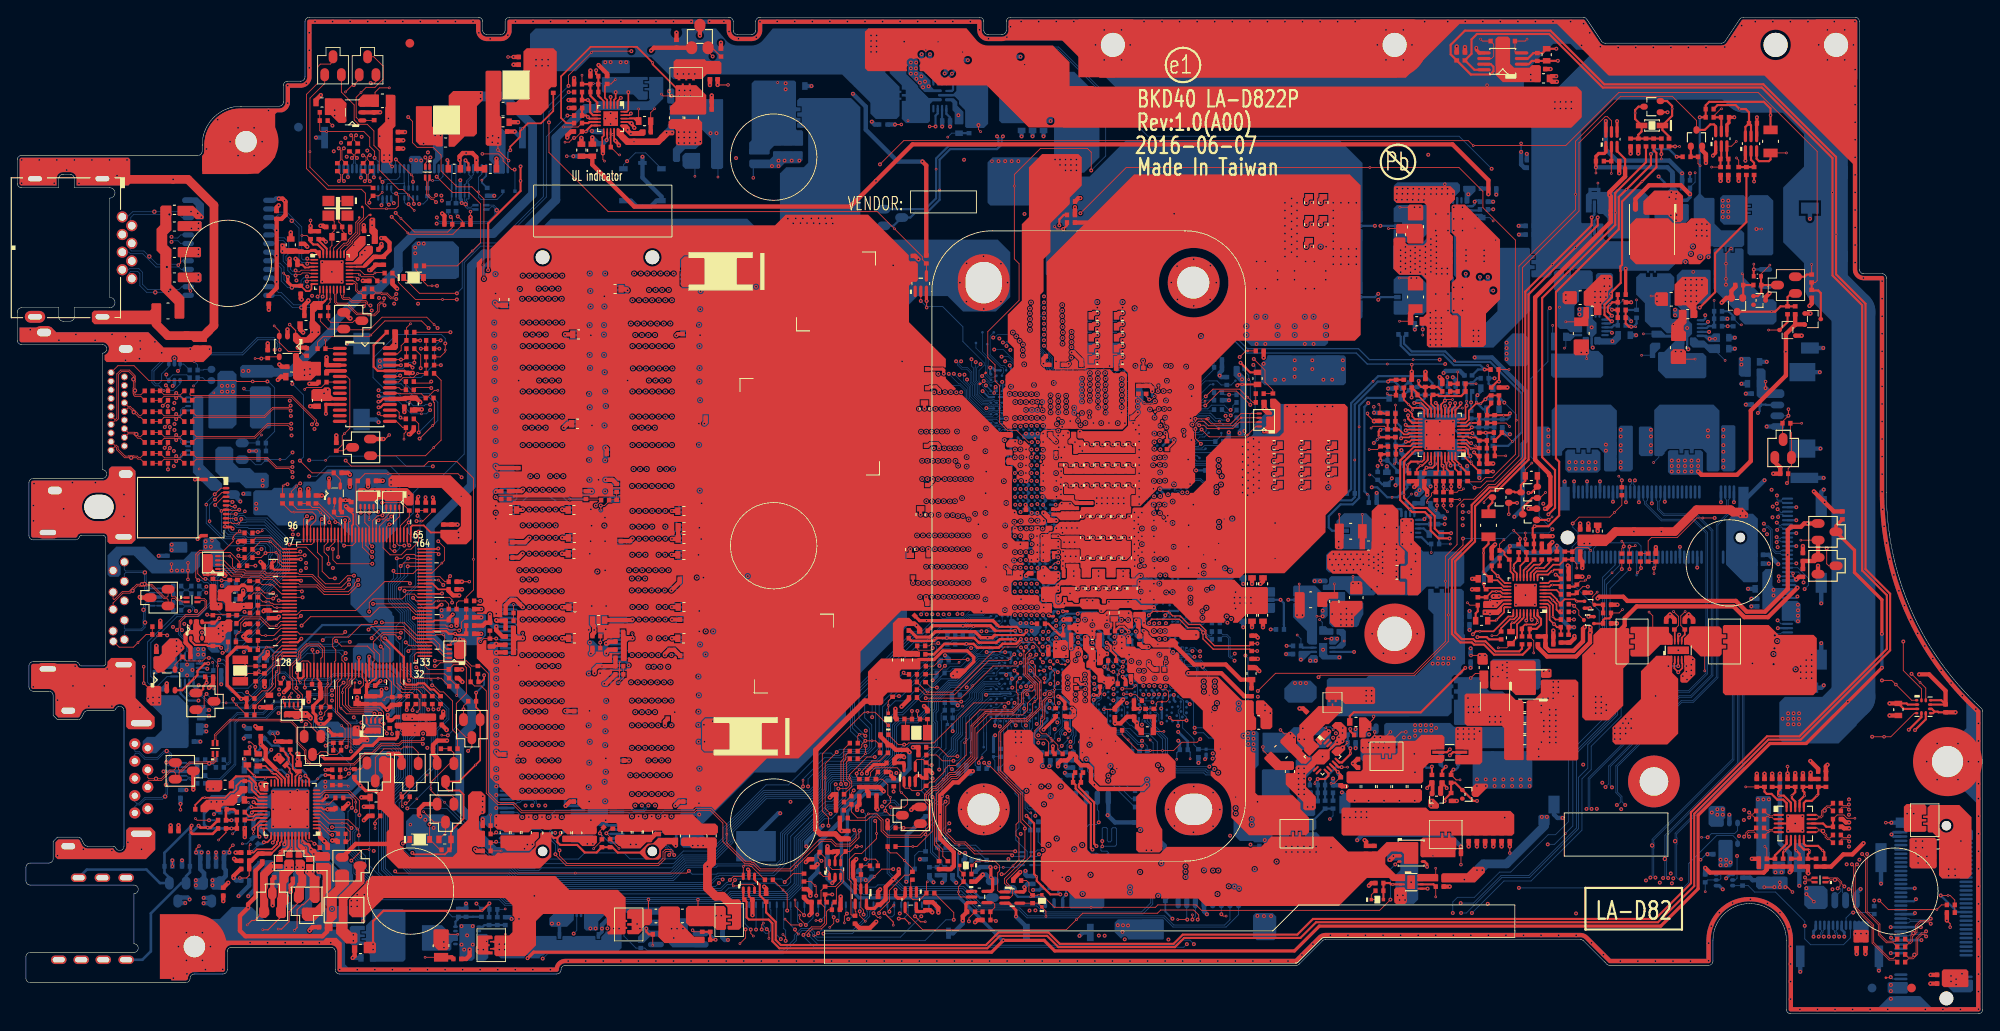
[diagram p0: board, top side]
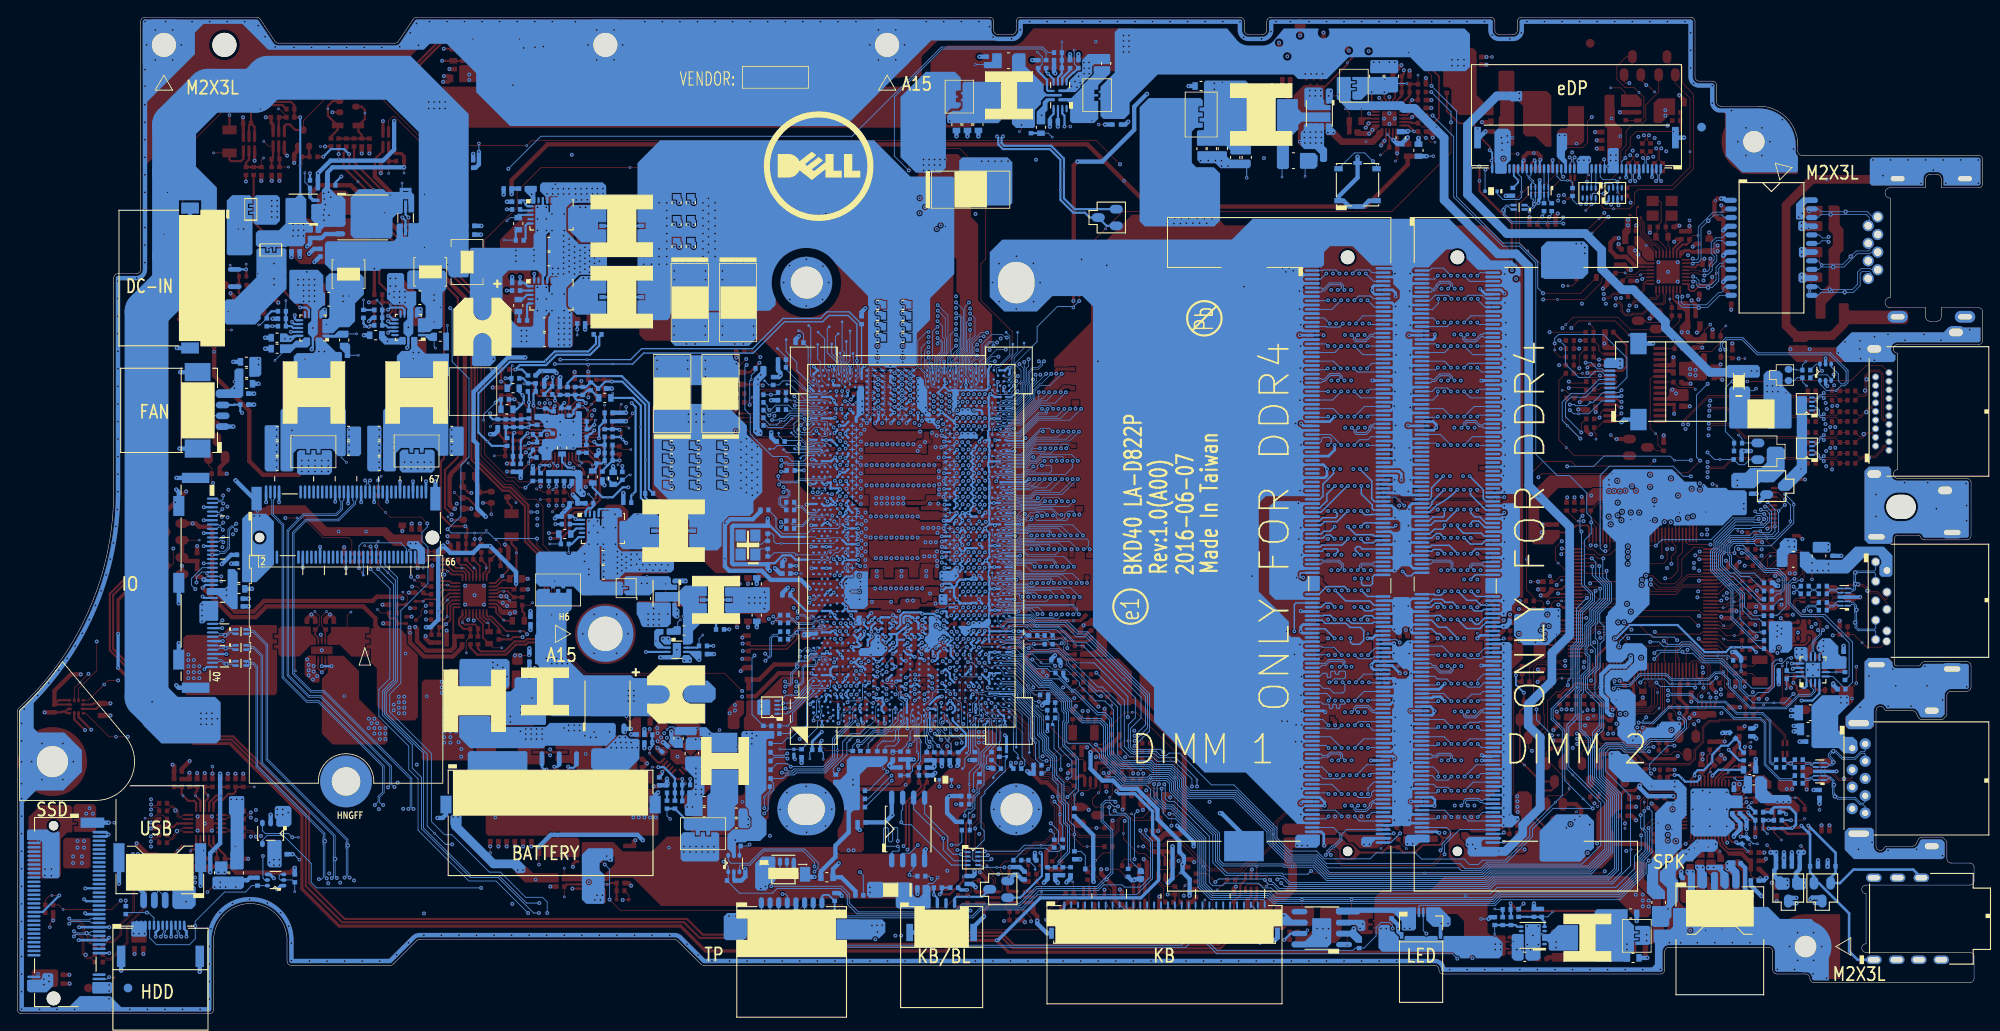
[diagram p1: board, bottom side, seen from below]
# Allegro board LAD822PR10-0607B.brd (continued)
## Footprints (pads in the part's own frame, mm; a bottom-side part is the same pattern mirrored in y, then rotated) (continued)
SY8286BRAC_QFN20_3X3-S
  oval 0.889x0.254 smd: 1(0,0) 2(0,-0.45) 3(0,-0.9) 4(0,-1.35) 5(0,-1.8) 11(3.1,-1.8) 12(3.1,-1.35) 13(3.1,-0.9) 14(3.1,-0.45) 15(3.1,0)
  oval 0.254x0.889 smd: 6(0.65,-2.45) 7(1.1,-2.45) 8(1.55,-2.45) 9(2,-2.45) 10(2.45,-2.45) 16(2.45,0.65) 17(2,0.65) 18(1.55,0.65) 19(1.1,0.65) 20(0.65,0.65)
  rect 0.991x0.991 smd: 21(1.55,-0.9)
SY8286CRAC_QFN20_3X3-S
  oval 0.889x0.254 smd: 1(0,0) 2(0,-0.45) 3(0,-0.9) 4(0,-1.35) 5(0,-1.8) 11(3.1,-1.8) 12(3.1,-1.35) 13(3.1,-0.9) 14(3.1,-0.45) 15(3.1,0)
  oval 0.254x0.889 smd: 6(0.65,-2.45) 7(1.1,-2.45) 8(1.55,-2.45) 9(2,-2.45) 10(2.45,-2.45) 16(2.45,0.65) 17(2,0.65) 18(1.55,0.65) 19(1.1,0.65) 20(0.65,0.65)
  rect 0.991x0.991 smd: 21(1.55,-0.9)
SY8286RAC_QFN20_3X3-S
  oval 0.889x0.254 smd: 1(0,0) 2(0,-0.45) 3(0,-0.9) 4(0,-1.35) 5(0,-1.8) 11(3.1,-1.8) 12(3.1,-1.35) 13(3.1,-0.9) 14(3.1,-0.45) 15(3.1,0)
  oval 0.254x0.889 smd: 6(0.65,-2.45) 7(1.1,-2.45) 8(1.55,-2.45) 9(2,-2.45) 10(2.45,-2.45) 16(2.45,0.65) 17(2,0.65) 18(1.55,0.65) 19(1.1,0.65) 20(0.65,0.65)
  rect 0.991x0.991 smd: 21(1.55,-0.9)
TAITW_PUBAUN-09FLBS1NN4H0_9P-T
  round 1.295 hole 0.711: 1(0,0) 2(-2.5,0) 3(-4.5,0) 4(-7,0) 5(-7.5,-1.5) 6(-5.5,-1.5) 7(-3.5,-1.5) 8(-1.5,-1.5) 9(0.5,-1.5)
  oval 1.295x2.997 hole 0.711x2.388: 10(2.9,-0.75) 11(-9.9,-0.75)
  oval 1.295x2.21 hole 0.711x1.6: 12(-11.35,-9.2) 13(4.35,-9.2)
TAIWI_USB034-107CRL-TWD_10P-T
  round 1.041 hole 0.787: 1(0,0) 2(-2.5,0) 3(-4.5,0) 4(-7,0) 5(-8,1.3) 6(-5.75,1.3) 7(-3.5,1.3) 8(-1.25,1.3) 9(1,1.3)
  round 0.965 hole 0.762: 10(-8.2,0.03)
  oval 1.372x2.667 hole 0.61x1.905: 11(-10.9,1.21) 12(-11.4,-7.55) 13(3.9,1.21) 14(4.4,-7.55)
TPC12
  round 0.305 smd: 1(0,0)
TPS2543RTER_QFN16_3X3-S
  oval 0.254x1.016 smd: 1(0,0) 2(0.5,0) 3(1,0) 4(1.5,0) 9(1.5,2.975) 10(1,2.975) 11(0.5,2.975) 12(0,2.975)
  oval 1.016x0.254 smd: 5(2.238,0.738) 6(2.238,1.238) 7(2.238,1.738) 8(2.238,2.238) 13(-0.738,2.238) 14(-0.738,1.738) 15(-0.738,1.238) 16(-0.738,0.738)
  rect 1.702x1.702 smd: 17(0.75,1.488)
TPS22961DNYR_WSON8
  oval 0.305x0.508 smd: 1(0,0) 2(0.65,0) 3(1.3,0) 4(1.95,0) 5(1.95,2.7)
  oval 1.6x0.508 smd: 6(0.65,2.7)
  rect 2.388x1.6 smd: 7(0.975,1.35)
TPS22965DSGR_SON8_2X2-S
  oval 0.254x0.787 smd: 1(0,0) 2(0.5,0) 3(1,0) 4(1.5,0) 5(1.5,2.2) 6(1,2.2) 7(0.5,2.2) 8(0,2.2)
  rect 1.6x0.889 smd: 9(0.75,1.1)
TPS22966DPUR_SON14_2X3-S
  oval 0.254x0.813 smd: 1(0,0) 2(0.4,0) 6(2,0) 7(2.4,0) 8(2.4,2.05) 9(2,2.05) 13(0.4,2.05) 14(0,2.05)
  oval 0.203x0.762 smd: 3(0.8,0) 4(1.2,0) 5(1.6,0) 10(1.6,2.05) 11(1.2,2.05) 12(0.8,2.05)
  rect 2.489x0.889 smd: 15(1.2,1.025)
TVNST52302AB0_SOT523-3
  oval 0.508x0.559 smd: 1(0,0) 2(-0.5,-1.4) 3(0.5,-1.4)
W25R128FVSIQ_SO8
  oval 0.635x1.676 smd: 1(0,0) 2(1.27,0) 3(2.54,0) 4(3.81,0) 5(3.81,7.25) 6(2.54,7.25) 7(1.27,7.25) 8(0,7.25)
Y_X1A000141000200_2P
  rect 0.991x1.803 smd: 1(0,0) 2(2.5,0)
Y_X3G024000DC1H_4P
  rect 1.397x1.194 smd: 1(0,0) 2(2.2,0) 3(2.2,1.7) 4(0,1.7)
Y_X3G025000DC1H_4P
  rect 1.397x1.194 smd: 1(0,0) 2(2.2,0) 3(2.2,1.7) 4(0,1.7)
YB8251ST23_TSOT-23-3
  oval 0.787x0.991 smd: 1(0,0) 2(-0.95,-2.6) 3(0.95,-2.6)

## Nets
0.6V_DDR_VTT_ON: PR202.1 RC123.2 UC14.4
1.2V_VTT_PWRGD: CC1822.1 PR209.2 PU200.10 RC392.1
2.5V_VIN: PC802.1 PJP801.2 PU800.3
3V_FB: PC113.1 PR109.2 PR110.1 PU100.13
3V_SN: PC112.1 PR106.2
3V_VIN: PC100.1 PC103.1 PC104.1 PC105.1 PJP105.2 PL102.2 PU100.2 PU100.3 PU100.4 PU100.5
5V_FB: PC127.1 PR115.2 PR118.1 PU102.13
5V_HDD: C6215.1 C6216.1 C6217.1 HDD1.1 HDD1.2 HDD1.3 R5601.1 RS1.1
5V_SN: PC125.1 PR112.2
5V_VIN: PC115.1 PC116.1 PC117.1 PC118.1 PJP106.2 PL103.2 PU102.2 PU102.3 PU102.4 PU102.5
+0.6V_DDR_VTT: CD12.1 CD13.1 CD14.1 CD15.1 CD32.1 CD88.1 CD89.1 CD90.1 JDIMM1.258 JDIMM2.258 PJP203.1
+0.6VSP: PC205.1 PC211.1 PJP203.2 PU200.2 PU200.20
+1.0V_APLL: CC225.1 CC1801.1 RC172.1 UC1.V15
+1.0V_CLK2: CC220.1 RC170.1 UC1.K19
+1.0V_CLK4: CC226.1 RC173.1 UC1.N20
+1.0V_CLK5: CC221.1 RC52.2 RC171.1 UC1.L19
+1.0V_MPHYPLL: CC58.1 CC210.1 CC211.1 CC217.1 CC218.1 JP17.2 UC1.AF20 UC1.AF21 UC1.K15 UC1.L15 UC1.N15 UC1.N16 UC1.N17 UC1.N18 UC1.P15 UC1.P16 UC1.T19 UC1.T20
+1.0V_PRIM: CC59.1 CC203.1 CC205.1 CC206.1 CC216.1 CC273.1 CE77.1 CZ87.1 JP17.1 PJP302.2 RC170.2 RC171.2 RC172.2 RC173.2 RC352.1 UC1.A10 UC1.A14 UC1.AB17 UC1.AB19 UC1.AB20 UC1.AF18 UC1.AF19 UC1.AK20 UC1.K17 UC1.L1 UC1.L21 UC1.P18 UC1.T1 UC1.V20 UC1.V21 UC1.Y18 UE1.95 UZ19.1 UZ19.2 UZ19.7 UZ21.1 UZ21.2
+1.0V_VCCST: CC195.1 CC202.1 PC602.1 PR601.1 PR604.1 PR605.1 RC79.1 RC80.1 RC120.2 RC152.1 RC157.1 RC1118.1 RZ1704.1 UC1.A18 UC1.K20 UC1.K21
+1.0V_VCCST_C: RZ1704.2 UZ21.7 UZ21.8
+1.0V_VCCSTG: CC199.1 RC83.1 RPC1.1 RPC1.2 RPC1.3 RZ1703.2 UC1.A22 UC1.G20
+1.0V_VCCSTG_C: JP15.1 RZ1703.1 UZ19.6
+1.0V_XDP: RC115.2 RC352.2 RC353.1
+1.0VS_VCCIO: CC181.1 CC182.1 CC185.1 CC186.1 CC248.1 CC249.1 CC250.1 CC251.1 CC252.1 CC253.1 JP15.2 RC2.1 UC1.AK28 UC1.AK30 UC1.AL30 UC1.AL42 UC1.AM28 UC1.AM30 UC1.AM42
+1.0VS_VCCOPC: CC1824.1 CC1825.1 CC1826.1 CC1827.1 CC1828.1 CC1829.1 CC1830.1 CC1831.1 CC1832.1 PJP1202.2 UC1.AB62 UC1.AE62 UC1.AG62 UC1.P62 UC1.V62
+1.0VS_VCCOPCP: PC1206.1 PC1207.1 PC1208.1 PJP1202.1 PL1201.2 PU1200.12
+1.2V_DDR: CC57.1 CC174.1 CC175.1 CC176.1 CC177.1 CC178.1 CC179.1 CC194.1 CC255.1 CC256.1 CC257.1 CC258.1 CC293.1 CC294.1 CC295.1 CC296.1 CC297.1 CD1.1 CD2.1 CD5.1 CD6.1 CD7.1 CD8.1 CD11.1 CD19.1 CD20.1 CD21.1 CD22.1 CD23.1 CD24.1 CD25.1 CD26.1 CD33.1 CD70.1 CD71.1 CD72.1 CD73.1 CD74.1 CD75.1 CD76.1 CD77.1 CD78.1 CD79.1 CD80.1 CD81.1 CD82.1 CD83.1 CD84.1 CD85.1 CD86.1 CD87.1 JDIMM1.12 JDIMM1.33 JDIMM1.54 JDIMM1.75 JDIMM1.96 JDIMM1.111 JDIMM1.112 JDIMM1.117 JDIMM1.118 JDIMM1.123 JDIMM1.124 JDIMM1.129 JDIMM1.130 JDIMM1.135 JDIMM1.136 JDIMM1.141 JDIMM1.142 JDIMM1.147 JDIMM1.148 JDIMM1.153 JDIMM1.154 JDIMM1.159 JDIMM1.160 JDIMM1.163 JDIMM1.178 JDIMM1.199 JDIMM1.220 JDIMM1.241 JDIMM2.12 JDIMM2.33 JDIMM2.54 JDIMM2.75 JDIMM2.111 JDIMM2.112 JDIMM2.117 JDIMM2.118 JDIMM2.123 JDIMM2.124 JDIMM2.129 JDIMM2.130 JDIMM2.135 JDIMM2.136 JDIMM2.141 JDIMM2.142 JDIMM2.147 JDIMM2.148 JDIMM2.153 JDIMM2.154 JDIMM2.159 JDIMM2.160 JDIMM2.163 JDIMM2.178 JDIMM2.199 JDIMM2.220 JDIMM2.241 PJP200.2 RD35.1 RH206.1 RH207.1 UC1.AL23 UC1.AM40 UC1.AU23 UC1.AU28 UC1.AU35 UC1.AU42 UC1.BB23 UC1.BB32 UC1.BB41 UC1.BB47 UC1.BB51 UC14.5
+1.2VP: PC213.1 PC214.2 PC215.1 PC216.1 PC217.1 PC218.1 PC219.1 PC220.1 PJP200.1 PL200.1 PR207.2 PU200.5 PU200.19
+1.8V_AVDD: C2715.1 CA61.1 R6511.1 UA1.40
+1.8V_PRIM: CC212.1 CC272.1 PJP502.2 Q6205.1 RC361.1 RC1134.1 UC1.AA1 UC1.AF16 UC1.H63
+1.8VALWP: PC503.1 PC505.1 PC506.1 PC507.1 PJP502.1 PL501.2 PR503.2
+1VALWP: PC309.1 PC310.1 PC311.1 PC312.1 PC313.1 PJP302.1 PL301.2 PR308.2
+2.5V_MEM: CD3.1 CD4.1 CD9.1 CD10.1 CD27.1 CD28.1 CD30.1 CD31.1 JDIMM1.257 JDIMM1.259 JDIMM2.257 JDIMM2.259 PJP802.2
+2.5VP: PC803.1 PC804.1 PJP802.1 PR801.1 PU800.6
+3.3V_ALW_DSW: CC279.1 CC280.1 RC70.1 RC72.2 RC214.1 RC243.2 RC1102.1 UC1.AD17 UC1.AD18 UC1.AJ17
+3.3V_CAM: C5207.1 EC5210.1 JEDP.29 JEDP.33 R5229.2
+3.3V_LAN: C3015.1 C3017.1 CL1.1 CL3.1 CL5.1 CL8.1 CL11.1 RL7.1 UL1.11 UL1.23 UL1.32 UL3.1
+3.3V_RUN_UZ2: CZ50.1 JP13.1 UZ2.8 UZ2.9
+3.3V_WLAN: C5803.1 C5804.1 C5806.1 C6221.1 R5809.1 R5810.2 WLAN1.2 WLAN1.4 WLAN1.64 WLAN1.66
+3V_SPI: CC9.1 CZ92.1 CZ93.1 CZ94.1 QZ11.3 RC9.1 RC30.1 RC53.1 RC1124.2 RZ1707.1 UC1.AJ16 UC2.8 UZ13.19 UZ13.24
+3VALW: C3013.1 C6204.1 CC271.1 CC1820.1 CC1821.1 CE1.1 CZ95.1 CZ96.1 JIO1.24 PC1205.1 PJP102.2 PJP501.1 PJP801.1 PR3.2 PR16.2 PR28.1 PR209.1 PR303.1 PR304.2 PR756.2 PR791.1 PU1200.10 Q6203.3 QC6.2 QC6.5 R2608.1 R3022.1 R5810.1 RC68.2 RC73.2 RC214.2 RC1124.1 RE25.1 RE71.1 RE72.1 RE73.1 RE74.1 RE75.1 RE343.2 RE385.2 RE388.2 RE389.2 RE396.1 RE404.1 RE408.2 RE409.2 RE446.2 RPE2.5 RPE2.6 RPE2.7 RPE2.8 RPE3.5 RPE3.6 RPE3.7 RPE3.8 RPE4.1 RPE4.2 RPE4.3 RPE4.4 RPE5.1 RPE5.2 RPE5.3 RPE5.4 RPE6.1 RPE6.2 RPE6.3 RPE6.4 RPE7.1 RPE7.2 RPE7.3 RPE7.4 RZ117.2 RZ1705.1 UC12.5 UC13.5 UC15.5 UE7.2 UL3.5 UZ2.6 UZ2.7 UZ6.5
+3VALW_EC: CE62.1 CE63.2 CE64.2 CE65.1 CE66.1 CE67.1 CE68.1 CE69.1 CE71.1 CE79.1 CE81.1 CE89.1 R2446.1 RE343.1 RE345.1 RE354.1 RE424.2 RE425.2 RE440.2 UE1.5 UE1.19 UE1.22 UE1.43 UE1.54 UE1.65 UE1.82 UE1.103 UE1.115
+3VALW_PCH: CC207.1 CC223.1 CC224.1 CC265.1 RC12.2 RC14.2 RC15.2 RC17.2 RC19.2 RC20.2 RC23.2 RC25.2 RC74.1 RC183.1 RC186.1 RC187.1 RC239.1 RC288.2 RC365.2 RC384.2 RC387.2 RC1127.2 RC1138.2 RPC3.5 RPC3.6 RPC3.7 RPC3.8 RZ1705.2 UC1.AD15 UC1.AG15 UC1.AJ21 UC1.AK15 UC1.AK17 UC1.T16 UC1.V19 UC1.Y15 UC1.Y16
+3VALWP: PC106.1 PC107.1 PC108.1 PC109.1 PC110.1 PJP102.1 PL100.2 PR107.1 PR108.2 PR109.1 PR113.1 PU100.14
+3VLP: D2501.2 PC111.1 PU100.16 PU100.17 R2609.1 RE356.2
+3VS: C2601.1 C2602.1 C5204.1 C5801.1 C5802.1 C5805.1 CA57.1 CA58.1 CD16.1 CD17.1 CD34.1 CD35.1 CE85.1 CN19.1 CN20.1 CS27.1 CS42.1 CZ97.1 CZ98.1 JDB1.9 JDB1.10 JDIMM1.255 JDIMM2.255 JIO1.22 JIO1.23 JP1.2 JP13.2 PR612.1 PR1206.1 Q2601.2 Q2601.5 Q6205.2 Q6206.2 Q6501.2 Q6501.5 Q6502.2 QC2.2 QC2.5 QL1.2 QX4.2 QX4.5 QX5.1 QX6.2 R2603.1 R2604.1 R5229.1 R5809.2 R6110.1 R6202.1 R6507.1 R6534.1 RA13.2 RA14.1 RC13.1 RC21.1 RC27.2 RC47.1 RC50.1 RC62.2 RC63.2 RC123.1 RC175.2 RC178.2 RC237.2 RC248.2 RC272.1 RC277.1 RC291.1 RC292.1 RC293.1 RC370.1 RC372.1 RC374.1 RC376.1 RC382.2 RC388.2 RC1104.1 RC1106.1 RC1109.2 RC1122.2 RC1123.1 RC1129.1 RC1130.1 RD1.1 RD2.1 RD3.1 RD4.1 RD5.1 RD6.1 RE32.1 RE432.1 RE439.2 RE441.2 RL2.1 RN19.1 RN20.1 RS19.1 RS20.1 RS25.1 RS26.1 RS27.1 RS28.1 RS29.1 RS30.1 RS33.2 RS34.2 RS38.2 RS39.1 RX13.1 RZ20.1 RZ21.1 THM26.1 U5201.4 U5201.5 U5603.2 U5603.3 U5603.9 U5603.10 UA1.1 UA1.9 UC7.5 UE6.5 UZ13.10
+3VS_SSD: C5529.1 C5530.1 C5531.1 C5532.1 C5533.1 JP1.1 JSSD1.2 JSSD1.4 JSSD1.62 JSSD1.64 JSSD1.66 RB1.1
+5V_KB_BL: C6202.1 F6201.1 JKBBL.1
+5V_PVDD: CA53.1 CA54.1 CA55.1 CA56.1 RA1110.1 UA1.41 UA1.46
+5V_RUN_UZ2: CZ44.1 JP21.2 UZ2.13 UZ2.14
+5VA: CA51.1 CA71.1 RA1111.1 UA1.26
+5VALW: C3504.1 C3510.1 CUS20.1 JLED.1 JLED.2 JWDB1.4 PC661.1 PC677.1 PC685.1 PC801.1 PD5.3 PD6.3 PJP103.2 PR8.1 PR206.1 PR210.2 PR602.2 PR615.1 PR634.1 PR655.1 PR658.1 PU606.6 PU800.4 U3504.5 U3505.5 UUS5.1 UUS5.4 UUS5.7 UUS5.8 UZ2.1 UZ2.2 UZ2.4 UZ19.3 UZ21.4
+5VALWP: PC120.1 PC121.1 PC122.1 PC123.1 PC124.1 PJP103.1 PL101.2 PR115.1 PR117.2 PU102.14
+5VS: C6214.1 D5204.2 F5203.1 F6201.2 JIO1.21 JP21.1 Q6201.3 R2606.2 R5232.2 R5601.2 RA1110.2 RA1111.2
+5VS_HDMI: DX4.1 F6202.1 JHDMI.18
+17.4V_BATT+: PC7.1 PC761.1 PC766.1 PC775.1 PC776.1 PC777.1 PC778.1 PJP3.2 PQ710.3 PR745.2 PR765.4 PR780.2
+17.4V_BATT++: PBATT1.8 PBATT1.9 PBATT1.10 PC8.1 PJP3.1
+19V_ADPIN: PC1.1 PC2.1 PJPDC1.5 PJPDC1.6 PL1.1
+19V_VIN: PC3.1 PC4.1 PC742.2 PD704.2 PL1.2 PQ740.5 PQ741.5 PR5.1 PR7.2 PR31.2 PR729.1
+19VB: EC9701.1 EC9702.1 EC9703.1 EC9706.1 EC9707.1 EC9708.1 EC9709.1 EC9710.1 EC9711.1 EC9712.1 EC9716.1 EC9749.1 EC9750.1 EC9751.1 EC9752.1 EC9753.1 F5201.1 PC606.1 PJP105.1 PJP106.1 PJP206.2 PJP301.1 PJP601.2 PJP602.2 PJP701.1 PJP1201.1 PL102.1 PL103.1 PL606.2 PL704.1 PQ717.5 PR102.2 PR703.4 R5214.1 R6528.2
+19VB_1.2V: PC201.1 PC206.1 PC208.1 PC212.1 PJP206.1 PQ201.2 PQ201.3 PQ201.4 PQ201.10 PR208.1
+19VB_+1VALW: PC301.1 PC302.1 PC303.1 PJP301.2 PU300.2 PU300.3 PU300.4 PU300.5
+VCC_CORE: PC1001.1 PC1002.1 PC1003.1 PC1004.1 PC1005.1 PC1006.1 PC1007.1 PC1008.1 PC1009.1 PC1010.1 PC1011.1 PC1012.1 PC1013.1 PC1030.1 PC1031.1 PC1032.1 PC1033.1 PC1034.1 PC1035.1 PC1036.1 PC1037.1 PC1038.1 PC1039.1 PC1050.1 PC1051.1 PC1052.1 PC1053.1 PC1054.1 PC1061.1 PC1062.1 PC1064.1 PC1065.1 PC1066.1 PC1067.1 PC1068.1 PC1069.1 PC1070.1 PC1071.1 PC1072.1 PC1073.1 PC1074.1 PC1075.1 PC1076.1 PC1077.1 PC1078.1 PC1079.1 PC1080.1 PC1081.1 PC1082.1 PC1083.1 PC1084.1 PC1085.1 PC1086.1 PC1087.1 PC1088.1 PC1089.1 PC1090.1 PC1091.1 PC1092.1 PC1093.1 PC1094.1 PC1095.1 PC1096.1 PC1097.1 PC1098.1 PC1099.1 PC1125.1 PC1126.1 PC1127.1 PC1164.1 PC1170.1 PC1171.1 PC1172.1 PC1173.1 PC1174.1 PL603.1 RC140.1 UC1.A30 UC1.A34 UC1.A39 UC1.A44 UC1.AK33 UC1.AK35 UC1.AK37 UC1.AK38 UC1.AK40 UC1.AL33 UC1.AL37 UC1.AL40 UC1.AM32 UC1.AM33 UC1.AM35 UC1.AM37 UC1.AM38 UC1.G30 UC1.G32 UC1.G33 UC1.G35 UC1.G37 UC1.G38 UC1.G40 UC1.G42 UC1.J30 UC1.J33 UC1.J37 UC1.J40 UC1.K33 UC1.K35 UC1.K37 UC1.K38 UC1.K40 UC1.K42 UC1.K43
+VCC_CORE_G0: T122.1(TP-1) UC1.K32
+VCC_CORE_G1: T123.1(TP-1) UC1.AK32
+VCC_FAN1: C2603.1 C6213.1 JFAN1.4 R2606.1
+VCC_GT: PC1014.1 PC1015.1 PC1016.1 PC1017.1 PC1018.1 PC1019.1 PC1020.1 PC1021.1 PC1022.1 PC1023.1 PC1024.1 PC1025.1 PC1026.1 PC1027.1 PC1028.1 PC1029.1 PC1040.1 PC1041.1 PC1042.1 PC1043.1 PC1044.1 PC1045.1 PC1046.1 PC1047.1 PC1048.1 PC1049.1 PC1055.1 PC1056.1 PC1063.1 PC1101.1 PC1128.1 PC1129.1 PC1130.1 PC1131.1 PC1132.1 PC1133.1 PC1134.1 PC1135.1 PC1136.1 PC1137.1 PC1138.1 PC1154.1 PC1155.1 PC1156.1 PC1158.1 PC1159.1 PC1161.1 PC1162.1 PC1163.1 PC1175.1 PC1176.1 PC1177.1 PC1178.1 PC1179.1 PC1180.1 PC1181.1 PC1182.1 PC1183.1 PC1184.1 PC1221.1 PC1222.1 PC1223.1 PC1224.1 PL604.1 PL605.1 RC161.1 RC340.1 UC1.A48 UC1.A53 UC1.A58 UC1.A62 UC1.A66 UC1.AA63 UC1.AA64 UC1.AA66 UC1.AA67 UC1.AA69 UC1.AA70 UC1.AA71 UC1.AC64 UC1.AC65 UC1.AC66 UC1.AC67 UC1.AC68 UC1.AC69 UC1.AC70 UC1.AC71 UC1.AK42 UC1.AK43 UC1.AK45 UC1.AK46 UC1.AK48 UC1.AK50 UC1.AK52 UC1.AK53 UC1.AK55 UC1.AK56 UC1.AK58 UC1.AK60 UC1.AK70 UC1.AL43 UC1.AL46 UC1.AL50 UC1.AL53 UC1.AL56 UC1.AL60 UC1.AM48 UC1.AM50 UC1.AM52 UC1.AM53 UC1.AM56 UC1.AM58 UC1.AU58 UC1.AU63 UC1.BB57 UC1.BB66 UC1.J43 UC1.J45 UC1.J46 UC1.J48 UC1.J50 UC1.J52 UC1.J53 UC1.J55 UC1.J56 UC1.J58 UC1.J60 UC1.K48 UC1.K50 UC1.K52 UC1.K53 UC1.K55 UC1.K56 UC1.K58 UC1.K60 UC1.L62 UC1.L63 UC1.L64 UC1.L65 UC1.L66 UC1.L67 UC1.L68 UC1.L69 UC1.L70 UC1.L71 UC1.M62 UC1.N63 UC1.N64 UC1.N66 UC1.N67 UC1.N69 UC1.N70 UC1.N71 UC1.R63 UC1.R64 UC1.R65 UC1.R66 UC1.R67 UC1.R68 UC1.R69 UC1.R70 UC1.R71 UC1.T62 UC1.U65 UC1.U68 UC1.U71 UC1.W63 UC1.W64 UC1.W65 UC1.W66 UC1.W67 UC1.W68 UC1.W69 UC1.W70 UC1.W71 UC1.Y62
+VCC_SA: PC1057.1 PC1058.1 PC1059.1 PC1060.1 PC1139.1 PC1140.1 PC1141.1 PC1142.1 PC1143.1 PC1144.1 PC1145.1 PC1146.1 PC1147.1 PC1148.1 PC1149.1 PC1150.1 PC1151.1 PC1152.1 PC1153.1 PL601.1 RC168.1 UC1.AK23 UC1.AK25 UC1.G23 UC1.G25 UC1.G27 UC1.G28 UC1.J22 UC1.J23 UC1.J27 UC1.K23 UC1.K25 UC1.K27 UC1.K28 UC1.K30
GND: C229.1 C2503.2 C2601.2 C2602.2 C2603.2 C2604.1 C2608.2 C2609.2 C3013.2 C3015.2 C3017.2 C3504.2 C3507.2 C3508.2 C3510.2 C3512.2 C3513.2 C5201.2 C5202.2 C5204.2 C5205.1 C5206.1 C5207.2 C5224.2 C5225.2 C5226.2 C5529.2 C5530.2 C5531.2 C5532.2 C5533.2 C5801.2 C5802.2 C5803.2 C5804.2 C5805.2 C5806.2 C6201.2 C6202.2 C6213.2 C6214.2 C6215.2 C6216.2 C6217.2 C6218.1 C6219.2 C6220.1 C6221.2 C6223.2 C6225.2 C6226.2 CA25.1 CA29.2 CA30.2 CA31.2 CA32.2 CA53.2 CA54.2 CA55.2 CA56.2 CA57.2 CA58.2 CA59.2 CA60.2 CA64.1 CA69.2 CC9.2 CC21.2 CC22.2 CC23.2 CC24.2 CC25.2 CC26.2 CC27.2 CC57.2 CC58.2 CC59.2 CC93.1 CC174.2 CC175.2 CC176.2 CC177.2 CC178.2 CC179.2 CC181.2 CC182.2 CC185.2 CC186.2 CC194.2 CC195.2 CC199.2 CC202.2 CC203.2 CC204.2 CC205.2 CC206.2 CC207.2 CC210.2 CC211.2 CC212.2 CC213.2 CC214.2 CC215.2 CC216.2 CC217.2 CC218.2 CC220.2 CC221.2 CC223.2 CC224.2 CC225.2 CC226.2 CC248.2 CC249.2 CC250.2 CC251.2 CC252.2 CC253.2 CC255.2 CC256.2 CC257.2 CC258.2 CC265.2 CC266.2 CC270.2 CC271.2 CC272.2 CC273.2 CC279.2 CC280.2 CC293.2 CC294.2 CC295.2 CC296.2 CC297.2 CC1801.2 CC1802.1 CC1803.1 CC1805.1 CC1806.2 CC1807.2 CC1808.2 CC1809.2 CC1810.2 CC1820.2 CC1821.2 CC1822.2 CC1823.1 CC1824.2 CC1825.2 CC1826.2 CC1827.2 CC1828.2 CC1829.2 CC1830.2 CC1831.2 CC1832.2 CD1.2 CD2.2 CD3.2 CD4.2 CD5.2 CD6.2 CD7.2 CD8.2 CD9.2 CD10.2 CD11.2 CD12.2 CD13.2 CD14.2 CD15.2 CD16.2 CD17.2 CD18.2 CD19.2 CD20.2 CD21.2 CD22.2 CD23.2 CD24.2 CD25.2 CD26.2 CD27.2 CD28.2 CD29.2 CD30.2 CD31.2 CD32.2 CD33.2 CD34.2 CD35.2 CD69.2 CD70.2 CD71.2 CD72.2 CD73.2 CD74.2 CD75.2 CD76.2 CD77.2 CD78.2 CD79.2 CD80.2 CD81.2 CD82.2 CD83.2 CD84.2 CD85.2 CD86.2 CD87.2 CD88.2 CD89.2 CD90.2 CD91.2 CD92.2 CE1.2 CE2.2 CE8.2 CE62.2 CE63.1 CE64.1 CE65.2 CE66.2 CE67.2 CE68.2 CE69.2 CE71.2 CE72.2 CE73.2 CE74.2 CE75.2 CE76.2 CE77.2 CE79.2 CE82.2 CE84.1 CE85.2 CE86.2 CE89.2 CE91.2 CL1.2 CL2.2 CL3.2 CL4.2 CL5.2 CL6.2 CL7.2 CL8.2 CL9.2 CL11.2 CL12.2 CL16.2 CL17.2 CL44.1 CL45.1 CL46.1 CLRP1.1 CN19.2 CN20.2 CS27.2 CS42.2 CUS20.2 CZ23.2 CZ44.2 CZ45.2 CZ50.2 CZ70.2 CZ87.2 CZ92.2 CZ93.2 CZ94.2 CZ95.2 CZ96.2 CZ97.2 CZ98.2 CZ1702.2 CZ1705.2 DA10.1 DA12.1 DA13.1 DA14.1 EC5205.2 EC5206.2 EC5210.2 EC9701.2 EC9702.2 EC9703.2 EC9706.2 EC9707.2 EC9708.2 EC9709.2 EC9710.2 EC9711.2 EC9712.2 EC9716.2 EC9749.2 EC9750.2 EC9751.2 EC9752.2 EC9753.2 EU3403.1 EU3404.1 EU3405.3 H1.1(TP-1) H3.1(TP-1) H4.1(TP-1) H5.1(TP-1) H6.1(TP-1) H7.1(TP-1) H8.1(TP-1) HCPU1.1(TP-1) HCPU2.1(TP-1) HCPU3.1(TP-1) HCPU4.1(TP-1) HDD1.6 HDD1.9 HDD1.12 HDD1.13 HDD1.14 HNGFF.1(TP-1) JDB1.2 JDB1.11 JDB1.12 JDEG1.10 JDEG1.11 JDEG1.12 JDIMM1.1 JDIMM1.2 JDIMM1.5 JDIMM1.6 JDIMM1.9 JDIMM1.10 JDIMM1.14 JDIMM1.15 JDIMM1.18 JDIMM1.19 JDIMM1.22 JDIMM1.23 JDIMM1.26 JDIMM1.27 JDIMM1.30 JDIMM1.31 JDIMM1.35 JDIMM1.36 JDIMM1.39 JDIMM1.40 JDIMM1.43 JDIMM1.44 JDIMM1.47 JDIMM1.48 JDIMM1.51 JDIMM1.52 JDIMM1.56 JDIMM1.57 JDIMM1.60 JDIMM1.61 JDIMM1.64 JDIMM1.65 JDIMM1.68 JDIMM1.69 JDIMM1.72 JDIMM1.73 JDIMM1.77 JDIMM1.78 JDIMM1.81 JDIMM1.82 JDIMM1.85 JDIMM1.86 JDIMM1.89 JDIMM1.90 JDIMM1.93 JDIMM1.94 JDIMM1.98 JDIMM1.99 JDIMM1.102 JDIMM1.103 JDIMM1.106 JDIMM1.107 JDIMM1.167 JDIMM1.168 JDIMM1.171 JDIMM1.172 JDIMM1.175 JDIMM1.176 JDIMM1.180 JDIMM1.181 JDIMM1.184 JDIMM1.185 JDIMM1.188 JDIMM1.189 JDIMM1.192 JDIMM1.193 JDIMM1.196 JDIMM1.197 JDIMM1.201 JDIMM1.202 JDIMM1.205 JDIMM1.206 JDIMM1.209 JDIMM1.210 JDIMM1.213 JDIMM1.214 JDIMM1.217 JDIMM1.218 JDIMM1.222 JDIMM1.223 JDIMM1.226 JDIMM1.227 JDIMM1.230 JDIMM1.231 JDIMM1.234 JDIMM1.235 JDIMM1.238 JDIMM1.239 JDIMM1.243 JDIMM1.244 JDIMM1.247 JDIMM1.248 JDIMM1.251 JDIMM1.252 JDIMM1.261 JDIMM1.262 JDIMM2.1 JDIMM2.2 JDIMM2.5 JDIMM2.6 JDIMM2.9 JDIMM2.10 JDIMM2.14 JDIMM2.15 JDIMM2.18 JDIMM2.19 JDIMM2.22 JDIMM2.23 JDIMM2.26 JDIMM2.27 JDIMM2.30 JDIMM2.31 JDIMM2.35 JDIMM2.36 JDIMM2.39 JDIMM2.40 JDIMM2.43 JDIMM2.44 JDIMM2.47 JDIMM2.48 JDIMM2.51 JDIMM2.52 JDIMM2.56 JDIMM2.57 JDIMM2.60 JDIMM2.61 JDIMM2.64 JDIMM2.65 JDIMM2.68 JDIMM2.69 JDIMM2.72 JDIMM2.73 JDIMM2.77 JDIMM2.78 JDIMM2.81 JDIMM2.82 JDIMM2.85 JDIMM2.86 JDIMM2.89 JDIMM2.90 JDIMM2.93 JDIMM2.94 JDIMM2.98 JDIMM2.99 JDIMM2.102 JDIMM2.103 JDIMM2.106 JDIMM2.107 JDIMM2.167 JDIMM2.168 JDIMM2.171 JDIMM2.172 JDIMM2.175 JDIMM2.176 JDIMM2.180 JDIMM2.181 JDIMM2.184 JDIMM2.185 JDIMM2.188 JDIMM2.189 JDIMM2.192 JDIMM2.193 JDIMM2.196 JDIMM2.197 JDIMM2.201 JDIMM2.202 JDIMM2.205 JDIMM2.206 JDIMM2.209 JDIMM2.210 JDIMM2.213 JDIMM2.214 JDIMM2.217 JDIMM2.218 JDIMM2.222 JDIMM2.223 JDIMM2.226 JDIMM2.227 JDIMM2.230 JDIMM2.231 JDIMM2.234 JDIMM2.235 JDIMM2.238 JDIMM2.239 JDIMM2.243 JDIMM2.244 JDIMM2.247 JDIMM2.248 JDIMM2.251 JDIMM2.252 JDIMM2.261 JDIMM2.262 JEDP.3 JEDP.6 JEDP.9 JEDP.18 JEDP.19 JEDP.20 JEDP.26 JEDP.30 JEDP.41 JEDP.42 JFAN1.1 JFAN1.5 JFAN1.6 JHDMI.2 JHDMI.5 JHDMI.8 JHDMI.11 JHDMI.17 JHDMI.20 JHDMI.21 JHDMI.22 JHDMI.23 JIO1.3 JIO1.6 JIO1.9 JIO1.12 JIO1.31 JIO1.34 JIO1.37 JIO1.40 JIO1.41 JIO1.42 JIO1.43 JIO1.44 JIO1.45 JIO2.4 JIO2.5 JIO2.6 JKB.1 JKB.31 JKB.32 JKBBL.5 JKBBL.6 JLED.5 JLED.6 JLED.7 JLED.8 JSPK.5 JSPK.6 JSSD1.1 JSSD1.3 JSSD1.27 JSSD1.33 JSSD1.39 JSSD1.45 JSSD1.51 JSSD1.57 JSSD1.63 JSSD1.65 JSSD1.67 JSSD1.68 JSSD1.69 JUSB1.4 JUSB1.7 JUSB1.11 JUSB1.12 JUSB1.13 JUSB1.14 JUSB2.4 JUSB2.7 JUSB2.10 JUSB2.11 JUSB2.12 JUSB2.13 JWDB1.1 JWDB1.5 JWDB1.6 PBATT1.1 PBATT1.2 PBATT1.3 PBATT1.4 PBATT1.11 PBATT1.12 PC1.2 PC2.2 PC3.2 PC4.2 PC7.2 PC8.2 PC100.2 PC103.2 PC104.2 PC105.2 PC106.2 PC107.2 PC108.2 PC109.2 PC110.2 PC111.2 PC112.2 PC115.2 PC116.2 PC117.2 PC118.2 PC119.2 PC120.2 PC121.2 PC122.2 PC123.2 PC124.2 PC125.2 PC126.2 PC128.2 PC201.2 PC202.2 PC203.2 PC204.1 PC205.2 PC206.2 PC207.2 PC208.2 PC209.2 PC210.2 PC211.2 PC212.2 PC213.2 PC215.2 PC216.2 PC217.2 PC218.2 PC219.2 PC220.2 PC301.2 PC302.2 PC303.2 PC304.2 PC305.2 PC306.2 PC308.2 PC310.2 PC311.2 PC312.2 PC313.2 PC501.2 PC502.2 PC504.2 PC505.2 PC506.2 PC507.2 PC601.2 PC602.2 PC603.2 PC604.2 PC605.1 PC606.2 PC608.2 PC612.2 PC613.1 PC614.1 PC616.1 PC618.1 PC619.1 PC621.1 PC622.2 PC625.1 PC628.2 PC629.1 PC631.2 PC636.1 PC641.2 PC643.2 PC644.2 PC645.2 PC647.1 PC649.2 PC651.1 PC652.2 PC654.1 PC656.2 PC657.2 PC658.2 PC659.2 PC660.2 PC661.2 PC662.2 PC664.2 PC665.2 PC666.2 PC667.2 PC668.2 PC669.2 PC670.2 PC672.2 PC673.2 PC674.2 PC677.2 PC678.2 PC679.2 PC680.2 PC681.2 PC685.2 PC686.2 PC687.2 PC688.2 PC690.2 PC705.2 PC711.1 PC748.2 PC749.1 PC751.1 PC752.1 PC753.1 PC757.1 PC760.2 PC761.2 PC762.2 PC763.2 PC764.2 PC765.2 PC766.2 PC768.1 PC769.1 PC775.2 PC776.2 PC777.2 PC778.2 PC790.2 PC801.2 PC802.2 PC804.2 PC805.2 PC1001.2 PC1002.2 PC1003.2 PC1004.2 PC1005.2 PC1006.2 PC1007.2 PC1008.2 PC1009.2 PC1010.2 PC1011.2 PC1012.2 PC1013.2 PC1014.2 PC1015.2 PC1016.2 PC1017.2 PC1018.2 PC1019.2 PC1020.2 PC1021.2 PC1022.2 PC1023.2 PC1024.2 PC1025.2 PC1026.2 PC1027.2 PC1028.2 PC1029.2 PC1030.2 PC1031.2 PC1032.2 PC1033.2 PC1034.2 PC1035.2 PC1036.2 PC1037.2 PC1038.2 PC1039.2 PC1040.2 PC1041.2 PC1042.2 PC1043.2 PC1044.2 PC1045.2 PC1046.2 PC1047.2 PC1048.2 PC1049.2 PC1050.2 PC1051.2 PC1052.2 PC1053.2 PC1054.2 PC1055.2 PC1056.2 PC1057.2 PC1058.2 PC1059.2 PC1060.2 PC1061.2 PC1062.2 PC1063.2 PC1064.2 PC1065.2 PC1066.2 PC1067.2 PC1068.2 PC1069.2 PC1070.2 PC1071.2 PC1072.2 PC1073.2 PC1074.2 PC1075.2 PC1076.2 PC1077.2 PC1078.2 PC1079.2 PC1080.2 PC1081.2 PC1082.2 PC1083.2 PC1084.2 PC1085.2 PC1086.2 PC1087.2 PC1088.2 PC1089.2 PC1090.2 PC1091.2 PC1092.2 PC1093.2 PC1094.2 PC1095.2 PC1096.2 PC1097.2 PC1098.2 PC1099.2 PC1101.2 PC1125.2 PC1126.2 PC1127.2 PC1128.2 PC1129.2 PC1130.2 PC1131.2 PC1132.2 PC1133.2 PC1134.2 PC1135.2 PC1136.2 PC1137.2 PC1138.2 PC1139.2 PC1140.2 PC1141.2 PC1142.2 PC1143.2 PC1144.2 PC1145.2 PC1146.2 PC1147.2 PC1148.2 PC1149.2 PC1150.2 PC1151.2 PC1152.2 PC1153.2 PC1154.2 PC1155.2 PC1156.2 PC1158.2 PC1159.2 PC1161.2 PC1162.2 PC1163.2 PC1164.2 PC1170.2 PC1171.2 PC1172.2 PC1173.2 PC1174.2 PC1175.2 PC1176.2 PC1177.2 PC1178.2 PC1179.2 PC1180.2 PC1181.2 PC1182.2 PC1183.2 PC1184.2 PC1202.2 PC1203.2 PC1204.2 PC1205.2 PC1206.2 PC1207.2 PC1208.2 PC1209.2 PC1221.2 PC1222.2 PC1223.2 PC1224.2 PD2.1 PD3.1 PD4.1 PD5.2 PD6.2 PH601.1 PH603.1 PJPDC1.7 PJPDC1.8 PL4.2 PQ1.1 PQ1.4 PQ2.1 PQ2.4 PQ3.3 PQ5.3 PQ201.5 PQ201.6 PQ201.7 PQ601.5 PQ601.6 PQ601.7 PQ708.1 PQ708.2 PQ708.3 PQ709.4 PQ711.3 PQ720.3 PQ721.3 PR2.2 PR9.1 PR10.1 PR29.2 PR32.2 PR33.1 PR103.2 PR110.2 PR118.2 PR122.2 PR204.2 PR302.2 PR305.2 PR310.2 PR502.1 PR505.2 PR608.2 PR611.2 PR613.1 PR629.1 PR631.1 PR637.2 PR647.1 PR651.2 PR653.2 PR654.2 PR662.2 PR680.2 PR681.2 PR727.2 PR731.2 PR732.2 PR738.2 PR751.1 PR752.1 PR753.1 PR755.1 PR779.1 PR802.2 PR1202.1 PR1205.2 PR1207.2 PU100.7 PU100.8 PU100.18 PU100.21 PU102.7 PU102.8 PU102.18 PU102.21 PU200.1 PU200.3 PU200.14 PU200.21 PU300.7 PU300.8 PU300.18 PU300.21 PU500.11 PU602.41 PU603.7 PU603.11 PU604.7 PU604.11 PU605.7 PU605.11 PU606.4 PU606.9 PU703.33 PU800.8 PU800.9 PU1200.2 PU1200.11 Q1901.3 Q2405.3 Q2505.3 Q6202.3 QC5.1 QC5.4 QX6.3 R1902.2 R2504.2 R2611.2 R3023.1 R5202.1 R6207.2 R6517.2 R6530.2 R6532.2 R6533.2 RA19.2 RA29.2 RA30.2 RA31.2 RA32.2 RA81.1 RA1115.2 RA1116.2 RC3.2 RC4.2 RC5.2 RC6.2 RC7.2 RC43.2 RC44.2 RC48.2 RC65.2 RC75.1 RC88.2 RC89.2 RC90.2 RC91.2 RC96.2 RC109.1 RC110.1 RC112.1 RC113.1 RC114.2 RC141.2 RC163.2 RC166.2 RC220.2 RC341.2 RC347.2 RC348.2 RC366.2 RC371.2 RC373.2 RC375.2 RC377.2 RC390.1 RC393.2 RC1105.2 RC1107.2 RC1109.1 RC1126.2 RC1128.2 RC1131.2 RD28.2 RD29.2 RD30.2 RD38.2 RD39.2 RD40.2 RE355.2 RE357.2 RE358.2 RE367.2 RE380.1 RE397.2 RE398.2 RE450.2 RE451.2 RH209.2 RH210.2 RH211.2 RH212.2 RL4.2 RL5.1 RN5203.1 RN5203.2 RN5203.3 RPC1.4 RS18.2 RS21.2 RS22.1 RS23.2 RS24.2 RS31.2 RS35.2 RS36.2 RS37.2 RUS26.2 RUS27.2 RX13.2 RX14.2 RX34.2 RZ65.2 RZ119.2 RZ1708.1 RZ1709.2 SW1.1 SW1.2 SW1.5 SW1.6 TC3501.2 TC3502.2 THM26.5 TPAD1.5 TPAD1.9 TPAD1.10 U3402.3 U3403.3 U3504.2 U3505.2 U5201.2 U5603.5 U5603.6 U5603.7 U5603.8 UA1.49 UC1.A5 UC1.A67 UC1.A70 UC1.AA2 UC1.AA4 UC1.AA65 UC1.AA68 UC1.AB8 UC1.AB15 UC1.AB16 UC1.AB18 UC1.AB21 UC1.AD8 UC1.AD13 UC1.AD16 UC1.AD19 UC1.AD20 UC1.AD21 UC1.AD62 UC1.AE64 UC1.AE65 UC1.AE66 UC1.AE67 UC1.AE68 UC1.AE69 UC1.AF1 UC1.AF2 UC1.AF4 UC1.AF10 UC1.AF15 UC1.AF17 UC1.AF63 UC1.AG16 UC1.AG17 UC1.AG18 UC1.AG19 UC1.AG20 UC1.AG21 UC1.AG71 UC1.AH6 UC1.AH13 UC1.AH63 UC1.AH64 UC1.AH67 UC1.AJ4 UC1.AJ15 UC1.AJ18 UC1.AJ20 UC1.AK8 UC1.AK11 UC1.AK16 UC1.AK18 UC1.AK21 UC1.AK22 UC1.AK27 UC1.AK63 UC1.AK68 UC1.AK69 UC1.AL2 UC1.AL4 UC1.AL28 UC1.AL32 UC1.AL35 UC1.AL38 UC1.AL45 UC1.AL48 UC1.AL52 UC1.AL55 UC1.AL58 UC1.AL64 UC1.AL65 UC1.AL66 UC1.AM8 UC1.AM13 UC1.AM21 UC1.AM25 UC1.AM27 UC1.AM43 UC1.AM45 UC1.AM46 UC1.AM55 UC1.AM60 UC1.AM61 UC1.AM68 UC1.AM71 UC1.AN20 UC1.AN23 UC1.AN28 UC1.AN30 UC1.AN32 UC1.AN33 UC1.AN35 UC1.AN37 UC1.AN38 UC1.AN40 UC1.AN42 UC1.AN58 UC1.AN63 UC1.AP10 UC1.AP18 UC1.AP20 UC1.AP23 UC1.AP28 UC1.AP32 UC1.AP35 UC1.AP38 UC1.AP42 UC1.AP58 UC1.AP63 UC1.AP68 UC1.AP70 UC1.AR5 UC1.AR8 UC1.AR11 UC1.AR15 UC1.AR16 UC1.AR20 UC1.AR23 UC1.AR28 UC1.AR35 UC1.AR42 UC1.AR43 UC1.AR45 UC1.AR46 UC1.AR48 UC1.AR50 UC1.AR52 UC1.AR53 UC1.AR55 UC1.AR58 UC1.AR63 UC1.AT2 UC1.AT4 UC1.AT20 UC1.AT23 UC1.AT28 UC1.AT35 UC1.AT42 UC1.AT56 UC1.AT58 UC1.AT63 UC1.AT68 UC1.AT71 UC1.AU10 UC1.AU15 UC1.AU20 UC1.AU32 UC1.AU38 UC1.AV1 UC1.AV68 UC1.AV69 UC1.AV70 UC1.AV71 UC1.AW6 UC1.AW8 UC1.AW10 UC1.AW12 UC1.AW14 UC1.AW16 UC1.AW18 UC1.AW21 UC1.AW23 UC1.AW26 UC1.AW28 UC1.AW30 UC1.AW32 UC1.AW34 UC1.AW36 UC1.AW38 UC1.AW41 UC1.AW43 UC1.AW45 UC1.AW47 UC1.AW49 UC1.AW51 UC1.AW53 UC1.AW55 UC1.AW57 UC1.AW60 UC1.AW62 UC1.AW64 UC1.AW66 UC1.AY3 UC1.AY66 UC1.AY71 UC1.B10 UC1.B14 UC1.B18 UC1.B22 UC1.B30 UC1.B34 UC1.B39 UC1.B44 UC1.B48 UC1.B53 UC1.B58 UC1.B62 UC1.B66 UC1.B71 UC1.BA1 UC1.BA2 UC1.BA6 UC1.BA10 UC1.BA14 UC1.BA18 UC1.BA23 UC1.BA28 UC1.BA32 UC1.BA36 UC1.BA41 UC1.BA45 UC1.BA49 UC1.BA53 UC1.BA57 UC1.BA62 UC1.BA66 UC1.BA71 UC1.BB6 UC1.BB18 UC1.BB26 UC1.BB30 UC1.BB34 UC1.BB38 UC1.BB43 UC1.BB55 UC1.BB60 UC1.BB64 UC1.BB67 UC1.BB70 UC1.C1 UC1.C5 UC1.C25 UC1.D6 UC1.D10 UC1.D11 UC1.D14 UC1.D18 UC1.D22 UC1.D25 UC1.D26 UC1.D30 UC1.D34 UC1.D39 UC1.D44 UC1.D45 UC1.D47 UC1.D48 UC1.D53 UC1.D58 UC1.D62 UC1.D66 UC1.D69 UC1.E6 UC1.E11 UC1.E15 UC1.E18 UC1.E21 UC1.E46 UC1.E50 UC1.E53 UC1.E56 UC1.E65 UC1.E71 UC1.F1 UC1.F2 UC1.F4 UC1.F8 UC1.F13 UC1.F22 UC1.F23 UC1.F27 UC1.F28 UC1.F32 UC1.F33 UC1.F35 UC1.F37 UC1.F38 UC1.F40 UC1.F42 UC1.F68 UC1.G5 UC1.G6 UC1.G10 UC1.G22 UC1.G43 UC1.G45 UC1.G48 UC1.G52 UC1.G55 UC1.G58 UC1.G60 UC1.G63 UC1.G66 UC1.H15 UC1.H18 UC1.H71 UC1.J8 UC1.J11 UC1.J13 UC1.J25 UC1.J28 UC1.J32 UC1.J35 UC1.J38 UC1.J42 UC1.K16 UC1.K18 UC1.K22 UC1.K61 UC1.K63 UC1.K64 UC1.K65 UC1.K66 UC1.K67 UC1.K68 UC1.K70 UC1.K71 UC1.L2 UC1.L4 UC1.L8 UC1.L11 UC1.L16 UC1.L17 UC1.L18 UC1.L20 UC1.N6 UC1.N10 UC1.N13 UC1.N19 UC1.N21 UC1.N65 UC1.N68 UC1.P17 UC1.P19 UC1.P20 UC1.P21 UC1.R6 UC1.R13 UC1.T2 UC1.T4 UC1.T15 UC1.T17 UC1.T18 UC1.T21 UC1.U10 UC1.U63 UC1.U64 UC1.U66 UC1.U67 UC1.U69 UC1.U70 UC1.V16 UC1.V17 UC1.V18 UC1.W6 UC1.W9 UC1.W13 UC1.Y17 UC1.Y19 UC1.Y20 UC1.Y21 UC2.4 UC7.3 UC12.3 UC13.3 UC14.3 UC15.3 UE1.17 UE1.51 UE1.64 UE1.84 UE1.100 UE1.124 UE6.3 UE7.1 UL1.33 UL3.2 US2.3 US2.21 UUS5.14 UUS5.17 UZ2.11 UZ2.15 UZ6.3 UZ13.4 UZ13.11 UZ13.18 UZ13.25 UZ19.5 UZ21.5 UZ21.9 WLAN1.1 WLAN1.7 WLAN1.10 WLAN1.18 WLAN1.25 WLAN1.31 WLAN1.37 WLAN1.43 WLAN1.49 WLAN1.55 WLAN1.61 WLAN1.67 WLAN1.68 WLAN1.69
GNDA: C2715.2 CA23.1 CA33.2 CA38.2 CA39.2 CA40.2 CA51.2 CA61.2 CA62.1 CA63.1 CA71.2 CA74.2 CA75.2 CA76.2 JHP.6 JHP.7 RA12.1 RA29.1 RA30.1 RA31.1 RA32.1 RA83.2 RA84.2 RA1115.1 RA1116.1 UA1.25 UA1.38
VCC_EDRAM_SENSE: T134.1(TP-1) UC1.AC63
VCC_GT_5V: PC669.1 PR658.2 PU604.14 PU605.14
VCC_GT_SENSE: PC617.1 PC618.2 PC620.1 PR622.1 RC161.2 UC1.J70
VCCEOPIO_SENSE: T136.1(TP-1) UC1.AL63
VCCHDA: CC215.1 RC1138.1 UC1.AJ19
VCCIO_SENSE: T4947.1(TP-1) UC1.AM23
VCCSA_B+: PC608.1 PC612.1 PJP603.1 PQ601.2 PQ601.3 PQ601.4 PQ601.10
VCCSENSE: PC639.1 PC651.2 PC653.1 PR648.1 RC140.2 UC1.E32
VCCSENSE_VCCGTUS: RC340.2 UC1.AK62
VCCST_PWRGD: CC1808.1 RC78.2 UC1.B65
VCCSTG_EN: DZ1701.1 RZ1702.1 UC15.4
VCCSTG_EN_R: CZ1702.1 DZ1701.2 RZ1702.2 UZ19.4
VDD_1.2V: PC209.1 PR205.1 PR206.2 PU200.11
VDD_CHG: PC768.2 PR741.1 PR749.2 PR750.2 PR760.1 PU703.19
VDDP_CHG: PC769.2 PR760.2 PU703.20
VIN_+VCCEOPIO: PC1202.1 PC1203.1 PJP1201.2 PU1200.1
VSS_EDRAM_SENSE: T135.1(TP-1) UC1.AE63
VSS_GT_SENSE: PC619.2 PC620.2 PU602.6 RC163.1 UC1.J69
VSSEOPIO_SENSE: T137.1(TP-1) UC1.AJ62
VSSIO_SENSE: T4948.1(TP-1) UC1.AM22
VSSSENSE: PC653.2 PC654.2 PU602.18 RC141.1 UC1.E33
VSSSENSE_VCCGTUS: RC341.1 UC1.AL61
+A_VCC: RA10.2 UA1.20
+DCBATOUT_LCD: C5202.1 C5205.2 F5201.2 JEDP.37 JEDP.38 JEDP.39 R5214.2
+IR_LED+: JEDP.40 R6528.1
+LAN_VDDREG: CL2.1 CL4.1 CL6.1 CL7.1 CL9.1 CL12.1 RL23.1 UL1.3 UL1.8 UL1.22 UL1.30
+LCDVDD: R5211.2 U5201.3
+LCDVDD_LCD: C5201.1 C5206.2 C6219.1 JEDP.11 JEDP.12 JEDP.13 R5211.1
+MIC2-VREFO: RA53.2 RA1109.2 UA1.29
+RTC_CELL: C2503.1 CC213.1 CC270.1 D2501.1 RA10.1 RC56.2 RC57.2 RC69.1 RE31.1 RE349.2 RE437.2 UC1.AK19 UC1.BB14
+RTC_CELL_VBAT: CE73.1 RE349.1 UE1.122
+RTC_VCC: JIO1.20 R2502.1
+TP_VDD: C6201.1 Q6203.1 Q6204.2 R6203.2 R6211.1 R6505.1 R6506.1 R6508.1 RZ18.1 RZ19.1 TPAD1.8
+TPAN_VDD: F5203.2 JEDP.23 R5232.1
+USB30_VCCA: C3508.1 C3512.1 JUSB1.1 TC3502.1 UUS5.12
+USB30_VCCB: C3507.1 C3513.1 JUSB2.1 TC3501.1 U3504.1
+USB30_VCCC: JIO1.25 JIO1.26 JIO1.27 JIO1.28 JIO1.29 JIO2.1 U3505.1
+V_DDR_REFA: CD18.1 JDIMM1.164 RH206.2 RH209.1 RH484.2
+V_DDR_REFA_R: CH101.1 RH484.1 UC1.AY67
+V_DDR_REFB: CD29.1 JDIMM2.164 RH207.2 RH210.1 RH485.2
+V_DDR_REFB_R: CH100.1 RH485.1 UC1.BA67
AC_DIS: PQ709.5 UE1.69
AC_PRESENT: DZ4.2 RC243.1 UC1.AY15
ACAV_IN: CE84.2 DZ4.1 PR12.1 PR731.1 PR741.2 PU703.2 UE1.128
ACIN_CHG: PC711.2 PQ709.3 PR729.2 PR732.1 PU703.1
ACLIM: PR749.1 PR751.2 PU703.16
ADJ_2.5V: PC803.2 PR801.2 PR802.1 PU800.7
ALERT#: R2603.2 THM26.6
ALL_SYS_PWRGD: PQ102.2 RC388.1 RC392.2 RC1135.1 RC1136.1 RE438.2 UC13.4
ALL_SYS_PWRGD_R: RC1136.2 RC1137.2 UC12.2
ALWON: PR114.1 UE1.121
ASGATE: PR762.2 PU703.30
ASGATE_R: PQ740.4 PQ741.4 PR778.1
AUD_HP_OUT_L_CN: CA39.1 DA10.3 JHP.1 LA8.1
AUD_HP_OUT_R_CN: CA33.1 DA10.2 JHP.2 LA9.1
AUD_PC_BEEP: CA65.1 RA1114.1
BA: PD704.3 PQ710.1 PR780.1
BAT1_LED#: QC6.1 RE408.1 UE1.1
BAT1_LED#_R: JLED.3 QC6.6
BAT2_LED#: QC6.4 RE409.1 UE1.106
BAT2_LED#_R: JLED.4 Q6105.1 QC6.3
BEEP: DA8.2 UE1.45
BKLT_CTRL: D5202.1 RN5201.7 RN5203.8
BLON_OUT_C: JEDP.16 RN5201.1 RN5203.7
BLUETOOTH_EN: RC292.2 UC1.AB2 WLAN1.46
BOARD_ID: CE70.1 RE345.2 RE347.2 UE1.111
BREATH_LED#: JIO1.19 UE1.70
BST_1.2V: PR200.2 PU200.18
BST_1.2V_R: PC200.1 PR200.1
BST_3V: PR100.1 PU100.1
BST_5V: PR111.1 PU102.1
BST_+1VALW: PR306.1 PU300.1
BST_+1VALW_R: PC307.1 PR306.2
BST_+VCCEOPIO: PR1203.1 PU1200.9
BST_R_+VCCEOPIO: PC1201.1 PR1203.2
C0_1.0VS_VCCOPCP: PR1207.1 PU1200.4
C1_1.0VS_VCCOPCP: PR1206.2 PU1200.3
CAP_LED: JKB.4 R6201.2
CAP_LED#: Q6206.3 R6202.2 UE1.93
CAP_LED_Q: Q6201.1 R6201.1
CAP_LED_R#: Q6201.2 Q6206.1
CBN: CA24.2 UA1.35
CBP: CA24.1 UA1.37
CCLIM: PR750.1 PR752.2 PU703.11
CFG0: RC113.2 T89.1(TP-1) UC1.E68
CFG1: RC112.2 T90.1(TP-1) UC1.B67
CFG2: T91.1(TP-1) UC1.D65
CFG3: RC43.1 RC110.2 T92.1(TP-1) UC1.D67
CFG4: RC109.2 T93.1(TP-1) UC1.E70
CFG5: T94.1(TP-1) UC1.C68
CFG6: T95.1(TP-1) UC1.D68
CFG7: T96.1(TP-1) UC1.C67
CFG8: T99.1(TP-1) UC1.F71
CFG9: T100.1(TP-1) UC1.G69
CFG10: T101.1(TP-1) UC1.F70
CFG11: T102.1(TP-1) UC1.G68
CFG12: T103.1(TP-1) UC1.H70
CFG13: T104.1(TP-1) UC1.G71
CFG14: T105.1(TP-1) UC1.H69
CFG15: T106.1(TP-1) UC1.G70
CFG16: T98.1(TP-1) UC1.E63
CFG17: T97.1(TP-1) UC1.F63
CFG18: T108.1(TP-1) UC1.E66
CFG19: T107.1(TP-1) UC1.F66
CFG_RCOMP: RC114.1 UC1.E60
CLK_ITPXDP_N: T4943.1(TP-1) UC1.F43
CLK_ITPXDP_P: T4944.1(TP-1) UC1.E43
CLK_PCI_LPC_MEC: CC1802.2 RC18.2 RZ127.1 UE1.57
CLK_PCI_LPDEBUG: CC1803.2 JDB1.1 RC22.2
CLK_PCIE_LAN_N2: RC1116.2 UL1.16
CLK_PCIE_LAN_N2_R: RC1116.1 UC1.D41
CLK_PCIE_LAN_P2: RC1117.2 UL1.15
CLK_PCIE_LAN_P2_R: RC1117.1 UC1.C41
CLK_PCIE_LAN_REQ#: QL1.3 RC50.2 RL10.1 UC1.AT8
CLK_PCIE_WLAN_N1: RC1114.2 WLAN1.41
CLK_PCIE_WLAN_N1_R: RC1114.1 UC1.B42
CLK_PCIE_WLAN_P1: RC1115.2 WLAN1.39
CLK_PCIE_WLAN_P1_R: RC1115.1 UC1.A42
CLK_PCIE_WLAN_REQ#: R5803.1 RC47.2 UC1.AT7
CLK_PCIE_WLAN_REQ#_R: R5803.2 WLAN1.45
CLK_SMB: PBATT1.7 PR20.1
CLK_TP_SIO: RZ19.2 TPAD1.1 UE1.78
CLKRUN#: RC27.1 UC1.AW11 UE1.63
CMP_STRAP0: RE385.1 UE1.118
CMP_VIN0: RE392.1 RE394.2 UE1.20
CMP_VOUT0: PR116.1 RE392.2 RE404.2 UE1.85
CMSRC: PR763.2 PU703.29
COMP: PC751.2 PR754.2 PU703.10
COMP_IA: PC636.2 PR639.2 PU602.16
COMP_VSA: PC628.1 PR630.1 PU602.24
CORE_SNUB: PC662.1 PR663.2
CORE_SW: PL603.4 PR663.1 PU603.8
CORE_VID0: T4950.1(TP-1) UC1.AN11
CORE_VID1: T4951.1(TP-1) UC1.AN13
CPU_B+: PC656.1 PC657.1 PC658.1 PC659.1 PC660.1 PC680.1 PC686.1 PJP601.1 PJP603.2 PR603.2 PU603.6 PU603.12
CPU_DP1_N0: CHR12.1 UC1.F53
CPU_DP1_N1: CHR10.1 UC1.E58
CPU_DP1_N2: CHR8.1 UC1.E55
CPU_DP1_N3: CHR14.1 UC1.F56
CPU_DP1_P0: CHR11.1 UC1.G53
CPU_DP1_P1: CHR9.1 UC1.F58
CPU_DP1_P2: CHR7.1 UC1.F55
CPU_DP1_P3: CHR13.1 UC1.G56
CPU_POPIRCOMP: RC88.1 UC1.AT16
CPU_XDP_TCK0: RPC1.5 T116.1(TP-1) UC1.A59 UC1.B61
CPVDD: CA59.1 CA60.1 R6529.1 UA1.36
CPVEE: CA25.2 UA1.34
CRT_HPD: JIO1.16 R6533.1 UC1.L7
CS_1.2V: PR205.2 PU200.13
CSI2_COMP: RC3.1 UC1.E13
DAT_SMB: PBATT1.6 PR18.1
DAT_TP_SIO: RZ18.2 TPAD1.2 UE1.79
DBC_EN: R5213.2 UC1.AM5
DBC_EN_R: JEDP.10 R5213.1 R6507.2
DDPC_SDATA: RC1122.1 UC1.N8
DDR4_DRAMRST#: CD69.1 CD91.1 CD92.1 JDIMM1.108 JDIMM2.108 RD31.1
DDR_A_ACT#: JDIMM1.114 UC1.BA55
DDR_A_ALERT#: JDIMM1.116 UC1.AW50
DDR_A_BG0: JDIMM1.115 UC1.AY55
DDR_A_BG1: JDIMM1.113 UC1.AY54
DDR_A_BS0: JDIMM1.150 UC1.AU52
DDR_A_BS1: JDIMM1.145 UC1.AT48
DDR_A_CAS#: JDIMM1.156 UC1.AU48
DDR_A_CKE0: JDIMM1.109 UC1.BA56
DDR_A_CKE1: JDIMM1.110 UC1.BB56
DDR_A_CLK0: JDIMM1.137 UC1.AT53
DDR_A_CLK1: JDIMM1.138 UC1.AT55
DDR_A_CLK#0: JDIMM1.139 UC1.AU53
DDR_A_CLK#1: JDIMM1.140 UC1.AU55
DDR_A_CS#0: JDIMM1.149 UC1.AU45
DDR_A_CS#1: JDIMM1.157 UC1.AU43
DDR_A_D0: JDIMM1.4 UC1.AL71
DDR_A_D1: JDIMM1.3 UC1.AL68
DDR_A_D2: JDIMM1.20 UC1.AN68
DDR_A_D3: JDIMM1.21 UC1.AN69
DDR_A_D4: JDIMM1.8 UC1.AL70
DDR_A_D5: JDIMM1.7 UC1.AL69
DDR_A_D6: JDIMM1.16 UC1.AN70
DDR_A_D7: JDIMM1.17 UC1.AN71
DDR_A_D8: JDIMM1.29 UC1.AR70
DDR_A_D9: JDIMM1.25 UC1.AR68
DDR_A_D10: JDIMM1.37 UC1.AU71
DDR_A_D11: JDIMM1.41 UC1.AU68
DDR_A_D12: JDIMM1.24 UC1.AR71
DDR_A_D13: JDIMM1.28 UC1.AR69
DDR_A_D14: JDIMM1.42 UC1.AU70
DDR_A_D15: JDIMM1.38 UC1.AU69
DDR_A_D16: JDIMM1.45 UC1.BB65
DDR_A_D17: JDIMM1.49 UC1.AW65
DDR_A_D18: JDIMM1.63 UC1.AW63
DDR_A_D19: JDIMM1.58 UC1.AY63
DDR_A_D20: JDIMM1.50 UC1.BA65
DDR_A_D21: JDIMM1.46 UC1.AY65
DDR_A_D22: JDIMM1.59 UC1.BA63
DDR_A_D23: JDIMM1.62 UC1.BB63
DDR_A_D24: JDIMM1.67 UC1.BA61
DDR_A_D25: JDIMM1.70 UC1.AW61
DDR_A_D26: JDIMM1.79 UC1.BB59
DDR_A_D27: JDIMM1.84 UC1.AW59
DDR_A_D28: JDIMM1.66 UC1.BB61
DDR_A_D29: JDIMM1.71 UC1.AY61
DDR_A_D30: JDIMM1.83 UC1.BA59
DDR_A_D31: JDIMM1.80 UC1.AY59
DDR_A_D32: JDIMM1.174 UC1.AY39
DDR_A_D33: JDIMM1.170 UC1.AW39
DDR_A_D34: JDIMM1.187 UC1.AY37
DDR_A_D35: JDIMM1.186 UC1.AW37
DDR_A_D36: JDIMM1.169 UC1.BB39
DDR_A_D37: JDIMM1.173 UC1.BA39
DDR_A_D38: JDIMM1.182 UC1.BA37
DDR_A_D39: JDIMM1.183 UC1.BB37
DDR_A_D40: JDIMM1.195 UC1.AY35
DDR_A_D41: JDIMM1.191 UC1.AW35
DDR_A_D42: JDIMM1.207 UC1.AY33
DDR_A_D43: JDIMM1.203 UC1.AW33
DDR_A_D44: JDIMM1.194 UC1.BB35
DDR_A_D45: JDIMM1.190 UC1.BA35
DDR_A_D46: JDIMM1.208 UC1.BA33
DDR_A_D47: JDIMM1.204 UC1.BB33
DDR_A_D48: JDIMM1.211 UC1.AY31
DDR_A_D49: JDIMM1.216 UC1.AW31
DDR_A_D50: JDIMM1.229 UC1.AY29
DDR_A_D51: JDIMM1.228 UC1.AW29
DDR_A_D52: JDIMM1.215 UC1.BB31
DDR_A_D53: JDIMM1.212 UC1.BA31
DDR_A_D54: JDIMM1.224 UC1.BA29
DDR_A_D55: JDIMM1.225 UC1.BB29
DDR_A_D56: JDIMM1.237 UC1.AY27
DDR_A_D57: JDIMM1.233 UC1.AW27
DDR_A_D58: JDIMM1.236 UC1.AY25
DDR_A_D59: JDIMM1.232 UC1.AW25
DDR_A_D60: JDIMM1.245 UC1.BB27
DDR_A_D61: JDIMM1.249 UC1.BA27
DDR_A_D62: JDIMM1.246 UC1.BA25
DDR_A_D63: JDIMM1.250 UC1.BB25
DDR_A_DQS0: JDIMM1.13 UC1.AM69
DDR_A_DQS1: JDIMM1.34 UC1.AT70
DDR_A_DQS2: JDIMM1.55 UC1.AY64
DDR_A_DQS3: JDIMM1.76 UC1.BA60
DDR_A_DQS4: JDIMM1.179 UC1.AY38
DDR_A_DQS5: JDIMM1.200 UC1.BA34
DDR_A_DQS6: JDIMM1.221 UC1.AY30
DDR_A_DQS7: JDIMM1.242 UC1.BA26
DDR_A_DQS#0: JDIMM1.11 UC1.AM70
DDR_A_DQS#1: JDIMM1.32 UC1.AT69
DDR_A_DQS#2: JDIMM1.53 UC1.BA64
DDR_A_DQS#3: JDIMM1.74 UC1.AY60
DDR_A_DQS#4: JDIMM1.177 UC1.BA38
DDR_A_DQS#5: JDIMM1.198 UC1.AY34
DDR_A_DQS#6: JDIMM1.219 UC1.BA30
DDR_A_DQS#7: JDIMM1.240 UC1.AY26
DDR_A_MA0: JDIMM1.144 UC1.AY50
DDR_A_MA1: JDIMM1.133 UC1.BB50
DDR_A_MA2: JDIMM1.132 UC1.AY51
DDR_A_MA3: JDIMM1.131 UC1.BA50
DDR_A_MA4: JDIMM1.128 UC1.BB52
DDR_A_MA5: JDIMM1.126 UC1.BA51
DDR_A_MA6: JDIMM1.127 UC1.BA52
DDR_A_MA7: JDIMM1.122 UC1.AW52
DDR_A_MA8: JDIMM1.125 UC1.AY52
DDR_A_MA9: JDIMM1.121 UC1.BB54
DDR_A_MA10: JDIMM1.146 UC1.AT50
DDR_A_MA11: JDIMM1.120 UC1.BA54
DDR_A_MA12: JDIMM1.119 UC1.AW54
DDR_A_MA13: JDIMM1.158 UC1.AU46
DDR_A_ODT0: JDIMM1.155 UC1.AT45
DDR_A_ODT1: JDIMM1.161 UC1.AT43
DDR_A_PAR: JDIMM1.143 UC1.AT52
DDR_A_RAS#: JDIMM1.152 UC1.AU50
DDR_A_WE#: JDIMM1.151 UC1.AT46
DDR_B_ACT#: JDIMM2.114 UC1.AN53
DDR_B_ALERT#: JDIMM2.116 UC1.AN43
DDR_B_BG0: JDIMM2.115 UC1.AP52
DDR_B_BG1: JDIMM2.113 UC1.AN52
DDR_B_BS0: JDIMM2.150 UC1.BB44
DDR_B_BS1: JDIMM2.145 UC1.BA44
DDR_B_CAS#: JDIMM2.156 UC1.AY43
DDR_B_CKE0: JDIMM2.109 UC1.AN56
DDR_B_CKE1: JDIMM2.110 UC1.AP55
DDR_B_CKE2: T5.1(TP-1) UC1.AN55
DDR_B_CKE3: T6.1(TP-1) UC1.AP53
DDR_B_CLK0: JDIMM2.137 UC1.AP45
DDR_B_CLK1: JDIMM2.138 UC1.AP46
DDR_B_CLK#0: JDIMM2.139 UC1.AN45
DDR_B_CLK#1: JDIMM2.140 UC1.AN46
DDR_B_CS#0: JDIMM2.149 UC1.BB42
DDR_B_CS#1: JDIMM2.157 UC1.AY42
DDR_B_D0: JDIMM2.28 UC1.AF65
DDR_B_D1: JDIMM2.25 UC1.AF64
DDR_B_D2: JDIMM2.42 UC1.AK65
DDR_B_D3: JDIMM2.38 UC1.AK64
DDR_B_D4: JDIMM2.24 UC1.AF66
DDR_B_D5: JDIMM2.29 UC1.AF67
DDR_B_D6: JDIMM2.41 UC1.AK67
DDR_B_D7: JDIMM2.37 UC1.AK66
DDR_B_D8: JDIMM2.8 UC1.AF70
DDR_B_D9: JDIMM2.4 UC1.AF68
DDR_B_D10: JDIMM2.21 UC1.AH71
DDR_B_D11: JDIMM2.20 UC1.AH68
DDR_B_D12: JDIMM2.7 UC1.AF71
DDR_B_D13: JDIMM2.3 UC1.AF69
DDR_B_D14: JDIMM2.16 UC1.AH70
DDR_B_D15: JDIMM2.17 UC1.AH69
DDR_B_D16: JDIMM2.45 UC1.AT66
DDR_B_D17: JDIMM2.49 UC1.AU66
DDR_B_D18: JDIMM2.62 UC1.AP65
DDR_B_D19: JDIMM2.59 UC1.AN65
DDR_B_D20: JDIMM2.50 UC1.AN66
DDR_B_D21: JDIMM2.46 UC1.AP66
DDR_B_D22: JDIMM2.63 UC1.AT65
DDR_B_D23: JDIMM2.58 UC1.AU65
DDR_B_D24: JDIMM2.71 UC1.AT61
DDR_B_D25: JDIMM2.66 UC1.AU61
DDR_B_D26: JDIMM2.79 UC1.AP60
DDR_B_D27: JDIMM2.84 UC1.AN60
DDR_B_D28: JDIMM2.70 UC1.AN61
DDR_B_D29: JDIMM2.67 UC1.AP61
DDR_B_D30: JDIMM2.83 UC1.AT60
DDR_B_D31: JDIMM2.80 UC1.AU60
DDR_B_D32: JDIMM2.169 UC1.AU40
DDR_B_D33: JDIMM2.173 UC1.AT40
DDR_B_D34: JDIMM2.183 UC1.AT37
DDR_B_D35: JDIMM2.187 UC1.AU37
DDR_B_D36: JDIMM2.170 UC1.AR40
DDR_B_D37: JDIMM2.174 UC1.AP40
DDR_B_D38: JDIMM2.186 UC1.AP37
DDR_B_D39: JDIMM2.182 UC1.AR37
DDR_B_D40: JDIMM2.190 UC1.AT33
DDR_B_D41: JDIMM2.194 UC1.AU33
DDR_B_D42: JDIMM2.207 UC1.AU30
DDR_B_D43: JDIMM2.203 UC1.AT30
DDR_B_D44: JDIMM2.191 UC1.AR33
DDR_B_D45: JDIMM2.195 UC1.AP33
DDR_B_D46: JDIMM2.204 UC1.AR30
DDR_B_D47: JDIMM2.208 UC1.AP30
DDR_B_D48: JDIMM2.216 UC1.AU27
DDR_B_D49: JDIMM2.212 UC1.AT27
DDR_B_D50: JDIMM2.225 UC1.AT25
DDR_B_D51: JDIMM2.229 UC1.AU25
DDR_B_D52: JDIMM2.211 UC1.AP27
DDR_B_D53: JDIMM2.215 UC1.AN27
DDR_B_D54: JDIMM2.228 UC1.AN25
DDR_B_D55: JDIMM2.224 UC1.AP25
DDR_B_D56: JDIMM2.232 UC1.AT22
DDR_B_D57: JDIMM2.236 UC1.AU22
DDR_B_D58: JDIMM2.249 UC1.AU21
DDR_B_D59: JDIMM2.245 UC1.AT21
DDR_B_D60: JDIMM2.237 UC1.AN22
DDR_B_D61: JDIMM2.233 UC1.AP22
DDR_B_D62: JDIMM2.250 UC1.AP21
DDR_B_D63: JDIMM2.246 UC1.AN21
DDR_B_DQS0: JDIMM2.34 UC1.AH65
DDR_B_DQS1: JDIMM2.13 UC1.AG70
DDR_B_DQS2: JDIMM2.55 UC1.AR65
DDR_B_DQS3: JDIMM2.76 UC1.AR60
DDR_B_DQS4: JDIMM2.179 UC1.AR38
DDR_B_DQS5: JDIMM2.200 UC1.AR32
DDR_B_DQS6: JDIMM2.221 UC1.AR27
DDR_B_DQS7: JDIMM2.242 UC1.AR21
DDR_B_DQS#0: JDIMM2.32 UC1.AH66
DDR_B_DQS#1: JDIMM2.11 UC1.AG69
DDR_B_DQS#2: JDIMM2.53 UC1.AR66
DDR_B_DQS#3: JDIMM2.74 UC1.AR61
DDR_B_DQS#4: JDIMM2.177 UC1.AT38
DDR_B_DQS#5: JDIMM2.198 UC1.AT32
DDR_B_DQS#6: JDIMM2.219 UC1.AR25
DDR_B_DQS#7: JDIMM2.240 UC1.AR22
DDR_B_MA0: JDIMM2.144 UC1.BA46
DDR_B_MA1: JDIMM2.133 UC1.AY46
DDR_B_MA2: JDIMM2.132 UC1.AY47
DDR_B_MA3: JDIMM2.131 UC1.BB46
DDR_B_MA4: JDIMM2.128 UC1.BA47
DDR_B_MA5: JDIMM2.126 UC1.AY48
DDR_B_MA6: JDIMM2.127 UC1.BA48
DDR_B_MA7: JDIMM2.122 UC1.AP48
DDR_B_MA8: JDIMM2.125 UC1.BB48
DDR_B_MA9: JDIMM2.121 UC1.AP50
DDR_B_MA10: JDIMM2.146 UC1.AW46
DDR_B_MA11: JDIMM2.120 UC1.AN48
DDR_B_MA12: JDIMM2.119 UC1.AN50
DDR_B_MA13: JDIMM2.158 UC1.BA43
DDR_B_ODT0: JDIMM2.155 UC1.BA42
DDR_B_ODT1: JDIMM2.161 UC1.AW42
DDR_B_PAR: JDIMM2.143 UC1.AP43
DDR_B_RAS#: JDIMM2.152 UC1.AW44
DDR_B_WE#: JDIMM2.151 UC1.AY44
DDR_VTT_CNTL: UC1.AW67 UC14.2
DEW1: RS34.1 RS36.1 US2.16
DEW2: RS33.1 RS35.1 US2.6
DIMM_CHA_SA0: JDIMM1.256 RD1.2 RD28.1
DIMM_CHA_SA1: JDIMM1.260 RD2.2 RD29.1
DIMM_CHA_SA2: JDIMM1.166 RD3.2 RD30.1
DIMM_CHB_SA0: JDIMM2.256 RD4.2 RD38.1
DIMM_CHB_SA1: JDIMM2.260 RD5.2 RD39.1
DIMM_CHB_SA2: JDIMM2.166 RD6.2 RD40.1
DMIC_CLK: C6223.1 EC5206.1 LA1.2 R5207.2
DMIC_CLK_C: LA1.1 UA1.3
DMIC_CLK_EDP: EU3405.1 EU3405.9 JEDP.27 R5207.1
DMIC_DATA: EC5205.1 R5215.2 UA1.2
DMIC_DATA_EDP: EU3405.2 EU3405.8 JEDP.28 R5215.1
E51_RX1: T4969.1(TP-1) WLAN1.38
E51_TX1: R6527.1 WLAN1.36 WLAN1.58
E51_TX2: R5812.1 R6517.1 WLAN1.30
EC_AGND: C2403.2 CE70.2 CE81.2 CE87.2 CE88.2 R2407.1 RE347.1 RE398.1 UE1.112
EC_MISO_R: RC1119.2 RE416.1 RPC5.8
EC_MOSI_R: RC58.2 RE414.1 RPC5.7
EC_MUTE#: RA14.2 RE433.1 RE435.1 UA1.47
EC_MUTE#_R: RE433.2 UE1.119
EC_SPI_CLK: RE413.2 UE1.32
EC_SPI_CS0#: RE410.1 UE1.27
EC_SPI_MISO: RE416.2 UE1.29
EC_SPI_MOSI: RE414.2 UE1.28
EC_SPICLK_R: CC1805.2 CC1823.2 RC59.2 RE413.1 RPC5.6 RZ66.1
EC_SPICS#_R: RC1125.2 RE410.2 UC2.1
EC_WAKE#: RC391.1 UE1.35
EDP_AUX_DN: C5209.1 UC1.E45
EDP_AUX_DN_C: C5209.2 JEDP.7
EDP_AUX_DP: C5212.1 UC1.F45
EDP_AUX_DP_C: C5212.2 JEDP.8
EDP_BKLT_CTRL: D5202.2 R5206.2
EDP_COMP: RC2.2 UC1.E52
EDP_HPD: JEDP.15 RN5203.6 UC1.L10
EDP_TX0_DN: C5203.1 UC1.C47
EDP_TX0_DN_C: C5203.2 JEDP.4
EDP_TX0_DP: C5210.1 UC1.C46
EDP_TX0_DP_C: C5210.2 JEDP.5
EDP_TX1_DN: C5211.1 UC1.D46
EDP_TX1_DN_C: C5211.2 JEDP.1
EDP_TX1_DP: C5213.1 UC1.C45
EDP_TX1_DP_C: C5213.2 JEDP.2
EDP_VDD_EN: D5201.2 UC1.U13
EDRAM_OPIO_RCOMP: RC90.1 UC1.H66
EMMC_RCOMP: RC4.1 UC1.AT1
EN_0.6VSP: PC203.1 PR202.2 PU200.7
EN_1.0V_VCCST_ON: CZ1705.1 DZ1703.2 RZ1701.2 UZ21.3
EN_1.2V: PC202.1 PR201.2 PU200.8
EN_1.8VALW: PC502.1 PR501.2 PR502.2 PU500.5
EN_2.5V: PC805.1 PR803.2 PU800.2
EN_3V: PR121.1 PU100.12
EN_5V: PR120.1 PU102.12
EN_+1VALW: PC304.1 PR301.2 PR302.1 PU300.11
EN_+VCCEOPIO: PC1204.1 PR1204.1 PR1205.1 PU1200.5
ENLDO_3V5V: PR102.1 PR103.1 PU100.11 PU102.11
EOPIO_RCOMP: RC91.1 UC1.H65
FAN1_PWM: Q6502.3 R6534.2 R6535.1 UE1.47
FAN1_PWM_R: JFAN1.2 Q6502.1 R6535.2
FAN1_TACH: C2604.2 CE75.1 JFAN1.3 RE441.1 UE1.40
FB_1.2V: PC214.1 PR204.1 PR207.1 PU200.6
FB_1.8VALW: PC503.2 PR504.1 PR505.1 PU500.6
FB_+1VALW: PC309.2 PR309.1 PR310.1 PU300.14
FB_IA: PR645.2 PR648.2 PR650.1 PU602.17
FB_VSA: PR646.1 PR649.1 PR652.1 PU602.25
FCCM_GT: PR664.2 PR671.1 PU602.11
FCCM_IA: PR659.1 PU602.21
FCCM_VSA: PR679.1 PU602.29
FFS_INT1: RC1123.2 U5603.12 UC1.BB11
FFS_INT2: QC5.5 U5603.11 UC1.J4
FFS_INT2_Q: HDD1.4 QC5.6 RS1.2
GC6_THM_DIS#: RE450.1 UE1.24
GPP_B23: RC365.1 UC1.AM7
GPP_C5: RC25.1 UC1.W1
GPU_B+: PC664.1 PC665.1 PC666.1 PC667.1 PC668.1 PC672.1 PC673.1 PC674.1 PC679.1 PC681.1 PC687.1 PC688.1 PC690.1 PJP602.1 PL606.1 PU604.6 PU604.12 PU605.6 PU605.12
GPU_PWR_LEVEL: RE451.1 UE1.21
GPU_THM_SMBCLK: Q2601.3 RC399.2 UE1.12
GPU_THM_SMBDAT: Q2601.6 RC397.2 UE1.11
GT1N: PL605.2 PR670.1 PR673.1
GT1P: PL605.3 PR674.2 PR675.1
GT2N: PL604.2 PR666.1 PR677.2
GT2P: PL604.3 PR667.2 PR668.1
GT_SNUB1: PC678.1 PR676.2
GT_SNUB2: PC670.1 PR669.2
GT_SW1: PL605.4 PR676.1 PU605.8
GT_SW2: PL604.4 PR669.1 PU604.8
H_CATERR#: RC79.2 UC1.D63
H_CPU_SVIDALRT#: RC153.1 UC1.B63
H_CPUPWRGD: T9.1(TP-1) UC1.A68
H_DRAMRST#: RC1126.1 RD31.2 RD35.2 UC1.AT13
H_PROCHOT#: CE86.1 PC605.2 PQ2.6 PQ3.1 PQ721.1 PR678.1 PR777.1 RC83.2 RC84.1 UE6.4
H_PROCHOT#_R: CC1809.1 RC84.2 UC1.C65
H_PROCHOT_EC: RE380.2 UE1.83 UE6.2
H_THERMTRIP#: RC80.2 UC1.C63
H_VCCST_PWRGD: RC78.1 RC1118.2 UC12.4
HDA_BIT_CLK: RC93.2 UC1.AY22
HDA_CODEC_BITCLK: CC27.1 RC93.1 UA1.6
HDA_CODEC_RST#: RC95.1 UA1.11
HDA_CODEC_SDIN0: RA130.2 UA1.8
HDA_CODEC_SDOUT: RC94.1 UA1.5
HDA_CODEC_SYNC: RC92.1 UA1.10
HDA_RST#: RC95.2 UC1.AW22
HDA_SDIN0: RA130.1 UC1.BA21
HDA_SDOUT: RC94.2 RC187.2 RC223.2 UC1.BB22
HDA_SYNC: RC92.2 UC1.BA22
HDD_A0_PRE0: RS24.1 RS27.2 US2.9
HDD_A0_PRE1: RS23.1 RS30.2 US2.19
HDD_B0_EQ: RS37.1 RS38.1 US2.13
HDD_B0_PRE0: RS21.1 RS28.2 US2.8
HDD_B0_PRE1: RS18.1 RS29.2 US2.17
HDD_DEVSLP: R5605.2 UC1.J1
HDD_DEVSLP_C: JSSD1.38 R6526.1 RB1.2
HDD_DEVSLP_R: HDD1.5 R5605.1
HDD_REXT_SATA0: RS26.2 RS31.1 US2.20
HDMI_HPD: QX5.3 RX14.1 UC1.L9
HDMIOUT_CLK+: CHO8.1 CHR13.2 RHO3.1 RP58.1
HDMIOUT_CLK-: CHR14.2 RHO1.1 RHO9.1 RP58.2
HDMIOUT_HPD: JHDMI.19 RX15.2 RX34.1
HDMIOUT_R_CK+: JHDMI.10 RHO3.2
HDMIOUT_R_CK-: JHDMI.12 RHO1.2
HDMIOUT_R_D0+: JHDMI.7 RHO4.2
HDMIOUT_R_D0-: JHDMI.9 RHO2.2
HDMIOUT_R_D1+: JHDMI.4 RHO7.2
HDMIOUT_R_D1-: JHDMI.6 RHO5.2
HDMIOUT_R_D2+: JHDMI.1 RHO8.2
HDMIOUT_R_D2-: JHDMI.3 RHO6.2
HDMIOUT_SCLK: JHDMI.15 QX4.6 RHR11.1
HDMIOUT_SDATA: JHDMI.16 QX4.3 RHR8.1
HDMIOUT_TX0+: CHO9.1 CHR11.2 RHO4.1 RP58.3
HDMIOUT_TX0-: CHR12.2 RHO2.1 RHO10.1 RP58.4
HDMIOUT_TX1+: CHO10.1 CHR9.2 RHO7.1 RP59.3
HDMIOUT_TX1-: CHR10.2 RHO5.1 RHO11.1 RP59.4
HDMIOUT_TX2+: CHO11.1 CHR7.2 RHO8.1 RP59.1
HDMIOUT_TX2-: CHR8.2 RHO6.1 RHO12.1 RP59.2
HOST_DEBUG_TX: JDEG1.8 R5812.2 R6527.2 RE73.2 UE1.81
HPOUT-L: RA55.1 UA1.32
HPOUT-R: RA56.1 UA1.33
I2C_SCL_TP: Q6501.1 RZ21.2 UC1.U6
I2C_SCL_TP_Q: C6226.1 Q6501.6 R6506.2 TPAD1.6
I2C_SDA_TP: Q6501.4 RZ20.2 UC1.U7
I2C_SDA_TP_Q: C6225.1 Q6501.3 R6508.2 TPAD1.7
I_ADP: PC748.1 PR774.1 RE399.2
I_ADP_R: CE87.1 RE399.1 UE1.110
I_BATT: PC749.2 PR775.1 RE400.2
I_BATT_R: CE88.1 RE400.1 UE1.114
I_SYS: PR620.1 PR727.1 PU703.8
ICSP_CLK: RE420.1 RE435.2 UE1.101
ICSP_CLR: RE421.1 UE1.87
ICSP_DAT: RE423.1 RE436.2 UE1.102
ILMT_+1VALW: PR304.1 PR305.1 PU300.13
IMON_IA: PC625.2 PR629.2 PU602.14
IMON_VSA: PC643.1 PR651.1 PU602.23
IMVP_VR_ON: PR616.1 RC1135.2
INT-SPK-L+: LA6.1 UA1.42
INT-SPK-L-: LA5.1 UA1.43
INT-SPK-R+: LA4.1 UA1.45
INT-SPK-R-: LA3.1 UA1.44
INT_TP#: Q6204.3 R6203.1 TPAD1.4
INTRUDER#: RC69.2 UC1.AP16
IR_CAM_DET#: DZ1704.2 RC293.2 UC1.P4
IR_CAM_DET#_D: DZ1704.1 JEDP.34
IR_LED-: JEDP.35 R6530.1
ISEN1_GT: PC635.2 PR615.2 PR675.2 PR677.1 PU602.9
ISEN2_GT: PC638.2 PR634.2 PR668.2 PR670.2 PU602.10
ISOLATE#: RL2.2 RL4.1 UL1.20
ISUMN_GT: PC624.2 PC626.2 PC635.1 PC638.1 PC641.1 PH602.2 PR632.1 PR633.2 PR638.1 PR666.2 PR673.2
ISUMN_IA: PC642.2 PC645.1 PC646.2 PH605.2 PL603.2 PR640.2 PR644.2 PR656.2
ISUMN_VSA: PC633.2 PC637.2 PC644.1 PH604.2 PL601.2 PR636.2 PR641.2 PR643.1
ISUMP_GT: PC624.1 PC626.1 PR628.1 PR633.1 PR637.1 PR667.1 PR674.1 PU602.7
ISUMP_IA: PC642.1 PC646.1 PR653.1 PR656.1 PR657.1 PR661.2 PU602.19
ISUMP_VSA: PC633.1 PC637.1 PR624.2 PR642.1 PR643.2 PR654.1 PU602.27
JACK_PLUG#: JHP.5 RA4.1
JACK_SENSE#: RA4.2 RA13.1 UA1.13
JTAG_CLK: JDEG1.4 RE422.2
JTAG_TDI: JDEG1.2 RE420.2
JTAG_TDO: JDEG1.5 RE423.2
JTAG_TMS: JDEG1.3 RE421.2
KB_BL_CTRL#: JKBBL.4 Q6202.1
KB_DET#: JKB.30 RC288.1 UC1.BB7
KB_LED_BL_DET: R6206.1 R6207.1 UC1.W8
KB_LED_DET_C: JKBBL.2 R6206.2
KB_LED_PWM: Q6202.2 UE1.44
KSI0: JKB.22 RPE2.4 UE1.98
KSI1: JKB.24 RPE2.3 UE1.99
KSI2: JKB.26 RPE2.2 UE1.6
KSI3: JKB.23 RPE2.1 UE1.7
KSI4: JKB.27 RPE3.4 UE1.104
KSI5: JKB.25 RPE3.3 UE1.105
KSI6: JKB.28 RPE3.2 UE1.107
KSI7: JKB.29 RPE3.1 UE1.108
KSO0: JKB.13 RPE4.8 UE1.2
KSO1: JKB.15 RPE4.7 UE1.14
KSO2: JKB.14 RPE4.6 UE1.15
KSO3: JKB.16 RPE4.5 UE1.16
KSO4: JKB.20 RPE5.8 UE1.37
KSO5: JKB.21 RPE5.7 UE1.38
KSO6: JKB.18 RPE5.6 UE1.39
KSO7: JKB.19 RPE5.5 UE1.50
KSO8: JKB.17 RPE7.8 UE1.46
KSO9: JKB.7 RE389.1 UE1.68
KSO10: JKB.5 RPE6.8 UE1.72
KSO11: JKB.6 RPE6.7 UE1.74
KSO12: JKB.12 RPE6.6 UE1.75
KSO13: JKB.9 RPE6.5 UE1.76
KSO14: JKB.8 RPE7.6 UE1.77
KSO15: JKB.10 RPE7.7 UE1.86
KSO16: JKB.11 RPE7.5 UE1.92
L_BKLT_CTRL: R5206.1 UC1.R11
L_BKLT_EN_EC: RC390.2 UC1.R12 UE1.91
LAN_CLKREQ#_R: QL1.1 RL7.2 RL10.2 UL1.12
LAN_EN: R3023.2 UE1.3 UL3.4
LAN_GND: CL43.2 CL44.2 CL45.2 JRJ45.9 JRJ45.10 JRJ45.11
LAN_MIDI0+: TL1.2 UL1.1
LAN_MIDI0-: TL1.3 UL1.2
LAN_MIDI1+: TL1.5 UL1.4
LAN_MIDI1-: TL1.6 UL1.5
LAN_MIDI2+: TL1.8 UL1.6
LAN_MIDI2-: TL1.9 UL1.7
LAN_MIDI3+: TL1.11 UL1.9
LAN_MIDI3-: TL1.12 UL1.10
LAN_WAKE#: RC70.2 RC391.2 UC1.AM15
LAN_X1: CL16.1 RL8.1 UL1.28 YL1.1
LAN_X2: CL17.1 RL8.2 UL1.29 YL1.3
LANWAKEB: RL1.1 UL1.21
LCD_BRIGHTNESS: JEDP.17 RN5201.2
LCD_TST: D5202.3 RN5201.6 UE1.26
LCD_TST_C: JEDP.14 RN5201.3
LCD_VCC_TEST_EN: RE442.2 UE1.113
LCD_VCC_TEST_EN_R: D5201.3 RE442.1
LCDVDD_EN: D5201.1 R5202.2 U5201.1
LDO1_CAP: CA62.2 RA12.2 UA1.27
LDO2_CAP: CA63.2 UA1.39
LDO3_CAP: CA64.2 UA1.7
LDO_+1VALW: PC306.1 PU300.16 PU300.17
LG_1.2V: PQ201.8 PU200.15
LGATE_CHG: PQ708.4 PU703.21
LID_CLOSE#: CE2.1 CE8.1 D5203.1 RE25.2 UE1.41 UE7.3
LINE1-L: CA67.1 UA1.22
LINE1-R: CA68.1 UA1.21
LINE1-VREFO-L: RA165.1 UA1.31
LINE1-VREFO-R: RA166.1 UA1.30
LINE-IN-L: LA8.2 RA55.2 RA80.2 RA83.1 RA165.2
LINE-IN-R: LA9.2 RA56.2 RA82.2 RA84.1 RA166.2
LP#_+VCCEOPIO: PR1201.1 PU1200.6
LPC_LAD0: JDB1.8 RZ124.1 UC1.AY13 UE1.59
LPC_LAD1: JDB1.7 RZ125.1 UC1.BA13 UE1.60
LPC_LAD2: JDB1.6 RZ121.1 UC1.BB13 UE1.61
LPC_LAD3: JDB1.5 RZ122.1 UC1.AY12 UE1.62
LPC_LFRAME#: JDB1.4 RZ123.1 UC1.BA12 UE1.58
LPSS_UART2_CTS#: RC382.1 UC1.AD4
LX_1.2V: PC200.2 PL200.2 PQ201.9 PR203.1 PU200.16
LX_1.8VALW: PL501.1 PR506.1 PU500.2 PU500.3
LX_3V: PC102.2 PL100.1 PR106.1 PU100.6 PU100.19 PU100.20
LX_5V: PC114.2 PL101.1 PR112.1 PU102.6 PU102.19 PU102.20
LX_+1VALW: PC307.2 PL301.1 PR307.1 PU300.6 PU300.19 PU300.20
MCT1: RL19.1 TL1.24
MCT2: RL20.1 TL1.21
MCT3: RL22.1 TL1.18
MCT4: RL21.1 TL1.15
ME_FWP_EC: RC223.1 RE357.1 UE1.80
ME_SUS_PWR_ACK: RC74.2 UC1.AR13 UE1.42
MEC_XTAL1: C5225.1 RE366.2 Y1.1
MEC_XTAL1_R: RE366.1 UE1.123
MEC_XTAL2: C5226.1 RE368.1 UE1.125 Y1.2
MIC1-L: CA74.1 UA1.19
MIC_IN_R: CA38.1 CA75.1 DA12.3 JHP.3 LA7.1
MODEL_ID: C2403.1 R2407.2 R2446.2 UE1.109
MONO_PC_BEEP_R: RA1114.2 UA1.16
MPHYP_PWR_EN: T4974.1(TP-1) UC1.AM10
MSCLK: JDEG1.6 RE72.2
MSDATA: JDEG1.7 RE75.2
NCT7718_DXN: C2606.2 C2607.2 Q2603.3 THM26.3
NCT7718_DXP: C2606.1 C2607.1 Q2603.1 Q2603.2 THM26.2
NRB_BIT: RC186.2 UC1.AR7
NTC_IA: PR635.2 PU602.15
PANEL_BKEN_EC: RN5201.8 UE1.117
PBAT_CHG_SMBCLK: PD2.3 PR20.2 PR770.1 RE425.1 UE1.9
PBAT_CHG_SMBDAT: PD2.2 PR18.2 PR769.1 RE424.1 UE1.8
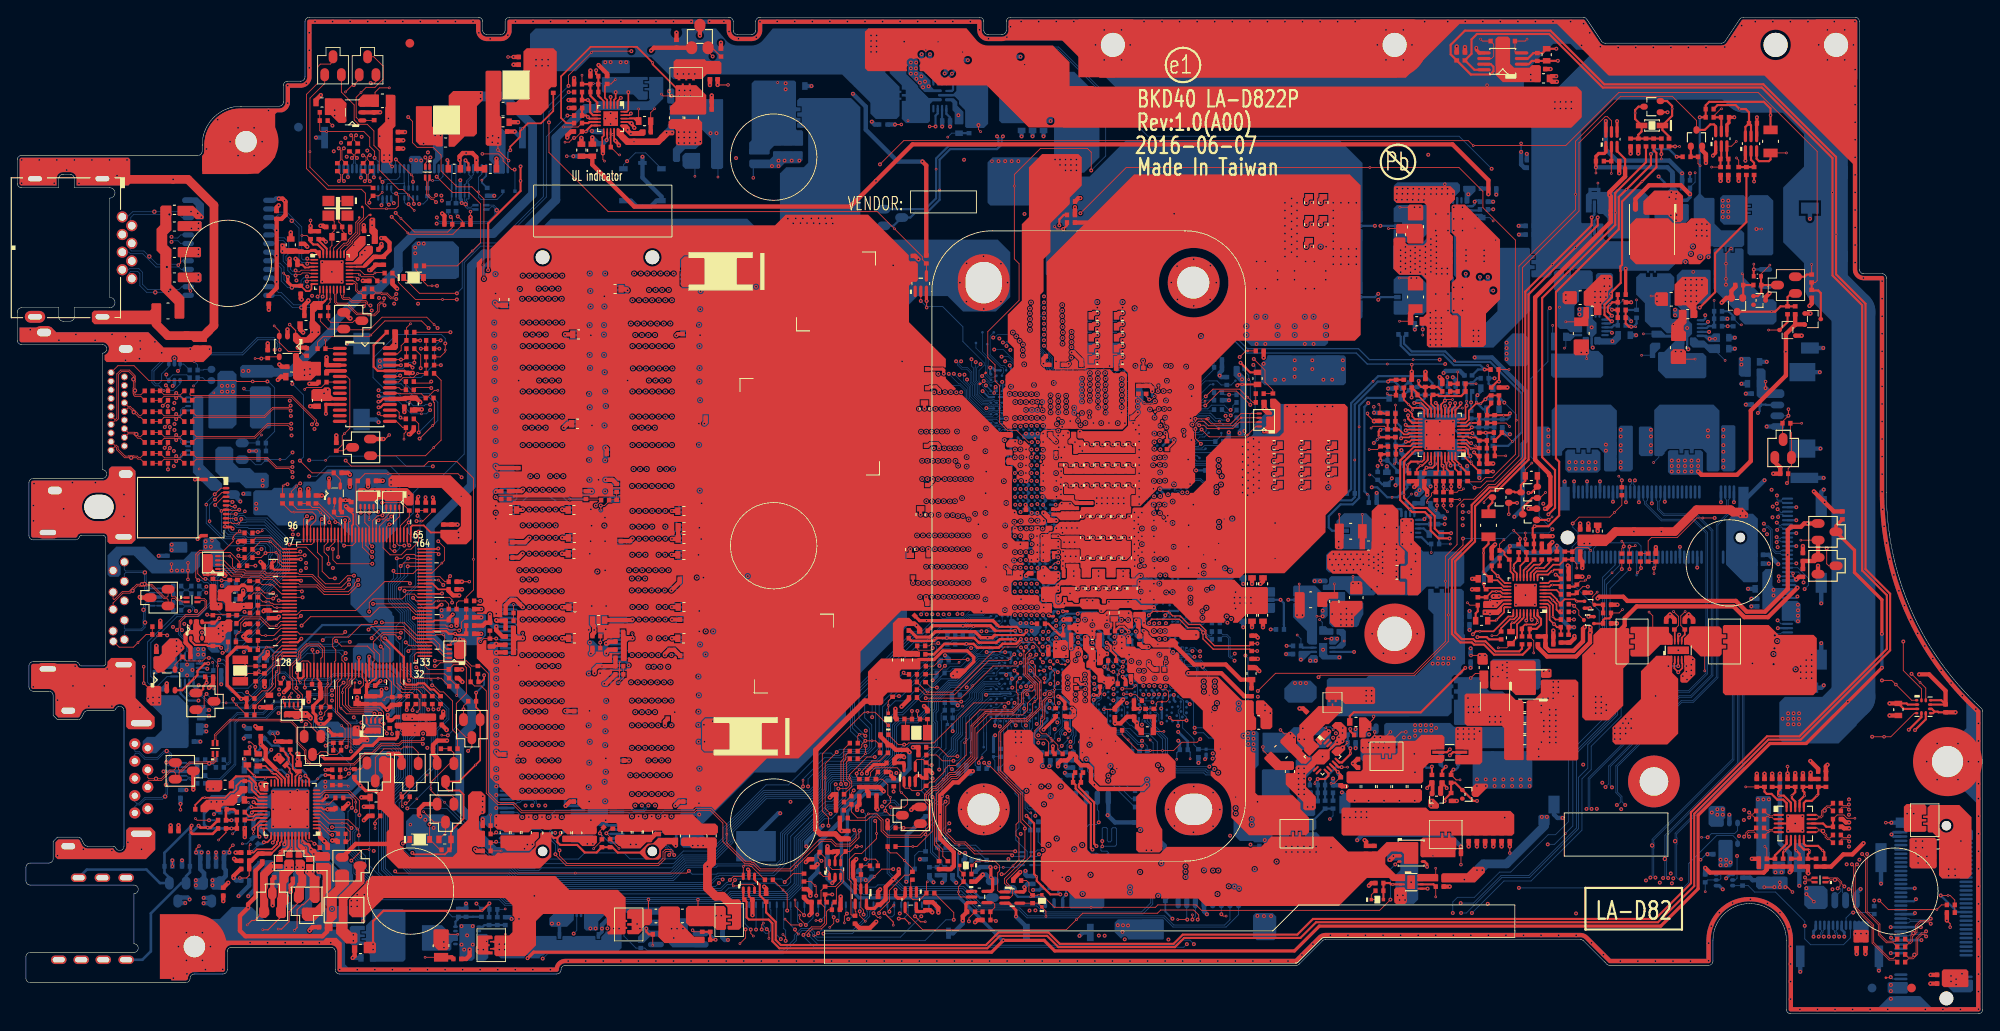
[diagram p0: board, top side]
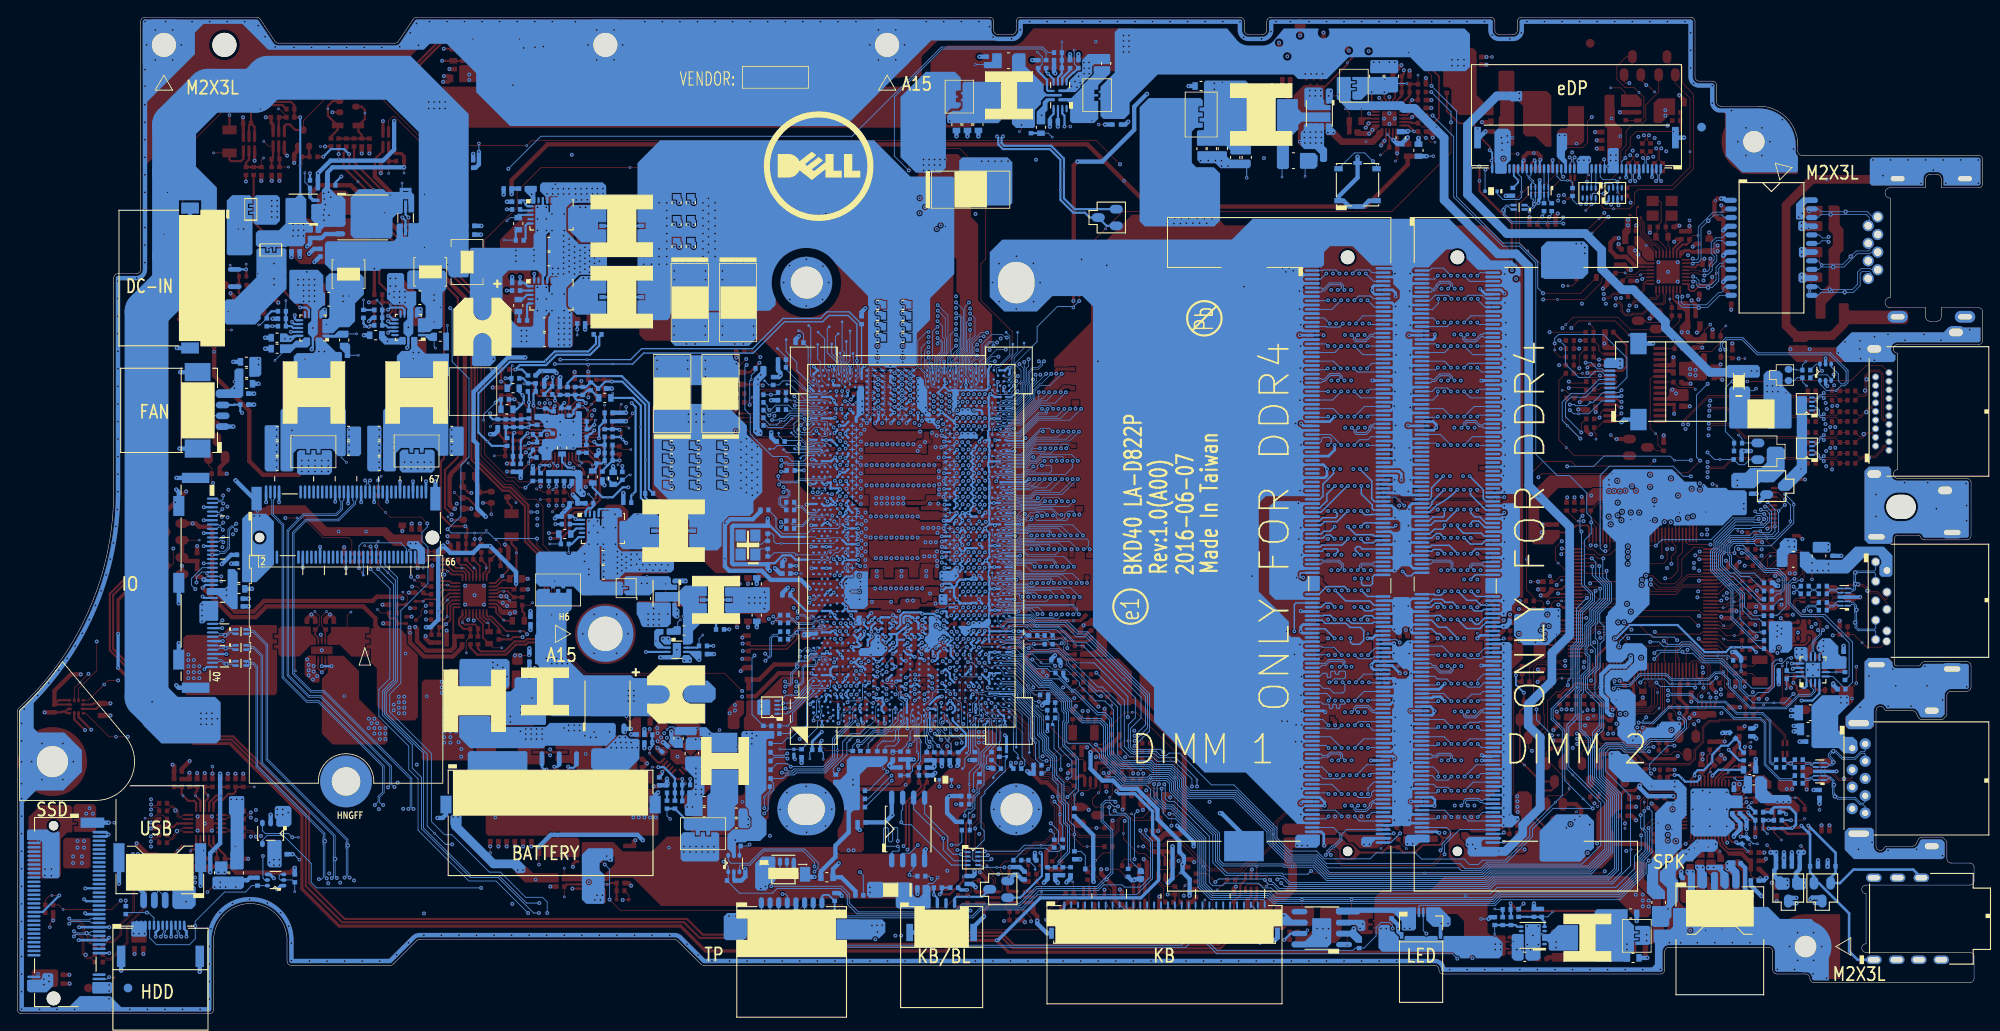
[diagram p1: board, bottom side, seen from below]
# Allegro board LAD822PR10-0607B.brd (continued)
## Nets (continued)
PBAT_PRES#: CE76.1 PC14.1 PC753.2 PD3.2 PR15.2 PR16.1 PR756.1 PR764.1 UE1.97
PC_BEEP: DA8.1 RA19.1 RA79.2
PCH_ALW_ON: RE446.1 RE448.2 UE1.71
PCH_BATLOW#: RC72.1 UC1.AU13
PCH_DPWROK: RC216.2 RC1139.2 UC1.BB20
PCH_JTAG_TCK1: RC348.1 T117.1(TP-1) UC1.B56
PCH_PCIE_WAKE#: RC395.2 UC1.BB15
PCH_PLTRST#: CC1806.1 UC1.AN10 UC7.1 UC7.2
PCH_PLTRST#_EC: CE72.1 JDB1.3 R5212.2 R5807.2 RC65.1 UC7.4 UE1.56 UL1.19 UZ13.16
PCH_POPIRCOMP: RC89.1 UC1.AU16
PCH_RSMRST#: CC1810.1 RE355.1 UE1.88 UZ6.1
PCH_RSMRST#_Q: RC75.2 RC158.1 RC216.1 UC1.AY17 UZ6.4
PCH_RTCRST#: CC25.1 CLRP1.2 Q1901.1 RC57.1 UC1.AM16
PCH_RTCX1: CC23.1 RC54.2 UC1.AM18 YC2.1
PCH_RTCX2: CC26.1 RC54.1 UC1.AM20 YC2.2
PCH_SMB_ALERT#: RC23.1 UC1.R10
PCH_SMBCLK: JDIMM1.253 JDIMM2.253 JIO1.17 QC2.1 RN20.2 U5603.1
PCH_SMBDATA: JDIMM1.254 JDIMM2.254 JIO1.18 QC2.4 RN19.2 U5603.4
PCH_SPI1_CLK_R: RZ66.2 RZ127.2 UZ13.21
PCH_SPI_CLK: RC59.1 UC1.AV2
PCH_SPI_CLK_R: RPC5.3 UC2.6
PCH_SPI_CS2#: RZ115.1 UC1.AU1
PCH_SPI_CS2#_R: RZ115.2 RZ120.1 RZ123.2 UZ13.22
PCH_SPI_CS#0: RC53.2 RC1125.1 UC1.AU3
PCH_SPI_D0: RC58.1 RC355.2 RZ64.1 UC1.AV3
PCH_SPI_D0_R: RPC5.2 UC2.5
PCH_SPI_D1: RC1119.1 RZ62.1 UC1.AW3
PCH_SPI_D1_R: RPC5.1 UC2.2
PCH_SPI_D2: RC30.2 RC354.2 RC1120.1 UC1.AW2
PCH_SPI_D2_R: RC61.2 UC2.3
PCH_SPI_D3: RC60.1 UC1.AU4
PCH_SPI_D3_R: RPC5.4 UC2.7
PCH_SPI_MISO: RZ62.2 RZ124.2 UZ13.26
PCH_SPI_MOSI: RZ64.2 RZ125.2 UZ13.23
PCI_CLK_LPC1: RC18.1 RC22.1 UC1.AY9
PCIE_PRX_C_LANTX_N6: CL14.1 UL1.18
PCIE_PRX_C_LANTX_P6: CL13.1 UL1.17
PCIE_PRX_LANTX_N6: CL14.2 UC1.G18
PCIE_PRX_LANTX_P6: CL13.2 UC1.F18
PCIE_PRX_WLANTX_N5: UC1.F16 WLAN1.35
PCIE_PRX_WLANTX_P5: UC1.E16 WLAN1.33
PCIE_PTX_C_LANRX_N6: CC135.1 UL1.14
PCIE_PTX_C_LANRX_P6: CC136.1 UL1.13
PCIE_PTX_C_WLANRX_N5: CC1815.1 WLAN1.29
PCIE_PTX_C_WLANRX_P5: CC1816.1 WLAN1.27
PCIE_PTX_LANRX_N6: CC135.2 UC1.D20
PCIE_PTX_LANRX_P6: CC136.2 UC1.C20
PCIE_PTX_WLANRX_N5: CC1815.2 UC1.C19
PCIE_PTX_WLANRX_P5: CC1816.2 UC1.D19
PCIE_RCOMPN: RC45.1 UC1.F5
PCIE_RCOMPP: RC45.2 UC1.E5
PCIE_WAKE#: RC395.1 RE354.2 RL1.2 UE1.4
PECI_EC: RE353.2 UC1.A54
PECI_MEC1404: RE353.1 UE1.94
PHASE_CHG: PC721.2 PL700.1 PQ704.1 PQ704.2 PQ704.3 PQ708.5 PU703.22
PHASE_ID1: RC372.2 RC373.1 UC1.BA8
PHASE_ID2: RC370.2 RC371.1 UC1.AY8
PLT_RST_NGFF#: R5807.1 WLAN1.44
PM_MSM#: T4949.1(TP-1) UC1.AP56
PM_ZVM#: PR1201.2 UC1.AR56
PME#: T115.1(TP-1) UC1.AU11
POK: CC266.1 PR13.1 PR107.2 PR113.2 PR301.1 PR501.1 PU100.9 PU102.9 RC220.1 RC1139.1 UZ6.2
POWER_SW#_MB: JIO1.30 RE428.2 SW1.3 SW1.4
POWER_SW_IN#: C6218.2 RE31.2 RE428.1 UE1.127
PROG: PR753.2 PU703.9
PROH: PQ720.2 PR777.2 PU703.5
PROJECT_ID: RC376.2 RC377.1 UC1.BA7
PS_ID: PD5.1 PR3.1 PR4.2 UE1.36
PSID: PJPDC1.3 PL2.2
PSID-1: PQ5.2 PR6.1 PR9.2
PSID-2: PQ5.1 PQ6.2 PR8.2 PR11.1
PSID-3: PQ6.3 PR4.1
PTP_DIS#: D3801.1 RE434.1 RE436.1
PTP_DIS#_R: RE434.2 UE1.90
PWM1_GT: PR680.1 PU602.12 PU605.1
PWM2_GT: PR681.1 PU602.13 PU604.1
PWM_IA: PR662.1 PU602.22 PU603.1
PWM_VSA: PU602.30 PU606.3
RESERVE_ID1: RC374.2 RC375.1 UC1.AB3
RESERVE_ID2: RC1128.1 RC1129.2 UC1.AC1
RESET_OUT#: CE82.1 RE367.1 UC1.BA20 UE1.73
RING2: LA10.2 RA1109.1 UA1.17
RING2_R: CA40.1 CA76.1 DA12.2 JHP.4 LA10.1
RJ45_MIDI0+: JRJ45.1 TL1.23
RJ45_MIDI0-: JRJ45.2 TL1.22
RJ45_MIDI1+: JRJ45.3 TL1.20
RJ45_MIDI1-: JRJ45.6 TL1.19
RJ45_MIDI2+: JRJ45.4 TL1.17
RJ45_MIDI2-: JRJ45.5 TL1.16
RJ45_MIDI3+: JRJ45.7 TL1.14
RJ45_MIDI3-: JRJ45.8 TL1.13
RTC_DET#: Q2505.1 RC384.1 UC1.P1
RTC_PWR: D2501.3 Q2505.2 R2502.2 R2504.1
RTCRST_ON: Q1901.2 R1902.1 UE1.31
RUNPWROK: RE438.1 UE1.48
SA_SNUB: PC622.1 PR627.2
SA_SW: PL601.4 PQ601.9 PR619.2 PR627.1 PU606.8
SATA3_PRX_C_SSDTX_N2: CHD2.2 JSSD1.43
SATA3_PRX_C_SSDTX_P2: CHD1.2 JSSD1.41
SATA3_PRX_HDDTX_N0: CS33.1 UC1.F20
SATA3_PRX_HDDTX_P0: CS35.1 UC1.E20
SATA3_PRX_SSDTX_N2: CHD2.1 UC1.E30
SATA3_PRX_SSDTX_P2: CHD1.1 UC1.F30
SATA3_PTX_C_SSDRX_N2: CHD3.2 JSSD1.47
SATA3_PTX_C_SSDRX_P2: CHD4.2 JSSD1.49
SATA3_PTX_HDDRX_N0: CS36.1 UC1.B21
SATA3_PTX_HDDRX_P0: CS37.1 UC1.A21
SATA3_PTX_SSDRX_N2: CHD3.1 UC1.A25
SATA3_PTX_SSDRX_P2: CHD4.1 UC1.B25
SATA_ARX_RC_DTX_N0: CS31.1 US2.12
SATA_ARX_RC_DTX_N0_C: CS31.2 HDD1.8
SATA_ARX_RC_DTX_P0: CS34.1 US2.11
SATA_ARX_RC_DTX_P0_C: CS34.2 HDD1.7
SATA_ATX_RC_DRX_N0: CS32.1 US2.14
SATA_ATX_RC_DRX_N0_C: CS32.2 HDD1.10
SATA_ATX_RC_DRX_P0: CS30.1 US2.15
SATA_ATX_RC_DRX_P0_C: CS30.2 HDD1.11
SATA_CRX_C_DTX_N0: CS33.2 US2.4
SATA_CRX_C_DTX_P0: CS35.2 US2.5
SATA_CTX_C_DRX_N0: CS36.2 US2.2
SATA_CTX_C_DRX_P0: CS37.2 US2.1
SATA_LED#: Q6105.3 R2405.1 RC248.1 UC1.H1
SATA_LED_EN: Q6105.2 R2405.2 R6110.2 UE1.30
SD_RCOMP: RC96.1 UC1.AB7
SDVO_SCLK: QX4.1 RC175.1 UC1.L13
SDVO_SDATA: QX4.4 RC178.1 UC1.L12
SERIRQ: RC21.2 RZ126.1 UC1.AY11 UE1.55
SIO_EXT_SCI#: RC237.1 UC1.J2 UE1.66
SIO_EXT_SMI#: RC239.2 UC1.L6 UE1.10
SIO_EXT_WAKE#: RC387.1 UC1.AD3 UE1.116
SIO_PWRBTN#: RC1102.2 UC1.BA15 UE1.52
SIO_RCIN#: RC13.2 UC1.AW13 UE1.53
SIO_SLP_A#: T4975.1(TP-1) UC1.AN16
SIO_SLP_LAN#: RC68.1 T4938.1(TP-1) UC1.AW15
SIO_SLP_S0#: RZ116.1 UC1.AT11 UC15.2
SIO_SLP_S3#: CE74.1 DZ1702.1 PR1204.2 RC130.1 UC1.AP15 UC15.1 UE1.23 UZ2.3 UZ2.5
SIO_SLP_S4#: DZ1703.1 PR201.1 PR803.1 RZ1701.1 UC1.BA16 UE1.67
SIO_SLP_S5#: PQ711.2 UC1.AY16
SIO_SLP_SUS#: RC76.2 RC1137.1 UE1.96
SIO_SLP_SUS#_R: RC76.1 UC1.AN15
SIO_SLP_WLAN#: T4945.1(TP-1) UC1.BB17
SLEEVE: LA7.2 RA53.1 UA1.18
SM_RCOMP0: RC5.1 UC1.AR18
SM_RCOMP1: RC6.1 UC1.AT18
SM_RCOMP2: RC7.1 UC1.AU18
SMBCLK: QC2.6 RC12.1 UC1.R7
SMBDATA: QC2.3 RC14.1 UC1.R8
SML0_SMBCLK: RC19.1 UC1.R9
SML0_SMBDATA: RC20.1 UC1.W2
SML1CLK: RC15.1 RC399.1 UC1.W3
SML1DATA: RC17.1 RC397.1 UC1.V3
SNUB_+1VALW: PC308.1 PR307.2
SOC_DP2_AUXN: JIO1.2 UC1.E48
SOC_DP2_AUXP: JIO1.1 UC1.F48
SOC_DP2_N0: JIO1.5 UC1.C50
SOC_DP2_N1: JIO1.8 UC1.C52
SOC_DP2_P0: JIO1.4 UC1.D50
SOC_DP2_P1: JIO1.7 UC1.D52
SOC_XDP_TDI: RPC1.7 T111.1(TP-1) UC1.D59 UC1.D60
SOC_XDP_TDO: RPC1.6 T118.1(TP-1) UC1.A56 UC1.A61
SOC_XDP_TMS: RPC1.8 T112.1(TP-1) UC1.C59 UC1.C60
SOC_XDP_TRST#: T110.1(TP-1) UC1.B59 UC1.C61
SPK_L1-_CONN: CA30.1 DA13.3 JSPK.3 LA5.2
SPK_L2+_CONN: CA29.1 DA13.2 JSPK.4 LA6.2
SPK_R1-_CONN: CA32.1 DA14.3 JSPK.1 LA3.2
SPK_R2+_CONN: CA31.1 DA14.2 JSPK.2 LA4.2
SPKR: DA8.3 RC183.2 UC1.AW5
SRTCRST#: CC24.1 RC56.1 UC1.AN18
SSD_DEVSLP: R6526.2 UC1.J3
SUS_STAT#/LPCPD#: RC1127.1 UC1.BA11
SUSACK#: RE449.2 UE1.34
SUSCLK: R6518.2 RC48.1 RE368.2 UC1.BA17
SUSCLK_R: R6518.1 WLAN1.42
SW_VCCEOPIO: PC1201.2 PL1201.1 PR1208.1 PU1200.8
SYS_PWROK: UC1.B6 UE1.89
SYS_RESET#: CC1807.1 RC291.2 UC1.B5
T_CRIT#: R2604.2 THM26.4
THM_SML1_CLK: C2608.1 Q2601.4 RE432.2 THM26.8
THM_SML1_DATA: C2609.1 Q2601.1 RE32.2 THM26.7
TON_1.2V: PR208.2 PU200.9
TOUCH_SCREEN_PD#: D5203.2 R5205.2 RC277.2 RC394.1
TOUCH_SCREEN_PD#_R: RC394.2 UC1.A7
TOUCHPAD_INTR#: DZ3.1 Q6204.1 RE440.1 UE1.33
TOUCHPAD_INTR#_D: DZ3.2 RC272.2 UC1.BA5
TP_LOCK#: D3801.2 R6505.2 TPAD1.3
TP_ON#_GATE: C6204.2 Q2405.2 Q6203.2 R6214.2
TP_PW_EN#: R6214.1 UE1.49
TP_RESET: JEDP.25 R5212.1
TP_RS: JEDP.24 R5205.1
TPM_ID: RC1130.2 RC1131.1 UC1.AC2
TPM_LPM#: QZ11.1 RZ119.1 UZ13.6
UART_2_CRXD_DTXD: JWDB1.2 RC62.1 UC1.AD1
UART_2_CTXD_DRXD: JWDB1.3 RC63.1 UC1.AD2
UG_1.2V: PQ201.1 PU200.17
UGATE_CHG: PR761.1 PU703.23
UL1_RSET_P31: RL5.2 UL1.31
USB2_ID: RC366.1 UC1.AG3
USB2_VBUSSENSE: RC393.1 UC1.AG4
USB3_CRX_DTX_N1: R3411.2 UC1.H8
USB3_CRX_DTX_N1_C: JUSB1.5 R3411.1 U3402.1 U3402.9
USB3_CRX_DTX_N2: R3417.2 UC1.J6
USB3_CRX_DTX_N2_C: JUSB2.5 R3417.1 U3403.1 U3403.9
USB3_CRX_DTX_N3: JIO1.10 UC1.J10
USB3_CRX_DTX_P1: R3410.2 UC1.G8
USB3_CRX_DTX_P1_C: JUSB1.6 R3410.1 U3402.2 U3402.8
USB3_CRX_DTX_P2: R3418.2 UC1.H6
USB3_CRX_DTX_P2_C: JUSB2.6 R3418.1 U3403.2 U3403.8
USB3_CRX_DTX_P3: JIO1.11 UC1.H10
USB3_CTX_DRX_N1: C3403.1 UC1.C13
USB3_CTX_DRX_N1_C: JUSB1.8 R3409.1 U3402.4 U3402.7
USB3_CTX_DRX_N1_R: C3403.2 R3409.2
USB3_CTX_DRX_N2: C3406.1 UC1.B13
USB3_CTX_DRX_N2_C: JUSB2.8 R3419.1 U3403.4 U3403.7
USB3_CTX_DRX_N2_R: C3406.2 R3419.2
USB3_CTX_DRX_N3: JIO1.13 UC1.B15
USB3_CTX_DRX_P1: C3404.1 UC1.D13
USB3_CTX_DRX_P1_C: JUSB1.9 R3408.1 U3402.5 U3402.6
USB3_CTX_DRX_P1_R: C3404.2 R3408.2
USB3_CTX_DRX_P2: C3405.1 UC1.A13
USB3_CTX_DRX_P2_C: JUSB2.9 R3416.1 U3403.5 U3403.6
USB3_CTX_DRX_P2_R: C3405.2 R3416.2
USB3_CTX_DRX_P3: JIO1.14 UC1.A15
USB_EN#: RE388.1 U3504.4 U3505.4 UE1.13
USB_OC#0: RPC3.3 U3504.3 UC1.A9 UUS5.13
USB_OC#1: RPC3.2 U3505.3 UC1.C9
USB_OC#2: RPC3.1 UC1.D9
USB_OC#3: RPC3.4 UC1.B9
USB_PN1: UC1.AB9 UUS5.2
USB_PN1_CHR: TR3404.2 UUS5.11
USB_PN1_CHR_C: EU3403.3 JUSB1.2 TR3404.1
USB_PN2: TR3405.2 UC1.AD6
USB_PN2_C: EU3404.2 JUSB2.2 TR3405.1
USB_PN3: TR3406.2 UC1.AH3
USB_PN3_C: JIO1.32 TR3406.1
USB_PN4: TR5802.2 UC1.AD9
USB_PN4_C: JIO2.2 TR5802.1
USB_PN5: TR5209.2 UC1.AJ1
USB_PN5_C: EU3405.4 EU3405.7 JEDP.31 TR5209.1
USB_PN6: TR5803.2 UC1.AF6
USB_PN6_C: JIO1.35 TR5803.1
USB_PN7: TR5201.2 UC1.AH1
USB_PN7_C: JEDP.22 TR5201.1
USB_PN8: UC1.AF8 WLAN1.5
USB_PN9: TR5804.2 UC1.AG1
USB_PN9_C: JIO1.38 TR5804.1
USB_POWERSHARE_VBUS_EN: R6532.1 RE448.1 UUS5.5
USB_PP1: UC1.AB10 UUS5.3
USB_PP1_CHR: TR3404.3 UUS5.10
USB_PP1_CHR_C: EU3403.2 JUSB1.3 TR3404.4
USB_PP2: TR3405.3 UC1.AD7
USB_PP2_C: EU3404.3 JUSB2.3 TR3405.4
USB_PP3: TR3406.3 UC1.AJ3
USB_PP3_C: JIO1.33 TR3406.4
USB_PP4: TR5802.3 UC1.AD10
USB_PP4_C: JIO2.3 TR5802.4
USB_PP5: TR5209.3 UC1.AJ2
USB_PP5_C: EU3405.5 EU3405.6 JEDP.32 TR5209.4
USB_PP6: TR5803.3 UC1.AF7
USB_PP6_C: JIO1.36 TR5803.4
USB_PP7: TR5201.3 UC1.AH2
USB_PP7_C: JEDP.21 TR5201.4
USB_PP8: UC1.AF9 WLAN1.3
USB_PP9: TR5804.3 UC1.AG2
USB_PP9_C: JIO1.39 TR5804.4
USB_PWR_SHR_EN_L#: RE449.1 RUS29.1
USBCHG_DET#: R6531.1 RE437.1 UE1.126
USBCOMP: RC44.1 UC1.AB6
UUS5_CTL1: RUS29.2 UUS5.6
UUS5_ILIM_H: RUS27.1 UUS5.16
UUS5_ILIM_L: RUS26.1 UUS5.15
VCIN0_PH: C2612.1 C2613.1 R2608.2 R2609.2 R2610.1 RE394.1
VCREF0: CE91.1 RE396.2 RE397.1 UE1.25
VD_IN1_C: C2612.2 C2613.2 R2610.2 R2611.1
VIDALERT_N: PR607.1 RC152.2 RC153.2
VIDSCLK: PR606.1 UC1.A63
VIDSOUT: PR609.1 RC157.2 UC1.D64
VL: PC126.1 PU102.15
VR_ALERT#: PR625.2 PU602.36
VR_CAP: C5224.1 T4931.1(TP-1) UE1.18
VR_SCLK: PR618.2 PU602.37
VR_SDA: PR626.2 PU602.35
VRALERT#: RC73.1 UC1.AM11
VRAM_ID1: RC1104.2 RC1105.1 UC1.AP8
VRAM_ID2: RC1106.2 RC1107.1 UC1.AW7
VSA_SEN+: PC640.2 PC650.1 PC652.1 PR649.2 RC168.2 UC1.H20
VSA_SEN-: PC649.1 PC650.2 PU602.26 RC166.1 UC1.H21
VTTREF_1.2V: PC210.1 PU200.4
WLAN_RADIO_DIS#: RE439.1 UC1.B7 WLAN1.48
XCLK_BIASREF: RC52.1 UC1.E42
XDP_HOOK0: RC158.2 T121.1(TP-1)
XDP_ITP_PMODE: RC115.1 RC353.2 T125.1(TP-1) UC1.E8
XDP_OBS0_R: T4942.1(TP-1) UC1.C55
XDP_OBS1_R: T4941.1(TP-1) UC1.D55
XDP_OBS2_R: T10.1(TP-1) UC1.B54
XDP_OBS3_R: T11.1(TP-1) UC1.C56
XDP_PRDY#: T120.1(TP-1) UC1.D56
XDP_PREQ#: T119.1(TP-1) UC1.D61
XDP_SPI_IO2: RC347.1 RC354.1 T131.1(TP-1)
XDP_SPI_SI: RC9.2 RC355.1 T124.1(TP-1)
XTAL24_IN: CC21.1 RC46.2 UC1.E37 YC1.3
XTAL24_OUT: CC22.1 RC46.1 UC1.E35 YC1.1
N16662348: CA23.2 UA1.28
N17298963: PC640.1 PR646.2
N17298971: PC601.1 PR652.2
N17298982: PC632.1 PR636.1 PU602.28
N17298983: PC632.2 PR641.1
N17298992: PH604.1 PR642.2
N17299006: PR604.2 PR607.2 PR625.1
N17299007: PR601.2 PR606.2 PR618.1
N17299016: PR605.2 PR609.2 PR626.1
N17299020: PR616.2 PU602.40
N17299022: PR612.2 PU602.39
N17299031: PR678.2 PU602.38
N17299032: PC603.1 PR602.1 PU602.34
N17299033: PC604.1 PR603.1 PU602.33
N17299046: PR608.1 PU602.32
N17299048: PR611.1 PU602.31
N17299099: PC630.1 PR640.1 PU602.20
N17299117: PH605.1 PR657.2
N17299153: PC639.2 PR645.1
N17299162: PC647.2 PR650.2
N17299166: PC629.2 PR639.1
N17299193: PC627.1 PR632.2
N17299198: PH602.1 PR628.2
N17299204: PC627.2 PR638.2 PU602.8
N17299248: PC621.2 PR623.1
N17299249: PR621.2 PR622.2 PR623.2 PU602.5
N17299259: PC616.2 PR617.2 PU602.4
N17299260: PC614.2 PR617.1
N17299268: PR610.2 PU602.3
N17299272: PC613.2 PR613.2 PU602.2
N17299296: PC617.2 PR621.1
N17299297: PC631.1 PR630.2
N17299304: PC630.2 PR644.1
N17299307: PC611.2 PU606.2
N17299308: PC611.1 PR619.1
N17299330: PH601.2 PR610.1 PR631.2
N17299350: PH603.2 PR635.1 PR647.2
N17299365: PQ601.8 PU606.5
N17299369: PQ601.1 PU606.1
N17299387: PR679.2 PU606.7
N17301560: PL603.3 PR661.1
N17301607: PR672.2 PU605.3
N17301608: PC671.1 PR672.1
N17301618: PR660.2 PU603.3
N17301619: PC655.1 PR660.1
N17301744: PR671.2 PU605.2
N17312499: PL601.3 PR624.1
N17415515: PJPDC1.1 PJPDC1.2 PL4.1
N17481633: PC705.1 PC760.1 PC762.1 PC763.1 PC764.1 PC765.1 PJP701.2 PL704.2 PQ704.5
N18390627: PQ710.2 PQ711.1
N20173493: RE356.1 RE358.1 UE1.120
N23700319: PD4.2 PL2.1 PQ6.1 PR6.2
N27266810: PC742.1 PC744.1 PQ709.6 PQ718.4 PR762.1 PR778.2
N27286345: PD704.1 PR743.2
N28103940: CA68.2 RA82.1
N28103942: CA67.2 RA80.1
N28204071: CA65.2 CA69.1 RA79.1 RA81.2
N28424999: T113.1(TP-1) UC1.AW71
N28425002: T114.1(TP-1) UC1.AW70
N28483977: PQ1.2 PR2.1 PR12.2 PR13.2
N28483985: PQ1.3 PR5.2
N28484391: PC16.1 PQ2.3 PR28.2
N28484395: PC16.2 PQ2.2 PR29.1
N28484412: PQ2.5 PR31.1 PR33.2
N28484439: PC14.2 PQ3.2 PR32.1
N28484451: PQ1.5 PQ1.6 PR7.1 PR10.2
N28714500: PR769.2 PU703.3
N28714504: PR770.2 PU703.4
N28714507: PC744.2 PQ709.1 PQ718.1 PQ718.2 PQ718.3 PQ740.1 PQ740.2 PQ740.3 PQ741.1 PQ741.2 PQ741.3 PR737.1 PR763.1
N28714524: PC750.1 PU703.27
N28714534: PC752.2 PR754.1
N28714559: PR774.2 PU703.6
N28714562: PR775.2 PU703.7
N28714564: PC721.1 PR771.2
N28714572: PC757.2 PR743.1 PU703.18
N28714582: PR755.2 PU703.12
N28714583: PC708.1 PR776.1 PU703.14
N28714585: PC708.2 PR742.1 PU703.15
N28714598: PC747.1 PR740.2 PU703.31
N28714599: PC747.2 PR772.2 PU703.32
N28714601: PC750.2 PU703.28
N28714604: PR773.1 PU703.25
N28714606: PQ704.4 PR761.2
N28714608: PR745.1 PU703.26
N28714612: PR771.1 PU703.24
N28714614: PR757.2 PU703.17
N28714617: PQ718.5 PR703.1
N28714625: PR757.1 PR779.2
N28714693: PC779.1 PL700.2 PQ717.1 PQ717.2 PQ717.3 PR765.1
N28714721: PR742.2 PR765.2
N28714724: PR765.3 PR776.2
N28714743: PQ709.2 PR737.2 PR738.1
N28714752: PR703.2 PR772.1
N28714753: PR703.3 PR740.1
N28714793: PC779.2 PQ717.4 PR773.2
N28716223: PC663.2 PU604.5
N28716225: PR665.2 PU604.3
N28716227: PC663.1 PR665.1
N28810503: CZ45.1 UZ2.12
N28810563: CZ23.1 UZ2.10
N28842863: CC204.1 UC1.AL1
N28843886: CC214.1 UC1.BB10
N28856399: T16.1(TP-1) UC1.BA70
N28856402: T17.1(TP-1) UC1.BA68
N28857231: T12.1(TP-1) UC1.BB68
N28857234: T13.1(TP-1) UC1.BB69
N28857237: T14.1(TP-1) UC1.AK13
N28857240: T15.1(TP-1) UC1.AK12
N28861827: RC120.1 UC1.C64
N29189918: PR764.2 PU703.13
N29708559: T126.1(TP-1) UC1.AY4
N29708561: T127.1(TP-1) UC1.BB3
N29708599: T128.1(TP-1) UC1.AU5
N29708601: T129.1(TP-1) UC1.AT5
N29708639: T130.1(TP-1) UC1.BB5
N32777150: PR664.1 PU604.2
N32842463: RC361.2 UC1.U11 UC1.U12
N33124395: PC204.2 PR210.1 PU200.12
N33124472: PC207.1 PR203.2
N34661441: JDEG1.9 RE74.2
N34661623: JDEG1.1 RE71.2
N36085760: PD6.1 PR11.2
N39282118: PC501.1 PJP501.2 PU500.8 PU500.9 PU500.10
N39282176: PC504.1 PR506.2
N39282188: PR503.1 PR504.2
N39732053: RZ65.1 RZ126.2 UZ13.27
N39732069: QZ11.2 RZ120.2
N39734476: RZ121.2 UZ13.20
N39734479: RZ122.2 UZ13.17
N39736574: RZ117.1 UZ13.5
N39737552: RZ116.2 UZ13.1
N39880170: PR1202.2 PU1200.7
N39880453: PC1209.1 PR1208.2
N40598435: PC102.1 PR100.2
N40598492: PC119.1 PU102.16 PU102.17
N40598500: PC114.1 PR111.2
N40598503: PC113.2 PR108.1
N40598539: PC127.2 PR117.1
N40598592: PC128.1 PD102.2 PQ102.1 PR114.2 PR120.2 PR121.2 PR122.1
N40598619: PD102.1 PQ102.3 PR116.2
N40605947: PC305.1 PR303.2 PU300.15
N40606056: PR308.1 PR309.2
N40638141: CL43.1 RL19.2 RL20.2 RL21.2 RL22.2
N40638178: JSSD1.61 T4973.1(TP-1)
N40638747: PC790.1 PQ721.2 PR790.2
N40641471: PQ720.1 PR790.1 PR791.2
N40740280: RL23.2 UL1.24
N40862903: RS19.2 US2.7
N40862946: RS25.2 US2.10
N40863062: RS20.2 RS22.2 US2.18
N40870793: CHO8.2 RHO9.2
N40871013: CHO10.2 RHO11.2
N40871311: CHO9.2 RHO10.2
N40871582: CHO11.2 RHO12.2
N40969705: D5204.1 F6202.2
N41096148: CZ70.1 UZ21.6
N41096439: Q6205.3 R6511.2 R6529.2
N41121585: CC93.2 DZ1702.2 RC130.2 UC13.2
N41122944: RC60.2 RPC5.5
N41123043: RC61.1 RC1120.2
N41149073: QC5.2 QC5.3 RS39.2
N41335354: R3022.2 UL3.3
N41378522: PBATT1.5 PR15.1
N41421024: RE422.1 T4932.1(TP-1)
N41548189: RZ1709.1 UZ13.7
N41548228: RZ1708.2 UZ13.15
N41548319: RZ1707.2 UZ13.28
N41715557: C6220.2 JUSB1.10 R6531.2
N41825015: RC1134.2 UC1.G61
N41863697: QX5.2 RX15.1
N41863897: DX4.3 RHR11.2
N41863899: DX4.2 RHR8.2
N41864735: QX6.1 RP58.5 RP58.6 RP58.7 RP58.8 RP59.5 RP59.6 RP59.7 RP59.8
N41865724: PR655.2 PU603.14
N41866336: PC655.2 PU603.5
N41866349: PR659.2 PU603.2
N41866816: C229.2 CL46.2 TL1.1 TL1.4 TL1.7 TL1.10
N41870308: PC671.2 PU605.5
N41918231: T4977.1(TP-1) UL1.26
N41918233: T4976.1(TP-1) UL1.25
N41918243: T4978.1(TP-1) UL1.27
N42060658: Q2405.1 R6211.2
N42923938: PR620.2 PU602.1
N124752685: CH101.2 RH211.1
N124753277: CH100.2 RH212.1

Pads without a net: FD1 1; FD2 1; FD3 1; FD4 1; JDIMM1 87 88 91 92 95 97 100 101 104 105 134 162 165; JDIMM2 87 88 91 92 95 96 97 100 101 104 105 134 162 165; JEDP 36; JHDMI 13 14; JIO1 15; JKB 2 3; JKBBL 3; JRJ45 12; JSSD1 5 6 7 8 9 10 11 12 13 14 15 16 17 18 19 20 21 22 23 24 25 26 28 29 30 31 32 34 35 36 37 40 42 44 46 48 50 52 53 54 55 56 58 59 60; PD3 3; PD4 3; PJPDC1 4; PU100 10 15; PU102 10; PU300 9 10 12; PU500 1 4 7; PU603 4 9 10 13; PU604 4 9 10 13; PU605 4 9 10 13; PU800 1 5; PU1200 13; RN5201 4 5; RN5203 4 5; UA1 4 12 14 15 23 24 48; UC1 A3 A4 A6 A11 A17 A19 A23 A26 A27 A29 A31 A33 A36 A38 A40 A45 A47 A50 A52 A65 A69 AB1 AB4 AB11 AB12 AB13 AC3 AD11 AD12 AF11 AF12 AF13 AH7 AH8 AH9 AH10 AH11 AH12 AK6 AK7 AK9 AK10 AL25 AL27 AM1 AM2 AM3 AM4 AN1 AN2 AN3 AN5 AN7 AN8 AP1 AP2 AP3 AP4 AP5 AP7 AP11 AP13 AR10 AT10 AT15 AU2 AU7 AU8 AU56 AW1 AW9 AW17 AW20 AW48 AW56 AW68 AW69 AY1 AY2 AY5 AY7 AY20 AY21 AY56 AY68 B2 B3 B11 B17 B19 B23 B26 B27 B29 B31 B33 B36 B38 B40 B45 B47 B50 B52 B69 B70 BA3 BA4 BA9 BB2 BB4 BB9 C2 C4 C7 C8 C11 C12 C15 C16 C17 C21 C23 C24 C27 C28 C29 C31 C32 C33 C36 C37 C38 C40 C42 C51 C54 C70 C71 D1 D3 D4 D5 D7 D8 D12 D15 D16 D17 D21 D23 D24 D27 D28 D29 D31 D32 D33 D36 D37 D38 D40 D42 D51 D54 D71 E1 E2 E3 E10 E22 E23 E25 E27 E28 E38 E40 E61 F6 F10 F11 F15 F21 F25 F46 F50 F52 F60 F61 F65 G1 G2 G3 G4 G11 G13 G15 G16 G21 G46 G50 G65 H2 H3 H5 H11 H13 H16 J5 J68 J71 K45 K46 M1 M2 M3 M4 N1 N2 N3 N7 N9 N11 N12 P2 P3 U1 U2 U3 U4 U8 U9 V1 V2 W4 W7 W10 W11 W12; UC12 1; UC13 1; UC14 1; UE6 1; UUS5 9; UZ13 2 3 8 9 12 13 14; WLAN1 6 8 9 11 12 13 14 15 16 17 19 20 21 22 23 24 26 28 32 34 40 47 50 51 52 53 54 56 57 59 60 62 63 65; YC1 2 4; YL1 2 4

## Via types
v1: diameter 0.305, hole 0.152, TOP to BOTTOM, 549 vias
v2: diameter 0.457, hole 0.203, TOP to BOTTOM, 4697 vias
v3: diameter 0.508, hole 0.254, TOP to BOTTOM, 45 vias
v4: diameter 0.406, hole 0.203, TOP to BOTTOM, 158 vias

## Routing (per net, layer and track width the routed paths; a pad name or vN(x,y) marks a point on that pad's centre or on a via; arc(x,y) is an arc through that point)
0.6V_DDR_VTT_ON: length 59.2
  TOP w0.102: UC14.4 105.22,86.88 RC123.2 104.74,87.35 104.74,87.69 v1(101.53,90.9) 99.53,92.9 68.38,92.9 61.54,99.74 v2(61.54,103.23) ; PR202.1 v2(63.82,106.74)
  BOTTOM w0.102: v2(63.82,106.74) 61.54,104.45 v2(61.54,103.23)
1.2V_VTT_PWRGD: length 196.8
  TOP w0.102: v1(63.39,100.93) 63.87,100.93 64.37,101.43 v2(64.44,101.43) 64.61,101.43 PR209.2 ; RC392.1 CC1822.1 110.14,11.09 v2(110.14,10.7)
  TOP w0.254: PU200.10 66.45,102.87 65.75,102.17 PR209.2
  IN2 w0.127: v2(64.44,101.43) 64.44,101.76 63.97,102.23 60.13,102.23 54.36,96.46 54.36,93.28 47.88,86.8 40.39,86.8 36.25,82.66 36.25,74.8 33.42,71.97 33.42,66 34.2,65.21 34.2,60.09 33.11,59 33.11,57.44 34.52,56.03 38.25,56.03 39.4,54.89 39.4,52.72 37.44,50.76 37.44,46.75 37.04,46.34 37.04,44 37.34,43.7 37.34,42.91 36.58,42.15 36.58,40.79 38.41,38.96 38.41,37.87 39.14,37.14 40.14,37.14 41.31,35.97 43,35.97 43.31,35.67 43.31,34.3 43.08,34.07 42.27,34.07 41.71,33.51 41.71,31.96 44.15,29.52 44.15,23.55 45.29,22.41 45.29,19.34 44.96,19.01 44.96,18.3 46,17.25 47.12,17.25 51.01,13.37 52.02,13.37 52.53,12.86 52.53,12.63 52.82,12.34 56.47,12.34 59.05,9.76 62.8,9.76 63.86,10.82 71.91,10.82 72.07,10.65 83.21,10.65 84.41,11.86 87.53,11.86 88.68,13.01 92.94,13.01 93.71,12.24 95.98,12.24 97.98,10.24 109.67,10.24 v2(110.14,10.7)
2.5V_VIN: length 1.9
  TOP w0.127: PC802.1 v4(73.05,13.24)
  vias: v2(71.73,10.4) v2(72.06,9.86)
3V_FB: length 4.7
  BOTTOM w0.102: PC113.1 185.23,82.02 v1(185.85,82.64)
  BOTTOM w0.254: PU100.13 184.56,79.49 184.79,79.73 PR109.2 PR110.1 PC113.1
3V_SN: length 3.3
  TOP w0.102: PR106.2 v1(179.21,80.13)
  TOP w0.635: PC112.1 181.58,80.7 PR106.2
3V_VIN:
  vias: v1(178.48,81.82) v2(179.23,83.24) v2(179.23,82.61)
5V_FB: length 4.6
  BOTTOM w0.102: PC127.1 v1(196.38,82.61)
  BOTTOM w0.254: PC127.1 PR118.1 PR115.2 195.74,79.62 195.53,79.42 PU102.13
5V_HDD: length 13.9
  TOP w0.127: v2(204.63,14.66) 204.88,14.66 v4(205.45,14.09) ; v2(203.36,14.66) v4(202.17,14.66) ; v2(203.99,14.66) v4(203.99,15.22)
  IN2 w1.524: 204.93,13.44 206.89,11.49 210.99,11.49 212.2,10.28
  BOTTOM w0.508: R5601.1 200.84,15.46 200.55,15.76 RS1.1
  vias: v2(212.74,9.28) v2(213.38,9.28) v2(214.01,9.28)
5V_SN:
  vias: v1(191.67,79.83)
5V_VIN: length 0.7
  TOP w0.102: v2(189.77,83.12) v1(189.08,83.12)
  vias: v2(189.77,82.48)
+0.6V_DDR_VTT: length 120.6
  IN2 w0.762: 59.78,20.38 61.18,20.38 61.69,19.87 64.1,19.87 65.24,18.73 70.58,18.73
  BOTTOM w1.016: 56.54,18.8 55.26,18.8 53.24,20.82 53.24,21.84 51.21,23.87 51.21,32 52.59,33.38 52.59,35.81 49.86,38.54 49.86,41.77 47.81,43.82 47.81,56.41 52.54,61.15 52.54,86.55 54,88.01 56.1,88.01 62.34,94.24 62.34,101.43 65.75,104.85 67.01,104.85 67.33,105.16 73.23,105.16 74.15,106.08
  vias: v2(59.03,19.59) v2(59.62,19.6) v2(70.98,19.61) v2(71.61,19.61) v4(58.7,19.11)
+0.6VSP: length 6
  TOP w0.203: PU200.20 70.55,104.47 70.72,104.63 v2(70.72,106.73) ; PU200.2 69.07,105.83 69.26,106.01 v2(69.26,106.73)
  BOTTOM w0.127: PC205.1 v1(66.67,107.73)
+1.0V_APLL: length 0.5
  BOTTOM w0.254: UC1.V15 v2(126.1,41.67)
  vias: v1(125.25,41.55)
+1.0V_CLK2: length 12.8
  TOP w0.508: RC170.1 CC220.1 141.61,38.69 139.86,40.44 136.2,40.44 133.53,43.11
  BOTTOM w0.254: v2(130.39,44.32) 130.39,44.32 130.17,44.32 UC1.K19
  vias: v1(132.01,42.78)
+1.0V_CLK4: length 5.3
  TOP w0.089: v2(128.64,44.24) 128.6,44.24 128.32,43.96 v1(128.18,43.96)
  TOP w0.254: v2(128.64,44.24) 128.05,44.83 127.54,44.83 127.04,44.33 RC173.1 126.97,44.39 CC226.1
  BOTTOM w0.254: v2(128.64,44.24) 128.64,44.82 UC1.N20
+1.0V_CLK5: length 26.1
  IN1 w0.508: v2(135.77,49.23) 134.99,49.23 133.12,47.37 132.17,47.37
  BOTTOM w0.254: v2(129.48,45.56) 129.48,45.06 UC1.L19
  BOTTOM w0.508: v2(135.77,49.23) 136.78,50.25 140.26,50.25 141.32,51.3 145.06,51.3 145.57,51.81 v1(145.57,52.73) 145.57,56.64 144.94,57.27 142.35,57.27 141.46,58.16 RC52.2
+1.0V_MPHYPLL: length 2.2
  BOTTOM w0.254: UC1.AF20 122.66,45.59 v2(122.75,45.59) 122.43,45.91 UC1.AF21 ; UC1.T19 126.44,44.61 v2(126.12,44.94) 126.44,45.26 UC1.T20
  vias: v2(126.99,42.32) v2(127.83,43.63) v2(127.83,43) v2(127.83,42.33) v2(128.67,41.58) v4(143.54,24.54)
+1.0V_PRIM: length 158.9
  TOP w0.254: v2(34.12,57.46) 33.54,56.88 UE1.95
  TOP w0.508: RC352.1 129.59,33.19 v2(129.59,33.66) 129.25,34 CC203.1 128.45,34.4 127.68,33.63 v2(127.05,33.63) 127.03,33.65 CE77.1 ; v2(135.55,39.43) 139.35,39.43 142,36.77 RC170.2
  IN2 w0.254: v2(34.12,57.46) 34.8,58.15 38.51,58.15 42.32,54.34 42.32,46.74 43.41,45.65 43.41,41.31 47.34,37.38 50.61,37.38 52.4,35.59 52.4,31.6 53.05,30.96 53.05,23.41 52.4,22.77 52.4,18.8 53.19,18.02 56.78,18.02 57.88,16.91 58.31,16.91 59.94,15.28 78.47,15.28 79.37,16.17 80,16.17 82.6,18.78 84.79,18.78 92.48,26.47 93.45,26.47 94.65,27.67 95.65,27.67 96.65,26.66 98.34,26.66 99.93,25.08 100.93,25.08 104.28,21.72 104.28,21.14 107.86,17.56 113.59,17.56 115.59,15.57 118.85,15.57 v2(119.84,16.56)
  BOTTOM w0.203: UC1.A14 135,41.67 135.63,41.67 135.97,41.33 v2(136.24,41.33) ; v2(127.05,33.63) 127.16,33.74 UC1.T1 ; v2(135.55,39.43) 135.33,39.21 UC1.A10
  BOTTOM w0.254: UC1.AF19 122.38,44.61 v2(122.72,44.95) ; UC1.P18 127.29,43.96 v2(126.98,43.66) ; UC1.L1 129.81,33.89 v2(129.59,33.66) ; UC1.AB19 124.12,44.61 v2(124.41,44.32) 124.49,44.32 UC1.Y18 v2(124.43,43.64) UC1.AB17 ; UC1.V21 v2(126.1,46.16) ; UC1.AF18 122.38,43.96 v2(122.72,44.3) ; v2(124.43,45.59) 124.33,45.59 124.29,45.55 UC1.AB20 ; v2(128.63,46.4) 129.04,45.99 UC1.L21 ; UC1.V20 v2(126.12,45.57) ; UC1.AK20 120.12,45.57 v2(120.23,45.57) ; UC1.K17 129.44,43.75 v2(129.44,44.27)
  vias: v2(115.54,32.63) v2(115.55,32.04) v2(115.55,31.4) v2(116.19,32.62) v2(116.19,32.04) v2(116.19,31.4) v2(146.84,19.36) v2(146.84,18.73) v2(147.51,19.36) v2(147.51,18.73) v2(148.21,19.36) v2(148.21,18.73) v2(148.91,19.36) v2(148.91,18.73) v2(149.61,19.36) v2(149.61,18.73) v2(150.32,19.36) v2(150.32,18.73) v4(152.05,19.24)
+1.0V_VCCST: length 96.4
  IN1 w1.016: 142.69,73.49 144.07,72.11 152.67,72.11 155.83,68.94 155.83,63.74 158.39,61.18
  IN3 w1.016: 136.01,50.22 136.74,49.49 136.74,47.39 136.1,46.74 136.1,45.14 136.43,44.81 ; 164.18,60.08 168.13,60.08 171.87,56.33 174.5,56.33 175.67,55.16 175.67,51.89 177.61,49.94 178.39,49.94 179.04,49.3 179.04,43.47 179.84,42.67 179.84,27.38 176.76,24.3 176.76,23.64 ; 140.79,59.97 136.58,55.76 136.58,53.56 136.01,52.99
  BOTTOM w1.016: 176.75,21.94 176.75,21.75 172.36,17.36 169.79,17.36
  vias: v2(130.4,45.26) v2(136.43,43.87) v2(141.43,73.99) v2(141.47,67.24) v2(141.75,73.48) v2(142.01,67.48) v2(161.9,60.21) v2(162.3,60.64) v2(168.94,16.63) v2(169.56,16.63) v2(176.44,22.79) v2(177.03,22.79) v4(167.48,15.54)
+1.0V_VCCST_C: length 1.1
  TOP w0.102: RZ1704.2 v1(164.16,16.85)
+1.0V_VCCSTG: length 95.6
  TOP w0.102: v4(167.08,17.27) RZ1703.2
  TOP w0.508: RZ1703.2 v2(167.08,19.36)
  IN1 w0.254: v2(131.58,45.21) 131.58,45.38 132.24,46.04 132.24,46.27 132.62,46.64 133.34,46.64 135.41,48.71 137.3,48.71 v2(137.69,49.1)
  IN2 w0.508: 134.47,43.57 135.16,43.57 135.54,43.19 136.59,43.19 141.71,38.07 143.77,38.07 144.21,37.63 144.21,36.47 143.4,35.66 143.4,34.8 141.27,32.67 141.27,27.79 140.25,26.77 140.25,21.94 141.29,20.9 144.92,20.9 145.72,20.1 v2(155.07,20.1)
  IN3 w0.254: v2(137.69,49.1) 137.69,49.73 136.86,50.57 136.86,52.54 137.82,53.51 137.82,54.13 139.94,56.25 139.94,57.5 140.73,58.29 141.98,58.29 144.2,60.5 144.2,67.34 v2(144.33,67.47)
  BOTTOM w0.254: UC1.G20 131.58,45.07 v2(131.58,45.21) ; UC1.A22 136.18,46.65 CC199.1 138,48.79 v2(137.69,49.1)
  BOTTOM w0.508: v2(155.07,20.1) 155.69,20.72 165.73,20.72 v2(167.08,19.36)
+1.0V_VCCSTG_C:
  vias: v1(163.83,18.28)
+1.0V_XDP: length 3.9
  TOP w0.089: v1(132.71,32.7) RC352.2
  TOP w0.508: RC115.2 RC353.1 131.54,32.76 RC352.2
+1.0VS_VCCIO: length 22
  IN2 w0.254: v2(120.24,57.12) 120.24,57.11
  IN2 w0.305: v2(120.24,57.12) 121.66,58.54 131.11,58.54 131.17,58.48 134.19,58.48 138.49,62.78 v2(139.08,62.78)
  BOTTOM w0.254: v2(139.08,62.78) 138.55,62.78 RC2.1
  vias: v2(118.77,57.97) v2(118.72,51.63) v2(118.86,50.71) v2(120.47,51) v2(120.47,50.42) v2(153.56,22.73) v2(154.23,22.73) v2(154.89,23.38) v2(154.89,22.74) v2(155.53,23.38) v2(155.53,22.74) v2(156.16,23.38) v2(156.16,22.74) v4(172.15,22.72)
+1.0VS_VCCOPC: length 2.9
  TOP w0.089: 122.84,67.77 123.19,67.77
  BOTTOM w0.254: v2(127.8,69.62) UC1.P62 127.8,68.79 v2(128.19,68.4) ; UC1.V62 125.97,68.79 v2(126.35,68.41) ; UC1.AB62 124.14,68.82 v2(124.55,68.41)
  vias: v2(120.68,98.93) v2(120.68,98.29) v2(120.93,67.97) v2(121.31,98.93) v2(121.31,98.29) v2(121.31,97.66) v2(121.86,68.63) v2(121.95,98.93) v2(121.95,98.29) v2(121.95,97.66) v2(122.58,98.93) v2(122.58,98.29) v2(122.58,97.66) v4(120.11,98.93)
+1.0VS_VCCOPCP: length 16.9
  TOP w0.102: v4(105.59,102.75) v2(106.27,102.75)
  IN1 w0.254: v2(119.59,103.39) 113.03,103.39 111.78,102.13 106.9,102.13 v2(106.27,102.75)
  BOTTOM w0.254: PU1200.12 106.53,104.26 106.27,104 v2(106.27,102.75)
+1.2V_DDR: length 83.3
  TOP w0.089: 115.84,56.6 115,56.6
  TOP w0.508: RH207.1 56.16,43.68 55.43,44.41 v2(55.43,44.83)
  IN3 w0.381: v2(55.43,44.83) 55.77,44.83 56.11,45.17 56.11,46.03 55.82,46.33 v2(55.43,46.33)
  BOTTOM w0.152: UC1.BB41 112.19,56.67 ; UC1.BB23 112.87,46.73 112.85,46.73 111.72,46.73 111.61,46.61 v2(111.59,46.61)
  BOTTOM w0.178: UC1.BB32 112.9,51.72 112.88,51.71 112.15,51.71 v2(112.12,51.73) ; UC1.BB47 112.49,60.33 112.14,60.33 v2(112.07,60.29)
  BOTTOM w0.203: UC1.BB51 v2(112.14,62.79) ; UC1.AL23 v2(118.79,47.06)
  BOTTOM w0.254: UC1.AU35 115.8,54.09 116.09,54.38 v2(116.09,54.38) ; UC1.AU28 115.8,50.43 v2(116.12,50.74) ; 112.19,56.67 111.24,56.67 v2(111.23,56.69) ; UC1.AU23 115.84,47.52 116.14,47.96 v2(116.17,48.01) ; JDIMM2.159 66.01,45.08 66.13,44.95 ; UC1.AU42 115.8,57.66 v2(115.42,58.04) ; v2(118.8,57.09) 119.05,56.84 UC1.AM40
  BOTTOM w0.305: JDIMM1.159 78.65,45.08 78.93,44.8 v2(78.93,44.29) 78.72,44.08 JDIMM1.163 ; JDIMM2.75 66.46,68.08 v2(66.51,68.13) ; v2(70.63,73.33) 70.62,73.33 JDIMM1.54 ; v2(78.89,68.34) 78.62,68.08 JDIMM1.75 ; JDIMM1.12 68.28,83.83 67.94,83.49 v2(67.94,83.09) ; JDIMM1.124 68.51,55.83 68.03,55.35 v2(68.03,54.72) 68.03,54.6 68.31,54.33 JDIMM1.130 ; v2(68.04,51.35) 68.06,51.33 68.27,51.33 JDIMM1.142 ; v2(78.93,46.64) 78.86,46.58 JDIMM1.153 ; JDIMM1.241 78.7,24.58 v2(78.9,24.38) ; JDIMM1.178 68.34,40.33 v2(67.46,39.44) ; v2(66.39,78.58) JDIMM2.33 ; JDIMM2.199 v2(66.23,35.08) ; JDIMM1.33 79.02,78.58 v2(79.03,78.58) ; JDIMM2.147 66.06,48.08 66.48,47.65 v2(66.48,47.22) 66.48,47.15 65.91,46.58 JDIMM2.153 ; JDIMM2.129 66.21,54.58 v2(66.36,54.72) ; v2(57.97,29.95) 57.84,29.83 JDIMM2.220 ; JDIMM2.135 66.07,53.08 v2(66.26,53.26) 66.26,51.94 65.9,51.58 JDIMM2.141 ; JDIMM1.220 68.24,29.83 68.06,29.64 68.06,29.63 v2(68.12,29.57) ; JDIMM2.241 v2(66.19,24.58) ; v2(68.1,44.52) 68.41,44.83 JDIMM1.160 ; JDIMM1.136 68.35,52.83 67.97,52.45 ; v2(66.39,58.42) 66.39,58.73 66.04,59.08 JDIMM2.111 ; JDIMM2.54 v2(58.03,73.33) ; 66.13,44.95 v2(66.13,44.45) 66.13,44.19 66.02,44.08 JDIMM2.163 ; JDIMM1.96 67.58,62.83 67.28,62.52 v2(67.28,61.83) ; JDIMM1.118 68.15,57.33 v2(68.02,57.46) 68.02,58.46 68.38,58.83 JDIMM1.112 ; JDIMM2.123 66.02,56.08 v2(66.47,56.52) 66.47,57.19 66.08,57.58 JDIMM2.117 ; JDIMM1.199 76.24,35.08 v2(76.1,34.93) ; v2(58.04,40.33) JDIMM2.178 ; JDIMM2.12 55.77,83.83 v2(55.36,83.41) ; JDIMM1.154 68.37,46.33 68.15,46.54 v2(68.15,47.22) 68.15,47.58 68.4,47.83 JDIMM1.148 ; JDIMM2.112 v2(55.37,58.83)
  vias: v2(55.37,57.33) v2(55.33,54.61) v2(55.43,52.69) v2(55.43,47.83) v2(78.84,53.13) v2(78.94,56.28) v2(79.2,59.12) v2(79.15,54.97) v2(79.41,50.51) v2(89.18,92.08) v2(89.81,91.54) v2(90.1,92.11) v2(90.64,91.56) v2(90.91,92.11) v2(91.41,91.56) v2(91.9,92.11) v2(92.17,91.56) v2(92.74,92.13) v2(92.85,91.51) v2(93.5,92.13) v2(93.62,91.51) v2(94.26,92.13) v2(94.38,91.51) v4(102.4,75.55)
+1.2VP: length 54.9
  TOP w0.203: PU200.19 70.83,104.07 v2(71.02,104.26) ; 67.52,106.03 67.87,105.68 PU200.5
  TOP w0.254: 67.52,106.03 67.25,106.31 PC214.2 67.24,106.75 PR207.2 67.25,107.66 PC213.1 67,108.83 v2(67,109.27)
  IN1 w0.254: v2(88.93,107.75) 88.1,107.75 85.73,110.13 80.45,110.13 79.09,111.49 74.93,111.49 74.1,110.65 71.1,110.65 70.67,111.08 67.26,111.08 66.74,110.56 66.74,109.52 v2(67,109.27)
  IN1 w0.508: v2(71.02,104.26) 72,105.24 72,107.64 75.3,110.94 78.83,110.94 80.2,109.57 85.46,109.57 87.98,107.06 v2(88.93,107.06)
  vias: v1(88,107.84)
+1.8V_AVDD: length 8.4
  TOP w0.127: v4(25.76,15.72) 26.54,15.72 26.84,16.02 CA61.1
  TOP w0.203: 29.3,18.55 29.41,18.55 30.38,19.52 30.38,19.76 30.59,19.97 UA1.40
  TOP w0.508: 29.3,18.55 R6511.1 27.92,18.55 27.08,17.71 C2715.1 CA61.1
+1.8V_PRIM: length 154.9
  TOP w0.254: v2(141.57,75.39) 142.68,74.28 RC1134.1
  TOP w1.016: 37.43,9.77 37.71,10.05 37.71,13.39 39.68,15.36 Q6205.1
  IN2 w0.254: v2(141.57,75.39) 138.71,75.39 136.99,73.67 135.77,73.67 133.77,71.67 133.77,70.11 133.17,69.51 131.9,69.51 131.42,69.98 v2(131.09,69.98)
  IN2 w1.016: 39.34,7.42 40.33,6.43 57.18,6.43 58.12,7.38 122.92,7.38 124.18,8.64
  IN3 w0.254: v2(131.09,69.98) 131.09,68.99 130.49,68.39 130.49,58.46 130.84,58.11 130.84,51.95 130.17,51.28 129.53,51.28 129.06,50.81 129.06,47.4 128.74,47.09 122.65,47.09 121.87,46.3 121.87,44.8 121.08,44.01 120.02,44.01 119.75,43.75 119.75,42.06 119.97,41.83 120.45,41.83 120.66,42.05 120.66,42.53 121.04,42.91 122.22,42.91 v2(122.8,42.33)
  BOTTOM w0.203: UC1.AA1 124.44,34.15 v2(124.44,33.04)
  BOTTOM w0.254: UC1.H63 130.7,69.59 v2(131.09,69.98) ; UC1.AF16 122.39,42.66 v2(122.8,42.33)
  vias: v2(38.89,9.14) v2(38.89,8.44) v2(125.17,9.05) v2(125.85,9.04) v2(130.67,18.93) v2(131.26,18.93) v4(126.14,30.16)
+1.8VALWP: length 18.6
  TOP w0.254: v2(41.18,8.06) 41.18,10.73 42.37,11.92 v1(53.78,11.92) v2(54.64,12.78)
  BOTTOM w0.254: v2(54.64,12.78) PR503.2 54.6,12.05 PC503.1
  vias: v2(41.18,7.42)
+1VALWP: length 6.7
  BOTTOM w0.102: PR308.2 152.28,22.92 v4(151.91,22.55)
  BOTTOM w0.254: 147.5,22.49 150.09,22.49 PC309.1 PR308.2
+2.5V_MEM: length 9
  TOP w1.016: 82.58,12.66 81.63,13.61 80.83,13.61 79.87,14.56 v4(79.87,17.04) 80.36,17.52 CD9.1
  vias: v2(65.98,19.67) v2(66.61,19.67) v2(78.17,19.47) v2(78.78,19.47) v2(79.37,19.47)
+2.5VP: length 1
  TOP w0.127: 78.78,12.2 v4(78.78,13.22)
  vias: v2(80.87,11.36) v2(81.47,11.36)
+3.3V_ALW_DSW: length 36.3
  TOP w0.381: 109.38,39.58 109.52,39.58 110.7,40.76 110.7,41.28 109.96,42.02 107.12,42.02 106.12,41.02 104.34,41.02 104.22,40.9
  TOP w0.635: 99.22,36.21 98.09,36.21 92.41,30.53 92.41,21.34 92.93,20.82 94.67,20.82 95.24,20.25 RC214.1
  IN3 w0.381: v2(122.75,43.62) 122.68,43.56 v2(120.24,43.56)
  BOTTOM w0.254: v2(122.75,43.62) 122.78,43.62 ; 122.78,43.62 123.12,43.96 UC1.AD18 ; 122.78,43.62 122.86,43.62 UC1.AD17 ; v2(120.24,43.56) 120.41,43.56 UC1.AJ17
  vias: v1(99.39,38.72) v2(108.31,39.15) v2(108.77,39.58)
+3.3V_CAM: length 8.2
  TOP w0.254: v2(51.18,98.89) 51.27,98.8 C5207.1
  TOP w0.508: R5229.2 EC5210.1 v2(53.13,98.85) 53.13,99.21 52.66,99.68 v4(51.95,99.68) 51.57,99.68 51.18,99.3 v2(51.18,98.89)
  BOTTOM w0.254: JEDP.33 53.27,98.71 v2(53.13,98.85) ; JEDP.29 51.27,98.81 v2(51.18,98.89)
+3.3V_LAN: length 3
  TOP w0.127: UL3.1 32.22,79.12 v4(31.52,79.81)
  TOP w0.203: 35.6,82.56 35.81,82.77 UL1.11
  vias: v2(30.69,88.96) v2(30.69,88.32) v2(34.13,78.93) v2(34.83,78.93) v2(39.88,87.89) v2(40.22,88.4)
+3.3V_RUN_UZ2: length 1.9
  TOP w0.102: 195.29,41.64 v1(195.29,39.71)
+3.3V_WLAN: length 16
  TOP w1.016: 184.12,54.99 184.96,55.84 v4(187.1,55.84) v4(190.27,55.84) 191.83,55.84 194.36,58.37 198.28,58.37 198.56,58.1
  vias: v2(181.35,54.45) v2(181.98,54.45) v2(199.42,57.65) v2(200.05,57.65) v4(199.67,58.22)
+3V_SPI: length 377.1
  TOP w0.127: v2(42.37,66.56) 42.57,66.56 v4(43.04,67.03)
  TOP w0.254: RZ1707.1 41.24,77.41 41.24,74.92 41.71,74.46 UZ13.24 44.81,74.46 CZ92.1 ; v2(41.8,70.87) 42,70.87 42.33,71.21 UZ13.19
  TOP w0.508: v2(45.76,74.21) CZ92.1 ; v2(46.64,70.82) 46.16,71.31 CZ93.1 44.88,71.31 CZ94.1 44.78,71.21 UZ13.19 ; QZ11.3 v2(42.37,66.56)
  IN1 w0.508: v2(116.14,20.83) 116.68,20.29 v2(116.68,16.54) 116.68,16.09 116.25,15.65 115.39,15.65 112.41,18.63 v2(109.69,18.63)
  IN2 w0.508: v2(116.14,20.83) 117.03,20.83 119.49,23.29 119.49,25.09 v2(119.6,25.21) 121.05,25.21 123.25,23 v2(126.2,23) 129.85,23 134.06,18.79 145.77,18.79 146.52,18.04 157.49,18.04 162.41,22.97 162.41,26.92 163,27.5 165.8,27.5 168.01,25.29 169.17,25.29 169.83,24.63 175.37,24.63 178.81,28.07 178.81,29.99 179.09,30.27 179.09,40.79 176.09,43.79 176.09,45.95 175.59,46.45 173.38,46.45 172.4,47.43 172.4,52.16 171.73,52.83 171.73,56.03 v2(173.26,57.56) ; v2(42.37,66.56) 42.9,67.09 42.9,70.48 ; 42.9,70.48 42.51,70.87 v2(41.8,70.87) ; 42.9,70.48 46.3,70.48 v2(46.64,70.82) 45.76,71.7 v2(45.76,74.21) 45.85,74.12 49.51,74.12 53,77.62 53,89.5 56.08,92.58 59.94,92.58 61.76,90.76 103.02,90.76 112.66,100.4 163.66,100.4 169.38,94.67 169.38,90.6 172.37,87.62 172.37,79.7 v2(168.67,76)
  IN3 w0.254: v2(119.6,25.21) 119.96,25.56 119.96,29.92 120.37,30.34 120.37,31.18 120.01,31.54 120.01,32.03 121.06,33.08 121.06,40.7 120.81,40.95 120.81,41.55 121.13,41.88 v2(121.13,42.34)
  BOTTOM w0.254: v2(121.13,42.34) 121.12,42.34 121.12,42.33 120.79,42.66 UC1.AJ16
  BOTTOM w0.508: v2(116.68,16.54) 116.68,16.12 116.85,15.95 117.57,15.95 RC1124.2 ; v2(168.67,76) 170.67,76 174.66,72.02 174.66,66.4 174.24,65.98 174.24,58.54 v2(173.26,57.56) ; v2(109.69,18.63) 109.69,17.94 RC9.1 ; RC30.1 118.84,22.22 119.85,23.24 119.85,24.95 v2(119.6,25.21) RC53.1 ; CC9.1 127.04,22.16 v2(126.2,23) 126.27,23.07 UC2.8
+3VALW: length 262.8
  TOP w0.381: CC271.1 99.18,12.19 98.45,12.19 98.28,12.36 UZ6.5 ; UC15.5 116.45,14.11 116.61,14.27 116.61,14.58 v2(116.55,14.65) ; UC12.5 104.06,12.03 104.26,11.83 104.96,11.83 CC1820.1 ; UC13.5 112.69,14.17 112.88,14.36 112.88,15.61 v4(112.68,15.81) 112.68,16.91 v2(112.61,16.99) ; RE396.1 45.08,35.76 v2(45.08,35.18) ; v2(118.77,32.9) 120.17,34.3 RC73.2
  TOP w0.508: Q6203.3 48.59,29.62 48.11,30.11 C6204.1 48.11,31.12 48.62,31.63 v2(49.74,31.63) ; v2(49.69,32.85) 49.69,32.9 R2608.1 ; PR28.1 v2(198.02,96.45) ; PR209.1 64.09,102.17 63.66,101.73 v2(63.66,101.47) ; PR16.2 v2(166.6,24.65) ; RC68.2 95.2,21.34 95.38,21.17 v2(95.43,21.17) RC214.2 ; RE25.1 v2(53.69,45.91) ; 20.46,44.19 19.8,44.19 19.48,43.86 19.48,42.98 20.04,42.41 RE388.2 ; v2(102.02,16.73) 102.02,16.2 v4(101.37,15.55) 100.5,14.68 100.5,13.25 99.88,12.63 CC271.1 ; UE7.2 76.3,111.87 CE1.1 73.69,111.87 v2(73.36,111.54) ; v2(105.9,11.74) 105.64,12 CC1820.1 ; PR791.1 v2(185.19,47.37) ; RE404.1 v2(35.26,60.02) ; PR756.2 v2(177.69,55.3) ; PR3.2 207.67,82.23 v2(207.42,81.97) ; v2(153.81,26.33) 153.29,26.33 PR304.2
  IN1 w0.508: v2(105.9,11.74) 105.9,12.28 107.55,13.93 108.28,13.93 111.34,16.99 v2(112.61,16.99) 112.61,15.43 113.39,14.65 v2(116.55,14.65) ; v2(153.81,26.33) 154.26,26.78 165.75,26.78 166.6,25.93 v2(166.6,24.65) ; v2(107.95,102.74) 107.95,103.49 107.14,104.3 100.54,104.3 93.75,111.08 81.45,111.08 80.19,112.34 74.16,112.34 v2(73.36,111.54) 72.8,112.1 66.16,112.1 65.05,110.99 65.05,103.21 63.66,101.81 v2(63.66,101.47)
  IN2 w0.381: v2(118.77,32.9) 119.1,33.23 119.1,33.48 120.06,34.44 121.27,34.44 122.58,33.13 122.58,27.8 121.82,27.03 119.24,27.03 v2(118.52,26.31)
  IN2 w0.508: v2(198.02,96.45) 205.71,88.77 205.71,83.69 v2(207.42,81.97) 208.05,81.97 210.6,79.43 210.6,50.86 208.05,48.32 v2(206.02,48.32) ; 204.82,48.32 204.82,51.05 v2(203.8,52.06) ; v2(63.66,101.47) 59.99,101.47 56.16,97.64 56.16,94.19 46.38,84.41 v2(46.38,82.23)
  IN2 w1.016: v2(206.02,48.32) 204.82,48.32 202.56,46.06 200.09,46.06 195.58,41.56
  BOTTOM w0.254: PC1205.1 107.95,103.79 107.53,104.22 PU1200.10 ; v2(206.02,48.32) 205.86,48.16 JIO1.24
  BOTTOM w0.508: RE446.2 130.47,14.19 132.08,15.81 RZ1705.1 133.06,16.76 v2(132.4,17.42) ; RE71.1 24.25,49.91 23.9,49.56 v2(23.68,49.56) ; R5810.1 202.72,53.14 v2(203.8,52.06) ; v2(116.55,14.65) 116.93,15.03 RC1124.1 ; v2(112.61,16.99) 111.43,16.99 CC1821.1 ; v2(107.95,102.74) PC1205.1 ; PR303.1 v2(154.89,32.96)
  vias: v2(21.73,51) v2(22.33,51.01) v2(23.28,44.61) v2(23.31,43.99) v2(23.77,44.94) v2(23.79,44.33) v2(23.8,43.67) v2(24.02,50.69) v2(31.89,56.08) v2(31.89,55.49) v2(32.52,55.49) v2(33.24,74.57) v2(33.24,73.93) v2(33.38,34.73) v2(33.87,74.67) v2(33.87,74.04) v2(33.94,34.25) v2(38.65,13.09) v2(38.65,12.42) v2(39.35,33.13) v2(39.34,13.79) v2(39.34,13.11) v2(39.34,12.44) v2(39.75,32.6) v2(40.13,60.56) v2(40.16,13.79) v2(41.36,60.58) v2(42,60.5) v2(42.66,60.53) v2(43.24,60.53) v2(45.32,60.02) v2(49.11,46.73) v2(49.11,46.05) v2(51.29,43.37) v2(51.77,43.01) v2(55.78,8.06) v2(55.78,7.42) v2(56.42,8.06) v2(56.42,7.42) v2(69.04,9.86) v2(69.65,9.86) v2(179.61,63.88) v2(179.61,63.11) v2(180.37,63.88) v2(180.37,63.11) v2(181.13,63.88) v2(181.13,63.11) v2(181.89,63.88) v2(181.89,63.11) v2(182.65,63.88) v2(182.65,63.11) v2(192.76,39.1) v2(193.17,40.27) v2(193.17,39.63) v2(193.25,38.7) v2(193.74,40.41) v2(193.74,39.77) v2(193.74,39.19) v2(193.92,41.03) v4(59.85,13.65)
+3VALW_EC: length 40.9
  TOP w0.203: UE1.65 45.54,56.36 45.72,56.55 47.04,56.55 47.86,55.74 CE63.2 ; UE1.54 48.06,49.82 48.73,49.14 CE66.1 ; RE354.1 35.03,38.49 34.74,38.78 UE1.5 ; UE1.82 38.74,56.53 38.88,56.67 38.88,57.83 38.64,58.07 CE68.1 ; UE1.43 48.16,45.42 48.29,45.55 49.89,45.55 CE69.1 ; UE1.22 41.54,38.92 41.25,38.64 41.14,38.64 CE79.1 40.5,38.47 40.34,38.64 UE1.19
  TOP w0.254: UE1.103 29.76,51.42 CE67.1 ; CE64.2 29.3,46.57 30.52,46.57 30.58,46.62 UE1.115
  TOP w0.381: v2(50.4,46.24) 49.93,45.77 CE69.1 ; v2(29.72,52.47) 29.45,52.2 CE67.1 ; CE71.1 42.03,36.78 42.16,36.9 v2(42.16,37.52) ; RE425.2 36.19,34.2 35.55,33.56 v2(35.13,33.56) 34.84,33.56 34.55,33.85 34.55,34.58 34.24,34.88 RE424.2 34.24,35.65 35.12,36.53 ; CE65.1 40.41,37.92 CE79.1
  TOP w0.508: 35.12,36.53 CE89.1 35.12,37.71 35.03,37.8 RE354.1 ; CE64.2 28.6,46.72 v2(28.5,46.62) ; CE71.1 CE65.1 ; RE440.2 v2(51.49,39.87) ; CE68.1 38.46,58.34 v2(38.04,58.76) ; v2(51.15,48.45) 50.45,48.45 49.93,48.97 CE66.1
  vias: v1(51.38,59.93) v2(23.29,47.38) v2(27.65,59.06) v2(27.65,58.48) v2(40.11,32.11) v2(40.49,31.66) v2(43.26,61.83) v2(43.26,61.25) v2(51.05,55.74) v2(51.08,55.13)
+3VALW_PCH: length 106.5
  TOP w0.254: RC1138.2 117.47,45.17 v2(117.39,45.25) ; v2(126.1,42.98) 126.13,42.98 126.54,42.57 126.54,42.05 127.17,41.42 RC23.2
  TOP w0.508: v2(120.46,28.67) 120.46,29 120.79,29.33 121.48,29.33 121.9,29.75 RC365.2 122.24,30.09 122.55,29.79 122.55,29.34 123.12,28.77 123.88,28.77 124.26,28.39 124.26,26.9 v4(124.65,26.51) 125.14,26.03 130.27,26.03 v2(130.74,26.5) ; RC183.1 99.9,32.12 100.75,31.27 RC187.1 101.12,31.11 101.67,30.56 102.98,30.56 v2(103.25,30.28) ; v2(110.57,28.09) 110.23,28.09 108.93,26.79 108.32,26.79 106.8,25.27 106.8,20.3 108.39,18.71 108.39,17.09 108.04,16.75 RC74.1 RC1127.2 ; CC207.1 92.29,16.99 v2(92.61,17.31) ; v2(91.79,13.67) 91.79,14.08 91.43,14.43 CC265.1
  IN2 w0.508: v2(120.46,28.67) 119.55,27.76 110.91,27.76 v2(110.57,28.09) 109.72,28.95 109.72,29.94 109.03,30.63 104.66,30.63 104.18,30.14 103.39,30.14 v2(103.25,30.28)
  BOTTOM w0.254: UC1.AK15 120.09,42.29 v2(120.22,42.29) ; v2(121.38,41.43) 121.49,41.55 UC1.AG15 ; v2(120.24,42.99) 120.14,42.99 UC1.AK17 ; v2(123.6,41.32) 123.75,41.32 124.01,41.58 124.42,41.58 UC1.Y15 ; v2(126.1,42.98) 126.21,42.98 UC1.T16 ; UC1.AJ21 120.83,46.08 121.14,46.08 121.38,46.32 v2(122.74,46.32) 122.89,46.48 124.9,46.48 125.28,46.1 125.28,45.02 UC1.V19 ; UC1.AD15 v2(122.79,41.63) ; UC1.Y16 v2(124.43,42.97)
  BOTTOM w0.508: v2(91.79,13.67) 91.79,15.59 92.61,16.41 v2(92.61,17.31) 92.46,17.45 92.46,18.22 92.97,18.73 92.97,20 95.51,22.54 95.51,23.68 97.87,26.04 99.69,26.04 100.66,27.01 101.88,27.01 103.25,28.38 v2(103.25,30.28) ; RC12.2 130.65,23.93 131.25,23.34 131.25,21 132.78,19.46 132.78,18.16 134.46,16.48 RZ1705.2 ; RC186.1 RC288.2 110.32,27.83 v2(110.57,28.09) ; RC387.2 v2(120.46,28.67)
  vias: v2(130.75,27.11) v2(141.36,35.94) v2(141.37,35.29)
+3VALWP: length 35.6
  TOP w0.102: v2(186.78,79.56) v1(187.3,79.56)
  TOP w0.254: PR107.1 PR113.1 186.15,79.94 186.53,79.56 v2(186.78,79.56)
  IN3 w0.254: v2(183.86,65.91) 184.62,66.67 184.62,68.13 185.6,69.11 185.6,77.82 v2(184.56,78.86) ; v2(186.78,79.56) 186.08,78.86 186.08,69.02 185.07,68 185.07,66.42 v2(183.86,65.21)
  BOTTOM w0.254: PR108.2 187.4,79.93 187.04,79.56 v2(186.78,79.56) 186.62,79.73 PR109.1 ; PU100.14 184.38,79.04 v2(184.56,78.86)
+3VLP: length 320.7
  TOP w0.381: v2(35.28,29.85) 35.6,29.53 38.57,29.53 40.11,31.07 41.12,31.07 41.88,31.83 43.79,31.83 44,32.04 R2609.1
  TOP w0.508: RE356.2 26.45,45.16 v2(26.32,45.03) ; v2(182.9,48.11) 183.09,48.29 185.86,48.29 186.34,47.81 198.9,47.81 200.14,46.57 202.29,46.57 204.91,49.18 v4(204.91,53.14) 204.91,56.01 205.29,56.4 206.43,56.4 206.81,56.78 v2(207.17,56.78) D2501.2
  IN1 w0.381: v2(26.32,45.03) 25.26,43.97 25.26,43.05 24.41,42.19 24.41,36.18 24.72,35.87 27.11,35.87 27.31,36.08 28.29,36.08 29.21,35.15 29.21,34.81 29.87,34.15 31.09,34.15 35.28,29.96 v2(35.28,29.85) 35.28,29.73 36.47,28.55 36.47,25.52 36.79,25.2 36.79,23.31 37.81,22.28 37.81,21.33 40.29,18.85 v2(41.25,18.85)
  IN2 w0.381: v2(41.25,18.85) 42.19,17.91 43.41,17.91 44.91,16.42 47.4,16.42 51.86,11.96 55.39,11.96 58.07,9.28 62.86,9.28 63.72,10.14 64.72,10.14 65.59,9.28 79.28,9.28 79.91,9.91 83.16,9.91 83.91,10.66 90.14,10.66 90.3,10.83 92.13,10.83 92.71,10.24 94.44,10.24 95.46,9.22 110.82,9.22 111.72,10.12 114.55,10.12 115.45,9.22 120.09,9.22 121.77,10.9 128.94,10.9 129.83,10.02 133.95,10.02 134.76,9.2 148.38,9.2 150.16,10.98 173.69,10.98 179.7,16.99 179.7,24.5 181.82,26.62 181.82,29.13 181.31,29.64 181.31,42.48 182.9,44.07 v2(182.9,48.11)
  IN2 w0.508: v2(184.61,77.88) 185.42,77.88 185.96,78.42 185.96,83.24 188.94,86.23 197.89,86.23 199.1,85.02 202.47,85.02 207.17,80.32 v2(207.17,56.78)
+3VS: length 311.9
  TOP w0.203: UA1.1 34.93,21.47 35.04,21.36 35.04,20.88 ; UA1.9 35.34,24.67
  TOP w0.254: 62.51,20.38 62.89,20.76 v2(62.89,20.95) ; 62.51,20.38 62.08,20.38 61.83,20.63 61.37,20.63 ; 62.51,20.38 62.51,19.87 62.83,19.55 64.8,19.55 65.68,18.68 67.05,18.68 RD2.1 RD1.1 68.88,19.29 69.5,18.66 72.29,18.66 ; Q2601.2 84.67,13.61 RE32.1 ; U5603.10 222.68,36.3 CN19.1 223.15,35.8 U5603.9 ; U5603.2 218.79,35.8 218.66,35.94 CN20.1 218.34,35.3 U5603.3 ; Q6501.5 94.64,18.16 94.95,18.46 RZ20.1
  TOP w0.356: v2(94.31,15.13) 94.64,15.46 Q6501.2
  TOP w0.381: RC1109.2 102.45,29.05 102.63,28.88 UC7.5 ; v2(84.57,16.71) 84.57,16.68 84.67,16.58 Q2601.5 ; CA57.1 41.44,25.84 40.3,25.84 v2(39.72,26.42) 39.02,27.12 R6202.1 ; v2(119.85,30.98) 119.85,30.3 RC382.2 ; 35.34,24.67 35.82,25.15 v3(35.82,25.19) ; UE6.5 v2(36.08,62)
  TOP w0.508: v2(85.09,11.41) 85.09,13.19 RE32.1 ; v2(102.34,35.57) 103.2,36.43 RC21.1 ; v2(54.7,46.22) RD6.1 54.21,45.28 53.88,44.95 RE441.2 ; v2(110.85,10.6) 111.1,10.85 RC388.2 ; RC123.1 105.2,98.24 v2(104.76,98.69) ; CD17.1 66.58,45.08 66.77,44.89 v2(66.77,44.45) 66.77,44.13 66.56,43.93 RD3.1 ; v2(22.19,37.74) 22.66,38.21 R6110.1 ; RS30.1 v2(203.99,27.8) ; v2(205.13,16.39) 205.32,16.58 RS28.1 RS19.1 RS33.2 202.49,17.04 CS27.1 202.48,16.71 202.12,16.35 195.89,16.35 v2(195.35,16.89) ; CN19.1 223.17,37.4 221.26,39.3 v2(220.12,39.3) ; RL2.1 40.01,84.87 v2(40,84.88) ; v2(103.66,30.86) RC50.1 104.3,30.84 RC47.1 ; v2(38.56,80.53) 38.48,80.53 QL1.2 ; CN20.1 v2(216.69,35.94) ; 35.04,20.88 35.04,20.47 v3(35.52,19.99) 35.92,19.59 RA14.1 ; Q6502.2 203.41,63.89 204.04,63.25 R6534.1 v2(203.23,62.54) ; v2(102.63,29.71) 102.52,29.83 101.87,29.83 101.51,29.47 RC1109.2 ; RS38.2 211.26,22.54 211.64,22.16 v2(212,22.16) ; 43.56,19.67 39.17,19.67 37.61,18.11 Q6205.2 ; RZ20.1 94.47,18.79 94.39,18.71 RZ21.1 v2(93.77,19.39) ; v2(94.03,25.05) 94.39,25.41 RC1123.1 RC1106.1 RC1104.1 ; v2(209.5,28.84) 209.31,28.65 209.31,28.09 CS42.1 209.32,28.05 RS34.2 ; RS29.1 v2(206.66,27.87) ; RS27.1 RS25.1 209.92,17.04 211.33,18.45 212.37,18.45 v2(213.67,19.74) ; R5229.1 v2(55.46,99.03) ; v2(166.91,61.06) PR612.1 ; RE432.1 86.67,14.49 v2(86.44,14.71) ; RS20.1 v2(205.77,27.87) ; CE85.1 v2(40.59,61.07) ; RS26.1 v2(201.32,27.8)
  IN1 w0.508: v2(30.14,32.49) 29.35,32.49 27.93,33.92 27.23,33.92 26.81,34.34 24.08,34.34 22.87,35.55 22.87,37 22.21,37.66 22.21,37.74 v2(22.19,37.74) ; v2(107.04,15.17) 106.28,14.41 104.27,14.41 103.39,15.29 v2(102.89,15.29) 102.57,14.97 102.57,13.33 103.05,12.85 103.05,10.78 104.14,9.69 110.37,9.69 110.85,10.17 v2(110.85,10.6) ; v2(102.63,29.71) 101.57,30.78 101.57,34.39 102.34,35.16 v2(102.34,35.57) ; v2(66.77,44.45) 66.77,44.85 66.4,45.22 64.49,45.22 63.48,44.2 55.17,44.2 54.7,44.67 v2(54.7,46.22)
  IN2 w0.381: v2(105.94,38.61) 105.95,38.61 105.95,38.35 104.21,36.61 103.38,36.61 v2(102.34,35.57)
  IN2 w0.508: v2(86.44,14.71) 86.44,14.81 88.89,17.25 89.18,17.25 v2(91.32,19.39) v2(93.77,19.39) ; v2(85.09,11.41) 87.71,11.41 88.87,12.57 92.75,12.57 93.53,11.79 94.92,11.79 95.53,11.18 95.53,10.35 96.09,9.79 110.27,9.79 110.85,10.37 v2(110.85,10.6)
  IN3 w0.254: v2(84.57,16.71) 85.56,16.71 87.43,18.57 90.5,18.57 v2(91.32,19.39)
  IN3 w0.508: v2(144.38,20.11) 143.21,18.94 v2(143.21,16.75) ; v2(30.14,32.49) 31.6,32.49 33.46,30.64 33.46,29.67 34.89,28.24 34.89,26.12 v3(35.82,25.19) 35.82,24.62 35.06,23.86 35.06,21.48 35.52,21.02 v3(35.52,19.99) ; 213.9,22.28 213.77,22.16 v2(212,22.16) ; v2(94.31,15.13) 94.83,15.65 96.8,15.65 97.65,14.8 98.96,14.8 99.44,15.29 v2(102.89,15.29)
  BOTTOM w0.305: JDIMM1.255 76.56,21.08 76.26,20.78 76.26,19.48 76.25,19.46 v2(76.2,19.46) ; v2(62.89,20.95) 63.07,20.95 63.19,21.08 JDIMM2.255
  BOTTOM w0.381: RN20.1 144.54,15.55 QC2.2 ; v2(17.99,72.7) 18.19,72.91 QX4.2 ; RC272.1 112.48,28.69 v2(112.48,29.06) ; v2(105.94,38.61) 106.4,39.08 RC13.1 ; QX4.5 v2(18.19,75.9)
  BOTTOM w0.508: v2(107.04,15.17) 107.34,15.48 RC376.1 RC370.1 ; v3(35.82,25.19) 38.73,25.19 39.72,26.18 v2(39.72,26.42) ; v2(203.99,27.8) 203.99,19.74 205.13,18.6 v2(205.13,16.39) ; RC292.1 RC1129.1 ; RC292.1 RC374.1 ; RC292.1 v2(123.73,29.45) ; RS39.1 v2(195.35,16.89) ; RC62.2 RC63.2 v2(121.33,28.63) 121.46,28.51 RC1130.1 ; RC291.1 v2(136.7,29.06) ; v2(91.32,19.39) 91.32,19.87 v2(93.22,21.78) ; v2(30.14,32.49) 30.08,32.55 RA13.2 ; v2(96.71,106.54) 98.2,105.05 98.2,102.38 101.9,98.69 v2(104.76,98.69) ; RN20.1 143.66,15.43 143.21,15.88 v2(143.21,16.75) ; v2(93.77,19.39) 93.77,15.68 v2(94.31,15.13) ; v2(102.89,15.29) 102.95,15.35 RC372.1 102.95,20.68 RC27.2 ; PR1206.1 v2(104.66,111.12)
  vias: v2(28.4,61.78) v2(28.4,61.16) v2(35.5,71.85) v2(35.93,72.27) v2(36.73,104.64) v2(36.73,104.01) v2(41.96,75.6) v2(41.96,74.96) v2(53.88,25.18) v2(53.85,24.59) v2(53.85,23.96) v2(53.81,23.36) v2(141.91,32.19) v2(142.43,32.47) v2(142.45,31.87) v2(142.46,31.25) v2(143.08,32.48) v2(143.07,31.85) v2(143.08,31.21) v2(143.09,30.61) v2(175.16,108.77) v2(175.16,108.14) v2(203.25,49.08) v2(203.25,48.45) v2(206.4,40.25) v2(206.4,39.56) v2(206.4,38.86) v2(207.04,40.95) v2(207.04,40.25) v2(207.04,39.56) v2(207.04,38.86) v2(207.67,41.59) v2(207.67,40.95) v2(207.67,40.25) v2(207.67,39.56) v2(207.67,38.86) v2(218.72,23.17) v2(219.1,23.81) v2(219.48,23.17) v4(200.82,40.57)
+3VS_SSD: length 1.8
  TOP w0.127: v4(223.7,10.03) 223.7,10.42 v2(223.32,10.8)
  TOP w0.508: RB1.1 v2(223.32,10.8)
  vias: v2(223.52,16.75) v2(223.52,15.98) v2(223.8,4.38) v2(223.8,3.74) v2(224.26,16.75) v2(224.29,16.01) v2(224.39,4.01) v2(224.39,3.37) v4(224.95,20) v4(225.07,4.63)
+5V_KB_BL: length 2
  BOTTOM w0.102: v4(120.95,15.79) 120.95,15.68 121.54,15.08 121.97,15.08 122.38,14.68 C6202.1
+5V_PVDD:
  vias: v1(33.04,19.87) v2(30.9,19.64) v2(33.99,19.01) v2(34.32,18.5) v2(36.43,12.14)
+5V_RUN_UZ2: length 2.1
  TOP w0.102: 189.28,44.6 189.28,46.08 v1(188.85,46.52)
+5VA: length 7.3
  TOP w0.203: UA1.26 28.13,25.47 27.86,25.74 27.86,25.74 27.6,26.01 v2(27.6,26.21)
  TOP w0.254: v2(27.6,26.21) 27.6,26.71 26.82,27.49 25.31,27.49 24.77,26.94 RA1111.1
  BOTTOM w0.102: v1(28.72,27.29) 28.46,27.03 CA71.1
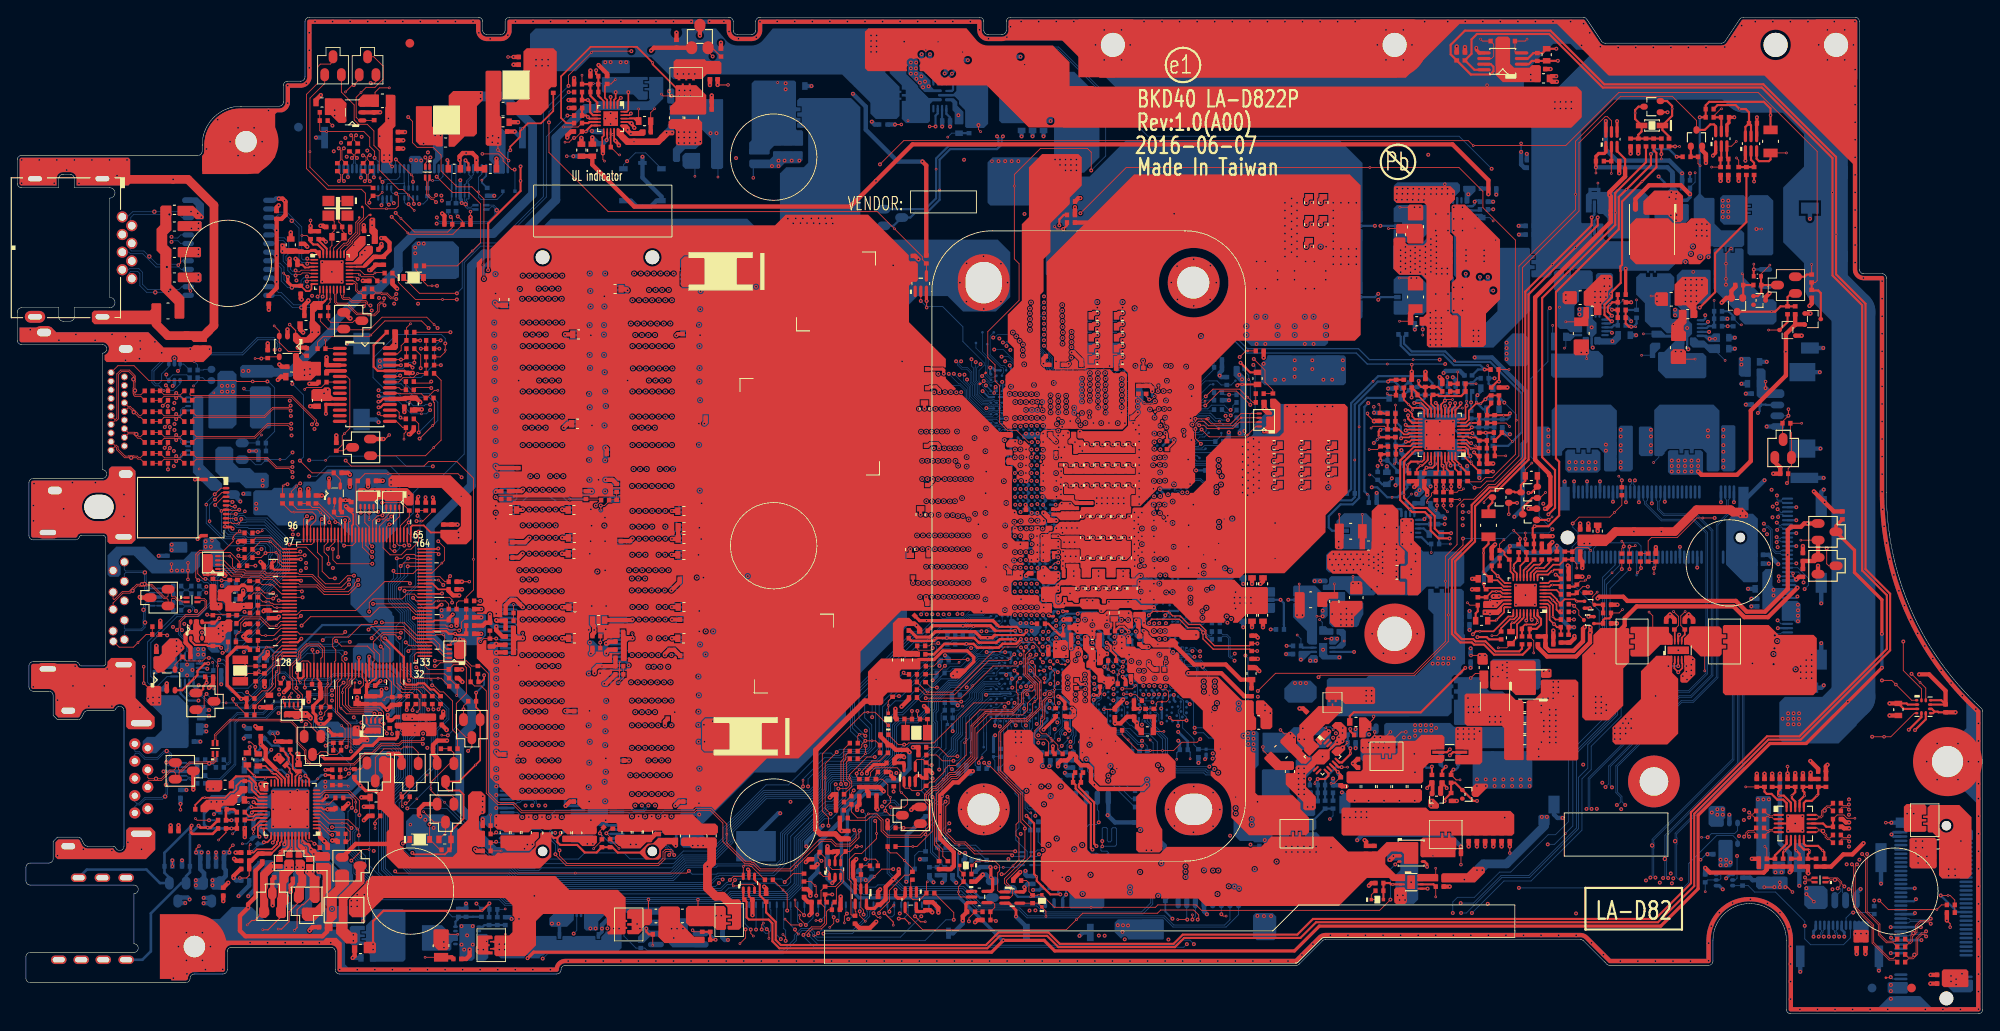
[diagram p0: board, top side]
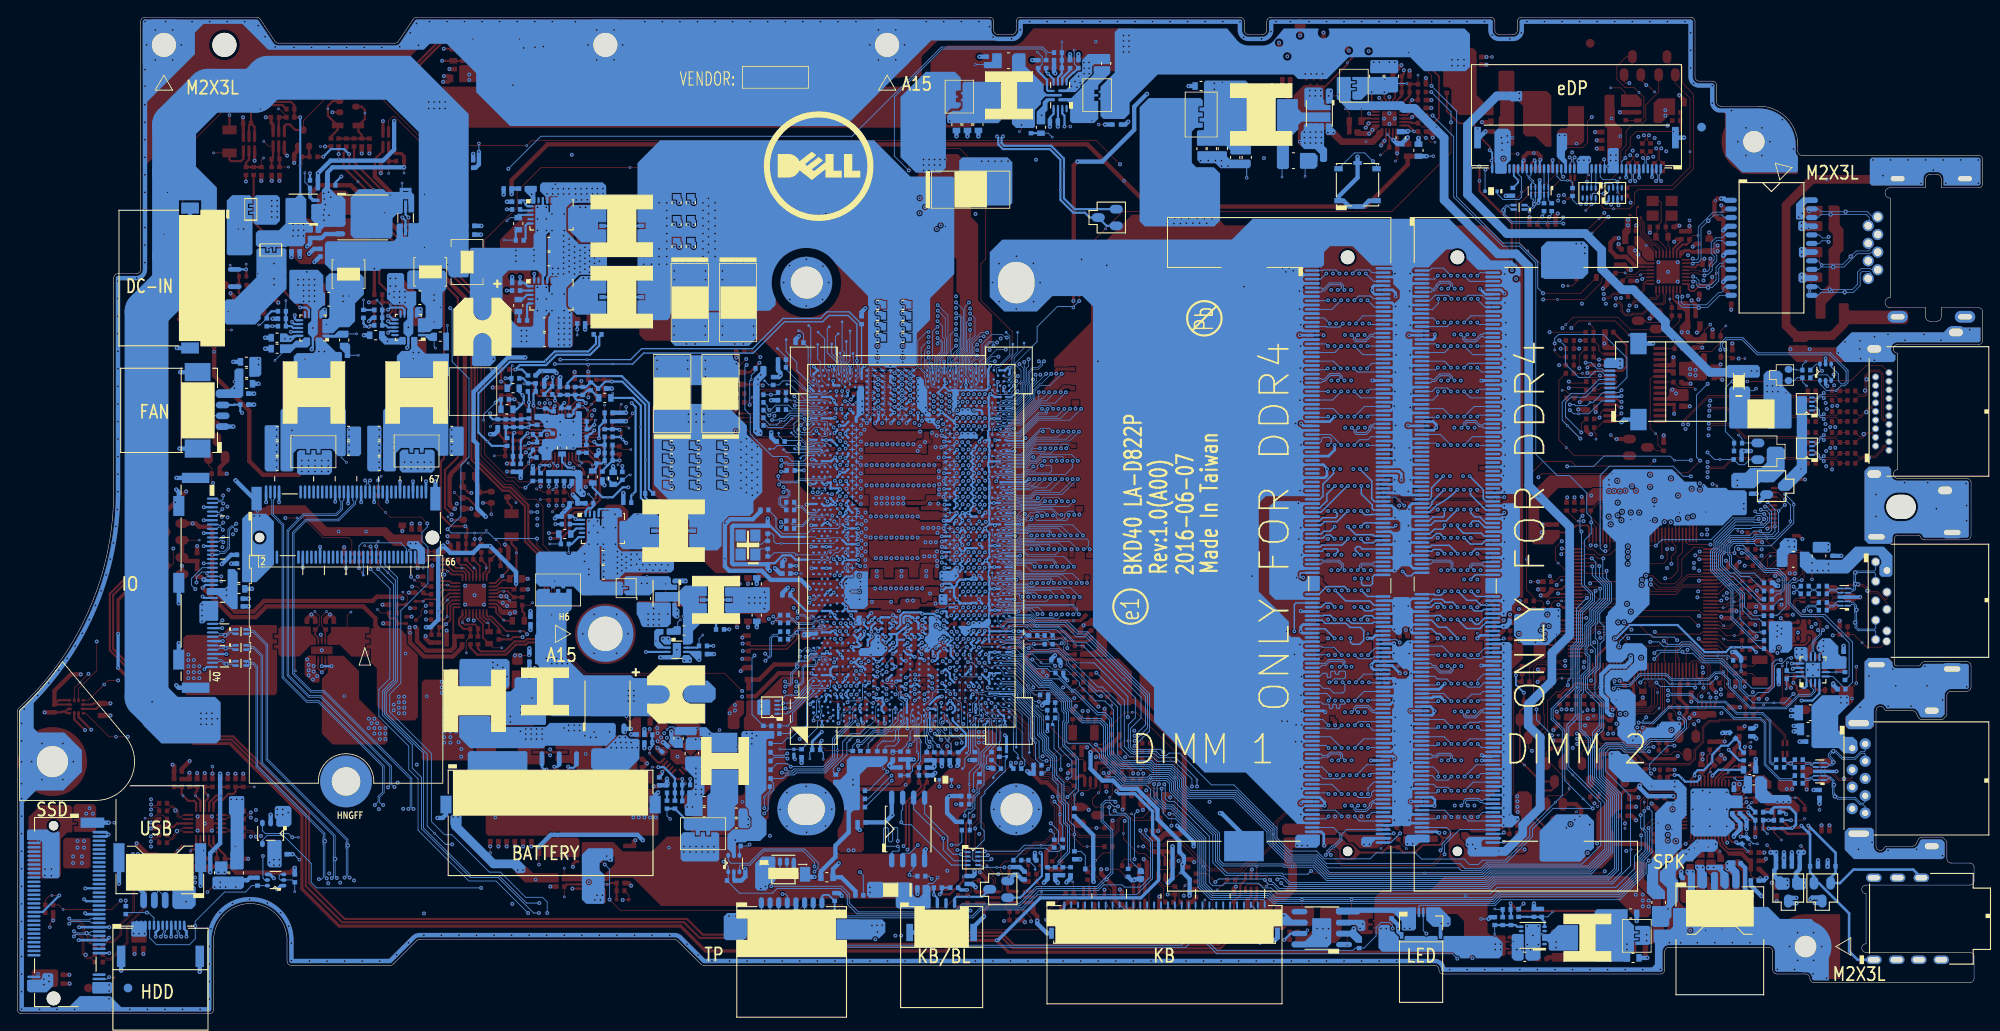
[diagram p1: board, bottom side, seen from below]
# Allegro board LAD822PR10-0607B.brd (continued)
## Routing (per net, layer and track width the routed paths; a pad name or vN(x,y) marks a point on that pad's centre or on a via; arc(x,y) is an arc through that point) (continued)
+5VALW: length 281.8
  TOP w0.203: UZ2.4 v2(192.23,40.25)
  TOP w0.508: PR602.2 162.84,60.93 163.17,60.6 v2(163.17,60.1) ; PD6.3 206.85,79.83 PD5.3 ; PD6.3 204.69,78.71 v4(204.69,76.66) 204.69,73.91 200.63,69.84 200.63,64 199.04,62.42 194.91,62.42 v2(194.53,62.8) ; PD6.3 205.77,79.87 PR8.1 ; v2(170.26,94.91) 170.26,96.53 166.11,100.68 103.61,100.68 v4(99.38,96.45) 96.41,93.48 71.4,93.48 66.55,98.33 PR210.2 PR206.1 ; PR615.1 v2(172.46,72.52)
  IN2 w0.508: 171.22,65.59 171.22,69.03 172.94,70.75 172.94,72.04 v2(172.46,72.52) ; 171.22,65.59 172.3,64.51 187.16,64.51 188.88,62.8 v2(191.48,62.8) ; 171.22,65.59 170.04,64.41 170.04,60.9 168.68,59.55 164.51,59.55 163.95,60.1 v2(163.17,60.1) 163.01,59.94 163.01,58.59 164.58,57.02 164.58,42.36 162.13,39.91 149.66,39.91 v2(148.56,41.02) ; v2(172.46,72.52) 172.46,74.42 173,74.97 173,87.88 170.02,90.86 170.02,94.67 v2(170.26,94.91) ; v2(172.46,72.52) 169.72,72.52 167.6,74.65 165.51,74.65 v2(165.07,74.2)
  IN3 w0.508: v2(128.17,8.62) 130.08,8.62 137.34,15.88 v2(137.34,16.61)
  BOTTOM w0.254: UUS5.1 20.4,37.92 20.57,37.75 20.83,37.75 21,37.92 v2(21,38.04) ; UUS5.4 18.9,37.08 19.71,36.27 v2(20.97,36.27) ; v2(192.23,40.25) v2(191.09,40.25)
  BOTTOM w0.508: PR658.1 PC677.1 v2(170.26,94.91) ; v2(163.17,60.1) 162.64,59.57 PC661.1 PR655.1 ; v2(165.07,74.2) 165.31,74.44 166.96,74.44 PR634.1 ; JWDB1.4 137.6,16.87 v2(137.34,16.61)
  vias: v2(18.43,43.2) v2(18.43,42.57) v2(18.46,41.97) v2(18.99,42.36) v2(66.32,9.88) v2(66.93,9.88) v2(158.84,17.84) v2(159.26,18.26) v2(159.74,13.72) v2(159.98,13.17) v2(160.37,13.72) v2(160.62,13.17) v2(184.88,33.08) v2(184.88,32.44) v2(184.88,31.81) v2(185.51,33.08) v2(185.51,32.44) v2(185.51,31.81) v2(185.83,33.65) v2(186.15,34.16) v2(186.15,33.08) v2(186.15,32.44) v2(186.46,33.65) v2(186.78,34.16) v2(186.78,33.08) v2(191.48,64.07) v2(191.48,63.43) v2(192.24,64.07) v2(192.24,63.43) v2(192.24,62.8) v2(193.01,64.07) v2(193.01,63.43) v2(193.01,62.8) v2(193.77,64.07) v2(193.77,63.43) v2(193.77,62.8) v2(194.53,64.07) v2(194.53,63.43) v2(197.13,17.84) v2(197.13,17.2) v2(197.77,17.84) v2(197.77,17.2) v2(198.28,17.52) v4(189.61,36.8)
+5VALWP: length 31.5
  IN3 w0.254: v2(197.96,79.62) 197.96,69 195.82,66.86 v2(195.67,66.86) ; v2(195.8,78.97) 196.9,78.97 197.45,78.42 197.45,69.21 195.8,67.56 v2(195.67,67.56)
  BOTTOM w0.102: PC124.1 189.98,64.45 v1(189.37,63.84)
  BOTTOM w0.254: PR115.1 v2(197.96,79.62) 198.58,79.62 PR117.2 ; PU102.14 v2(195.8,78.97)
+5VS: length 153.5
  TOP w0.508: v2(206.02,49.33) 202.62,45.93 199.88,45.93 198.64,47.18 187.42,47.18 186.03,45.79 186.03,44.97 185.47,44.41 ; Q6201.3 44.47,29.76 44.12,30.11 v2(42.93,30.11)
  IN1 w1.524: 200.43,25.71 196.5,25.71 191.29,30.92 186.84,30.92 186.2,30.28 184.18,30.28 182.78,31.68 182.78,33.46
  IN2 w1.016: 199.04,74.48 198.59,74.04 198.59,62.99 195.48,59.88 195.48,54.8 188.31,47.62 188.31,43.07 182.93,37.7
  BOTTOM w0.254: JIO1.21 205.7,49.66 v2(206.02,49.33)
  BOTTOM w1.016: 29.33,74.29 31.59,74.29 36.73,79.43 36.73,80.14 40.44,83.85 41.71,83.85 44.1,86.24 44.1,88.45 46,90.36 55.08,90.36 59.63,94.91 59.63,102.89 56.23,106.29 54.58,106.29
  BOTTOM w1.524: 202.02,18.54 202.02,23.3
  vias: v2(22.06,26.03) v2(22.67,26.03) v2(26.13,74.43) v2(26.76,74.44) v2(30.31,37.56) v2(30.31,36.96) v2(35.65,26.87) v2(35.65,26.29) v2(53.62,106.61) v2(53.62,105.98) v2(128.78,14.64) v2(128.78,14.05) v2(182.68,36.71) v2(182.68,36.08) v2(182.68,35.44) v2(182.68,34.81) v2(183.32,36.71) v2(183.32,36.08) v2(183.32,35.44) v2(183.32,34.81) v2(183.9,35.78) v2(183.9,35.15) v2(199.55,75.81) v2(199.55,75.18) v2(201.45,24.82) v2(202.09,24.82) v2(202.72,24.82) v4(182.53,41.71)
+5VS_HDMI:
  vias: v1(22.75,71.9) v2(23.69,72.72) v2(23.69,72.04) v2(24.32,72.72) v2(24.32,72.04) v2(24.96,72.72) v2(24.96,72.04)
+17.4V_BATT+: length 46.6
  TOP w0.254: v2(168.99,43.62) 170.07,43.62 170.34,43.35 PR745.2 ; v2(174.91,60.32) 175.21,60.32 PQ710.3 175.92,62.29 PR780.2
  IN2 w0.254: v2(161.76,27.96) 159.92,29.8 159.92,33.35 168.99,42.41 v2(168.99,43.62) 168.99,52.85 169.85,53.71 169.85,58.5 171.67,60.32 v2(174.91,60.32)
  vias: v4(161.69,30.09)
+17.4V_BATT++: length 4
  TOP w0.102: v4(160.71,32.63) 160.19,32.63 159.21,31.66 ; v4(158.92,32.63) 158.28,32 v2(157.75,32) ; v2(157.09,32.01) 157.1,32.02 v4(157.1,32.63)
  vias: v2(155.72,30.81) v2(156.32,30.81) v2(156.43,31.41) v2(156.92,30.81) v2(157.03,31.41) v2(157.52,30.81) v2(157.64,31.41) v2(158.12,30.79) v2(158.25,31.4) v2(158.74,30.81)
+19V_ADPIN: length 4.4
  TOP w0.102: v2(197.76,84.42) v4(197.76,85.11) v4(197.76,86.88) 197.76,88.03 v4(198.34,88.62)
+19V_VIN: length 102.1
  TOP w0.127: PD704.2 v4(172.62,57.84)
  TOP w0.254: v2(173.57,59.16) PD704.2 ; v2(194.72,103.82) PR31.2 PR7.2 195.41,105.2 195.81,105.61 202.14,105.61 202.91,104.83 v4(202.91,104.07) PR5.1
  TOP w0.508: v2(182.07,44.74) 182.07,44.18 v4(182.02,44.13) 182.02,43 180.39,41.37 177.05,41.37 175.99,42.44 PR729.1
  IN1 w0.508: v2(194.31,90.74) 179.62,90.74 175.47,86.59 175.47,66.38 173.57,64.49 v2(173.57,59.16)
  IN3 w0.508: v2(173.57,59.16) 173.57,59.14 174.3,58.42 174.3,58.24 174.66,57.88 175.31,57.88 176.56,56.64 176.56,53.79 177.63,52.73 179.73,52.73 180.11,52.35 180.11,49.79 182.63,47.26 182.63,45.3 v2(182.07,44.74)
  BOTTOM w0.254: v2(194.72,103.82) 194.72,94.55
  vias: v2(194.36,91.41) v2(194.34,90.09) v2(194.97,91.46) v2(194.95,90.74) v2(194.97,90.09) v2(195.56,91.43) v2(195.53,90.71) v2(195.56,90.06)
+19VB: length 113.1
  TOP w0.381: PR102.2 v2(186.15,86.29)
  IN1 w5.08: 181.52,40.41 181.54,40.43 186.13,40.43 191.25,35.3 201.07,35.3
  BOTTOM w5.08: 183.99,108.39 198.43,108.39 199.93,106.89 205.36,106.89 209.32,102.93 209.32,97.21 ; 210.59,34.79 212.51,36.71 212.51,81.3 209.32,84.48 209.32,87.82
  vias: v2(60.04,110.48) v2(60.04,109.79) v2(60.73,110.48) v2(60.73,109.79) v2(61.43,110.48) v2(61.43,109.79) v2(76.41,108.83) v2(77.09,108.83) v2(77.73,108.83) v2(78.41,108.83) v2(98.81,113.29) v2(98.81,112.66) v2(98.81,112.02) v2(98.81,111.39) v2(99.44,113.29) v2(99.44,112.66) v2(99.44,112.02) v2(99.44,111.39) v2(156.11,37.41) v2(156.11,36.82) v2(156.11,36.22) v2(156.75,37.41) v2(156.75,36.82) v2(156.75,36.22) v2(163.81,40.55) v2(164.41,40.55) v2(164.44,41.17) v2(165.04,41.17) v2(165.01,40.55) v2(165.65,41.17) v2(165.61,40.55) v2(166.25,41.17) v2(177.96,105.6) v2(177.96,104.83) v2(178.59,105.6) v2(178.59,104.83) v2(179.23,105.6) v2(179.23,104.83) v2(179.86,105.6) v2(179.86,104.83) v2(204.31,34.16) v2(204.94,34.79) v2(204.94,34.16) v2(204.94,33.52) v2(205.58,34.79) v2(205.58,34.16) v2(205.58,33.52) v2(206.21,34.79) v2(206.21,34.16) v2(206.21,33.52) v4(102.64,112.58)
+19VB_1.2V: length 23.3
  TOP w0.203: PR208.1 63.53,103.15 62.93,103.74 62.93,108.55 66.35,111.97 71.71,111.97 v1(73.53,110.15) 73.53,109.95 76.22,107.26
  vias: v2(76.61,106.93) v2(76.61,106.29) v2(77.24,106.93) v2(77.24,106.29) v2(77.88,106.93) v2(77.88,106.29)
+19VB_+1VALW:
  vias: v2(148.36,31.78) v2(148.95,31.78) v4(148.78,33.05)
+VCC_CORE: length 41.5
  BOTTOM w0.102: UC1.K33 130.36,53.34 ; UC1.K33 130.03,53.01 ; UC1.K33 130.08,53.29 ; UC1.G40 131.62,56.66 ; UC1.G40 131.29,56.99 ; UC1.G40 131.58,56.95 ; UC1.AM37 119.05,55.17 ; UC1.AM37 119.05,54.5 ; UC1.AM37 119.38,54.83 ; UC1.AM37 118.72,54.83 ; 119.66,53.92 UC1.AK35 ; UC1.AK35 120.32,53.92 ; UC1.AK35 120.28,54.2 ; UC1.AK35 119.99,54.25 ; 119.05,55.42 UC1.AM38 ; UC1.AM38 119.38,55.75 ; UC1.AM38 119.05,56.08 ; UC1.AM38 118.72,55.75 ; 130.08,55.12 UC1.K37 ; UC1.K37 130.36,55.17 ; UC1.K37 130.03,54.83 ; 118.72,52.09 UC1.AM32 ; UC1.AM32 119.38,52.09 ; UC1.AM32 118.77,52.38 ; UC1.AM32 119.05,52.42 ; 131.29,55.42 UC1.G38 ; UC1.G38 131.62,55.75 ; UC1.G38 131.58,55.46 ; 119.66,53.01 UC1.AK33 ; UC1.AK33 120.28,52.72 ; UC1.AK33 120.32,53.01 ; UC1.AK33 119.99,52.68 ; 130.83,51.3 UC1.J30 ; UC1.J30 130.5,51.63 ; UC1.J30 130.83,51.96 ; UC1.J30 131.16,51.63 ; UC1.K42 130.36,57.91 ; UC1.K42 130.69,57.58 ; UC1.K42 130.36,57.25 ; UC1.K42 130.03,57.58 ; 119.53,54.05 UC1.AL37 ; UC1.AL37 119.86,54.38 ; UC1.AL37 119.2,54.38 ; UC1.AL37 119.53,54.71 ; 131.29,57.25 UC1.G42 ; UC1.G42 131.58,57.29 ; UC1.G42 130.96,57.58 ; UC1.G30 131.58,51.46 ; UC1.G30 130.96,51.18 ; UC1.G30 131.29,51.51 ; UC1.G30 131.62,51.18 ; UC1.AL40 119.53,56.54 ; UC1.AL40 119.2,56.21 ; UC1.AL40 119.86,56.21 ; UC1.AL40 119.53,55.88 ; UC1.AK40 120.32,56.66 ; UC1.AK40 119.66,56.66 ; UC1.AK40 119.99,56.33 ; UC1.AK40 120.28,56.38 ; UC1.K43 130.69,58.49 ; UC1.K43 130.08,58.21 ; UC1.K43 130.03,58.49 ; UC1.K43 130.36,58.16 ; UC1.G32 131.62,52.09 ; UC1.G32 130.96,52.09 ; UC1.G32 131.29,51.76 ; UC1.G32 131.58,51.81 ; UC1.K40 130.36,56.99 ; UC1.K40 130.08,56.95 ; UC1.K40 130.03,56.66 ; UC1.AM35 119.05,54.25 ; UC1.AM35 119.05,53.59 ; UC1.AM35 118.72,53.92 ; UC1.AM35 119.38,53.92 ; UC1.G35 131.62,53.92 ; UC1.G35 131.58,53.64 ; UC1.G35 131.29,53.59 ; 119.66,54.83 UC1.AK37 ; UC1.AK37 120.32,54.83 ; UC1.AK37 120.28,54.55 ; UC1.AK37 119.99,54.5 ; 119.05,52.68 UC1.AM33 ; UC1.AM33 119.05,53.34 ; UC1.AM33 118.72,53.01 ; UC1.AM33 119.38,53.01 ; UC1.J40 130.83,57.45 ; UC1.J40 131.16,57.12 ; UC1.J40 130.5,57.12 ; 130.36,55.42 UC1.K38 ; UC1.K38 130.08,55.46 ; UC1.K38 130.03,55.75 ; 130.5,55.29 UC1.J37 131.16,55.29 ; 119.66,55.75 UC1.AK38 ; UC1.AK38 119.99,56.08 ; UC1.AK38 120.28,56.03 ; UC1.AK38 120.32,55.75 ; 130.03,53.92 UC1.K35 ; UC1.K35 130.36,53.59 ; UC1.K35 130.08,53.64 ; 131.16,53.46 UC1.J33 130.5,53.46 ; 119.2,52.55 UC1.AL33 ; UC1.AL33 119.53,52.88 ; UC1.AL33 119.53,52.22 ; UC1.AL33 119.86,52.55 ; 131.29,55.17 UC1.G37 131.58,55.12 ; 131.58,53.29 UC1.G33 131.29,53.34
  BOTTOM w0.254: UC1.A30 v2(135.56,51.6) ; v2(136.11,58.96) 136.03,59.04 UC1.A44 ; UC1.A39 135.55,56.56 v2(135.57,56.58) ; UC1.A34 v2(135.57,54.08)
  BOTTOM w0.508: v2(138.65,52.57) 138.92,52.31 RC140.1
  vias: v2(118.66,56.18) v2(118.66,55.32) v2(118.73,54.28) v2(118.75,53.44) v2(118.73,52.54) v2(120.26,56.22) v2(120.47,54.68) v2(120.47,54.07) v2(120.47,52.85) v2(120.88,59.08) v2(120.84,56.27) v2(120.97,55.7) v2(121.01,51.85) v2(121.03,53.54) v2(121.02,52.45) v2(121.29,52.98) v2(121.43,56.26) v2(121.83,59.06) v2(121.9,52.98) v2(122.04,56.26) v2(122.51,52.97) v2(122.65,56.26) v2(123.86,57.59) v2(123.89,55.15) v2(123.89,52.77) v2(125.07,57.59) v2(125.09,55.15) v2(125.09,52.77) v2(126.27,57.59) v2(126.3,55.15) v2(126.3,52.77) v2(127.48,57.59) v2(127.51,55.15) v2(127.51,52.77) v2(128.69,57.59) v2(128.71,55.15) v2(129.29,58.06) v2(129.26,57.08) v2(129.25,56.18) v2(129.29,55.28) v2(129.29,54.38) v2(129.3,53.53) v2(129.33,52.55) v2(129.33,51.84) v2(129.75,57.5) v2(129.73,56.69) v2(129.76,55.74) v2(129.77,54.8) v2(129.78,53.93) v2(129.72,53.07) v2(130.15,58.04) v2(130.16,55.29) v2(130.16,53.46) v2(131.54,57.13) v2(131.54,55.29) v2(131.61,53.44) v2(131.61,51.62) v2(132.93,57.02) v2(133.15,57.68) v2(139.84,69.25) v2(141.81,65.69) v2(141.81,64.8) v2(141.81,63.91) v2(141.81,63.03) v2(141.81,62.14) v2(141.81,61.25) v2(141.81,60.36) v2(142.4,60.05) v2(142.45,66.2) v2(142.45,65.31) v2(142.45,64.42) v2(142.45,63.53) v2(142.45,62.64) v2(142.45,61.76) v2(142.45,60.87) v2(143.08,66.58) v2(143.08,65.69) v2(143.08,64.8) v2(143.08,63.91) v2(143.08,63.03) v2(143.08,62.14) v2(143.08,61.25) v2(143.08,60.36) v2(143.72,66.2) v2(143.72,65.31) v2(143.72,64.42) v2(143.72,63.53) v2(143.72,62.64) v2(143.72,61.76) v2(143.72,60.87) v2(145.44,66.16) v2(145.44,64.64) v2(145.44,63.11) v2(145.44,61.59) v2(146.97,70.33) v2(147.98,70.33) v2(148.01,69.43) v2(148.01,68.54) v2(148.62,66.16) v2(148.62,64.64) v2(148.62,63.11) v2(148.62,61.59) v2(148.9,69.43) v2(148.9,68.54) v2(149.79,69.43) v2(149.79,68.54) v2(150.45,70.33) v2(151.34,70.33) v2(151.73,66.16) v2(151.73,64.64) v2(151.73,63.11) v2(151.73,61.59) v2(152.23,70.33) v4(145.57,56.83)
+VCC_CORE_G0: length 1.1
  TOP w0.089: T122.1 v2(129.91,51.85)
  BOTTOM w0.076: v2(129.91,51.85) 130.15,52.09 UC1.K32
+VCC_CORE_G1: length 1.7
  TOP w0.089: T123.1 120.12,52.26 v2(120.48,52.26)
  BOTTOM w0.076: v2(120.48,52.26) 120.31,52.09 UC1.AK32
+VCC_FAN1: length 0.8
  TOP w0.127: v2(202.34,72.45) v4(202.34,73.21)
+VCC_GT: length 137.7
  TOP w0.508: RC340.1 124.36,91.63
  BOTTOM w0.102: 119.66,57.58 UC1.AK42 ; UC1.AK42 120.32,57.58 ; UC1.AK42 120.28,57.86 ; UC1.AK42 119.99,57.91 ; 126.42,72.23 UC1.U68 ; UC1.U68 126.76,72.56 ; UC1.U68 126.14,72.28 ; UC1.U68 126.71,72.85 ; 130.03,62.15 UC1.K50 ; UC1.K50 130.36,62.48 ; UC1.K50 130.36,61.82 ; UC1.K50 130.69,62.15 ; 126.55,68.84 UC1.T62 ; UC1.T62 126.88,68.51 ; UC1.T62 126.88,69.18 ; UC1.T62 127.21,68.84 ; 130.83,62.28 UC1.J50 ; UC1.J50 130.5,62.61 ; UC1.J50 131.16,62.61 ; UC1.J50 130.83,62.94 ; 130.5,59.86 UC1.J45 ; UC1.J45 131.16,59.86 ; UC1.J45 130.83,59.53 ; UC1.J45 130.83,60.19 ; 130.83,59.28 UC1.J43 130.5,58.95 ; 128.84,74.51 UC1.L71 ; UC1.L71 128.88,74.8 ; UC1.L71 128.88,74.23 ; UC1.AL60 119.53,67.51 ; UC1.AL60 119.2,67.18 ; UC1.AL60 119.53,66.85 ; UC1.AL60 119.86,67.18 ; 130.03,67.64 UC1.K60 ; UC1.K60 130.36,67.97 ; UC1.K60 130.36,67.31 ; UC1.K60 130.69,67.64 ; 123.4,74.8 UC1.AC71 ; UC1.AC71 124.01,74.51 ; UC1.AC71 123.97,74.23 ; UC1.AC71 123.97,74.8 ; UC1.N64 128.54,70.25 ; UC1.N64 128.25,70.29 ; UC1.N64 127.92,69.96 ; UC1.N64 128.58,69.96 ; UC1.AK45 120.32,59.41 ; UC1.AK45 120.28,59.69 ; UC1.AK45 119.66,59.41 ; UC1.AK45 119.99,59.74 ; 126.42,74.18 UC1.U71 ; UC1.U71 126.76,74.51 ; UC1.U71 126.14,74.23 ; UC1.U71 126.09,74.51 ; UC1.N66 128.54,71.55 ; UC1.N66 128.54,70.98 ; UC1.N66 128.58,71.26 ; 119.66,60.32 UC1.AK46 ; UC1.AK46 120.32,60.32 ; UC1.AK46 119.99,59.99 ; UC1.AK46 120.28,60.04 ; UC1.AA63 124.88,69.6 ; UC1.AA63 124.26,69.31 ; UC1.AA63 124.6,68.98 ; UC1.AA63 124.93,69.31 ; 124.26,73.86 UC1.AA70 ; UC1.AA70 124.88,74.15 ; UC1.AA70 124.93,73.86 ; UC1.AA70 124.31,73.58 ; UC1.N67 128.54,71.63 ; UC1.N67 128.58,71.91 ; UC1.N67 128.54,72.2 ; 128.88,73.58 UC1.L70 ; UC1.L70 128.88,74.15 ; UC1.L70 128.84,73.86 ; 127.01,71.26 UC1.R66 ; UC1.R66 127.05,70.98 ; UC1.R66 127.05,71.55 ; 129.17,68.98 UC1.L63 ; UC1.L63 128.84,69.31 ; UC1.L63 128.88,69.6 ; 119.99,58.16 UC1.AK43 ; UC1.AK43 120.32,58.49 ; UC1.AK43 120.28,58.21 ; UC1.AK43 119.66,58.49 ; UC1.AC64 123.87,69.96 124.02,70.11 ; UC1.AC69 123.97,72.93 ; UC1.AC69 124.01,73.21 ; UC1.AC69 123.97,73.5 ; 127.05,69.6 UC1.R63 ; UC1.R63 127.01,69.31 ; UC1.R63 127.34,68.98 ; UC1.K52 130.69,63.06 ; UC1.K52 130.36,63.39 ; UC1.K52 130.36,62.73 ; UC1.K52 130.03,63.06 ; UC1.R71 127.62,74.8 ; UC1.R71 127.01,74.51 ; UC1.R71 127.67,74.51 ; UC1.R71 127.05,74.23 ; UC1.AM50 119.38,62.15 ; UC1.AM50 119.05,62.48 ; UC1.AM50 118.72,62.15 ; UC1.AM50 119.05,61.82 ; 130.5,61.69 UC1.J48 ; UC1.J48 130.83,61.36 ; UC1.J48 131.16,61.69 ; UC1.J48 130.83,62.02 ; UC1.N70 128.58,73.86 ; UC1.N70 127.97,73.58 ; UC1.N70 128.54,74.15 ; UC1.N70 127.92,73.86 ; 130.83,64.77 UC1.J53 130.5,64.44 ; UC1.U65 126.71,70.9 ; UC1.U65 126.14,70.33 ; UC1.U65 126.42,70.28 ; UC1.U65 126.76,70.61 ; UC1.AA67 124.88,71.63 ; UC1.AA67 124.88,72.2 ; UC1.AA67 124.93,71.91 ; 118.77,66.09 UC1.AM56 ; UC1.AM56 119.05,66.14 ; UC1.AM56 119.38,65.81 ; UC1.AM56 119.05,65.48 ; 127.05,72.2 UC1.R67 ; UC1.R67 127.05,71.63 ; UC1.R67 127.01,71.91 ; 125.18,71.26 UC1.W66 ; UC1.W66 125.23,70.98 ; UC1.W66 125.23,71.55 ; 128.84,72.56 UC1.L68 ; UC1.L68 128.88,72.85 ; UC1.L68 128.88,72.28 ; UC1.AK55 120.32,64.89 ; UC1.AK55 119.66,64.89 ; UC1.AK55 120.28,65.18 ; UC1.AK55 119.99,65.22 ; 119.2,59.86 UC1.AL46 ; UC1.AL46 119.53,59.53 ; UC1.AL46 119.86,59.86 ; UC1.AL46 119.53,60.19 ; UC1.J55 130.83,65.68 ; UC1.J55 131.16,65.35 ; UC1.J55 130.5,65.35 ; UC1.J55 130.83,65.02 ; UC1.AK52 120.28,63.35 ; UC1.AK52 119.66,63.06 ; UC1.AK52 120.32,63.06 ; UC1.AK52 119.99,63.39 ; UC1.AA66 124.93,71.26 ; UC1.AA66 124.88,71.55 ; UC1.AA66 124.88,70.98 ; UC1.W71 125.79,74.8 ; UC1.W71 125.18,74.51 ; UC1.W71 125.84,74.51 ; UC1.W71 125.23,74.23 ; 129.34,68.56 UC1.L62 ; UC1.L62 129.29,68.84 ; UC1.L62 129.62,68.51 ; UC1.L62 129.96,68.84 ; 128.58,69.31 UC1.N63 128.54,69.6 ; 127.92,74.51 UC1.N71 ; UC1.N71 128.58,74.51 ; UC1.N71 128.54,74.8 ; UC1.N71 127.97,74.23 ; 128.88,71.55 UC1.L66 ; UC1.L66 128.84,71.26 ; UC1.L66 128.88,70.98 ; UC1.W64 125.79,70.25 ; UC1.W64 125.18,69.96 ; UC1.W64 125.23,69.68 ; UC1.W64 125.23,70.25 ; 130.5,68.09 UC1.J60 ; UC1.J60 130.83,67.76 ; UC1.J60 131.16,68.09 ; UC1.J60 130.83,68.42 ; 130.5,63.52 UC1.J52 130.83,63.19 ; UC1.AA71 124.93,74.51 ; UC1.AA71 124.31,74.23 ; UC1.AA71 124.88,74.8 ; UC1.AA71 124.26,74.51 ; 125.18,72.56 UC1.W68 ; UC1.W68 125.23,72.28 ; UC1.W68 125.23,72.85 ; UC1.W68 125.79,72.28 ; 127.05,72.85 UC1.R68 ; UC1.R68 127.62,72.85 ; UC1.R68 127.01,72.56 ; UC1.R68 127.05,72.28 ; 124.26,73.21 UC1.AA69 ; UC1.AA69 124.31,72.93 ; UC1.AA69 124.93,73.21 ; UC1.AA69 124.6,72.88 ; UC1.AC70 123.97,73.58 ; UC1.AC70 124.01,73.86 ; UC1.AC70 123.97,74.15 ; 119.2,63.52 UC1.AL53 ; UC1.AL53 119.53,63.19 ; UC1.AL53 119.53,63.85 ; UC1.AL53 119.86,63.52 ; 128.88,70.25 UC1.L64 ; UC1.L64 128.84,69.96 ; UC1.L64 128.88,69.68 ; UC1.R64 127.67,69.96 ; UC1.R64 127.01,69.96 ; UC1.R64 127.05,69.68 ; UC1.R64 127.62,70.25 ; UC1.M62 129.04,68.84 ; UC1.M62 129,68.56 ; UC1.M62 128.71,68.51 ; UC1.M62 128.71,69.18 ; UC1.Y62 125.38,68.84 ; UC1.Y62 125.05,68.51 ; UC1.Y62 125.05,69.18 ; UC1.Y62 124.72,68.84 ; UC1.AM52 119.05,63.39 ; UC1.AM52 119.05,62.73 ; UC1.AM52 119.38,63.06 ; UC1.AM52 118.72,63.06 ; 128.84,73.21 UC1.L69 ; UC1.L69 128.88,73.5 ; UC1.L69 128.88,72.93 ; 119.66,61.24 UC1.AK48 ; UC1.AK48 120.32,61.24 ; UC1.AK48 119.99,61.57 ; UC1.AK48 120.28,61.52 ; UC1.AC68 123.96,72.56 124.06,72.66 ; UC1.R70 127.62,74.15 ; UC1.R70 127.67,73.86 ; UC1.R70 127.05,73.58 ; UC1.R70 127.01,73.86 ; UC1.AK53 120.28,63.69 ; UC1.AK53 119.66,63.98 ; UC1.AK53 119.99,63.65 ; UC1.AK53 120.32,63.98 ; 128.84,71.91 UC1.L67 ; UC1.L67 128.88,71.63 ; UC1.L67 128.88,72.2 ; UC1.AM53 119.38,63.98 ; UC1.AM53 119.05,63.65 ; UC1.AM53 119.05,64.31 ; UC1.AM53 118.72,63.98 ; 130.03,61.24 UC1.K48 ; UC1.K48 130.36,61.57 ; UC1.K48 130.36,60.9 ; UC1.K48 130.69,61.24 ; UC1.AL56 119.53,65.68 ; UC1.AL56 119.53,65.02 ; UC1.AL56 119.2,65.35 ; UC1.AL56 119.86,65.35 ; UC1.K55 130.69,64.89 ; UC1.K55 130.36,64.56 ; UC1.K55 130.03,64.89 ; UC1.K55 130.36,65.22 ; 128.25,72.88 UC1.N69 ; UC1.N69 127.97,72.93 ; UC1.N69 128.58,73.21 ; UC1.N69 127.92,73.21 ; 130.5,60.78 UC1.J46 ; UC1.J46 130.83,61.11 ; UC1.J46 130.83,60.45 ; UC1.AC67 123.81,71.91 v2(124.14,71.59) 123.81,71.26 UC1.AC66 ; UC1.AM58 119.38,66.72 ; UC1.AM58 119.05,66.39 ; UC1.AM58 118.72,66.72 ; UC1.AM58 119.05,67.05 ; 127.05,72.93 UC1.R69 ; UC1.R69 127.67,73.21 ; UC1.R69 127.62,73.5 ; UC1.R69 127.01,73.21 ; 119.05,60.9 UC1.AM48 ; UC1.AM48 118.77,61.52 ; UC1.AM48 119.05,61.57 ; UC1.AM48 119.38,61.24 ; 125.23,73.5 UC1.W69 ; UC1.W69 125.23,72.93 ; UC1.W69 125.18,73.21 ; 130.03,63.98 UC1.K53 ; UC1.K53 130.36,64.31 ; UC1.K53 130.08,63.69 ; UC1.K53 130.36,63.65 ; 125.23,70.9 UC1.W65 ; UC1.W65 125.18,70.61 ; UC1.W65 125.23,70.33 ; UC1.W65 125.79,70.33 ; UC1.AK50 120.28,61.87 ; UC1.AK50 120.32,62.15 ; UC1.AK50 119.99,61.82 ; UC1.AK50 119.66,62.15 ; UC1.K56 130.69,65.81 ; UC1.K56 130.03,65.81 ; UC1.K56 130.36,65.48 ; UC1.K56 130.36,66.14 ; UC1.K58 130.69,66.72 ; UC1.K58 130.03,66.72 ; UC1.K58 130.36,66.39 ; UC1.K58 130.36,67.05 ; 127.05,70.33 UC1.R65 ; UC1.R65 127.67,70.61 ; UC1.R65 127.05,70.9 ; UC1.R65 127.01,70.61 ; 119.99,65.48 UC1.AK56 ; UC1.AK56 120.28,65.52 ; UC1.AK56 120.32,65.81 ; UC1.AK56 119.66,65.81 ; 125.18,71.91 UC1.W67 ; UC1.W67 125.79,72.2 ; UC1.W67 125.23,71.63 ; UC1.W67 125.23,72.2 ; 125.18,73.86 UC1.W70 ; UC1.W70 125.79,74.15 ; UC1.W70 125.23,73.58 ; UC1.W70 125.23,74.15 ; UC1.AL50 119.86,61.69 ; UC1.AL50 119.53,62.02 ; UC1.AL50 119.53,61.36 ; UC1.AL50 119.2,61.69 ; 128.84,70.61 UC1.L65 ; UC1.L65 128.88,70.33 ; UC1.L65 128.88,70.9 ; UC1.AA64 124.88,70.25 ; UC1.AA64 124.6,70.29 ; UC1.AA64 124.31,70.25 ; UC1.AA64 124.93,69.96 ; UC1.J58 131.16,67.18 ; UC1.J58 130.83,66.85 ; UC1.J58 130.5,67.18 ; UC1.J58 130.83,67.51 ; 119.2,58.03 UC1.AL43 ; UC1.AL43 119.53,57.7 ; UC1.AL43 119.53,58.37 ; UC1.AL43 119.86,58.03 ; 124.01,70.61 UC1.AC65 123.97,70.33 ; 119.66,67.64 UC1.AK60 119.99,67.31 ; 125.18,69.31 UC1.W63 ; UC1.W63 125.51,68.98 ; UC1.W63 125.23,69.6 ; UC1.AK58 120.28,67.01 ; UC1.AK58 120.32,66.72 ; UC1.AK58 119.66,66.72 ; UC1.AK58 119.99,67.05 ; UC1.J56 131.16,66.26 ; UC1.J56 130.5,66.26 ; UC1.J56 130.83,65.93 ; UC1.J56 130.83,66.6
  BOTTOM w0.203: v2(135.51,64.18) 135.18,64.18 UC1.A53 ; v2(135.93,71.53) 135.82,71.43 UC1.A66 ; UC1.A58 135.87,66.47 135.88,66.45 v2(135.88,66.44) ; v2(135.73,61.34) 135.17,61.34 UC1.A48 ; UC1.A62 v2(135.8,68.95) ; UC1.BB66 112.41,71.42 v2(111.72,72.11) ; v2(120.22,75.55) 120.2,75.55 120.2,75.2 120.17,75.18 UC1.AK70 ; UC1.AU58 116.11,66.42 v2(116.11,66.23) ; UC1.BB57 112.88,66.35 111.1,66.35 v2(110.79,66.67)
  BOTTOM w0.254: UC1.AU63 115.8,69.73 115.99,69.92 v2(116.74,69.92)
  vias: v2(118.72,67.19) v2(118.72,66.21) v2(118.74,63.52) v2(118.74,62.61) v2(118.74,61.69) v2(120.25,61.7) v2(120.27,59.88) v2(120.46,66.95) v2(120.54,65.6) v2(120.81,62.11) v2(120.77,61.32) v2(120.79,60.73) v2(120.79,60.14) v2(120.83,64.41) v2(120.81,62.84) v2(121.06,66.96) v2(121.2,65.62) v2(121.61,67.27) v2(121.96,63.54) v2(121.96,61.19) v2(122.98,67.41) v2(123.05,68.16) v2(123.16,63.54) v2(123.16,61.19) v2(123.62,68.41) v2(124.14,74.19) v2(124.14,73.56) v2(124.14,72.89) v2(124.37,65.95) v2(124.37,63.54) v2(124.37,61.19) v2(125,81.78) v2(125,80.51) v2(125,79.24) v2(125,77.97) v2(125,76.7) v2(125,75.43) v2(125.07,74.19) v2(125.05,73.54) v2(125.06,72.86) v2(125.07,72.22) v2(125.07,71.59) v2(125.07,70.95) v2(125.1,70.22) v2(125.45,68.4) v2(125.57,65.95) v2(125.57,63.54) v2(125.57,61.19) v2(125.91,72.27) v2(125.91,74.19) v2(125.94,70.28) v2(126.42,75.01) v2(126.78,65.95) v2(126.78,63.54) v2(126.78,61.19) v2(127.37,68.4) v2(127.82,73.5) v2(127.82,72.87) v2(127.84,71.62) v2(127.82,70.26) v2(127.92,81.78) v2(127.92,80.51) v2(127.92,79.24) v2(127.92,77.97) v2(127.92,76.7) v2(127.92,75.43) v2(127.99,65.95) v2(127.99,63.54) v2(127.99,61.19) v2(129.14,68.4) v2(129.19,65.95) v2(129.19,63.54) v2(129.19,61.19) v2(129.44,67.64) v2(129.81,68.16) v2(129.84,67.15) v2(129.84,66.27) v2(129.84,65.31) v2(129.84,64.42) v2(129.84,63.54) v2(129.84,62.58) v2(129.84,61.69) v2(129.84,60.8) v2(129.84,59.85) v2(129.84,59.03) v2(131.5,60.8) v2(143.42,87.12) v2(143.42,83.97) v2(144.44,87.12) v2(144.44,83.97) v2(145.86,86.02) v2(145.86,85.01) v2(146.71,93.91) v2(146.71,93.02) v2(146.71,92.13) v2(146.71,91.24) v2(146.71,90.36) v2(146.71,89.47) v2(146.71,88.58) v2(146.71,87.69) v2(147.48,94.42) v2(147.48,93.53) v2(147.48,92.64) v2(147.48,91.75) v2(147.48,90.86) v2(147.48,89.97) v2(147.48,89.09) v2(147.48,88.2) v2(147.82,86.02) v2(147.82,85.01) v2(148.11,93.91) v2(148.11,93.02) v2(148.11,92.13) v2(148.11,91.24) v2(148.11,90.36) v2(148.11,89.47) v2(148.11,88.58) v2(148.11,87.69) v2(149.1,87.12) v2(149.1,83.97) v2(149.83,93.91) v2(149.83,91.37) v2(149.83,88.83) v2(150.12,87.12) v2(150.12,83.97) v2(151.48,93.91) v2(151.48,91.37) v2(151.48,88.83) v2(151.44,86.02) v2(151.44,85.01) v2(152.3,93.91) v2(152.3,93.02) v2(152.3,92.13) v2(152.3,91.24) v2(152.3,90.36) v2(152.3,89.47) v2(152.3,88.58) v2(152.3,87.69) v2(152.3,86.8) v2(153.19,93.91) v2(153.19,88.58) v2(153.19,87.69) v2(153.19,86.8) v2(154.08,93.91) v2(154.08,88.58) v2(154.08,87.69) v2(154.08,86.8) v2(154.97,93.91) v2(154.97,88.58) v2(154.97,87.69) v2(154.97,86.8) v4(133.89,92.64)
+VCC_SA: length 8.3
  TOP w0.508: RC168.1 v2(143.58,41.09)
  IN1 w0.508: v2(143.58,41.09) 143.88,41.09 144.28,41.49 144.28,43.72 143.56,44.43 143.56,46.77 v2(142.78,47.56)
  vias: v2(120.47,48.35) v2(120.47,47.76) v2(121.84,48.68) v2(123.35,49.25) v2(124.56,49.25) v2(125.77,49.25) v2(126.97,49.25) v2(128.18,49.25) v2(129.9,50.03) v2(129.89,49.45) v2(129.99,47.98) v2(131.54,49.81) v2(131.54,47.96) v2(140.87,48.19) v2(140.87,47.56) v2(141,48.83) v2(141,46.92) v2(141.51,48.19) v2(141.51,47.56) v2(142.14,48.19) v2(142.14,47.56) v2(142.78,48.19) v4(131.09,48.95)
GND: length 2125.7
  TOP w0.127: v2(204.88,27.82) v4(204.88,28.63) ; v2(51.46,50.03) v4(52.31,50.03) ; v2(57.43,110.8) v4(56.8,110.8) ; v2(172.74,19.38) v4(172.74,18.61) ; v2(33.94,91.23) v4(33.94,91.88) ; CE77.2 v4(125.76,35.25) ; v2(26.84,65.17) v4(27.64,65.17) ; v2(216.9,22.13) v4(216.25,22.13) ; v2(157.02,68.62) 157,68.62 156.26,69.36 v4(156.26,69.53) ; v2(101.58,102.98) v4(102.31,102.98) ; v2(161.39,74.35) v4(161.39,75.17) ; v2(105.24,82.55) v4(105.24,81.78) ; v2(52.45,92.26) v4(52.45,92.9) ; v2(81.05,107.56) v4(82.26,107.56)
  TOP w0.203: PU200.3 v2(68.67,106.17) ; UE1.64 48.66,53.82 v2(48.72,53.88) ; PU200.1 69.47,105.68 v2(69.85,106.07) ; v2(49.15,48.67) 49.1,48.62 UE1.51
  TOP w0.254: UE1.100 31.52,52.63 v2(32.81,52.63) ; v2(218.91,32.89) 220.38,34.35 U5603.5 ; UE1.17 v2(39.54,41.23) ; CN19.2 222.36,34.91 222.28,34.98 221.9,34.98 ; UZ13.25 v2(44.4,75.11) ; U5603.7 221.72,34.8 221.9,34.98 ; v2(51.87,98.84) 52.21,98.5 EC5210.2 ; US2.3 v2(205.77,22.03) ; 221.9,34.98 221.58,35.3 U5603.8 ; v2(219.63,32.85) 220.88,34.09 U5603.6 ; CC178.2 v2(103.66,49.88) ; UZ2.11 192.23,43.78 v2(192.35,43.9) ; v2(41.81,70.23) 42.05,70.23 42.38,70.56 UZ13.18 ; RZ65.2 v2(46.63,77.97) ; v2(45.75,74.84) 45.46,75.13 CZ92.2 ; C5207.2 49.88,98.75 v2(49.77,98.86) ; v2(32.87,43.43) 32.46,43.02 UE1.124 ; UE1.84 v2(37.94,57.16) ; v2(133.86,66.43) 133.86,66.18 RC114.2 ; UZ21.5 v2(163.22,14.48)
  TOP w0.305: RC96.2 123.06,38.16 v2(123.6,38.16) ; JDEG1.10 24.73,56.37 v2(24.92,56.18) ; UZ19.5 162.87,17.63 163.16,17.33 v2(163.16,17.01)
  TOP w0.33: UC15.3 114.76,12.81 115.59,11.98 v2(115.59,11.26)
  TOP w0.356: v2(35.72,69.48) CZ98.2 36.3,70.57 36.31,70.56 UZ13.11 ; PQ709.4 v2(185.15,103.37)
  TOP w0.381: UC12.3 102.76,13.62 102.52,13.38 101.91,13.38 101.64,13.65 v2(101.64,14.37) ; CC1806.2 104.73,27.31 104.47,27.57 104.12,27.57 103.93,27.38 UC7.3 ; CE68.2 38.43,59.46 v2(37.99,59.46) 37.45,59.46 UE6.3 37.38,58.29 RE380.1 ; v2(120.47,36.75) 120.5,36.75 120.5,36.74 120.58,36.74 121.25,36.06 RC366.2 ; v2(168.86,111.84) 168.86,111.64 169.23,111.27 THM26.5 ; CC174.2 114.84,51.29 v2(114.39,51.74) ; v2(106.68,65.48) 106.68,65.85 106.48,66.05 105.69,66.05 105.41,65.77 CC175.2 ; PC1040.2 v2(120.22,64.44) ; v2(107.22,74.13) 107.22,74.53 107.09,74.66 CC255.2 ; v2(36.02,32.85) CA69.2 RA19.2 ; v2(129.95,35.36) 129.9,35.31 CC203.2 ; v2(127.94,39.04) 128.27,38.7 RC390.1 ; RA81.1 v2(35.67,28.25) ; JDEG1.12 21.26,55.37 v2(20.87,54.97) ; RE367.2 47.25,59.22 v2(47.25,59.8) ; JDEG1.11 v2(20.56,61.87) ; v2(201.34,103.82) PR10.1 201.3,103.09 PQ1.4 ; CC296.2 116.73,58.9 v2(116.68,58.95) ; CE65.2 CE71.2 42.1,35.86 42.75,35.21 v2(42.83,35.21) ; v2(46.42,59.88) 46.41,59.88 46.32,59.79 CE82.2 ; v2(120.47,53.46) 120.41,53.4 PC1096.2 119.94,53.39 PC1088.2 ; PR103.2 v2(186.78,82.39) ; v2(181.83,45.99) PQ721.3 ; CC1822.2 109.8,11.95 109.8,12.68 109.98,12.87 UC13.3 ; RC1109.1 100.4,28.85 99.14,28.85 98.33,28.04 v2(98.33,27.82) ; CC294.2 104.55,57.8 v2(104.54,57.79) ; v2(106.72,71.97) 106.72,72.24 106.35,72.6 105.64,72.6 105.48,72.44 CC258.2 ; PQ1.1 v2(200,98.79) ; UC14.3 105.22,82.57 v2(105.24,82.55) ; CE79.2 41.47,38.01 v2(42.03,38.56) ; v2(105.94,61.92) 105.94,61.65 105.52,61.22 CC176.2 ; CC293.2 103.34,53.8 v2(103.35,53.81) ; CC266.2 96.73,15.73 96.98,15.48 UZ6.3 ; v2(48.09,59.8) 48.16,59.72 CE74.2 ; PQ2.1 196.56,99.69 v2(196.24,99.37) ; CC295.2 104.99,70.07 v2(105,70.06) ; PQ720.3 v2(182.02,46.97) ; v2(198.72,103.82) PR33.1 198.1,103.2 197.86,102.96 PQ2.4
  TOP w0.457: CC25.2 100.99,28.01 v2(101.13,27.87) 101.13,27.55 RC48.2 ; CD1.2 70.8,29.32 v2(70.8,29.33) ; v2(55.37,60.44) 55.45,60.51 CD69.2 ; CD85.2 75.77,53.13 v2(75.75,53.15) ; v2(76.28,78.56) 76.44,78.72 CD82.2 ; CD6.2 58.44,58.34 v2(58.5,58.39) ; CC211.2 128.68,43.57 v2(128.58,43.67) ; v2(75.77,58.23) 75.78,58.21 CD5.2
  TOP w0.508: v2(55.43,30.33) 55.72,30.03 CD79.2 ; PR9.1 198.83,84.17 198.39,83.72 PQ5.3 197.81,82.9 v2(197.26,82.35) ; RE450.2 40.62,22.92 v2(40.11,22.41) ; PC753.1 176.44,53.53 PR755.1 177.31,53.51 PR752.1 177.32,54.27 v2(177.66,54.62) ; C5806.2 v2(182.91,55.9) ; v2(125,77.34) 124.62,77.34 PC1021.2 ; PC1001.2 145.82,60.95 v2(145.44,60.95) ; v2(36.45,20.06) 36.95,20.06 C6223.2 ; RD40.2 55.13,42.53 v2(55.43,42.83) 55.54,42.72 RH210.2 ; CE66.2 v2(51.46,49.14) ; v2(43.96,83.97) 43.42,84.5 RL4.2 ; CC1828.2 119.54,66.95 v2(120.22,66.26) ; v2(58.5,47.09) 57.66,47.92 57.14,47.92 56.52,47.3 RH212.2 ; PC504.2 51.96,6.34 52.35,6.74 v2(52.35,7.42) ; CE85.2 v2(42.29,61.72) ; v2(30.25,93.62) 30.01,93.37 CL46.1 ; v2(161.67,61.01) 161.97,61.3 PR608.2 PR611.2 ; v2(40.73,86.13) 40.91,86.13 41.47,86.69 CL4.2 CL2.2 ; C5201.2 v2(44.67,100.2) ; UE7.1 v2(79,113.28) ; v2(66.39,41.72) 66.56,41.89 RD30.2 ; EU3403.1 14.24,48.19 v2(14.18,48.25) ; PC213.2 v2(66.34,109.23) ; v2(212,21.47) 211.41,21.47 211.23,21.65 RS37.2 ; v2(151.73,65.53) 152.11,65.53 PC1002.2 ; v2(63.25,67.87) 63.7,68.32 CD71.2 ; CC23.2 105.33,35.24 v2(104.94,35.63) ; v2(95.29,13.57) 95.29,12.15 C6226.2 ; CC1831.2 121.58,75.15 v2(121.7,75.27) ; PC1174.2 149,60.95 v2(148.62,60.95) ; v2(59.26,55.11) 58.75,54.61 CD80.2 ; v2(119.28,42.5) 119.33,42.45 CC223.2 ; 31.27,78.48 v2(31.27,79.24) ; CC57.2 103.9,87.76 v2(104.3,87.37) ; v2(38.83,6.47) 39.04,6.69 PC507.2 ; PC1162.2 127.54,81.15 v2(127.92,81.15) ; v2(129.69,69.65) 129.05,69.01 CC1826.2 ; CE89.2 v2(33.72,36.15) ; PC1184.2 127.54,78.61 v2(127.92,78.61) ; RC341.2 v2(122.41,93.4) ; v2(207.52,29.27) 208.42,28.37 CS42.2 ; PC752.1 PC751.1 181.13,52.38 v2(181.13,51.62) ; CA30.2 29.52,15.57 DA13.1 29.56,13.91 v2(29.56,12.56) ; RD39.2 53.19,18.86 v2(53.01,19.03) ; CC1824.2 122.81,94.46 v2(123.03,94.46) ; C2608.2 v2(167.54,111.95) ; v2(121.96,42.34) 121.96,42.34 CC224.2 CC215.2 ; v2(35.79,76.03) CZ95.2 35.79,75.11 UZ13.4 ; v2(101.63,35.31) 101.63,34.27 CC26.2 ; CC1830.2 118.9,75.15 v2(118.76,75.29) 118.76,75.87 CC1829.2 ; RE397.2 44.17,35.76 CE91.2 43.38,35.76 v2(42.83,35.21) ; CL17.2 35.53,91.12 35.39,91.26 v2(35.1,91.26) ; v2(156.43,14.83) 156.73,15.13 CZ1705.2 ; CC270.2 99.44,23.76 v2(99.55,23.66) ; CD83.2 55.6,63.19 v2(55.37,63.42) ; CZ93.2 45.95,69.98 v2(46.82,69.98) ; v2(50.95,56.65) CE62.2 CE63.1 ; PC7.2 155.07,28.51 v2(154.59,28.99) 155.08,29.48 PC777.2 ; CC220.2 143.34,40.09 v2(143.74,39.68) ; CD75.2 70.91,54.73 v2(71.2,55.02) ; v2(30.33,75.19) 30.6,74.93 C3013.2 ; C3017.2 33.42,77.15 v2(32.46,77.15) ; v2(75.77,45.65) 75.77,45.65 CD81.2 ; PC748.2 v2(182.15,48.76) ; PC1022.2 150.84,94.29 v2(150.84,93.91) ; v2(42.14,89.15) 42.14,88.86 CL1.2 ; v2(130.91,42.49) 130.2,42.49 CC221.2 ; C6221.2 v2(181.83,56.76) ; v2(179.44,51.9) 179.56,51.78 PR753.1 PR727.2 ; R6517.2 v2(189.64,54.03) ; v2(28.98,41.89) 28.98,41.56 C5225.2 ; CD24.2 63.12,58.34 v2(63.07,58.39) ; R2504.2 v2(206.66,54.16) ; PC1061.2 149,64 v2(148.62,64) ; C6215.2 v2(212.88,6.92) ; v2(33.68,82.61) 33.68,82.53 33.23,82.07 CL11.2 C3015.2 ; v2(170.81,63.72) PR631.1 170.08,63.74 PC621.1 ; RH209.2 68.43,42.16 68.16,41.89 v2(68.16,41.74) ; v2(143.56,43.57) 143.35,43.79 RC166.2 ; RZ1708.1 45.89,67.56 45.44,67.11 v2(45.32,67.11) ; CD7.2 63.08,43.48 v2(63.07,43.47) ; CD73.2 v2(63.4,78.67) ; CD25.2 70.29,83.94 70.35,83.88 70.53,83.88 v2(70.63,83.78) ; PC1005.2 152.11,64 v2(151.73,64) ; v2(148.62,65.53) 149,65.53 PC1082.2 ; CC186.2 v2(172.74,19.38) ; CL6.2 32.8,82.82 v2(32.91,82.71) ; PQ3.3 194.99,99.99 195.43,99.55 PR32.2 v2(195.43,98.53) ; PC1026.2 150.84,91.75 v2(150.84,91.37) ; Q1901.3 103.8,23.95 v2(103.46,23.6) ; v2(155.93,20.1) 156.11,19.92 CZ87.2 CC59.2 ; PR204.2 v2(64.44,108.36) ; v2(149.19,93.91) 149.19,94.29 PC1025.2 ; RC1107.2 RC1105.2 97.2,24 v2(97.2,23.61) ; v2(145.44,64) 145.82,64 PC1071.2 ; v2(130.97,40.7) 130.97,40.38 131.47,39.87 RC3.2 ; CC1805.1 51.07,38.87 v2(51.51,38.43) ; CE84.1 31.4,37.78 v2(30.86,37.23) ; v2(121.75,32.81) 121.43,33.13 CC272.2 ; PC201.2 PC208.2 v2(80.37,106.34) ; CC218.2 128.9,39.07 v2(128.9,38.37) ; PC1156.2 124.62,78.61 v2(125,78.61) ; CD77.2 63.66,35.05 63.65,35.05 v2(63.44,35.05) ; CL16.2 v2(38.52,90.46) ; CD19.2 58.03,52.83 v2(58.48,53.28) ; v2(171.03,54.35) 170.64,53.96 PR751.1 PR779.1 ; v2(33.94,91.23) RL5.1 CL12.2 ; RD38.2 v2(53.86,22.51) ; PC1133.2 127.54,77.34 v2(127.92,77.34) ; PD4.1 202.34,82.99 v2(202.78,83.43) ; PC1143.2 144.17,50.08 v2(143.88,49.79) ; CE8.2 v2(53.69,46.86) ; CD74.2 79.67,68.5 v2(79.52,68.35) ; PC651.1 162.97,74.33 v2(162.97,74.33) ; C5803.2 v2(180.88,56.76) ; CE69.2 v2(50.84,44.95) ; CD22.2 76.04,42.14 75.45,42.14 74.95,41.65 v2(74.95,41.53) ; CZ44.2 190.83,45.78 v2(191.28,46.22) 191.79,45.71 CZ45.2 ; CD72.2 CD23.2 75.77,54.99 v2(75.77,54.99) ; v2(71.2,45.65) 71.13,45.59 CD17.2 ; C2602.2 v2(177.45,109.41) ; EC5206.2 49.44,92.41 v2(49.18,92.67) ; C5529.2 v2(221.44,4.5) ; v2(31.64,14.12) 31.64,14.87 31.89,15.12 CA32.2 ; v2(26.14,49) 26.14,48.53 RE398.2 ; v2(63.07,47.09) 63.09,47.08 CD84.2 ; PC202.2 v2(63.82,104.9) ; CD21.2 76.63,24.57 v2(76.17,24.11) ; CE1.2 v2(76.29,113.62) ; v2(46.64,22.87) 46.49,23.02 46.49,23.67 47.1,24.28 Q2405.3 ; CD26.2 63.09,55.1 v2(63.07,55.12) ; PC210.2 68.27,108.87 v2(67.28,109.86) ; v2(55.29,82.33) 55.58,82.04 CD87.2 ; v2(148.4,35.35) 148.82,35.35 PC302.2 ; CC265.2 91.06,13.39 91.52,12.94 C6225.2 91.93,11.67 v2(91.67,11.41) ; v2(40.1,91.31) 40.1,90.72 CL9.2 ; CC1810.2 v2(32.73,60.7) ; v2(28.15,52.33) 28.54,51.93 CE67.2 ; v2(148.62,62.48) 149,62.48 PC1173.2 ; RS23.2 v2(203.1,27.8) ; v2(177.78,44.37) PC711.1 PR732.2 ; v2(38.32,24.35) 37.77,23.79 CA64.1 ; v2(68.07,65.53) 68.13,65.53 68.23,65.43 CD2.2 ; CD86.2 75.78,43.48 v2(75.77,43.47) ; PC1081.2 145.82,62.48 v2(145.44,62.48) ; v2(207.29,16.26) 207.23,16.33 RS24.2 RS21.2 ; U5201.2 41.29,104.39 R5202.1 v2(41.99,104.4) ; v2(125,79.88) 124.62,79.88 PC1131.2 ; EC5205.2 v2(52.45,92.26) ; EU3404.1 v2(20.37,25.97) ; PR738.2 v2(185.4,97.34) ; RS31.2 v2(202.21,27.8) ; v2(121.08,45.63) 121.12,45.66 CC216.2 ; v2(30.26,45.98) 30.09,45.8 CE64.1 ; PC203.2 v2(63.81,105.81) ; CZ1702.2 115.27,15.6 v2(116.07,16.4) ; v2(151.73,62.48) 152.11,62.48 PC1006.2 ; CL7.2 v2(31.51,87.43) ; PC1141.2 v2(144.17,44.76) ; PD5.2 v2(207.53,81.1) ; CN20.2 v2(216.69,34.54) ; v2(39.34,36.63) C5224.2 39.41,35.86 CE65.2 ; RC75.1 97.45,9.94 98.69,9.94 v2(99.41,10.66) ; PC769.1 v2(168.37,49.14) ; v2(49.3,34.98) 49.3,34.52 R2611.2 ; v2(224.31,34.91) CN19.2 ; PC1027.2 149.19,91.75 v2(149.19,91.37) ; v2(131.35,72.1) 131.35,72.44 131.08,72.72 RC90.2 RC91.2 ; v2(200.75,17.94) RS35.2 CS27.2 ; CZ96.2 30.52,73.78 v2(30.15,73.41) ; CC1822.2 109.43,11.3 v2(109.43,10.78) ; CD91.2 66.44,60.52 v2(66.48,60.49) ; CC249.2 v2(170.83,19.38) ; v2(127.97,36.38) 127.03,35.43 CE77.2 ; PR29.2 v2(197.13,96.45) ; RZ1709.2 34.69,72.96 v2(33.81,72.96) ; PC1028.2 149.19,89.21 v2(149.19,88.83) ; CE86.2 38.28,62.64 v2(38.5,62.43) ; PC1183.2 124.62,76.07 v2(125,76.07) ; v2(161.39,74.35) 161.39,73.45 PC654.1 ; CC266.2 RC220.2 96.73,17.53 v2(97.1,17.9) ; EC9749.2 v2(57.43,109.91) ; CZ50.2 193.95,45.71 v2(193.44,46.22) 192.99,45.78 CZ23.2 ; PC601.2 157.04,68.66 157.02,68.64 v2(157.02,68.62) ; RC1126.2 68.89,61.83 v2(68.07,61.83) ; PR2.2 v2(199.23,96.45) ; PC1135.2 124.62,81.15 v2(125,81.15) ; v2(207.93,60.49) v4(209.18,59.23) 210.24,58.17 C2503.2 ; RA1116.2 v2(17.75,21.81) ; CC250.2 v2(169.88,19.38) ; v2(35.13,106.38) 34.57,105.82 C5204.2 ; v2(55.43,41.83) 55.45,41.84 CD29.2 ; CC248.2 v2(171.78,19.38) ; PC749.1 v2(181.13,50.62) ; RS36.2 RS18.2 v2(207.55,27.92) ; CL5.2 v2(31.65,90.48) ; v2(67.94,38.21) 68.14,38.21 RH211.2 ; v2(180.21,43.74) 180.21,43.48 179.71,42.97 PC768.1 179.53,42.99 PR731.2 ; RA1115.2 v2(23.84,13.04) ; v2(91.27,17.56) 91.61,17.9 CC207.2 ; CD8.2 63.07,53.26 v2(63.05,53.28) ; v2(33.09,78.89) 32.73,79.24 CL8.2 ; R6533.2 129.24,35.33 CC203.2 ; v2(75.77,47.11) 75.77,47.1 CD70.2 ; v2(145.44,65.53) 145.82,65.53 PC1076.2 ; CE2.2 v2(81.44,112.45) ; CC179.2 105.46,53.79 v2(105.45,53.81) ; CC1820.2 105.95,12.91 106.61,12.25 v2(106.61,11.72) ; PD6.2 v2(206.52,78.53) ; PQ711.3 v2(174.91,58.49) ; PC647.1 164.93,73.41 v2(164.62,73.72) ; CA57.2 v2(39.83,25.05) ; CZ97.2 v2(33.9,70.35) ; v2(75.7,49.02) 76.66,49.98 CD76.2 ; PC1221.2 127.54,79.88 v2(127.92,79.88) ; v2(178.18,107.93) 177.63,107.93 177.32,108.24 C2601.2 177.57,108.58 v2(178.1,108.58) ; RS22.1 v2(204.88,27.82) ; CC271.2 99.62,14.16 v2(99.86,14.4) ; PC757.1 v2(168.38,50.36) ; v2(28.64,37.87) 28.6,37.9 C5226.2 ; C6220.1 v2(16.55,45.51) ; CE75.2 v2(53.69,44) ; U3504.2 v2(17.3,38.24) ; C6219.2 v2(44.87,102.1) ; C3504.2 v2(16.09,42.6) ; PC1144.2 v2(142.9,49.78) ; PC790.2 v2(185.13,45.21) ; RC109.1 v2(144.25,75.98) ; CA58.2 v2(40.12,23.97) ; EC9716.2 v2(57.43,110.8) ; R3023.1 v2(28.98,77.63) ; C5206.1 v2(44.67,101.15) ; v2(25.53,54.6) 25.66,54.73 CE76.2 ; CC177.2 105.32,47.79 105.18,47.93 v2(105.18,48.26) ; v2(33.56,88.83) 33.23,89.16 CL3.2 ; CZ70.2 v2(165.78,14.73) ; CD20.2 74.95,33.83 v2(74.95,33.4) ; CZ94.2 v2(44.8,69.68) ; v2(105.88,27.86) 105.57,28.18 RC65.2 CC1806.2 ; v2(28.08,35.49) C6218.1 ; CE73.2 26.64,43.24 v2(26.18,43.7) 26.68,44.2 RE358.2 ; v2(122.02,76.59) 122.24,76.59 123.14,75.69 CC1832.2 ; RE355.2 v2(33.68,60.79) ; v2(127.92,76.07) 127.54,76.07 PC1159.2 127.18,75.71 CC1825.2 ; v2(58.52,60.68) 58.36,60.52 CD92.2 ; CC93.1 110.93,15.3 v2(111.74,16.11) ; CC251.2 v2(168.93,19.38) ; C5205.1 v2(57.95,103.25) ; C2609.2 v2(166.59,112.01) ; EC9753.2 v2(81.05,107.56) ; C5531.2 v2(221.42,3.49) ; v2(116.75,50.73) 117.03,51.01 CC185.2 ; PC128.2 v2(187.61,99.63) ; v2(100.7,22.37) 100.73,22.35 R1902.2 ; PC1145.2 v2(142.9,44.76) ; EC9752.2 v2(80.17,107.55) ; C5202.2 v2(57.56,102.17) ; PR122.2 v2(186.72,99.63) ; CD18.2 69.2,43.09 68.48,43.09 68.28,42.88 v2(68.14,42.88) ; RZ119.2 v2(36.92,66.97) ; CC252.2 v2(167.97,19.38) ; C229.1 v2(29.11,81.53) ; CE72.2 v2(51.46,50.03) ; C6217.2 v2(213.9,6.92) ; RE357.2 v2(38.5,61.02) ; v2(63.46,24.08) 63.96,24.57 CD78.2 ; v2(208.41,51.87) Q2505.3
  GND1 w0.203: 124.97,112.2 H4.1 ; H4.1 128.14,113.54 ; H4.1 126.8,114.03 ; H4.1 126.8,110.37 ; H4.1 125.46,110.86 ; H4.1 128.14,110.86 ; H4.1 128.63,112.2 ; H4.1 125.46,113.54 ; HNGFF.1 190.94,25.38 ; HNGFF.1 190.94,28.42 ; HNGFF.1 187.34,26.9 ; HNGFF.1 187.9,28.42 ; HNGFF.1 187.9,25.38 ; HNGFF.1 191.5,26.9 ; HNGFF.1 189.42,28.98 ; HNGFF.1 189.42,24.82 ; JUSB1.12 5.05,39.06 ; JUSB1.12 2.03,39.06 ; JUSB1.12 2.03,39.93 ; JUSB1.12 5.05,39.93 ; JUSB1.12 3.54,39.06 ; JHDMI.20 13.83,61.57 ; JHDMI.20 13.83,63.43 ; JHDMI.20 12.55,61.57 ; JHDMI.20 13.83,62.5 ; JHDMI.20 11.27,61.57 ; JHDMI.20 11.27,62.5 ; JHDMI.20 11.27,63.43 ; JHDMI.20 12.55,63.43 ; 111.82,21.38 HCPU3.1 ; HCPU3.1 111.82,25.96 ; HCPU3.1 110.15,22 ; HCPU3.1 110.15,25.34 ; HCPU3.1 109.53,23.67 ; HCPU3.1 113.49,22 ; HCPU3.1 113.49,25.34 ; HCPU3.1 114.11,23.67 ; JUSB1.13 13.81,55.23 ; JUSB1.13 10.79,55.23 ; JUSB1.13 10.79,54.36 ; JUSB1.13 10.79,56.09 ; JUSB1.13 13.81,54.36 ; JUSB1.13 12.3,56.09 ; JUSB1.13 13.81,56.09 ; JUSB1.13 12.3,54.36 ; H6.1 159.41,46.43 ; H6.1 161.18,42.23 ; H6.1 161.84,44 ; H6.1 159.41,41.57 ; H6.1 156.98,44 ; H6.1 161.18,45.77 ; H6.1 157.64,45.77 ; H6.1 157.64,42.23 ; HCPU4.1 138.73,23.67 ; HCPU4.1 133.57,21.43 ; HCPU4.1 138.73,25.91 ; HCPU4.1 136.15,21.43 ; HCPU4.1 133.57,25.91 ; HCPU4.1 133.57,23.67 ; HCPU4.1 136.15,25.91 ; HCPU4.1 138.73,21.43 ; 19.26,6.54 H7.1 ; H7.1 20.5,6.1 ; H7.1 19.26,9.02 ; H7.1 18.82,7.78 ; H7.1 21.74,9.02 ; H7.1 22.18,7.78 ; H7.1 20.5,9.46 ; H7.1 21.74,6.54 ; 15.1,22.92 JUSB2.4 ; JUSB2.4 15.74,24.39 ; JUSB2.4 15.74,23.12 ; JUSB2.4 15.93,23.75 ; JUSB2.4 15.1,24.58 ; JUSB2.4 14.47,24.39 ; 223.4,26.96 H8.1 ; H8.1 221.77,30.83 ; H8.1 221.77,27.57 ; H8.1 225.64,29.2 ; H8.1 225.03,30.83 ; H8.1 221.16,29.2 ; H8.1 223.4,31.44 ; H8.1 225.03,27.57 ; 10.27,73.25 JHDMI.17 ; JHDMI.17 11.43,73.25 ; JHDMI.17 11.31,73.71 ; JHDMI.17 10.39,73.71 ; JHDMI.17 10.39,72.79 ; JHDMI.17 11.31,72.79 ; 11.82,65.75 JHDMI.2 ; JHDMI.2 11.94,66.21 ; JHDMI.2 12.86,66.21 ; JHDMI.2 12.4,65.17 ; JHDMI.2 11.94,65.29 ; JHDMI.2 12.98,65.75 ; JHDMI.2 12.86,65.29 ; JHDMI.5 11.31,66.79 ; JHDMI.5 11.31,67.71 ; JHDMI.5 10.39,66.79 ; JHDMI.5 11.43,67.25 ; JHDMI.5 10.27,67.25 ; JHDMI.5 10.39,67.71 ; H1.1 211.84,110.86 ; H1.1 209.16,113.54 ; H1.1 208.67,112.2 ; H1.1 212.33,112.2 ; H1.1 210.5,110.37 ; H1.1 211.84,113.54 ; H1.1 209.16,110.86 ; H1.1 210.5,114.03 ; HCPU1.1 114.38,81.84 ; HCPU1.1 111.85,81.84 ; HCPU1.1 109.32,87.5 ; HCPU1.1 114.38,84.67 ; HCPU1.1 109.32,81.84 ; HCPU1.1 111.85,87.5 ; HCPU1.1 114.38,87.5 ; HCPU1.1 109.32,84.67 ; 12.3,39.56 JUSB1.11 ; JUSB1.11 12.3,41.29 ; JUSB1.11 10.79,39.56 ; JUSB1.11 10.79,41.29 ; JUSB1.11 13.81,41.29 ; JUSB1.11 13.81,40.43 ; JUSB1.11 13.81,39.56 ; JUSB1.11 10.79,40.43 ; JUSB1.14 5.05,56.59 ; JUSB1.14 5.05,55.73 ; JUSB1.14 3.54,56.59 ; JUSB1.14 2.03,56.59 ; JUSB1.14 2.03,55.73 ; JUSB2.10 16.03,34.48 ; JUSB2.10 16.03,32.82 ; JUSB2.10 14.35,34.48 ; JUSB2.10 16.03,33.65 ; JUSB2.10 14.35,32.82 ; 11.84,48.37 JUSB1.7 ; JUSB1.7 12.39,48.53 ; JUSB1.7 12.39,47.13 ; JUSB1.7 12.93,47.28 ; JUSB1.7 13.09,47.83 ; JUSB1.7 12.93,48.37 ; JUSB1.7 11.69,47.83 ; JUSB1.7 11.84,47.28 ; 4.62,35.1 JUSB2.13 ; JUSB2.13 5.9,35.93 ; JUSB2.13 7.18,35.93 ; JUSB2.13 7.18,35.1 ; JUSB2.13 4.62,35.93 ; 10.39,70.71 JHDMI.11 ; JHDMI.11 11.43,70.25 ; JHDMI.11 11.31,69.79 ; JHDMI.11 10.27,70.25 ; JHDMI.11 11.31,70.71 ; JHDMI.11 10.39,69.79 ; JHDMI.23 4.38,77.97 ; JHDMI.23 1.82,77.97 ; JHDMI.23 1.82,78.9 ; JHDMI.23 3.1,77.97 ; JHDMI.23 4.38,78.9 ; 158.07,113.54 H3.1 ; H3.1 160.75,110.86 ; H3.1 161.24,112.2 ; H3.1 159.41,114.03 ; H3.1 157.58,112.2 ; H3.1 160.75,113.54 ; H3.1 158.07,110.86 ; H3.1 159.41,110.37 ; HCPU2.1 137.77,83 ; HCPU2.1 138.39,84.67 ; HCPU2.1 134.43,83 ; HCPU2.1 136.1,86.96 ; HCPU2.1 133.81,84.67 ; HCPU2.1 134.43,86.34 ; HCPU2.1 137.77,86.34 ; HCPU2.1 136.1,82.38 ; 24.8,100.99 H5.1 ; H5.1 25.24,99.75 ; H5.1 28.16,100.99 ; H5.1 26.48,99.31 ; H5.1 26.48,102.67 ; H5.1 25.24,102.23 ; H5.1 27.72,102.23 ; H5.1 27.72,99.75 ; JUSB2.7 14.23,26.62 ; JUSB2.7 14.43,27.25 ; JUSB2.7 12.77,27.25 ; JUSB2.7 12.96,26.62 ; JUSB2.7 14.23,27.89 ; JUSB2.7 13.6,26.42 ; JUSB2.7 12.96,27.89 ; JUSB2.7 13.6,28.08 ; 11.27,77.93 JHDMI.22 ; JHDMI.22 13.83,76.07 ; JHDMI.22 11.27,76.07 ; JHDMI.22 12.55,76.07 ; JHDMI.22 13.83,77.93 ; JHDMI.22 12.55,77.93 ; JHDMI.22 11.27,77 ; JHDMI.22 13.83,77 ; JUSB2.11 16.03,20.85 ; JUSB2.11 16.03,21.68 ; JUSB2.11 14.35,21.68 ; JUSB2.11 16.03,20.02 ; JUSB2.11 14.35,20.02 ; JUSB1.4 11.63,43.78 ; JUSB1.4 11.63,44.87 ; JUSB1.4 10.54,44.87 ; JUSB1.4 11.09,45.03 ; JUSB1.4 11.79,44.33 ; 11.94,68.29 JHDMI.8 ; JHDMI.8 11.94,69.21 ; JHDMI.8 12.86,69.21 ; JHDMI.8 12.86,68.29 ; JHDMI.8 11.82,68.75 ; JHDMI.8 12.98,68.75 ; 3.07,60.6 JHDMI.21 ; JHDMI.21 4.35,61.53 ; JHDMI.21 4.35,59.67 ; JHDMI.21 3.07,59.67 ; JHDMI.21 5.63,59.67 ; JHDMI.21 5.63,61.53 ; JHDMI.21 3.07,61.53 ; JHDMI.21 5.63,60.6 ; 4.62,19.4 JUSB2.12 ; JUSB2.12 7.18,19.4 ; JUSB2.12 7.18,18.57 ; JUSB2.12 4.62,18.57 ; JUSB2.12 5.9,18.57
  VCC w0.203: 111.85,81.84 HCPU1.1 ; HCPU1.1 111.85,87.5 ; HCPU1.1 109.32,81.84 ; HCPU1.1 114.38,84.67 ; HCPU1.1 109.32,87.5 ; HCPU1.1 114.38,87.5 ; HCPU1.1 114.38,81.84 ; HCPU1.1 109.32,84.67
  VCC w0.254: 4.62,18.57 JUSB2.12 ; JUSB2.12 7.18,18.57 ; JUSB2.12 5.9,18.57 ; JUSB2.12 4.62,19.4 ; JUSB2.12 7.18,19.4 ; 3.07,59.67 JHDMI.21 ; JHDMI.21 4.35,61.53 ; JHDMI.21 3.07,61.53 ; JHDMI.21 5.63,60.6 ; JHDMI.21 4.35,59.67 ; JHDMI.21 5.63,59.67 ; JHDMI.21 3.07,60.6 ; JHDMI.21 5.63,61.53 ; 2.03,55.73 JUSB1.14 ; JUSB1.14 3.54,56.59 ; JUSB1.14 5.05,56.59 ; JUSB1.14 5.05,55.73 ; JUSB1.14 2.03,56.59 ; JHDMI.8 12.86,69.21 ; JHDMI.8 11.82,68.75 ; JHDMI.8 12.98,68.75 ; JHDMI.8 11.94,68.29 ; JHDMI.8 11.94,69.21 ; JHDMI.8 12.86,68.29 ; 10.39,70.71 JHDMI.11 ; JHDMI.11 10.27,70.25 ; JHDMI.11 11.43,70.25 ; JHDMI.11 11.31,69.79 ; JHDMI.11 10.39,69.79 ; JHDMI.11 11.31,70.71 ; JHDMI.5 11.31,67.71 ; JHDMI.5 10.39,66.79 ; JHDMI.5 10.27,67.25 ; JHDMI.5 11.43,67.25 ; JHDMI.5 11.31,66.79 ; JHDMI.5 10.39,67.71 ; JUSB1.7 12.93,48.37 ; JUSB1.7 11.84,47.28 ; JUSB1.7 12.39,48.53 ; JUSB1.7 12.93,47.28 ; JUSB1.7 13.09,47.83 ; JUSB1.7 12.39,47.13 ; JUSB1.7 11.69,47.83 ; JUSB1.7 11.84,48.37 ; JUSB2.11 14.35,21.68 ; JUSB2.11 14.35,20.02 ; JUSB2.11 16.03,21.68 ; JUSB2.11 16.03,20.02 ; JUSB2.11 16.03,20.85 ; 10.79,56.09 JUSB1.13 ; JUSB1.13 10.79,55.23 ; JUSB1.13 10.79,54.36 ; JUSB1.13 13.81,55.23 ; JUSB1.13 12.3,54.36 ; JUSB1.13 12.3,56.09 ; JUSB1.13 13.81,56.09 ; JUSB1.13 13.81,54.36 ; JUSB1.11 12.3,41.29 ; JUSB1.11 13.81,40.43 ; JUSB1.11 10.79,39.56 ; JUSB1.11 12.3,39.56 ; JUSB1.11 10.79,41.29 ; JUSB1.11 10.79,40.43 ; JUSB1.11 13.81,41.29 ; JUSB1.11 13.81,39.56 ; 11.94,65.29 JHDMI.2 ; JHDMI.2 12.98,65.75 ; JHDMI.2 12.4,65.17 ; JHDMI.2 12.86,65.29 ; JHDMI.2 11.82,65.75 ; JHDMI.2 11.94,66.21 ; JHDMI.2 12.86,66.21 ; H8.1 225.64,29.2 ; H8.1 221.77,27.57 ; H8.1 223.4,26.96 ; H8.1 221.16,29.2 ; H8.1 225.03,27.57 ; H8.1 225.03,30.83 ; H8.1 221.77,30.83 ; H8.1 223.4,31.44 ; JUSB2.10 14.35,34.48 ; JUSB2.10 16.03,34.48 ; JUSB2.10 16.03,32.82 ; JUSB2.10 14.35,32.82 ; JUSB2.10 16.03,33.65 ; 12.77,27.25 JUSB2.7 ; JUSB2.7 14.43,27.25 ; JUSB2.7 13.6,26.42 ; JUSB2.7 13.6,28.08 ; JUSB2.7 12.96,26.62 ; JUSB2.7 14.23,27.89 ; JUSB2.7 14.23,26.62 ; JUSB2.7 12.96,27.89 ; JHDMI.20 13.83,61.57 ; JHDMI.20 11.27,63.43 ; JHDMI.20 13.83,62.5 ; JHDMI.20 11.27,62.5 ; JHDMI.20 12.55,61.57 ; JHDMI.20 12.55,63.43 ; JHDMI.20 11.27,61.57 ; JHDMI.20 13.83,63.43 ; 15.1,22.92 JUSB2.4 ; JUSB2.4 14.47,24.39 ; JUSB2.4 15.93,23.75 ; JUSB2.4 15.74,23.12 ; JUSB2.4 15.74,24.39 ; JUSB2.4 15.1,24.58 ; 2.03,39.93 JUSB1.12 ; JUSB1.12 3.54,39.06 ; JUSB1.12 5.05,39.93 ; JUSB1.12 5.05,39.06 ; JUSB1.12 2.03,39.06 ; JUSB1.4 11.79,44.33 ; JUSB1.4 11.63,43.78 ; JUSB1.4 11.09,45.03 ; JUSB1.4 11.63,44.87 ; JHDMI.17 11.31,72.79 ; JHDMI.17 11.31,73.71 ; JHDMI.17 11.43,73.25 ; JHDMI.17 10.39,73.71 ; JHDMI.17 10.27,73.25 ; JHDMI.17 10.39,72.79 ; JHDMI.22 13.83,77.93 ; JHDMI.22 11.27,76.07 ; JHDMI.22 12.55,76.07 ; JHDMI.22 11.27,77.93 ; JHDMI.22 11.27,77 ; JHDMI.22 13.83,77 ; JHDMI.22 12.55,77.93 ; JHDMI.22 13.83,76.07 ; JUSB2.13 7.18,35.93 ; JUSB2.13 5.9,35.93 ; JUSB2.13 4.62,35.1 ; JUSB2.13 4.62,35.93 ; JUSB2.13 7.18,35.1 ; 1.82,78.9 JHDMI.23 ; JHDMI.23 3.1,77.97 ; JHDMI.23 1.82,77.97 ; JHDMI.23 4.38,78.9 ; JHDMI.23 4.38,77.97
  GND2 w0.203: H3.1 159.41,114.03 ; H3.1 158.07,110.86 ; H3.1 160.75,110.86 ; H3.1 157.58,112.2 ; H3.1 161.24,112.2 ; H3.1 160.75,113.54 ; H3.1 158.07,113.54 ; H3.1 159.41,110.37 ; 11.94,65.29 JHDMI.2 ; JHDMI.2 12.4,65.17 ; JHDMI.2 12.86,66.21 ; JHDMI.2 12.98,65.75 ; JHDMI.2 11.82,65.75 ; JHDMI.2 12.86,65.29 ; JHDMI.2 11.94,66.21 ; 11.27,77 JHDMI.22 ; JHDMI.22 13.83,77 ; JHDMI.22 12.55,77.93 ; JHDMI.22 13.83,76.07 ; JHDMI.22 12.55,76.07 ; JHDMI.22 11.27,76.07 ; JHDMI.22 11.27,77.93 ; JHDMI.22 13.83,77.93 ; JUSB1.7 13.09,47.83 ; JUSB1.7 11.84,48.37 ; JUSB1.7 12.39,48.53 ; JUSB1.7 11.69,47.83 ; JUSB1.7 12.93,47.28 ; JUSB1.7 12.93,48.37 ; JUSB1.7 11.84,47.28 ; JUSB1.7 12.39,47.13 ; JUSB2.10 14.35,34.48 ; JUSB2.10 14.35,32.82 ; JUSB2.10 16.03,34.48 ; JUSB2.10 16.03,32.82 ; JUSB2.10 16.03,33.65 ; JHDMI.21 5.63,61.53 ; JHDMI.21 3.07,59.67 ; JHDMI.21 4.35,59.67 ; JHDMI.21 3.07,60.6 ; JHDMI.21 4.35,61.53 ; JHDMI.21 3.07,61.53 ; JHDMI.21 5.63,59.67 ; JHDMI.21 5.63,60.6 ; 109.32,81.84 HCPU1.1 ; HCPU1.1 114.38,87.5 ; HCPU1.1 109.32,84.67 ; HCPU1.1 114.38,81.84 ; HCPU1.1 111.85,81.84 ; HCPU1.1 109.32,87.5 ; HCPU1.1 114.38,84.67 ; HCPU1.1 111.85,87.5 ; 159.41,41.57 H6.1 ; H6.1 161.18,45.77 ; H6.1 161.18,42.23 ; H6.1 161.84,44 ; H6.1 159.41,46.43 ; H6.1 157.64,42.23 ; H6.1 157.64,45.77 ; H6.1 156.98,44 ; JUSB1.13 13.81,55.23 ; JUSB1.13 13.81,54.36 ; JUSB1.13 10.79,56.09 ; JUSB1.13 10.79,55.23 ; JUSB1.13 12.3,56.09 ; JUSB1.13 12.3,54.36 ; JUSB1.13 10.79,54.36 ; JUSB1.13 13.81,56.09 ; H5.1 28.16,100.99 ; H5.1 27.72,102.23 ; H5.1 26.48,99.31 ; H5.1 25.24,102.23 ; H5.1 26.48,102.67 ; H5.1 27.72,99.75 ; H5.1 24.8,100.99 ; H5.1 25.24,99.75 ; 5.9,18.57 JUSB2.12 ; JUSB2.12 7.18,18.57 ; JUSB2.12 4.62,19.4 ; JUSB2.12 7.18,19.4 ; JUSB2.12 4.62,18.57 ; 10.79,41.29 JUSB1.11 ; JUSB1.11 12.3,41.29 ; JUSB1.11 10.79,39.56 ; JUSB1.11 13.81,40.43 ; JUSB1.11 10.79,40.43 ; JUSB1.11 13.81,39.56 ; JUSB1.11 12.3,39.56 ; JUSB1.11 13.81,41.29 ; JUSB2.11 14.35,21.68 ; JUSB2.11 16.03,20.02 ; JUSB2.11 16.03,21.68 ; JUSB2.11 14.35,20.02 ; JUSB2.11 16.03,20.85 ; 12.77,27.25 JUSB2.7 ; JUSB2.7 12.96,27.89 ; JUSB2.7 14.23,26.62 ; JUSB2.7 13.6,26.42 ; JUSB2.7 14.43,27.25 ; JUSB2.7 12.96,26.62 ; JUSB2.7 14.23,27.89 ; JUSB2.7 13.6,28.08 ; 133.57,23.67 HCPU4.1 ; HCPU4.1 138.73,21.43 ; HCPU4.1 138.73,25.91 ; HCPU4.1 133.57,25.91 ; HCPU4.1 136.15,21.43 ; HCPU4.1 138.73,23.67 ; HCPU4.1 133.57,21.43 ; HCPU4.1 136.15,25.91 ; HCPU2.1 138.39,84.67 ; HCPU2.1 137.77,83 ; HCPU2.1 136.1,82.38 ; HCPU2.1 137.77,86.34 ; HCPU2.1 134.43,86.34 ; HCPU2.1 133.81,84.67 ; HCPU2.1 134.43,83 ; HCPU2.1 136.1,86.96 ; H8.1 225.03,30.83 ; H8.1 223.4,26.96 ; H8.1 221.16,29.2 ; H8.1 221.77,30.83 ; H8.1 223.4,31.44 ; H8.1 221.77,27.57 ; H8.1 225.64,29.2 ; H8.1 225.03,27.57 ; H1.1 211.84,113.54 ; H1.1 209.16,113.54 ; H1.1 211.84,110.86 ; H1.1 210.5,110.37 ; H1.1 212.33,112.2 ; H1.1 210.5,114.03 ; H1.1 209.16,110.86 ; H1.1 208.67,112.2 ; 11.27,63.43 JHDMI.20 ; JHDMI.20 13.83,63.43 ; JHDMI.20 11.27,62.5 ; JHDMI.20 13.83,61.57 ; JHDMI.20 13.83,62.5 ; JHDMI.20 12.55,63.43 ; JHDMI.20 12.55,61.57 ; JHDMI.20 11.27,61.57 ; 2.03,39.06 JUSB1.12 ; JUSB1.12 3.54,39.06 ; JUSB1.12 2.03,39.93 ; JUSB1.12 5.05,39.93 ; JUSB1.12 5.05,39.06 ; 1.82,78.9 JHDMI.23 ; JHDMI.23 4.38,78.9 ; JHDMI.23 1.82,77.97 ; JHDMI.23 4.38,77.97 ; JHDMI.23 3.1,77.97 ; JUSB1.14 5.05,56.59 ; JUSB1.14 3.54,56.59 ; JUSB1.14 2.03,55.73 ; JUSB1.14 2.03,56.59 ; JUSB1.14 5.05,55.73 ; 10.54,44.87 JUSB1.4 ; JUSB1.4 11.79,44.33 ; JUSB1.4 11.09,45.03 ; JUSB1.4 11.63,44.87 ; JUSB1.4 11.63,43.78 ; HNGFF.1 191.5,26.9 ; HNGFF.1 187.9,28.42 ; HNGFF.1 189.42,24.82 ; HNGFF.1 187.34,26.9 ; HNGFF.1 190.94,28.42 ; HNGFF.1 189.42,28.98 ; HNGFF.1 187.9,25.38 ; HNGFF.1 190.94,25.38 ; 10.39,66.79 JHDMI.5 ; JHDMI.5 11.43,67.25 ; JHDMI.5 11.31,67.71 ; JHDMI.5 10.27,67.25 ; JHDMI.5 11.31,66.79 ; JHDMI.5 10.39,67.71 ; 109.53,23.67 HCPU3.1 ; HCPU3.1 110.15,25.34 ; HCPU3.1 113.49,25.34 ; HCPU3.1 114.11,23.67 ; HCPU3.1 110.15,22 ; HCPU3.1 111.82,21.38 ; HCPU3.1 111.82,25.96 ; HCPU3.1 113.49,22 ; 10.27,70.25 JHDMI.11 ; JHDMI.11 11.43,70.25 ; JHDMI.11 11.31,69.79 ; JHDMI.11 10.39,70.71 ; JHDMI.11 10.39,69.79 ; JHDMI.11 11.31,70.71 ; 125.46,113.54 H4.1 ; H4.1 125.46,110.86 ; H4.1 128.14,110.86 ; H4.1 126.8,114.03 ; H4.1 128.63,112.2 ; H4.1 128.14,113.54 ; H4.1 124.97,112.2 ; H4.1 126.8,110.37 ; 14.47,24.39 JUSB2.4 ; JUSB2.4 15.1,22.92 ; JUSB2.4 15.1,24.58 ; JUSB2.4 15.93,23.75 ; JUSB2.4 15.74,24.39 ; JUSB2.4 15.74,23.12 ; 10.39,72.79 JHDMI.17 ; JHDMI.17 11.31,72.79 ; JHDMI.17 11.43,73.25 ; JHDMI.17 11.31,73.71 ; JHDMI.17 10.27,73.25 ; JHDMI.17 10.39,73.71 ; H7.1 20.5,9.46 ; H7.1 19.26,9.02 ; H7.1 21.74,6.54 ; H7.1 19.26,6.54 ; H7.1 22.18,7.78 ; H7.1 21.74,9.02 ; H7.1 18.82,7.78 ; H7.1 20.5,6.1 ; JHDMI.8 12.98,68.75 ; JHDMI.8 11.94,69.21 ; JHDMI.8 11.82,68.75 ; JHDMI.8 12.86,68.29 ; JHDMI.8 12.86,69.21 ; JHDMI.8 11.94,68.29 ; JUSB2.13 7.18,35.1 ; JUSB2.13 4.62,35.93 ; JUSB2.13 7.18,35.93 ; JUSB2.13 4.62,35.1 ; JUSB2.13 5.9,35.93
  BOTTOM w0.089: 135.96,52.59 134.82,52.59 134.82,52.59 134.53,52.59 134.46,52.51 134.28,52.51 134.2,52.59 133.89,52.59 133.82,52.52 133.54,52.52 133.35,52.71 133.35,52.81 132.76,53.41 132.45,53.41 UC1.F35 ; 136.33,55.23 135.14,55.23 134.94,55.03 134.22,55.03 134.19,55.05 133.82,55.05 133.8,55.03 133.5,55.03 133.4,55.12 132.23,55.12 UC1.F37
  BOTTOM w0.127: v2(195.61,18.47) 195.46,18.47 v4(194.82,17.84) ; v2(174.04,99.8) v4(174.04,100.79) ; v2(66.51,102.23) 65.88,102.23 v4(65.81,102.17) ; v2(157.02,69.6) 157,69.62 v4(157,70.29) ; RE451.2 v4(27.97,39.68) ; PC217.2 v4(85.18,96.81) ; UC1.BB60 112.15,67.74 v2(112.11,67.78) ; v2(64.35,99.31) v4(63.59,99.31) ; v2(57.2,10.98) v4(58.07,10.98) ; v4(168,58.1) v2(167.29,58.1)
  BOTTOM w0.152: v2(116.54,75.21) 116.49,75.16 UC1.AT71 ; v2(112.11,72.77) 112.69,72.19 UC1.BB67 ; UC1.AG71 121.5,74.36 121.53,74.39 121.53,74.82 121.6,74.89 121.6,75.17 v2(121.7,75.27)
  BOTTOM w0.178: UC1.BB26 112.26,48.04 112.21,47.98 v2(112.05,47.98) ; v2(111.42,53.06) 111.46,53.02 112.74,53.02 UC1.BB34 ; v2(118.76,75.29) 118.84,75.2 118.84,74.47 UC1.AM71 ; v2(112.06,58) 112.08,57.97 UC1.BB43
  BOTTOM w0.203: UC1.AW43 114.96,57.49 114.99,57.46 114.99,57.16 114.96,57.13 UC1.AW41 115,56.67 v2(115.47,56.21) 114.96,55.7 UC1.AW38 114.96,54.98 114.99,54.95 114.99,54.66 114.96,54.63 UC1.AW36 114.96,53.76 114.99,53.73 114.99,53.43 114.96,53.4 UC1.AW34 ; UC1.AW12 114.96,40.76 115.07,40.87 115.07,41.34 114.96,41.44 UC1.AW14 ; UC1.AV68 115.32,72.2 116.45,72.2 UC1.AT68 ; UC1.AW49 114.96,61.88 115.06,61.97 115.06,62.25 114.96,62.35 UC1.AW51 ; UC1.AW60 114.96,67.94 115.02,68 115.02,68.56 114.96,68.62 UC1.AW62 ; UC1.AW21 115.03,45.54 115.03,46.29 114.96,46.36 UC1.AW23 ; UC1.AW28 114.96,48.81 115.03,48.74 115.03,48 UC1.AW26 ; UC1.C1 v2(134.35,33.35) ; v2(120.22,62.61) UC1.AL52 ; UC1.H71 v2(131.1,75.06) ; v2(113.15,33.37) UC1.BA1 113.25,33.99 113.25,34.45 UC1.BA2 113.46,34.52 113.97,35.03 UC1.AY3 ; v2(121.75,32.81) 121.86,32.93 UC1.AF1 ; UC1.AW16 114.96,43.35 115.05,43.44 115.05,43.83 114.96,43.92 UC1.AW18 114.96,44.57 115.26,44.87 ; UC1.AW6 114.95,37.09 113.8,37.09 UC1.BA6 UC1.BB6 112.22,37.03 v2(112.13,36.93) ; UC1.BB30 111.98,50.39 v2(111.84,50.26) ; v2(120.22,66.26) UC1.AL58 ; UC1.AW32 114.96,51.35 115.07,51.24 115.07,50.6 UC1.AW30 ; UC1.AH67 120.29,72.56 UC1.AK68 120.1,72.56 119.69,72.15 119.42,72.15 119.33,72.24 UC1.AM68 118.89,72.18 117.73,72.18 UC1.AP68 ; v2(112.17,44.3) 112.18,44.29 UC1.BB18 UC1.BA18 ; v2(111.99,55.33) 112.03,55.37 UC1.BB38 ; UC1.F40 v2(131.54,56.21) UC1.F38 ; v2(120.22,64.44) UC1.AL55 ; v2(115.56,33.4) 115.17,33.78 UC1.AV1 ; v2(112.05,65.14) 112.05,65.14 UC1.BB55 ; v2(112.16,70.13) 112.2,70.1 UC1.BB64 ; v2(120.22,60.78) UC1.AL48
  BOTTOM w0.254: v2(118.72,46.15) 118.72,46.03 UC1.AM21 ; JIO1.3 v2(205.89,58.66) ; UC1.AU32 115.76,52.09 v2(115.36,52.49) ; UC1.AW34 114.96,52.89 v2(115.36,52.49) ; v2(120.48,69.66) UC1.AK63 UC1.AM61 ; v2(120.48,69.66) 120.83,69.31 UC1.AH63 ; v2(120.48,69.66) 120.78,69.96 UC1.AH64 ; v2(125.78,38.45) 125.66,38.57 UC1.W9 ; UC1.N6 128.21,36.62 v2(127.97,36.38) 127.81,36.54 127.41,36.54 UC1.R6 127.33,36.13 127.16,35.96 UC1.T4 127.44,35.56 127.44,35.14 UC1.T2 ; UC1.AK68 120.17,72.83 v2(119.95,73.05) 120.17,73.27 UC1.AK69 ; UC1.AA65 v2(124.13,71) ; UC1.AD19 UC1.AD20 123.21,45.26 v2(123.58,45.63) ; UC1.BB70 112.6,74.14 v2(112.6,74.82) 112.84,74.82 UC1.BA71 UC1.AY71 ; v2(131.54,47.06) UC1.G22 UC1.K22 ; v2(131.54,47.06) 131.54,47.11 131.9,47.52 UC1.F23 ; v2(131.54,47.06) 131.54,47.03 131.91,46.6 UC1.F22 ; v2(118.04,53.43) 117.75,53.72 UC1.AP35 UC1.AR35 UC1.AT35 ; v2(118.04,53.43) 118.4,53.8 UC1.AN35 ; v2(118.04,53.43) 118.4,53.07 UC1.AN33 ; RN5203.3 42.27,93.91 42.15,93.79 v2(42.15,93.63) ; UC1.D6 133.49,36.92 v2(133.85,36.92) 133.85,36.31 UC1.C5 ; v2(118.06,58.01) 118.4,57.66 UC1.AN42 118.08,57.26 v2(118.08,57.1) 118.08,56.98 UC1.AN40 ; v2(118.06,58.01) v2(117.41,58.01) ; v2(118.06,58.01) 117.75,57.7 UC1.AP42 ; UC1.J8 130.33,38.03 v2(130.33,37.97) ; UC1.AF2 UC1.AF1 ; v2(120.42,39.56) 120.11,39.87 UC1.AK11 119.54,39.41 119.54,38.86 UC1.AM8 ; UC1.B48 134.13,61.3 v2(133.88,61.3) 133.67,61.51 UC1.D48 133.32,60.88 UC1.D47 132.34,60.84 v2(132.24,60.74) 132.24,60.68 UC1.E46 ; UC1.AA2 UC1.AA4 124.51,36.28 v2(124.58,36.35) 124.71,36.35 124.97,36.62 UC1.W6 ; v2(135.28,74.95) UC1.B71 UC1.A70 ; v2(205.82,39.89) 205.55,40.16 JIO1.40 ; UC1.AB15 v2(124.43,42.32) UC1.AB16 ; UC1.AW14 v2(114.32,41.87) UC1.BA14 ; UC1.B58 134.3,66.43 v2(133.86,66.43) 133.36,66.43 UC1.D58 133.25,66.47 UC1.E56 ; UC1.E6 132.92,37.79 v2(132.92,37.92) ; UC1.BA18 UC1.AW18 ; v2(118.72,69) 119.05,68.66 UC1.AM61 ; UC1.N65 v2(127.84,71) ; v2(120.17,51.63) UC1.AL32 ; v2(125.96,72.86) UC1.U69 UC1.U70 126.28,73.86 v2(125.96,73.54) ; UC1.B30 133.85,51.6 v2(133.85,51.6) 133.85,51.6 UC1.D30 ; UC1.AM43 118.72,58.82 v2(118.72,58.92) 118.72,59.08 UC1.AM45 119.05,59.44 v2(118.65,59.84) 119.05,60.24 UC1.AM46 v2(118.66,60.78) ; UC1.N19 128.15,44.61 v2(127.83,44.3) 127.52,44.61 UC1.P19 ; UC1.T21 UC1.P21 127.49,45.91 v2(127.78,45.62) 127.43,45.26 UC1.P20 ; UC1.AA68 v2(124.14,72.22) ; v2(133.05,73.3) 133.05,72.84 UC1.D69 UC1.F68 ; UC1.BA45 v2(114.45,59.15) UC1.AW45 ; UC1.AM27 UC1.AM25 119.05,48.31 v2(118.72,47.98) 118.4,47.66 UC1.AN23 UC1.AP23 UC1.AR23 117.03,47.59 116.53,47.59 UC1.AT23 ; UC1.AM27 119.51,49.81 UC1.AL28 120.29,49.81 v2(120.47,49.63) ; UC1.AM27 UC1.AK27 120.31,49.03 v2(120.47,49.03) ; UC1.AM27 118.72,49.68 118.72,49.94 UC1.AN28 UC1.AP28 117.68,50.34 117.18,50.34 UC1.AR28 ; UC1.R13 127.73,40.77 v2(127.98,40.77) UC1.N13 ; UC1.G5 131.56,36.82 v2(131.56,36.98) 131.56,37.19 UC1.G6 ; v2(124.64,40.86) 124.89,40.86 UC1.W13 ; UC1.AW45 114.96,59.57 115,59.61 115,59.92 114.96,59.96 UC1.AW47 114.96,60.73 115,60.77 115,61.08 114.96,61.12 UC1.AW49 ; UC1.AW45 114.96,58.71 115,58.67 115,58.29 114.96,58.25 UC1.AW43 ; UC1.AK18 119.3,43.45 v2(119.3,43.41) 119.3,43.32 119.45,43.17 119.45,43.16 119.82,42.79 UC1.AK16 119.45,42.66 v2(119.28,42.5) 119.43,42.35 119.43,41.49 UC1.AM13 ; RN5203.2 42.77,93.94 v2(43.01,93.71) ; UUS5.14 21.88,40.06 v2(21.99,39.95) ; JIO1.12 v2(205.89,54.16) ; v2(117.41,58.01) 117.1,57.7 UC1.AR42 UC1.AT42 ; v2(117.41,58.01) 117.1,58.31 UC1.AR43 117.1,58.53 v2(116.68,58.95) UC1.AR45 v2(116.68,59.87) 117.1,60.3 UC1.AR46 116.76,60.67 v2(116.76,60.78) 116.76,60.89 UC1.AR48 116.77,61.56 v2(116.77,61.74) 116.77,61.82 UC1.AR50 116.73,62.52 v2(116.73,62.62) 116.73,62.69 UC1.AR52 116.74,63.43 v2(116.74,63.49) 116.74,63.62 UC1.AR53 116.8,64.28 v2(116.8,64.45) 116.8,64.59 UC1.AR55 v2(116.75,65.36) UC1.AT56 ; UC1.AW57 114.96,66.05 115.04,65.97 115.04,65.63 114.96,65.55 UC1.AW55 114.96,64.77 115,64.73 115,64.01 UC1.AW53 ; UC1.AW57 115.32,66.44 v2(115.48,66.28) ; UC1.AW57 114.96,66.6 115.1,66.74 115.1,67.5 UC1.AW60 ; UC1.AD13 122.78,41.17 v2(122.48,40.93) ; JEDP.26 v2(49.77,98.86) ; v2(131.54,61.69) UC1.G48 ; v2(118.09,54.29) UC1.AN37 118.4,54.86 v2(118.01,55.32) ; UC1.AM61 119.05,68.42 v2(118.72,68.09) 119.05,67.75 UC1.AM60 ; UC1.AP70 v2(117.67,72.81) UC1.AP68 117.29,72.24 117.23,72.18 116.94,72.18 116.88,72.24 UC1.AT68 ; UC1.E53 v2(132.81,64.44) 133.26,63.99 UC1.D53 UC1.B53 ; UC1.Y20 124.89,45.31 124.89,45.87 UC1.Y21 124.69,46.07 124.16,46.07 UC1.AB21 123.86,45.91 v2(123.58,45.63) ; UC1.AW53 115.11,63.81 115.11,63.44 115,63.34 115,62.79 UC1.AW51 ; UC1.AW53 UC1.BA53 ; v2(135.7,35.85) 135.4,36.15 UC1.A5 ; v2(132.84,69.03) 132.93,68.95 UC1.D62 UC1.B62 ; v2(118.07,52.64) 118.07,52.42 UC1.AN32 118.08,51.77 v2(118.08,51.62) 118.08,51.52 118.4,51.2 UC1.AN30 ; UC1.B66 UC1.D66 132.94,71.05 v2(132.94,71.02) 132.94,70.82 UC1.E65 ; UC1.AD16 123.16,42.66 122.84,42.98 v2(122.77,42.98) ; UC1.AT4 116.56,35.37 v2(116.53,35.34) 116.56,35.32 UC1.AT2 ; v2(120.47,36.75) 120.5,36.75 120.5,36.74 120.75,36.76 UC1.AH6 121.08,36.62 UC1.AF4 ; UC1.B18 UC1.D18 133.17,44.32 v2(132.83,44.32) 132.83,44.1 UC1.E18 ; JIO1.6 v2(205.89,57.16) ; v2(115.36,52.49) 114.96,52.09 UC1.AW32 114.41,51.72 v2(114.39,51.74) 114.37,51.72 UC1.BA32 ; v2(115.12,38.79) 115.12,39.02 114.96,39.18 UC1.AW10 114.67,39.45 v2(114.46,39.24) 114.25,39.45 UC1.BA10 ; v2(115.12,38.79) 115.31,38.79 UC1.AU10 ; v2(115.12,38.79) 115.12,38.64 114.96,38.48 UC1.AW8 ; JSSD1.27 v2(219.6,14.53) ; UC1.AD21 123.3,45.91 v2(123.58,45.63) ; UC1.AN38 118.22,55.94 118.22,56.05 v2(118.08,56.18) 117.75,55.85 UC1.AP38 ; UC1.AR15 117.1,42.13 v2(116.74,42.49) 117.1,42.85 UC1.AR16 116.79,43.26 v2(116.79,43.39) ; v2(131.54,56.21) UC1.J38 130.17,56.21 v2(130.16,56.2) ; v2(120.48,71.57) UC1.AH67 ; 135.96,52.59 137.41,52.59 137.9,53.08 138.9,53.08 139.81,52.18 140.49,52.18 CC22.2 ; v2(131.62,69.03) 131.62,69.25 UC1.G63 ; UC1.BA66 UC1.AY66 v2(114.87,71.78) UC1.AW66 115.05,71.24 115.05,70.28 UC1.AW64 115,70.15 115,69.38 114.96,69.34 UC1.AW62 v2(114.43,68.92) UC1.BA62 ; UC1.D25 v2(132.97,48.79) ; UC1.G58 131.61,67.04 v2(131.61,67.19) 131.61,67.37 131.35,67.64 UC1.G60 ; UC1.BA49 110.8,61.56 110.44,61.92 v2(110.39,61.92) ; 130.24,43.47 130.24,43.03 UC1.K16 130.05,42.49 v2(130.91,42.49) UC1.H15 ; 130.24,43.47 129.88,43.83 UC1.K18 ; 130.24,43.47 UC1.H18 ; UC1.V18 UC1.V17 ; UC1.V18 UC1.T18 126.3,43.74 126.3,43.54 UC1.T17 126.58,43.31 126.92,42.98 v2(126.98,42.98) 127.32,43.31 UC1.P17 ; UC1.V18 UC1.Y19 124.8,44.61 v2(124.43,44.99) ; UC1.V17 UC1.Y17 ; UC1.V17 125.65,43.28 125.65,42.7 UC1.V16 125.96,42.39 v2(126.1,42.39) 126.11,42.39 126.48,42.01 UC1.T15 ; UC1.B44 134.14,58.83 133.52,58.83 UC1.D44 133.21,58.93 132.83,58.93 v2(132.79,58.96) 132.79,59.09 133.36,59.66 UC1.D45 ; UC1.AL45 v2(120.17,58.95) ; UC1.F13 131.94,41.33 v2(132.19,41.58) 132.19,41.63 UC1.E15 ; RN5203.1 43.27,94.18 v2(43.58,93.87) ; UC1.AJ15 120.93,41.74 UC1.AH13 121.24,40.86 v2(121.57,40.86) ; UC1.AD62 v2(123.22,69.57) ; UC1.E11 133.05,40.2 UC1.D11 133.36,39.25 UC1.D10 ; JSSD1.33 219.5,13.03 v2(219.74,13.27) ; v2(130.16,54.38) UC1.J35 131.48,54.38 UC1.F37 ; UC1.D26 v2(133.72,48.83) UC1.C25 ; JKB.1 106.3,12.18 106.61,11.87 v2(106.61,11.72) ; v2(129.4,75.04) 129.74,74.69 UC1.K71 UC1.K70 ; UC1.AR5 117.1,36.78 v2(116.89,37) ; 130.52,40.7 130.03,40.2 UC1.J11 129.64,40.2 129.64,40.2 129.34,39.9 UC1.L11 ; 130.52,40.7 130.1,41.12 UC1.J13 ; 130.52,40.7 v2(130.97,40.7) ; UC1.AK21 119.92,46.01 119.92,46.53 UC1.AK22 120.34,46.6 v2(120.48,46.46) ; JIO1.37 v2(203.25,41.66) ; v2(131.61,52.63) UC1.F33 ; v2(131.61,52.63) 131.53,52.55 UC1.J32 v2(130.13,52.55) ; v2(131.61,52.63) 131.94,52.3 UC1.F32 ; PU1200.11 107.03,103.45 PC1205.2 ; UC1.G66 v2(131.35,72.1) ; UC1.G43 130.83,58.03 UC1.J42 ; UC1.G43 131.29,58.73 v2(131.52,58.95) 131.52,59.18 UC1.G45 ; UC1.G43 131.58,58.21 v2(131.58,57.98) 131.58,57.91 131.9,57.58 UC1.F42 ; UC1.BA57 v2(114.27,66.44) ; v2(127.94,39.04) 128.22,39.04 UC1.N10 ; JDB1.2 41.9,71.46 v2(41.81,71.55) ; UC1.N68 v2(127.84,72.24) ; UC1.AW30 114.96,50.08 115.03,50.01 115.03,49.65 114.96,49.58 UC1.AW28 v2(114.41,49.21) UC1.BA28 ; UC1.AR11 117.1,39.9 v2(117.26,39.75) 117.72,39.29 UC1.AP10 ; v2(128.9,38.37) 128.95,38.31 128.95,38.3 UC1.L8 ; UC1.AK8 120.06,37.92 v2(120.42,38.29) ; UC1.AD8 123.31,38.16 v2(123.6,38.16) 123.66,38.16 123.9,37.92 UC1.AB8 ; UC1.D10 133.3,39.21 v2(132.92,38.84) ; UC1.D10 UC1.B10 ; UC1.BA41 114.2,56.67 v2(114.34,56.54) 114.47,56.67 UC1.AW41 ; v2(123.6,43.62) 123.94,43.96 UC1.AB18 ; UC1.E50 132.26,62.48 v2(132.26,62.69) 132.24,62.72 132.2,62.68 131.68,62.68 UC1.G52 ; UC1.U67 v2(125.96,71.59) ; UC1.AR28 UC1.AT28 116.45,50.43 v2(116.75,50.73) 117.1,50.38 UC1.AR28 ; v2(116.77,37.94) 116.77,38.05 UC1.AR8 ; UC1.U64 v2(125.96,69.62) UC1.U63 ; JIO1.9 v2(205.89,55.66) ; UC1.AU15 116.11,41.73 v2(116.11,41.59) ; UC1.AJ4 119.87,35.88 v2(119.5,36.24) 119.21,35.95 UC1.AL4 118.92,35.55 118.92,35.15 UC1.AL2 ; v2(132.95,75.05) 132.95,74.56 UC1.E71 ; UC1.F8 131.63,38.69 v2(131.63,38.84) 131.29,39.18 UC1.G10 ; UC1.L16 UC1.L17 128.94,43.31 v2(128.58,43.67) 128.7,43.79 128.82,43.79 129,43.96 UC1.L18 ; UC1.D34 v2(133.83,54.08) UC1.B34 ; JEDP.30 51.77,98.74 v2(51.87,98.84) ; UC1.E21 132.87,45.96 v2(132.87,46.15) 133.32,46.6 UC1.D22 UC1.B22 ; UC1.G55 131.29,64.66 v2(131.61,64.34) ; UC1.AL35 v2(120.47,53.46) ; UC1.AW26 114.96,47.62 115.04,47.54 115.04,47.28 114.96,47.19 UC1.AW23 114.31,46.73 v2(114.3,46.74) 114.3,46.73 UC1.BA23 ; UC1.AW36 v2(114.31,54.19) UC1.BA36 ; UC1.N21 128.24,45.91 v2(128.56,45.59) 128.89,45.26 UC1.L20 ; CC21.2 140.34,56.52 140.34,56.51 139.06,55.23 136.33,55.23 ; v2(126.8,38.64) 126.82,38.64 126.82,38.67 UC1.U10 ; UC1.L2 129.95,35 v2(129.95,35.36) 129.95,35.7 UC1.L4 ; UC1.A67 135.79,72.58 v2(135.86,72.58) ; UC1.F1 UC1.F2 132.47,35.27 v2(132.39,35.35) 132.47,35.43 UC1.F4 ; JSSD1.57 v2(216.83,7.03) ; UC1.F27 v2(132.18,49.81) UC1.F28 131.56,50.64 130.9,50.64 UC1.J28 ; v2(117.37,52.55) UC1.AP32 ; UC1.AV68 115,72.51 v2(115,72.62) 115.1,72.71 UC1.AV69 UC1.AV70 UC1.AV71 v2(114.86,75.08) ; UC1.B39 134.06,56.84 v2(133.71,56.84) 133.61,56.84 UC1.D39 ; UC1.AF10 121.82,39.22 v2(121.56,38.96) ; v2(118.7,65.32) 119.05,64.96 UC1.AM55 ; UC1.J25 v2(130.03,48.89) ; JIO1.31 v2(203.76,44.66) ; UC1.U66 v2(125.96,70.95) ; UC1.AL38 v2(120.47,55.29) ; UC1.D14 133.54,41.69 v2(133.76,41.9) 133.98,41.69 UC1.B14 ; v2(115.47,56.21) UC1.AU38
  BOTTOM w0.305: JDIMM2.9 65.94,84.58 66.32,84.2 v2(66.32,83.7) 66.32,83.24 66.15,83.08 JDIMM2.15 ; JDIMM2.201 63.75,34.58 63.53,34.79 63.53,34.97 v2(63.44,35.05) 63.44,35.09 63.93,35.58 JDIMM2.197 ; JDIMM2.35 63.62,78.08 63.4,78.29 v2(63.4,78.67) ; JDIMM1.206 68.24,33.33 67.99,33.57 v2(67.99,34.33) JDIMM1.202 ; JDIMM1.180 70.47,39.83 70.76,40.12 v2(70.76,40.36) 70.76,40.46 70.39,40.83 JDIMM1.176 68.04,40.83 67.91,40.95 ; JDIMM2.196 v2(55.43,35.83) ; JDIMM2.209 65.88,32.58 66.2,32.89 66.2,33.33 v2(66.13,33.4) 65.95,33.58 JDIMM2.205 ; JDIMM1.40 68.16,76.83 67.91,76.58 v2(67.91,76.29) 67.91,76.01 68.09,75.83 JDIMM1.44 ; JDIMM1.93 76.31,63.58 75.9,63.16 v2(75.9,63.08) 75.9,62.31 76.13,62.08 JDIMM1.99 ; JEDP.6 v2(39.77,96.83) ; JDIMM1.78 68.26,67.33 67.95,67.63 v2(67.95,68.13) 67.95,68.56 68.22,68.83 JDIMM1.72 ; HDD1.12 208.15,9.82 207.89,9.56 v2(207.89,8.93) ; JDIMM2.252 55.46,21.83 55.45,21.84 55.44,21.83 v2(55.44,21.84) ; JDIMM1.196 68.56,35.83 v2(68.15,36.23) ; JDIMM2.188 v2(55.43,37.83) ; JDIMM1.248 68.45,22.83 68.1,22.47 v2(68.1,22.41) 68.1,22.09 68.37,21.83 JDIMM1.252 ; JDIMM2.189 62.91,37.58 v2(62.25,38.23) ; v2(216.86,8.81) 217.14,8.53 JSSD1.51 v2(220.37,8.53) ; JDIMM1.230 68.25,27.33 67.97,27.05 v2(67.97,26.86) 67.97,26.67 68.31,26.33 JDIMM1.234 ; JDIMM2.230 v2(55.43,27.33) ; WLAN1.37 v2(187.67,59.24) ; JDIMM1.22 68.18,81.33 67.94,81.56 v2(67.94,81.91) 68.36,82.33 JDIMM1.18 ; JDIMM2.184 v2(55.43,38.83) ; JDIMM2.218 v2(55.43,30.33) ; v2(75.01,69.16) 75.59,68.58 JDIMM1.73 ; JDIMM1.6 68.24,85.33 68.04,85.53 v2(68.04,85.72) 68.04,85.97 68.39,86.33 JDIMM1.2 ; HDD1.6 211.15,9.74 211.45,9.44 v2(211.45,8.93) ; JDIMM1.48 68.25,74.83 67.97,74.54 v2(67.97,74.29) 67.97,74.16 68.31,73.83 JDIMM1.52 ; JDIMM2.180 v2(55.43,39.83) ; JDIMM1.64 68.38,70.83 68.1,70.54 v2(68.1,70.38) 68.1,70.26 68.53,69.83 JDIMM1.68 ; JDIMM1.90 68.26,64.33 v2(68.04,64.1) 68.04,63.56 68.27,63.33 JDIMM1.94 ; JDIMM2.171 66.03,42.08 v2(66.39,41.72) 66.39,41.46 66,41.08 JDIMM2.175 ; v2(216.82,10.03) JSSD1.45 v2(220.31,10.03) ; JDIMM2.61 65.98,71.58 v2(66.19,71.78) 66.19,72.33 65.94,72.58 JDIMM2.57 ; WLAN1.18 v2(192.42,54.07) ; HDD1.9 209.65,8.94 v2(209.67,8.93) ; JDIMM1.102 68.26,61.33 68.07,61.52 v2(68.07,61.83) 68.07,62.13 68.26,62.33 JDIMM1.98 ; JDIMM2.193 63.72,36.58 63.59,36.71 62.76,36.71 v2(62.25,36.2) ; v2(66.48,60.49) 66.48,60.48 66.08,60.08 JDIMM2.107 ; 56.7,40.83 v2(55.43,40.83) ; JDIMM1.56 68.41,72.83 68.04,72.45 v2(68.04,72.07) 68.28,71.83 JDIMM1.60 ; JDIMM2.248 v2(55.43,22.83) ; v2(219.62,11.65) 219.5,11.53 JSSD1.39 ; WLAN1.10 v2(194.42,51.67) ; JDIMM2.192 v2(55.43,36.83) ; JDIMM1.30 68.25,79.33 67.9,78.98 v2(67.9,78.65) 67.9,78.11 68.19,77.83 JDIMM1.36 ; JDIMM2.27 65.92,80.08 v2(66.25,79.75) 66.2,79.69 66.2,79.31 65.96,79.08 JDIMM2.31 ; v2(68.07,32.72) 68.46,32.33 JDIMM1.210 ; JDIMM2.202 v2(55.43,34.33) ; v2(75.01,65.86) 75.01,65.29 75.72,64.58 JDIMM1.89 ; JDIMM2.73 63.59,68.58 63.25,68.23 v2(63.25,67.87) 63.54,67.58 JDIMM2.77 ; JDIMM1.214 68.25,31.33 v2(68.04,31.11) 68.04,30.79 68.51,30.33 JDIMM1.218 ; JDIMM1.172 68.25,41.83 v2(68.16,41.74) ; JDIMM2.39 65.95,77.08 66.25,76.77 v2(66.25,76.29) 66.17,76.29 65.95,76.08 JDIMM2.43 ; v2(67.91,79.75) 67.91,80 68.23,80.33 JDIMM1.26 ; JDIMM2.65 66.1,70.58 66.26,70.42 v2(66.26,70.23) 66.26,69.85 65.99,69.58 JDIMM2.69 ; WLAN1.61 v2(181.67,61.65) ; JDIMM2.172 v2(55.43,41.83) ; JDIMM1.86 68.27,65.33 v2(68.07,65.53) 68.07,66.07 68.33,66.33 JDIMM1.82 ; v2(67.94,38.21) 68.33,37.83 JDIMM1.188 ; JDIMM1.106 68.2,60.33 v2(68.04,60.49) ; JDIMM2.238 v2(55.43,25.33) ; JDIMM2.217 65.91,30.58 66.26,30.92 v2(66.26,31.49) 66.18,31.58 JDIMM2.213 ; JDIMM1.192 68.04,36.83 68.04,36.82 ; JDIMM2.85 66.31,65.58 v2(66.36,65.53) 66.36,66.32 66.1,66.58 JDIMM2.81 ; WLAN1.55 v2(183.17,61.65) ; JDIMM2.89 66.07,64.58 66.2,64.45 v2(66.2,64.13) 66.2,63.88 65.89,63.58 JDIMM2.93 ; WLAN1.67 v2(180.17,61.65) ; JDIMM1.244 68.21,23.83 68.04,24 v2(68.04,24.6) 68.04,25.14 68.22,25.33 JDIMM1.238 ; JDIMM1.239 76.75,25.08 76.17,24.49 v2(76.17,24.11) 76.2,24.08 JDIMM1.243 ; v2(189.17,59.11) WLAN1.31 ; JEDP.9 v2(41.27,96.87) ; JDIMM2.235 65.99,26.08 v2(66.14,26.22) 66.14,26.73 65.79,27.08 JDIMM2.231 ; JDIMM2.222 v2(57.97,29.33) ; JDIMM2.181 65.99,39.58 v2(66.15,39.41) 66.15,38.71 66.02,38.58 JDIMM2.185 ; JDIMM2.244 v2(55.43,23.83) ; v2(111.59,44.29) 111.6,44.29 111.13,44.29 110.65,43.81 CC27.2 ; v2(68.1,28.02) 68.41,28.33 JDIMM1.226 ; v2(66.2,29.08) 66.21,29.07 66.21,28.38 65.9,28.08 JDIMM2.227 ; WLAN1.1 v2(198.67,59.24) ; JSSD1.1 217.17,21.03 v2(216.91,20.76) 217.14,20.53 JSSD1.3 ; WLAN1.7 v2(197.17,59.24) ; JDIMM2.99 65.99,62.08 v2(66.23,61.83) 66.23,61.33 65.98,61.08 JDIMM2.103 ; v2(68.14,42.88) 68.2,42.83 JDIMM1.168 ; JDIMM2.47 66.01,75.08 v2(66.29,74.79) 66.29,74.29 66.08,74.08 JDIMM2.51 ; JDIMM2.23 66.03,81.08 66.36,81.4 v2(66.36,81.91) 66.19,82.08 JDIMM2.19 ; JDIMM2.243 v2(63.46,24.08) 63.4,24.13 63.4,24.76 63.72,25.08 JDIMM2.239 ; JDIMM2.214 v2(55.43,31.33) ; WLAN1.49 v2(184.67,59.3) ; v2(66.27,42.98) 66.18,43.08 JDIMM2.167 ; JDIMM1.222 v2(70.8,29.33) ; JDIMM2.14 57.56,83.33 v2(58.17,83.93) ; JDIMM2.206 v2(55.43,33.33) ; JEDP.3 v2(38.27,96.9) ; JDIMM2.251 66.24,22.08 66.39,22.22 v2(66.39,22.42) 66.39,22.86 66.17,23.08 JDIMM2.247 ; JDIMM1.14 70.36,83.33 70.63,83.6 v2(70.63,83.78) 70.63,84.14 70.45,84.33 JDIMM1.10 ; JDIMM2.234 v2(55.43,26.33) ; WLAN1.25 v2(190.67,59.3) ; WLAN1.43 v2(186.17,59.24) ; JDIMM2.168 v2(55.43,42.83) ; JDIMM2.210 v2(55.43,32.33) ; 68.07,38.83 JDIMM1.184 ; JIO1.34 v2(203.68,43.16) ; JDIMM2.226 v2(55.43,28.33)
  BOTTOM w0.356: v2(113.17,32.25) 112.98,32.06 CC1823.1 ; v2(108.26,32.72) 108.23,32.75 CC1803.1 ; CC1807.2 137.59,29.6 v2(137.47,29.48) ; JDIMM2.223 v2(66.2,29.08)
  BOTTOM w0.381: R6207.2 118.3,14.33 v2(117.55,14.33) ; QC5.4 198.23,16.14 v2(197.77,15.68) ; QC5.1 196.96,14.84 v2(197.39,14.41) ; v2(51.27,96.53) EU3405.3 51.27,94.38 51.39,94.27 51.39,93.94 v2(51.44,93.89) ; v2(186.78,80.2) 186.36,80.61 PR110.2 ; U3403.3 v2(16.92,28.06)
  BOTTOM w0.406: U3402.3 v2(14.18,48.25) ; JLED.8 62.75,10.31 v2(62.64,10.42) ; JLED.7 67.67,9.49 v2(67.67,9.86)
  BOTTOM w0.508: v2(125,79.88) 124.62,79.88 PC1131.2 ; RC375.2 126.14,29.2 126.52,28.82 v2(126.52,28.7) 126.34,28.52 RC1128.2 ; v2(209.07,38.03) 208.79,37.76 JIO1.41 ; C6213.2 v2(199.55,72.96) ; R6532.2 17.3,38.08 v2(17.3,38.24) ; PC604.2 v2(158.51,63.39) ; v2(72.36,99.25) SW1.6 72.36,96.83 74.56,94.63 SW1.1 73.98,94.16 73.31,93.48 SW1.5 71.7,93.48 71.02,94.16 SW1.2 ; RC113.1 139.34,73.73 v2(139.16,73.91) 139.16,74.23 139.42,74.49 RC43.2 RC110.1 ; PR118.2 v2(197.92,80.49) ; PC1173.2 149,62.48 v2(148.62,62.48) ; PC1082.2 149,65.53 v2(148.62,65.53) ; v2(148.62,64) 149,64 PC1061.2 ; PH601.1 v2(161.75,79.24) ; JWDB1.5 135.99,15.84 v2(135.21,15.84) ; JIO2.4 212.85,13.96 v2(213.33,14.44) ; R6530.2 v2(55.2,94.72) ; v2(21.87,32.7) 21.33,32.7 C3513.2 21.45,33.33 v2(21.87,33.33) ; PC1162.2 127.54,81.15 v2(127.92,81.15) ; RC4.2 v2(117.28,29.38) ; PC661.2 163.55,58.75 164.44,57.86 PR662.2 165.03,57.59 v2(165.24,57.37) ; v2(41.81,68.51) 41.51,68.81 JDB1.11 ; EC9751.2 v2(173.76,91.24) ; RC141.2 139.17,50.99 v2(139.78,51.6) ; v2(151.73,65.53) 152.11,65.53 PC1002.2 ; PC1206.2 v2(116.23,101.61) ; v2(119.45,28.67) 119.56,28.78 RC393.2 ; v2(163.57,61.07) 163.29,61.35 PC602.2 ; PC111.2 v2(187.35,78.58) ; PC1027.2 149.19,91.75 v2(149.19,91.37) ; RX14.2 27.91,65.13 RX34.2 v2(26.84,65.17) ; PC1204.2 PR1205.2 107.48,109.05 v2(107.33,108.9) ; v2(152.28,27.22) PR310.2 152.3,26.46 PR305.2 ; JFAN1.1 v2(202.47,68) ; CLRP1.1 98.1,15.58 v2(98.2,15.48) 98.52,15.48 CC24.2 ; PR653.2 164.67,73.67 v2(164.62,73.72) ; TPAD1.5 137.35,11.86 v2(137.68,11.53) ; JFAN1.6 v2(208.62,74.3) ; v2(115.59,11.26) 116.79,10.06 JKBBL.6 ; v2(98.9,103.31) 99.23,102.98 EC9702.2 ; CC9.2 130.22,21.53 v2(129.96,21.28) ; v2(178.83,22.68) 178.25,22.68 177.85,23.08 PBATT1.11 ; PC8.2 v2(156.45,32.34) ; CC213.2 106.73,40.79 v2(106.73,40.29) ; EC9707.2 v2(168.08,44.44) ; v2(115.15,28.48) 114.64,28.48 RC347.2 ; PC1028.2 149.19,89.21 v2(149.19,88.83) ; C6201.2 132.38,13.98 v2(132.05,13.65) ; RC163.2 129.76,81.25 v2(129.31,81.69) ; v2(21.57,12.8) 22.25,12.8 DA12.1 22.14,13.42 v2(21.58,13.42) ; JDIMM1.261 v2(85.5,84.2) ; PC219.2 v2(91.91,107.44) ; v2(152.75,31.43) 152.65,31.43 PC306.2 ; v2(66.51,102.23) 66.59,102.15 PC204.1 ; v2(118.7,28.68) 118.58,28.8 CC204.2 ; Q6202.3 112.11,16.11 v2(111.74,16.11) 111.17,15.54 CC1821.2 ; PH603.1 v2(157.33,60.31) ; v2(140.21,67.33) 140.21,66.76 139.72,66.27 RC348.2 ; v2(67.67,9.86) 67.67,10.28 PC801.2 ; v2(26.73,13.62) 27.49,14.37 27.49,16.89 CA29.2 ; JIO1.45 v2(209.05,62.06) ; EC9701.2 v2(101.58,102.98) ; PC641.2 171.86,67.5 172.24,67.11 v2(172.75,67.11) ; v2(149.19,93.91) 149.19,94.29 PC1025.2 ; PC502.2 PR502.1 v2(51.94,12.76) ; PC1174.2 149,60.95 v2(148.62,60.95) ; v2(125,82.42) 124.62,82.42 PC1181.2 ; v2(174.04,99.8) 174.04,98.36 174.43,97.98 EC9706.2 ; v2(157.02,68.62) PC652.2 ; PC1224.2 150.84,89.21 v2(150.84,88.83) ; v2(157.02,69.6) PC649.2 ; v2(121.24,27.9) 121.52,27.62 RC1131.2 ; v2(106.04,15.22) 105.57,15.69 RC371.2 ; CC199.2 138.92,48.71 v2(138.28,49.35) ; C3504.2 v2(16.09,42.6) ; v2(150.84,93.91) 150.84,94.29 PC1022.2 ; PC645.2 v2(158.65,72.4) ; PR681.2 v2(170.81,94.04) ; PC1081.2 145.82,62.48 v2(145.44,62.48) ; EC9712.2 v2(168.2,40.06) ; UC2.4 122.46,18.92 v2(122.33,19.04) ; PR680.2 v2(170.2,85.33) ; v2(109.43,10.78) 109.43,10.45 108.3,9.32 JKB.31 ; PC126.2 v2(198.78,78.29) ; JIO1.42 v2(208.78,42.92) ; JSSD1.68 v2(216.9,22.13) ; PC685.2 v2(146.84,41.65) ; PC1059.2 v2(141.89,49.78) ; PC605.1 v2(167.8,63.43) ; PC1158.2 127.54,82.42 v2(127.92,82.42) ; PC3.2 v2(194.78,87.62) ; HDD1.13 v2(215.45,4.99) ; v2(122.94,9.02) 123.32,9.41 JKBBL.5 ; PC1156.2 124.62,78.61 v2(125,78.61) ; PC1006.2 152.11,62.48 v2(151.73,62.48) ; v2(22.19,35.17) 21.62,35.17 TC3501.2 21.68,34.48 v2(22.19,34.48) ; JEDP.41 58.27,101.46 v2(57.56,102.17) ; PR1207.2 v2(105.63,111.12) ; PC1221.2 127.54,79.88 v2(127.92,79.88) ; RC377.2 108.23,15.6 v2(108.66,15.17) ; RA31.2 v2(19.57,25.92) ; PC506.2 v2(40.04,10.74) ; v2(88.29,23.22) 88.09,23.22 85.5,20.63 JDIMM1.262 ; JDB1.12 v2(38.15,77.61) ; PR1202.1 v2(110.01,110.43) ; RX13.2 v2(26.17,60.22) ; JEDP.42 v2(34.57,101.46) ; v2(26.22,33.33) 26.51,33.04 RA29.2 ; PJPDC1.7 v2(207.48,92.06) ; RC112.1 137.39,78.09 v2(137,78.48) ; RUS26.2 RUS27.2 v2(23.6,38.16) ; PC1001.2 145.82,60.95 v2(145.44,60.95) ; C2603.2 v2(200.05,71.81) ; CC1808.2 v2(140.24,71.05) ; RA32.2 26.84,14.85 v2(25.61,13.62) ; C3507.2 v2(21.19,31.52) ; PC4.2 v2(195.74,87.62) ; PC1076.2 145.82,65.53 v2(145.44,65.53) ; WLAN1.69 v2(179.07,61.63) ; v2(193.7,88.01) 193.13,88.58 EC9703.2 ; v2(145.44,64) 145.82,64 PC1071.2 ; C5801.2 v2(200.69,48.06) ; JIO2.5 v2(206.25,14.82) ; PC644.2 159.74,61.43 v2(159.52,61.21) ; JIO1.44 208.78,60.41 v2(209.07,60.7) ; PC677.2 v2(171.17,94.86) ; PC505.2 v2(38.83,6.47) ; C6214.2 v2(202.47,75.5) ; PC119.2 v2(198.78,77.02) ; PBATT1.12 153.65,25.29 v2(153.31,25.64) ; JKB.32 81.62,8.8 81.88,8.55 v2(82.25,8.55) ; v2(150.84,91.37) 150.84,91.75 PC1026.2 ; v2(160.19,65.26) 160.19,64.89 PR654.2 ; EC9709.2 v2(174.7,99.58) ; PR647.1 166.48,73.39 v2(166.14,73.72) ; v2(193.07,87.05) 192.43,87.69 EC9708.2 ; JIO1.43 v2(208.78,47.53) ; U3505.2 v2(198.15,23.05) ; v2(169.21,62.05) PC619.1 PC618.1 ; EC9750.2 v2(173.79,90.23) ; v2(19.43,12.82) 18.8,12.82 DA10.1 18.98,13.46 19.73,13.46 v2(19.94,13.24) ; PC1184.2 127.54,78.61 v2(127.92,78.61) ; v2(202.21,61.78) 200.08,59.65 WLAN1.68 ; RE451.2 27.97,41.26 28.6,41.89 v2(28.98,41.89) ; v2(215.7,15.07) JIO2.6 ; v2(140.36,51.3) 140.62,51.56 CC22.2 144.61,52.05 144.75,52.19 144.75,56.38 144.6,56.52 CC21.2 v2(140.62,57.34) ; C3508.2 v2(16.37,53.03) ; PC1207.2 v2(118.77,101.62) ; CA31.2 34.89,15.9 v2(34.89,16.45) ; PC209.2 v2(64.35,99.31) ; C2604.1 v2(200.05,70.54) ; PC1208.2 v2(117.5,101.62) ; PR505.2 57,11.18 v2(57.2,10.98) ; C5805.2 v2(200.31,49.21) ; C5804.2 v2(202.72,52.13) ; EC9711.2 v2(168.2,42.31) ; v2(151.73,64) 152.11,64 PC1005.2 ; PC1060.2 v2(141.89,44.76) ; v2(125,81.15) 124.62,81.15 PC1135.2 ; v2(151.73,60.95) 152.11,60.95 PC1013.2 ; PC305.2 v2(154.89,30.75) ; HDD1.14 v2(206.35,4.86) ; JFAN1.5 v2(208.69,65.45) ; C6202.2 v2(123.3,13.88) ; C5802.2 v2(200.69,47.18) ; v2(108.84,35.72) 108.84,35.74 108.54,36.04 CC1802.1 108.17,36.13 CC214.2 ; PC1209.2 v2(116.11,110.84) ; v2(107.04,102.75) PC1205.2 ; C3510.2 v2(195.61,18.47) ; RC373.2 v2(104.46,17.89) ; v2(25.81,59.33) QX6.3 ; PJPDC1.8 v2(209.01,77.1) ; EC9710.2 v2(168.08,46.64)
  vias: v2(1.5,79.22) v2(1.87,58.86) v2(1.87,57.08) v2(1.85,37.85) v2(1.93,61.4) v2(4.65,36.32) v2(4.65,18.31) v2(4.82,78) v2(5.36,58.48) v2(6.38,61.51) v2(6.44,37.97) v2(6.7,40.25) v2(6.79,78.67) v2(7.65,19.04) v2(8.28,35.62) v2(9.01,78) v2(9.05,61.51) v2(10.06,37.97) v2(10.4,39.92) v2(10.96,78.68) v2(10.95,35.62) v2(10.95,18.92) v2(12.35,60.13) v2(12.35,57.59) v2(12.53,78.4) v2(12.53,75.67) v2(12.81,19.85) v2(13.17,39.11) v2(14.14,75.86) v2(14.19,35.49) v2(14.21,77.92) v2(14.24,76.98) v2(14.38,19.04) v2(15.93,77.81) v2(16.72,76.54) v2(17.87,54.33) v2(17.87,53.69) v2(18.05,70.04) v2(18.02,44.79) v2(18.06,4.12) v2(18.18,70.73) v2(18.19,68.3) v2(18.19,67.6) v2(18.12,65.17) v2(18.11,63.42) v2(18.65,7.78) v2(19.03,39.81) v2(19.33,45.14) v2(19.57,9.39) v2(19.57,6.17) v2(19.65,40.43) v2(19.65,39.19) v2(19.64,4.62) v2(20.03,76.97) v2(20.27,39.81) v2(21.43,9.39) v2(21.43,6.17) v2(21.8,54.71) v2(21.8,54.08) v2(21.78,5.11) v2(21.9,100.15) v2(22.25,76.97) v2(22.41,54.08) v2(22.35,7.78) v2(23.19,103.54) v2(23.78,5.14) v2(24.63,100.99) v2(25.55,102.6) v2(25.55,99.38) v2(26.94,8.22) v2(27.41,102.6) v2(27.41,99.38) v2(28.33,100.99) v2(28.97,8.22) v2(29.07,104.6) v2(29.62,25.64) v2(29.62,23.67) v2(29.62,21.7) v2(31,8.22) v2(31.3,107.49) v2(31.3,105.46) v2(31.54,71) v2(31.59,25.64) v2(31.59,23.67) v2(31.59,21.7) v2(31.66,69.22) v2(31.74,66.97) v2(31.84,63.9) v2(31.86,62.14) v2(32.31,84.92) v2(33.04,8.22) v2(33.44,107.75) v2(33.58,84.21) v2(33.55,25.64) v2(33.55,23.67) v2(33.55,21.7) v2(33.8,113.61) v2(33.8,111.58) v2(33.8,109.55) v2(34.1,87.86) v2(34.12,83.14) v2(34.4,67.72) v2(34.46,114.9) v2(34.97,8.21) v2(35.3,87.03) v2(35.3,84.79) v2(36.27,8.22) v2(36.49,114.9) v2(36.41,85.91) v2(36.42,36.27) v2(36.63,99.88) v2(37.32,5.13) v2(37.47,100.87) v2(37.53,87.03) v2(37.53,84.79) v2(37.97,101.42) v2(38.13,99.25) v2(38.52,114.9) v2(39.35,5.1) v2(39.85,101.56) v2(39.97,33.14) v2(40.51,99.96) v2(40.55,114.9) v2(41.02,81.44) v2(41.38,5.1) v2(41.87,82.9) v2(42.59,114.9) v2(43.41,5.1) v2(43.62,82.23) v2(44.62,114.9) v2(45.44,5.1) v2(45.57,98.86) v2(46.05,88.73) v2(46.05,88.07) v2(46.16,98.84) v2(46.46,89.19) v2(46.65,114.9) v2(46.74,98.81) v2(46.97,32.44) v2(47.04,89.19) v2(47.22,22.46) v2(47.45,30.79) v2(47.48,5.1) v2(47.53,99.75) v2(48.19,21.52) v2(48.68,114.9) v2(49.08,94.75) v2(49.14,94.17) v2(49.51,5.1) v2(50.71,114.9) v2(51.42,10.14) v2(51.42,8.01) v2(51.54,5.1) v2(51.72,7.42) v2(52.06,9.07) v2(52.75,114.9) v2(52.71,10.14) v2(52.71,8.01) v2(53.42,113.6) v2(53.57,5.1) v2(54.73,112.9) v2(55.2,80.04) v2(55.2,78.65) v2(55.2,77.25) v2(55.28,75.83) v2(55.29,74.83) v2(55.21,73.27) v2(55.29,67.88) v2(55.27,64.7) v2(55.34,85.66) v2(55.34,71.18) v2(55.38,69.83) v2(55.37,66.33) v2(55.47,62.33) v2(55.6,5.1) v2(56.77,113.33) v2(57.66,114.9) v2(57.64,5.1) v2(58.11,51.36) v2(58.5,56.56) v2(58.5,50.29) v2(58.43,48.92) v2(58.5,45.65) v2(58.8,67.87) v2(58.88,78.66) v2(58.82,35) v2(58.82,24.11) v2(59.2,82.8) v2(59.2,41.53) v2(59.2,38.23) v2(59.2,36.2) v2(59.2,33.21) v2(59.2,31.24) v2(59.2,27.46) v2(59.2,25.82) v2(59.2,22.78) v2(59.26,85.47) v2(59.26,80.05) v2(59.26,77.32) v2(59.26,74.82) v2(59.26,72.06) v2(59.26,69.16) v2(59.26,65.86) v2(59.69,114.9) v2(59.67,5.1) v2(60,53.28) v2(59.96,48.92) v2(60.04,60.68) v2(60.02,58.39) v2(60.02,56.56) v2(60.02,50.29) v2(60.02,47.09) v2(60.02,45.65) v2(60.02,43.47) v2(60.15,62.26) v2(60.35,83.97) v2(60.4,73.33) v2(60.4,51.36) v2(60.35,40.26) v2(60.35,29.34) v2(60.78,85.47) v2(60.72,82.8) v2(60.78,80.05) v2(60.78,77.32) v2(60.78,74.82) v2(60.78,72.06) v2(60.78,69.16) v2(60.78,65.86) v2(60.78,55.12) v2(60.73,41.53) v2(60.73,38.23) v2(60.73,36.2) v2(60.73,33.21) v2(60.73,31.24) v2(60.73,27.46) v2(60.73,25.82) v2(60.73,22.78) v2(61.11,35) v2(61.11,24.11) v2(61.16,78.66) v2(61.15,67.87) v2(61.48,48.92) v2(61.57,60.68) v2(61.54,58.39) v2(61.54,56.56) v2(61.54,55.12) v2(61.53,53.28) v2(61.54,47.09) v2(61.54,45.65) v2(61.54,43.47) v2(61.67,62.26) v2(61.7,5.1) v2(61.73,114.9) v2(61.88,10.45) v2(62.31,85.47) v2(62.25,82.8) v2(62.31,80.05) v2(62.31,77.32) v2(62.31,74.82) v2(62.31,72.06) v2(62.31,69.16) v2(62.31,65.86) v2(62.25,41.53) v2(62.25,33.21) v2(62.25,31.24) v2(62.25,27.46) v2(62.25,25.82) v2(62.25,22.78) v2(62.26,20.95) v2(62.64,83.97) v2(62.69,73.33) v2(62.69,51.36) v2(62.63,40.26) v2(62.63,29.34) v2(63,48.92) v2(63.09,60.68) v2(63.07,45.65) v2(63.19,62.26) v2(63.76,114.9) v2(63.76,6.1) v2(65.79,114.9) v2(65.79,6.1) v2(66.26,85.72) v2(67.82,114.9) v2(67.82,6.1) v2(68.05,110.19) v2(68.05,103.67) v2(68.67,110.21) v2(68.67,104.29) v2(68.67,103.04) v2(69.29,103.67) v2(69.24,101.09) v2(69.62,100.58) v2(69.85,114.9) v2(69.83,110.19) v2(69.85,6.1) v2(70.48,110.19) v2(70.82,51.36) v2(71.16,61.12) v2(71.2,58.23) v2(71.2,56.41) v2(71.18,53.15) v2(71.13,50.4) v2(71.13,49.02) v2(71.2,47.11) v2(71.32,63.08) v2(71.5,67.87) v2(71.52,78.61) v2(71.52,34.93) v2(71.52,24.11) v2(71.65,27.6) v2(71.77,79.93) v2(71.8,38.38) v2(71.89,114.9) v2(71.9,41.53) v2(71.9,36.26) v2(71.9,33.4) v2(71.9,30.79) v2(71.9,25.44) v2(71.9,22.85) v2(71.89,6.1) v2(71.96,82.63) v2(71.96,77.32) v2(71.96,72.06) v2(71.96,69.16) v2(71.96,65.86) v2(72.01,74.73) v2(72.16,85.73) v2(72.68,61.12) v2(72.7,53.15) v2(72.66,50.4) v2(72.66,49.02) v2(72.72,58.23) v2(72.72,56.41) v2(72.72,55.02) v2(72.72,47.11) v2(72.72,45.65) v2(72.85,63.08) v2(73.1,73.33) v2(73.1,51.36) v2(73.05,40.18) v2(73.05,29.34) v2(73.12,83.82) v2(73.29,79.93) v2(73.24,27.62) v2(73.32,38.38) v2(73.48,82.63) v2(73.48,77.32) v2(73.48,72.06) v2(73.48,69.16) v2(73.48,65.86) v2(73.43,41.53) v2(73.43,36.26) v2(73.43,33.4) v2(73.43,30.79) v2(73.43,25.44) v2(73.43,22.85) v2(73.54,74.73) v2(73.68,85.73) v2(73.79,67.87) v2(73.81,34.93) v2(73.81,24.11) v2(73.81,78.61) v2(73.92,114.9) v2(73.92,6.1) v2(74.21,61.12) v2(74.18,49.02) v2(74.24,58.23) v2(74.24,55.02) v2(74.23,53.15) v2(74.24,47.11) v2(74.24,45.65) v2(74.24,43.47) v2(74.37,63.08) v2(74.76,27.62) v2(74.82,79.93) v2(74.85,38.38) v2(75.01,82.63) v2(75.01,77.32) v2(75.01,72.06) v2(74.95,36.26) v2(74.95,30.79) v2(74.95,25.44) v2(74.95,22.85) v2(75.06,74.73) v2(75.21,85.73) v2(75.4,83.82) v2(75.39,73.33) v2(75.39,51.36) v2(75.33,40.18) v2(75.33,29.34) v2(75.73,61.12) v2(75.72,9.85) v2(75.95,114.9) v2(75.95,6.1) v2(76.36,9.85) v2(76.55,102.1) v2(76.55,101.47) v2(76.55,100.83) v2(77.04,9.86) v2(77.18,102.1) v2(77.18,101.47) v2(77.18,100.83) v2(77.82,102.1) v2(77.82,101.47) v2(77.82,100.83) v2(77.98,114.9) v2(77.98,6.1) v2(78.45,100.83) v2(78.51,102.1) v2(78.51,101.47) v2(78.91,65.87) v2(78.83,39.05) v2(78.89,36.88) v2(78.84,34.98) v2(78.82,33.45) v2(78.85,31.5) v2(78.84,26.08) v2(78.92,79.78) v2(78.96,77.32) v2(78.97,74.78) v2(78.95,73.21) v2(78.99,60.57) v2(78.96,28.38) v2(78.93,23.08) v2(79.09,83.69) v2(79.04,81.59) v2(79.02,71.05) v2(79.02,42.77) v2(79.47,33.46) v2(79.53,31.5) v2(79.66,41.61) v2(79.78,86.04) v2(80.01,6.1) v2(80.13,114.9) v2(80.28,86.36) v2(80.49,33.88) v2(80.55,44.28) v2(80.66,85.91) v2(81.03,86.36) v2(81.1,33.9) v2(81.78,114.9) v2(82.05,6.1) v2(82.38,113.75) v2(83.47,112.91) v2(84.08,6.1) v2(84.55,50.68) v2(85.53,113.09) v2(85.96,114.88) v2(86.11,6.1) v2(87.34,98.17) v2(87.95,114.9) v2(88.1,98.8) v2(88.1,98.17) v2(88.14,6.1) v2(88.8,98.8) v2(89.49,24.54) v2(89.63,98.8) v2(89.98,114.9) v2(90.17,6.1) v2(90.52,98.8) v2(92.02,114.9) v2(92.21,6.1) v2(94.05,114.9) v2(94.24,6.1) v2(96.08,114.9) v2(96.27,6.1) v2(98.11,114.9) v2(98.2,32.78) v2(98.3,6.1) v2(100.14,114.9) v2(100.33,6.1) v2(102.18,114.9) v2(102.37,6.1) v2(103.42,110.17) v2(103.42,109.49) v2(103.42,108.87) v2(104,109.49) v2(104,108.86) v2(104.03,110.15) v2(104.05,108.28) v2(104.07,44.99) v2(104.21,114.9) v2(104.4,6.1) v2(104.46,107.83) v2(104.63,108.55) v2(104.83,107.3) v2(104.81,55.39) v2(104.87,49.87) v2(105.06,107.96) v2(105.48,107.41) v2(105.81,67.41) v2(105.89,59.33) v2(105.9,46.26) v2(105.94,64.03) v2(106.24,114.9) v2(106.46,51.77) v2(106.43,6.1) v2(106.52,48.28) v2(106.84,55.39) v2(106.84,49.87) v2(106.97,70.06) v2(107.03,67.43) v2(107.48,53.81) v2(107.6,57.71) v2(107.77,64.03) v2(107.9,65.48) v2(107.85,46.26) v2(107.95,61.92) v2(107.92,59.33) v2(108.27,114.9) v2(108.43,51.77) v2(108.49,48.28) v2(108.46,6.1) v2(108.68,71.97) v2(108.75,49.87) v2(108.81,55.39) v2(109.1,84.67) v2(109.06,74) v2(109.25,23.67) v2(109.45,57.63) v2(109.45,53.81) v2(109.87,86.9) v2(109.85,82.47) v2(109.92,25.57) v2(109.96,21.71) v2(110.3,114.9) v2(110.46,48.28) v2(110.49,6.1) v2(111.37,113.95) v2(111.83,87.73) v2(111.85,81.62) v2(111.87,26.35) v2(111.85,20.96) v2(112.4,112.91) v2(112.53,6.1) v2(113.57,98.74) v2(113.66,78.2) v2(113.78,25.64) v2(113.76,21.71) v2(113.85,86.86) v2(113.85,82.47) v2(114.33,98.74) v2(114.46,23.66) v2(114.53,113.1) v2(114.61,84.68) v2(114.56,6.1) v2(114.95,114.31) v2(114.93,76.87) v2(115.09,98.74) v2(115.85,98.74) v2(116,77.94) v2(116.1,45.25) v2(116.18,114.9) v2(116.37,76.86) v2(116.59,6.1) v2(116.74,67.18) v2(116.76,45.25) v2(117.2,81.67) v2(117.2,79.83) v2(117.41,44.35) v2(117.44,69.92) v2(117.44,67.17) v2(118.07,69.92) v2(118.1,67.19) v2(118.22,114.9) v2(118.61,70.83) v2(118.62,6.1) v2(118.75,31.29) v2(118.82,83.08) v2(118.82,81.75) v2(118.82,79.91) v2(118.82,78) v2(120.25,114.9) v2(120.65,6.1) v2(120.94,80.79) v2(121,78.89) v2(121.16,54.61) v2(121.19,47.51) v2(121.35,63.54) v2(121.35,61.19) v2(121.76,54.61) v2(122.02,78.38) v2(122.28,114.9) v2(122.27,51.27) v2(122.27,50.68) v2(122.33,70.19) v2(122.33,69.59) v2(122.37,54.61) v2(122.41,66.2) v2(122.55,63.54) v2(122.55,61.19) v2(122.69,6.1) v2(122.74,49.25) v2(122.98,65.71) v2(123.23,73.54) v2(123.23,72.88) v2(123.23,72.23) v2(123.23,71.58) v2(123.23,70.9) v2(123.26,65.17) v2(123.25,57.59) v2(123.28,55.15) v2(123.28,52.77) v2(123.76,65.95) v2(123.76,63.54) v2(123.76,61.19) v2(123.81,47.85) v2(123.95,49.25) v2(124.46,57.59) v2(124.48,55.15) v2(124.48,52.77) v2(124.44,47.85) v2(124.79,112.2) v2(124.72,6.1) v2(124.97,65.95) v2(124.97,63.54) v2(124.97,61.19) v2(124.93,59.73) v2(124.93,59.09) v2(125.14,51.27) v2(125.14,50.68) v2(125.16,49.25) v2(125.44,46.64) v2(125.52,59.73) v2(125.52,59.09) v2(125.66,57.59) v2(125.69,55.15) v2(125.69,52.77) v2(125.8,113.94) v2(125.8,110.46) v2(126.17,65.95) v2(126.17,63.54) v2(126.17,61.19) v2(126.16,59.73) v2(126.16,59.09) v2(126.36,49.25) v2(126.34,47.71) v2(126.79,59.73) v2(126.79,59.09) v2(126.75,6.1) v2(126.87,57.59) v2(126.9,55.15) v2(126.9,52.77) v2(127.38,65.95) v2(127.38,63.54) v2(127.38,61.19) v2(127.37,10.26) v2(127.43,59.73) v2(127.43,59.09) v2(127.57,49.25) v2(127.8,113.94) v2(127.8,110.46) v2(127.99,51.25) v2(127.99,50.67) v2(127.97,10.24) v2(128.06,59.73) v2(128.06,59.09) v2(128.08,57.59) v2(128.1,55.15) v2(128.1,52.77) v2(128.58,65.95) v2(128.58,63.54) v2(128.58,61.19) v2(128.55,47.71) v2(128.55,10.22) v2(128.81,112.2) v2(128.78,6.1) v2(129.69,70.95) v2(129.69,70.3) v2(130.01,50.72) v2(130.41,114.9) v2(130.81,6.1) v2(132.49,114.89) v2(132.85,6.1) v2(133.2,23.68) v2(133.56,84.68) v2(133.91,25.59) v2(133.93,21.75) v2(134.23,86.58) v2(134.27,82.72) v2(134.52,114.89) v2(134.88,6.1) v2(136.15,87.38) v2(136.16,81.97) v2(136.16,26.32) v2(136.12,21.01) v2(136.55,114.89) v2(136.9,41.38) v2(136.91,6.1) v2(137.34,37.29) v2(137.62,47.01) v2(138.09,86.65) v2(138.07,82.72) v2(138.4,25.61) v2(138.4,21.71) v2(138.59,114.89) v2(138.66,37.29) v2(138.76,84.67) v2(138.94,6.1) v2(139.18,23.66) v2(140.49,45.71) v2(140.62,114.89) v2(140.87,14.74) v2(140.97,6.1) v2(141.41,14.49) v2(142.26,79.62) v2(142.26,78.61) v2(142.65,114.89) v2(142.87,22.52) v2(142.88,21.89) v2(143.01,6.1) v2(143.42,80.72) v2(143.42,77.57) v2(143.53,11.34) v2(144.25,75.27) v2(144.29,11.31) v2(144.34,70.05) v2(144.4,35.11) v2(144.44,80.72) v2(144.44,77.57) v2(144.42,35.75) v2(144.68,114.89) v2(145.02,34.81) v2(145.1,11.31) v2(145.04,6.1) v2(145.57,73.43) v2(145.86,79.62) v2(145.86,78.61) v2(146.59,73.43) v2(146.71,114.89) v2(147.07,6.1) v2(147.84,79.62) v2(147.84,78.61) v2(147.84,75.67) v2(147.84,74.66) v2(147.83,73.76) v2(147.87,38.29) v2(148.3,28.43) v2(148.29,27.82) v2(148.29,27.21) v2(148.29,26.58) v2(148.29,25.99) v2(148.3,25.41) v2(148.51,38.29) v2(148.68,6.8) v2(148.75,114.89) v2(148.92,28.43) v2(148.94,27.81) v2(148.92,27.22) v2(148.92,26.59) v2(148.94,25.99) v2(148.94,25.41) v2(149.01,80.72) v2(149.01,77.57) v2(149.14,38.29) v2(149.33,23.95) v2(149.88,75.67) v2(149.88,74.66) v2(149.94,23.95) v2(149.95,8.06) v2(150.03,80.72) v2(150.03,77.57) v2(150.78,114.89) v2(151.06,29.78) v2(151.16,73.43) v2(151.13,42.15) v2(151.45,79.62) v2(151.45,78.61) v2(151.9,52.61) v2(151.97,9.09) v2(152.17,73.43) v2(152.17,51.98) v2(152.33,53.25) v2(152.4,51.34) v2(152.61,52.61) v2(152.81,114.89) v2(152.99,53.22) v2(152.91,52) v2(153,41.27) v2(152.96,32.01) v2(153.11,51.37) v2(153.19,46.29) v2(153.19,45.65) v2(153.19,45.02) v2(153.29,52.61) v2(153.41,33.09) v2(153.37,32.51) v2(153.36,31.57) v2(153.42,75.67) v2(153.42,74.66) v2(153.6,52) v2(153.67,53.22) v2(153.88,51.37) v2(153.83,46.92) v2(153.83,46.29) v2(153.83,45.65) v2(153.83,45.02) v2(153.98,52.64) v2(154,9.09) v2(154.28,52) v2(154.36,53.22) v2(154.46,46.29) v2(154.46,45.65) v2(154.46,45.02) v2(154.66,52.61) v2(154.64,51.42) v2(154.78,24.68) v2(154.84,114.89) v2(155.05,53.22) v2(155.07,52) v2(155.43,52.64) v2(155.45,51.42) v2(155.76,53.22) v2(155.78,52.05) v2(156.04,9.09) v2(156.4,24.67) v2(156.43,53.21) v2(156.43,52.57) v2(156.43,51.94) v2(156.81,44) v2(157,52.89) v2(157,52.26) v2(157,51.62) v2(157.4,112.2) v2(157.51,53.21) v2(157.51,52.57) v2(157.51,51.94) v2(157.51,51.3) v2(158.02,53.53) v2(158.02,52.89) v2(158.02,52.26) v2(158.02,51.62) v2(158.02,50.99) v2(158.11,46.26) v2(158.11,41.75) v2(158.07,9.09) v2(158.18,24.67) v2(158.22,56.3) v2(158.22,54.38) v2(158.41,113.94) v2(158.41,110.46) v2(159.6,53.78) v2(159.6,53.14) v2(159.6,52.51) v2(159.6,51.87) v2(159.6,51.24) v2(159.6,50.6) v2(159.69,95.56) v2(159.67,94.95) v2(159.62,94.27) v2(159.64,56.3) v2(159.64,54.38) v2(159.96,24.67) v2(160.1,88.43) v2(160.1,87.79) v2(160.1,87.16) v2(160.1,86.52) v2(160.1,85.89) v2(160.1,9.09) v2(160.3,94.95) v2(160.25,94.27) v2(160.33,95.56) v2(160.41,113.94) v2(160.41,110.46) v2(160.66,88.81) v2(160.66,88.17) v2(160.66,87.54) v2(160.66,86.9) v2(160.66,86.27) v2(160.71,46.26) v2(160.71,41.75) v2(160.86,94.27) v2(160.94,95.56) v2(160.91,94.95) v2(161.24,88.4) v2(161.24,87.76) v2(161.24,87.13) v2(161.24,86.49) v2(161.24,85.86) v2(161.32,15.23) v2(161.42,112.2) v2(161.5,94.27) v2(161.57,95.56) v2(161.55,94.95) v2(161.78,88.76) v2(161.78,88.12) v2(161.78,87.49) v2(161.78,86.85) v2(161.78,86.22) v2(161.74,24.67) v2(162.01,44) v2(162.21,94.93) v2(162.16,94.24) v2(162.13,9.09) v2(162.23,95.54) v2(162.33,88.43) v2(162.33,87.79) v2(162.33,87.16) v2(162.33,86.52) v2(162.33,85.89) v2(162.79,94.24) v2(162.88,114.89) v2(162.87,95.54) v2(162.84,94.93) v2(162.97,88.83) v2(162.97,88.2) v2(162.97,87.56) v2(162.97,86.93) v2(162.97,86.29) v2(162.97,85.66) v2(163.11,68.57) v2(163.11,67.04) v2(163.11,65.52) v2(163.6,94.93) v2(163.6,89.72) v2(163.6,89.09) v2(163.6,88.45) v2(163.6,87.82) v2(163.6,87.18) v2(163.6,86.55) v2(163.6,85.91) v2(163.53,81.19) v2(163.54,80.59) v2(163.54,79.99) v2(163.54,79.36) v2(163.54,78.72) v2(163.54,78.09) v2(163.54,77.45) v2(163.63,95.54) v2(163.64,24.64) v2(163.63,24.04) v2(164.17,92.62) v2(164.17,90.7) v2(164.17,83.35) v2(164.17,81.43) v2(164.18,80.59) v2(164.18,79.99) v2(164.18,79.36) v2(164.18,78.72) v2(164.18,78.09) v2(164.18,77.45) v2(164.16,9.09) v2(164.27,95.54) v2(164.24,94.93) v2(164.24,90.1) v2(164.24,89.47) v2(164.24,88.83) v2(164.24,88.2) v2(164.24,87.56) v2(164.24,86.93) v2(164.24,86.32) v2(164.24,85.68) v2(164.64,68.57) v2(164.64,67.04) v2(164.64,65.52) v2(164.9,95.54) v2(164.87,94.93) v2(164.87,86.32) v2(164.87,85.68) v2(164.81,80.59) v2(164.81,79.99) v2(164.81,79.36) v2(164.81,78.72) v2(164.81,78.09) v2(164.81,77.45) v2(165.51,86.32) v2(165.51,85.68) v2(165.55,114.9) v2(165.54,95.55) v2(165.52,94.94) v2(165.58,92.62) v2(165.58,90.7) v2(165.58,83.35) v2(165.58,81.43) v2(166.16,94.94) v2(166.16,68.57) v2(166.16,67.04) v2(166.16,65.52) v2(166.2,9.09) v2(167.29,58.86) v2(167.29,57.34) v2(167.29,56.57) v2(167.58,114.9) v2(168.23,9.09) v2(168.94,27.13) v2(168.94,26.37) v2(169.61,114.9) v2(169.95,27.13) v2(169.95,26.37) v2(170.26,9.09) v2(170.97,27.13) v2(170.97,26.37) v2(171.64,114.9) v2(171.99,27.13) v2(171.99,26.37) v2(172.29,9.09) v2(172.37,77.72) v2(172.37,77.08) v2(172.37,76.45) v2(172.37,75.81) v2(173,27.13) v2(173,26.37) v2(173.45,49.57) v2(173.45,47.38) v2(173.68,114.9) v2(174.02,27.13) v2(174.02,26.37) v2(174.32,9.09) v2(174.54,48.47) v2(175.03,27.13) v2(175.03,26.37) v2(175.71,114.9) v2(175.64,49.57) v2(175.64,47.38) v2(176.08,30.65) v2(176.09,29.78) v2(176.38,35.69) v2(176.37,34.88) v2(176.39,31.45) v2(176.36,9.09) v2(176.57,36.52) v2(176.67,33.94) v2(176.67,33.31) v2(176.67,32.67) v2(177.19,67.62) v2(177.19,66.86) v2(177.19,65.91) v2(177.19,65.15) v2(177.16,36.53) v2(177.35,35.21) v2(177.35,34.58) v2(177.35,33.94) v2(177.35,33.31) v2(177.35,32.67) v2(177.35,32.04) v2(177.35,31.4) v2(177.74,114.9) v2(177.77,38.44) v2(177.77,37.8) v2(177.77,37.17) v2(177.75,36.53) v2(178.07,35.21) v2(178.07,34.58) v2(178.07,33.94) v2(178.07,33.31) v2(178.07,32.67) v2(178.07,32.04) v2(178.07,31.4) v2(178.35,38.44) v2(178.35,37.8) v2(178.35,37.17) v2(178.39,9.09) v2(179.77,114.9) v2(180.42,9.09) v2(181.04,112.15) v2(181.27,114.68) v2(181.99,113.6) v2(182.21,79.49) v2(182.19,8.21) v2(182.34,77.15) v2(182.59,83.62) v2(182.59,82.99) v2(182.59,82.35) v2(182.81,23.73) v2(183.21,112) v2(183.23,83.62) v2(183.23,82.99) v2(183.23,82.35) v2(183.44,26.75) v2(183.57,6.84) v2(183.67,85.15) v2(183.67,84.26) v2(183.86,83.62) v2(183.86,82.99) v2(184.31,85.15) v2(184.31,84.26) v2(185.28,111.91) v2(185.58,67.62) v2(185.58,66.86) v2(185.58,65.84) v2(185.58,65.21) v2(185.58,63.88) v2(185.58,63.24) v2(185.53,6.09) v2(185.63,23.69) v2(187.32,111.91) v2(187.56,6.09) v2(188.5,15.44) v2(189.07,67.62) v2(189.07,66.86) v2(189.07,65.85) v2(189.07,65.08) v2(189.35,111.91) v2(189.59,6.09) v2(190.1,15.18) v2(191.38,111.91) v2(191.37,16.25) v2(191.49,15.1) v2(191.62,6.09) v2(192.23,42.1) v2(193.07,85.02) v2(193.07,84.39) v2(193.07,83.75) v2(193.07,83.12) v2(193.07,82.48) v2(193.26,79.42) v2(193.39,76.96) v2(193.41,111.91) v2(193.7,85.02) v2(193.7,84.39) v2(193.7,83.75) v2(193.7,83.12) v2(193.7,82.48) v2(193.65,6.09) v2(194.34,85.02) v2(194.34,84.39) v2(194.34,83.75) v2(194.34,83.12) v2(194.34,82.48) v2(194.97,85.02) v2(194.97,84.39) v2(195.44,111.91) v2(195.75,8.17) v2(195.75,6.14) v2(196.05,10.14) v2(196.99,11.7) v2(197.39,94.17) v2(197.39,93.53) v2(197.39,92.9) v2(197.39,92.26) v2(197.45,67.62) v2(197.45,66.86) v2(197.45,65.85) v2(197.45,65.08) v2(197.45,64.07) v2(197.45,63.31) v2(197.62,111.96) v2(198.02,94.17) v2(198.02,93.53) v2(198.02,92.9) v2(198.02,92.26) v2(198.53,12.82) v2(198.8,113.15) v2(199.27,20.58) v2(199.57,114.43) v2(199.85,23.6) v2(199.83,22.44) v2(200.59,13.25) v2(201.15,114.89) v2(202.5,55.53) v2(202.56,12.78) v2(203.03,60.68) v2(203.18,114.89) v2(203.17,58.73) v2(203.14,57.49) v2(203.48,16.38) v2(203.74,54.03) v2(204,11.72) v2(204.18,16.38) v2(204.94,22.85) v2(204.94,21.2) v2(205.06,9.82) v2(205.21,114.89) v2(205.24,7.79) v2(205.24,5.76) v2(205.24,3.73) v2(205.24,1.7) v2(206.32,0.5) v2(206.6,22.85) v2(206.6,21.2) v2(207.24,114.89) v2(208.35,0.5) v2(208.49,112.2) v2(209.5,113.94) v2(209.5,110.46) v2(210.08,14.41) v2(210.29,114.9) v2(210.38,0.5) v2(211.5,113.94) v2(211.5,110.46) v2(211.73,17.31) v2(211.99,24.82) v2(211.99,23.05) v2(211.99,19.36) v2(211.97,14.42) v2(212.51,112.2) v2(212.41,0.5) v2(212.68,114.9) v2(212.7,109.34) v2(212.69,107.42) v2(212.7,105.28) v2(212.7,103.25) v2(212.7,101.21) v2(212.7,99.18) v2(212.7,97.15) v2(212.7,95.12) v2(212.7,93.09) v2(212.7,91.05) v2(212.7,89.02) v2(212.7,86.99) v2(213.2,17.84) v2(213.66,85.2) v2(214.44,0.5) v2(215.83,84.84) v2(215.83,82.81) v2(215.83,80.78) v2(215.83,78.75) v2(215.83,76.72) v2(215.83,74.68) v2(215.83,72.65) v2(215.83,70.62) v2(215.83,68.59) v2(215.83,66.56) v2(215.83,64.52) v2(215.83,62.49) v2(215.83,60.46) v2(215.89,58.4) v2(216.06,56.45) v2(216.34,54.52) v2(216.48,0.5) v2(216.72,52.65) v2(216.84,3.34) v2(216.84,2.62) v2(216.84,1.72) v2(217.19,50.82) v2(217.77,48.98) v2(218.42,47.28) v2(219.14,45.64) v2(219.74,20) v2(219.74,19.24) v2(219.94,44.05) v2(219.99,18.22) v2(219.99,17.46) v2(220.5,20) v2(220.5,19.24) v2(220.77,42.59) v2(220.83,0.5) v2(220.99,29.2) v2(221.01,18.22) v2(221.01,17.46) v2(221.69,41.14) v2(222.19,31.29) v2(222.19,27.11) v2(222.66,39.77) v2(222.86,0.5) v2(223.82,38.3) v2(224.61,31.29) v2(224.61,27.11) v2(224.9,0.5) v2(225.11,36.85) v2(225.81,29.2) v2(226.67,35.28) v2(226.98,33.62) v2(226.98,31.59) v2(226.98,29.18) v2(226.98,26.64) v2(226.98,24.91) v2(226.98,22.88) v2(226.98,20.85) v2(226.98,18.82) v2(226.98,16.78) v2(226.98,14.75) v2(226.98,12.72) v2(226.98,10.69) v2(226.98,8.66) v2(226.98,6.62) v2(226.98,4.59) v2(226.98,2.56) v2(226.98,0.53) v4(22.53,54.78) v4(32.41,25.84) v4(45.49,21.9) v4(75.97,8.77) v4(79.05,101) v4(101.37,86.67) v4(112.8,98.74) v4(127.92,9.46) v4(152.17,46.29) v4(157.38,49.46) v4(158.3,57.84) v4(165.22,96.07) v4(170.11,107.54) v4(180.08,36.77) v4(184.43,83.37) v4(193.96,85.91)
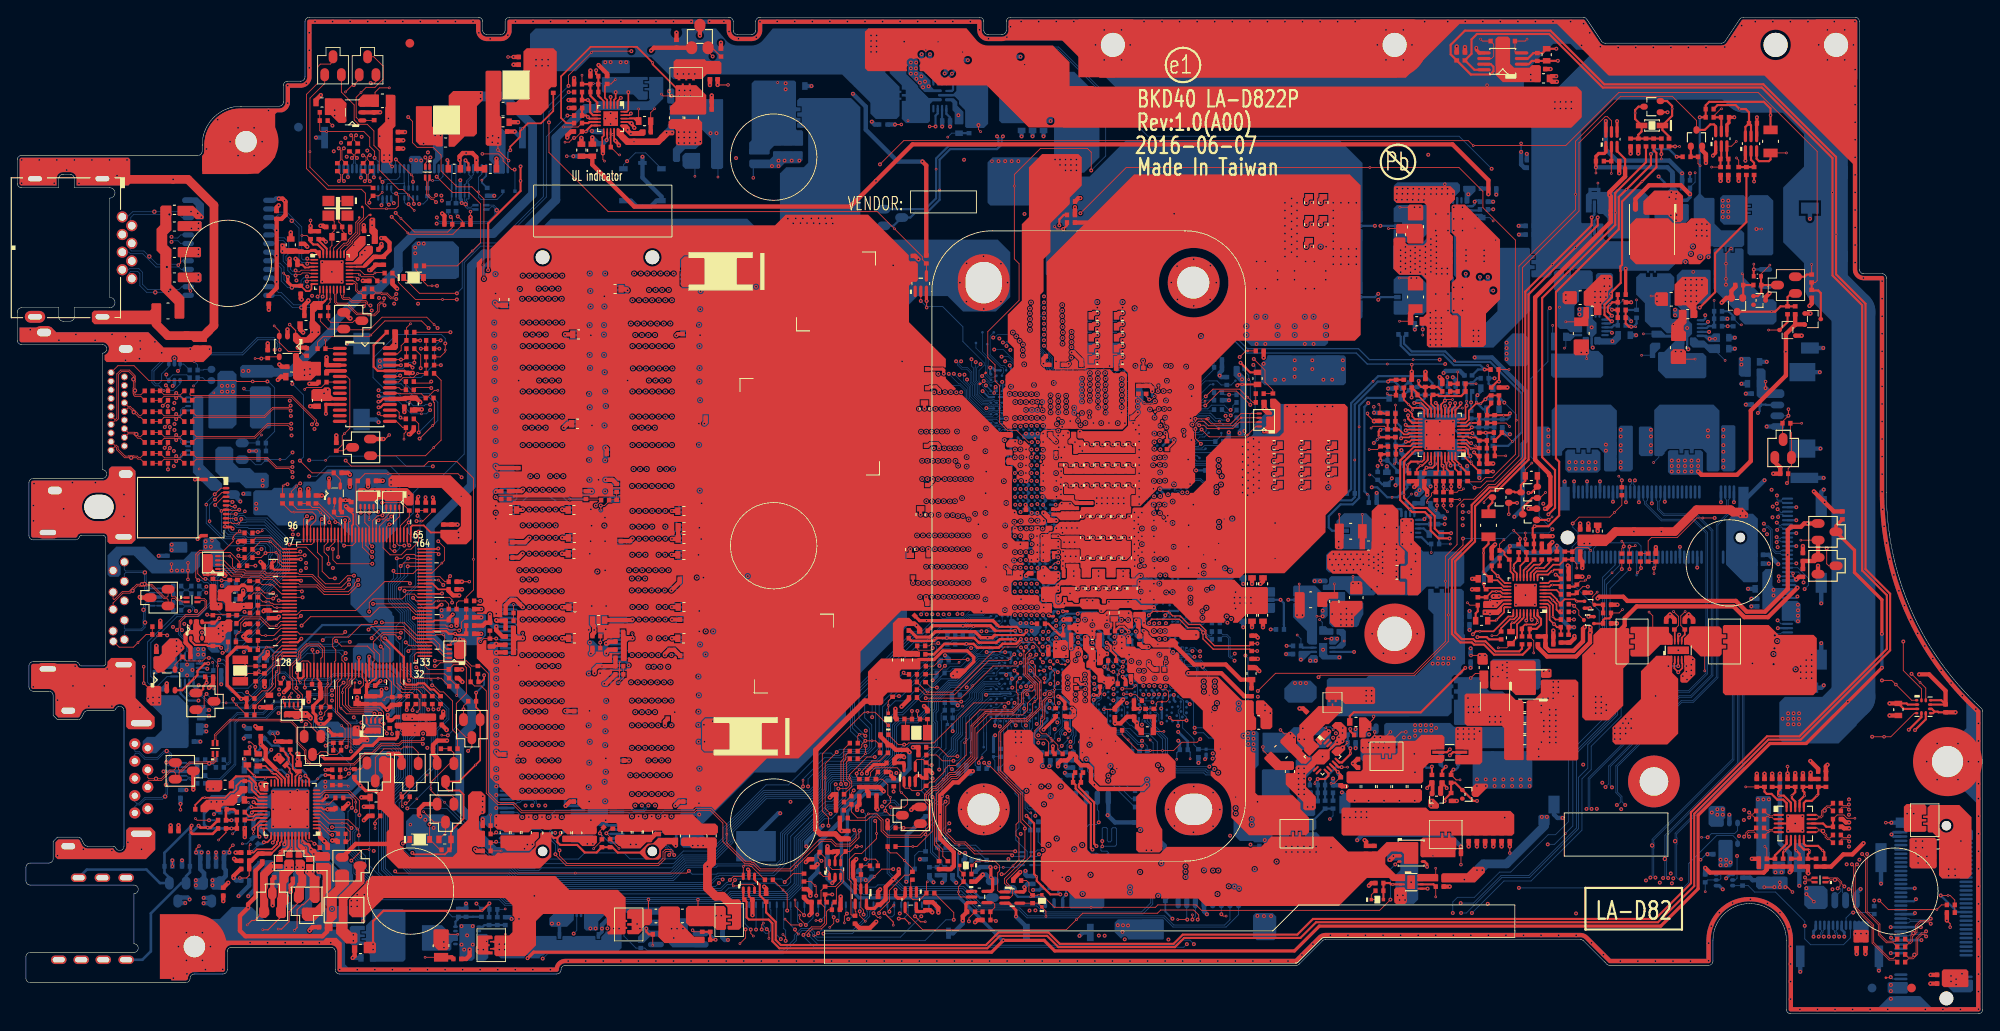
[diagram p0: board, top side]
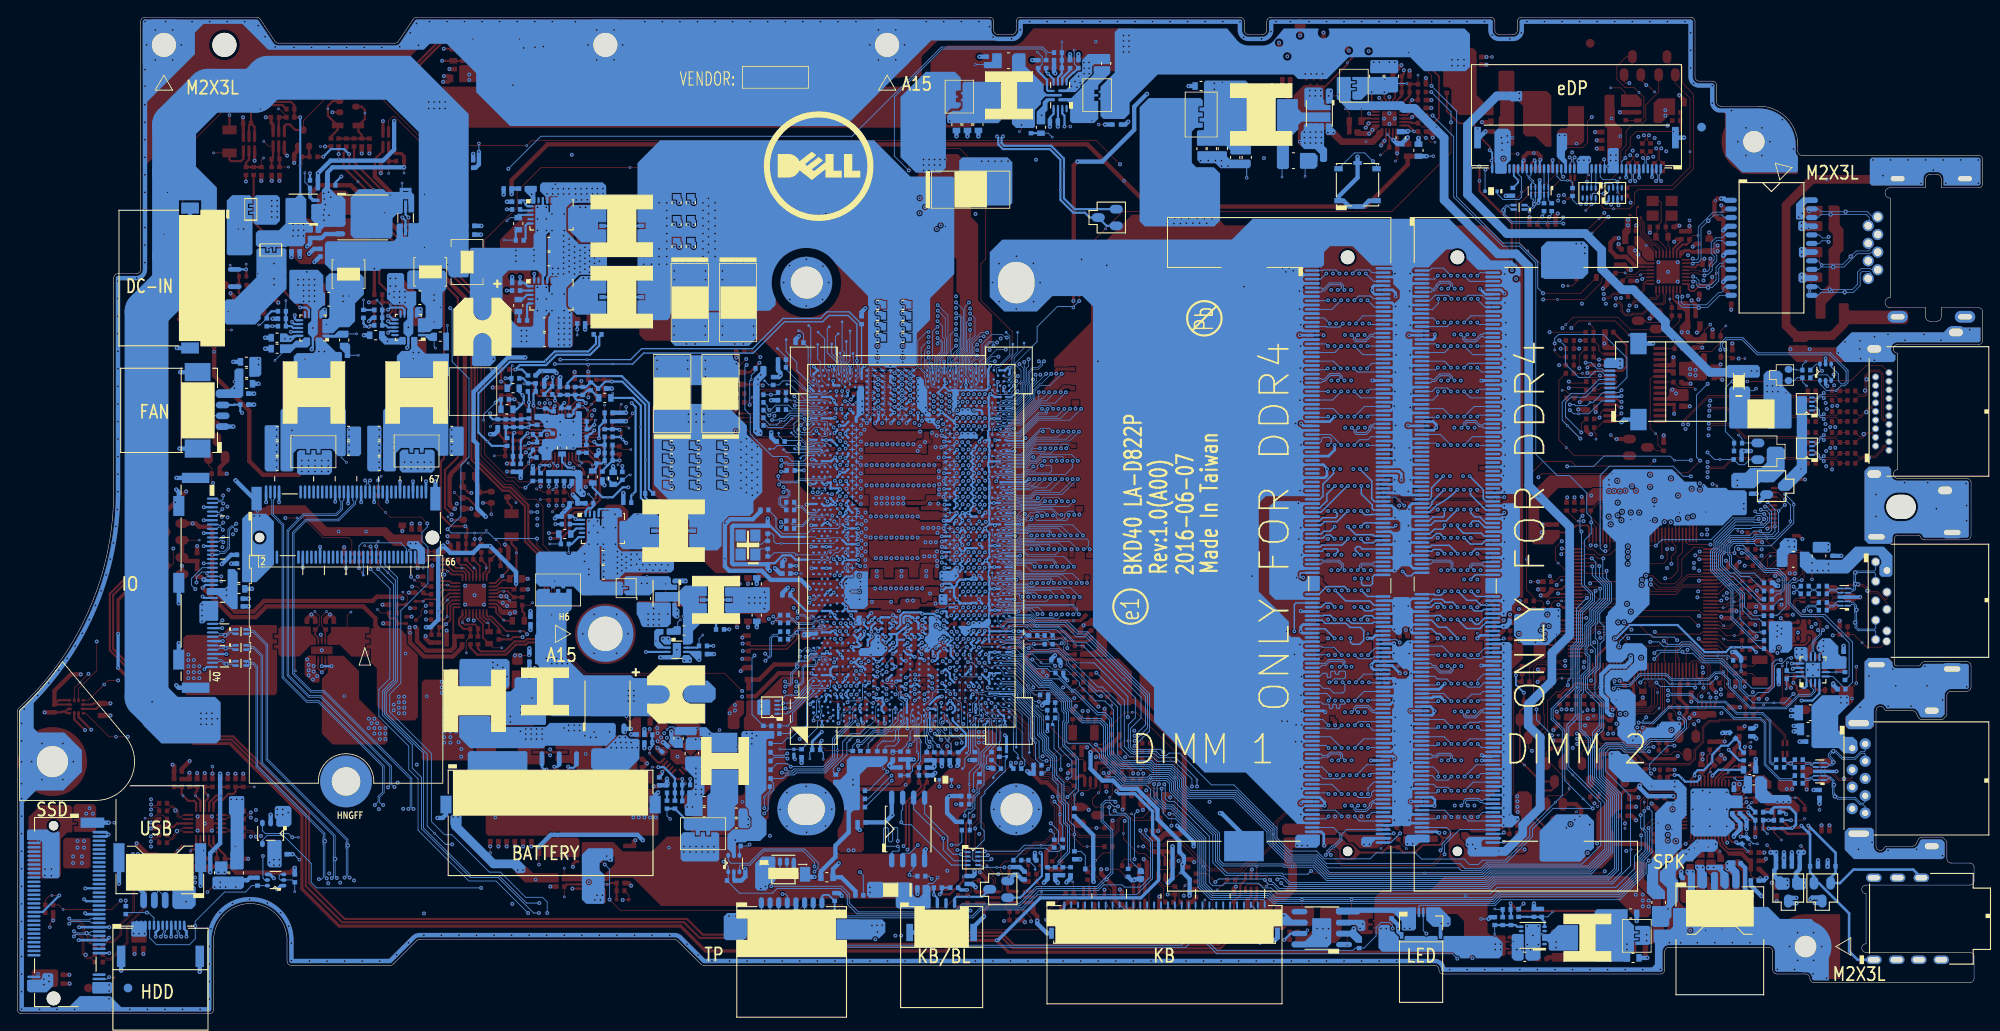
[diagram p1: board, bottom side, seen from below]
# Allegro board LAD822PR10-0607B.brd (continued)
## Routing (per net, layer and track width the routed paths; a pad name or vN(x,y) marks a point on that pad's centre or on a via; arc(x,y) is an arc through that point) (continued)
GNDA: length 49.7
  TOP w0.127: v2(18.89,24.32) v4(18.89,23.62) ; v2(17.95,17.76) v4(17.95,17.09) ; v4(23,18.04) v2(23,18.69)
  TOP w0.203: v2(29.57,19.82) 29.57,19.88 29.79,20.1 UA1.38
  TOP w0.508: v2(25.04,15.73) 25.04,15.95 25.85,16.76 CA61.2 ; v2(25.09,17.95) 25.33,17.71 C2715.2 ; CA63.1 v2(25.26,18.66) ; RA1116.1 v2(18.66,21.83) ; RA1115.1 v2(24.41,15.17) ; v2(26.33,20.45) RA84.2
  GND1 w0.254: JHP.6 10.93,15.75 ; JHP.6 8.77,16.42 ; JHP.6 9.85,16.42 ; JHP.6 8.77,15.75 ; JHP.6 10.93,16.42 ; 9.95,5.58 JHP.7 ; JHP.7 11.03,5.58 ; JHP.7 8.87,6.25 ; JHP.7 8.87,5.58 ; JHP.7 11.03,6.25
  VCC w0.254: 8.77,15.75 JHP.6 ; JHP.6 8.77,16.42 ; JHP.6 10.93,16.42 ; JHP.6 10.93,15.75 ; JHP.6 9.85,16.42 ; JHP.7 11.03,6.25 ; JHP.7 11.03,5.58 ; JHP.7 8.87,6.25 ; JHP.7 9.95,5.58 ; JHP.7 8.87,5.58
  GND2 w0.254: JHP.6 10.93,16.42 ; JHP.6 10.93,15.75 ; JHP.6 8.77,16.42 ; JHP.6 9.85,16.42 ; JHP.6 8.77,15.75 ; 8.87,6.25 JHP.7 ; JHP.7 11.03,5.58 ; JHP.7 8.87,5.58 ; JHP.7 9.95,5.58 ; JHP.7 11.03,6.25
  BOTTOM w0.508: v2(22.09,18.68) CA76.2 CA40.2 ; v2(26.22,31.87) 26.47,32.13 RA29.1 ; v3(28.79,26.59) 28.79,26.59 RA30.1 ; CA74.2 v2(26.28,29.51) ; RA31.1 v2(18.89,24.32) ; CA39.2 v2(19.07,17.76) ; v2(23,18.69) CA75.2 CA38.2 ; v2(25.04,15.73) 25.33,15.44 RA32.1 ; CA33.2 v2(17.95,17.76)
  vias: v2(22.44,24.53) v2(23.08,24.53) v2(23.78,24.53) v3(28.16,26.59)
VCC_EDRAM_SENSE: length 1.1
  TOP w0.089: v2(124.08,69.65) 124.08,69.18 124.1,69.17 T134.1
  BOTTOM w0.076: UC1.AC63 123.74,69.31 v2(124.08,69.65)
VCC_GT_5V: length 10.8
  IN1 w0.508: v2(167.64,85.69) 168.76,86.81 168.76,92 167.94,92.82 v2(167.94,94.9)
  BOTTOM w0.254: PU605.14 v2(167.64,85.69)
VCC_GT_SENSE: length 62.8
  TOP w0.254: v2(130.3,75.62) 130.33,75.59 RC161.2 ; PR622.1 v2(169.95,67.29) 170.88,67.29 PC617.1
  IN1 w0.152: v2(165.26,75.24) 167.62,75.24 171.12,71.74 171.12,70.06 169.38,68.32 169.38,67.86 v2(169.95,67.29)
  BOTTOM w0.076: UC1.J70 130.18,74.12 130.18,75.02 130.3,75.15
  BOTTOM w0.152: 130.3,75.15 v2(130.3,75.62) 130.3,79.87 131.3,80.87 133.53,80.87 134.27,80.13 138.68,80.13 142.3,76.51 154.97,76.51 156.24,75.24 v1(158.56,75.24) v2(165.26,75.24)
  BOTTOM w0.254: v2(169.95,67.29) 170.11,67.13 PC620.1 170.1,64.53 PC618.2
VCCEOPIO_SENSE: length 1.4
  TOP w0.089: v2(118.67,69.88) 118.38,70.18 T136.1
  BOTTOM w0.076: UC1.AL63 119.15,69.4 v2(118.67,69.88)
VCCHDA: length 4.3
  TOP w0.254: RC1138.1 119.33,45.17 v1(120.1,44.4) 120.64,43.86 CC215.1 121.05,44.89 v2(121.1,44.94)
  BOTTOM w0.254: v2(121.1,44.94) 120.77,44.61 UC1.AJ19
VCCIO_SENSE: length 2.9
  TOP w0.254: T4947.1 v2(121.02,46.6)
  BOTTOM w0.076: UC1.AM23 119.52,47.52 120.15,46.9 120.73,46.9 v2(121.02,46.6)
VCCSA_B+: length 0.8
  TOP w0.102: v2(154.59,49.84) v1(154.59,50.66)
  vias: v2(155.22,49.84)
VCCSENSE: length 48.5
  TOP w0.254: PC651.2 162.5,72.59 162.19,72.9 v2(162.19,73.29) ; PC651.2 PR648.1 164.4,72.59 164.92,72.07 PC639.1 ; PC651.2 162.97,72.59 PC653.1
  IN1 w0.152: v2(132.98,52.65) 136.54,52.65 v2(137.32,51.87)
  IN3 w0.152: v2(162.19,73.29) 160.67,71.76 158.06,71.76 154.23,67.94 146.02,67.94 145.1,67.03 145.09,67.03 144.58,66.52 144.58,60.35 138.22,53.98 138.22,53.36 137.63,52.78 137.63,52.19 v2(137.32,51.87)
  BOTTOM w0.152: UC1.E32 132.59,52.26 v2(132.98,52.65)
  BOTTOM w0.254: RC140.2 v2(137.32,51.87)
VCCSENSE_VCCGTUS: length 33.6
  TOP w0.102: v1(120.04,91.16) 120.33,90.87 v2(121.05,90.87)
  TOP w0.254: RC340.2 121.49,91.32 v2(121.05,90.87)
  IN3 w0.135: v2(120.32,68.28) 120.32,68.68 120.66,69.02 121.64,69.02 121.95,69.32 121.95,70.35 122.36,70.76
  IN3 w0.254: v2(121.05,90.87) 121.05,91.11 121.59,91.65 122.32,91.65 125.12,88.85 125.12,83.75 126.01,82.86 126.01,75.81 125.18,74.99 122.93,74.99 122.36,74.41 122.36,70.76
  BOTTOM w0.076: v2(120.32,68.28) 119.95,68.66 UC1.AK62
VCCST_PWRGD: length 5.1
  BOTTOM w0.076: UC1.B65 134.93,70.48 135.45,70.48 135.77,70.8 137.32,70.8 v1(137.46,70.94) 137.58,71.06 137.95,71.06
  BOTTOM w0.102: RC78.2 CC1808.1 138.5,71.06 137.95,71.06
VCCSTG_EN: length 4.1
  TOP w0.102: UC15.4 117.5,12.81 RZ1702.1 118.15,12.81 DZ1701.1 118.58,12.34 119.05,11.87 v1(119.05,11.26)
VCCSTG_EN_R: length 50.5
  TOP w0.102: CZ1702.1 116.81,15.43 117.08,15.15 117.08,14.14 RZ1702.2 118.09,13.72 118.14,13.78 DZ1701.2 120.03,12.33 v1(124.27,12.33) 131.73,12.33 132.01,12.61 136.43,12.61 137.06,11.97 157.67,11.97 v2(158.92,13.22) ; UZ19.4 159.81,17.63 v2(159.48,17.29)
  BOTTOM w0.102: v2(158.92,13.22) 158.92,16.73 v2(159.48,17.29)
VDD_1.2V: length 8.2
  TOP w0.102: v2(67.78,99.65) 67.78,98.94 v1(67.97,98.74)
  TOP w0.203: PR205.1 67.69,100.44 67.69,101.51 67.87,101.68 PU200.11
  TOP w0.508: PR206.2 v2(65.28,101.43) ; v2(67.78,99.65) PR205.1
  IN1 w0.508: v2(67.78,99.65) 67.06,99.65 v2(65.28,101.43)
  BOTTOM w0.508: PC209.1 65.31,101.4 v2(65.28,101.43)
VDD_CHG: length 28.6
  TOP w0.203: v2(172.75,54.16) 172.67,54.08 PR749.2 ; PU703.19 171.97,49.07 171.73,49.31 170.16,49.31 PR760.1 169.74,49.4 v2(169.74,49.79) ; PR750.2 v2(178.18,54.2) ; v2(180.18,44.76) PR741.1
  TOP w0.254: PR741.1 PC768.2
  BOTTOM w0.508: v2(180.18,44.76) 179.63,44.76 178.76,45.64 v1(178.76,46.64) 178.76,53.62 v2(178.18,54.2) 177.35,53.37 174.72,53.37 173.93,54.16 v2(172.75,54.16) 169.74,51.15 v2(169.74,49.79)
VDDP_CHG: length 3.8
  TOP w0.203: PU703.20 171.9,48.67 171.66,48.92 v1(171.17,48.92) 170.68,48.92 PR760.2
  TOP w0.254: PR760.2 PC769.2
VIN_+VCCEOPIO:
  vias: v1(103.09,103.42)
VSS_EDRAM_SENSE: length 1.3
  TOP w0.089: T135.1 122.77,68.67 v2(122.77,68.66)
  BOTTOM w0.076: UC1.AE63 v2(122.77,68.66)
VSS_GT_SENSE: length 63.5
  TOP w0.203: PU602.6 168.39,67.24 v2(168.41,67.23)
  IN1 w0.152: v2(164.62,75.75) 164.62,74.99 164.88,74.73 167.59,74.73 170.74,71.58 170.74,70.22 169,68.48 169,67.83 v2(168.41,67.23)
  BOTTOM w0.076: 129.89,75.2 130,75.09 130,73.86 130.43,73.43 UC1.J69
  BOTTOM w0.152: v2(164.62,75.75) v1(161.55,75.75) 156.49,75.75 155.22,77.02 142.36,77.02 138.85,80.53 134.51,80.53 133.75,81.29 131.18,81.29 RC163.1 129.76,75.33 129.89,75.2
  BOTTOM w0.254: v2(168.41,67.23) 169.19,66.44 PC620.2 169.21,64.53 PC619.2
VSSEOPIO_SENSE: length 1.1
  TOP w0.089: v2(120.91,68.54) 120.55,68.89 T137.1
  BOTTOM w0.076: UC1.AJ62 120.6,68.84 v2(120.91,68.54)
VSSIO_SENSE: length 1.2
  TOP w0.254: v2(119.38,46.13) 119.49,46.03 T4948.1
  BOTTOM w0.076: UC1.AM22 119.05,46.46 v2(119.38,46.13)
VSSSENSE: length 49.7
  TOP w0.203: PC653.2 163.64,70.08 PU602.18
  TOP w0.254: PC653.2 162.06,71.86 PC654.2 161.38,71.38 v2(161.37,71.37)
  IN1 w0.152: v2(137.32,50.99) 136.1,52.21 132.7,52.21 v2(132.27,52.64)
  IN3 w0.152: v2(137.32,50.99) 138.01,51.68 138.01,52.62 138.61,53.22 138.61,53.84 144.96,60.19 144.96,66.36 145.24,66.64 145.26,66.64 146.17,67.56 154.3,67.56 158.12,71.38 161.37,71.38 v2(161.37,71.37)
  BOTTOM w0.076: v2(137.32,50.99) v1(136.73,50.99)
  BOTTOM w0.152: UC1.E33 132.27,52.68 v2(132.27,52.64)
  BOTTOM w0.254: RC141.1 v2(137.32,50.99)
VSSSENSE_VCCGTUS: length 35.8
  TOP w0.254: v2(120.6,91.3) 120.6,91.99 121.12,92.51 RC341.1
  IN3 w0.135: 122.71,70.54 122.84,70.42 122.84,69.34 122.32,68.82 122.32,68.37 121.75,67.81 121.32,67.81 121.05,67.53 v2(120.49,67.53)
  IN3 w0.254: 122.71,70.54 122.71,74.28 123.08,74.64 125.32,74.64 126.4,75.72 126.4,83.01 125.5,83.91 125.5,89.01 122.48,92.03 121.44,92.03 120.7,91.3 v2(120.6,91.3)
  BOTTOM w0.076: v2(120.49,67.53) 120.49,67.57 119.97,68.09 UC1.AL61
+A_VCC: length 6.6
  TOP w0.254: 29.93,28.31 29.93,28.25 30.99,27.2 UA1.20
  TOP w0.508: RA10.2 v1(28.18,31.21) 28.74,30.65 28.74,29.5 29.93,28.31
+DCBATOUT_LCD: length 2.5
  TOP w0.127: v4(56.86,98.8) v4(55.63,100.03) v2(55.63,100.82)
  vias: v2(54.97,100.92) v2(55.02,101.66) v2(55.71,101.46) v4(54.46,101.46)
+IR_LED+: length 11.9
  TOP w0.203: R6528.1 62.03,104.54 60.61,103.12 59.1,103.12 v1(58.46,102.48) 58.19,102.22 58.19,101.56 57.05,100.41 v2(57.05,100.01)
  BOTTOM w0.203: JEDP.40 56.77,99.72 v2(57.05,100.01)
+LAN_VDDREG: length 18.9
  TOP w0.127: v1(30.81,85.77) 31.26,85.32 v2(31.31,85.32)
  TOP w0.203: UL1.8 34.12,84.51 34.05,84.44 34.05,83.92 33.81,83.68 33.42,83.68 CL6.1 ; UL1.3 33.84,86.51 33.74,86.42 33.3,86.42 33.27,86.45 ; 35.81,88.61 UL1.30 ; 39.26,86.51 UL1.22
  TOP w0.254: CL12.1 34.89,89.53 35.81,88.61 ; 33.27,86.45 32.99,86.74 CL7.1 ; 40.28,86.67 40.11,86.51 39.26,86.51
  TOP w0.381: CL12.1 35.41,89.71 v2(35.72,89.4) ; CL6.1 31.75,84.3 31.31,84.74 v2(31.31,85.32)
  TOP w0.508: v2(42.12,89.82) 42.55,89.82 43.08,89.29 43.08,88.41 42.41,87.74 CL2.1 CL4.1 41.25,87.65 40.28,86.67 ; CL7.1 32.43,87.21 v2(32.2,87.43)
  vias: v2(41.05,91.94) v2(41.06,91.31)
+LCDVDD: length 2.9
  TOP w0.102: R5211.2 41.41,106.71 41.92,107.23 v1(43.06,107.23)
+LCDVDD_LCD: length 0.8
  TOP w0.127: v2(43.08,98.8) 43.08,98.42 v4(43.39,98.12)
  vias: v2(42.45,99.44) v2(42.45,98.8) v2(43.08,99.44) v4(41.95,101.63) v4(42.95,103.69)
+MIC2-VREFO: length 14.4
  TOP w0.102: v1(29.54,32.43) 29.86,32.11 v2(29.86,31.53)
  TOP w0.254: UA1.29 28.54,24.27 27.63,24.27 27.46,24.44 27.4,24.44 v2(27.33,24.51)
  TOP w0.508: RA1109.2 RA53.2 30.61,31.53 v2(29.86,31.53)
  IN3 w0.508: v2(29.86,31.53) 30.04,31.53 31.08,30.49 31.08,29.46 30.19,28.57 28.86,28.57 26.89,26.6 26.89,25.01 27.33,24.57 v2(27.33,24.51)
+RTC_CELL: length 343.7
  TOP w0.381: RE31.1 RE437.2 25.96,36.51 v2(25.91,36.46) 25.89,36.46 24.29,38.05 24.29,41.32 25.42,42.45 26.64,42.45 RE349.2 ; v2(59.06,6.43) 59.76,7.13 112.76,7.13 v2(114.13,8.5) 118.85,8.5 120.07,7.27 147.82,7.27 150.69,10.15 190.21,10.15 194.53,14.47 194.53,22.98 202.85,31.3 207.04,31.3 v4(211.86,36.13) v2(215.8,40.06) ; C2503.1 210.49,56.52 D2501.1 212.63,53.68 212.63,51.11 215.8,47.94 v2(215.8,44)
  TOP w0.508: CC270.1 98.52,25.6 98.35,25.78 RC56.2 ; RC56.2 RC69.1 ; RC56.2 99.37,26.25 RC57.2 99.78,26.25 v2(100.27,25.76) ; v2(27.55,33.29) 27.78,33.07 RA10.1
  IN1 w0.381: v2(59.06,6.43) 58.85,6.22 51.12,6.22 50.42,6.93 50.42,10.76 48.66,12.52 46.87,12.52 42,17.39 42,19.17 37.3,23.88 37.3,25.41 36.97,25.73 36.97,28.76 35.84,29.89 35.84,30.12 31.15,34.82 v2(30.24,34.82) 29.7,35.36 29.7,35.43 28.55,36.58 27.1,36.58 26.89,36.38 25.99,36.38 v2(25.91,36.46)
  IN1 w0.508: v2(100.27,25.76) 100.85,26.34 101.79,26.34 105.44,29.98 107.32,29.98 107.88,30.54 108.3,30.54 110.43,32.67 110.43,36.45 109.22,37.65 109.22,38.51 109.55,38.84 109.55,40.11 108.54,41.13 107.75,41.13 v2(107.37,41.51) 107.37,42.2 108.28,43.11 110.97,43.11 v2(112.19,41.89)
  IN3 w0.254: v2(112.19,41.89) 115.13,44.83 115.64,44.83 115.67,44.79 120.1,44.79 v2(120.23,44.93)
  IN3 w0.508: v2(27.55,33.29) 28.72,33.29 v2(30.24,34.82)
  BOTTOM w0.254: v2(120.23,44.93) 119.92,44.61 UC1.AK19 ; v2(112.19,41.89) 112.34,41.89 112.34,41.89 112.89,41.89 112.9,41.89 112.99,41.89 UC1.BB14
  BOTTOM w0.381: v2(100.27,25.76) 99.99,25.47 98.11,25.47 96.08,23.44 96.08,20.8 95.38,20.1 95.38,15.47 97.44,13.42 109.07,13.42 113.99,8.5 v2(114.13,8.5) ; v2(215.8,40.06) v2(215.8,44)
  BOTTOM w0.508: CC213.1 107.8,41.08 v2(107.37,41.51)
+RTC_CELL_VBAT: length 5
  TOP w0.102: UE1.122 30.41,43.82 v1(29.98,43.39) 29.71,43.39 29.56,43.24 CE73.1 27.84,43.23 RE349.1
+RTC_VCC: length 1.7
  TOP w0.127: v2(205.9,50.29) 205.51,50.67 v4(205.51,50.99)
  TOP w0.508: v2(205.9,50.29) 206.2,50.59 R2502.1
+TP_VDD: length 134.9
  TOP w0.203: RZ19.1 53.31,38.51 RZ18.1 53.7,38.44 54.03,38.77 v2(54.03,39.2) ; v2(45.72,18.63) 45.89,18.46 49.5,18.46 R6505.1 50.19,19.16 R6211.1 50.19,21.14 51.65,22.6 51.65,25.38 51.18,25.85 49.91,25.85 49.56,26.21 Q6203.1 51.12,26.89 v1(53.04,28.81) 53.57,29.34 Q6204.2 53.57,35.01 53.1,35.48 R6203.2 v2(53.1,37.18) ; v2(94.32,13.81) R6508.1 93.49,13.11 R6506.1
  IN1 w0.203: v2(133.7,11.01) 122.63,11.01 120.6,8.97 103.33,8.97 102.14,10.17 98,10.17 96.87,11.3 96.87,11.69 96.17,12.39 95.74,12.39 v2(94.32,13.81)
  IN2 w0.203: v2(45.72,18.63) 45.77,18.68 46.54,18.68 51.01,14.21 55.18,14.21 56.19,13.2 56.74,13.2 58.32,11.62 80.02,11.62 80.55,12.15 83.57,12.15 84.08,12.66 86.72,12.66 88.85,14.79 93.35,14.79 v2(94.32,13.81)
  BOTTOM w0.203: TPAD1.8 134.35,13.57 134.15,13.76 133.57,13.76 C6201.1 132.87,11.83 v2(133.7,11.01) ; v2(54.03,39.2) 54.03,38.11 v2(53.1,37.18)
+TPAN_VDD:
  vias: v2(48.35,101.72) v2(48.99,101.72) v4(47.02,100.77)
+USB30_VCCA: length 2.7
  TOP w0.127: v4(19.76,52.22) v2(19.76,51.32) v4(19.76,50.3) ; v2(17.85,51.32) v4(17.85,52.08)
  vias: v2(18.49,51.32) v2(19.12,51.32) v2(20.92,42.22) v2(20.92,41.59) v2(21.56,42.22) v2(21.56,41.59)
+USB30_VCCB: length 2.8
  TOP w0.127: 15.14,37.65 15.14,37.78 v4(14.63,38.29) v4(14.63,40.19)
  vias: v2(15.71,36.63) v2(15.71,36) v2(16.41,36.63) v2(16.41,36) v4(15.14,36.51)
+USB30_VCCC: length 39.2
  TOP w0.127: v2(207.06,13.85) v4(207.93,12.98)
  IN2 w1.524: 196.93,21.85 196.93,21.24 198.78,19.39 206.33,19.39 208.84,16.87 208.84,15.25
  IN2 w2.032: 205.51,43.87 205.51,41.94 197.51,33.94 197.51,25.2
  vias: v2(196.12,23.3) v2(196.75,23.68) v2(196.75,23.05) v2(197.39,23.68) v2(197.39,23.05) v2(206.09,47.37) v2(206.09,46.73) v2(206.09,46.1) v2(206.09,45.46) v2(207.06,14.54)
+V_DDR_REFA: length 2.5
  TOP w0.102: v2(71.2,43.47) 71.2,43.98 v1(71.16,44.02)
  BOTTOM w0.305: v2(71.2,43.47) 70.62,43.47 70.27,43.83 JDIMM1.164
+V_DDR_REFA_R: length 142.1
  TOP w0.508: RH484.1 CH101.1 v1(67.67,40.25) 67.17,40.25 66.81,39.89 v2(66.81,39.44)
  IN1 w0.381: 65.28,54.82 65.28,56.24 66.35,57.31 66.98,57.31 68.69,59.01 68.69,62.44 68.04,63.09 65.52,63.09 64.52,64.09 64.52,85.94 67.43,88.85 102.54,88.85 106.07,92.38 114.92,92.38 122.54,84.76 122.54,75.38 121.41,74.24 115.05,74.24 v2(113.99,73.17)
  IN1 w0.508: v2(66.81,39.44) 66.81,39.83 67.44,40.47 68.2,40.47 68.89,41.16 68.89,44.81 67.25,46.45 67.25,47.39 65.28,49.36 65.28,54.82
  BOTTOM w0.152: UC1.AY67 114.06,72.18 114.06,73.1 v2(113.99,73.17)
+V_DDR_REFB: length 2.5
  TOP w0.102: v2(58.5,43.47) v1(58.5,44.08)
  BOTTOM w0.305: JDIMM2.164 58.14,43.83 v2(58.5,43.47)
+V_DDR_REFB_R: length 137.9
  TOP w0.089: v2(113.23,72.59) 113.06,72.42 v4(113.06,71.89)
  TOP w0.508: v2(55.43,45.58) 55.49,45.53 CH100.1 RH485.1
  IN1 w0.381: v2(55.43,45.58) 55.56,45.58 57.2,47.23 57.2,87 59.75,89.54 102.52,89.54 105.86,92.89 115.13,92.89 123.17,84.84 123.17,75.33 121.46,73.61 115.19,73.61 114.17,72.59 v2(113.23,72.59)
  BOTTOM w0.254: UC1.BA67 113.34,72.48 v2(113.23,72.59)
AC_DIS: length 257.1
  TOP w0.102: PQ709.5 184.5,103.42 184.03,103.89 183.77,103.89 180.75,100.87 180.75,92.96 174.2,86.41 174.2,64.45 171.02,61.27 170.25,61.27 168.56,59.58 167.44,59.58 166.63,58.78 166.63,54.33 165.28,52.98 v1(165.28,50.1) 165.28,43.1 161.61,39.43 145.62,39.43 v2(143.58,37.38) ; v2(44.79,54.22) 44.17,54.22 43.94,54.45 UE1.69
  IN2 w0.127: v2(143.58,37.38) 142.66,36.47 142.66,35.05 140.57,32.96 140.57,28.09 139.64,27.16 134.19,27.16 132.34,25.31 130.58,25.31 125.07,30.81 125.07,39.04 124.42,39.7 123.36,39.7 122,38.34 122,36.79 120.2,34.98 118.49,34.98 117.76,34.25 111.98,34.25 111.63,33.89 102.06,33.89 101.37,33.21 101.37,30.28 99.72,28.62 98.88,28.62 98.29,29.2 94.12,29.2 92.85,27.93 89.81,27.93 82.36,20.49 81.89,20.49 79.29,17.89 77.3,17.89 76.72,17.3 60.35,17.3 59.03,18.63 58.59,18.63 56.8,20.42 56.8,27.95 54.92,29.83 54.92,31.51 54.12,32.31 54.12,37.54 52.91,38.74 52.91,40.77 51.45,42.24 50.49,42.24 47.76,44.97 47.76,51.25 v2(44.79,54.22)
AC_PRESENT: length 17.8
  TOP w0.102: v2(102.05,36.79) 101.38,36.79 RC243.1 100.8,36.21 v1(100.8,35.72) DZ4.2
  BOTTOM w0.076: 103.5,37.94 103.52,37.94 106.07,40.49 106.07,40.91 107.07,41.9 107.66,41.9 107.79,41.78 110.6,41.78 111.69,42.86 113.14,42.86 113.25,42.75 113.53,42.75 UC1.AY15
  BOTTOM w0.102: v2(102.05,36.79) 102.35,36.79 103.5,37.94
ACAV_IN: length 315.8
  TOP w0.102: v2(30.81,38.92) 30.81,38.62 CE84.2 30.18,38.59 30.18,39.28 30.38,39.48 30.38,40.98 30.83,41.42 UE1.128 ; DZ4.1 99.28,34.91 v1(98.43,34.91) 98,34.91 93.17,30.08 93.17,23.46 93.89,22.75 v2(93.89,21.78)
  TOP w0.203: PR731.1 178.65,44.74 PR741.2 178.21,44.76 v2(177.85,45.12) 177.35,45.63 177.35,47.23 177.1,47.47 PU703.2
  TOP w0.254: PR12.1 v2(201.01,96.39)
  IN1 w0.254: v2(201.01,96.39) 200.37,95.75 200.37,92.64 197.2,89.47 179.35,89.47 176.13,86.24 176.13,59.05 175.81,58.73 175.81,56.94 175.82,56.94 176.06,56.7 176.06,56.69 176.44,56.31 176.44,53.27 178.69,51.02 178.69,45.96 v2(177.85,45.12)
  IN2 w0.127: v2(39.63,38.36) 40.62,39.35 42.82,39.35 43.77,38.4 43.77,37.5 44.66,36.61 44.66,32.82 47.4,30.08 47.4,24.49 48.9,22.99 48.9,18.05 51.67,15.27 55.84,15.27 56.84,14.27 57.27,14.27 58.86,12.68 79.59,12.68 80.28,13.37 82.76,13.37 83.2,13.8 84.42,13.8 92.81,22.2 93.41,22.2 93.83,21.78 v2(93.89,21.78) 93.89,20.41 94.36,19.93 94.36,18.2 99.45,13.11 103.2,13.11 103.64,12.67 115.24,12.67 116.6,11.31 118.62,11.31 119.88,12.57 129.26,12.57 130.1,11.73 131.95,11.73 132.95,12.73 142.9,12.73 145.69,15.53 159.84,15.53 161.58,13.79 173.65,13.79 177.57,17.71 177.57,24.92 180.14,27.49 180.14,29.44 180.42,29.72 180.42,42.55 v2(177.85,45.12)
  BOTTOM w0.102: v2(39.63,38.36) 39.22,38.77 36.83,38.77 36.25,38.18 31.55,38.18 v2(30.81,38.92)
ACIN_CHG: length 77.5
  TOP w0.203: PC711.2 177,43.82 177,47 176.93,47.07 PU703.1
  TOP w0.254: 186.08,97.94 186.08,98.98 185.15,99.91 PQ709.3
  TOP w0.508: v2(176.81,58.48) 176.98,58.48 177.44,58.94 177.44,62.21 177.28,62.36 177.28,62.54 175.67,64.15 175.67,82.96 184.42,91.71 184.42,92.52 184.41,92.53 184.41,92.98 184.42,92.99 184.42,94.66 v1(184.28,94.8) 184.28,95.16 186.08,96.96 186.08,97.94 ; PR729.2 176.85,43.7 PC711.2 PR732.1 176.86,42.48 177.3,42.04 180.11,42.04 181.21,43.14 181.21,44.58 v2(181.42,44.79)
  IN1 w0.508: v2(176.81,58.48) 176.57,58.24 176.57,56.9 176.95,56.52 176.95,53.48 177.52,52.92 179.62,52.92 180.11,52.42 180.11,49.44 180.99,48.56 180.99,45.78 181.42,45.35 v2(181.42,44.79)
ACLIM: length 5.4
  TOP w0.102: PR751.2 171.56,54.39 v1(172.06,54.89)
  TOP w0.203: PR751.2 171.92,53.65 172.11,53.46 172.11,53.16 PR749.1 172.81,52.46 172.81,51.23 173.14,50.89 PU703.16
ADJ_2.5V: length 5.7
  TOP w0.102: v4(78.16,9.67) 78.34,9.49 PR801.2
  TOP w0.254: PR801.2 PC803.2 80.19,9.48 PR802.1 v2(80.82,8.57)
  BOTTOM w0.254: PU800.7 80.11,9.28 v2(80.82,8.57)
ALERT#: length 4.4
  TOP w0.102: v1(169.35,112.87) 169.57,112.64 R2603.2 170.87,112.29 170.87,110.88 170.61,110.62 THM26.6
ALL_SYS_PWRGD: length 404.1
  TOP w0.102: RE438.2 50.84,47.57 51.08,47.81 RC1135.1 51.96,48.24 52.8,49.08 v1(52.8,52.62) 52.8,62.02 50.87,63.95 47.59,63.95 47.07,63.43 38.64,63.43 v2(38,64.07) ; v2(108.39,10.88) 108.39,11.72 RC1136.1 ; UC13.4 112.95,12.87 113.12,12.69 113.12,12.3 RC392.2 RC388.1 113.15,10.85 v2(113.26,10.74)
  TOP w0.254: PQ102.2 v2(191,104.4)
  IN1 w0.114: v2(108.39,10.88) 108.79,11.29 112.72,11.29 v2(113.26,10.74) 113.34,10.74 114.67,9.42 120.35,9.42 122.35,11.42 136.76,11.42 139.78,8.4 148.75,8.4 150.29,9.94 167.97,9.94 169.13,11.09 180.98,11.09 181.6,11.72 194.87,11.72 196.75,13.6 197.54,13.6 198.12,14.18 202.25,14.18 202.44,13.99 205.31,13.99 206.55,12.75 208.7,12.75 211.11,10.34 215.92,10.34 218.09,12.51 218.09,28.41 221.92,32.24 222.49,32.24 223.57,33.32 223.57,37.24 221.17,39.64 221.17,40 218.7,42.47 218.7,43.63 217.59,44.74 217.59,46.05 210.13,53.51 210.13,56.73 201.7,65.16 201.7,68.68 202.11,69.08 202.11,70.45 201.9,70.65 201.9,83.96 203.35,85.4 203.35,98.26 200.13,101.48 193.92,101.48 v2(191,104.4) ; v2(60.81,6.38) 60.81,6.43 59.87,7.37 58.19,7.37 57.71,6.89 55.55,6.89 54.68,7.77 54.68,8.43 53.6,9.51 53.6,10.22 53.17,10.65 51.34,10.65 48.77,13.22 48.26,13.22 42.83,18.64 42.83,19.38 40.59,21.62 40.59,22.84 39.04,24.39 39.04,24.8 37.59,26.25 37.59,29.02 36.46,30.15 36.46,31.24 33.93,33.78 33.75,33.78 32.03,35.5 30.51,35.5 29.3,36.7 29.3,38.93 34.93,44.56 34.93,52.42 35.82,53.32 37.64,53.32 38.55,54.23 38.55,60.14 38,60.69 v2(38,64.07)
  BOTTOM w0.102: v2(60.81,6.38) 61.37,6.94 88.64,6.94 90.16,8.47 90.16,8.99 90.8,9.63 91.72,9.63 92.04,9.32 92.04,9.07 92.64,8.47 105.06,8.47 107.47,10.88 v2(108.39,10.88)
ALL_SYS_PWRGD_R: length 5.7
  TOP w0.102: v1(105.32,15.27) 105.22,15.17 RC1136.2 104.46,13.2 103.66,13.2 103.41,13.46 UC12.2 103.41,15.34 RC1137.2
ALWON: length 274.5
  TOP w0.102: UE1.121 32.44,44.22 32.69,43.96 37.69,43.96 v2(37.95,44.22)
  TOP w0.254: PR114.1 188.5,98.61 184.94,95.05 v1(184.94,92.76) 184.94,91.36 176.48,82.9 176.48,64.45 177.97,62.96 177.97,58.59 v2(177.21,57.83)
  IN2 w0.127: v2(177.21,57.83) 176.64,57.27 176.64,54.01 177.13,53.52 177.13,50.61 179.03,48.72 180.08,48.72 180.67,48.12 180.67,29.62 180.39,29.34 180.39,27.38 177.83,24.82 177.83,17.6 173.76,13.53 161.47,13.53 159.73,15.27 145.8,15.27 143.01,12.48 133.06,12.48 132.05,11.48 129.99,11.48 129.15,12.31 119.98,12.31 118.7,11.03 116.52,11.03 115.14,12.42 103.54,12.42 103.09,12.86 99.34,12.86 95.41,16.8 89.06,16.8 87,14.74 87,14.6 85.95,13.55 83.3,13.55 82.87,13.11 80.38,13.11 79.69,12.43 58.76,12.43 57.17,14.02 56.74,14.02 55.73,15.02 51.43,15.02 48.64,17.8 48.64,22.46 46.7,24.4 46.7,27.76 42.35,32.11 42.35,32.64 42.58,32.88 43.13,32.88 43.89,33.64 43.89,36.02 43.29,36.63 42.04,36.63 41.03,37.65 39.35,37.65 38.92,38.08 38.92,39.17 37.16,40.92 37.16,41.94 37.95,42.73 v2(37.95,44.22)
ASGATE: length 70.9
  TOP w0.203: PU703.30 175.14,45.71 175.23,45.63 175.29,45.63 175.29,45.62 v2(175.28,45.62)
  IN1 w0.508: v2(175.28,45.62) 176.48,45.62 177.26,46.4 177.26,51.38 177.05,51.58 177.05,51.69 175.85,52.9 175.85,54.99 174.3,56.54 174.3,57.68 173.69,58.29 173.12,58.29 172.42,58.99 172.42,64.64 174.76,66.97 174.76,86.77 183.75,95.77 192.03,95.77 v2(193.59,97.33)
  BOTTOM w0.254: PR762.2 v2(193.59,97.33)
ASGATE_R: length 12.1
  TOP w0.508: PQ741.4 187.28,94.37 188.85,95.94 192.52,95.94 193.54,94.93 v2(193.59,94.93)
  BOTTOM w0.102: v1(194.19,97.39) 194.19,96.31 193.59,95.71 PR778.1
  BOTTOM w0.381: PR778.1 v2(193.59,94.93) 193.59,94.56 193.23,94.2 PQ740.4
AUD_HP_OUT_L_CN: length 23.1
  TOP w0.305: LA8.1 22.38,21.56 v4(22.04,21.56) 21.2,21.56 v2(20.98,21.78)
  BOTTOM w0.305: JHP.1 14.48,6.25 15.46,7.23 15.46,11.62 18.97,15.13 DA10.3 19.54,15.93 19.98,16.38 CA39.1 19.98,20.77 v2(20.98,21.78)
AUD_HP_OUT_R_CN: length 24
  TOP w0.305: v2(20.18,21.79) 20.09,21.7 v1(20.09,21.19) 20.09,20.99 20.25,20.84 22.62,20.84 LA9.1
  BOTTOM w0.305: v2(20.18,21.79) 17.03,18.64 CA33.1 17.03,16.33 17.6,15.76 DA10.2 16.51,15.13 14.95,16.7 8.04,16.7 JHP.2
AUD_PC_BEEP: length 1.9
  TOP w0.102: v1(38.31,26.35) 38.18,26.47 CA65.1 RA1114.1
BA: length 5.4
  TOP w0.102: PR780.1 174.53,63.01 v1(175.29,63.77)
  TOP w0.254: PD704.3 173.24,60.46 173.32,60.38 PQ710.1 174.02,61.21 174.53,61.72 PR780.1
BAT1_LED#: length 17.6
  TOP w0.127: v1(32.76,38.35) 32.56,38.54 32.56,38.85
  TOP w0.254: UE1.1 33.14,39.06 32.92,38.85 32.56,38.85 32.46,38.95 32.46,39.4 v2(32.36,39.5) ; v2(23.6,42.37) 23.38,42.59 RE408.1 22.04,42.59 21.92,42.71 20.56,42.71 20.08,43.19 QC6.1
  IN3 w0.254: v2(32.36,39.5) 31.35,39.5 30.64,40.22 30.64,41.05 29.01,42.68 23.9,42.68 v2(23.6,42.37)
BAT1_LED#_R: length 71.4
  TOP w0.102: v1(40.72,19.02) 39.95,19.02 v2(38.66,17.74) ; QC6.6 20.08,45.07 v2(19.81,44.8)
  IN1 w0.114: v2(19.81,44.8) 19.81,41.48 22.65,38.64 22.65,37.84 23.31,37.18 23.31,35.93 23.31,35.73 24.26,34.77 26.99,34.77 27.41,34.36 28.11,34.36 29.41,33.05 30.64,33.05 34.15,29.55 34.15,29.27 34.48,28.94 34.48,21.87 35.97,20.38 35.97,19.77 38,17.74 v2(38.66,17.74)
  BOTTOM w0.102: JLED.3 65.25,12.43 65.13,12.56 56.42,12.56 55.77,13.2 42.03,13.2 38.95,16.28 38.95,17.44 v2(38.66,17.74)
BAT2_LED#: length 15.3
  TOP w0.254: QC6.4 21.49,45.28 RE409.1 22.84,45.28 v2(23.37,45.81) ; UE1.106 32.77,50.22 v2(32.85,50.15)
  IN1 w0.254: v2(23.37,45.81) 23.58,46.03 29.46,46.03 32.36,48.93 32.36,49.66 v2(32.85,50.15)
BAT2_LED#_R: length 82.3
  TOP w0.102: Q6105.1 23.19,36.61 v1(23.19,40.28) 23.19,40.8 v2(23.37,40.98) ; v2(21.38,44.16) QC6.3
  IN1 w0.114: v2(64.39,9.28) 61.9,9.28 60.86,10.32 58.79,10.32 55.09,14.02 51.62,14.02 47.68,17.96 47.68,19.24 43.26,23.66 43.26,25.53 41.81,26.98 41.81,28.84 40.01,30.64 40.01,30.94 38.88,32.07 38.88,32.56 38.65,32.79 38.65,33.64 38.08,34.21 38.08,37.35 38.31,37.57 38.31,40.39 38.59,40.67 38.59,42.96 v2(38.48,43.06)
  IN2 w0.127: v2(21.38,44.16) 22.51,43.03 22.51,41.84 v2(23.37,40.98)
  BOTTOM w0.102: v2(38.48,43.06) 37.47,43.06 36.96,42.55 35.04,42.55 34.81,42.78 33.88,42.78 32.21,41.12 30.14,41.12 26.72,37.7 24.71,37.7 24.39,38.02 24.39,40.52 23.93,40.98 v2(23.37,40.98) ; v2(64.39,9.28) 64.75,9.64 JLED.4
BEEP: length 33.6
  TOP w0.102: v2(32.9,33.92) 32.97,33.99 33.56,33.99 34.01,33.54 34.01,33.23 DA8.2 ; UE1.45 46.12,46.22 45.27,47.07 41.91,47.07 40.82,45.98 33.94,45.98 v2(32.91,44.95)
  IN1 w0.114: v2(32.9,33.92) 31.56,35.26 30.41,35.26 29.06,36.6 29.06,39.15 31.6,41.69 31.6,43.65 v2(32.91,44.95)
BKLT_CTRL: length 32.8
  TOP w0.102: v2(43.84,94.98) 44.1,94.73 44.1,93.53 43.79,93.23 v1(42.73,93.23) 40.88,93.23 40.29,93.81 40.29,95.03 39.84,95.48 35.87,95.48 33.47,97.87 33.47,106.48 34.76,107.77 34.76,109.66 35.08,109.98 36.22,109.98 36.54,110.3 D5202.1
  BOTTOM w0.102: RN5201.7 45.3,94.81 45.12,94.98 v2(43.84,94.98) 43.47,94.98 43.27,95.18 RN5203.8
BLON_OUT_C: length 4.7
  BOTTOM w0.102: 44.8,96.13 44.8,96.26 44.77,96.29 JEDP.16 ; 44.8,96.13 RN5201.1 ; 44.8,96.13 44.79,96.14 42.87,96.14 42.77,96.04 RN5203.7
BLUETOOTH_EN: length 112.4
  IN1 w0.114: v2(167.05,12.82) 166.98,12.75 143.73,12.75 139.48,17 138.15,17 137.82,16.67 137.82,16.4 136.83,15.41 132.63,15.41 128.43,19.61 128.43,21.3 127.58,22.16 127.58,23.89 124.14,27.33 124.14,30.32 124.1,30.35 v2(124.1,31.16)
  BOTTOM w0.102: v2(167.05,12.82) 168.54,12.82 171.72,16 174.93,16 180.46,21.52 180.46,30.17 184.99,34.71 184.99,37.27 183.71,38.55 183.71,50.21 v1(184.57,51.07) 185.42,51.93 WLAN1.46 ; UC1.AB2 123.58,34.27 123.58,31.68 v2(124.1,31.16) 124.36,30.9 RC292.2
BOARD_ID: length 22
  TOP w0.102: v2(21.97,46.21) 22.04,46.15 RE345.2 22.75,46.26 24.36,46.26 RE347.2 25.38,46.15 CE70.1 ; UE1.111 v2(33.02,48.22)
  IN1 w0.114: v2(33.02,48.22) 32.23,47.43 32.23,46.68 30.77,45.22 26.85,45.22 26.6,45.47 25.89,45.47 24.74,44.33 24.74,43.44 24.26,42.96 23.21,42.96 21.97,44.19 v2(21.97,46.21)
BREATH_LED#: length 256.4
  TOP w0.102: v2(43.65,54.16) 43.54,54.27 UE1.70
  TOP w0.127: v2(203.86,50.66) v4(203.86,50.1)
  IN1 w0.114: v2(203.86,50.66) 197.48,50.66 195.6,52.54 195.6,60.1 201.04,65.55 201.04,84.31 202.49,85.76 202.49,97.9 200,100.39 193.25,100.39 192.88,100.03 191.22,100.03 191,100.25 164.07,100.25 v2(163.3,99.47)
  IN2 w0.127: v2(43.65,54.16) 43.65,56.38 44.38,57.11 44.38,62.42 53.51,71.55 53.51,89.29 56.29,92.07 59.73,92.07 62.03,89.77 102.75,89.77 112.87,99.89 162.88,99.89 v2(163.3,99.47)
  BOTTOM w0.102: JIO1.19 v2(203.86,50.66)
BST_1.2V: length 1.4
  TOP w0.102: 71.91,103.37 v1(71.91,104.78)
BST_1.2V_R: length 2.9
  TOP w0.102: PR200.1 73.31,104.36 v1(73.75,104.81)
  TOP w0.508: PR200.1 73.31,102.12 PC200.1
BST_3V: length 1.4
  BOTTOM w0.102: v1(179.06,77.08) 179.22,77.25 PR100.1
BST_5V: length 1.4
  BOTTOM w0.102: PR111.1 v1(188.19,78.73)
BST_+1VALW: length 0.6
  TOP w0.102: v1(151.44,33.11) 151.78,32.77 v2(151.78,32.68)
  vias: v2(150.98,31.87)
BST_+1VALW_R: length 1.7
  BOTTOM w0.127: v1(152.29,32.89) 151.97,33.21 151.55,33.21 PR306.2
BST_+VCCEOPIO:
  vias: v2(108.92,104.06)
BST_R_+VCCEOPIO: length 2.7
  BOTTOM w0.102: PR1203.2 108.14,101.98 v1(107.69,101.52)
  BOTTOM w0.254: PC1201.1 PR1203.2
C0_1.0VS_VCCOPCP: length 2
  BOTTOM w0.254: PR1207.1 105.63,109.28 106.53,108.38 PU1200.4
C1_1.0VS_VCCOPCP: length 4.5
  BOTTOM w0.102: v1(105.15,111.62) 105.15,110 PR1206.2
  BOTTOM w0.254: PU1200.3 106.03,108.25 105.3,108.97 105.21,108.97 PR1206.2
CAP_LED: length 74.3
  TOP w0.102: R6201.2 45.42,24.72 45.06,24.37 v2(44.94,24.37)
  TOP w0.127: v2(103.9,11.29) 104.53,10.65 v1(105.08,10.65)
  IN2 w0.127: v2(44.94,24.37) 45.55,24.37 46.03,23.88 46.03,22.82 46.47,22.37 46.47,19.26 51.22,14.51 55.52,14.51 56.52,13.51 56.96,13.51 58.55,11.92 79.9,11.92 80.59,12.61 83.08,12.61 83.51,13.04 86.16,13.04 87.51,14.39 87.51,14.53 89.23,16.25 95.14,16.25 99.04,12.35 102.83,12.35 v2(103.9,11.29)
  BOTTOM w0.102: v2(103.9,11.29) JKB.4
CAP_LED#: length 37.5
  TOP w0.102: UE1.93 34.34,54.61 34.06,54.34 v2(31.51,54.34) ; Q6206.3 39.75,28.33 R6202.2 38.03,28.33 v2(38,28.3)
  IN2 w0.127: v2(38,28.3) 37.09,29.22 37.09,32.39 36.12,33.36 35.67,33.36 35.42,33.12 34.94,33.12 34.61,33.45 34.1,33.45 33.53,34.02 33.46,34.02 32.77,34.7 32.77,35.8 33.3,36.33 33.3,36.97 32.85,37.43 32.85,40.28 31.86,41.27 31.86,48.09 31.06,48.89 31.06,53.88 v2(31.51,54.34)
CAP_LED_Q: length 3.3
  TOP w0.102: Q6201.1 45.43,26.06 R6201.1 44.5,24.08 v1(44.59,24)
CAP_LED_R#: length 9.7
  TOP w0.102: Q6201.2 46.4,30.27 45.77,30.89 v1(45.11,30.89) 44.69,30.89 44.48,30.68 42.44,30.68 41.43,29.67 Q6206.1
CBN: length 4.3
  TOP w0.203: v2(28.03,20.51) 27.84,20.7 27.84,21.58 28.13,21.87 UA1.35
  BOTTOM w0.127: CA24.2 26.56,19.68 v1(26.05,19.68)
  BOTTOM w0.305: CA24.2 27.39,20.51 v2(28.03,20.51)
CBP: length 3.3
  TOP w0.203: v2(28.54,19.86) 28.95,19.86 29.39,20.3 UA1.37
  BOTTOM w0.127: CA24.1 27.85,19.51 v1(27.14,18.8)
  BOTTOM w0.305: CA24.1 28.35,19.67 v2(28.54,19.86)
CCLIM: length 4.4
  TOP w0.203: PR750.1 PR752.2 177.32,52.25 176.69,51.62 v1(176.03,51.62) 175.75,51.62 175.14,51.02 PU703.11
CFG0: length 8.8
  BOTTOM w0.076: 137.95,73.29 137.5,73.29 136.57,72.36 136.45,72.36 136.15,72.06 135.91,72.06 135.53,71.68 134.84,71.68 134.8,71.67 134.59,71.67 134.35,71.75 133.93,71.75 133.64,71.92 UC1.E68
  BOTTOM w0.102: 137.95,73.29 138.86,73.29 139.33,72.82 RC113.2 140.49,72.82 T89.1
CFG1: length 8.3
  BOTTOM w0.076: UC1.B67 134.66,72.5 135.22,73.05 135.46,73.05 135.94,73.53 135.94,76.04
  BOTTOM w0.102: 135.94,76.04 135.94,77.18 RC112.2 136.48,78.76 136.82,79.1 T90.1
CFG2: length 5.9
  BOTTOM w0.076: UC1.D65 133.88,71.07 134.25,71.07 134.56,71.17 136.34,71.17 137.95,72.79
  BOTTOM w0.102: 137.95,72.79 138.06,72.89 T91.1
CFG3: length 8.5
  BOTTOM w0.076: 137.95,74.1 136.08,72.23 135.84,72.23 135.46,71.85 134.8,71.85 134.75,71.83 134.62,71.83 134.45,71.89 134.34,71.94 134.34,71.96 134.07,72.07 UC1.D67
  BOTTOM w0.102: T92.1 138.51,76.06 RC110.2 RC43.1 138.51,74.65 137.95,74.1
CFG4: length 11.9
  TOP w0.102: v2(141.48,76.05) 142.19,76.77 T93.1 RC109.2
  IN2 w0.127: v2(141.48,76.05) 134.53,76.05 v2(133.5,75.02)
  BOTTOM w0.076: v2(133.5,75.02) 133.5,74.99 133.21,74.7 133.21,74.34 133.01,74.14 UC1.E70
CFG5: length 5.3
  BOTTOM w0.076: 134.83,76.13 134.83,75.82 134.55,75.54 134.55,74.27 134.35,74.08 134.35,73.36 133.81,72.82 UC1.C68
  BOTTOM w0.102: T94.1 134.83,76.13
CFG6: length 6
  BOTTOM w0.076: 133.83,74.6 133.83,74.4 133.54,74.1 UC1.D68
  BOTTOM w0.102: T95.1 134.03,78.18 134.03,74.8 133.83,74.6
CFG7: length 8
  BOTTOM w0.076: 135.63,76.02 135.63,75.52 135.69,75.47 135.69,73.94 135.5,73.75 135.25,73.75 134.96,73.47 134.96,73.09 134.56,72.69 UC1.C67
  BOTTOM w0.102: 135.63,76.02 135.63,79.45 T96.1
CFG8: length 3.9
  BOTTOM w0.076: UC1.F71 132.45,74.13 132.45,74.4 132.41,74.44 132.41,75.63 132.64,75.85
  BOTTOM w0.102: T99.1 133.21,76.43 132.64,75.85
CFG9: length 4.9
  BOTTOM w0.076: 131.69,75.21 131.69,74.87 131.49,74.67 131.49,74.41 131.55,74.29 131.55,74.15 131.48,73.92 131.48,73.79 131.56,73.57 131.56,73.32 UC1.G69 ; 131.49,76.12 131.49,75.57
  BOTTOM w0.089: 131.69,75.21 131.69,75.37 131.49,75.57
  BOTTOM w0.102: 131.49,76.12 131.52,76.15 T100.1
CFG10: length 6.9
  BOTTOM w0.076: 132.59,75.41 132.59,74.49 132.65,74.43 132.65,73.74 UC1.F70
  BOTTOM w0.102: 132.59,75.41 133.73,76.55 133.73,79.33 T101.1
CFG11: length 6.9
  BOTTOM w0.076: 132.5,76.12 132.23,75.85 132.23,75.63 132.24,75.62 132.24,74.35 132.09,74.2 132.09,73.72 131.95,73.58 131.95,73.39 132.09,73.26 132.09,73.06 131.66,72.64 UC1.G68
  BOTTOM w0.102: T102.1 132.76,78.45 132.76,76.38 132.5,76.12
CFG12: length 3.1
  BOTTOM w0.076: 130.7,76.09 130.7,74.83 130.86,74.66 130.86,74.38 130.81,74.24 130.81,74.14 130.86,74.01 130.86,73.77 UC1.H70
  BOTTOM w0.102: T103.1 130.75,76.14 130.7,76.09
CFG13: length 5.8
  BOTTOM w0.076: UC1.G71 131.76,74.58 131.91,74.73 131.91,75.45 131.78,75.58 131.78,76.12
  BOTTOM w0.102: 131.78,76.12 131.78,76.58 132.01,76.81 T104.1
CFG14: length 6.6
  BOTTOM w0.076: UC1.H69 131.1,73.09 131.36,73.36 131.36,73.62 131.31,73.78 131.31,73.93 131.37,74.14 131.37,74.26 131.34,74.34 131.33,74.37 131.33,74.78 131.45,74.91 131.45,75.26 131.11,75.6 131.11,76.12
  BOTTOM w0.102: 131.11,76.12 131.08,76.15 131.08,78.75 131.09,78.76 T105.1
CFG15: length 2.9
  BOTTOM w0.076: UC1.G70 131.76,74.11 132.07,74.42 132.07,75.56 132.01,75.62 132.01,75.97
  BOTTOM w0.102: T106.1 132.24,76.19 132.01,75.97
CFG16: length 1.2
  TOP w0.089: v2(132.74,70.04) 133.35,70.04 T98.1
  BOTTOM w0.076: v2(132.74,70.04) 132.65,69.96 UC1.E63
CFG17: length 1.1
  TOP w0.089: v2(132.1,70.04) 131.78,69.72 T97.1
  BOTTOM w0.076: UC1.F63 132,69.94 v2(132.1,70.04)
CFG18: length 1.3
  TOP w0.089: v2(132.65,72.11) 133.08,72.11 133.09,72.09 T108.1
  BOTTOM w0.076: v2(132.65,72.11) UC1.E66
CFG19: length 1.2
  TOP w0.089: T107.1 132.07,72.17 v2(132,72.11)
  BOTTOM w0.076: v2(132,72.11) UC1.F66
CFG_RCOMP: length 1.5
  TOP w0.254: v2(132.89,67.25) 133.06,67.09 RC114.1
  BOTTOM w0.254: v2(132.89,67.25) 132.59,67.56 UC1.E60
CLK_ITPXDP_N: length 1.2
  TOP w0.089: v2(132.17,58.97) 131.89,58.69 T4943.1
  BOTTOM w0.076: v2(132.17,58.97) 132.12,58.92 132.12,58.67 UC1.F43
CLK_ITPXDP_P: length 1.3
  TOP w0.089: v2(132.25,57.98) 132.26,57.98 132.68,57.56 T4944.1
  BOTTOM w0.076: v2(132.25,57.98) 132.25,58.15 UC1.E43
CLK_PCI_LPC_MEC: length 129
  TOP w0.094: 48.09,51.14 v1(49.14,52.19) 49.43,52.48 49.43,54.01 v2(48.72,54.72) ; RZ127.1 46.17,72.54 47.83,72.54 v2(47.91,72.46)
  TOP w0.102: 48.09,51.14 47.97,51.02 UE1.57
  IN1 w0.114: v2(105.93,27.25) 105.35,27.25 102.36,24.26 102.36,22.71 100.54,20.89 97.99,20.89 97.69,20.59 94.72,20.59 94.53,20.79 90.73,20.79 88.43,18.49 76.83,18.49 75.79,17.45 70.21,17.45 69.1,18.55 65.61,18.55 63.72,20.44 62.18,20.44 60.42,22.21 58.42,22.21 56.72,23.91 56.72,24.79 55.73,25.78 55.4,25.78 53.98,27.19 53.98,28.58 52.7,29.87 52.7,35.75 48.87,39.57 48.87,41.15 47.71,42.31 47.71,43.63 47.71,50.04 48.31,50.64 48.31,54.31 v2(48.72,54.72) 48.94,54.94 48.94,57.44 49.53,58.03 49.53,67.45 47.27,69.71 47.27,70.73 47.91,71.37 v2(47.91,72.46)
  BOTTOM w0.076: 106.92,34.51 106.92,34.73 RC18.2 CC1802.2
  BOTTOM w0.094: 106.92,34.51 106.92,33.95 106.98,33.9 106.98,30.88 105.42,29.32 105.42,27.49 105.65,27.25 v2(105.93,27.25)
CLK_PCI_LPDEBUG: length 121.9
  IN1 w0.114: v2(47.78,69.91) 50.02,67.67 50.02,57.83 49.43,57.24 49.43,52.65 49.09,52.31 49.09,50.72 48.21,49.84 48.21,43.83 48.21,42.52 49.37,41.36 49.37,39.78 53.19,35.95 53.19,30.07 54.47,28.79 54.47,27.7 55.32,26.86 55.59,26.86 57.26,25.19 57.26,24.35 58.18,23.43 62.95,23.43 63.43,22.95 63.43,21.43 65.81,19.04 69.31,19.04 70.41,17.94 74.21,17.94 75.25,18.98 88.22,18.98 91.48,22.24 97.09,22.24 97.94,21.38 100.3,21.38 101.87,22.95 101.87,24.47 105.68,28.28 v2(106.7,28.28)
  BOTTOM w0.076: 107.65,33.79 107.65,33.96 RC22.2
  BOTTOM w0.094: JDB1.1 44.11,70.96 45.6,69.48 v1(46.78,69.48) 47.35,69.48 v2(47.78,69.91) ; v2(106.7,28.28) 106.7,29.93 107.48,30.72 107.48,33.33 CC1803.2 107.65,33.79
CLK_PCIE_LAN_N2: length 141.8
  TOP w0.094: v2(40.87,82.02) 40.7,82.02 40.55,82.17 40.55,82.39 40.34,82.6 38.75,82.6 38.44,82.91 37.8,82.91 37.7,83.01 37.7,83.16 37.81,83.27 UL1.16
  IN1 w0.114: v2(139.09,56.37) 138.85,56.62 138.42,56.62 137.98,57.06 137.98,75.32 132.62,80.67 132.62,83.95 125.43,91.14 125.43,92.68 122.63,95.49 121.09,95.49 118.83,97.75 103.77,97.75 101.45,95.43 56.83,95.43 50.48,89.09 48.48,89.09 46.29,86.89 45.29,86.89 41.71,83.31 41.53,83.31 40.47,82.25 40.47,82.12 40.57,82.02 v2(40.87,82.02)
  BOTTOM w0.094: v2(139.09,56.37) 138.88,56.58 138.78,56.58 138.47,56.27 RC1116.2
CLK_PCIE_LAN_N2_R: length 4.5
  BOTTOM w0.076: UC1.D41 133.94,57.8 134.24,57.5 135.48,57.5 135.75,57.24 135.75,57.22 135.76,57.21
  BOTTOM w0.094: RC1116.1 137.32,56.44 136.54,56.44 135.76,57.21
CLK_PCIE_LAN_P2: length 141.8
  TOP w0.094: UL1.15 37.41,83.27 37.52,83.16 37.52,82.93 37.72,82.73 38.36,82.73 38.68,82.41 40.27,82.41 40.36,82.32 40.36,82.21 v2(40.1,81.94)
  IN1 w0.114: v2(40.1,81.94) 40.27,82.11 40.27,82.34 41.45,83.51 41.63,83.51 45.21,87.09 46.2,87.09 48.4,89.29 50.4,89.29 56.74,95.63 101.37,95.63 103.68,97.95 118.91,97.95 121.17,95.69 122.71,95.69 125.63,92.77 125.63,91.23 132.82,84.04 132.82,80.76 138.18,75.4 138.18,57.14 138.5,56.82 138.96,56.82 v2(139.09,56.96)
  BOTTOM w0.094: v2(139.09,56.96) 138.9,56.76 138.72,56.76 138.47,57.01 RC1117.2
CLK_PCIE_LAN_P2_R: length 4.5
  BOTTOM w0.076: 135.89,57.34 135.88,57.35 135.86,57.35 135.55,57.67 134.42,57.67 134.34,57.74 UC1.C41
  BOTTOM w0.094: RC1117.1 137.81,56.83 137.81,56.69 137.74,56.62 136.61,56.62 135.89,57.34
CLK_PCIE_LAN_REQ#: length 155.1
  TOP w0.094: RC50.2 106.66,30.86 107.7,29.81 v2(108.8,29.81) ; RL10.1 35.07,80.21 35.98,79.29 QL1.3 37.87,79.2 40.76,79.2 42.22,80.67 47.39,80.67 v1(48.24,79.81) v2(48.64,79.41)
  IN1 w0.114: v2(48.64,79.41) 48.9,79.41 50.52,77.79 50.52,57.62 49.93,57.03 49.93,52.33 49.6,52 49.6,50.53 48.7,49.63 48.7,44.04 48.7,44.04 48.7,42.76 49.87,41.59 49.87,40.06 51.08,38.84 52.5,38.84 53.69,37.66 53.69,30.28 54.97,29 54.97,28.02 55.12,27.87 55.78,27.87 56.62,27.04 56.62,26.72 58.82,24.52 63.6,24.52 63.92,24.2 63.92,21.64 64.95,20.61 66.41,20.61 67.45,19.57 70.18,19.57 70.62,19.13 72.32,19.13 73.13,19.94 88.48,19.94 91.28,22.73 97.29,22.73 98.15,21.88 99.51,21.88 99.8,22.17 99.8,22.79 99.13,23.46 99.13,23.94 100.17,24.98 101.41,24.98 105.73,29.29 107.61,29.29 108.13,29.81 v2(108.8,29.81)
  IN3 w0.135: v2(116.15,37.84) 116.15,36.99 115.66,36.51 114.44,36.51 108.8,30.87 v2(108.8,29.81)
  BOTTOM w0.102: UC1.AT8 116.39,38.38 116.15,38.14 v2(116.15,37.84)
CLK_PCIE_WLAN_N1: length 125.2
  IN3 w0.135: v2(138.8,60.4) 138.68,60.52 137.98,60.52 137.18,61.32 137.18,65.65 137.93,66.41 137.93,77.16 138.36,77.59 138.36,80.48 140.15,82.27 140.15,92.11 148.36,100.32 171.8,100.32 175.99,96.13 175.99,64.07 178.91,61.15 186.6,61.15 186.76,61.31 186.76,61.64 v2(186.63,61.77)
  BOTTOM w0.094: v2(138.8,60.4) 138.64,60.55 138.36,60.55 138.23,60.42 138.23,60.1 138.38,59.95 139.09,59.95 139.32,59.72 139.32,58.99 138.97,58.64 138.76,58.64 RC1114.2 ; v2(186.63,61.77) 186.83,61.57 186.83,61.39 186.67,61.23 WLAN1.41
CLK_PCIE_WLAN_N1_R: length 3.6
  BOTTOM w0.094: RC1114.1 137.27,58.64 136.72,58.64 135.92,57.84 135.1,57.84 134.86,58.08 134.86,58.16 UC1.B42
CLK_PCIE_WLAN_P1: length 125.2
  IN3 w0.135: v2(138.8,60.98) 138.58,60.76 138.08,60.76 137.42,61.42 137.42,65.55 138.17,66.3 138.17,77.06 138.61,77.49 138.61,80.38 140.39,82.17 140.39,92.01 148.47,100.08 171.7,100.08 175.74,96.03 175.74,63.97 178.81,60.9 186.7,60.9 187,61.21 187,61.56 v2(187.22,61.77)
  BOTTOM w0.094: v2(187.22,61.77) 187.02,61.57 187.02,61.36 187.17,61.2 WLAN1.39 ; RC1115.2 138.47,58.92 138.58,58.82 138.9,58.82 139.14,59.06 139.14,59.65 139.02,59.77 138.31,59.77 138.05,60.03 138.05,60.5 138.28,60.73 138.55,60.73 v2(138.8,60.98)
CLK_PCIE_WLAN_P1_R: length 3.6
  BOTTOM w0.094: UC1.A42 135.1,58.36 135.04,58.3 135.04,58.15 135.17,58.02 135.85,58.02 136.64,58.82 137.33,58.82 137.56,59.05 RC1115.1
CLK_PCIE_WLAN_REQ#: length 152.3
  TOP w0.094: RC47.2 106.39,29.97 107.06,29.29 v2(108.35,29.29) ; R5803.1 185.7,58.91 v1(184.85,58.06) 184.3,57.51 180.75,57.51 v2(180.02,56.78)
  IN1 w0.114: v2(108.35,29.29) 109.43,29.29 110.11,29.97 115.3,29.97 116.3,28.97 117.29,28.97 118.19,28.07 120.36,28.07 120.98,27.45 121.16,27.45 126.07,22.55 126.07,21.6 126.97,20.7 126.97,17.77 131.51,13.23 139.71,13.23 142.81,10.13 148.03,10.13 149.57,11.67 v2(166.14,11.67)
  BOTTOM w0.076: 111.73,37.05 112.01,37.33 112.47,37.33 112.52,37.28 113.64,37.28 113.68,37.32 114.82,37.32 114.85,37.35 115.46,37.35 115.63,37.18 116.17,37.18 UC1.AT7
  BOTTOM w0.094: 109.78,32.57 109.78,32.09 109.21,31.52 109.21,29.65 108.86,29.29 v2(108.35,29.29) ; v2(166.14,11.67) 166.14,12.94 166.68,13.48 168.63,13.48 171.55,16.4 172.84,16.4 177.17,20.73 178.02,20.73 179.54,22.26 179.54,30.15 184.36,34.97 184.36,37.01 183.08,38.29 183.08,46.68 179.94,49.82 179.94,54.05 180.64,54.75 180.64,55.74 180.02,56.35 v2(180.02,56.78)
  BOTTOM w0.102: 109.78,32.57 109.78,34.39 111.73,36.34 111.73,37.05
CLK_PCIE_WLAN_REQ#_R: length 2.8
  TOP w0.094: R5803.2 v2(185.7,61.78)
  BOTTOM w0.094: WLAN1.45 185.67,61.75 v2(185.7,61.78) 185.7,61.89 v1(185.35,62.25)
CLK_SMB: length 2.8
  TOP w0.254: PR20.1 v2(163.72,28.62)
  BOTTOM w0.254: PBATT1.7 162.75,28.82 163.07,28.49 163.59,28.49 v2(163.72,28.62)
CLK_TP_SIO: length 146.5
  TOP w0.102: v2(96.85,21.27) 97.08,21.04 97.08,20.37 96.35,19.64 94.8,19.64 94.24,20.2 92.83,20.2 89.4,16.77 86.01,16.77 85.25,17.53 85,17.53 84.88,17.66 84.26,17.66 82.12,19.8 v1(82.12,20.8) 82.12,21.95 80.29,23.78 78.54,23.78 78.26,23.5 58.42,23.5 57.46,24.47 55.68,24.47 54.51,25.64 54.51,39.4 53.65,40.27 RZ19.2 52.58,40.27 51.97,40.88 v2(48.33,40.88) ; v2(41.08,53.5) 40.34,54.24 UE1.78
  IN3 w0.135: v2(41.08,53.5) 43.05,51.53 43.05,48.54 43.95,47.64 43.95,44.32 43.8,44.17 43.8,42.43 44.7,41.54 47.55,41.54 48.21,40.88 v2(48.33,40.88)
  BOTTOM w0.102: TPAD1.1 141.35,11.48 139.91,10.04 133.76,10.04 132.69,11.11 116.85,11.11 115.94,12.02 111.14,12.02 109.38,13.79 97.93,13.79 96.09,15.63 96.09,20.02 96.85,20.78 v2(96.85,21.27)
CLKRUN#: length 195.3
  TOP w0.102: v2(48.77,53.22) 48.57,53.42 UE1.63
  IN1 w0.114: v2(115.52,40.65) 114.13,40.65 113.01,41.77 113.01,54.47 115.14,56.6 116.26,56.6 117.25,57.59 119.05,57.59 119.79,58.33 119.79,69.12 120.04,69.38 120.04,71.76 120.53,72.25 120.91,72.25 124.03,75.37 124.03,85.16 v2(116.57,92.62)
  IN3 w0.135: v2(48.77,53.22) 49.2,53.65 49.2,60.31 47.35,62.17 47.35,70.09 47.15,70.29 47.15,71.44 47.35,71.64 47.35,78.52 46.87,79 46.87,84.21 54.31,91.65 69.52,91.65 70.51,92.64 116.55,92.64 v2(116.57,92.62)
  BOTTOM w0.076: 111.39,39.92 111.85,40.38 113.52,40.38 113.55,40.36 113.78,40.36 113.8,40.38 114.17,40.38 114.2,40.36 114.34,40.36 UC1.AW11 114.93,40.06 v2(115.52,40.65)
  BOTTOM w0.102: 111.39,39.92 109.27,37.8 108.05,37.8 106.38,36.13 106.38,35.2 106.04,34.85 106.04,33.87 106.24,33.66 106.24,31.15 104.67,29.58 104.67,25.78 v1(105.13,25.32) RC27.1
CMP_STRAP0: length 7.1
  TOP w0.102: RE385.1 26.13,45.96 28.21,45.96 29.26,44.9 29.94,44.9 v1(29.98,44.94) 30.46,45.42 UE1.118
CMP_VIN0: length 13.2
  TOP w0.254: UE1.20 v2(40.74,41.35)
  TOP w0.381: RE394.2 43.76,34.36 43.38,33.98 RE392.1 42.88,34.21 v2(42.88,34.6)
  BOTTOM w0.508: v2(42.88,34.6) 43.13,34.6 43.49,34.96 v1(43.49,35.39) 43.49,36.37 44.15,37.03 44.15,39.25 43.18,40.22 41.38,40.22 40.74,40.86 v2(40.74,41.35)
CMP_VOUT0: length 242.1
  TOP w0.102: v2(191.86,100.44) v1(192.38,100.44) ; RE392.2 43.34,32.84 43.34,32.45 v2(43.37,32.41) ; UE1.85 37.54,56.53 37.18,56.88 36.81,56.88 v2(36.81,56.94) 36.81,57.15 34.87,59.1 RE404.2
  TOP w0.254: PR116.1 v2(191.86,100.44)
  IN1 w0.114: v2(191.86,100.44) 191.7,100.27 191.32,100.27 191.1,100.49 163.97,100.49 163.75,100.27 135.39,100.27 135.2,100.47 103.96,100.47 101.15,97.66 75.59,97.66 73.43,99.82 72.1,99.82 71.59,99.31 69.62,99.31 67.54,97.23 53.1,97.23 51.96,96.09 50.54,96.09 50.16,96.46 47.71,96.46 46.97,95.72 46.97,92.08 44.45,89.57 44.45,88.58 40.96,85.09 40.79,85.09 35.26,79.56 35.26,78.75 31.14,74.63 31.14,72.12 30.44,71.41 30.44,60.98 32.78,58.63 35.07,58.63 36.76,56.94 v2(36.81,56.94)
  IN2 w0.127: v2(43.37,32.41) 43.37,32.48 44.4,33.51 44.4,36.5 43.51,37.39 43.51,38.26 42.73,39.05 41.25,39.05 40.14,37.93 39.42,37.93 39.17,38.18 39.17,39.28 37.42,41.03 37.42,41.82 37.94,42.34 38.7,42.34 38.94,42.58 38.94,43.52 38.43,44.03 38.43,45.3 37.95,45.78 37.95,50.55 39.91,52.51 39.91,55.43 38.65,56.69 37.79,56.69 37.54,56.94 v2(36.81,56.94)
CMSRC: length 69.9
  TOP w0.203: v2(174.64,45.54) 174.63,45.54 174.63,45.55 174.65,45.55 174.74,45.64 PU703.29
  IN1 w0.508: v2(174.64,45.54) 174.63,45.54 174.63,46.3 174.92,46.59 176.17,46.59 176.42,46.84 176.42,51.43 174.67,53.18 172.86,53.18 172.06,53.98 172.06,55.79 171.54,56.31 171.54,64.96 174.02,67.43 174.02,87.89 182.58,96.45 189.39,96.45 189.89,96.96 v2(189.96,96.96)
  BOTTOM w0.254: v2(189.96,96.96) 190.64,96.27 PR763.2
COMP: length 6.8
  TOP w0.102: v1(180.5,51.61) 180.5,52.1 PC751.2
  TOP w0.203: PC751.2 179.96,52.6 PR754.2 178.5,52 177.77,52 177,51.24 175.85,51.24 175.54,50.94 PU703.10
COMP_IA: length 3
  TOP w0.203: PU602.16 164.44,70.08 164.39,70.12 164.39,70.51 v2(164.16,70.73)
  BOTTOM w0.254: PR639.2 163.69,70.12 PC636.2 164.51,70.39 v2(164.16,70.73)
COMP_VSA: length 3.7
  TOP w0.203: v2(160.68,67.56) 160.77,67.64 PU602.24
  BOTTOM w0.254: PR630.1 161.6,66.78 PC628.1 161.24,67.14 161.1,67.14 v2(160.68,67.56)
CORE_SNUB: length 3.6
  TOP w0.102: PR663.2 v1(155.67,57.82)
  TOP w0.635: PC662.1 PR663.2
CORE_SW: length 2
  TOP w0.127: PR663.1 v1(153,57.84)
  vias: v2(152.94,54.67) v2(152.94,54.03)
CORE_VID0: length 1.2
  TOP w0.089: v2(118.84,39.75) 118.82,39.73 T4950.1
  BOTTOM w0.076: UC1.AN11 118.4,40.18 v2(118.84,39.75)
CORE_VID1: length 1.1
  TOP w0.089: T4951.1 118.39,41.02 v2(118.71,40.7)
  BOTTOM w0.076: UC1.AN13 118.4,41.01 v2(118.71,40.7)
CPU_B+: length 12.7
  IN3 w0.254: v2(161.83,53.27) 161.83,57.28 157.45,61.67 v2(157.45,63.43)
  BOTTOM w0.254: PR603.2 v2(157.45,63.43)
  vias: v1(160.76,56.52) v2(160.3,57.07) v2(160.3,55.73) v2(160.3,54.38) v2(161.32,57.07) v2(161.32,55.73) v2(161.32,54.38) v2(161.32,51.49) v2(161.32,50.86) v2(161.83,52.38)
CPU_DP1_N0: length 148.4
  TOP w0.094: v2(34.68,68.26) 34.61,68.33 34.61,68.78 31.8,71.59 20.09,71.59 19.99,71.69 19.99,71.88 CHR12.1
  IN1 w0.114: v2(34.68,68.26) 34.68,69.1 44.92,79.33 45.65,79.33 50.78,84.46 52.18,84.46 57.89,90.17 102.26,90.17 105.6,93.52 116.45,93.52 126.43,83.54 126.43,76.04 128.63,73.85 128.63,69.88 130.38,68.13 130.38,63.72 131.25,62.85 131.73,62.85 132.05,63.17 132.05,63.39 v2(132.24,63.58)
  BOTTOM w0.076: v2(132.24,63.58) 131.94,63.88 UC1.F53
CPU_DP1_N1: length 147
  TOP w0.094: CHR10.1 20.71,66.84 27.44,66.84 28.93,68.33 v2(31.7,68.33)
  IN1 w0.114: v2(132.23,66.33) 132.37,66.47 133.11,66.47 133.57,66.93 133.57,72.1 131.74,73.93 131.74,77.36 129.94,79.17 129.94,82.86 117.68,95.12 104.93,95.12 102.58,92.76 63.29,92.76 62.3,91.77 57.05,91.77 51.54,86.27 49.54,86.27 43.19,79.92 42.58,79.92 32.44,69.77 32.44,68.51 32.27,68.33 v2(31.7,68.33)
  BOTTOM w0.076: v2(132.23,66.33) 132.23,66.36 UC1.E58
CPU_DP1_N2: length 150.6
  TOP w0.094: CHR8.1 20.73,64.41 28.94,64.41 30.04,63.31 v2(31.84,63.31)
  IN1 w0.114: v2(132.3,65.37) 132.3,65.03 132.19,64.92 131.48,64.92 131.22,65.18 131.22,68.37 130.46,69.13 130.46,74.84 128.69,76.6 128.69,82.58 116.85,94.42 105.22,94.42 101.88,91.07 57.38,91.07 51.76,85.45 50.34,85.45 45.12,80.23 44.53,80.23 33.14,68.84 33.14,63.6 32.86,63.31 v2(31.84,63.31)
  BOTTOM w0.076: v2(132.3,65.37) 132.59,65.08 UC1.E55
CPU_DP1_N3: length 149
  TOP w0.094: CHR14.1 20.73,69.24 28.57,69.24 29.55,70.22 31.44,70.22 v2(31.64,70.42)
  IN1 w0.114: v2(131.6,65.44) 131.77,65.61 132.01,65.61 132.15,65.75 133.99,65.75 134.44,66.2 134.44,72.76 132.5,74.69 132.5,77.67 130.7,79.47 130.7,83.09 117.96,95.83 104.66,95.83 102.3,93.47 60.88,93.47 60.05,92.64 56.87,92.64 51.25,87.03 49.31,87.03 42.9,80.61 42.28,80.61 32.09,70.42 v2(31.64,70.42)
  BOTTOM w0.076: v2(131.6,65.44) 131.6,65.44 131.6,65.46 UC1.F56
CPU_DP1_P0: length 148.3
  TOP w0.094: CHR11.1 20.6,71.41 31.72,71.41 34.43,68.7 34.43,68.57 34.11,68.26 v2(34.1,68.26)
  IN1 w0.114: v2(34.1,68.26) 34.48,68.64 34.48,69.18 44.83,79.54 45.56,79.54 50.69,84.67 52.09,84.67 57.8,90.38 102.17,90.38 105.51,93.72 116.54,93.72 126.64,83.62 126.64,76.13 128.83,73.93 128.83,69.96 130.58,68.21 130.58,63.8 131.33,63.05 131.64,63.05 131.85,63.25 131.85,63.66 131.73,63.78 131.52,63.78 131.46,63.72 v2(131.46,63.52)
  BOTTOM w0.076: UC1.G53 131.29,63.68 v2(131.46,63.52)
CPU_DP1_P1: length 147
  TOP w0.094: CHR9.1 20.75,66.66 27.52,66.66 29.01,68.15 31.3,68.15 v2(31.7,67.75)
  IN1 w0.114: v2(132.24,67.15) 132.24,66.82 132.39,66.67 133.03,66.67 133.37,67.01 133.37,72.01 131.54,73.85 131.54,77.28 129.73,79.08 129.73,82.77 117.59,94.91 105.02,94.91 102.67,92.56 63.37,92.56 62.38,91.57 57.13,91.57 51.62,86.06 49.62,86.06 43.27,79.71 42.67,79.71 32.64,69.69 32.64,68.42 32.35,68.13 32.08,68.13 v2(31.7,67.75)
  BOTTOM w0.076: UC1.F58 132.24,67.02 v2(132.24,67.15)
CPU_DP1_P2: length 150.6
  TOP w0.094: CHR7.1 20.73,64.23 28.87,64.23 29.97,63.13 31.44,63.13 v2(31.84,62.73)
  IN1 w0.114: v2(132.23,64.42) 131.93,64.71 131.4,64.71 131.02,65.09 131.02,68.28 130.25,69.05 130.25,74.75 128.49,76.52 128.49,82.49 116.77,94.21 105.31,94.21 101.97,90.87 57.47,90.87 51.84,85.25 50.42,85.25 45.2,80.03 44.61,80.03 33.34,68.76 33.34,63.51 32.94,63.11 32.22,63.11 v2(31.84,62.73)
  BOTTOM w0.076: v2(132.23,64.42) 131.94,64.71 UC1.F55
CPU_DP1_P3: length 149
  TOP w0.094: v2(31.64,69.84) 31.44,70.04 29.63,70.04 28.64,69.05 20.44,69.05 20.25,68.87 CHR13.1
  IN1 w0.114: v2(31.64,69.84) 32.02,70.22 32.17,70.22 42.36,80.41 42.98,80.41 49.39,86.82 51.34,86.82 56.95,92.44 60.13,92.44 60.96,93.27 102.39,93.27 104.74,95.62 117.87,95.62 130.5,83 130.5,79.39 132.3,77.58 132.3,74.61 134.23,72.67 134.23,66.28 133.9,65.95 132.07,65.95 131.93,65.81 131.65,65.81 131.52,65.93 131.52,66.09 v2(131.61,66.17)
  BOTTOM w0.076: UC1.G56 131.61,66.13 v2(131.61,66.17)
CPU_POPIRCOMP: length 12.7
  TOP w0.305: v2(116.15,43.39) 116.15,43.38 115.61,42.84 114.04,42.84 113.59,42.4 111.1,42.4 110.67,42.83 v4(109.85,42.83) 107.29,42.83 106.09,41.63 RC88.1
  BOTTOM w0.254: v2(116.15,43.39) 116.15,43.25 UC1.AT16
CPU_XDP_TCK0: length 15.2
  TOP w0.089: v2(136,68.23) 136.35,68.59 v2(136.35,68.89)
  TOP w0.102: RPC1.5 141.63,69.52 140.44,68.32 138.18,68.32 T116.1 137.61,68.89 v2(136.35,68.89)
  BOTTOM w0.076: v2(136.35,68.89) 136.99,68.89 137.46,68.43 ; v2(136,68.23) 135.76,68.23 135.48,68.51 135.48,68.51 135.46,68.53 134.92,68.53 UC1.B61
  BOTTOM w0.089: 136.87,67.05 135.41,67.05 UC1.A59
  BOTTOM w0.102: 136.87,67.05 137.13,67.05 137.59,67.51 137.59,68.3 137.46,68.43
CPVDD: length 25.9
  TOP w0.203: UA1.36 28.54,20.76 v2(28.79,20.51)
  TOP w0.508: v2(33.84,9.63) 33.84,9.69 34.18,10.03 R6529.1
  IN3 w0.508: v2(28.79,20.51) 29.26,20.98 32.52,20.98 33.05,20.44 33.05,18.47 33.94,17.58 34.95,17.58 37.44,15.1 37.44,12.03 35.04,9.63 v2(33.84,9.63)
  BOTTOM w0.508: CA59.1 28.98,23.02 28.06,22.09 CA60.1 28.06,21.36 28.79,20.62 v2(28.79,20.51)
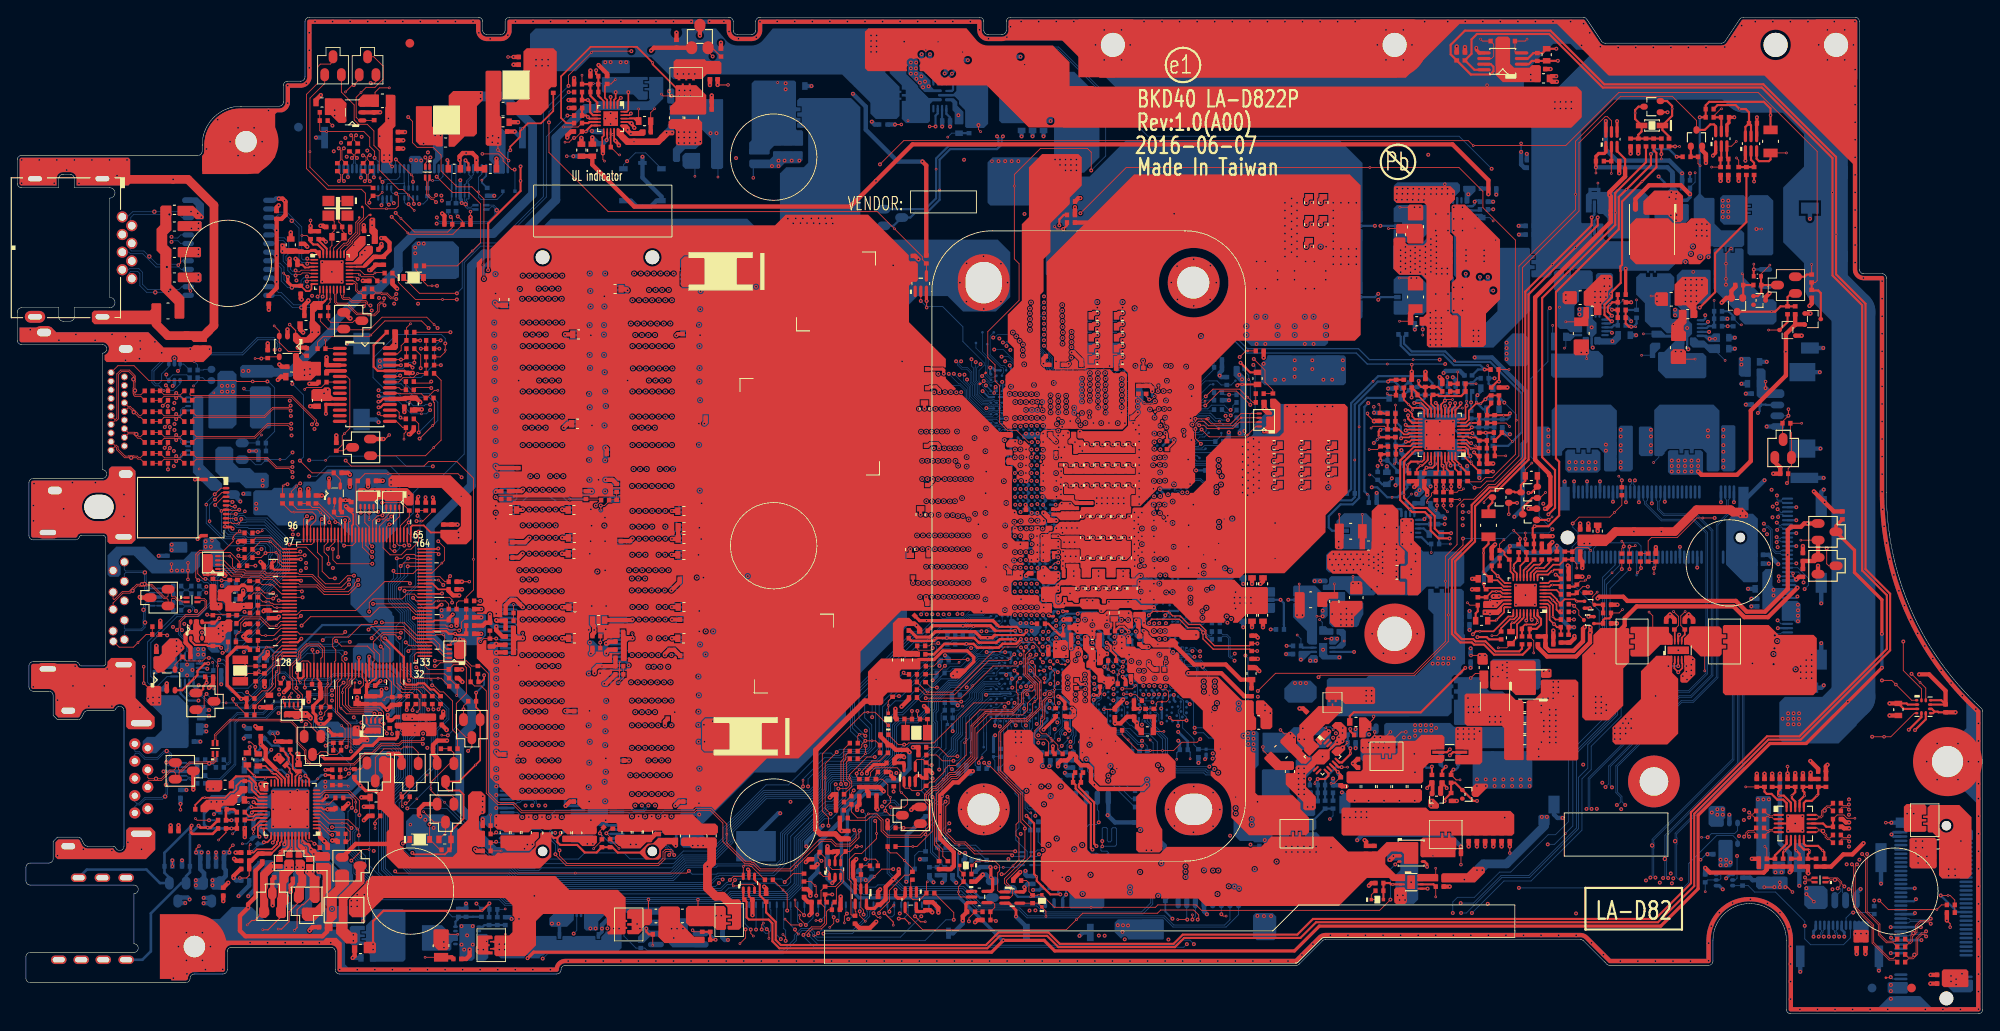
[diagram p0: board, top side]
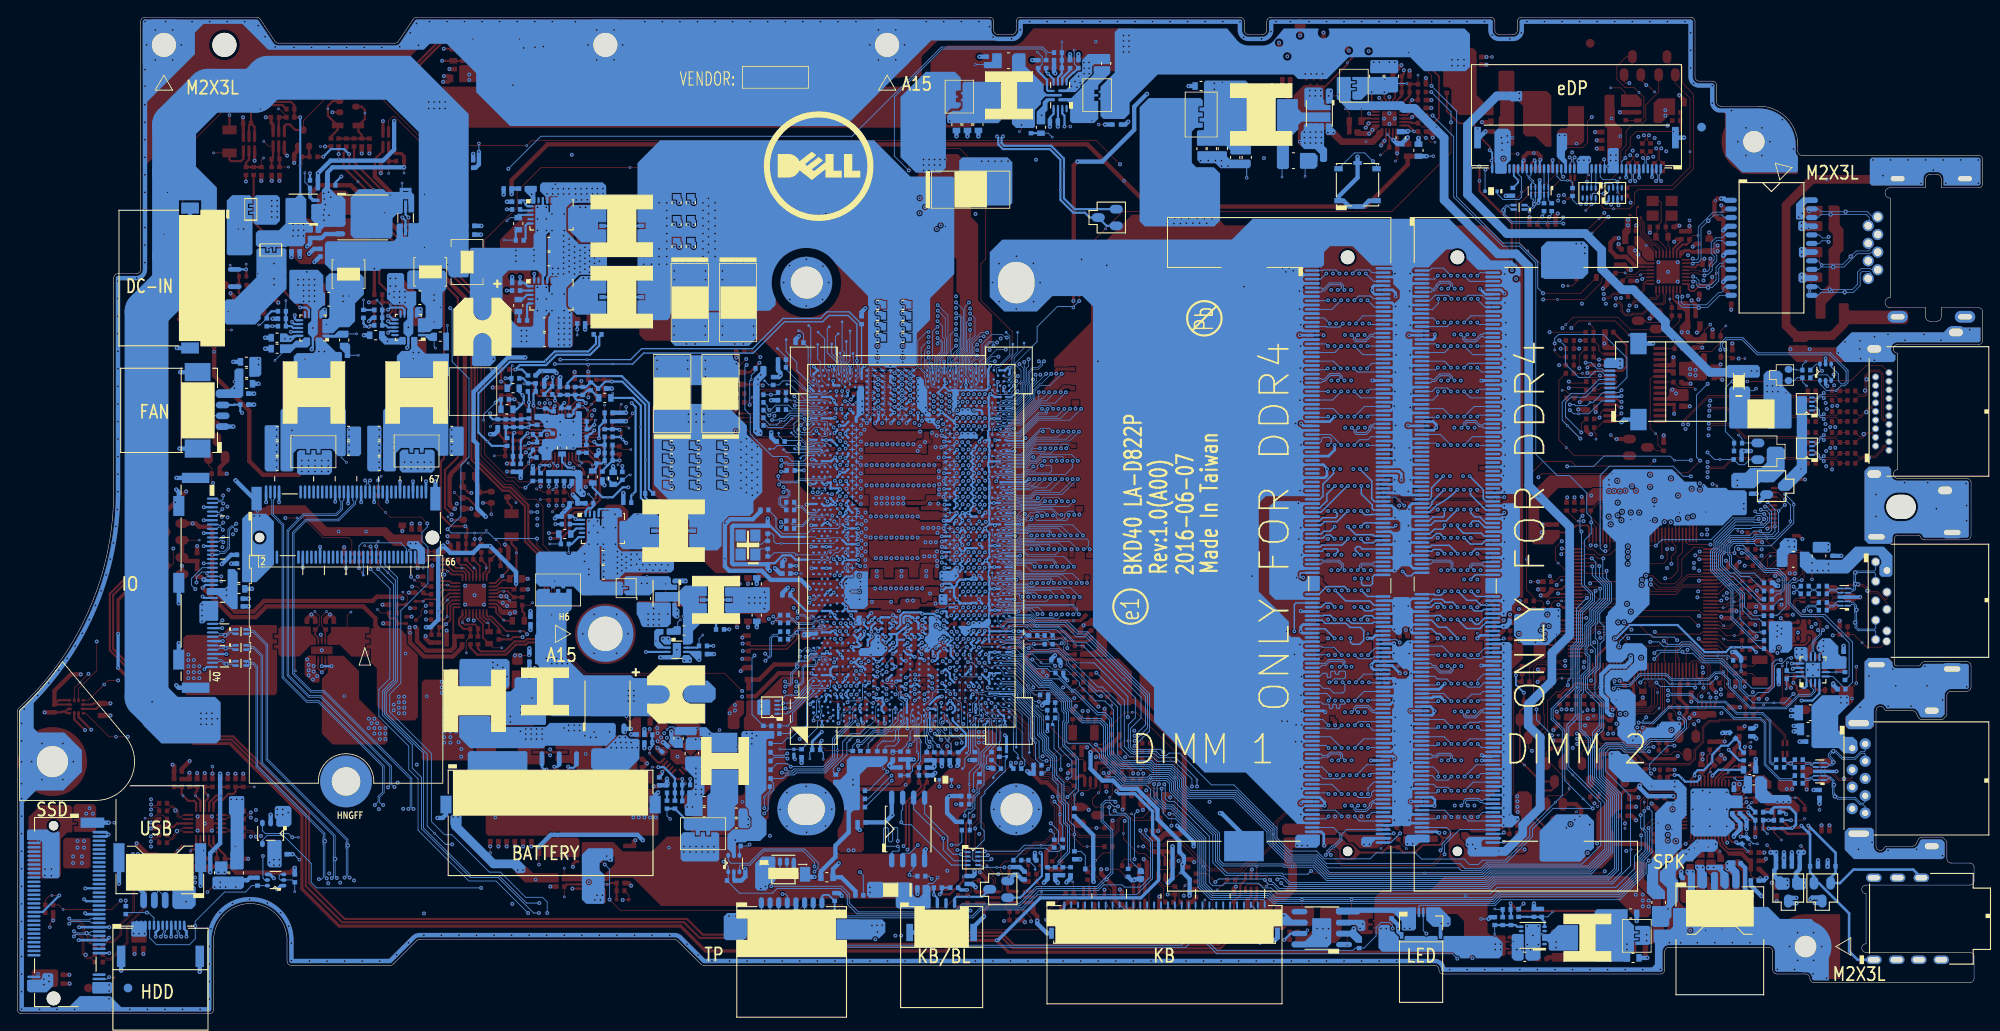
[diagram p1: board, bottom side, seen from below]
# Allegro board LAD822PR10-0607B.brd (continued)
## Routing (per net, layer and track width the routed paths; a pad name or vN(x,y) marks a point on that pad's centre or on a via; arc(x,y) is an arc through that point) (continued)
CPVEE: length 4.3
  TOP w0.127: v1(27.33,20.88) v2(27.33,21.39)
  TOP w0.203: v2(27.33,21.39) 27.33,21.52 28.09,22.27 UA1.34
  BOTTOM w0.508: CA25.2 27.33,22.45 v2(27.33,21.39)
CRT_HPD: length 155.2
  TOP w0.089: R6533.1 129.45,36.95 v2(128.87,36.95)
  TOP w0.127: v2(128.87,36.95) 128.81,37.02 v4(128.04,37.02)
  IN1 w0.114: v2(205.9,52.16) 206.63,52.16 216.76,42.03 216.76,38.33 215.09,36.66 215.09,21.24 216.88,19.44 216.88,13.01 215.85,11.98 213.49,11.98 213.34,12.13 211.03,12.13 209.42,13.73 209.42,16.16 207.69,17.9 203.11,17.9 202.1,18.91 195.02,18.91 194.58,18.46 163.49,18.46 162.88,19.06 159.48,19.06 157.64,17.22 155.11,17.22 154.42,16.53 145.92,16.53 143.94,18.51 143.2,18.51 142.31,19.4 142.31,19.97 139.62,22.66 139.62,24.97 133.15,31.44 133.15,33.69 132.27,34.56 131.64,34.56 129.25,36.95 v2(128.87,36.95)
  BOTTOM w0.076: UC1.L7 129.03,36.95 v2(128.87,36.95)
  BOTTOM w0.102: v2(205.9,52.16) JIO1.16
CS_1.2V: length 3.2
  TOP w0.102: PR205.2 68.69,100.36 69.59,99.46 v1(69.71,99.46)
  TOP w0.203: PR205.2 68.67,100.38 PU200.13
CSI2_COMP: length 2
  TOP w0.089: v2(132.93,40.7) v1(132.93,41.21)
  TOP w0.102: RC3.1 132.76,40.52 v2(132.93,40.7)
  BOTTOM w0.102: UC1.E13 132.59,41.04 v2(132.93,40.7)
DAT_SMB: length 2.5
  TOP w0.254: v2(165.33,28.61) 164.89,28.16 PR18.1
  BOTTOM w0.254: v2(165.33,28.61) 164.93,28.61 164.75,28.78 PBATT1.6
DAT_TP_SIO: length 146.5
  TOP w0.102: v2(97.49,21.22) 97.41,21.14 97.41,20.38 96.45,19.41 94.7,19.41 94.14,19.97 93.07,19.97 v1(90.18,17.08) 89.64,16.54 85.91,16.54 85.15,17.31 84.91,17.31 84.78,17.43 84.17,17.43 81.66,19.93 81.66,22.08 80.19,23.55 78.64,23.55 78.36,23.27 58.33,23.27 57.36,24.24 55.59,24.24 54.28,25.54 54.28,37.37 53.7,37.96 52.91,37.96 52.47,38.4 RZ18.2 52.47,40.03 51.84,40.65 48.95,40.65 48.58,40.28 v2(48.32,40.28) ; v2(41.08,52.89) 39.94,54.03 UE1.79
  IN3 w0.135: v2(48.32,40.28) 48.04,40.28 47.04,41.27 44.59,41.27 43.54,42.32 43.54,44.28 43.69,44.43 43.69,47.53 42.78,48.44 42.78,51.21 41.09,52.9 v2(41.08,52.89)
  BOTTOM w0.102: TPAD1.2 140.35,10.89 139.73,10.27 133.85,10.27 132.79,11.34 116.95,11.34 116.04,12.25 111.24,12.25 109.23,14.26 102.38,14.26 101.72,14.92 99.6,14.92 99.34,14.66 97.5,14.66 96.32,15.84 96.32,19.87 97.49,21.04 v2(97.49,21.22)
DBC_EN: length 185.2
  TOP w0.102: v2(45.24,103.84) 45.75,103.33 45.75,100.87 46.28,100.34 48.15,100.34 49.05,99.44 49.05,97.59 50.88,95.77 52.61,95.77 54,94.37 v1(54,86.72) v2(54,85.1) ; R5213.2 35.92,103.41 v2(36.48,102.85)
  IN1 w0.114: v2(36.48,102.85) 43.31,102.85 44.3,103.84 v2(45.24,103.84)
  IN2 w0.127: v2(54,85.1) 53.83,84.92 53.83,63.85 44.2,54.22 44.2,53.09 45.01,52.28 45.95,52.28 47.27,50.96 47.27,44.91 50.21,41.98 51.12,41.98 52.51,40.6 52.51,38.77 53.86,37.41 53.86,32.21 54.66,31.41 54.66,29.72 56.54,27.84 56.54,20.32 58.49,18.37 58.92,18.37 60.24,17.05 76.82,17.05 77.41,17.64 79.39,17.64 82,20.24 82.47,20.24 89.91,27.68 92.95,27.68 94.22,28.95 98.19,28.95 98.77,28.37 99.82,28.37 101.68,30.23 101.68,33.16 102.16,33.64 112.06,33.64 112.31,33.89 117.63,33.89 117.91,33.61 117.91,33.56 v2(117.99,33.56)
  BOTTOM w0.076: UC1.AM5 118.91,36.55 118.57,36.2 118.44,36.2 118.22,35.97 118.22,33.79 v2(117.99,33.56)
DBC_EN_R: length 12.3
  TOP w0.102: v2(41.35,99.12) 41.35,99.88 40.79,100.45 40.79,101.49 40.11,102.17 v1(35.79,102.17) 35.11,102.17 35,102.27 R5213.1 R6507.2
  BOTTOM w0.102: v2(41.35,99.12) 41.77,98.7 JEDP.10
DDPC_SDATA: length 19.2
  TOP w0.089: v2(127.88,37.63) 129.04,37.63 v1(129.44,38.03)
  IN1 w0.114: v2(136.28,32.54) 136.65,32.91 136.65,33.77 134.69,35.73 134.69,36.7 133.85,37.54 130.23,37.54 130.14,37.63 v2(127.88,37.63)
  BOTTOM w0.102: v2(136.28,32.54) 137.28,32.54 137.9,31.93 138.34,31.93 138.96,31.3 RC1122.1
  BOTTOM w0.135: v2(127.88,37.63) 128.17,37.92 UC1.N8
DDR4_DRAMRST#: length 17.4
  TOP w0.102: 56.94,59.6 v1(63.95,59.6) 65.8,59.6 ; 56.94,59.6 CD69.1 55.6,59.6 v2(55.37,59.83) ; 56.94,59.6 CD92.1 ; 65.8,59.6 CD91.1 ; 65.8,59.6 67.46,59.6 RD31.1 67.58,59.47 v2(66.95,58.85)
  BOTTOM w0.102: v2(66.95,58.85) 67.93,59.83 JDIMM1.108 ; JDIMM2.108 v2(55.37,59.83)
DDR_A_ACT#: length 52.9
  IN1 w0.183: v2(106.42,67.43) 105.55,68.3 104.89,68.3 103.44,69.75 103.44,69.98 102.55,70.87 92.55,70.87 85.51,63.83 80.25,63.83 79.05,62.63 73.25,62.63 71.92,61.3 v2(71.92,61.12)
  BOTTOM w0.076: v2(106.42,67.43) 107.08,66.77 109.55,66.77 110.76,65.57 112.27,65.57 112.46,65.37 112.82,65.37 112.82,65.37 112.91,65.41 113.11,65.41 113.2,65.37 113.2,65.37 113.2,65.37 113.21,65.36 113.44,65.36 UC1.BA55
  BOTTOM w0.17: v2(71.92,61.12) 71.92,60.2 70.64,58.92 70.64,58.48 70.49,58.33 JDIMM1.114
DDR_A_ALERT#: length 57.8
  IN1 w0.076: v2(108.58,64.03) 107.88,63.33 104.45,63.33 103.67,64.11 103.67,64.37 103.53,64.51
  IN1 w0.183: v2(71.96,58.23) 70.75,57.02 70.75,54.84 71.48,54.11 71.51,54.11 71.56,54.06 76.76,54.06 77.22,54.52 79.34,54.52 80.32,55.51 85.04,55.51 94.85,65.32 102.72,65.32 103.53,64.51
  BOTTOM w0.076: v2(108.58,64.03) 108.83,64.03 109.41,63.46 109.41,63.21 109.77,62.84 110.62,62.84 111.2,62.26 112.42,62.26 112.54,62.39 112.79,62.39 112.87,62.36 112.88,62.35 112.91,62.33 113.05,62.33 113.21,62.38 113.45,62.38 113.51,62.34 113.78,62.34 113.88,62.38 114.22,62.38 114.41,62.18 UC1.AW50
  BOTTOM w0.17: JDIMM1.116 70.66,57.83 70.7,57.79 71.52,57.79 v2(71.96,58.23)
DDR_A_BG0: length 53.7
  IN1 w0.183: v2(73.44,61.12) 73.18,61.38 73.18,61.91 73.44,62.17 79.24,62.17 80.44,63.37 85.7,63.37 92.74,70.41 102.53,70.41 103.17,69.77 103.17,69.63 105.2,67.6 v2(105.2,67.41)
  BOTTOM w0.076: UC1.AY55 114.21,65.24 113.92,64.95 113.76,64.87 113.58,64.87 113.42,64.93 113.28,64.93 113.06,64.86 112.94,64.86 112.86,64.9 112.83,64.91 112.33,64.91 112.19,64.77 111.32,64.77 109.54,66.54 106.07,66.54 v2(105.2,67.41)
  BOTTOM w0.17: v2(73.44,61.12) 73.55,61.12 76.59,58.08 JDIMM1.115
DDR_A_BG1: length 54.5
  IN1 w0.076: v2(104.59,67.41) 104.59,67.9 102.9,69.6 102.9,69.65
  IN1 w0.183: v2(74.97,61.12) 74.97,61.54 75.14,61.71 76.18,61.71 76.36,61.53 76.36,61.12 76.55,60.93 76.91,60.93 77.1,61.12 77.1,61.53 77.28,61.71 79.43,61.71 79.78,62.06 80.27,62.06 80.45,62.24 80.45,62.73 80.63,62.91 81,62.91 81.18,62.73 81.18,62.24 81.36,62.06 81.73,62.06 81.91,62.24 81.91,62.68 82.09,62.86 82.46,62.86 82.64,62.68 82.64,62.24 82.83,62.06 83.19,62.06 83.37,62.24 83.37,62.68 83.56,62.86 83.92,62.86 84.11,62.68 84.11,62.24 84.29,62.06 85.05,62.06 92.93,69.95 102.6,69.95 102.9,69.65
  BOTTOM w0.076: v2(104.59,67.41) 105.69,66.32 109.54,66.32 111.25,64.6 112.31,64.6 112.45,64.74 112.79,64.74 112.91,64.69 113.05,64.69 113.28,64.75 113.41,64.75 113.63,64.68 113.88,64.68 UC1.AY54
  BOTTOM w0.17: v2(74.97,61.12) 75.91,60.18 75.91,59.4 76.73,58.58 JDIMM1.113
DDR_A_BS0: length 54.2
  IN1 w0.076: 103.82,60.86 109.32,60.86 109.37,60.92 114.16,60.92 114.82,61.57 114.82,62.25 115.18,62.61 v2(115.45,62.61)
  IN1 w0.183: 103.82,60.86 103.73,60.77 96.73,60.77 85.26,49.3 80.14,49.3 79.52,48.68 75.99,48.68 75.89,48.58 74.89,48.58 74.77,48.7 74.77,48.85 v2(74.94,49.02)
  BOTTOM w0.076: UC1.AU52 115.8,62.96 v2(115.45,62.61)
  BOTTOM w0.17: JDIMM1.150 70.45,47.33 70.93,47.8 73.72,47.8 v2(74.94,49.02)
DDR_A_BS1: length 55.7
  IN1 w0.076: 106.52,60.53 109.42,60.53 109.64,60.75 114.23,60.75 114.98,61.5 114.98,61.78 115.35,62.14 116.06,62.14 116.18,62.03 v2(116.18,61.69)
  IN1 w0.183: 106.52,60.53 103.93,60.53 103.71,60.31 96.92,60.31 85.45,48.84 80.33,48.84 79.71,48.21 77.92,48.21 77.72,48.01 73.42,48.01 73.12,48.32 73.12,48.72 v2(73.42,49.02)
  BOTTOM w0.076: v2(116.18,61.69) 116.18,61.51 116.39,61.24 UC1.AT48
  BOTTOM w0.17: v2(73.42,49.02) 73.86,49.46 75.94,49.46 76.83,48.58 JDIMM1.145
DDR_A_CAS#: length 53.4
  IN1 w0.076: 104.18,58.73 112.92,58.73 114.96,60.78 v2(115.47,60.78)
  IN1 w0.183: v2(71.96,45.65) 72.5,46.2 79.12,46.2 79.75,46.83 80.52,46.83 81.14,47.45 86.02,47.45 97.5,58.92 103.99,58.92 104.18,58.73
  BOTTOM w0.076: UC1.AU48 115.8,61.11 v2(115.47,60.78)
  BOTTOM w0.17: v2(71.96,45.65) 71.52,46.09 70.68,46.09 70.41,45.83 JDIMM1.156
DDR_A_CKE0: length 53.3
  IN1 w0.183: v2(75.13,63.08) 75.13,64.11 75.34,64.33 76.65,64.33 76.82,64.16 76.82,63.59 76.99,63.41 77.36,63.41 77.49,63.55 77.49,64.19 77.63,64.33 78.11,64.33 78.23,64.21 78.23,63.47 78.41,63.29 78.78,63.29 78.96,63.47 78.96,64.13 79.12,64.3 85.32,64.3 92.36,71.34 102.74,71.34 103.72,70.36 103.72,69.86 105,68.58 106.5,68.58 v2(107.64,67.43)
  BOTTOM w0.076: UC1.BA56 113.18,65.96 112.98,65.96 112.84,66.06 110.73,66.06 109,67.79 108,67.79 v2(107.64,67.43)
  BOTTOM w0.17: v2(75.13,63.08) 75.13,62.55 76.36,61.33 76.36,59.94 76.72,59.58 JDIMM1.109
DDR_A_CKE1: length 52.7
  IN1 w0.076: 104.02,70.71 103.99,70.68 103.99,69.9 105.1,68.79 106.78,68.79 108.15,67.43 v2(108.76,67.43)
  IN1 w0.183: v2(72.09,63.08) 72.53,63.53 73.89,63.53 75.15,64.79 85.16,64.79 92.17,71.8 102.93,71.8 104.02,70.71
  BOTTOM w0.076: v2(108.76,67.43) 109.12,67.43 110.75,65.8 UC1.BB56
  BOTTOM w0.17: JDIMM1.110 70.41,59.33 70.72,59.64 70.72,61.71 v2(72.09,63.08)
DDR_A_CLK0: length 54.6
  IN1 w0.076: 102.14,62.81 102.16,62.81 102.18,62.83 102.88,62.83 103.38,62.34 111.17,62.34 111.24,62.26 113.24,62.26 114.28,63.3 115.38,63.3 115.98,63.9 115.98,64.2 v2(116.22,64.44)
  IN1 w0.114: 102.14,62.81 95.88,62.81 85.56,52.49 80.84,52.49 80.15,51.79 78.04,51.79 77.64,51.4 77.64,50.87 77.36,50.59 74.4,50.59 74.13,50.86 74.13,51.09 v2(73.86,51.36)
  BOTTOM w0.076: UC1.AT53 116.22,64.21 v2(116.22,64.44)
  BOTTOM w0.102: JDIMM1.137 76.45,52.58 76.42,52.54 74.48,52.54 74.02,52.07 74.02,51.52 v2(73.86,51.36)
DDR_A_CLK1: length 55
  IN1 w0.076: v2(116.1,65.35) 115.87,65.12 115.87,64.94 115.72,64.79 115.3,64.79 114.06,63.55 111.78,63.55 110.9,62.67 103.68,62.67 102.79,63.56 102.18,63.56 102.16,63.54 102.14,63.54
  IN1 w0.114: 102.14,63.54 95.58,63.54 85.26,53.21 80.54,53.21 79.85,52.52 77.74,52.52 77.05,51.83 72.88,51.83 72.86,51.85 72.3,51.85 72.21,51.76 72.21,51.49 v2(72.34,51.36)
  BOTTOM w0.076: v2(116.1,65.35) UC1.AT55
  BOTTOM w0.102: JDIMM1.138 70.43,52.33 70.57,52.18 71.89,52.18 72.15,51.93 72.15,51.55 v2(72.34,51.36)
DDR_A_CLK#0: length 54.6
  IN1 w0.076: v2(115.45,64.44) 115.64,64.63 115.74,64.63 115.82,64.55 115.82,63.97 115.31,63.46 114.21,63.46 113.17,62.43 111.31,62.43 111.23,62.51 103.44,62.51 102.95,63 102.18,63 102.16,63.02 102.14,63.02
  IN1 w0.114: 102.14,63.02 95.8,63.02 85.47,52.69 80.76,52.69 80.07,52 77.95,52 77.44,51.48 77.44,50.96 77.27,50.79 74.49,50.79 74.34,50.94 74.34,51.08 v2(74.63,51.36)
  BOTTOM w0.076: v2(115.45,64.44) 115.61,64.44 115.8,64.25 UC1.AU53
  BOTTOM w0.102: v2(74.63,51.36) 74.41,51.36 74.23,51.55 74.23,51.98 74.57,52.32 76.35,52.32 76.6,52.08 JDIMM1.139
DDR_A_CLK#1: length 54.8
  IN1 w0.076: 102.14,63.74 102.16,63.74 102.18,63.72 102.86,63.72 103.75,62.84 110.83,62.84 111.71,63.71 113.99,63.71 115.23,64.96 115.65,64.96 115.7,65.01 115.7,65.12 v2(115.47,65.35)
  IN1 w0.114: v2(71.58,51.36) 71.96,51.75 71.96,51.8 72.21,52.05 72.94,52.05 72.96,52.03 76.96,52.03 77.65,52.72 79.77,52.72 80.46,53.41 85.17,53.41 95.5,63.74 102.14,63.74
  BOTTOM w0.076: v2(115.47,65.35) UC1.AU55
  BOTTOM w0.102: JDIMM1.140 70.42,51.83 70.56,51.97 71.8,51.97 71.93,51.84 71.93,51.72 v2(71.58,51.36)
DDR_A_CS#0: length 57.6
  IN1 w0.076: 104.3,57.07 104.32,57.06 109.4,57.06 110.2,56.26 112.68,56.26 115.01,58.59 115.65,58.59 116,58.95 v2(116.06,58.95)
  IN1 w0.183: v2(79.67,44.28) 79.82,44.28 80.46,44.92 81.15,44.92 81.39,44.69 81.39,43.81 81.5,43.7 81.79,43.7 82.01,43.92 82.01,44.83 82.13,44.95 82.62,44.95 82.81,44.77 82.81,42.82 82.94,42.69 83.36,42.69 83.54,42.87 83.54,44.82 83.67,44.95 84.04,44.95 84.22,44.77 84.22,43.69 84.48,43.43 84.88,43.43 85.11,43.66 85.11,44.56 85.51,44.95 86.4,44.95 98.52,57.07 104.3,57.07
  BOTTOM w0.076: v2(116.06,58.95) 116.06,59.15 UC1.AU45
  BOTTOM w0.17: JDIMM1.149 79.47,47.58 79.67,47.37 v2(79.67,44.28)
DDR_A_CS#1: length 59.9
  IN1 w0.076: v2(115.5,58.95) 115.14,58.95 113.32,57.14 110.64,57.14 110.39,56.89 109.96,56.89 109.57,57.28 104.48,57.28
  IN1 w0.183: 104.48,57.28 104.22,57.54 98.33,57.54 86.21,45.42 80.3,45.42 79.69,44.81 78.82,44.81 77.93,43.92 73.29,43.92 73.18,43.81 v2(73.18,43.49)
  BOTTOM w0.076: v2(115.5,58.95) 115.8,58.65 UC1.AU43
  BOTTOM w0.17: v2(73.18,43.49) 73.18,43.05 72.93,42.79 72.1,42.79 71.64,43.26 71.64,44.36 72.01,44.74 73.21,44.74 73.68,45.21 76.11,45.21 76.47,45.58 JDIMM1.157
DDR_A_D0: length 67.8
  IN1 w0.114: v2(72.92,85.73) 73.35,86.16 76.41,86.16 76.81,85.76 78.92,85.76 80.64,87.48 102.7,87.48 106.52,91.29 114.47,91.29 119.53,86.23 119.53,79.34 v2(118.82,78.64)
  BOTTOM w0.076: UC1.AL71 119.49,74.54 119.49,75.81 119.14,76.16 119.14,76.45 118.46,77.13 118.46,78.27 v2(118.82,78.64)
  BOTTOM w0.102: v2(72.92,85.73) 72.51,86.13 70.99,86.13 70.68,85.83 JDIMM1.4
DDR_A_D1: length 69.8
  IN1 w0.114: v2(118.82,82.38) 118.45,82.76 118.45,86.38 114.19,90.63 106.79,90.63 102.98,86.82 85.78,86.82 85.36,86.4 85.2,86.4 84.78,86.82 84.62,86.82 84.46,86.66 84.46,86.49 84.87,86.08 84.87,85.92 84.71,85.75 84.55,85.75 84.14,86.17 83.98,86.17 83.82,86.01 83.82,85.84 84.23,85.43 84.23,85.27 84.06,85.1 75.07,85.1 v2(74.45,85.73)
  BOTTOM w0.076: v2(118.82,82.38) 117.96,81.52 117.96,76.92 118.41,76.48 118.41,75.08 118.61,74.88 118.61,74.37 118.6,74.34 118.57,74.26 118.57,74.14 118.63,73.93 118.63,73.78 118.58,73.62 118.58,73.44 118.62,73.36 118.62,72.88 118.63,72.76 118.81,72.57 118.98,72.56 UC1.AL68
  BOTTOM w0.102: v2(74.45,85.73) 74.85,86.13 76.39,86.13 76.45,86.08 JDIMM1.3
DDR_A_D2: length 69.9
  IN1 w0.114: v2(71.2,82.63) 71.94,83.37 76.13,83.37 76.51,83 76.77,83 76.88,83.11 76.88,83.38 76.99,83.5 77.22,83.5 77.34,83.38 77.34,83.11 77.45,83 77.68,83 77.79,83.11 77.79,83.38 77.91,83.5 78.14,83.5 78.25,83.38 78.25,83.11 78.37,83 83.72,83 85.5,84.78 85.66,84.78 85.99,84.45 86.16,84.45 86.32,84.61 86.32,84.77 85.99,85.1 85.99,85.27 86.29,85.57 104.86,85.57 108.68,89.39 113.68,89.39 116.26,86.8 116.26,83.96 117.7,82.52 117.7,81.6 v2(117.2,81.1)
  BOTTOM w0.076: v2(117.2,81.1) 116.63,80.54 116.63,78.53 117.28,77.88 117.28,76.61 117.75,76.14 117.75,74.81 117.75,74.81 117.75,73.87 117.96,73.67 118.01,73.5 117.99,73.39 117.96,73.29 118,73.08 UC1.AN68
  BOTTOM w0.102: JDIMM1.20 70.39,81.83 v2(71.2,82.63)
DDR_A_D3: length 69
  IN1 w0.114: v2(117.32,82.37) 115.93,83.76 115.93,86.67 113.54,89.06 108.81,89.06 105,85.24 102.4,85.24 102.29,85.13 102.29,84.77 102.17,84.66 101.95,84.66 101.83,84.77 101.83,85.13 101.72,85.24 101.49,85.24 101.32,85.08 101.32,84.77 101.21,84.66 101.04,84.66 100.93,84.77 100.93,85.13 100.82,85.24 100.57,85.24 100.46,85.13 100.46,84.77 100.35,84.66 100.12,84.66 100,84.77 100,85.13 99.89,85.24 99.66,85.24 99.55,85.13 99.55,84.77 99.43,84.66 99.2,84.66 99.09,84.77 99.09,85.13 98.97,85.24 87.42,85.24 85.5,83.32 85.34,83.32 85,83.66 84.84,83.66 84.68,83.49 84.68,83.33 85.01,83 85.01,82.84 84.84,82.67 76.37,82.67 75.99,83.04 74.31,83.04 74.2,82.93 74.2,82.68 v2(74.24,82.63)
  BOTTOM w0.076: UC1.AN69 118.38,73.32 118.38,73.57 118.46,73.79 118.46,73.92 118.39,74.15 118.39,74.25 118.39,74.26 118.45,74.41 118.45,74.81 118.24,75.01 118.24,76.41 117.8,76.85 117.8,81.89 v2(117.32,82.37)
  BOTTOM w0.102: v2(74.24,82.63) 75.3,81.58 JDIMM1.21
DDR_A_D4: length 68.9
  IN1 w0.114: v2(71.4,85.73) 72.16,86.49 79.18,86.49 80.5,87.81 102.57,87.81 106.38,91.62 114.61,91.62 119.86,86.37 119.86,78.4 v2(118.82,77.37)
  BOTTOM w0.076: UC1.AL70 119.51,74.01 119.68,74.19 119.74,74.32 119.77,74.43 119.77,74.67 119.65,74.79 119.65,75.9 119.33,76.23 119.33,76.86 v2(118.82,77.37)
  BOTTOM w0.102: v2(71.4,85.73) 70.5,84.83 JDIMM1.8
DDR_A_D5: length 69.3
  IN1 w0.114: v2(75.97,85.73) 76.27,85.43 81.33,85.43 81.44,85.54 81.44,86.75 81.55,86.86 81.78,86.86 81.9,86.75 81.9,85.54 82.01,85.43 82.25,85.43 82.37,85.54 82.37,86.75 82.48,86.86 82.71,86.86 82.82,86.75 82.82,85.54 82.94,85.43 83.37,85.43 83.49,85.55 83.49,87.01 83.63,87.15 102.84,87.15 106.66,90.96 114.33,90.96 119.2,86.1 119.2,79.65 v2(118.82,79.27)
  BOTTOM w0.076: v2(118.82,79.27) 119.5,78.59 119.5,76.29 119.82,75.97 119.82,74.89 119.94,74.77 119.94,74.41 119.91,74.32 119.9,74.25 119.89,74.17 119.85,74.04 119.85,74.04 119.77,73.85 119.77,73.68 119.51,73.42 UC1.AL69
  BOTTOM w0.102: v2(75.97,85.73) 76.62,85.08 JDIMM1.7
DDR_A_D6: length 67.6
  IN1 w0.114: v2(117.2,79.19) 115.27,81.12 115.27,86.39 113.27,88.4 109.09,88.4 105.27,84.58 103.48,84.58 102.9,84 90.91,84 90.79,84.11 90.79,84.47 90.68,84.58 90.45,84.58 90.33,84.47 90.33,84.11 90.22,84 89.99,84 89.88,84.11 89.88,84.47 89.76,84.58 89.53,84.58 89.42,84.47 89.42,84.11 89.31,84 89.08,84 88.96,84.11 88.96,84.47 88.85,84.58 88.62,84.58 88.51,84.47 88.51,84.11 88.39,84 88.16,84 88.05,84.11 88.05,84.47 87.93,84.58 87.69,84.58 85.12,82.01 72.7,82.01 72.55,82.17 72.55,82.46 v2(72.72,82.63)
  BOTTOM w0.076: UC1.AN70 117.92,74.13 117.92,74.87 117.91,74.88 117.91,76.23 117.47,76.68 117.47,77.96 117.2,78.23 v2(117.2,79.19)
  BOTTOM w0.102: JDIMM1.16 70.54,82.83 70.83,83.12 72.23,83.12 v2(72.72,82.63)
DDR_A_D7: length 66.5
  IN1 w0.114: v2(117.2,80.46) 115.6,82.06 115.6,86.53 113.4,88.73 108.95,88.73 105.13,84.91 103.35,84.91 102.76,84.33 98.76,84.33 98.64,84.44 98.64,84.8 98.53,84.91 98.3,84.91 98.19,84.8 98.19,84.44 98.07,84.33 97.83,84.33 97.72,84.44 97.72,84.8 97.6,84.91 97.37,84.91 97.26,84.8 97.26,84.44 97.14,84.33 96.92,84.33 96.8,84.44 96.8,84.8 96.69,84.91 96.46,84.91 96.34,84.8 96.34,84.44 96.23,84.33 95.99,84.33 95.87,84.44 95.87,84.8 95.76,84.91 95.53,84.91 95.42,84.8 95.42,84.44 95.3,84.33 95.07,84.33 94.96,84.44 94.96,84.8 94.85,84.91 94.62,84.91 94.5,84.8 94.5,84.44 94.39,84.33 94.16,84.33 94.05,84.44 94.05,84.8 93.93,84.91 93.7,84.91 93.59,84.8 93.59,84.44 93.47,84.33 93.25,84.33 93.13,84.44 93.13,84.8 93.02,84.91 92.79,84.91 92.67,84.8 92.67,84.44 92.56,84.33 92.33,84.33 92.22,84.44 92.22,84.8 92.1,84.91 91.87,84.91 91.76,84.8 91.76,84.44 91.65,84.33 91.42,84.33 91.3,84.44 91.3,84.8 91.19,84.91 87.56,84.91 84.98,82.34 75.87,82.34 75.77,82.43 v2(75.77,82.63)
  BOTTOM w0.076: UC1.AN71 118.18,74.84 118.08,74.95 118.08,76.32 117.63,76.76 117.63,80.03 v2(117.2,80.46)
  BOTTOM w0.102: JDIMM1.17 75.82,82.58 v2(75.77,82.63)
DDR_A_D8: length 57
  IN1 w0.114: v2(115.62,78.45) 115.71,78.35 115.83,78.35 115.98,78.51 115.98,78.66 114.38,80.26 110.18,80.26 107.14,83.3 104.22,83.3 103.64,82.72 87.64,82.72 85.45,80.52 85,80.52 84.89,80.41 84.89,80.22 84.77,80.11 84.55,80.11 84.43,80.22 84.43,80.41 84.32,80.52 74.84,80.52 74.61,80.28 74.33,80.28 74.09,80.52 73.82,80.52 73.68,80.38 73.68,80.08 73.83,79.93 v2(74.06,79.93)
  BOTTOM w0.076: UC1.AR70 117.15,74.01 117.42,74.28 117.42,74.67 117.42,74.67 117.42,75.91 116.9,76.43 116.9,77.63 116.08,78.45 v2(115.62,78.45)
  BOTTOM w0.102: v2(74.06,79.93) 74.19,79.79 74.19,79.76 74.43,79.52 75.94,79.52 75.99,79.58 JDIMM1.29
DDR_A_D9: length 58.3
  IN1 w0.114: v2(75.58,79.93) 75.84,80.19 76.08,80.19 76.2,80.08 76.2,79.89 76.31,79.78 76.54,79.78 76.66,79.89 76.66,80.08 76.77,80.19 77,80.19 77.11,80.08 77.11,79.89 77.23,79.78 77.46,79.78 77.57,79.89 77.57,80.08 77.68,80.19 77.93,80.19 78.04,80.08 78.04,79.89 78.15,79.78 78.38,79.78 78.5,79.89 78.5,80.08 78.61,80.19 79.29,80.19 79.41,80.08 79.41,79.89 79.52,79.78 79.75,79.78 79.86,79.89 79.86,80.08 79.98,80.19 80.21,80.19 80.32,80.08 80.32,79.89 80.44,79.78 80.66,79.78 80.78,79.89 80.78,80.08 80.89,80.19 81.12,80.19 81.24,80.08 81.24,79.89 81.35,79.78 81.58,79.78 81.69,79.89 81.69,80.08 81.81,80.19 82.04,80.19 82.15,80.08 82.15,79.89 82.26,79.78 82.49,79.78 82.61,79.89 82.61,80.08 82.72,80.19 82.96,80.19 83.08,80.08 83.08,79.89 83.19,79.78 83.42,79.78 83.53,79.89 83.53,80.08 83.65,80.19 83.88,80.19 83.99,80.08 83.99,79.89 84.11,79.78 85.17,79.78 87.78,82.39 103.78,82.39 104.36,82.97 107,82.97 110.04,79.93 113.26,79.93 114.77,78.42 115.03,78.42 115.22,78.62 v2(115.22,78.89)
  BOTTOM w0.076: UC1.AR68 117.05,72.77 117.38,73.09 117.38,73.12 117.39,73.21 117.38,73.27 117.33,73.38 117.32,73.44 117.35,73.59 117.59,73.87 117.59,74.74 117.58,74.74 117.58,76.01 117.09,76.51 117.09,77.75 115.95,78.89 v2(115.22,78.89)
  BOTTOM w0.102: v2(75.58,79.93) 76.23,80.58 JDIMM1.25
DDR_A_D10: length 55
  IN1 w0.114: v2(75.77,77.32) 75.55,77.32 75.38,77.49 75.38,77.7 75.5,77.82 79.26,77.82 79.37,77.7 79.37,77.35 79.49,77.24 79.71,77.24 79.83,77.35 79.83,78.09 79.94,78.2 80.17,78.2 80.29,78.09 80.29,77.35 80.4,77.24 80.63,77.24 80.74,77.35 80.74,78.09 80.86,78.2 81.09,78.2 81.2,78.09 81.2,77.35 81.31,77.24 81.54,77.24 81.66,77.35 81.66,78.09 81.77,78.2 82.01,78.2 82.13,78.09 82.13,77.35 82.24,77.24 82.48,77.24 82.6,77.35 82.6,78.09 82.71,78.2 82.94,78.2 83.05,78.09 83.05,77.35 83.17,77.24 83.41,77.24 83.52,77.35 83.52,77.4 83.64,77.52 83.98,77.52 84.1,77.4 84.1,77.35 84.21,77.24 84.85,77.24 88.43,80.81 106.93,80.81 109.39,78.36 110.34,78.36 111.78,76.92 v2(113.07,76.92)
  BOTTOM w0.076: v2(113.07,76.92) 114.11,76.92 115.72,75.31 115.72,74.62 UC1.AU71
  BOTTOM w0.102: v2(75.77,77.32) 76.03,77.58 JDIMM1.37
DDR_A_D11: length 57.3
  IN1 w0.114: v2(74.24,77.32) 75.07,78.15 79.18,78.15 79.56,78.53 83.27,78.53 83.38,78.42 83.38,77.96 83.5,77.85 83.73,77.85 83.84,77.96 83.84,78.42 83.96,78.53 84.18,78.53 84.3,78.42 84.3,77.96 84.41,77.85 84.64,77.85 84.76,77.96 84.76,78.42 84.87,78.53 85.68,78.53 88.29,81.14 107.07,81.14 109.53,78.69 110.48,78.69 110.86,78.31 v2(112.95,78.31)
  BOTTOM w0.076: UC1.AU68 116.2,72.56 116.63,72.58 116.75,72.69 116.83,72.84 116.83,72.91 116.8,73 116.74,73.15 116.74,73.23 116.76,73.62 116.7,73.78 116.7,73.93 116.77,74.14 116.77,74.26 116.74,74.34 116.72,74.37 116.72,74.79 116.9,74.97 116.9,75.42 116.52,75.8 116.28,75.8 115.81,76.27 115.81,77.56 114.73,78.64 113.44,78.64 113.1,78.31 v2(112.95,78.31)
  BOTTOM w0.102: JDIMM1.41 74.99,76.58 v2(74.24,77.32)
DDR_A_D12: length 55.5
  IN1 w0.114: v2(116.39,77.49) 116.38,77.5 116.38,78.55 114.34,80.59 110.32,80.59 108.09,82.81 107.28,83.63 104.09,83.63 103.5,83.05 87.5,83.05 85.31,80.85 73.45,80.85 v2(72.53,79.93)
  BOTTOM w0.076: v2(116.39,77.49) 116.73,77.15 116.73,76.33 117.25,75.81 117.25,74.61 UC1.AR71
  BOTTOM w0.102: v2(72.53,79.93) 72.53,80.02 71.73,80.83 JDIMM1.24
DDR_A_D13: length 57.2
  IN1 w0.114: v2(116.39,76.22) 116.76,76.6 116.76,78.46 114.3,80.92 110.45,80.92 108.42,82.95 108.42,82.95 107.41,83.96 103.95,83.96 103.36,83.38 87.37,83.38 85.17,81.18 72.26,81.18 v2(71.01,79.93)
  BOTTOM w0.076: v2(116.39,76.22) 116.4,76.22 117.09,75.53 117.09,74.87 116.89,74.67 116.89,74.41 116.94,74.29 116.94,74.27 116.95,74.26 116.94,74.25 116.94,74.15 116.88,73.92 116.88,73.79 116.95,73.57 116.95,73.32 UC1.AR69
  BOTTOM w0.102: v2(71.01,79.93) 70.9,79.83 JDIMM1.28
DDR_A_D14: length 55.3
  IN1 w0.114: v2(113.92,76.09) 113.95,76.06 113.95,75.88 113.83,75.76 112.47,75.76 110.2,78.03 109.25,78.03 106.8,80.48 88.57,80.48 84.99,76.9 78.57,76.9 78.45,77.02 78.45,77.41 78.37,77.49 78.15,77.49 78.07,77.41 78.07,77.02 77.95,76.9 77.76,76.9 77.64,77.02 77.64,77.37 77.53,77.49 77.3,77.49 77.18,77.37 77.18,77.02 77.07,76.9 76.84,76.9 76.73,77.02 76.73,77.37 76.61,77.49 76.38,77.49 76.27,77.37 76.27,77.02 76.16,76.9 72.75,76.9 72.61,77.05 72.61,77.2 v2(72.72,77.3)
  BOTTOM w0.076: v2(113.92,76.09) 114.69,76.09 115.55,75.23 115.55,74.14 UC1.AU70
  BOTTOM w0.102: v2(72.72,77.3) 72.71,77.3 71.73,76.33 JDIMM1.42
DDR_A_D15: length 55.5
  IN1 w0.114: v2(71.2,77.32) 70.89,77.32 70.55,76.97 70.55,76.29 70.66,76.18 70.89,76.18 71.01,76.29 71.01,76.65 71.12,76.77 71.35,76.77 71.46,76.65 71.46,76.29 71.58,76.18 71.82,76.18 71.93,76.29 71.93,76.8 72.05,76.91 72.28,76.91 72.39,76.8 72.39,76.69 72.5,76.57 85.13,76.57 88.7,80.15 106.66,80.15 109.12,77.7 110.07,77.7 112.2,75.56 v2(114.33,75.56)
  BOTTOM w0.076: UC1.AU69 115.83,73.42 115.45,73.8 115.45,73.98 115.37,74.06 115.37,75.16 114.96,75.56 v2(114.33,75.56)
  BOTTOM w0.102: v2(71.2,77.32) 71.19,77.33 JDIMM1.38
DDR_A_D16: length 51.9
  IN1 w0.114: v2(74.3,74.73) 74.86,75.29 82.04,75.29 82.16,75.18 82.16,74.79 82.27,74.68 82.5,74.68 82.61,74.79 82.61,75.18 82.73,75.29 82.96,75.29 83.07,75.18 83.07,74.79 83.19,74.68 83.41,74.68 83.53,74.79 83.53,75.18 83.64,75.29 83.87,75.29 83.99,75.18 83.99,74.79 84.1,74.68 85.05,74.68 89.24,78.87 106.13,78.87 108.63,76.36 109.87,76.36 v2(110.43,75.8)
  BOTTOM w0.076: v2(110.43,75.8) 110.43,75.01 110.66,74.78 110.66,73.21 110.95,72.92 110.95,71.7 111.8,70.86 112.58,70.86 UC1.BB65
  BOTTOM w0.102: JDIMM1.45 75.14,75.58 v2(74.3,74.73)
DDR_A_D17: length 53
  IN1 w0.114: v2(109.92,73.44) 110,73.52 110,75.32 109.28,76.04 108.49,76.04 105.99,78.54 89.37,78.54 85.18,74.35 81.83,74.35 81.71,74.46 81.71,74.85 81.6,74.96 81.37,74.96 81.26,74.85 81.26,74.46 81.14,74.35 80.9,74.35 80.79,74.46 80.79,74.85 80.67,74.96 80.44,74.96 80.33,74.85 80.33,74.46 80.21,74.35 79.99,74.35 79.87,74.46 79.87,74.85 79.76,74.96 79.53,74.96 79.41,74.85 79.41,74.46 79.3,74.35 78.63,74.35 78.51,74.46 78.51,74.56 78.4,74.68 77.84,74.68 77.72,74.79 77.72,74.85 77.61,74.96 77.38,74.96 77.26,74.85 77.26,74.79 77.15,74.68 76.92,74.68 76.81,74.79 76.81,74.85 76.69,74.96 76.46,74.96 76.35,74.85 76.35,74.67 76.24,74.56 75.88,74.56 75.82,74.61 v2(75.82,74.73)
  BOTTOM w0.076: UC1.AW65 114.64,70.05 114.45,69.86 113.85,69.86 113.81,69.83 113.58,69.83 113.42,69.88 113.28,69.88 113.06,69.82 112.94,69.82 112.83,69.86 112.45,69.86 112.32,69.73 112.06,69.73 110.35,71.44 110.35,72.7 109.92,73.13 v2(109.92,73.44)
  BOTTOM w0.102: v2(75.82,74.73) 75.86,74.73 76.02,74.58 JDIMM1.49
DDR_A_D18: length 55
  IN1 w0.114: v2(106.59,74.11) 104.4,76.3 90.3,76.3 84.81,70.81 79.95,70.81 79.65,71.12 79.65,71.32 79.47,71.5 78.64,71.5 78.48,71.33 78.48,71.03 78.26,70.81 76.44,70.81 76.33,70.93 76.33,71.51 76.22,71.62 75.99,71.62 75.87,71.51 75.87,70.93 75.76,70.81 75.52,70.81 75.4,70.93 75.4,71.51 75.29,71.62 75.06,71.62 74.95,71.51 74.95,70.93 74.83,70.81 74.58,70.81 74.24,71.14 v2(74.24,72.06)
  BOTTOM w0.076: v2(106.59,74.11) 107.96,72.74 109.1,72.74 109.69,72.15 109.69,71.01 111.7,69 113.34,69 113.56,69.22 113.7,69.24 113.83,69.24 113.95,69.21 114.12,69.21 114.13,69.22 114.13,69.22 114.44,69.53 UC1.AW63
  BOTTOM w0.102: JDIMM1.63 75.23,71.08 v2(74.24,72.06)
DDR_A_D19: length 53.2
  IN1 w0.076: v2(109.62,74.01) 108.97,74.67 108.05,74.67 106.55,76.16 106.36,76.16 106.3,76.23
  IN1 w0.114: 106.3,76.23 105.23,77.29 89.89,77.29 85.36,72.76 84.19,72.76 84.08,72.65 84.08,71.93 83.96,71.81 83.73,71.81 83.62,71.93 83.62,72.65 83.5,72.76 76.31,72.76 76.26,72.81 71.94,72.81 v2(71.2,72.06)
  BOTTOM w0.076: v2(109.62,74.01) 109.5,73.88 109.5,73.3 110.19,72.61 110.19,71.29 111.91,69.56 112.4,69.56 112.54,69.7 112.79,69.7 112.91,69.64 113.05,69.64 113.28,69.71 113.41,69.71 113.63,69.63 113.88,69.63 UC1.AY63
  BOTTOM w0.102: JDIMM1.58 70.93,72.33 v2(71.2,72.06)
DDR_A_D20: length 52.7
  IN1 w0.114: v2(72.77,74.73) 73.66,75.62 84.32,75.62 84.43,75.51 84.43,75.12 84.54,75.01 84.77,75.01 84.89,75.12 84.89,75.51 85,75.62 85.52,75.62 89.1,79.2 106.27,79.2 108.72,76.74 110.02,76.74 110.93,75.84 v2(110.93,75.47)
  BOTTOM w0.076: v2(110.93,75.47) 110.93,74.91 110.85,74.83 110.85,73.26 111.12,72.99 111.12,71.77 111.87,71.03 112.79,71.03 113.04,70.91 113.04,70.9 113.05,70.9 113.19,70.76 UC1.BA65
  BOTTOM w0.102: v2(72.77,74.73) 72.37,74.33 JDIMM1.50
DDR_A_D21: length 53.1
  IN1 w0.114: v2(111.48,75.23) 111.48,75.57 109.98,77.07 108.86,77.07 106.4,79.53 88.96,79.53 85.39,75.95 72.47,75.95 v2(71.25,74.73)
  BOTTOM w0.076: v2(111.48,75.23) 111.01,74.76 111.01,73.33 111.31,73.03 111.31,71.89 112.01,71.19 112.83,71.19 112.99,71.11 113.06,71.08 113.1,71.08 113.23,71.03 113.52,71.03 113.78,70.76 UC1.AY65
  BOTTOM w0.102: JDIMM1.46 70.69,75.33 71.25,74.77 v2(71.25,74.73)
DDR_A_D22: length 52.8
  IN1 w0.114: v2(107.81,74.11) 107.41,74.5 107.09,74.5 104.96,76.63 90.16,76.63 84.67,71.14 81.93,71.14 81.82,71.26 81.82,71.99 81.7,72.1 81.47,72.1 81.36,71.99 81.36,71.26 81.24,71.14 81.02,71.14 80.9,71.26 80.9,71.99 80.79,72.1 80.56,72.1 80.44,71.99 80.44,71.26 80.33,71.14 80.09,71.14 79.98,71.25 79.98,71.94 79.81,72.1 78.29,72.1 78.15,71.95 78.15,71.26 78.03,71.14 77.8,71.14 77.69,71.26 77.69,71.99 77.58,72.1 77.35,72.1 77.23,71.99 77.23,71.26 77.12,71.14 76.89,71.14 76.78,71.26 76.78,71.84 76.66,71.95 75.88,71.95 v2(75.77,72.06)
  BOTTOM w0.076: UC1.BA63 113.12,69.43 112.86,69.17 111.8,69.17 109.86,71.11 109.86,72.24 109.15,72.95 108.97,72.95 v2(107.81,74.11)
  BOTTOM w0.102: v2(75.77,72.06) 75.78,72.08 JDIMM1.59
DDR_A_D23: length 52
  IN1 w0.114: v2(108.39,74.11) 108.02,74.48 107.72,74.48 107.5,74.7 107.35,74.7 105.09,76.96 90.03,76.96 84.53,71.47 83.29,71.47 83.17,71.59 83.17,72.08 83.06,72.2 82.83,72.2 82.72,72.08 82.72,71.59 82.6,71.47 82.37,71.47 82.26,71.59 82.26,72.32 82.15,72.43 76.17,72.43 76.13,72.48 73.13,72.48 v2(72.72,72.06)
  BOTTOM w0.076: UC1.BB63 112.61,69.35 111.88,69.35 110.02,71.21 110.02,72.48 v2(108.39,74.11)
  BOTTOM w0.102: v2(72.72,72.06) 71.98,71.33 JDIMM1.62
DDR_A_D24: length 52.5
  IN1 w0.114: v2(108.04,71.98) 107.66,72.36 106.27,72.36 103.28,75.35 90.69,75.35 85.2,69.86 84.85,69.86 84.74,69.74 84.74,69.39 84.62,69.28 84.4,69.28 84.28,69.39 84.28,69.74 84.17,69.86 83.94,69.86 83.82,69.74 83.82,69.23 83.71,69.11 83.48,69.11 83.37,69.23 83.37,69.74 83.25,69.86 75.61,69.86 75.5,69.74 75.5,69.66 75.38,69.54 75.15,69.54 75.04,69.66 75.04,69.74 74.93,69.86 74.7,69.86 74.58,69.74 74.58,69.68 74.47,69.57 74.24,69.57 74.13,69.68 74.13,69.74 74.01,69.86 73.64,69.86 73.56,69.78 73.56,69.66 74.07,69.16 v2(74.24,69.16)
  BOTTOM w0.076: v2(108.04,71.98) 108.75,71.27 108.92,71.27 111.52,68.67 112.85,68.67 113.11,68.4 UC1.BA61
  BOTTOM w0.102: v2(74.24,69.16) 75.16,70.08 JDIMM1.67
DDR_A_D25: length 54.2
  IN1 w0.114: v2(109.24,71.98) 108.66,72.56 106.4,72.56 103.28,75.68 90.56,75.68 85.07,70.19 72.97,70.19 72.86,70.07 72.86,69.68 72.75,69.57 72.52,69.57 72.4,69.68 72.4,70.07 72.29,70.19 72.06,70.19 71.95,70.07 71.95,69.68 71.83,69.57 71.6,69.57 71.49,69.68 71.49,70.07 71.37,70.19 71.17,70.19 71.02,70.04 71.02,69.32 71.19,69.16 v2(71.19,69.16)
  BOTTOM w0.076: UC1.AW61 114.51,68.3 114.19,68.62 113.95,68.62 113.83,68.6 113.61,68.6 113.61,68.6 113.6,68.6 113.37,68.84 111.61,68.84 109.24,71.21 v2(109.24,71.98)
  BOTTOM w0.102: JDIMM1.70 71.03,69.33 71.19,69.16 v2(71.19,69.16)
DDR_A_D26: length 52.6
  IN1 w0.114: v2(74.24,65.86) 75.07,66.68 75.59,66.68 75.68,66.59 75.68,66.38 75.79,66.27 76.02,66.27 76.13,66.38 76.13,66.76 76.25,66.88 76.53,66.88 76.65,66.76 76.65,66.22 76.76,66.11 76.99,66.11 77.11,66.22 77.11,66.76 77.22,66.88 82.65,66.88 82.77,66.76 82.77,66.22 82.88,66.11 83.11,66.11 83.22,66.22 83.22,66.76 83.34,66.88 83.57,66.88 83.68,66.76 83.68,66.22 83.8,66.11 84.02,66.11 84.14,66.22 84.14,66.76 84.25,66.88 85.38,66.88 91.62,73.11 103.48,73.11 104.77,71.82 104.77,71.44 106.16,70.05 v2(106.28,70.05)
  BOTTOM w0.076: v2(106.28,70.05) 107.2,69.13 109.34,69.13 111.5,66.98 112.58,66.98 UC1.BB59
  BOTTOM w0.102: JDIMM1.79 75.46,67.08 v2(74.24,65.86)
DDR_A_D27: length 54.6
  IN1 w0.114: v2(71.2,65.86) 71.02,66.03 71.02,66.42 71.15,66.54 71.29,66.54 71.39,66.65 71.39,67.26 71.51,67.37 71.74,67.37 71.85,67.26 71.85,66.65 71.97,66.53 72.21,66.53 72.33,66.42 72.33,66.4 72.47,66.26 72.64,66.26 72.79,66.4 72.79,66.42 72.9,66.53 73.13,66.53 73.24,66.42 73.24,66.4 73.38,66.27 73.57,66.27 73.7,66.4 73.7,66.42 73.81,66.53 74.06,66.53 74.73,67.21 85.25,67.21 91.48,73.44 103.61,73.44 104.98,72.08 104.98,71.52 106.06,70.44 107.19,70.44 v2(107.58,70.05)
  BOTTOM w0.076: UC1.AW59 114.64,67.78 114.45,67.97 114.17,67.97 114.14,67.93 113.92,67.93 113.82,68.01 113.57,68.01 113.44,67.96 113.21,67.96 113.2,67.97 113.2,67.97 113.2,67.97 113.11,68.01 112.91,68.01 112.82,67.97 112.46,67.97 112.26,68.18 111.28,68.18 109.01,70.45 107.97,70.45 v2(107.58,70.05)
  BOTTOM w0.102: JDIMM1.84 71.16,65.83 v2(71.2,65.86)
DDR_A_D28: length 52
  IN1 w0.076: v2(107.36,71.98) 106.99,71.61 105.82,71.61 105.69,71.74 105.69,72.22 104.77,73.14
  IN1 w0.114: v2(72.72,69.16) 72.55,68.98 72.55,68.64 72.73,68.45 72.97,68.45 73.09,68.57 73.09,68.63 73.2,68.75 73.43,68.75 73.55,68.63 73.55,68.57 73.66,68.45 73.9,68.45 74.02,68.57 74.02,68.63 74.13,68.74 74.36,68.74 74.47,68.63 74.47,68.57 74.59,68.45 74.82,68.45 74.93,68.57 74.93,68.63 75.04,68.74 75.27,68.74 75.39,68.63 75.39,68.57 75.5,68.45 75.68,68.45 75.79,68.57 75.79,68.65 75.91,68.77 76.14,68.77 76.25,68.65 76.25,68.57 76.37,68.45 78.41,68.45 78.72,68.76 79.91,68.76 80.23,68.45 84.73,68.45 90.97,74.69 103.28,74.69 104.77,73.2 104.77,73.14
  BOTTOM w0.076: v2(107.36,71.98) 108.38,70.97 108.99,70.97 111.45,68.51 112.4,68.51 112.5,68.4 UC1.BB61
  BOTTOM w0.102: JDIMM1.66 71.55,70.33 v2(72.72,69.16)
DDR_A_D29: length 53.6
  IN1 w0.114: v2(106.12,71.97) 106.12,72.18 103.28,75.02 90.83,75.02 84.59,68.78 83.02,68.78 82.9,68.9 82.9,69.41 82.79,69.53 82.56,69.53 82.44,69.41 82.44,68.9 82.33,68.78 82.1,68.78 81.99,68.9 81.99,69.41 81.87,69.53 81.64,69.53 81.53,69.41 81.53,68.9 81.42,68.78 81.19,68.78 81.07,68.9 81.07,69.41 80.96,69.53 80.72,69.53 80.6,69.41 80.6,69 80.49,68.88 80.26,68.88 80.15,69 80.15,69.41 80.03,69.53 79.8,69.53 79.69,69.41 79.69,69.21 79.57,69.09 79.35,69.09 79.23,69.21 79.23,69.41 79.12,69.53 78.89,69.53 78.77,69.41 78.77,69.2 78.66,69.09 78.43,69.09 78.32,69.2 78.32,69.41 78.2,69.53 77.96,69.53 77.85,69.41 77.85,68.9 77.73,68.78 77.5,68.78 77.39,68.9 77.39,69.41 77.27,69.53 77.05,69.53 76.93,69.41 76.93,68.9 76.82,68.78 76.59,68.78 76.47,68.9 76.47,69.41 76.36,69.53 76.14,69.53 v2(75.77,69.16)
  BOTTOM w0.076: UC1.AY61 113.88,68.2 113.62,68.2 113.52,68.17 113.52,68.17 113.44,68.14 113.23,68.14 113.14,68.17 112.88,68.17 112.79,68.14 112.53,68.14 112.33,68.34 111.38,68.34 109.01,70.72 107.37,70.72 v2(106.12,71.97)
  BOTTOM w0.102: JDIMM1.71 75.85,69.08 v2(75.77,69.16)
DDR_A_D30: length 53.6
  IN1 w0.114: v2(75.77,65.86) 75.77,65.85 75.84,65.77 77.44,65.77 77.55,65.89 77.55,66.43 77.67,66.55 77.91,66.55 78.02,66.43 78.02,65.89 78.13,65.77 78.36,65.77 78.48,65.89 78.48,66.43 78.59,66.55 79.37,66.55 79.49,66.43 79.49,65.89 79.6,65.77 79.83,65.77 79.94,65.89 79.94,66.43 80.06,66.55 80.29,66.55 80.4,66.43 80.4,65.9 80.52,65.78 80.74,65.78 80.86,65.9 80.86,66.43 80.97,66.55 81.2,66.55 81.32,66.43 81.32,65.89 81.43,65.77 81.66,65.77 81.77,65.89 81.77,66.43 81.89,66.55 82.12,66.55 82.23,66.43 82.23,65.89 82.34,65.77 84.75,65.77 84.86,65.89 84.86,66.43 84.98,66.55 85.52,66.55 91.76,72.78 103.26,72.78 104.57,71.48 104.57,71.02 105.54,70.05 v2(105.63,70.05)
  BOTTOM w0.076: UC1.BA59 112.93,66.87 112.78,66.81 111.43,66.81 109.3,68.94 106.74,68.94 v2(105.63,70.05)
  BOTTOM w0.102: v2(75.77,65.86) 75.65,65.86 75.4,66.1 75.4,66.54 75.62,66.76 76.33,66.76 76.55,66.54 76.55,66.29 76.75,66.09 77.59,66.09 JDIMM1.83
DDR_A_D31: length 54.5
  IN1 w0.114: v2(72.72,65.86) 72.72,65.45 72.84,65.33 72.84,64.63 72.96,64.51 73.19,64.51 73.3,64.63 73.3,65.33 73.41,65.44 73.64,65.44 73.76,65.33 73.76,64.78 73.87,64.66 74.1,64.66 74.21,64.78 74.21,65.33 74.33,65.44 84.89,65.44 91.89,72.45 103.18,72.45 104.37,71.27 104.37,70.08 v2(104.34,70.05)
  BOTTOM w0.076: UC1.AY59 113.78,67.08 113.52,66.81 113.32,66.81 112.89,66.68 112.82,66.65 111.36,66.65 109.26,68.74 105.65,68.74 v2(104.34,70.05)
  BOTTOM w0.102: v2(72.72,65.86) 72.1,66.48 71.15,66.48 70.8,66.83 JDIMM1.80
DDR_A_D32: length 56.3
  IN1 w0.114: v2(72.67,41.53) 72.67,41.9 72.93,42.16 74.39,42.16 74.6,41.94 76.45,41.94 77.2,41.2 80.21,41.2 80.25,41.24 82.13,41.24 82.25,41.12 82.25,40.31 82.36,40.19 82.59,40.19 82.71,40.31 82.71,41.12 82.82,41.24 83.05,41.24 83.16,41.12 83.16,40.31 83.28,40.19 83.51,40.19 83.62,40.31 83.62,41.12 83.73,41.24 84.74,41.24 92.78,49.28 99.12,55.62 103.89,55.62 v2(104.13,55.39)
  BOTTOM w0.076: UC1.AY39 113.78,56.03 113.52,56.3 113.23,56.3 112.98,56.4 112.96,56.4 112.83,56.47 112.43,56.47 112.35,56.39 111.54,56.39 111.41,56.26 110.76,56.26 110.39,56.62 105.36,56.62 v2(104.13,55.39)
  BOTTOM w0.102: JDIMM1.174 70.44,41.33 70.65,41.11 72.25,41.11 v2(72.67,41.53)
DDR_A_D33: length 53.9
  IN1 w0.114: v2(71.14,41.53) 72.1,42.49 74.53,42.49 74.74,42.27 76.65,42.27 77.3,41.63 78.4,41.63 78.79,42.02 80.3,42.02 80.76,41.57 84.6,41.57 92.45,49.42 98.99,55.95 109.41,55.95 109.97,55.39 v2(110.09,55.39)
  BOTTOM w0.076: UC1.AW39 114.64,55.38 114.35,55.09 113.85,55.09 113.56,55.11 113.5,55.13 113.18,55.13 113.11,55.11 112.89,55.1 112.78,55.13 112.44,55.13 112.25,54.94 111.77,54.94 111.38,55.32 110.16,55.32 v2(110.09,55.39)
  BOTTOM w0.102: v2(71.14,41.53) 70.35,42.33 JDIMM1.170
DDR_A_D34: length 55.9
  IN1 w0.076: 101.63,53.72 102.33,53.72 102.94,54.33 109.22,54.33 109.44,54.54 v2(109.44,55.39)
  IN1 w0.114: v2(74.09,38.38) 73.84,38.38 73.72,38.51 73.72,38.83 73.83,38.94 75.64,38.94 76.29,38.29 77.47,38.29 77.59,38.4 77.59,38.72 77.7,38.83 77.93,38.83 78.05,38.72 78.05,38.4 78.16,38.29 78.39,38.29 78.5,38.4 78.5,38.49 78.62,38.6 78.85,38.6 78.96,38.49 78.96,38.4 79.07,38.29 84.48,38.29 99.91,53.72 101.63,53.72
  BOTTOM w0.076: UC1.AY37 113.88,54.91 113.63,54.91 113.48,54.96 113.24,54.96 113.08,54.92 112.96,54.92 112.76,54.96 112.51,54.96 112.32,54.77 111.67,54.77 111.43,55.02 109.81,55.02 v2(109.44,55.39)
  BOTTOM w0.102: JDIMM1.187 76.72,38.08 76.33,37.69 75.65,37.69 75.11,37.14 74.07,37.14 73.82,37.4 73.82,38.11 v2(74.09,38.38)
DDR_A_D35: length 56.1
  IN1 w0.076: v2(106.19,53.8) 106.26,53.73 106.26,53.4 106.11,53.25 102.73,53.25 102.21,52.73 101.63,52.73
  IN1 w0.114: 101.63,52.73 100.33,52.73 84.89,37.3 71.41,37.3 71.3,37.41 71.3,37.66 71.19,37.78 70.96,37.78 70.84,37.66 70.84,37.41 70.73,37.3 70.49,37.3 70.2,37.59 70.2,38.03 70.55,38.38 v2(71.04,38.38)
  BOTTOM w0.076: UC1.AW37 114.42,54.81 114.11,54.5 113.56,54.5 113.34,54.28 112.32,54.28 111.47,54.28 111.22,54.52 106.91,54.52 v2(106.19,53.8)
  BOTTOM w0.102: v2(71.04,38.38) 70.98,38.33 JDIMM1.186
DDR_A_D36: length 54.4
  IN1 w0.076: v2(106.19,55.39) 106.45,55.12 106.45,54.99 106.31,54.84 102.98,54.84
  IN1 w0.114: 102.98,54.84 102.86,54.96 99.4,54.96 83.97,39.53 80.04,39.53 79.39,40.19 76.43,40.19 75.91,40.7 74.74,40.7 74.63,40.82 74.63,41 74.52,41.12 74.29,41.12 74.17,41 74.17,40.82 74.06,40.7 72.93,40.7 72.83,40.8 72.83,40.99 72.95,41.12 73.6,41.12 74.01,41.53 v2(74.19,41.53)
  BOTTOM w0.076: UC1.BB39 112.66,56.06 111.68,56.06 111.55,55.93 110.62,55.93 110.32,56.23 107.04,56.23 v2(106.19,55.39)
  BOTTOM w0.102: JDIMM1.169 76.57,42.58 76.44,42.45 75.1,42.45 v2(74.19,41.53)
DDR_A_D37: length 54.6
  IN1 w0.076: 101.63,55.29 102.79,55.29 103.05,55.03 105.42,55.03 105.54,55.15 v2(105.54,55.39)
  IN1 w0.114: 101.63,55.29 99.26,55.29 84.66,40.69 84.49,40.69 84.27,40.9 84.11,40.9 83.95,40.74 83.95,40.58 84.17,40.36 84.17,40.2 83.83,39.86 82.03,39.86 81.92,39.98 81.92,40.78 81.79,40.91 81.56,40.91 81.45,40.79 81.45,39.98 81.33,39.86 81.1,39.86 80.99,39.98 80.99,40.82 80.9,40.91 80.67,40.91 80.56,40.79 80.56,39.95 80.47,39.86 80.23,39.86 80.09,40 80.09,40.39 79.97,40.52 79.5,40.52 79.38,40.63 79.38,40.75 79.27,40.87 79.04,40.87 78.93,40.75 78.93,40.63 78.81,40.52 78.58,40.52 78.47,40.63 78.47,40.75 78.35,40.87 78.13,40.87 78.01,40.75 78.01,40.63 77.9,40.52 77.67,40.52 77.55,40.63 77.55,40.75 77.44,40.87 77.21,40.87 77.1,40.75 77.1,40.63 76.98,40.52 76.79,40.52 76.61,40.7 76.38,40.7 76.19,40.89 76.19,41.16 76.29,41.27 76.42,41.27 76.48,41.33 76.48,41.45 76.32,41.61 75.8,41.61 v2(75.71,41.53)
  BOTTOM w0.076: UC1.BA39 113.19,56.03 113.05,56.18 113.04,56.18 113.04,56.18 112.79,56.3 112.5,56.3 112.42,56.22 111.61,56.22 111.48,56.09 110.69,56.09 110.36,56.42 106.58,56.42 v2(105.54,55.39)
  BOTTOM w0.102: JDIMM1.173 75.76,41.58 v2(75.71,41.53)
DDR_A_D38: length 55.1
  IN1 w0.076: 102.2,53.06 102.58,53.44 104.72,53.44 104.8,53.53 104.8,53.76 v2(104.76,53.8)
  IN1 w0.114: v2(72.56,38.38) 72.33,38.38 72.23,38.28 72.23,38.16 72.06,37.99 71.93,37.99 71.77,37.84 71.77,37.72 71.87,37.63 72.81,37.63 72.93,37.74 72.93,37.86 73.04,37.97 73.27,37.97 73.38,37.86 73.38,37.74 73.5,37.63 73.73,37.63 73.84,37.74 73.84,37.86 73.95,37.97 74.18,37.97 74.3,37.86 74.3,37.74 74.41,37.63 74.64,37.63 74.75,37.74 74.75,37.86 74.87,37.97 75.1,37.97 75.21,37.86 75.21,37.74 75.33,37.63 84.76,37.63 100.19,53.06 102.2,53.06
  BOTTOM w0.076: UC1.BA37 113.12,54.71 112.86,54.44 112.39,54.44 112.39,54.44 111.53,54.44 111.29,54.69 105.65,54.69 v2(104.76,53.8)
  BOTTOM w0.102: JDIMM1.182 71.62,39.33 v2(72.56,38.38)
DDR_A_D39: length 55.1
  IN1 w0.076: 101.63,53.39 102.3,53.39 103.07,54.16 104.04,54.16 104.11,54.1 104.11,53.85 v2(104.05,53.8)
  IN1 w0.114: v2(75.61,38.38) 75.53,38.3 75.53,38.16 75.73,37.96 84.62,37.96 100.05,53.39 101.63,53.39
  BOTTOM w0.076: v2(104.05,53.8) 103.86,53.8 103.47,54.19 103.47,54.8 103.66,54.99 109.61,54.99 109.74,54.85 111.36,54.85 111.6,54.61 112.39,54.61 112.49,54.71 UC1.BB37
  BOTTOM w0.102: v2(75.61,38.38) 75.42,38.38 75.02,38.79 73.95,38.79 73.75,38.98 73.75,39.56 73.87,39.67 74.42,39.67 74.52,39.57 74.52,39.4 74.63,39.3 74.83,39.3 74.93,39.4 74.93,39.57 75.03,39.67 75.35,39.67 75.46,39.57 75.46,39.02 75.56,38.92 75.76,38.92 75.86,39.02 75.86,39.33 75.97,39.43 76.36,39.43 76.71,39.08 JDIMM1.183
DDR_A_D40: length 55.2
  IN1 w0.076: v2(106.84,53.8) 106.98,53.8 107.22,53.56 107.22,53.21 107.01,53 102.71,53 101.65,51.94 101.16,51.94 100.99,52.11
  IN1 w0.114: 100.99,52.11 100.58,52.11 85.15,36.67 79.27,36.67 79.06,36.46 78.72,36.46 78.51,36.67 74.29,36.67 74.19,36.57 v2(74.19,36.26)
  BOTTOM w0.076: UC1.AY35 113.88,53.48 113.62,53.48 113.44,53.41 113.23,53.41 113.14,53.45 112.88,53.45 112.79,53.41 112.22,53.41 112.01,53.62 110.97,53.62 110.51,53.15 107.33,53.15 106.84,53.64 v2(106.84,53.8)
  BOTTOM w0.102: v2(74.19,36.26) 74,36.26 73.81,36.07 73.81,35.94 73.9,35.86 74.3,35.86 74.4,35.75 74.4,35.47 74.51,35.37 74.71,35.37 74.81,35.47 74.81,35.75 74.91,35.86 75.12,35.86 75.22,35.75 75.22,35.47 75.32,35.37 75.52,35.37 75.62,35.47 75.62,35.75 75.73,35.86 76.34,35.86 76.56,36.08 JDIMM1.195
DDR_A_D41: length 56
  IN1 w0.076: v2(108.14,53.8) 108.29,53.8 108.55,53.54 108.55,52.96 108.42,52.83 102.78,52.83 101.72,51.78 101.07,51.78
  IN1 w0.114: v2(75.71,36.26) 75.71,36.13 75.79,36.06 76.13,36.06 76.24,36.17 76.24,36.23 76.36,36.34 76.58,36.34 76.7,36.23 76.7,36.17 76.81,36.06 77.05,36.06 77.16,36.17 77.16,36.23 77.27,36.34 77.5,36.34 77.61,36.23 77.61,36.14 77.7,36.06 77.94,36.06 78.01,36.13 78.01,36.25 78.1,36.34 78.31,36.34 78.52,36.13 80.04,36.13 80.11,36.06 80.11,35.88 80.23,35.76 80.52,35.76 80.63,35.88 80.63,36.23 80.75,36.34 80.99,36.34 81.1,36.23 81.1,35.81 81.22,35.69 81.44,35.69 81.56,35.81 81.56,36.23 81.67,36.34 81.9,36.34 82.02,36.23 82.02,35.81 82.13,35.69 82.36,35.69 82.47,35.81 82.47,36.23 82.59,36.34 82.82,36.34 82.93,36.23 82.93,35.81 83.04,35.69 83.27,35.69 83.39,35.82 83.39,36.23 83.51,36.34 85.29,36.34 100.72,51.78 101.07,51.78
  BOTTOM w0.076: v2(108.14,53.8) 107.96,53.99 107.96,54.22 108.09,54.36 111.15,54.36 111.4,54.11 112.25,54.11 112.25,54.11 113.37,54.11 113.58,53.9 114.1,53.9 114.42,53.58 UC1.AW35
  BOTTOM w0.102: JDIMM1.191 75.91,37.08 75.47,36.64 75.47,36.51 v2(75.71,36.26)
DDR_A_D42: length 55.3
  IN1 w0.114: v2(74.19,33.4) 74.01,33.4 73.94,33.33 73.94,32.95 74.08,32.81 75.71,32.81 76.35,33.46 77.69,33.46 78.58,32.58 79.87,32.58 80.1,32.81 80.75,32.81 80.86,32.93 80.86,33.02 80.98,33.14 81.21,33.14 81.32,33.02 81.32,32.93 81.44,32.81 81.71,32.81 81.82,32.93 81.82,33.34 81.94,33.46 82.17,33.46 82.28,33.34 82.28,32.93 82.4,32.81 84.92,32.81 103.5,51.39 105.72,51.39 105.83,51.5 v2(105.83,51.77)
  BOTTOM w0.076: UC1.AY33 113.78,52.35 113.51,52.08 113.17,52.08 113.06,52.03 112.83,51.92 112.46,51.92 112.34,52.05 112.34,52.05 112.28,52.1 111.96,52.1 111.8,51.94 110.83,51.94 110.15,51.26 106.34,51.26 v2(105.83,51.77)
  BOTTOM w0.102: JDIMM1.207 75.95,33.08 75.88,33 74.6,33 v2(74.19,33.4)
DDR_A_D43: length 54.4
  IN1 w0.114: v2(75.71,33.4) 75.71,33.64 75.86,33.79 77.83,33.79 78.71,32.91 79.73,32.91 80.29,33.47 81.25,33.47 81.58,33.79 82.5,33.79 82.61,33.67 82.61,33.26 82.73,33.14 82.95,33.14 83.07,33.26 83.07,33.67 83.18,33.79 83.41,33.79 83.53,33.67 83.53,33.26 83.64,33.14 83.87,33.14 83.98,33.26 83.98,33.67 84.1,33.79 84.33,33.79 84.44,33.67 84.44,33.26 84.56,33.14 84.78,33.14 84.9,33.26 84.9,33.67 85.01,33.79 85.43,33.79 103.62,51.98 104.96,51.98 v2(105.18,51.77)
  BOTTOM w0.076: v2(105.18,51.77) 106.36,52.95 110.54,52.95 111.04,53.45 111.95,53.45 112.15,53.25 112.82,53.25 112.82,53.25 112.91,53.28 113.11,53.28 113.2,53.25 113.2,53.25 113.2,53.24 113.21,53.24 113.44,53.24 113.57,53.28 113.82,53.28 113.92,53.21 114.43,53.21 114.64,53.01 UC1.AW33
  BOTTOM w0.102: JDIMM1.203 76.39,34.08 v2(75.71,33.4)
DDR_A_D44: length 53.4
  IN1 w0.076: 101.12,51.24 101.65,51.24 102.92,52.5 110.07,52.5 110.33,52.76 110.33,53.56 v2(110.09,53.8)
  IN1 w0.114: v2(71.14,36.26) 71.09,36.26 70.83,36 70.83,35.68 71.07,35.45 72.79,35.45 72.84,35.4 79.15,35.4 79.51,35.03 84.91,35.03 101.12,51.24
  BOTTOM w0.076: UC1.BB35 112.58,53.78 112.12,53.78 112.12,53.78 110.11,53.78 v2(110.09,53.8)
  BOTTOM w0.102: JDIMM1.194 71.08,36.33 v2(71.14,36.26)
DDR_A_D45: length 54.5
  IN1 w0.076: v2(108.79,53.8) 108.99,53.6 108.99,52.95 108.71,52.67 102.85,52.67 101.63,51.45 101.15,51.45
  IN1 w0.114: 101.15,51.45 100.86,51.45 84.78,35.36 84.47,35.36 84.42,35.41 84.42,35.84 84.3,35.95 84.07,35.95 83.96,35.84 83.96,35.48 83.85,35.36 79.65,35.36 79.29,35.73 73.2,35.73 v2(72.67,36.26)
  BOTTOM w0.076: v2(108.79,53.8) 109.18,54.18 111.01,54.18 111.24,53.95 112.18,53.95 112.19,53.95 112.85,53.95 113.11,53.68 UC1.BA35
  BOTTOM w0.102: JDIMM1.190 71.6,37.33 v2(72.67,36.26)
DDR_A_D46: length 54
  IN1 w0.076: 101.63,48.59 101.63,48.79 102.19,49.35 102.19,49.58 103.65,51.04 109.01,51.04 v2(109.73,51.77)
  IN1 w0.114: v2(71.14,33.4) 72.39,32.15 75.98,32.15 76.37,32.54 77.67,32.54 78.3,31.92 80.16,31.92 80.39,32.15 85.19,32.15 90.48,37.44 101.63,48.59
  BOTTOM w0.076: UC1.BA33 113.19,52.35 113.05,52.21 113.04,52.21 113.04,52.21 112.79,52.09 112.53,52.09 112.35,52.26 111.89,52.26 111.75,52.12 110.08,52.12 v2(109.73,51.77)
  BOTTOM w0.102: JDIMM1.208 70.56,32.83 v2(71.14,33.4)
DDR_A_D47: length 53.1
  IN1 w0.076: 101.63,49.05 102.02,49.45 102.02,49.65 103.58,51.21 108.52,51.21 v2(109.08,51.77)
  IN1 w0.114: 101.63,49.05 85.06,32.48 80.25,32.48 80.02,32.25 78.44,32.25 77.81,32.87 76.24,32.87 75.84,32.48 72.95,32.48 72.67,32.77 v2(72.67,33.4)
  BOTTOM w0.076: v2(109.08,51.77) 109.6,52.29 111.68,52.29 111.82,52.43 112.46,52.43 112.54,52.35 UC1.BB33
  BOTTOM w0.102: v2(72.67,33.4) 72.24,33.83 JDIMM1.204
DDR_A_D48: length 57
  IN1 w0.076: v2(104.26,49.89) 104.26,49.55 104.17,49.46 102.96,49.46 102.68,49.18 102.68,48.03 101.63,46.98 101.63,46.77
  IN1 w0.114: v2(74.19,30.79) 74.01,30.79 73.75,30.53 73.75,30.53 73.6,30.38 73.4,30.38 73.3,30.28 73.3,30.16 73.38,30.08 74.23,30.08 74.34,30.2 74.34,30.36 74.46,30.47 74.69,30.47 74.8,30.36 74.8,30.2 74.91,30.08 75.14,30.08 75.26,30.2 75.26,30.28 75.37,30.39 75.6,30.39 75.71,30.28 75.71,30.2 75.83,30.08 75.96,30.08 76.17,30.29 76.33,30.29 76.54,30.08 77.3,30.08 77.37,30.16 77.37,30.3 77.44,30.37 85.22,30.37 92.02,37.17 101.63,46.77
  BOTTOM w0.076: v2(104.26,49.89) 105.36,51 111.09,51 111.41,51.31 112.29,51.31 112.46,51.48 112.82,51.48 113.23,51.32 113.52,51.32 113.78,51.05 UC1.AY31
  BOTTOM w0.102: JDIMM1.211 75.48,32.08 v2(74.19,30.79)
DDR_A_D49: length 57.3
  IN1 w0.076: v2(110.09,49.89) 109.53,50.45 103.47,50.45 102.35,49.33 102.35,48.43 102.05,48.12
  IN1 w0.114: v2(71.14,30.79) 71.14,31.23 71.4,31.49 71.8,31.49 71.87,31.42 71.87,31.31 71.99,31.19 72.22,31.19 72.33,31.31 72.33,31.42 72.44,31.53 72.67,31.53 72.79,31.42 72.79,31.29 72.9,31.17 73.13,31.17 73.24,31.29 73.24,31.42 73.36,31.53 73.59,31.53 73.7,31.42 73.7,31.29 73.82,31.17 74.05,31.17 74.16,31.29 74.16,31.39 74.3,31.53 76.24,31.53 76.63,31.92 77.42,31.92 78.25,31.09 80.21,31.09 80.65,31.53 85.45,31.53 91.11,37.19 102.05,48.12
  BOTTOM w0.076: v2(110.09,49.89) 110.12,49.86 112.01,49.86 112.3,50.16 112.83,50.16 112.86,50.15 112.94,50.11 113.06,50.11 113.28,50.18 113.42,50.18 113.57,50.12 113.83,50.12 113.85,50.14 114.42,50.14 114.64,50.36 UC1.AW31
  BOTTOM w0.102: JDIMM1.216 71.1,30.83 v2(71.14,30.79)
DDR_A_D50: length 56.3
  IN1 w0.076: 101.63,44.54 102.13,45.05 102.13,46.08 104.13,48.08 104.13,48.4 104.37,48.64 109,48.64 109.44,49.08 v2(109.44,49.89)
  IN1 w0.114: 101.63,44.54 101.45,44.36 93.6,36.51 93.6,36.51 85.88,28.79 78.48,28.79 78.38,28.69 78.38,28.23 78.26,28.11 78.02,28.11 77.91,28.23 77.91,28.39 77.79,28.51 77.56,28.51 77.45,28.39 77.45,28.23 77.33,28.11 77.11,28.11 76.99,28.23 76.99,28.39 76.88,28.51 76.65,28.51 76.53,28.39 76.53,28.22 76.42,28.1 75.73,28.1 75.73,28.1 74.17,28.1 74,27.93 v2(74,27.62)
  BOTTOM w0.076: v2(109.44,49.89) 109.44,49.89 109.83,49.49 110.31,49.49 110.51,49.7 112.08,49.7 112.37,49.99 112.79,49.99 112.91,49.94 113.05,49.94 113.28,50 113.41,50 113.63,49.93 113.88,49.93 UC1.AY29
  BOTTOM w0.102: JDIMM1.229 76.69,27.58 76.34,27.22 74.41,27.22 v2(74,27.62)
DDR_A_D51: length 56.8
  IN1 w0.076: 102.23,43.75 102.83,44.34 102.83,45.98 104.56,47.71 106.63,47.71 v2(107.21,48.29)
  IN1 w0.114: 102.23,43.75 94.59,36.1 85.6,27.11 76.54,27.11 76.31,26.88 70.93,26.88 70.77,27.05 70.77,27.44 v2(70.95,27.62)
  BOTTOM w0.076: UC1.AW29 114.42,49.83 114.3,49.71 114.3,49.69 114.12,49.51 113.95,49.51 113.83,49.53 113.58,49.53 113.34,49.3 112.39,49.3 112.3,49.2 110.73,49.2 110.53,49 107.92,49 v2(107.21,48.29)
  BOTTOM w0.102: JDIMM1.228 70.81,27.83 70.95,27.69 v2(70.95,27.62)
DDR_A_D52: length 55.2
  IN1 w0.076: v2(106.19,49.89) 106.19,50.16 106.11,50.24 103.5,50.24 102.51,49.26 102.51,48.13 101.63,47.24
  IN1 w0.114: v2(75.71,30.79) 75.8,30.7 76.13,30.7 76.23,30.79 76.23,31.1 76.34,31.22 76.48,31.22 76.61,31.09 76.61,30.48 76.67,30.41 76.9,30.41 77,30.51 77,31.42 77.11,31.53 77.34,31.53 77.45,31.42 77.45,30.88 77.63,30.7 80.83,30.7 80.95,30.81 80.95,31.09 81.06,31.2 81.29,31.2 81.4,31.09 81.4,30.81 81.52,30.7 81.75,30.7 81.86,30.81 81.86,31.09 81.98,31.2 82.2,31.2 82.32,31.09 82.32,30.81 82.43,30.7 82.66,30.7 82.78,30.81 82.78,31.09 82.89,31.2 83.12,31.2 83.23,31.09 83.23,30.81 83.35,30.7 83.58,30.7 83.69,30.81 83.69,31.09 83.8,31.2 84.01,31.2 84.1,31.11 84.1,30.79 84.2,30.7 84.39,30.7 84.47,30.78 84.47,31.12 84.55,31.2 84.71,31.2 84.8,31.11 84.8,30.79 84.87,30.73 85.12,30.73 85.25,30.86 85.25,31.14 85.31,31.2 85.59,31.2 91.69,37.3 101.63,47.24
  BOTTOM w0.076: UC1.BB31 112.61,50.98 111.54,50.98 111.23,50.67 106.97,50.67 v2(106.19,49.89)
  BOTTOM w0.102: JDIMM1.215 76,31.08 v2(75.71,30.79)
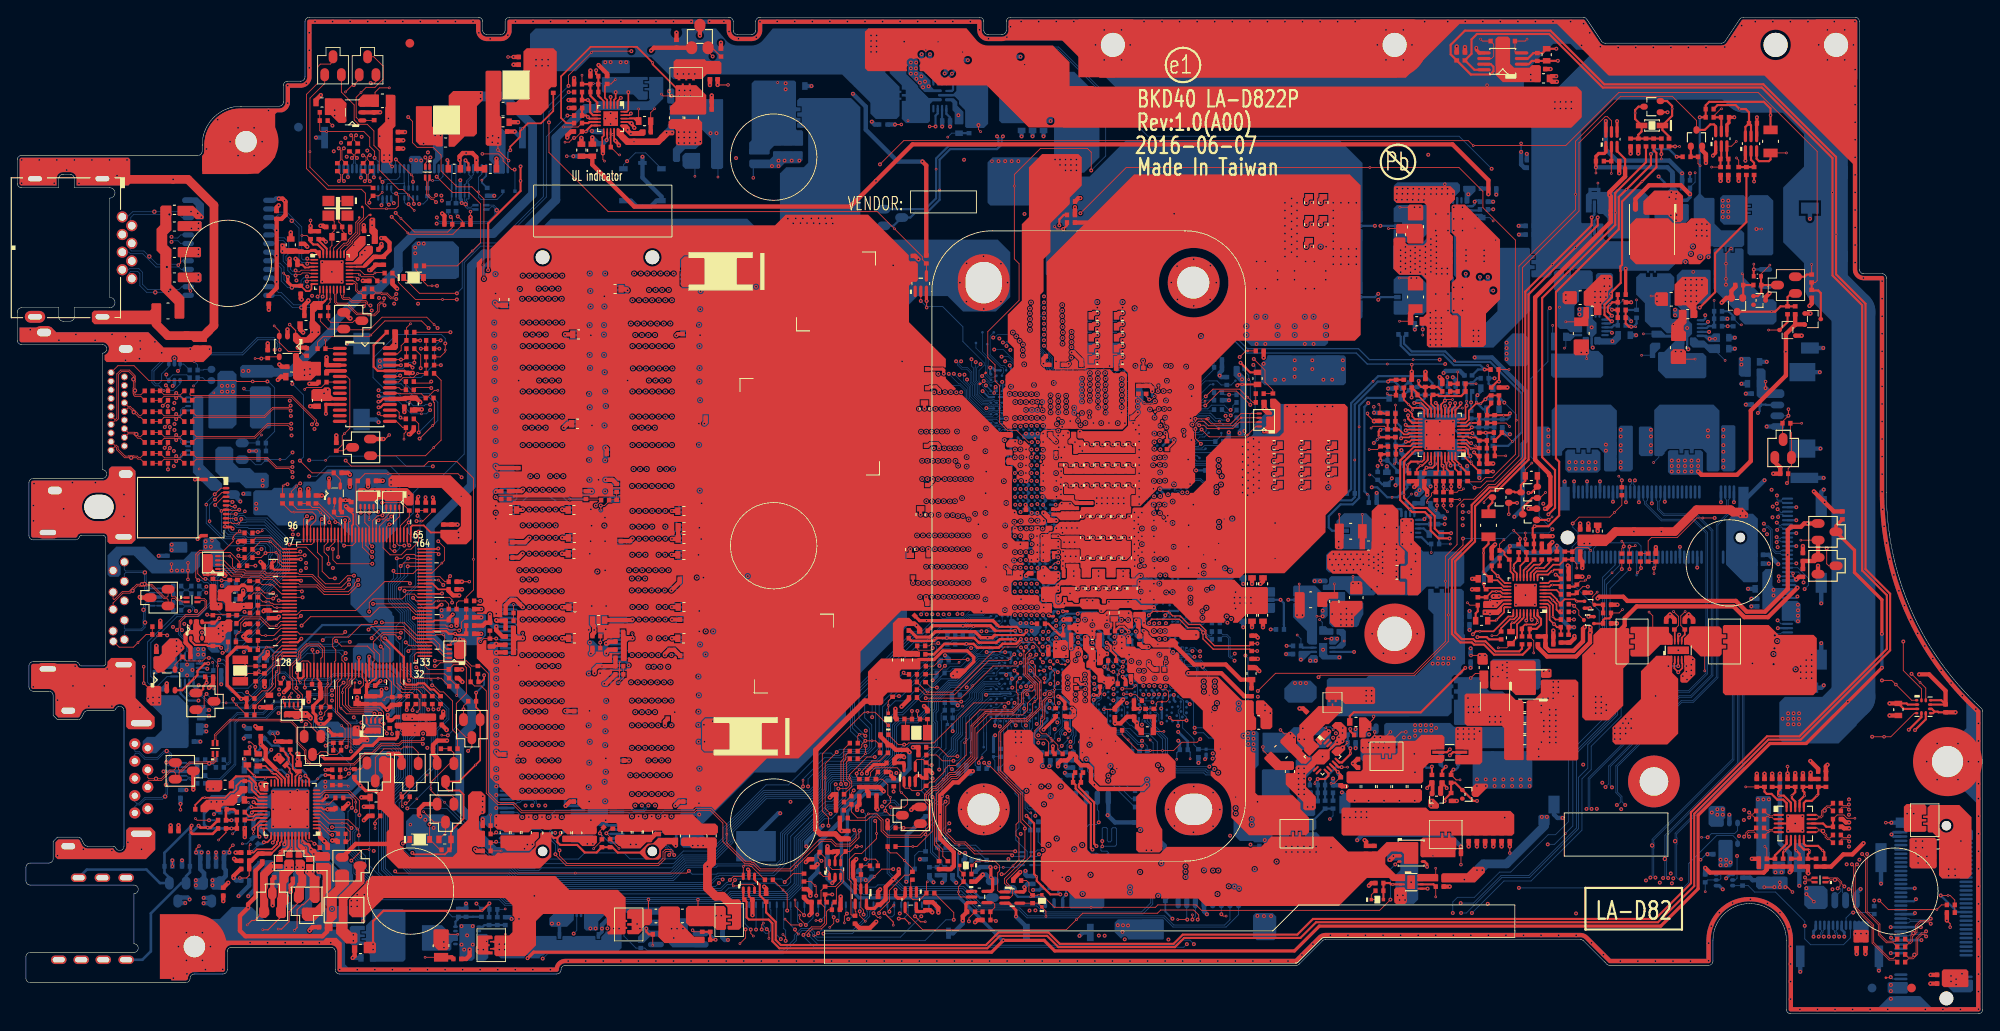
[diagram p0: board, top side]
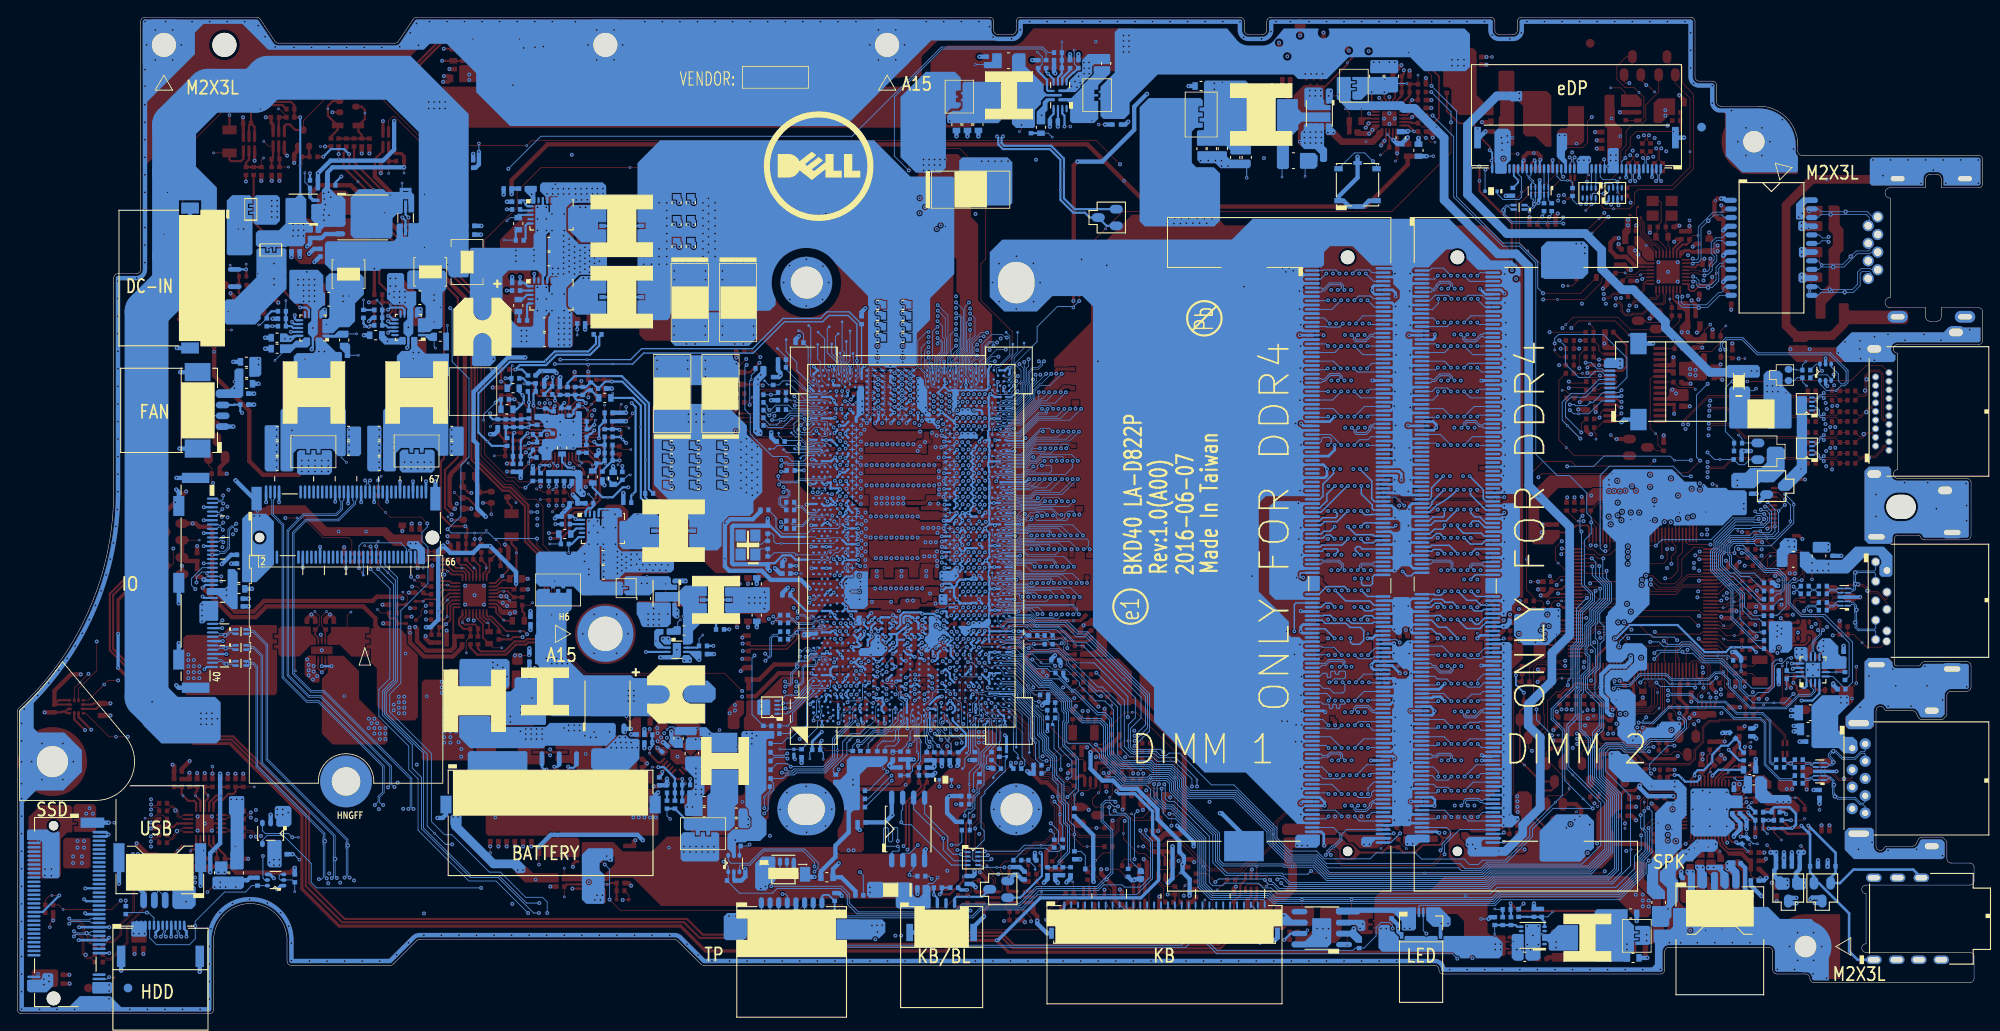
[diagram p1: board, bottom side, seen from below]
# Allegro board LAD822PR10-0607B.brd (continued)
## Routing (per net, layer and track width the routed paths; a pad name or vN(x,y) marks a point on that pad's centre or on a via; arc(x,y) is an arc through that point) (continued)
DDR_A_D53: length 56.4
  IN1 w0.076: 101.81,46.49 101.81,46.79 104.17,49.14 104.79,49.14 v2(105.54,49.89)
  IN1 w0.114: 101.81,46.49 92.35,37.03 92.35,37.03 85.36,30.04 77.72,30.04 77.44,29.75 73.01,29.75 72.93,29.84 72.93,30.11 72.81,30.22 72.61,30.22 72.48,30.09 72.48,29.84 72.39,29.75 72.1,29.75 71.91,29.94 71.91,30.21 72.49,30.79 v2(72.67,30.79)
  BOTTOM w0.076: v2(105.54,49.89) 106.48,50.83 111.16,50.83 111.47,51.15 112.36,51.15 112.53,51.32 112.79,51.32 113.04,51.2 113.04,51.2 113.05,51.19 113.19,51.05 UC1.BA31
  BOTTOM w0.102: JDIMM1.212 71.63,31.83 v2(72.67,30.79)
DDR_A_D54: length 56.2
  IN1 w0.076: v2(105.84,48.29) 105.43,47.87 104.49,47.87 102.66,46.05 102.66,44.65 101.77,43.75
  IN1 w0.114: v2(72.48,27.62) 72.89,27.21 76.17,27.21 76.4,27.44 83.33,27.44 83.45,27.56 83.45,27.62 83.56,27.73 83.79,27.73 83.9,27.62 83.9,27.56 84.02,27.44 84.25,27.44 84.36,27.56 84.36,28.01 84.47,28.12 84.7,28.12 84.82,28.01 84.82,27.56 84.93,27.44 85.46,27.44 94.26,36.24 94.26,36.24 101.77,43.75
  BOTTOM w0.076: v2(105.84,48.29) 106.72,49.16 110.46,49.16 110.66,49.37 112.21,49.37 112.3,49.46 112.84,49.46 113.11,49.73 UC1.BA29
  BOTTOM w0.102: v2(72.48,27.62) 71.28,28.83 JDIMM1.224
DDR_A_D55: length 54.9
  IN1 w0.076: v2(104.49,48.26) 104.49,48.2 102.41,46.13 102.41,44.86 101.63,44.08
  IN1 w0.114: v2(75.53,27.62) 75.83,27.62 75.98,27.77 79.24,27.77 79.37,27.9 79.37,28.34 79.5,28.46 79.69,28.46 79.81,28.34 79.81,27.84 79.89,27.77 80.12,27.77 80.23,27.89 80.23,28.35 80.35,28.46 80.58,28.46 80.69,28.35 80.69,27.89 80.81,27.77 81.03,27.77 81.15,27.89 81.15,28.33 81.28,28.46 81.51,28.46 81.62,28.35 81.62,27.87 81.72,27.77 81.95,27.77 82.06,27.89 82.06,28.35 82.18,28.46 82.41,28.46 82.52,28.35 82.52,27.89 82.63,27.77 82.86,27.77 82.98,27.89 82.98,28.35 83.09,28.46 83.32,28.46 83.42,28.37 83.42,28.18 83.53,28.06 83.78,28.06 83.85,28.13 83.85,28.34 83.95,28.45 86,28.45 93.93,36.38 101.63,44.08
  BOTTOM w0.076: UC1.BB29 112.34,49.73 112.14,49.53 110.59,49.53 110.39,49.33 105.56,49.33 v2(104.49,48.26)
  BOTTOM w0.102: JDIMM1.225 76.48,28.58 v2(75.53,27.62)
DDR_A_D56: length 59.2
  IN1 w0.076: v2(109.16,48.29) 108.17,47.3 104.68,47.3 103.32,45.95 103.32,43.75
  IN1 w0.114: 103.32,43.75 103.32,43.49 100.78,40.95 95.38,35.55 95.38,35.55 85.99,26.16 83.94,26.16 83.83,26.04 83.83,25.41 83.71,25.29 83.49,25.29 83.37,25.41 83.37,26.04 83.26,26.16 83.03,26.16 82.91,26.04 82.91,25.41 82.8,25.29 82.56,25.29 82.44,25.41 82.44,26.04 82.33,26.16 82.1,26.16 81.99,26.04 81.99,25.41 81.87,25.29 81.64,25.29 81.53,25.41 81.53,26.04 81.42,26.16 81.19,26.16 81.07,26.04 81.07,25.41 80.96,25.29 80.73,25.29 80.62,25.41 80.62,26.04 80.5,26.16 80.27,26.16 80.16,26.04 80.16,25.37 80.08,25.29 79.85,25.29 79.73,25.41 79.73,26.01 79.59,26.16 79.36,26.16 79.25,26.05 79.25,25.78 79.13,25.66 75.91,25.66 75.71,25.47 v2(75.71,25.44)
  BOTTOM w0.076: UC1.AY27 113.92,48.6 113.39,49.13 112.46,49.13 112.37,49.04 110.8,49.04 110.6,48.83 110.58,48.83 110.57,48.82 109.69,48.82 v2(109.16,48.29)
  BOTTOM w0.102: v2(75.71,25.44) 75.85,25.58 JDIMM1.237
DDR_A_D57: length 60.3
  IN1 w0.076: 102.99,43.75 102.99,45.85 104.64,47.49 107.06,47.49 v2(107.86,48.29)
  IN1 w0.114: v2(74.19,25.44) 74.01,25.44 73.43,26.02 73.43,26.16 73.54,26.26 74.27,26.26 74.39,26.15 74.39,25.92 74.46,25.84 74.77,25.84 74.84,25.92 74.84,26.15 74.96,26.26 75.19,26.26 75.3,26.15 75.3,25.98 75.41,25.86 75.64,25.86 75.76,25.98 75.76,26.15 75.87,26.26 76.57,26.26 76.8,26.49 76.91,26.49 77.03,26.37 77.03,26.11 77.14,25.99 77.37,25.99 77.48,26.11 77.48,26.37 77.6,26.49 77.83,26.49 77.94,26.37 77.94,26.11 78.06,25.99 78.28,25.99 78.4,26.11 78.4,26.37 78.51,26.49 85.86,26.49 95.05,35.68 95.05,35.69 102.99,43.63 102.99,43.75
  BOTTOM w0.076: v2(107.86,48.29) 108.39,47.76 110.77,47.76 110.9,47.88 111.25,47.88 111.46,48.1 111.46,48.41 111.58,48.52 112.32,48.52 112.4,48.44 113.75,48.44 113.9,48.29 114.42,48.29 114.64,48.51 UC1.AW27
  BOTTOM w0.102: JDIMM1.233 75.32,26.58 v2(74.19,25.44)
DDR_A_D58: length 59
  IN1 w0.076: v2(107.21,46.26) 106.68,46.78 104.4,46.78 103.51,45.9 103.51,43.21 103.41,43.11
  IN1 w0.114: 103.41,43.11 101.11,40.82 95.71,35.41 85.26,24.96 84.91,24.96 84.8,25.08 84.8,25.71 84.68,25.83 84.45,25.83 84.34,25.71 84.34,25.08 84.23,24.96 79.61,24.96 79.49,25.08 79.49,25.18 79.34,25.33 76.32,25.33 76.13,25.15 76.13,25.15 76.02,25.03 72.78,25.03 72.67,25.15 v2(72.67,25.44)
  BOTTOM w0.076: UC1.AY25 113.74,47.37 113.47,47.1 113.17,47.1 112.85,46.95 112.33,46.95 112.31,46.97 111.32,46.97 111.09,46.74 111.09,46.74 110.33,46.74 109.5,45.91 107.55,45.91 v2(107.21,46.26)
  BOTTOM w0.102: JDIMM1.236 70.52,25.83 70.74,25.61 70.74,25.28 70.97,25.04 72.26,25.04 v2(72.67,25.44)
DDR_A_D59: length 59.9
  IN1 w0.076: 103.41,42.64 103.67,42.91 103.67,45.83 104.47,46.62 106.19,46.62 v2(106.56,46.26)
  IN1 w0.114: v2(71.14,25.44) 71.09,25.39 71.09,24.89 71.34,24.63 76.82,24.63 76.93,24.75 76.93,24.89 77.05,25 77.28,25 77.39,24.89 77.39,24.75 77.51,24.63 77.73,24.63 77.85,24.75 77.85,24.89 77.96,25 79.1,25 79.47,24.63 85.4,24.63 96.04,35.27 96.04,35.27 101.44,40.68 103.41,42.64
  BOTTOM w0.076: v2(106.56,46.26) 107.07,45.74 109.57,45.74 110.08,46.26 111.73,46.26 111.99,46.51 112.9,46.51 112.94,46.47 113.3,46.47 113.41,46.58 113.41,46.8 113.69,47.08 114.17,47.08 114.46,47.37 UC1.AW25
  BOTTOM w0.102: JDIMM1.232 70.48,26.83 71.14,26.16 v2(71.14,25.44)
DDR_A_D60: length 57.3
  IN1 w0.114: v2(74.19,22.85) 74.13,22.8 74.13,22.47 74.28,22.33 83.42,22.33 83.54,22.45 83.54,22.94 83.65,23.06 83.88,23.06 83.99,22.94 83.99,22.45 84.11,22.33 84.34,22.33 84.45,22.45 84.45,22.94 84.56,23.06 84.79,23.06 84.91,22.94 84.91,22.45 85.02,22.33 85.33,22.33 97.78,34.78 97.78,34.78 101.75,38.75 102.89,38.75 103.61,39.47 103.61,41.21 108.44,46.03 108.44,46.44 109.04,47.05 109.87,47.05 v2(111.11,48.29)
  BOTTOM w0.076: UC1.BB27 111.52,48.7 v2(111.11,48.29)
  BOTTOM w0.102: JDIMM1.245 74.91,23.58 v2(74.19,22.85)
DDR_A_D61: length 57.6
  IN1 w0.114: v2(109.81,48.29) 108.23,46.71 108.23,46.12 103.41,41.29 103.41,39.73 102.75,39.08 101.61,39.08 97.45,34.92 97.45,34.92 85.92,23.39 83.2,23.39 83.09,23.27 83.09,22.78 82.98,22.66 82.75,22.66 82.63,22.78 82.63,23.27 82.52,23.39 82.29,23.39 82.18,23.27 82.18,22.78 82.06,22.66 81.83,22.66 81.72,22.78 81.72,23.27 81.6,23.39 81.38,23.39 81.26,23.27 81.26,22.78 81.15,22.66 80.92,22.66 80.8,22.78 80.8,23.27 80.69,23.39 80.46,23.39 80.35,23.27 80.35,22.78 80.23,22.66 80,22.66 79.89,22.78 79.89,23.07 79.78,23.18 79.55,23.18 79.43,23.07 79.43,22.78 79.32,22.66 78.66,22.66 78.55,22.78 78.55,22.85 78.43,22.97 78.2,22.97 78.09,22.85 78.09,22.78 77.97,22.66 77.75,22.66 77.63,22.78 77.63,22.85 77.52,22.97 77.29,22.97 77.17,22.85 77.17,22.78 77.06,22.66 76.83,22.66 76.72,22.78 76.72,22.85 76.6,22.97 76.37,22.97 76.26,22.85 76.26,22.78 76.15,22.66 75.9,22.66 v2(75.71,22.85)
  BOTTOM w0.076: v2(109.81,48.29) 110.17,48.65 110.64,48.65 110.65,48.67 110.66,48.67 110.87,48.87 112.44,48.87 112.53,48.97 112.85,48.97 113.11,48.7 UC1.BA27
  BOTTOM w0.102: JDIMM1.249 75.99,22.58 v2(75.71,22.85)
DDR_A_D62: length 58.3
  IN1 w0.114: v2(71.14,22.85) 71.14,21.85 71.28,21.71 71.66,21.71 71.74,21.79 71.74,22.33 71.85,22.44 72.08,22.44 72.19,22.33 72.19,21.79 72.31,21.67 85.6,21.67 98.44,34.5 98.44,34.51 102.02,38.09 103.16,38.09 104.02,38.94 104.02,40.96 109.34,46.29 v2(109.38,46.29)
  BOTTOM w0.076: UC1.BA25 113.19,47.37 113.04,47.22 112.82,47.12 112.4,47.12 112.38,47.13 111.25,47.13 111.02,46.9 109.99,46.9 v2(109.38,46.29)
  BOTTOM w0.102: v2(71.14,22.85) 70.67,23.33 JDIMM1.246
DDR_A_D63: length 56.8
  IN1 w0.114: v2(72.67,22.85) 72.67,22.16 72.83,22 73.07,22 73.18,22.12 73.18,22.33 73.3,22.44 73.53,22.44 73.64,22.33 73.64,22.12 73.75,22 85.47,22 98.11,34.64 98.11,34.64 101.88,38.42 103.03,38.42 103.81,39.21 103.81,41.12 108.81,46.12 v2(108.81,46.29)
  BOTTOM w0.076: UC1.BB25 112.49,47.37 112.42,47.3 111.18,47.3 110.95,47.07 109.32,47.07 108.81,46.56 v2(108.81,46.29)
  BOTTOM w0.102: JDIMM1.250 72.14,22.33 v2(72.67,22.85)
DDR_A_DQS0: length 69.2
  IN1 w0.076: 117.72,83.5 117.72,83.48 117.74,83.46 117.74,83.02 117.88,82.89 117.88,81.42 118.5,80.81 118.66,80.81 118.82,80.64 v2(118.82,80.54)
  IN1 w0.114: v2(74.64,83.82) 74.27,84.19 74.27,84.27 74.37,84.37 79.84,84.37 79.96,84.26 79.96,83.99 80.19,83.75 80.7,83.75 80.93,83.99 80.93,84.26 81.05,84.37 81.39,84.37 81.5,84.26 81.5,84.05 81.74,83.82 82.25,83.82 82.48,84.05 82.48,84.26 82.6,84.37 84.36,84.37 86.08,86.09 104.64,86.09 108.46,89.91 113.89,89.91 116.78,87.02 116.78,84.44 117.72,83.5
  BOTTOM w0.076: UC1.AM69 118.94,73.21 119.25,73.53 119.25,74 119.3,74.08 119.3,74.3 119.24,74.41 119.24,74.67 119.32,74.75 119.32,75.53 118.78,76.08 118.78,76.58 118.3,77.06 118.3,80.61 118.46,80.77 118.68,80.77 118.82,80.62 v2(118.82,80.54)
  BOTTOM w0.102: JDIMM1.13 76.58,83.58 76.43,83.72 76.2,83.72 75.49,84.43 74.36,84.43 74.21,84.28 74.21,84.05 74.45,83.82 v2(74.64,83.82)
DDR_A_DQS1: length 57
  IN1 w0.076: v2(114.07,77.74) 114.18,77.63 114.3,77.63 114.46,77.79 114.46,77.9 113.14,79.23 112.62,79.23 112.6,79.21 112.58,79.21
  IN1 w0.114: v2(73.05,78.61) 72.76,78.9 72.76,79.04 72.83,79.12 74.19,79.12 74.37,78.94 74.37,78.9 74.6,78.67 75.11,78.67 75.35,78.9 75.35,78.94 75.46,79.05 85.47,79.05 88.08,81.66 107.29,81.66 109.74,79.21 112.58,79.21
  BOTTOM w0.076: v2(114.07,77.74) 114.4,77.74 114.51,77.86 115,77.86 115.56,77.3 115.56,76.15 116.09,75.62 116.09,75.03 116.26,74.87 116.26,74.64 116.26,74.38 116.21,74.24 116.21,74.14 116.26,74.01 116.26,73.73 116.22,73.65 116.22,73.43 116.28,73.3 116.35,73.24 116.43,73.24 116.49,73.3 116.49,73.33 UC1.AT70
  BOTTOM w0.102: JDIMM1.34 70.42,78.33 70.57,78.47 70.78,78.47 71.43,77.82 72.58,77.82 72.83,78.07 72.83,78.39 v2(73.05,78.61)
DDR_A_DQS2: length 52.8
  IN1 w0.076: 106.94,76.39 108.37,74.95 108.75,74.95 108.91,75.11 108.91,75.31 109.15,75.56 v2(109.23,75.56)
  IN1 w0.114: v2(74.63,73.33) 74.62,73.33 74.45,73.33 74.13,73.65 74.13,73.72 74.25,73.83 77.77,73.83 77.98,73.62 85.48,73.62 89.67,77.81 105.51,77.81 106.94,76.39
  BOTTOM w0.076: UC1.AY64 114.1,70.19 113.77,70.53 113.52,70.53 113.44,70.49 113.23,70.49 113.12,70.55 112.9,70.55 112.79,70.49 112.55,70.49 112.36,70.68 111.72,70.68 110.77,71.63 110.77,72.83 110.47,73.13 110.47,74.33 109.97,74.84 109.37,74.84 108.99,75.22 108.99,75.45 109.09,75.56 v2(109.23,75.56)
  BOTTOM w0.102: JDIMM1.55 76.58,73.08 76.43,73.22 76.17,73.22 75.48,73.91 74.5,73.91 74.35,73.76 74.35,73.61 v2(74.63,73.33)
DDR_A_DQS3: length 53.9
  IN1 w0.076: 104.6,73.04 105.38,72.26 105.38,71.62 106.03,70.96 108.21,70.96 108.61,70.56 108.61,70.32 v2(108.88,70.05)
  IN1 w0.114: v2(73.02,67.87) 72.92,67.87 72.69,67.64 72.69,67.52 72.95,67.26 73.75,67.26 74.43,67.93 84.95,67.93 91.18,74.17 103.46,74.17 104.6,73.04
  BOTTOM w0.076: v2(108.88,70.05) 108.85,70.05 108.85,70.05 108.73,70.05 108.4,69.72 108.4,69.65 108.45,69.61 109.33,69.61 111.59,67.35 112.3,67.35 112.46,67.51 112.82,67.51 112.83,67.51 112.86,67.49 112.94,67.46 113.08,67.46 113.08,67.46 113.1,67.47 113.13,67.5 113.64,67.5 113.71,67.57 113.71,67.69 UC1.BA60
  BOTTOM w0.102: v2(73.02,67.87) 72.75,67.6 72.75,67.33 72.51,67.09 71.32,67.09 70.81,67.6 70.81,67.87 70.71,67.97 70.57,67.97 70.42,67.83 JDIMM1.76
DDR_A_DQS4: length 55.3
  IN1 w0.076: v2(107.49,55.39) 107.68,55.39 107.81,55.26 107.81,54.82 107.65,54.66 102.8,54.66 102.58,54.44 101.64,54.44 101.64,54.44
  IN1 w0.114: v2(74.43,40.18) 74.23,40.18 74.02,39.97 74.02,39.77 74.12,39.66 76.2,39.66 76.44,39.43 76.44,39.16 76.55,39.05 76.89,39.05 77.01,39.16 77.01,39.43 77.24,39.66 79.17,39.66 79.82,39.01 84.18,39.01 99.61,54.44 101.64,54.44
  BOTTOM w0.076: UC1.AY38 114.1,55.63 114.1,55.64 114.05,55.67 113.91,55.76 113.8,55.8 113.52,55.8 113.44,55.77 113.23,55.77 113.12,55.82 112.9,55.82 112.79,55.77 112.38,55.77 112.26,55.89 111.79,55.89 111.66,55.76 110.56,55.76 110.3,56.01 107.98,56.01 107.81,55.84 107.81,55.51 107.69,55.39 v2(107.49,55.39)
  BOTTOM w0.102: v2(74.43,40.18) 74.25,40.18 74.03,40.4 74.03,40.71 74.13,40.81 75.58,40.81 76.03,40.36 76.46,40.36 76.75,40.08 JDIMM1.179
DDR_A_DQS5: length 55
  IN1 w0.076: v2(107.13,51.77) 107.26,51.9 107.26,52.04 107.13,52.17 103.36,52.17 102.2,51.01 102.2,50.98 102.09,50.87 102.04,50.87 102.02,50.85 102.01,50.85
  IN1 w0.114: 102.01,50.85 101.76,50.85 85.21,34.31 73.08,34.31 72.46,34.93 v2(72.29,34.93)
  BOTTOM w0.076: UC1.BA34 113.87,53.02 113.93,52.95 113.93,52.87 113.91,52.83 113.83,52.78 113.77,52.75 113.55,52.75 113.47,52.79 113.2,52.79 113.07,52.73 112.96,52.73 112.94,52.73 112.83,52.79 111.71,52.79 111.58,52.65 107.61,52.65 107.25,52.29 107.25,51.89 v2(107.13,51.77)
  BOTTOM w0.102: JDIMM1.200 70.31,34.83 70.39,34.91 70.64,34.91 71.18,35.46 72.43,35.46 72.58,35.3 72.58,35.1 72.41,34.93 v2(72.29,34.93)
DDR_A_DQS6: length 56.4
  IN1 w0.076: 101.63,45.57 101.65,45.59 101.67,45.59 101.8,45.71 101.8,46.22 102,46.41 102,46.74 104.23,48.97 107.45,48.97 107.98,49.5 107.98,49.55 107.8,49.73 107.8,49.78 107.78,49.81 107.78,49.89 107.65,50.01 107.55,50.01 107.49,49.95 v2(107.49,49.89)
  IN1 w0.114: v2(74.57,29.34) 74.46,29.23 74.29,29.23 74.07,29.02 74.07,28.95 74.2,28.82 75.54,28.82 75.95,29.23 77.65,29.23 77.94,29.52 85.58,29.52 92.87,36.81 101.63,45.57
  BOTTOM w0.076: UC1.AY30 114.14,50.66 114.11,50.69 113.83,50.82 113.52,50.82 113.44,50.79 113.23,50.79 113.12,50.84 112.9,50.84 112.79,50.79 112.18,50.79 112.15,50.82 111.61,50.82 111.24,50.45 107.86,50.45 107.69,50.28 107.69,50.08 v2(107.49,49.89)
  BOTTOM w0.102: JDIMM1.221 76.58,29.58 76.43,29.72 75.78,29.72 75.42,30.08 74.42,30.08 74.3,29.95 74.3,29.61 v2(74.57,29.34)
DDR_A_DQS7: length 59.4
  IN1 w0.076: 103.3,41.8 104.51,43 104.51,45.16 104.98,45.63 104.98,46.04 104.75,46.26 v2(104.61,46.26)
  IN1 w0.114: v2(73.05,24.11) 72.91,24.11 72.75,23.95 72.75,23.81 72.86,23.69 79.03,23.69 79.45,24.11 85.62,24.11 96.72,35.22 96.72,35.22 103.3,41.8
  BOTTOM w0.076: v2(104.61,46.26) 104.68,46.26 104.76,46.33 104.76,46.88 105.28,47.4 110.82,47.4 111.05,47.63 112.25,47.63 112.43,47.8 112.82,47.8 112.96,47.75 113.07,47.75 113.2,47.8 113.47,47.8 113.55,47.77 113.77,47.77 113.83,47.8 113.91,47.85 113.93,47.89 113.93,47.97 113.87,48.04 UC1.BA26
  BOTTOM w0.102: v2(73.05,24.11) 73.02,24.11 72.77,23.86 72.77,23.64 72.54,23.42 71.34,23.42 70.74,24.01 70.74,24.23 70.55,24.42 70.41,24.42 70.31,24.33 JDIMM1.242
DDR_A_DQS#0: length 69.2
  IN1 w0.076: v2(118.82,81.12) 118.72,81.02 118.52,81.02 118.05,81.49 118.05,82.95 117.91,83.09 117.91,83.46 117.93,83.48 117.93,83.5
  IN1 w0.114: 117.93,83.5 117.93,83.58 116.99,84.52 116.99,87.1 113.98,90.11 108.38,90.11 104.56,86.3 85.99,86.3 84.27,84.58 82.51,84.58 82.28,84.34 82.28,84.13 82.16,84.02 81.82,84.02 81.71,84.13 81.71,84.34 81.47,84.58 80.96,84.58 80.73,84.34 80.73,84.07 80.62,83.96 80.27,83.96 80.16,84.07 80.16,84.34 79.93,84.58 74.29,84.58 74.07,84.36 74.07,84.01 v2(73.88,83.82)
  BOTTOM w0.076: v2(118.82,81.12) 118.63,80.93 118.39,80.93 118.13,80.68 118.13,76.99 118.61,76.51 118.61,76.01 119.16,75.46 119.16,74.82 119.08,74.74 119.08,74.38 119.13,74.24 119.13,74.14 119.08,74.01 119.08,73.58 118.96,73.47 118.9,73.47 118.85,73.52 UC1.AM70
  BOTTOM w0.102: v2(73.88,83.82) 74,83.94 74,84.37 74.27,84.64 75.58,84.64 76.29,83.93 76.43,83.93 76.58,84.08 JDIMM1.11
DDR_A_DQS#1: length 57
  IN1 w0.076: v2(114.49,77.33) 114.49,77.58 114.63,77.72 114.63,77.97 113.2,79.39 112.62,79.39 112.6,79.41 112.58,79.41
  IN1 w0.114: v2(72.29,78.61) 72.56,78.87 72.56,79.13 72.75,79.32 74.27,79.32 74.57,79.02 74.57,78.99 74.69,78.87 75.03,78.87 75.14,78.99 75.14,79.02 75.38,79.26 85.38,79.26 87.99,81.86 107.37,81.86 109.83,79.41 112.58,79.41
  BOTTOM w0.076: UC1.AT69 116.33,73.05 116.31,73.05 116.28,73.07 116.28,73.07 116.15,73.21 116.06,73.39 116.06,73.68 116.09,73.76 116.09,73.97 116.04,74.08 116.04,74.3 116.09,74.41 116.09,74.8 115.93,74.97 115.93,75.55 115.39,76.08 115.39,77.23 114.93,77.69 114.58,77.69 114.49,77.59 v2(114.49,77.33)
  BOTTOM w0.102: JDIMM1.32 70.42,78.83 70.57,78.68 70.87,78.68 71.52,78.04 72.49,78.04 72.61,78.16 72.61,78.28 v2(72.29,78.61)
DDR_A_DQS#2: length 52.7
  IN1 w0.076: 107.23,76.39 107.25,76.37 107.25,76.35 107.23,76.33 108.44,75.12 108.68,75.12 108.74,75.18 108.74,75.47 v2(108.65,75.56)
  IN1 w0.114: 107.23,76.39 105.6,78.02 89.59,78.02 85.4,73.83 78.06,73.83 77.85,74.04 74.16,74.04 73.93,73.8 73.93,73.4 v2(73.86,73.33)
  BOTTOM w0.076: UC1.BA64 113.76,70.1 113.84,70.17 113.84,70.23 113.7,70.36 113.55,70.36 113.47,70.33 113.2,70.33 113.07,70.38 112.96,70.38 112.94,70.38 112.83,70.33 112.71,70.33 112.71,70.33 112.48,70.33 112.29,70.51 111.62,70.51 110.58,71.55 110.58,72.76 110.28,73.05 110.28,74.25 109.89,74.65 109.29,74.65 108.82,75.12 108.82,75.38 v2(108.65,75.56)
  BOTTOM w0.102: JDIMM1.53 76.58,73.58 76.43,73.43 76.26,73.43 75.57,74.13 74.41,74.13 74.14,73.85 74.14,73.61 v2(73.86,73.33)
DDR_A_DQS#3: length 53.9
  IN1 w0.076: 104.5,72.85 104.55,72.85 105.21,72.19 105.21,71.55 105.96,70.8 108.14,70.8 108.44,70.49 108.44,70.26 v2(108.23,70.05)
  IN1 w0.114: v2(72.26,67.87) 72.48,67.65 72.48,67.43 72.86,67.05 73.84,67.05 74.51,67.73 85.03,67.73 91.27,73.97 103.38,73.97 104.5,72.85
  BOTTOM w0.076: UC1.AY60 114.02,67.64 113.71,67.33 113.2,67.33 113.18,67.32 113.15,67.29 113.1,67.29 113.07,67.28 113.03,67.29 112.9,67.29 112.79,67.34 112.79,67.34 112.53,67.34 112.37,67.18 111.52,67.18 109.27,69.44 108.38,69.44 108.23,69.59 v2(108.23,70.05)
  BOTTOM w0.102: JDIMM1.74 70.42,68.33 70.57,68.18 70.8,68.18 71.03,67.96 71.03,67.69 71.41,67.31 72.42,67.31 72.54,67.42 72.54,67.6 v2(72.26,67.87)
DDR_A_DQS#4: length 55.3
  IN1 w0.076: 101.64,54.24 101.65,54.24 101.67,54.26 101.71,54.26 101.73,54.27 102.65,54.27 102.87,54.49 107.72,54.49 107.97,54.75 107.97,55.22 v2(108.14,55.39)
  IN1 w0.114: 101.64,54.24 99.7,54.24 84.27,38.81 79.74,38.81 79.08,39.46 77.33,39.46 77.21,39.35 77.21,39.08 76.98,38.85 76.47,38.85 76.23,39.08 76.23,39.35 76.12,39.46 74.04,39.46 73.82,39.68 73.82,40.03 v2(73.67,40.18)
  BOTTOM w0.076: v2(108.14,55.39) 107.97,55.56 107.97,55.77 108.05,55.85 110.24,55.85 110.49,55.6 111.73,55.6 111.86,55.73 112.19,55.73 112.31,55.6 112.82,55.6 112.96,55.66 113.07,55.66 113.2,55.6 113.47,55.6 113.55,55.64 113.77,55.64 113.83,55.61 113.91,55.56 113.99,55.5 114.02,55.48 114.02,55.41 114.02,55.41 114.02,55.33 113.95,55.29 113.84,55.29 UC1.BA38
  BOTTOM w0.102: JDIMM1.177 76.12,40.58 75.67,41.03 74.04,41.03 73.81,40.8 73.81,40.33 v2(73.67,40.18)
DDR_A_DQS#5: length 55.1
  IN1 w0.076: v2(107.78,51.77) 107.62,51.77 107.43,51.96 107.43,52.11 107.2,52.33 103.29,52.33 102.01,51.06
  IN1 w0.114: 102.01,51.06 101.67,51.06 85.13,34.51 73.21,34.51 73.05,34.67 v2(73.05,34.93)
  BOTTOM w0.076: UC1.AY34 114.18,52.92 114.1,52.84 114.07,52.76 114.05,52.71 113.91,52.63 113.8,52.58 113.52,52.58 113.44,52.62 113.23,52.62 113.12,52.57 112.9,52.57 112.79,52.62 111.88,52.62 111.78,52.62 111.64,52.49 107.68,52.49 107.41,52.22 107.41,52.06 107.71,51.77 v2(107.78,51.77)
  BOTTOM w0.102: JDIMM1.198 70.21,35.33 70.41,35.13 70.55,35.13 71.09,35.67 72.52,35.67 72.8,35.39 72.8,35.1 72.97,34.93 v2(73.05,34.93)
DDR_A_DQS#6: length 56.5
  IN1 w0.076: v2(108.14,49.89) 108.14,49.43 107.52,48.81 104.3,48.81 102.16,46.67 102.16,46.35 101.97,46.15 101.97,45.64 101.79,45.47 101.79,45.44 101.78,45.43
  IN1 w0.114: 101.78,45.43 93.08,36.73 93.08,36.73 85.66,29.31 78.02,29.31 77.74,29.03 76.03,29.03 75.62,28.62 74.02,28.62 73.81,28.83 v2(73.81,29.34)
  BOTTOM w0.076: v2(108.14,49.89) 108.01,49.89 107.87,50.03 107.87,50.2 107.93,50.26 111.24,50.26 111.26,50.28 111.31,50.28 111.52,50.49 111.68,50.65 112.08,50.65 112.11,50.62 112.83,50.62 112.94,50.67 112.96,50.67 113.07,50.67 113.2,50.62 113.47,50.62 113.55,50.66 113.77,50.66 113.83,50.63 113.95,50.56 113.99,50.52 113.99,50.43 113.91,50.35 113.84,50.34 UC1.BA30
  BOTTOM w0.102: JDIMM1.219 76.58,30.08 76.43,29.93 75.87,29.93 75.51,30.3 74.33,30.3 74.08,30.04 74.08,29.61 v2(73.81,29.34)
DDR_A_DQS#7: length 59.4
  IN1 w0.076: v2(105.26,46.26) 105.14,46.14 105.14,45.56 104.67,45.09 104.67,42.93 103.49,41.75 103.49,41.72 103.45,41.69 103.45,41.66 103.45,41.65
  IN1 w0.114: 103.45,41.65 96.92,35.13 96.92,35.13 85.7,23.91 79.54,23.91 79.12,23.49 72.78,23.49 72.55,23.72 72.55,23.85 v2(72.29,24.11)
  BOTTOM w0.076: UC1.AY26 114.12,47.94 114.1,47.92 114.1,47.86 114.05,47.73 113.91,47.65 113.8,47.6 113.52,47.6 113.44,47.64 113.23,47.64 113.12,47.59 112.9,47.59 112.79,47.64 112.5,47.64 112.32,47.46 111.11,47.46 110.88,47.23 105.35,47.23 104.92,46.81 104.92,46.49 105.16,46.26 v2(105.26,46.26)
  BOTTOM w0.102: v2(72.29,24.11) 72.55,23.84 72.55,23.73 72.45,23.63 71.43,23.63 70.96,24.1 70.96,24.32 70.64,24.63 70.49,24.63 70.29,24.83 JDIMM1.240
DDR_A_MA0: length 52.3
  IN1 w0.076: v2(114.18,61.67) 113.81,61.3 103.72,61.3
  IN1 w0.183: v2(71.89,50.4) 72.36,49.93 79.47,49.93 79.76,50.22 84.87,50.22 96.35,61.7 103.33,61.7 103.72,61.3
  BOTTOM w0.076: UC1.AY50 113.99,61.86 v2(114.18,61.67)
  BOTTOM w0.17: JDIMM1.144 70.39,50.83 70.62,50.59 70.62,49.82 70.85,49.59 71.69,49.59 71.89,49.79 v2(71.89,50.4)
DDR_A_MA1: length 52.6
  IN1 w0.076: 103.44,64.1 104.37,63.17 108.89,63.17 108.99,63.27 108.99,63.43 108.96,63.47 v2(108.89,63.47)
  IN1 w0.183: 103.44,64.1 102.68,64.86 95.04,64.86 84.71,54.53 84.37,54.53 84.19,54.71 84.19,54.92 84.06,55.05 83.78,55.05 83.63,54.9 83.63,54.71 83.45,54.53 83.08,54.53 82.9,54.71 82.9,54.87 82.71,55.05 82.35,55.05 82.17,54.87 82.17,54.71 81.98,54.53 81.57,54.53 81.43,54.67 81.43,54.87 81.25,55.05 80.89,55.05 80.7,54.87 80.7,54.7 80.54,54.53 80,54.53 79.53,54.06 77.41,54.06 76.95,53.6 75.44,53.6 v2(74.99,53.15)
  BOTTOM w0.076: UC1.BB50 112.5,62.12 112.48,62.1 111.11,62.1 110.59,62.62 107.96,62.62 107.75,62.83 107.75,63.35 107.87,63.47 v2(108.89,63.47)
  BOTTOM w0.17: v2(74.99,53.15) 74.61,53.53 74.61,53.7 74.74,53.83 76.21,53.83 76.46,53.58 JDIMM1.133
DDR_A_MA2: length 53.4
  IN1 w0.076: 103.42,63.57 103.98,63 109.51,63 v2(109.88,63.37)
  IN1 w0.183: v2(71.94,53.15) 71.94,52.86 72.1,52.7 76.71,52.7 77.58,53.58 79.7,53.58 80.19,54.07 84.9,54.07 95.23,64.4 102.59,64.4 103.42,63.57
  BOTTOM w0.076: UC1.AY51 114.1,62.54 113.86,62.54 113.75,62.51 113.55,62.51 113.5,62.54 113.18,62.54 113.06,62.51 112.94,62.51 112.83,62.55 112.48,62.55 112.35,62.43 111.29,62.43 110.71,63.01 110.24,63.01 v2(109.88,63.37)
  BOTTOM w0.17: JDIMM1.132 71.83,53.83 72.1,54.1 72.42,54.1 72.61,53.91 72.61,53.68 72.08,53.15 v2(71.94,53.15)
DDR_A_MA3: length 53.9
  IN1 w0.076: v2(105.33,64.03) 104.96,63.66 104.59,63.66 104.3,63.95 104.3,64.64 104.11,64.83
  IN1 w0.183: 104.11,64.83 103.63,65.31 102.69,66.25 94.46,66.25 84.65,56.44 83.94,56.44 83.76,56.61 83.76,57.03 83.37,57.42 81.05,57.42 80.64,57.01 80.64,56.62 80.46,56.44 79.41,56.44 79.12,56.72 78.75,56.72 77.93,55.9 77.05,55.9 76.65,55.5 73.57,55.5 73.48,55.42 v2(73.48,55.02)
  BOTTOM w0.076: v2(105.33,64.03) 105.33,63.29 106.17,62.45 110.49,62.45 111.08,61.87 112.93,61.87 113.19,62.12 UC1.BA50
  BOTTOM w0.17: JDIMM1.131 76.66,54.08 76.46,54.28 74.15,54.28 73.48,54.95 v2(73.48,55.02)
DDR_A_MA4: length 52.4
  IN1 w0.076: v2(104.72,64.03) 104.72,64.75 102.87,66.6
  IN1 w0.183: v2(71.96,55.01) 71.96,55.73 72.19,55.96 76.46,55.96 76.86,56.36 77.74,56.36 78.56,57.19 80.04,57.19 80.73,57.88 84,57.88 84.17,57.72 84.17,57.27 84.29,57.15 84.71,57.15 84.83,57.27 84.83,57.63 85.02,57.82 85.38,57.82 94.27,66.71 102.76,66.71 102.87,66.6
  BOTTOM w0.076: v2(104.72,64.03) 105.26,64.57 105.43,64.74 109.01,64.74 109.65,64.11 110.31,64.11 110.85,63.56 112.57,63.56 UC1.BB52
  BOTTOM w0.17: JDIMM1.128 70.23,54.83 70.53,54.53 71.56,54.53 71.96,54.93 v2(71.96,55.01)
DDR_A_MA5: length 54.8
  IN1 w0.076: v2(107.16,64.03) 107.27,64.03 107.64,64.41 107.64,64.6 107.55,64.69 105.48,64.69 102.92,67.26 102.92,67.32
  IN1 w0.183: v2(73.48,56.41) 72.99,56.9 72.99,57.17 73.14,57.32 77.39,57.32 78.18,58.11 79.48,58.11 81.07,59.7 84.88,59.7 84.99,59.59 84.99,59.4 85.15,59.24 85.37,59.24 85.5,59.37 85.5,59.62 85.63,59.75 86,59.75 93.89,67.63 102.61,67.63 102.92,67.32
  BOTTOM w0.076: UC1.BA51 113.44,63.01 113.21,63.01 113.2,63.01 113.2,63.02 113.2,63.02 113.11,63.05 112.91,63.05 112.82,63.02 112.46,63.02 112.25,63.23 110.63,63.23 110.11,63.75 109.5,63.75 108.85,64.4 107.25,64.4 107.16,64.31 v2(107.16,64.03)
  BOTTOM w0.17: v2(73.48,56.41) 72.56,55.48 70.58,55.48 70.42,55.33 JDIMM1.126
DDR_A_MA6: length 52.3
  IN1 w0.076: v2(109.88,64.46) 109.8,64.39 108.43,64.39 108.18,64.13 108.18,63.93 107.74,63.5 104.52,63.5 104.08,63.94 104.08,64.48
  IN1 w0.183: 104.08,64.48 102.77,65.78 94.65,65.78 84.84,55.97 83.58,55.97 83.3,56.25 83.3,56.84 83.18,56.96 82.69,56.96 82.57,56.84 82.57,56.16 82.39,55.97 82.02,55.97 81.84,56.16 81.84,56.82 81.7,56.96 81.24,56.96 81.11,56.82 81.11,56.18 80.9,55.97 79.27,55.97 78.28,54.99 77.88,54.99 77.79,55.08 77.79,55.26 77.6,55.44 77.24,55.44 77.06,55.26 77.06,55.17 76.87,54.99 76.4,54.99 75.93,54.52 75.04,54.52 74.9,54.67 74.9,54.9 v2(75.01,55.01)
  BOTTOM w0.076: UC1.BA52 113.11,63.45 112.83,63.73 110.92,63.73 110.19,64.46 v2(109.88,64.46)
  BOTTOM w0.17: v2(75.01,55.01) 75.08,55.01 75.5,55.43 76,55.43 76.35,55.08 JDIMM1.127
DDR_A_MA7: length 56.4
  IN1 w0.076: v2(107.29,65.48) 106.93,65.83 105.67,65.83 103.81,67.69 103.81,68.17 102.49,69.49
  IN1 w0.183: 102.49,69.49 93.12,69.49 85.24,61.6 80.35,61.6 79.77,61.02 77.66,61.02 77.13,60.49 77.06,60.49 76.77,60.21 71.61,60.21 v2(67.94,56.54)
  BOTTOM w0.076: UC1.AW52 114.45,63.35 114.12,63.67 113.58,63.67 113.35,63.89 110.99,63.89 109.96,64.92 107.85,64.92 v2(107.29,65.48)
  BOTTOM w0.17: v2(67.94,56.54) 68.16,56.33 JDIMM1.122
DDR_A_MA8: length 54
  IN1 w0.076: v2(106.55,64.03) 106.67,64.03 106.86,64.21 106.86,64.43 106.76,64.53 105.33,64.53 102.99,66.87
  IN1 w0.183: v2(75.01,56.41) 74.96,56.46 74.96,56.7 75.11,56.86 77.58,56.86 78.37,57.65 79.85,57.65 80.54,58.34 80.89,58.34 81.08,58.53 81.08,59.06 81.26,59.24 81.62,59.24 81.81,59.06 81.81,58.53 81.99,58.34 82.36,58.34 82.54,58.53 82.54,59.01 82.77,59.24 83.04,59.24 83.27,59.01 83.27,58.53 83.45,58.34 83.76,58.34 83.95,58.53 83.95,59.06 84.13,59.24 84.49,59.24 84.68,59.06 84.68,58.53 84.86,58.34 85.25,58.34 94.08,67.17 102.68,67.17 102.99,66.87
  BOTTOM w0.076: UC1.AY52 113.62,63.25 113.44,63.18 113.23,63.18 113.14,63.22 112.88,63.22 112.79,63.18 112.55,63.18 112.33,63.4 110.75,63.4 110.22,63.93 109.57,63.93 108.94,64.56 106.55,64.56 106.42,64.44 106.42,64.16 v2(106.55,64.03)
  BOTTOM w0.17: v2(75.01,56.41) 75.54,55.88 76.25,55.88 76.55,55.58 JDIMM1.125
DDR_A_MA9: length 52.2
  IN1 w0.076: v2(106.07,65.48) 105.48,65.48 103.58,67.38 103.58,68.09 102.64,69.02
  IN1 w0.183: 102.64,69.02 93.31,69.02 85.43,61.14 80.54,61.14 79.43,60.03 77.25,60.03 76.96,59.75 74.19,59.75 73.48,59.03 v2(73.48,58.23)
  BOTTOM w0.076: UC1.BB54 112.44,64.48 112.4,64.44 111.15,64.44 109.62,65.96 105.94,65.96 105.83,65.85 105.83,65.72 v2(106.07,65.48)
  BOTTOM w0.17: v2(73.48,58.23) 74.72,56.99 76.18,56.99 76.6,56.58 JDIMM1.121
DDR_A_MA10: length 54.1
  IN1 w0.076: v2(116.16,62.61) 115.81,62.97 115.31,62.97 114.65,62.32 114.65,61.64 114.09,61.08 103.56,61.08
  IN1 w0.183: 103.56,61.08 103.4,61.23 96.54,61.23 85.07,49.76 79.95,49.76 79.66,49.47 72.34,49.47 v2(71.89,49.02)
  BOTTOM w0.076: UC1.AT50 116.45,62.33 v2(116.16,62.61)
  BOTTOM w0.17: v2(71.89,49.02) 71.2,48.33 70.62,48.33 70.62,48.33 JDIMM1.146
DDR_A_MA11: length 52.7
  IN1 w0.076: 102.55,68.1 103.15,67.5 103.15,67.25 105.54,64.87 109.09,64.87 109.29,65.07 109.29,65.3 v2(109.12,65.48)
  IN1 w0.183: v2(71.96,56.41) 71.66,56.71 71.66,57.27 72.16,57.78 77.19,57.78 77.99,58.57 79.28,58.57 80.92,60.21 85.81,60.21 93.7,68.1 102.55,68.1
  BOTTOM w0.076: v2(109.12,65.48) 109.87,65.48 111.13,64.22 112.87,64.22 113.12,64.48 UC1.BA54
  BOTTOM w0.17: v2(71.96,56.41) 71.52,56.85 70.29,56.85 70.27,56.83 JDIMM1.120
DDR_A_MA12: length 54
  IN1 w0.076: 102.61,68.56 103.34,67.83 103.34,67.38 105.68,65.05 108.28,65.05 108.51,65.27 v2(108.51,65.48)
  IN1 w0.183: 102.61,68.56 93.5,68.56 85.62,60.67 80.73,60.67 79.62,59.57 78.91,59.57 78.75,59.42 78.75,59.18 78.63,59.05 78.24,59.05 78.06,59.23 78.06,59.45 77.94,59.57 77.57,59.57 77.31,59.3 77.09,59.3 76.91,59.12 76.91,58.43 76.73,58.24 76.36,58.24 76.18,58.43 76.18,59.1 76,59.28 74.89,59.28 74.7,59.1 74.7,58.53 v2(75.01,58.23)
  BOTTOM w0.076: v2(108.51,65.48) 108.51,65.25 108.66,65.1 110.02,65.1 111.06,64.06 113.36,64.06 113.56,64.27 114.11,64.27 114.42,64.58 UC1.AW54
  BOTTOM w0.17: v2(75.01,58.23) 74.71,57.94 74.71,57.63 74.9,57.44 76.4,57.44 76.77,57.08 JDIMM1.119
DDR_A_MA13: length 56.6
  IN1 w0.076: v2(115.48,59.84) 114.49,59.84 113,58.35 104.47,58.35 104.11,58 103.66,58
  IN1 w0.183: 103.66,58 98.14,58 86.02,45.88 80.11,45.88 79.5,45.27 78.6,45.27 77.72,44.38 74.12,44.38 74.1,44.4 72.42,44.4 72.23,44.59 72.23,44.95 72.48,45.2 73.04,45.2 v2(73.48,45.65)
  BOTTOM w0.076: UC1.AU46 115.47,59.99 115.47,59.85 v2(115.48,59.84)
  BOTTOM w0.17: JDIMM1.158 70.52,45.33 70.64,45.21 73.04,45.21 v2(73.48,45.65)
DDR_A_ODT0: length 57.4
  IN1 w0.076: 103.69,58.46 104.13,58.46 104.19,58.52 112.93,58.52 114.84,60.42 115.56,60.42 v2(116.12,59.86)
  IN1 w0.183: v2(75.01,45.65) 74.88,45.65 74.42,45.19 74.42,44.95 74.53,44.85 76.05,44.85 76.2,45 76.2,45.53 76.4,45.73 76.74,45.73 76.93,45.55 76.93,45.03 77.11,44.85 77.53,44.85 77.71,45.03 77.71,45.55 77.89,45.73 79.31,45.73 79.91,46.34 80.97,46.34 81.15,46.52 81.15,46.8 81.34,46.99 81.7,46.99 81.89,46.8 81.89,46.47 82.02,46.34 82.51,46.34 82.62,46.45 82.62,46.83 82.77,46.99 83.21,46.99 83.35,46.85 83.35,46.47 83.48,46.34 83.97,46.34 84.08,46.45 84.08,46.84 84.23,46.99 84.67,46.99 84.81,46.85 84.81,46.47 84.94,46.34 85.57,46.34 97.69,58.46 103.69,58.46
  BOTTOM w0.076: UC1.AT45 116.12,59.74 v2(116.12,59.86)
  BOTTOM w0.17: JDIMM1.155 76.34,46.08 76.26,46.15 75.5,46.15 v2(75.01,45.65)
DDR_A_ODT1: length 59.7
  IN1 w0.076: v2(116.11,58.11) 115.69,57.68 114.34,57.68 112.75,56.1 109.91,56.1 109.4,56.61 108.8,56.61
  IN1 w0.183: 108.8,56.61 98.72,56.61 86.6,44.49 85.8,44.49 85.57,44.27 85.57,43.47 84.33,42.22 82.53,42.22 82.35,42.41 82.35,43.08 82.18,43.24 81.82,43.24 81.63,43.06 81.63,42.43 81.43,42.22 81.07,42.22 80.88,42.41 80.88,43.64 80.7,43.81 80.29,43.81 80.11,43.63 80.11,43.03 79.96,42.88 79.62,42.88 79.43,43.06 79.43,43.57 79.25,43.75 78.57,43.75 78.38,43.56 78.38,42.54 78.13,42.29 77.76,42.29 77.58,42.47 77.58,43.28 77.39,43.46 76.36,43.46 76.2,43.3 76.2,43.11 76.02,42.93 75.01,42.93 74.83,43.11 74.83,43.3 v2(75.01,43.47)
  BOTTOM w0.076: v2(116.11,58.11) 116.14,58.11 116.45,58.42 UC1.AT43
  BOTTOM w0.17: JDIMM1.161 76.11,44.58 v2(75.01,43.47)
DDR_A_PAR: length 52.5
  IN1 w0.076: 103.76,61.65 103.76,61.58 103.77,61.57 112.78,61.57 114.35,63.13 115.72,63.13 v2(116.1,63.52)
  IN1 w0.183: 103.76,61.65 103.25,62.16 96.16,62.16 85.05,51.05 84.8,51.05 84.69,51.16 84.69,51.65 84.51,51.83 84.14,51.83 83.9,51.58 83.9,50.87 83.71,50.68 83.35,50.68 83.16,50.87 83.16,51.71 83.05,51.83 82.71,51.83 82.48,51.61 82.48,50.87 82.3,50.68 81.94,50.68 81.75,50.87 81.75,51.71 81.63,51.83 81.29,51.83 81.05,51.59 81.05,50.99 80.75,50.68 80.02,50.68 79.57,51.14 78.5,51.14 78.3,50.94 78.3,50.63 78.42,50.51 v2(78.64,50.51)
  BOTTOM w0.076: v2(116.1,63.52) UC1.AT52
  BOTTOM w0.17: JDIMM1.143 78.93,51.08 79,51.01 79,50.58 78.93,50.51 v2(78.64,50.51)
DDR_A_RAS#: length 53.2
  IN1 w0.076: v2(115.44,61.74) 115.44,61.73 113.64,59.93 109.64,59.93 109.31,60.26 106.59,60.26
  IN1 w0.183: 106.59,60.26 104.17,60.26 103.76,59.85 97.11,59.85 85.64,48.37 80.76,48.37 80.14,47.75 78.11,47.75 77.91,47.55 72.41,47.55 v2(71.96,47.11)
  BOTTOM w0.076: UC1.AU50 115.44,61.79 v2(115.44,61.74)
  BOTTOM w0.17: v2(71.96,47.11) 71.52,46.66 70.67,46.66 70.51,46.83 JDIMM1.152
DDR_A_WE#: length 51.5
  IN1 w0.076: 107.98,59.99 108.57,59.99 109.19,59.37 113.31,59.37 115.08,61.13 115.75,61.13 v2(116.1,60.78)
  IN1 w0.183: v2(75.01,47.11) 75.45,46.66 78.31,46.66 78.94,47.29 80.33,47.29 80.95,47.91 85.83,47.91 97.31,59.38 104.04,59.38 104.64,59.99 107.98,59.99
  BOTTOM w0.076: v2(116.1,60.78) UC1.AT46
  BOTTOM w0.17: JDIMM1.151 76.55,47.08 76.08,47.55 75.45,47.55 v2(75.01,47.11)
DDR_B_ACT#: length 67.4
  IN3 w0.076: v2(118.01,64.44) 117.62,64.83 114.27,64.83
  IN3 w0.175: v2(59.28,60.68) 60.41,61.81 63.38,61.81 63.64,62.07 63.64,62.16 64.21,62.73 68.58,62.73 70.29,64.43 76.26,64.43 77.17,65.35 78.16,65.35 78.56,64.95 79.73,64.95 80.38,65.59 80.79,65.59 82.29,67.09 103.66,67.09 104.04,66.71 109.8,66.71 110.84,65.67 112.52,65.67 113.35,64.83 114.27,64.83
  BOTTOM w0.076: v2(118.01,64.44) UC1.AN53
  BOTTOM w0.17: JDIMM2.114 57.49,58.33 59.28,60.12 v2(59.28,60.68)
DDR_B_ALERT#: length 80.1
  IN3 w0.175: v2(55.37,58.02) 56.16,58.81 56.16,60.42 60.21,64.47 64.08,64.47 64.18,64.57 68.38,64.57 70.11,66.3 76.2,66.3 76.85,66.96 80.23,66.96 81.72,68.45 110.37,68.45 111.98,66.85 115.06,66.85 115.22,66.68 118.99,66.68 119.24,66.43 119.24,59.86 118.82,59.43 118.47,59.43 v2(118.06,59.02)
  BOTTOM w0.102: UC1.AN43 v2(118.06,59.02)
  BOTTOM w0.17: JDIMM2.116 55.57,57.83 v2(55.37,58.02)
DDR_B_BG0: length 67.5
  IN3 w0.076: 114.65,63.88 117.02,63.88 v2(117.37,63.52)
  IN3 w0.175: v2(60.81,60.68) 60.42,60.29 60.42,59.94 60.61,59.75 61.45,59.75 61.94,60.24 63.94,60.24 64.65,60.95 65.68,60.95 66.11,61.39 68.53,61.39 70.66,63.52 76.63,63.52 77.15,64.04 80.57,64.04 82.72,66.18 105.34,66.18 105.38,66.15 109.62,66.15 111.52,64.25 113.19,64.25 113.56,63.88 114.65,63.88
  BOTTOM w0.076: UC1.AP52 117.45,63.06 117.37,63.14 v2(117.37,63.52)
  BOTTOM w0.17: JDIMM2.115 64.01,58.08 63.18,58.91 62.44,59.31 61.72,59.82 61.23,60.26 v2(60.81,60.68)
DDR_B_BG1: length 67.5
  IN3 w0.076: 114.9,64.14 114.96,64.08 117.92,64.08 118.01,63.99 v2(118.01,63.52)
  IN3 w0.175: v2(62.33,60.68) 62.07,60.94 62.07,61.15 62.28,61.36 63.23,61.36 63.4,61.19 63.4,61 63.57,60.83 63.89,60.83 64.22,61.16 64.22,62.1 64.4,62.28 64.75,62.28 64.92,62.1 64.92,61.58 65.1,61.41 65.49,61.41 65.69,61.61 65.69,62.1 65.87,62.28 68.77,62.28 70.47,63.98 76.45,63.98 77.36,64.89 77.97,64.89 78.37,64.49 80.21,64.49 80.38,64.67 80.38,64.96 80.57,65.14 81.03,65.14 82.53,66.64 103.57,66.64 103.76,66.44 109.69,66.44 111.63,64.51 113.3,64.51 113.67,64.14 114.9,64.14
  BOTTOM w0.076: v2(118.01,63.52) 118.4,63.13 UC1.AN52
  BOTTOM w0.17: v2(62.33,60.68) 63.75,59.26 63.75,58.98 64.15,58.58 JDIMM2.113
DDR_B_BS0: length 66.6
  IN3 w0.076: v2(105.2,59.36) 104.5,59.36 103.56,58.42
  IN3 w0.175: 103.56,58.42 103.02,58.42 102.16,57.56 93.09,57.56 92.85,57.32 92.85,56.85 91.87,55.87 87.77,55.87 82.85,50.95 82.24,50.95 82.06,50.78 82.06,50.44 81.88,50.27 81.53,50.27 81.36,50.44 81.36,50.78 81.18,50.95 80.73,50.95 80.56,50.78 80.56,50.44 80.38,50.27 80.03,50.27 79.86,50.44 79.86,50.78 79.68,50.95 76.45,50.95 76.17,50.67 76.17,50.16 75.96,49.96 75.55,49.96 75.38,50.14 75.38,50.31 75.22,50.47 74.87,50.47 74.68,50.27 74.68,50.14 74.5,49.96 74.15,49.96 73.98,50.14 73.98,50.29 73.8,50.47 73.45,50.47 73.28,50.29 73.28,50.14 73.1,49.96 70.8,49.96 70.32,49.48 64.4,49.48 64.24,49.64 64.24,50.05 64.03,50.26 63.5,50.26 63.06,49.83 60.82,49.83 60.48,49.49 60.48,49.16 v2(60.72,48.92)
  BOTTOM w0.076: v2(105.2,59.36) 105.8,58.76 109.11,58.76 109.19,58.84 111.24,58.84 111.34,58.74 112.58,58.74 UC1.BB44
  BOTTOM w0.17: v2(60.72,48.92) 59.67,47.88 58.62,47.88 58.07,47.33 JDIMM2.150
DDR_B_BS1: length 66.9
  IN3 w0.076: 103.22,58.15 103.7,58.15 104.39,58.85 106.71,58.85 v2(107.22,59.36)
  IN3 w0.175: v2(62.24,48.92) 62.24,49.13 62.49,49.37 63.86,49.37 64.21,49.03 70.51,49.03 70.99,49.51 76.15,49.51 76.62,49.97 76.62,50.29 76.83,50.5 78.06,50.5 78.24,50.32 78.24,49.99 78.42,49.81 80.88,49.81 81.05,49.64 81.05,49.48 81.23,49.31 81.85,49.31 82.2,49.66 82.2,49.94 82.76,50.5 83.04,50.5 86,53.46 86.25,53.46 86.48,53.22 86.73,53.22 86.98,53.47 86.98,53.72 86.74,53.95 86.74,54.2 86.96,54.42 87.21,54.42 87.51,54.12 87.87,54.12 88.04,54.29 88.04,55.18 88.28,55.42 88.64,55.42 88.81,55.24 88.81,54.29 88.99,54.12 89.34,54.12 89.51,54.29 89.51,55.24 89.69,55.42 90.04,55.42 90.21,55.24 90.21,54.29 90.39,54.12 90.74,54.12 90.92,54.29 90.92,55.24 91.09,55.42 92.06,55.42 93.75,57.11 102.08,57.11 103.13,58.15 103.22,58.15
  BOTTOM w0.076: UC1.BA44 113.07,58.9 111.41,58.9 111.32,59 109.06,59 109.01,58.95 107.4,58.95 107.22,59.13 v2(107.22,59.36)
  BOTTOM w0.17: v2(62.24,48.92) 62.68,48.48 63.41,48.48 63.5,48.58 JDIMM2.145
DDR_B_CAS#: length 66.3
  IN3 w0.175: v2(59.26,45.65) 59.8,46.19 63.44,46.19 64.45,47.21 65.87,47.21 66.3,46.78 68.34,46.78 68.77,47.21 70.47,47.21 70.9,46.78 71.01,46.66 76,46.66 77.34,48 79.49,48 80,47.49 83.57,47.49 88.38,52.3 91.51,52.3 94.5,55.29 101.85,55.29 103.56,57 104.38,57 v2(105.15,57.77)
  BOTTOM w0.076: v2(105.15,57.77) 105.15,58.07 105.28,58.2 105.85,58.2 106.28,57.77 106.28,57.51 106.5,57.28 107.08,57.28 107.24,57.45 107.24,57.85 107.77,58.38 109.39,58.38 109.51,58.51 111.07,58.51 111.19,58.39 112.27,58.39 112.45,58.2 112.83,58.2 112.94,58.25 113.06,58.25 113.28,58.19 113.42,58.19 113.58,58.24 113.76,58.24 113.92,58.16 114.02,58.16 UC1.AY43
  BOTTOM w0.17: v2(59.26,45.65) 58.73,45.12 58.35,45.12 57.64,45.83 JDIMM2.156
DDR_B_CKE0: length 65.6
  IN3 w0.076: 113.95,65.09 114.86,65.09 114.96,64.99 117.65,64.99 v2(118.01,65.35)
  IN3 w0.175: v2(62.43,62.26) 62.26,62.26 61.82,62.69 61.82,63.03 61.99,63.2 68.41,63.2 70.17,64.96 76.14,64.96 77.15,65.97 78.18,65.97 78.72,65.43 79.57,65.43 80.19,66.05 80.6,66.05 82.1,67.54 103.85,67.54 104.42,66.97 109.91,66.97 110.95,65.93 112.63,65.93 113.46,65.09 113.95,65.09
  BOTTOM w0.076: v2(118.01,65.35) 118.4,65.74 UC1.AN56
  BOTTOM w0.17: v2(62.43,62.26) 63.8,60.89 63.8,59.88 64.1,59.58 JDIMM2.109
DDR_B_CKE1: length 66.6
  IN3 w0.076: 113.13,65.86 113.27,65.72 117.01,65.72 v2(117.37,65.35)
  IN3 w0.175: 113.13,65.86 112.79,66.2 111.92,66.2 110.11,68 81.91,68 80.42,66.5 77.04,66.5 75.95,65.41 69.98,65.41 68.22,63.66 60.79,63.66 v2(59.38,62.26)
  BOTTOM w0.076: v2(117.37,65.35) UC1.AP55
  BOTTOM w0.17: JDIMM2.110 57.47,59.33 57.8,59.66 57.8,60.67 v2(59.38,62.26)
DDR_B_CKE2: length 1.1
  TOP w0.089: v2(118.66,64.44) 118.46,64.23 T5.1
  BOTTOM w0.076: UC1.AN55 v2(118.66,64.44)
DDR_B_CKE3: length 1.2
  TOP w0.089: v2(117.38,64.44) 117.62,64.67 T6.1
  BOTTOM w0.076: v2(117.38,64.44) UC1.AP53
DDR_B_CLK0: length 70.4
  IN3 w0.076: v2(117.42,59.86) 117.63,59.65 117.63,59.56 117.54,59.47 114.99,59.47 114.54,59.92 111.4,59.92 110.87,60.46 104.06,60.46 103.37,59.77 102.18,59.77 102.16,59.79 102.14,59.79
  IN3 w0.114: 102.14,59.79 88.54,59.79 83.61,54.86 82.91,54.86 82.7,54.65 82.7,53.95 82.53,53.78 82.13,53.78 82.02,53.9 82.02,54.61 81.76,54.86 81.24,54.86 81.02,54.64 81.02,53.9 80.91,53.78 80.57,53.78 80.45,53.9 80.45,54.65 80.24,54.86 79.72,54.86 79.46,54.6 79.46,53.9 79.41,53.85 70.81,53.85 68.99,52.03 61.65,52.03 61.44,51.82 61.44,51.64 v2(61.16,51.36)
  BOTTOM w0.076: v2(117.42,59.86) 117.75,59.53 UC1.AP45
  BOTTOM w0.102: v2(61.16,51.36) 61.31,51.52 61.31,52.23 61.62,52.54 63.72,52.54 63.75,52.58 JDIMM2.137
DDR_B_CLK1: length 69.4
  IN3 w0.076: 102.14,60.31 102.16,60.31 102.18,60.33 103.7,60.33 104.01,60.64 114.43,60.64 114.96,61.17 117.56,61.17 117.66,61.08 117.66,60.85 117.58,60.78 v2(117.37,60.78)
  IN3 w0.114: v2(59.64,51.36) 59.17,51.83 59.17,52.42 59.35,52.61 59.72,52.61 59.88,52.44 59.88,52.06 60.12,51.82 60.64,51.82 60.88,52.06 60.88,52.44 60.99,52.55 68.78,52.55 70.59,54.37 78.34,54.37 78.61,54.64 78.61,55.02 78.98,55.38 83.39,55.38 88.32,60.31 102.14,60.31
  BOTTOM w0.076: UC1.AP46 117.75,60.4 v2(117.37,60.78)
  BOTTOM w0.102: JDIMM2.138 57.73,52.33 57.87,52.18 59.11,52.18 59.36,51.93 59.36,51.64 v2(59.64,51.36)
DDR_B_CLK#0: length 70.3
  IN3 w0.076: 102.14,59.58 102.16,59.58 102.18,59.6 103.44,59.6 104.13,60.3 110.8,60.3 111.34,59.76 114.47,59.76 114.92,59.3 117.61,59.3 117.82,59.51 117.82,59.68 v2(118.02,59.88)
  IN3 w0.114: v2(61.92,51.36) 61.65,51.64 61.65,51.73 61.74,51.82 69.08,51.82 70.89,53.63 79.5,53.63 79.67,53.81 79.67,54.52 79.81,54.65 80.15,54.65 80.24,54.56 80.24,53.81 80.48,53.57 81,53.57 81.23,53.81 81.23,54.55 81.33,54.65 81.67,54.65 81.81,54.52 81.81,53.81 82.04,53.57 82.62,53.57 82.91,53.86 82.91,54.57 83,54.65 83.7,54.65 88.62,59.58 102.14,59.58
  BOTTOM w0.076: UC1.AN45 118.33,59.41 118.02,59.72 v2(118.02,59.88)
  BOTTOM w0.102: JDIMM2.139 63.9,52.08 63.65,52.32 61.71,52.32 61.53,52.14 61.53,51.55 61.71,51.36 v2(61.92,51.36)
DDR_B_CLK#1: length 69.3
  IN3 w0.076: v2(118.01,60.78) 117.82,60.97 117.82,61.15 117.63,61.34 114.89,61.34 114.36,60.81 103.94,60.81 103.63,60.5 102.18,60.5 102.16,60.52 102.14,60.52
  IN3 w0.114: v2(58.88,51.36) 58.96,51.44 58.96,52.51 59.27,52.82 59.81,52.82 60.1,52.53 60.1,52.15 60.21,52.03 60.55,52.03 60.67,52.15 60.67,52.53 60.9,52.76 68.69,52.76 70.5,54.58 78.25,54.58 78.4,54.73 78.4,55.1 78.89,55.59 83.31,55.59 88.23,60.52 102.14,60.52
  BOTTOM w0.076: v2(118.01,60.78) 118.4,60.38 UC1.AN46
  BOTTOM w0.102: JDIMM2.140 57.72,51.83 57.86,51.97 59.02,51.97 59.14,51.84 59.14,51.63 v2(58.88,51.36)
DDR_B_CS#0: length 66.9
  IN3 w0.076: 103.63,57.62 104.53,58.52 108.37,58.52 108.86,58.03 v2(108.86,57.63)
  IN3 w0.175: 103.63,57.62 103.44,57.62 102.01,56.2 94.13,56.2 91.13,53.21 88,53.21 87.11,52.31 86.14,52.31 85.92,52.1 85.92,51.89 86.16,51.66 86.16,51.36 85.97,51.18 85.69,51.18 85.51,51.35 85.36,51.35 84.99,50.98 84.99,50.44 84.71,50.16 84.13,50.16 83.94,49.97 83.94,49.75 84.1,49.59 84.1,49.31 83.88,49.08 83.66,49.08 83.37,49.37 83.2,49.37 82.97,49.14 82.97,48.95 83.21,48.7 83.21,48.51 83.1,48.4 80.37,48.4 79.87,48.91 76.96,48.91 76.17,48.12 62.58,48.12 62.43,47.97 62.43,47.72 62.25,47.55 61.9,47.55 61.73,47.72 61.73,47.99 61.58,48.14 60.96,48.14 60.78,47.96 v2(60.78,47.09)
  BOTTOM w0.076: UC1.BB42 112.68,57.3 111.7,57.3 111.6,57.41 110.84,57.41 110.23,58.02 109.25,58.02 v2(108.86,57.63)
  BOTTOM w0.17: JDIMM2.149 64.05,47.58 63.63,48 62.56,48 62.22,47.66 61.33,47.66 60.78,47.11 v2(60.78,47.09)
DDR_B_CS#1: length 69.2
  IN3 w0.175: v2(110.1,57.24) 109.07,56.21 104.06,56.21 101.77,53.92 95.07,53.92 92.08,50.93 88.94,50.93 84.14,46.13 78.37,46.13 76.8,44.55 69.33,44.55 68.47,45.41 65.83,45.41 65.23,44.82 65.23,44.56 64.59,43.92 61.69,43.92 60.57,45.04 59.59,45.04 59.42,44.87 59.42,44.36 59.57,44.21 60.36,44.21 60.78,43.79 v2(60.78,43.47)
  BOTTOM w0.076: v2(110.1,57.24) 110.27,57.08 111.39,57.08 111.51,56.96 112.26,56.96 112.34,56.88 112.83,56.88 112.86,56.89 112.92,56.92 113.23,57.04 113.72,57.04 UC1.AY42
  BOTTOM w0.17: v2(60.78,43.47) 62.08,44.77 62.99,44.77 63.79,45.58 JDIMM2.157
DDR_B_D0: length 74.1
  IN3 w0.076: 113.17,80.43 114.89,80.43 119.63,75.69 119.63,75.5 121.92,73.21 121.92,70.82 v2(121.4,70.3)
  IN3 w0.109: 113.17,80.43 84.16,80.43 83.37,81.22 81.71,81.22 80.52,82.41 80.42,82.41 80.17,82.66 77.93,82.66 77.38,82.11 69.17,82.11 68.2,81.14 65.69,81.14 65.66,81.11 59.56,81.11 v2(58.5,80.05)
  BOTTOM w0.076: UC1.AF65 v2(121.4,70.3)
  BOTTOM w0.102: v2(58.5,80.05) 58.27,79.83 JDIMM2.28
DDR_B_D1: length 72.6
  IN3 w0.076: v2(121.4,69.66) 121.05,69.66 120.84,69.88 120.84,73.56 120.3,74.1 118.68,74.1 116.77,76.01 116.77,77.85 115.25,79.37 112.27,79.37 112.19,79.45
  IN3 w0.109: 112.19,79.45 83.76,79.45 82.97,80.24 80.56,80.24 79.74,81.07 70.44,81.07 70.32,80.96 70.2,80.96 70.02,81.13 69.86,81.13 69.75,81.02 69.75,80.83 69.88,80.7 69.88,80.51 69.78,80.42 69.63,80.42 69.32,80.73 69.17,80.73 69.01,80.57 69.01,80.42 69.32,80.11 69.32,79.96 69.15,79.79 68.58,79.79 68.47,79.9 68.47,80.05 68.37,80.16 67.28,80.16 67.17,80.05 67.17,79.9 67.06,79.79 66.85,79.79 66.74,79.9 66.74,80.05 66.63,80.16 66.09,80.16 66.06,80.13 65.43,80.13 65.12,79.82 64.87,79.82 64.55,80.13 64.23,80.13 64.16,80.06 64.16,79.89 64.06,79.79 63.85,79.79 63.77,79.87 63.77,80.08 63.72,80.13 63.15,80.13 v2(63.07,80.05)
  BOTTOM w0.076: UC1.AF64 v2(121.4,69.66)
  BOTTOM w0.102: v2(63.07,80.05) 63.6,80.58 JDIMM2.25
DDR_B_D2: length 73.2
  IN3 w0.076: v2(119.58,70.31) 119.18,70.71 119.18,71.15 118.93,71.4 118.93,72.11 117.85,73.19 117.56,73.19 115.12,75.63 115.12,75.94 113.78,77.28 111.69,77.28
  IN3 w0.109: 111.69,77.28 111.41,77.56 79.76,77.56 79.26,78.05 70.1,78.05 69.08,77.03 65.69,77.03 65.56,76.89 65.56,76.64 65.45,76.53 65.19,76.53 65.08,76.64 65.08,76.8 64.97,76.91 64.75,76.91 64.64,76.8 64.64,76.64 64.53,76.53 64.31,76.53 64.21,76.64 64.21,76.8 64.1,76.91 63.88,76.91 63.77,76.8 63.77,76.64 63.66,76.53 63.44,76.53 63.33,76.64 63.33,76.8 63.22,76.91 63,76.91 62.89,76.8 62.89,76.64 62.79,76.53 62.57,76.53 62.46,76.64 62.46,76.8 62.35,76.91 62.13,76.91 62.02,76.8 62.02,76.64 61.91,76.53 61.69,76.53 61.58,76.64 61.58,76.8 61.47,76.91 61.26,76.91 61.15,76.8 61.15,76.64 61.04,76.53 60.82,76.53 60.71,76.64 60.71,76.8 60.6,76.91 60.38,76.91 60.27,76.8 60.27,76.64 60.16,76.53 59.64,76.53 59.53,76.64 59.53,77.01 59.84,77.32 v2(60.02,77.32)
  BOTTOM w0.076: v2(119.58,70.31) 119.89,70.61 UC1.AK65
  BOTTOM w0.102: v2(60.02,77.32) 59.03,76.33 JDIMM2.42
DDR_B_D3: length 73.9
  IN3 w0.076: v2(119.58,69.64) 118.99,70.23 118.99,71.09 118.69,71.39 118.69,71.73 118,72.42 117.53,72.42 115.31,74.64 115.31,75.15 114.93,75.53 114.93,75.9 114.38,76.45 112.24,76.45 111.45,77.23
  IN3 w0.109: v2(58.5,77.32) 58.35,77.47 57.12,77.47 56.99,77.34 56.99,76.39 57.17,76.21 57.78,76.21 57.89,76.32 57.89,76.79 58,76.89 58.22,76.89 58.33,76.79 58.33,76.32 58.44,76.21 65.59,76.21 66.08,76.7 69.21,76.7 70.24,77.73 79.13,77.73 79.63,77.23 111.45,77.23
  BOTTOM w0.076: UC1.AK64 119.91,69.96 v2(119.58,69.64)
  BOTTOM w0.102: JDIMM2.38 58.49,77.33 v2(58.5,77.32)
DDR_B_D4: length 73.6
  IN3 w0.076: v2(121.4,70.93) 121.45,70.93 121.75,71.24 121.75,73.12 120.29,74.58 119.97,74.58 118.72,75.83 118.37,75.83 117.13,77.08 117.13,77.96 114.98,80.1 112.84,80.1
  IN3 w0.109: v2(60.02,80.05) 60.76,80.78 65.79,80.78 65.82,80.81 68.34,80.81 69.3,81.78 77.51,81.78 78.06,82.33 79.76,82.33 80.01,82.09 80.39,82.09 81.58,80.89 83.24,80.89 84.03,80.1 112.84,80.1
  BOTTOM w0.076: UC1.AF66 v2(121.4,70.93)
  BOTTOM w0.102: v2(60.02,80.05) 59.24,80.83 JDIMM2.24
DDR_B_D5: length 73
  IN3 w0.076: 112.52,79.78 115.07,79.78 116.96,77.89 116.96,76.05 118.74,74.27 120.37,74.27 121,73.63 121,71.62 121.05,71.57 v2(121.4,71.57)
  IN3 w0.109: 112.52,79.78 83.89,79.78 83.1,80.57 80.7,80.57 80.42,80.85 80.42,81.01 80.63,81.22 80.63,81.38 80.48,81.53 80.33,81.53 80.13,81.34 79.93,81.34 79.78,81.48 79.78,81.78 79.56,82 78.61,82 78.46,81.85 78.46,81.59 78.33,81.46 69.44,81.46 68.47,80.49 65.96,80.49 65.93,80.46 61.37,80.46 61.31,80.39 61.31,80.29 v2(61.55,80.05)
  BOTTOM w0.076: UC1.AF67 v2(121.4,71.57)
  BOTTOM w0.102: JDIMM2.29 62.02,79.58 v2(61.55,80.05)
DDR_B_D6: length 71.7
  IN3 w0.076: v2(119.58,71.61) 119.58,71.98 118,73.57 117.64,73.57 115.62,75.6 115.62,76.89 113.84,78.66 112.78,78.66
  IN3 w0.109: 112.78,78.66 112.33,78.21 83.24,78.21 82.45,79 80.05,79 79.7,79.34 70.47,79.34 68.81,77.68 67.86,77.68 67.75,77.79 67.75,78.22 67.64,78.33 67.42,78.33 67.31,78.22 67.31,77.79 67.2,77.68 66.98,77.68 66.87,77.79 66.87,78.06 66.77,78.17 66.55,78.17 66.44,78.06 66.44,77.79 66.33,77.68 63.49,77.68 63.39,77.78 63.39,78.12 63.28,78.23 63.06,78.23 62.95,78.12 62.95,77.84 62.84,77.73 62.62,77.73 62.51,77.84 62.51,78.06 62.41,78.17 62.19,78.17 62.08,78.06 62.08,77.91 62.01,77.85 61.31,77.85 61.18,77.72 61.18,77.47 61.33,77.32 v2(61.54,77.32)
  BOTTOM w0.076: v2(119.58,71.61) 119.89,71.91 UC1.AK67
  BOTTOM w0.102: JDIMM2.41 62.29,76.58 v2(61.54,77.32)
DDR_B_D7: length 72.3
  IN3 w0.076: v2(119.57,70.93) 119.57,71.09 119.18,71.47 119.18,72.09 117.89,73.38 117.6,73.38 115.28,75.7 115.28,76.01 113.83,77.46 111.79,77.46
  IN3 w0.109: v2(63.07,77.32) 63.15,77.23 63.74,77.23 63.86,77.35 68.94,77.35 70.61,79.02 74.22,79.02 74.33,78.91 74.33,78.49 74.44,78.38 74.66,78.38 74.77,78.49 74.77,78.91 74.88,79.02 75.09,79.02 75.2,78.91 75.2,78.49 75.31,78.38 75.53,78.38 75.64,78.49 75.64,78.91 75.75,79.02 76.74,79.02 76.85,78.91 76.85,78.49 76.96,78.38 77.17,78.38 77.28,78.49 77.28,78.91 77.39,79.02 77.61,79.02 77.72,78.91 77.72,78.49 77.83,78.38 78.05,78.38 78.16,78.49 78.16,78.91 78.27,79.02 79.57,79.02 79.72,78.86 79.72,78.06 79.89,77.88 80.13,77.88 80.24,77.99 80.24,78.56 80.35,78.67 80.57,78.67 80.68,78.56 80.68,77.99 80.79,77.88 81,77.88 81.11,77.99 81.11,78.56 81.22,78.67 81.44,78.67 81.55,78.56 81.55,77.99 81.66,77.88 81.88,77.88 81.99,77.99 81.99,78.56 82.1,78.67 82.32,78.67 82.42,78.56 82.42,77.99 82.53,77.88 111.36,77.88 111.79,77.46
  BOTTOM w0.076: UC1.AK66 v2(119.57,70.93)
  BOTTOM w0.102: JDIMM2.37 63.33,77.58 v2(63.07,77.32)
DDR_B_D8: length 83.7
  IN3 w0.076: 122.94,80.6 122.94,78.71 v2(122.01,77.78)
  IN3 w0.109: 122.94,80.6 122.94,83.46 119.77,86.63 118.64,86.63 114.32,90.94 109.38,90.94 104.64,86.2 83.63,86.2 82.74,87.1 76.16,87.1 75.53,86.46 64.84,86.46 63.44,85.06 60.43,85.06 v2(60.02,85.47)
  BOTTOM w0.076: v2(122.01,77.78) 122.2,77.78 122.87,77.12 122.87,74.79 122.16,74.08 UC1.AF70
  BOTTOM w0.102: v2(60.02,85.47) 59.37,84.83 JDIMM2.8
DDR_B_D9: length 84.9
  IN3 w0.076: v2(122.02,78.97) 122.02,79.25 122.62,79.85 122.62,80.93
  IN3 w0.109: 122.62,80.93 122.62,83.32 119.64,86.3 118.5,86.3 116.42,88.39 114.19,90.62 109.51,90.62 104.77,85.88 83.5,85.88 82.61,86.77 76.3,86.77 75.66,86.14 65.26,86.14 63.58,84.45 59.52,84.45 v2(58.5,85.47)
  BOTTOM w0.076: UC1.AF68 122.38,72.88 122.38,73.62 122.47,73.72 122.47,74.16 123.25,74.93 123.25,77.95 122.23,78.97 v2(122.02,78.97)
  BOTTOM w0.102: v2(58.5,85.47) 58.14,85.83 JDIMM2.4
DDR_B_D10: length 82.8
  IN3 w0.076: 121.37,82.17 121.37,80.66 120.97,80.26 v2(120.97,80.2)
  IN3 w0.109: 121.37,82.17 121.37,82.81 119.12,85.06 117.99,85.06 113.67,89.37 110.03,89.37 102.91,82.25 89.48,82.25 89.25,82.48 89.25,83.14 89.14,83.24 88.92,83.24 88.82,83.14 88.82,82.36 88.71,82.25 88.49,82.25 88.38,82.36 88.38,83.14 88.27,83.24 88.05,83.24 87.94,83.14 87.94,82.36 87.83,82.25 87.61,82.25 87.51,82.36 87.51,83.07 87.4,83.18 87.18,83.18 87.07,83.07 87.07,82.46 86.86,82.25 84.59,82.25 82.21,84.63 80.73,84.63 80.61,84.75 77.7,84.75 77.51,84.56 68.02,84.56 66.75,83.29 64.94,83.29 64.35,82.7 63.1,82.7 v2(63.01,82.8)
  BOTTOM w0.076: v2(120.97,80.2) 120.39,79.62 120.39,78.38 120.14,78.12 120.14,76.65 120.94,75.85 120.94,74.82 120.83,74.72 UC1.AH71
  BOTTOM w0.102: v2(63.01,82.8) 63.01,82.24 63.67,81.58 JDIMM2.21
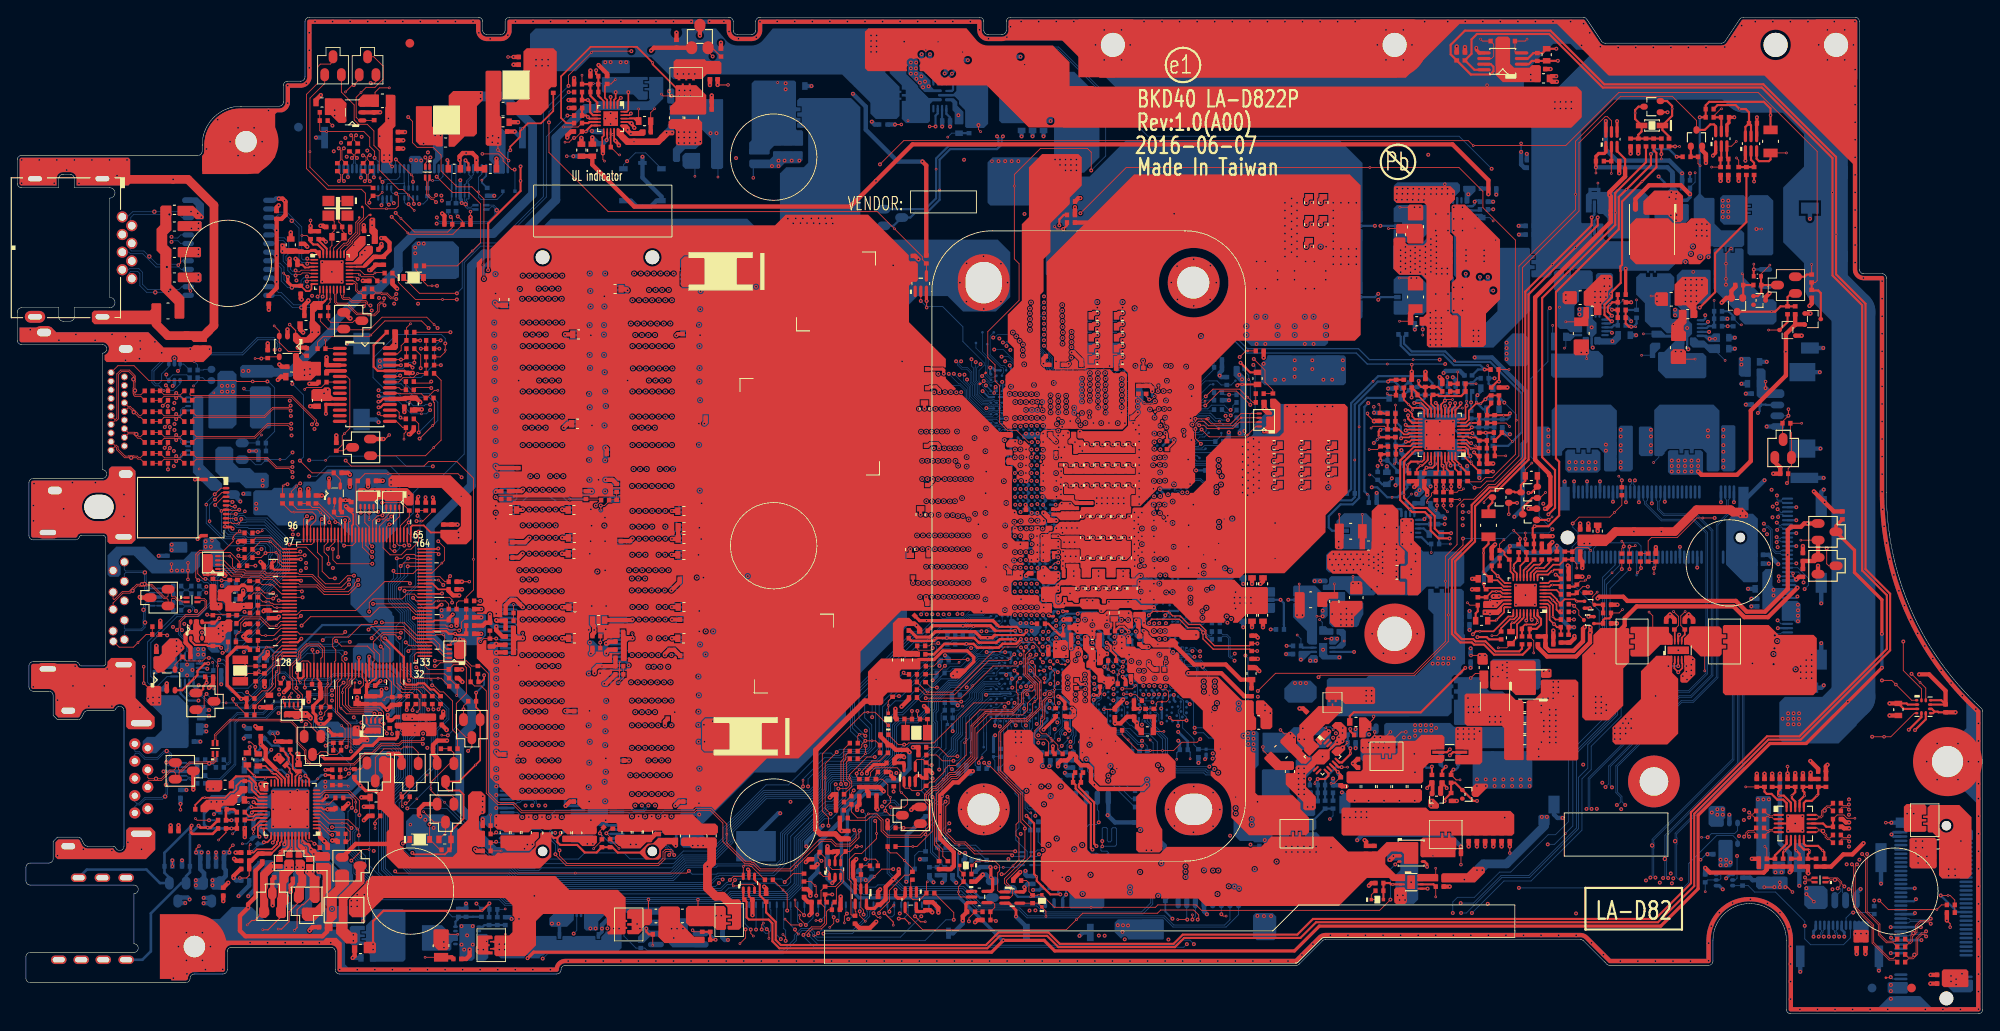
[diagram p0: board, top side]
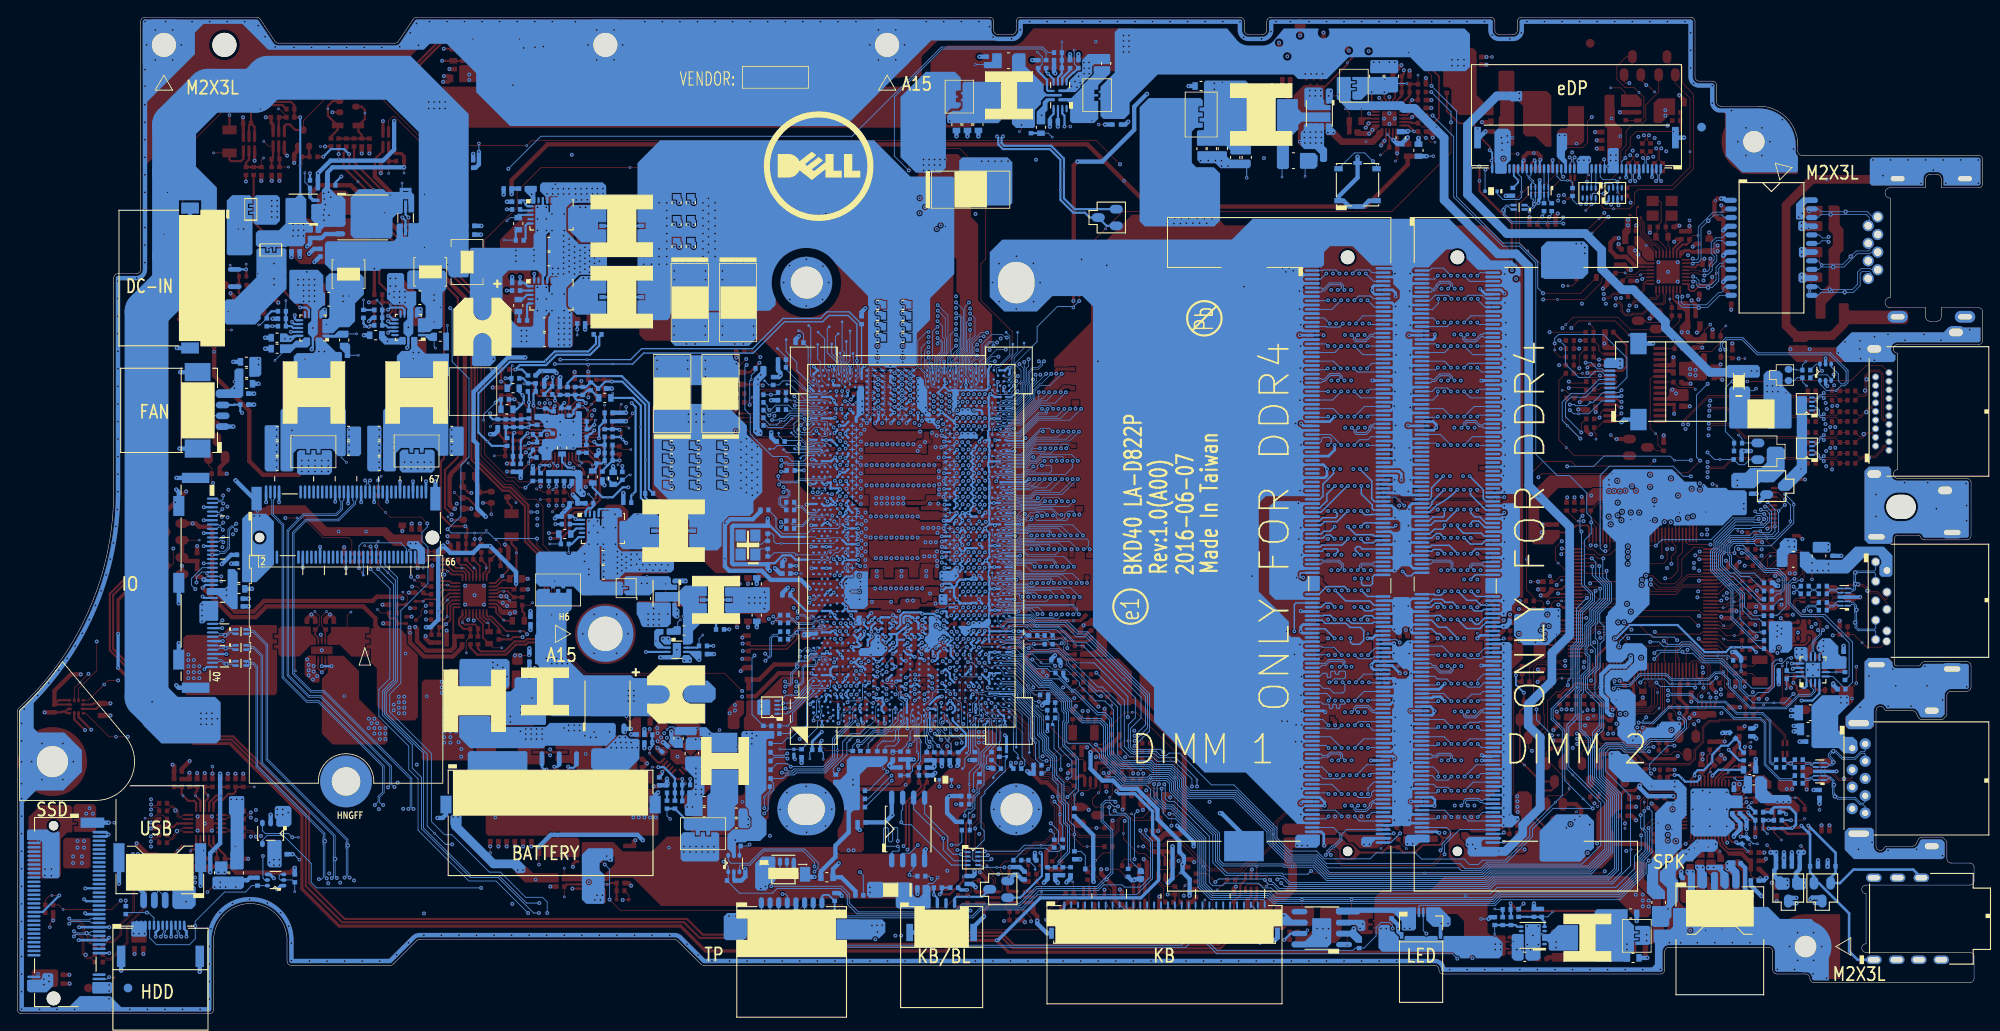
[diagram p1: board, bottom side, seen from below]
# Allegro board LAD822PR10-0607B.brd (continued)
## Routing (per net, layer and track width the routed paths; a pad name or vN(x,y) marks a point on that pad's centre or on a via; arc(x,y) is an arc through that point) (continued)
DDR_B_D11: length 85.1
  IN3 w0.076: 118.91,83.5 119.28,83.13 119.28,80.92 120.64,79.55 v2(120.97,79.55)
  IN3 w0.109: 118.91,83.5 118.59,83.82 117.85,83.82 113.27,88.4 110.43,88.4 107.46,85.42 107.46,82.28 106.45,81.28 84.19,81.28 83.63,81.84 81.97,81.84 80.78,83.03 80.67,83.03 80.43,83.27 77.67,83.27 77.44,83.04 69.23,83.04 68.51,82.32 65.35,82.32 64.76,81.73 58.95,81.73 58.44,82.24 v2(58.44,82.8)
  BOTTOM w0.076: UC1.AH68 121.52,72.56 121.72,72.76 121.72,73.01 121.73,73.02 121.73,73.28 121.74,73.3 121.74,73.35 121.76,73.37 121.76,73.64 121.72,73.76 121.72,73.99 121.73,74 121.73,74 121.73,74 121.76,74.09 121.76,74.29 121.73,74.38 121.73,74.74 122.08,75.09 122.08,75.39 121.53,75.94 121.53,78.99 v2(120.97,79.55)
  BOTTOM w0.102: v2(58.44,82.8) 58.44,82.66 57.6,81.83 JDIMM2.20
DDR_B_D12: length 82.2
  IN3 w0.076: v2(122.01,77.2) 122.32,77.2 123.27,78.15 123.27,80.28
  IN3 w0.109: v2(63.07,85.47) 64.41,86.82 69.7,86.82 71.6,88.71 75.02,88.71 75.52,88.21 85.34,88.21 85.45,88.11 85.45,87.54 85.56,87.44 85.78,87.44 85.88,87.54 85.88,88.11 85.99,88.21 86.21,88.21 86.32,88.11 86.32,87.54 86.43,87.44 86.65,87.44 86.76,87.54 86.76,88.11 86.87,88.21 87.09,88.21 87.2,88.11 87.2,87.54 87.3,87.44 87.52,87.44 87.63,87.54 87.63,88.11 87.74,88.21 106.19,88.21 109.24,91.27 114.46,91.27 118.77,86.95 119.91,86.95 123.27,83.59 123.27,80.28
  BOTTOM w0.076: v2(122.01,77.2) 122.03,77.2 122.49,76.75 122.49,74.84 UC1.AF71
  BOTTOM w0.102: v2(63.07,85.47) 63.47,85.08 64.9,85.08 JDIMM2.7
DDR_B_D13: length 84
  IN3 w0.076: 123.35,77.4 121.99,76.05 v2(121.99,75.99)
  IN3 w0.109: 123.35,77.4 123.59,77.65 123.59,83.73 120.04,87.28 118.91,87.28 114.59,91.59 109.11,91.59 106.05,88.54 75.65,88.54 75.16,89.03 71.46,89.03 69.57,87.14 62.47,87.14 61.54,86.21 v2(61.54,85.47)
  BOTTOM w0.076: UC1.AF69 121.96,73.32 121.96,73.58 121.92,73.68 121.92,73.68 121.89,73.77 121.89,73.97 121.93,74.06 121.93,74.31 121.93,74.32 121.89,74.41 121.89,74.67 122.3,75.08 122.3,75.69 v2(121.99,75.99)
  BOTTOM w0.102: v2(61.54,85.47) 62.41,86.34 63.76,86.34 64.02,86.08 JDIMM2.3
DDR_B_D14: length 83.6
  IN3 w0.076: 119.45,83.5 119.45,82.29 120.31,81.43 v2(120.94,81.43)
  IN3 w0.109: 119.45,83.5 119.45,83.52 118.7,84.26 117.86,84.26 113.4,88.72 110.3,88.72 107.13,85.55 107.13,82.65 106.08,81.6 84.32,81.6 83.76,82.16 82.77,82.16 81.58,83.35 81.09,83.35 80.34,84.1 77.97,84.1 77.24,83.37 69.05,83.37 68.32,82.64 65.21,82.64 64.62,82.05 60.71,82.05 v2(59.96,82.8)
  BOTTOM w0.076: UC1.AH70 120.83,74.01 120.69,74.16 120.69,74.16 120.69,74.16 120.57,74.41 120.57,74.7 120.77,74.9 120.77,75.78 119.95,76.6 119.95,78.33 120.07,78.45 120.07,80.56 v2(120.94,81.43)
  BOTTOM w0.102: v2(59.96,82.8) 59.55,83.21 57.91,83.21 57.53,82.83 JDIMM2.16
DDR_B_D15: length 84.7
  IN3 w0.076: 120.18,83.36 120.18,82.36 120.47,82.06 v2(120.94,82.06)
  IN3 w0.109: v2(61.48,82.8) 61.48,82.71 61.82,82.38 64.49,82.38 65.08,82.97 67.24,82.97 68.51,84.23 71.04,84.23 71.15,84.12 71.15,83.86 71.26,83.75 71.48,83.75 71.59,83.86 71.59,84 71.7,84.1 71.92,84.1 72.03,84 72.03,83.86 72.13,83.75 72.35,83.75 72.46,83.86 72.46,84.12 72.57,84.23 77.64,84.23 77.84,84.42 80.48,84.42 81.22,83.68 81.71,83.68 82.9,82.49 83.9,82.49 84.46,81.93 105.95,81.93 106.52,82.5 106.52,85.4 110.16,89.05 113.54,89.05 117.85,84.73 118.99,84.73 120.18,83.53 120.18,83.36
  BOTTOM w0.076: UC1.AH69 120.83,73.42 120.44,73.81 120.44,74.3 120.4,74.37 120.4,74.77 120.46,74.82 120.61,74.97 120.61,75.69 119.76,76.54 119.76,80.88 v2(120.94,82.06)
  BOTTOM w0.102: JDIMM2.17 64.01,82.58 63.38,83.21 61.89,83.21 v2(61.48,82.8)
DDR_B_D16: length 64.6
  IN3 w0.076: 111.37,76.1 112.06,75.41 112.95,75.41 116.1,72.26 v2(116.1,71.75)
  IN3 w0.109: v2(61.54,74.82) 61.95,75.23 65.5,75.23 65.87,74.87 65.87,74.63 66.12,74.38 67.02,74.38 67.88,75.23 69.12,75.23 70.13,76.24 79.71,76.24 80.48,75.47 82.57,75.47 82.68,75.58 82.68,76.02 82.79,76.13 83.01,76.13 83.12,76.02 83.12,75.58 83.23,75.47 83.44,75.47 83.55,75.58 83.55,76.15 83.66,76.26 110.08,76.26 110.2,76.37 110.83,76.37 111.1,76.1 111.37,76.1
  BOTTOM w0.076: UC1.AT66 116.45,71.4 v2(116.1,71.75)
  BOTTOM w0.102: JDIMM2.45 62.3,75.58 v2(61.54,74.82)
DDR_B_D17: length 63.7
  IN3 w0.076: v2(115.47,71.78) 115.47,72.66 112.95,75.18 112.04,75.18 111.46,75.75
  IN3 w0.109: 111.46,75.75 111.17,75.75 110.75,76.18 110.28,76.18 110.04,75.93 108.64,75.93 108.63,75.93 86.35,75.93 86.34,75.92 85.78,75.92 85.67,75.81 85.67,75.25 85.56,75.14 85.34,75.14 85.24,75.25 85.24,75.81 85.13,75.92 84.91,75.92 84.8,75.81 84.8,75.25 84.69,75.14 84.47,75.14 84.36,75.25 84.36,75.81 84.25,75.92 83.99,75.92 83.88,75.81 83.88,75.25 83.77,75.14 80.35,75.14 79.57,75.92 70.27,75.92 69.05,74.7 67.8,74.7 67.15,74.05 65.65,74.05 65.54,74.16 65.54,74.73 65.43,74.84 65.22,74.84 65.11,74.73 65.11,74.16 65,74.05 64.76,74.05 64.61,74.2 64.61,74.67 64.41,74.87 63.12,74.87 v2(63.07,74.82)
  BOTTOM w0.076: v2(115.47,71.78) 115.8,71.45 UC1.AU66
  BOTTOM w0.102: v2(63.07,74.82) 63.31,74.58 JDIMM2.49
DDR_B_D18: length 67
  IN3 w0.076: 103.28,73.69 104.63,72.34 109.39,72.34 110.49,71.24 113,71.24 114.09,70.15 116.02,70.15 116.16,70.29 117.18,70.29 117.5,70.6 v2(117.5,70.86)
  IN3 w0.109: 103.28,73.69 103.26,73.71 88.16,73.71 88.06,73.61 88.06,73.04 87.94,72.92 79.85,72.92 79.66,72.73 77.27,72.73 77.01,72.47 71.03,72.47 70.44,71.89 69.39,71.89 68.28,70.79 59.73,70.79 59.53,70.99 59.53,71.57 v2(60.02,72.06)
  BOTTOM w0.076: UC1.AP65 117.75,70.46 117.5,70.71 v2(117.5,70.86)
  BOTTOM w0.102: v2(60.02,72.06) 59.28,71.33 JDIMM2.62
DDR_B_D19: length 67.7
  IN3 w0.076: 103.28,74.03 104.81,72.5 109.46,72.5 110.55,71.41 113.23,71.41 114.32,70.32 115.94,70.32 116.1,70.48 117.02,70.48 117.12,70.58 117.12,71.12 117.31,71.31 117.63,71.31 v2(118.06,70.88)
  IN3 w0.109: v2(61.54,72.06) 61.43,71.95 61.43,71.31 61.62,71.12 61.62,71.11 61.95,71.11 62.06,71.22 62.06,71.54 62.17,71.65 62.39,71.65 62.47,71.57 62.5,71.54 62.5,71.22 62.61,71.11 62.82,71.11 62.93,71.22 62.93,71.54 63.04,71.65 63.26,71.65 63.37,71.54 63.37,71.22 63.48,71.11 68.15,71.11 69.25,72.22 70.31,72.22 70.89,72.8 76.88,72.8 77.7,73.62 79.18,73.62 79.56,73.24 87.63,73.24 87.73,73.35 87.73,73.85 87.91,74.03 103.28,74.03
  BOTTOM w0.076: UC1.AN65 118.4,70.44 118.06,70.79 v2(118.06,70.88)
  BOTTOM w0.102: JDIMM2.59 63.71,72.08 63.32,72.47 61.95,72.47 v2(61.54,72.06)
DDR_B_D20: length 66.8
  IN3 w0.076: 112.31,76.12 113.01,76.12 116.77,72.36 117.03,72.36 117.22,72.17 117.59,72.17 v2(118,71.75)
  IN3 w0.109: v2(58.5,74.82) 58.04,74.82 57.88,74.99 57.88,75.69 58.07,75.88 68.85,75.88 69.86,76.89 79.3,76.89 79.31,76.91 111.52,76.91 112.31,76.12
  BOTTOM w0.076: v2(118,71.75) 118.4,71.35 UC1.AN66
  BOTTOM w0.102: JDIMM2.50 58,74.33 v2(58.5,74.82)
DDR_B_D21: length 66.1
  IN3 w0.076: v2(117.37,71.75) 116.96,72.17 116.64,72.17 113.21,75.6 112.36,75.6 111.84,76.12
  IN3 w0.109: 111.84,76.12 111.38,76.58 79.45,76.58 79.44,76.57 70,76.57 68.99,75.56 67.19,75.56 67.08,75.45 67.08,75 66.97,74.89 66.75,74.89 66.64,75 66.64,75.45 66.53,75.56 59.84,75.56 59.72,75.43 59.72,75.12 v2(60.02,74.82)
  BOTTOM w0.076: v2(117.37,71.75) UC1.AP66
  BOTTOM w0.102: JDIMM2.46 59.52,75.33 v2(60.02,74.82)
DDR_B_D22: length 65.6
  IN3 w0.076: 103.28,74.36 104.97,72.67 109.53,72.67 110.62,71.57 113.34,71.57 114.43,70.48 115.75,70.48 v2(116.1,70.84)
  IN3 w0.109: 103.28,74.36 87.6,74.36 87.41,74.16 87.41,73.72 87.26,73.57 79.7,73.57 79.32,73.95 77.57,73.95 77.39,73.78 72.68,73.78 72.57,73.67 72.57,73.23 72.46,73.12 72.24,73.12 72.13,73.23 72.13,73.67 72.02,73.78 71.8,73.78 71.69,73.67 71.69,73.23 71.58,73.12 71.37,73.12 71.26,73.23 71.26,73.67 71.15,73.78 70.35,73.78 70.22,73.65 70.22,72.67 70.1,72.54 69.12,72.54 69.05,72.48 67.87,72.48 67.58,72.19 67.25,72.19 67.14,72.08 67.14,71.55 67.03,71.44 66.81,71.44 66.71,71.55 66.71,72.08 66.6,72.19 65.22,72.19 65.11,72.08 65.11,71.55 65.01,71.44 64.79,71.44 64.68,71.55 64.68,72.08 64.57,72.19 64.35,72.19 64.24,72.08 64.24,71.55 64.13,71.44 63.91,71.44 63.78,71.57 63.78,72 63.72,72.06 v2(63.07,72.06)
  BOTTOM w0.076: v2(116.1,70.84) 116.45,70.49 UC1.AT65
  BOTTOM w0.102: v2(63.07,72.06) 63.07,71.64 63.63,71.08 JDIMM2.63
DDR_B_D23: length 64.7
  IN3 w0.076: v2(115.5,70.84) 114.47,70.84 113.56,71.75 110.68,71.75 109.59,72.83 105.11,72.83 103.26,74.68
  IN3 w0.109: v2(58.5,72.06) 57.75,72.06 57.62,72.2 57.62,72.58 57.75,72.7 63.15,72.7 63.25,72.8 68.92,72.8 70.21,74.1 76.93,74.1 77.1,74.27 79.45,74.27 79.83,73.89 86.82,73.89 86.96,74.04 86.96,74.54 87.1,74.68 103.26,74.68
  BOTTOM w0.076: v2(115.5,70.84) 115.8,70.53 UC1.AU65
  BOTTOM w0.102: v2(58.5,72.06) 58.23,72.33 JDIMM2.58
DDR_B_D24: length 65.1
  IN3 w0.076: 103.26,72.44 104.63,71.08 109.68,71.08 110.09,70.67 112.49,70.67 113.69,69.47 115.64,69.47 v2(116.1,69.01)
  IN3 w0.109: 103.26,72.44 94.78,72.44 94.67,72.33 94.67,71.76 94.56,71.65 94.34,71.65 94.23,71.76 94.23,72.33 94.12,72.44 93.9,72.44 93.8,72.33 93.8,71.76 93.69,71.65 93.47,71.65 93.36,71.76 93.36,72.33 93.25,72.44 93.03,72.44 92.92,72.33 92.92,71.76 92.81,71.65 92.59,71.65 92.48,71.76 92.48,72.33 92.38,72.44 92.16,72.44 92.05,72.33 92.05,71.76 91.94,71.65 91.72,71.65 91.61,71.76 91.61,72.33 91.5,72.44 91.28,72.44 91.17,72.33 91.17,71.76 91.06,71.65 80.38,71.65 80.19,71.46 78.61,71.46 78.5,71.35 78.5,70.99 78.39,70.88 78.18,70.88 78.07,70.99 78.07,71.35 77.96,71.46 77.8,71.46 76.96,70.63 69.91,70.63 68.15,68.87 63.36,68.87 v2(63.07,69.16)
  BOTTOM w0.076: UC1.AT61 116.45,68.66 v2(116.1,69.01)
  BOTTOM w0.102: JDIMM2.71 63.15,69.08 v2(63.07,69.16)
DDR_B_D25: length 64.6
  IN3 w0.076: v2(115.47,68.98) 115.17,69.28 113.56,69.28 112.33,70.5 110.02,70.5 109.61,70.91 104.47,70.91 103.26,72.12
  IN3 w0.109: v2(60.02,69.16) 60.02,68.85 60.29,68.58 60.64,68.58 60.81,68.75 61.02,68.75 61.13,68.64 61.13,68.57 61.24,68.46 61.46,68.46 61.57,68.57 61.57,68.64 61.68,68.75 61.9,68.75 62.01,68.64 62.01,68.57 62.12,68.46 63.62,68.46 63.73,68.35 63.73,68.27 63.84,68.16 64.06,68.16 64.17,68.27 64.17,68.35 64.28,68.46 64.5,68.46 64.61,68.35 64.61,68.27 64.71,68.16 64.93,68.16 65.04,68.27 65.04,68.35 65.15,68.46 65.89,68.46 65.97,68.54 68.29,68.54 70.05,70.3 77.09,70.3 77.35,70.55 79.74,70.55 80.51,71.33 95.08,71.33 95.22,71.46 95.22,71.94 95.39,72.12 103.26,72.12
  BOTTOM w0.076: v2(115.47,68.98) 115.47,68.88 UC1.AU61
  BOTTOM w0.102: JDIMM2.66 58.85,70.33 v2(60.02,69.16)
DDR_B_D26: length 67.8
  IN3 w0.076: 102.14,69.43 102.74,69.43 102.9,69.27 111.35,69.27 112.01,68.61 112.47,68.61 113.54,67.53 116.33,67.53 116.52,67.72 117,67.72 v2(117.37,68.09)
  IN3 w0.109: v2(61.54,65.86) 61.26,65.86 61.19,65.78 61.19,65.53 61.27,65.45 63.67,65.45 63.78,65.55 64.31,65.55 64.42,65.65 64.42,66.19 64.49,66.26 64.83,66.26 64.9,66.19 64.9,65.66 65.01,65.55 65.23,65.55 65.33,65.66 65.33,66.19 65.41,66.26 68.69,66.26 69.71,67.28 70.34,67.28 70.44,67.39 70.44,67.74 70.55,67.85 70.77,67.85 70.88,67.74 70.88,67.39 70.99,67.28 71.24,67.28 71.42,67.46 71.67,67.46 71.86,67.28 72.11,67.28 72.3,67.46 72.55,67.46 72.73,67.28 72.98,67.28 73.17,67.46 73.42,67.46 73.61,67.28 75.79,67.28 76.45,67.93 77.81,67.93 77.94,68.07 77.94,68.26 78.07,68.39 78.26,68.39 78.39,68.26 78.39,68.07 78.52,67.93 79.82,67.93 79.93,68.04 79.93,68.53 80.06,68.66 80.55,68.66 81.32,69.43 102.14,69.43
  BOTTOM w0.076: UC1.AP60 117.75,67.71 v2(117.37,68.09)
  BOTTOM w0.102: v2(61.54,65.86) 62.76,67.08 JDIMM2.79
DDR_B_D27: length 68
  IN3 w0.076: v2(118.01,68.09) 117.46,67.55 116.6,67.55 116.42,67.37 113.31,67.37 112.3,68.38 111.98,68.38 111.26,69.1 102.14,69.1
  IN3 w0.109: 102.14,69.1 81.45,69.1 79.96,67.61 76.58,67.61 75.93,66.95 69.84,66.95 68.83,65.94 66.18,65.94 65.47,65.22 63.93,65.22 63.83,65.12 59.82,65.12 59.02,64.32 57.88,64.32 57.57,64.63 57.57,65.6 57.82,65.86 v2(58.5,65.86)
  BOTTOM w0.076: v2(118.01,68.09) 118.4,67.7 UC1.AN60
  BOTTOM w0.102: v2(58.5,65.86) 58.46,65.83 JDIMM2.84
DDR_B_D28: length 67.2
  IN3 w0.076: v2(118.01,69.01) 117.46,69.55 116.53,69.55 116.2,69.88 114.04,69.88 112.93,71 110.23,71 109.82,71.41 104.91,71.41 103.23,73.09 102.35,73.09
  IN3 w0.109: 102.35,73.09 88.81,73.09 88.67,72.95 88.67,72.44 88.53,72.3 80.11,72.3 79.92,72.11 77.53,72.11 76.69,71.28 69.64,71.28 67.88,69.52 63.75,69.52 63.37,69.89 58.11,69.89 58,69.78 58,69.27 58.12,69.16 v2(58.5,69.16)
  BOTTOM w0.076: UC1.AN61 118.4,68.61 v2(118.01,69.01)
  BOTTOM w0.102: v2(58.5,69.16) 58.33,69.33 JDIMM2.70
DDR_B_D29: length 66.7
  IN3 w0.076: 102.35,72.77 102.36,72.75 103.28,72.75 104.79,71.24 109.75,71.24 110.16,70.83 112.77,70.83 113.91,69.69 116.14,69.69 116.45,69.37 117.01,69.37 v2(117.37,69.01)
  IN3 w0.109: 102.35,72.77 90.85,72.77 90.74,72.66 90.74,72.09 90.63,71.98 90.41,71.98 90.3,72.09 90.3,72.66 90.19,72.77 89.98,72.77 89.87,72.66 89.87,72.09 89.76,71.98 89.54,71.98 89.43,72.09 89.43,72.66 89.32,72.77 89.1,72.77 88.99,72.66 88.99,72.09 88.88,71.98 80.24,71.98 80.05,71.79 77.66,71.79 76.82,70.95 69.78,70.95 68.02,69.19 63.61,69.19 63.24,69.57 61.66,69.57 61.54,69.45 v2(61.54,69.16)
  BOTTOM w0.076: UC1.AP61 117.75,68.63 v2(117.37,69.01)
  BOTTOM w0.102: v2(61.54,69.16) 62.46,70.08 JDIMM2.67
DDR_B_D30: length 67.1
  IN3 w0.076: 102.14,69.75 103.18,69.75 103.47,69.47 111.41,69.47 112.07,68.81 112.66,68.81 113.77,67.7 115.81,67.7 v2(116.12,68.01)
  IN3 w0.109: v2(63.07,65.86) 63.62,65.86 64.35,66.59 68.56,66.59 69.57,67.6 69.92,67.6 70.13,67.81 70.13,68.16 70.25,68.28 74.2,68.28 74.31,68.17 74.31,67.71 74.41,67.6 74.63,67.6 74.74,67.71 74.74,68.17 74.85,68.28 75.07,68.28 75.18,68.17 75.18,67.71 75.29,67.6 75.51,67.6 75.62,67.71 75.62,68.17 75.73,68.28 77.5,68.28 77.97,68.75 79.44,68.75 79.67,68.98 80.41,68.98 81.18,69.75 97.73,69.75 97.84,69.86 97.84,70.44 97.95,70.54 98.17,70.54 98.28,70.44 98.28,69.86 98.39,69.75 98.61,69.75 98.71,69.86 98.71,70.44 98.82,70.54 99.04,70.54 99.15,70.44 99.15,69.86 99.26,69.75 99.48,69.75 99.59,69.86 99.59,70.44 99.7,70.54 99.92,70.54 100.03,70.44 100.03,69.86 100.13,69.75 100.35,69.75 100.46,69.86 100.46,70.44 100.57,70.54 100.79,70.54 100.9,70.44 100.9,69.86 101.01,69.75 101.23,69.75 101.34,69.86 101.34,70.44 101.45,70.54 101.66,70.54 101.77,70.44 101.77,69.86 101.88,69.75 102.14,69.75
  BOTTOM w0.076: v2(116.12,68.01) 116.45,67.68 UC1.AT60
  BOTTOM w0.102: JDIMM2.83 63.29,66.08 v2(63.07,65.86)
DDR_B_D31: length 66.3
  IN3 w0.076: 102.89,70.87 103.34,70.42 109.31,70.42 109.76,69.97 111.17,69.97 112.01,69.13 112.74,69.13 113.81,68.06 v2(115.47,68.06)
  IN3 w0.109: 102.89,70.87 97.52,70.87 97.41,70.76 97.41,70.19 97.3,70.08 97.08,70.08 96.97,70.19 96.97,70.76 96.86,70.87 96.64,70.87 96.53,70.76 96.53,70.19 96.42,70.08 81.05,70.08 80.28,69.31 78.07,69.31 77.4,68.64 70.15,68.64 68.42,66.91 64.21,66.91 63.95,66.66 61.88,66.66 61.77,66.55 61.77,66.38 61.66,66.27 61.44,66.27 61.33,66.38 61.33,66.55 61.22,66.66 61.01,66.66 60.9,66.55 60.9,66.38 60.79,66.27 60.57,66.27 60.46,66.38 60.46,66.55 60.35,66.66 59.96,66.66 59.85,66.54 59.85,66.03 v2(60.02,65.86)
  BOTTOM w0.076: v2(115.47,68.06) 115.47,68.03 115.8,67.7 UC1.AU60
  BOTTOM w0.102: v2(60.02,65.86) 59.05,66.83 JDIMM2.80
DDR_B_D32: length 67.6
  IN3 w0.076: 103.55,53.21 110.11,53.21 111.22,54.33 111.58,54.33 114.21,56.97 115.38,56.97 v2(115.38,56.97)
  IN3 w0.109: v2(61.49,41.53) 61.92,41.1 66.82,41.1 66.93,41.21 66.93,41.46 67.04,41.57 67.25,41.57 67.36,41.46 67.36,41.21 67.47,41.1 68.83,41.1 68.94,41.21 68.94,41.73 69.05,41.84 69.27,41.84 69.38,41.73 69.38,41.21 69.49,41.1 69.89,41.1 70.01,41.22 70.01,41.65 70.36,42.01 78.37,42.01 78.39,42.02 81.83,42.02 81.94,42.13 81.94,42.79 82.05,42.9 83.87,42.9 89.81,48.84 92.92,48.84 95.93,51.84 102.18,51.84 103.55,53.21
  BOTTOM w0.076: UC1.AU40 115.7,56.66 115.39,56.97 v2(115.38,56.97)
  BOTTOM w0.102: v2(61.49,41.53) 62.53,42.58 JDIMM2.169
DDR_B_D33: length 67.7
  IN3 w0.076: v2(116.13,57.02) 116.11,57.02 116.11,57.04 115.82,57.33 113.43,57.33 110.56,54.45 103.49,54.45 102.92,53.88 102.92,53.04
  IN3 w0.109: 102.92,53.04 102.05,52.17 95.8,52.17 92.79,49.17 89.68,49.17 84.59,44.08 83.73,43.22 81.73,43.22 81.62,43.11 81.62,42.45 81.51,42.35 81.29,42.35 81.18,42.45 81.18,43.11 81.07,43.22 80.85,43.22 80.74,43.11 80.74,42.45 80.63,42.35 80.42,42.35 80.31,42.45 80.31,43.11 80.2,43.22 79.98,43.22 79.87,43.11 79.87,42.45 79.76,42.35 79.54,42.35 79.43,42.45 79.43,43.11 79.32,43.22 77.95,43.22 77.79,43.07 77.79,42.52 77.61,42.33 68.8,42.33 68.61,42.15 65.71,42.15 65.55,41.98 65.55,41.64 65.44,41.53 v2(63.01,41.53)
  BOTTOM w0.076: UC1.AT40 116.45,56.7 v2(116.13,57.02)
  BOTTOM w0.102: v2(63.01,41.53) 63.06,41.58 JDIMM2.173
DDR_B_D34: length 69.6
  IN3 w0.076: v2(116.1,55.3) 115.98,55.3 115.55,54.88 113.26,54.88 111.87,53.5 111.35,53.5 110.94,53.08 110.94,52.24 109.82,51.12 103.01,51.12 102.16,50.27 101.66,50.27
  IN3 w0.109: 101.66,50.27 96.58,50.27 93.53,47.22 90.42,47.22 83.3,40.11 77.52,40.11 76.94,39.53 75.79,39.53 75.71,39.44 71.17,39.44 71.09,39.53 68.13,39.53 67.62,39.02 66.54,39.02 66.44,38.91 66.44,37.93 66.33,37.82 66.11,37.82 66,37.93 66,38.91 65.89,39.02 65.65,39.02 65.48,38.86 65.48,38.03 65.27,37.82 61.9,37.82 v2(61.49,38.23)
  BOTTOM w0.076: v2(116.1,55.3) UC1.AT37
  BOTTOM w0.102: JDIMM2.183 63.43,39.08 63.12,38.77 62.03,38.77 v2(61.49,38.23)
DDR_B_D35: length 68.6
  IN3 w0.076: v2(115.45,55.3) 115.19,55.04 113.19,55.04 111.84,53.7 111.32,53.7 110.89,53.27 110.77,53.15 110.77,52.31 109.75,51.29 102.37,51.29
  IN3 w0.109: v2(63.01,38.23) 63.96,38.23 64.21,38.48 64.21,39.68 64.38,39.85 64.61,39.85 64.72,39.74 64.72,38.49 64.83,38.38 65.05,38.38 65.16,38.49 65.16,39.74 65.27,39.85 71.11,39.85 71.22,39.96 71.22,40.28 71.33,40.39 71.54,40.39 71.65,40.28 71.65,39.96 71.76,39.85 71.98,39.85 72.09,39.96 72.09,40.28 72.2,40.39 72.42,40.39 72.53,40.28 72.53,39.96 72.72,39.77 75.57,39.77 75.66,39.85 75.86,39.85 75.97,39.96 75.97,40.28 76.07,40.39 76.29,40.39 76.4,40.28 76.4,39.96 76.51,39.85 76.8,39.85 76.93,39.98 76.93,40.25 77.06,40.39 77.34,40.39 77.38,40.43 83.17,40.43 90.29,47.55 93.4,47.55 96.45,50.6 101.68,50.6 102.37,51.29
  BOTTOM w0.076: v2(115.45,55.3) UC1.AU37
  BOTTOM w0.102: v2(63.01,38.23) 63.17,38.08 JDIMM2.187
DDR_B_D36: length 69
  IN3 w0.076: 102.2,53.3 102.2,53.63 103.36,54.78 110.4,54.78 113.27,57.66 116.4,57.66 116.94,57.12 v2(117.34,57.12)
  IN3 w0.109: v2(58.44,41.53) 59.29,42.38 65.03,42.38 66.04,43.4 68.67,43.4 69.08,42.98 76.79,42.98 77.68,43.87 83.45,43.87 89.41,49.83 92.54,49.83 95.53,52.82 101.72,52.82 102.2,53.3
  BOTTOM w0.076: v2(117.34,57.12) 117.1,56.88 UC1.AR40
  BOTTOM w0.102: v2(58.44,41.53) 57.65,42.33 JDIMM2.170
DDR_B_D37: length 69.6
  IN3 w0.076: 102.14,52.95 102.49,53.31 102.49,53.68 103.42,54.62 110.49,54.62 113.36,57.49 115.89,57.49 115.98,57.4 116.42,57.4 117.37,56.45 v2(117.37,56.21)
  IN3 w0.109: 102.14,52.95 101.68,52.49 95.66,52.49 92.67,49.5 89.54,49.5 84.74,44.7 84.74,44.69 83.6,43.55 77.81,43.55 76.92,42.66 68.66,42.66 68.48,42.47 65.58,42.47 65.16,42.06 59.87,42.06 59.72,41.91 59.72,41.78 v2(59.97,41.53)
  BOTTOM w0.076: v2(117.37,56.21) UC1.AP40
  BOTTOM w0.102: v2(59.97,41.53) 59.56,41.13 57.96,41.13 57.76,41.33 JDIMM2.174
DDR_B_D38: length 70.6
  IN3 w0.076: 101.66,49.95 102.1,49.95 103.11,50.96 109.89,50.96 111.1,52.17 111.1,52.24 113.57,54.71 115.18,54.71 115.19,54.71 115.64,54.71 115.88,54.94 117.02,54.94 v2(117.37,55.29)
  IN3 w0.109: 101.66,49.95 96.72,49.95 93.66,46.89 90.55,46.89 83.44,39.78 77.65,39.78 77.07,39.2 75.93,39.2 75.84,39.12 71.04,39.12 70.95,39.2 68.26,39.2 67.75,38.69 66.98,38.69 66.76,38.47 66.76,37.71 66.55,37.49 59.88,37.49 59.72,37.65 59.72,37.98 v2(59.97,38.23)
  BOTTOM w0.076: v2(117.37,55.29) UC1.AP37
  BOTTOM w0.102: v2(59.97,38.23) 59.56,37.82 58.21,37.82 57.71,38.33 JDIMM2.186
DDR_B_D39: length 70
  IN3 w0.076: 101.66,49.62 102.01,49.62 103.18,50.79 109.96,50.79 111.27,52.1 111.27,52.18 113.64,54.55 115.04,54.55 115.05,54.54 115.75,54.54 115.95,54.74 117.05,54.74 v2(117.41,54.39)
  IN3 w0.109: v2(58.44,38.23) 59.5,37.17 66.68,37.17 67.31,37.8 68.11,37.8 69.19,38.88 70.82,38.88 70.9,38.79 75.98,38.79 76.06,38.88 77.21,38.88 77.79,39.46 83.57,39.46 90.68,46.56 93.79,46.56 96.85,49.62 101.66,49.62
  BOTTOM w0.076: v2(117.41,54.39) UC1.AR37
  BOTTOM w0.102: v2(58.44,38.23) 58.45,38.24 58.45,38.67 57.79,39.33 JDIMM2.182
DDR_B_D40: length 71
  IN3 w0.076: 101.56,48.3 102.25,48.99 102.25,48.99 103.55,50.3 110.18,50.3 113.39,53.51 114.86,53.51 115.16,53.81 115.63,53.81 115.97,53.46 v2(116.1,53.46)
  IN3 w0.109: v2(59.97,36.2) 60.42,35.74 61.44,35.74 61.72,35.46 62.49,35.46 62.6,35.35 62.6,35.2 62.71,35.09 62.92,35.09 63.03,35.2 63.03,35.35 63.14,35.46 63.44,35.46 63.57,35.59 63.57,35.71 63.67,35.82 63.98,35.82 64.09,35.71 64.09,35.25 64.37,34.97 65.2,34.97 65.49,35.27 65.49,35.71 65.6,35.82 68.32,35.82 68.56,36.06 68.56,36.46 69.43,37.32 77.45,37.32 78.11,37.99 79.27,37.99 79.48,38.19 84.1,38.19 84.56,38.65 88.27,42.36 88.42,42.36 89.04,41.74 89.2,41.74 92.75,45.29 94.32,45.29 97.33,48.3 101.56,48.3
  BOTTOM w0.076: v2(116.1,53.46) 116.24,53.28 UC1.AT33
  BOTTOM w0.102: JDIMM2.190 57.86,37.33 58.17,37.02 59.15,37.02 v2(59.97,36.2)
DDR_B_D41: length 69.9
  IN3 w0.076: 101.66,47.89 101.84,47.89 103.47,49.51 110.22,49.51 111.16,50.45 111.16,50.54 111.79,51.17 112.63,51.17 113.88,52.42 114.1,52.42 115.13,53.45 v2(115.46,53.45)
  IN3 w0.109: v2(58.44,36.2) 58.14,36.2 58.01,36.07 58.01,35.55 58.15,35.41 61.31,35.41 62.08,34.64 65.6,34.64 65.82,34.86 65.82,35.25 66.06,35.49 68.45,35.49 68.89,35.92 68.89,36.32 69.56,37 77.58,37 78.25,37.66 79.41,37.66 79.61,37.87 84.23,37.87 88.27,41.9 88.42,41.9 88.91,41.41 89.33,41.41 92.89,44.97 94.45,44.97 97.38,47.9 101.65,47.9 101.66,47.89
  BOTTOM w0.076: UC1.AU33 115.8,53.11 v2(115.46,53.45)
  BOTTOM w0.102: v2(58.44,36.2) 58.31,36.33 JDIMM2.194
DDR_B_D42: length 69.4
  IN3 w0.076: v2(115.5,51.66) 115.16,51.32 113.48,51.32 111.18,49.02 104.17,49.02 103.31,48.16
  IN3 w0.109: v2(63.01,33.21) 63.2,33.39 65.55,33.39 65.96,32.99 66.3,32.99 66.54,33.23 66.54,33.54 67.1,34.1 67.47,34.1 67.65,33.92 68.65,33.92 69.25,34.52 69.67,34.52 69.78,34.63 69.78,35.01 69.88,35.12 70.1,35.12 70.21,35.01 70.21,34.63 70.32,34.52 70.57,34.52 70.68,34.63 70.68,35.01 70.79,35.12 71,35.12 71.11,35.01 71.11,34.63 71.22,34.52 74.11,34.52 74.22,34.63 74.22,35.01 74.33,35.12 74.55,35.12 74.66,35.01 74.66,34.63 74.77,34.52 75.14,34.52 75.25,34.63 75.25,35.01 75.36,35.12 75.58,35.12 75.69,35.01 75.69,34.63 75.79,34.52 76.27,34.52 76.51,34.76 76.51,35.44 76.8,35.74 79.37,35.74 80.25,36.62 84.75,36.62 87.66,39.53 87.82,39.53 88.29,39.07 88.44,39.07 88.59,39.22 88.59,39.38 88.13,39.84 88.13,40 88.3,40.16 88.67,40.16 89.16,39.68 89.37,39.68 93.37,43.68 94.93,43.68 97.88,46.63 101.78,46.63 103.31,48.16
  BOTTOM w0.076: UC1.AU30 115.5,51.59 v2(115.5,51.66)
  BOTTOM w0.102: JDIMM2.207 63.15,33.08 v2(63.01,33.21)
DDR_B_D43: length 70.2
  IN3 w0.076: 103.08,47.64 104.3,48.85 111.25,48.85 113.52,51.12 115.47,51.12 116.01,51.66 v2(116.1,51.66)
  IN3 w0.109: 103.08,47.64 101.74,46.3 98.02,46.3 94.93,43.21 93.36,43.21 88.69,38.54 88.35,38.54 87.87,39.03 87.62,39.03 84.89,36.29 81.09,36.29 80.93,36.13 80.93,35.49 80.85,35.41 80.57,35.41 80.48,35.49 80.48,35.76 80.37,35.87 80.15,35.87 80.05,35.76 80.05,35.54 79.91,35.41 77.04,35.41 76.83,35.21 76.83,34.62 76.4,34.19 69.38,34.19 68.78,33.59 67.37,33.59 66.44,32.66 64.97,32.66 64.86,32.77 64.86,32.96 64.75,33.07 64.53,33.07 64.42,32.96 64.42,32.77 64.31,32.66 64.1,32.66 63.99,32.77 63.99,32.96 63.88,33.07 63.66,33.07 63.55,32.96 63.55,32.77 63.44,32.66 61.66,32.66 61.49,32.83 v2(61.49,33.21)
  BOTTOM w0.076: UC1.AT30 116.45,51.2 v2(116.1,51.66)
  BOTTOM w0.102: JDIMM2.203 62.35,34.08 v2(61.49,33.21)
DDR_B_D44: length 71.2
  IN3 w0.076: v2(116.74,53.46) 116.38,53.82 115.88,53.82 115.73,53.97 115.03,53.97 114.74,53.67 113.31,53.67 110.09,50.46 103.4,50.46 101.61,48.68
  IN3 w0.109: v2(61.49,36.2) 61.9,35.79 63.18,35.79 63.62,36.23 64.3,36.23 64.41,36.12 64.41,35.4 64.52,35.29 65.06,35.29 65.17,35.4 65.17,36.12 65.28,36.23 67.38,36.23 67.53,36.38 67.53,36.68 67.7,36.86 68.51,36.86 69.58,37.93 70.39,37.93 70.67,37.65 77.31,37.65 77.98,38.31 79.14,38.31 79.34,38.52 83.96,38.52 88.27,42.82 88.42,42.82 89.04,42.2 89.2,42.2 89.35,42.35 89.35,42.51 89.02,42.84 89.02,42.99 89.17,43.15 89.33,43.15 89.66,42.82 89.82,42.82 92.62,45.62 94.18,45.62 97.24,48.68 101.61,48.68
  BOTTOM w0.076: UC1.AR33 116.88,53.28 v2(116.74,53.46)
  BOTTOM w0.102: v2(61.49,36.2) 62.37,37.08 JDIMM2.191
DDR_B_D45: length 72.1
  IN3 w0.076: v2(117.37,53.46) 116.82,54.02 115.93,54.02 115.82,54.14 114.95,54.14 114.65,53.84 113.24,53.84 110.03,50.63 103.33,50.63 101.7,49 101.66,49
  IN3 w0.109: v2(63.01,36.2) 63.37,36.55 66.94,36.55 67.57,37.18 68.37,37.18 69.45,38.26 70.59,38.26 70.7,38.15 70.7,38.08 70.81,37.97 76.07,37.97 76.18,38.08 76.18,38.15 76.29,38.26 76.51,38.26 76.61,38.15 76.61,38.08 76.72,37.97 77.18,37.97 78.05,38.84 78.46,38.84 78.66,38.64 79,38.64 79.21,38.84 83.83,38.84 88.38,43.4 88.54,43.4 88.67,43.26 88.83,43.26 88.98,43.42 88.98,43.57 88.85,43.71 88.85,43.86 89,44.01 89.16,44.01 89.78,43.39 89.93,43.39 90.09,43.55 90.09,43.7 89.46,44.32 89.46,44.48 89.63,44.65 89.79,44.65 90.41,44.02 90.56,44.02 90.72,44.18 90.72,44.33 90.1,44.95 90.1,45.11 90.25,45.26 90.41,45.26 91.03,44.64 91.18,44.64 91.34,44.8 91.34,44.95 90.71,45.57 90.71,45.73 90.93,45.94 91.18,45.94 91.66,45.46 92,45.46 92.48,45.94 94.05,45.94 97.11,49 101.66,49
  BOTTOM w0.076: UC1.AP33 117.52,53.28 v2(117.37,53.46)
  BOTTOM w0.102: v2(63.01,36.2) 63.14,36.08 JDIMM2.195
DDR_B_D46: length 70.6
  IN3 w0.076: 103.03,47.3 104.41,48.69 111.32,48.69 112.32,49.69 112.33,49.69 113.58,50.94 115.55,50.94 115.88,51.28 116.33,51.28 116.71,51.66 v2(116.74,51.66)
  IN3 w0.109: 103.03,47.3 101.69,45.97 98.15,45.97 95.07,42.89 93.49,42.89 88.72,38.11 88.32,38.11 87.89,38.54 87.59,38.54 85.02,35.97 81.4,35.97 81.25,35.82 81.25,35.36 80.98,35.08 79.83,35.08 79.32,34.57 77.46,34.57 76.76,33.87 69.52,33.87 68.92,33.27 67.5,33.27 66.57,32.34 59.95,32.34 59.72,32.57 59.72,32.97 v2(59.97,33.21)
  BOTTOM w0.076: UC1.AR30 117.1,51.2 v2(116.74,51.66)
  BOTTOM w0.102: JDIMM2.204 58.21,33.83 58.28,33.75 59.43,33.75 v2(59.97,33.21)
DDR_B_D47: length 71.4
  IN3 w0.076: 110.26,47.81 111.13,47.81 112.51,49.19 112.51,49.56 113.72,50.76 115.62,50.76 115.96,51.1 116.44,51.1 116.57,51.23 116.94,51.23 v2(117.37,51.66)
  IN3 w0.109: 110.26,47.81 104.23,47.81 102.06,45.64 98.29,45.64 95.21,42.56 93.63,42.56 88.76,37.69 88.25,37.69 87.85,38.1 87.61,38.1 85.16,35.64 81.78,35.64 81.58,35.44 81.58,35.13 81.21,34.76 79.97,34.76 79.46,34.25 77.6,34.25 76.34,32.99 69.1,32.99 68.41,32.31 67.39,32.31 67.1,32.01 58.63,32.01 58.44,32.2 v2(58.44,33.21)
  BOTTOM w0.076: UC1.AP30 117.75,51.2 v2(117.37,51.66)
  BOTTOM w0.102: JDIMM2.208 58.05,32.83 v2(58.44,33.21)
DDR_B_D48: length 70.6
  IN3 w0.076: v2(115.47,49.8) 115.28,49.99 114.07,49.99 113.49,49.41 113.49,48.41 112.38,47.3 111.61,47.3 111.4,47.08 108.01,47.08 108,47.07 104.74,47.07 103.59,45.92 103.59,45.2 102.38,43.99
  IN3 w0.109: 102.38,43.99 99.3,43.99 96.28,40.97 94.29,40.97 89.12,35.81 87.57,35.81 85.82,34.05 84.25,34.05 84.04,33.84 84.04,32.74 83.36,32.06 77.67,32.06 77,31.4 70.15,31.4 68.8,30.05 64.92,30.05 64.79,30.18 58.61,30.18 58.32,30.48 58.32,31.12 v2(58.44,31.24)
  BOTTOM w0.076: UC1.AU27 115.47,49.79 115.47,49.8 v2(115.47,49.8)
  BOTTOM w0.102: JDIMM2.216 58.02,30.83 v2(58.44,31.24)
DDR_B_D49: length 71.3
  IN3 w0.076: 103.41,45.4 103.41,45.97 104.67,47.23 107.93,47.23 107.94,47.25 111.33,47.25 111.54,47.46 112.32,47.46 113.33,48.48 113.33,49.56 113.92,50.15 115.66,50.15 116.01,49.81 v2(116.1,49.81)
  IN3 w0.109: 103.41,45.4 102.33,44.32 99.16,44.32 96.13,41.3 94.15,41.3 89.05,36.19 87.5,36.19 85.68,34.38 83.88,34.38 83.71,34.21 83.71,32.88 83.22,32.39 77.53,32.39 76.87,31.73 70.01,31.73 68.66,30.38 65.06,30.38 64.92,30.51 61.02,30.51 60.91,30.62 60.91,30.68 60.8,30.79 60.58,30.79 60.48,30.68 60.48,30.62 60.37,30.51 60.13,30.51 59.97,30.67 v2(59.97,31.24)
  BOTTOM w0.076: UC1.AT27 v2(116.1,49.81)
  BOTTOM w0.102: JDIMM2.212 59.39,31.83 v2(59.97,31.24)
DDR_B_D50: length 69.6
  IN3 w0.076: v2(116.1,48.91) 115.96,48.91 115.56,48.51 114.53,48.51 113.02,47 113.02,46.61 112.05,45.64 110.48,45.64 109.02,44.19 106.29,44.19 105.6,43.49
  IN3 w0.109: 105.6,43.49 104.29,42.19 100.08,42.19 97.28,39.39 95.2,39.39 89.93,34.11 88.1,34.11 84.03,30.04 80.5,30.04 80.39,29.93 80.39,29.42 80.29,29.31 80.07,29.31 79.96,29.42 79.96,29.93 79.85,30.04 79.63,30.04 79.52,29.93 79.52,29.29 79.41,29.18 79.19,29.18 79.08,29.29 79.08,29.93 78.97,30.04 78.76,30.04 78.65,29.93 78.65,29.29 78.54,29.18 78.32,29.18 78.21,29.29 78.21,29.93 78.1,30.04 77.86,30.04 77.15,29.32 76.61,29.32 75.88,28.59 69.56,28.59 68.58,27.61 63.16,27.61 v2(63.01,27.46)
  BOTTOM w0.076: v2(116.1,48.91) 116.1,48.89 UC1.AT25
  BOTTOM w0.102: JDIMM2.225 63.6,28.58 63.01,27.99 v2(63.01,27.46)
DDR_B_D51: length 69.3
  IN3 w0.076: v2(115.43,48.89) 114.68,48.89 112.85,47.07 112.85,46.68 111.98,45.81 110.41,45.81 109.38,44.78 106.6,44.78 105.44,43.62
  IN3 w0.109: v2(61.49,27.46) 61.49,27.87 61.72,28.1 65,28.1 65.17,27.93 67.44,27.93 67.93,28.43 68.94,28.43 69.72,29.21 70.26,29.21 70.55,28.92 71.34,28.92 71.45,29.02 71.45,29.54 71.55,29.65 71.77,29.65 71.88,29.54 71.88,29.02 71.99,28.92 75.75,28.92 76.48,29.65 77.01,29.65 77.73,30.36 83.89,30.36 88.09,34.56 89.91,34.56 95.07,39.72 96.79,39.72 99.59,42.52 104.34,42.52 105.44,43.62
  BOTTOM w0.076: UC1.AU25 115.8,48.49 115.43,48.87 v2(115.43,48.89)
  BOTTOM w0.102: v2(61.49,27.46) 61.9,27.06 63.18,27.06 63.7,27.58 JDIMM2.229
DDR_B_D52: length 71.7
  IN3 w0.076: v2(117.37,49.81) 116.99,50.19 115.89,50.19 115.76,50.32 113.78,50.32 113.16,49.7 113.16,48.59 112.2,47.63 111.47,47.63 111.26,47.42 107.85,47.42
  IN3 w0.109: v2(61.49,31.24) 61.9,30.83 65.33,30.83 65.46,30.7 68.53,30.7 69.88,32.05 76.73,32.05 77.4,32.71 79.76,32.71 80,32.95 80.29,32.95 80.53,32.71 80.77,32.71 80.88,32.82 80.88,33.03 80.99,33.14 81.21,33.14 81.32,33.03 81.32,32.82 81.43,32.71 81.64,32.71 81.75,32.82 81.75,33.03 81.86,33.14 82.08,33.14 82.19,33.03 82.19,32.82 82.3,32.71 83.09,32.71 83.39,33.01 83.39,34.52 83.57,34.7 85.55,34.7 87.56,36.71 89.11,36.71 94.02,41.62 95.99,41.62 99.06,44.69 101.87,44.69 104.6,47.42 107.85,47.42
  BOTTOM w0.076: UC1.AP27 v2(117.37,49.81)
  BOTTOM w0.102: JDIMM2.211 62.32,32.08 v2(61.49,31.24)
DDR_B_D53: length 72.1
  IN3 w0.076: 110.01,47.61 111.17,47.61 112.68,49.12 112.68,49.47 113.69,50.48 115.85,50.48 115.96,50.37 117.45,50.37 v2(118.01,49.81)
  IN3 w0.109: 110.01,47.61 104.42,47.61 101.82,45.02 98.92,45.02 95.85,41.95 93.88,41.95 89.02,37.08 88,37.08 87.8,37.27 87.66,37.27 85.41,35.03 83.17,35.03 83.06,34.92 83.06,33.15 82.95,33.04 82.73,33.04 82.62,33.15 82.62,34.81 82.52,34.92 82.23,34.92 82.07,34.75 82.07,34.75 81.82,34.49 81.82,34.03 82.07,33.78 82.07,33.59 81.95,33.47 80.06,33.47 79.63,33.04 78.36,33.04 78.24,33.17 78.24,33.52 78.13,33.63 77.91,33.63 77.8,33.52 77.8,33.13 77.71,33.04 77.26,33.04 76.6,32.38 69.74,32.38 69.52,32.15 69.36,32.15 69.32,32.19 69.17,32.19 69.01,32.04 69.01,31.88 69.05,31.84 69.05,31.69 68.89,31.52 67.48,31.52 67.04,31.08 65.59,31.08 65.28,31.39 63.16,31.39 v2(63.01,31.24)
  BOTTOM w0.076: UC1.AN27 118.2,49.58 v2(118.01,49.81)
  BOTTOM w0.102: JDIMM2.215 63.18,31.08 v2(63.01,31.24)
DDR_B_D54: length 72
  IN3 w0.076: 105.21,42.54 106.33,43.66 108.96,43.66 110.61,45.31 112.19,45.31 113.35,46.47 113.35,46.86 114.61,48.13 115.72,48.13 115.97,48.37 117.49,48.37 v2(118.01,48.89)
  IN3 w0.109: v2(58.44,27.46) 59.18,26.73 67.15,26.73 67.43,26.45 68.34,26.45 69.08,27.19 75.67,27.19 76.45,27.97 79.25,27.97 79.72,28.44 80.63,28.44 81.57,29.39 84.3,29.39 88.37,33.46 90.2,33.46 95.47,38.74 97.55,38.74 100.34,41.53 104.19,41.53 105.21,42.54
  BOTTOM w0.076: UC1.AN25 v2(118.01,48.89)
  BOTTOM w0.102: JDIMM2.228 58.08,27.83 v2(58.44,27.46)
DDR_B_D55: length 71.3
  IN3 w0.076: v2(117.4,48.92) 117.03,48.54 115.88,48.54 115.66,48.32 114.57,48.32 113.18,46.93 113.18,46.54 112.12,45.48 110.55,45.48 109.09,44.02 106.41,44.02 105.56,43.18
  IN3 w0.109: v2(59.97,27.46) 60.38,27.05 63.66,27.05 63.89,27.28 68.71,27.28 69.7,28.27 76.02,28.27 76.61,28.85 80.58,28.85 81.44,29.71 84.16,29.71 88.24,33.79 90.06,33.79 95.34,39.06 97.42,39.06 100.21,41.86 104.24,41.86 105.56,43.18
  BOTTOM w0.076: v2(117.4,48.92) 117.47,48.85 117.75,48.56 UC1.AP25
  BOTTOM w0.102: v2(59.97,27.46) 58.6,28.83 JDIMM2.224
DDR_B_D56: length 72.5
  IN3 w0.076: v2(116.1,47.06) 116.03,47.06 115.63,47.47 115.32,47.47 114.9,47.05 114.9,46.82 114.38,46.3 114.23,46.3 112.75,44.82 111.33,44.82 108.92,42.41 107.13,42.41 104.98,40.26 104.61,40.26
  IN3 w0.109: v2(59.97,25.82) 60.78,25.01 69.38,25.01 70.22,25.85 76.66,25.85 76.85,25.67 79.39,25.67 79.49,25.77 79.49,25.99 79.6,26.1 79.82,26.1 79.93,25.99 79.93,25.77 80.04,25.67 80.26,25.67 80.37,25.77 80.37,25.99 80.48,26.1 80.7,26.1 80.81,25.99 80.81,25.77 80.91,25.67 81.4,25.67 82.23,26.49 82.23,27.9 82.45,28.12 84.82,28.12 88.9,32.19 90.72,32.19 96,37.47 98.17,37.47 100.96,40.26 104.61,40.26
  BOTTOM w0.076: v2(116.1,47.06) UC1.AT22
  BOTTOM w0.102: JDIMM2.232 58.97,26.83 v2(59.97,25.82)
DDR_B_D57: length 71.8
  IN3 w0.076: v2(115.45,47.05) 115.37,47.05 114.42,46.11 114.28,46.11 112.82,44.65 111.4,44.65 108.84,42.1 107.05,42.1 104.89,39.93 104.55,39.93
  IN3 w0.109: v2(58.44,25.82) 58.44,24.89 58.65,24.69 58.88,24.69 58.99,24.8 58.99,25.29 59.1,25.4 59.32,25.4 59.43,25.29 59.43,24.8 59.54,24.69 63.6,24.69 64.12,24.17 68.99,24.17 69.72,24.89 76.48,24.89 76.94,25.34 81.54,25.34 82.55,26.36 82.55,27.28 83.07,27.79 84.96,27.79 88.86,31.7 90.69,31.7 96.14,37.14 98.35,37.14 101.15,39.93 104.55,39.93
  BOTTOM w0.076: v2(115.45,47.05) 115.45,47.05 115.8,46.7 UC1.AU22
  BOTTOM w0.102: v2(58.44,25.82) 58.44,25.83 JDIMM2.236
DDR_B_D58: length 70.8
  IN3 w0.076: v2(115.45,46.17) 114.9,45.62 114.48,45.62 112.33,43.47 110.91,43.47 108.44,40.99 108.44,40.86 107.49,39.91 105.66,39.91 104.35,38.61
  IN3 w0.109: 104.35,38.61 103.99,38.24 101.54,38.24 99.17,35.87 97.51,35.87 92.09,30.45 91.25,30.45 91.14,30.34 91.14,29.89 91.04,29.78 90.82,29.78 90.71,29.89 90.71,30.34 90.6,30.45 90.38,30.45 90.27,30.34 90.27,29.89 90.16,29.78 89.94,29.78 89.83,29.89 89.83,30.34 89.72,30.45 89.49,30.45 81.48,22.44 81.1,22.44 80.99,22.55 80.99,23.1 80.88,23.21 80.67,23.21 80.56,23.1 80.56,22.55 80.45,22.44 80.23,22.44 80.12,22.55 80.12,23.1 80.01,23.21 79.79,23.21 79.68,23.1 79.68,22.55 79.57,22.44 78.4,22.44 78.29,22.55 78.29,22.72 78.18,22.83 77.96,22.83 77.85,22.72 77.85,22.55 77.74,22.44 77.47,22.44 77.36,22.55 77.36,22.72 77.25,22.83 77.03,22.83 76.93,22.72 76.93,22.55 76.82,22.44 70.97,22.44 70.59,22.83 63.06,22.83 v2(63.01,22.78)
  BOTTOM w0.076: UC1.AU21 115.8,45.82 v2(115.45,46.17)
  BOTTOM w0.102: v2(63.01,22.78) 63.22,22.58 JDIMM2.249
DDR_B_D59: length 71.5
  IN3 w0.076: v2(116.1,46.17) 115.98,46.17 115.26,45.45 114.55,45.45 111.07,41.97 109.65,41.97 108.6,40.92 108.6,40.8 107.53,39.72 105.84,39.72 104.16,38.04 103.98,38.04
  IN3 w0.109: 103.98,38.04 103.8,37.86 101.62,37.86 99.3,35.54 97.65,35.54 92.15,30.04 91.99,30.04 91.93,30.11 91.77,30.11 91.62,29.95 91.62,29.8 91.68,29.73 91.68,29.58 91.56,29.45 89.79,29.45 89.51,29.73 89.23,29.73 81.62,22.12 70.16,22.12 70.05,22.23 70.05,22.38 69.94,22.49 69.73,22.49 69.62,22.38 69.62,22.23 69.51,22.12 69.29,22.12 69.18,22.23 69.18,22.38 69.07,22.49 68.85,22.49 68.74,22.38 68.74,22.23 68.5,21.98 67.63,21.98 67.52,22.09 67.52,22.28 67.41,22.39 67.19,22.39 67.08,22.28 67.08,22.09 66.97,21.98 65.26,21.98 65.01,22.23 62.04,22.23 v2(61.49,22.78)
  BOTTOM w0.076: UC1.AT21 116.45,45.82 v2(116.1,46.17)
  BOTTOM w0.102: v2(61.49,22.78) 62.29,23.58 JDIMM2.245
DDR_B_D60: length 73.3
  IN3 w0.076: 105.06,42.03 106.37,43.34 109.39,43.34 111.19,45.15 112.26,45.15 113.51,46.41 113.51,46.79 114.52,47.8 115.8,47.8 115.95,47.65 117.42,47.65 v2(118.01,47.06)
  IN3 w0.109: 105.06,42.03 103.93,40.91 100.6,40.91 97.81,38.12 95.73,38.12 90.45,32.84 88.63,32.84 84.55,28.77 81.83,28.77 80.47,27.42 80.35,27.42 80.23,27.3 80.23,26.89 80.15,26.81 79.86,26.81 79.78,26.89 79.78,27.24 79.67,27.35 79.41,27.35 79.3,27.24 79.3,26.92 79.19,26.81 78.97,26.81 78.86,26.92 78.86,27.24 78.75,27.35 78.54,27.35 78.43,27.24 78.43,26.92 78.32,26.81 78.1,26.81 77.99,26.92 77.99,27.24 77.88,27.35 77.66,27.35 77.55,27.24 77.55,26.92 77.44,26.81 77.22,26.81 77.12,26.92 77.12,27.24 77.01,27.35 76.77,27.35 76.6,27.18 76.6,26.72 76.45,26.57 70.02,26.57 69.75,26.3 69.65,26.3 69.43,26.51 69.28,26.51 69.12,26.36 69.12,26.2 69.31,26.02 69.31,25.86 69.11,25.67 68.07,25.67 67.9,25.83 67.63,25.83 67.47,25.67 67.19,25.67 67.03,25.83 66.76,25.83 66.59,25.67 65.22,25.67 65.11,25.77 65.11,26 65,26.11 64.78,26.11 64.67,26 64.67,25.77 64.56,25.67 64.34,25.67 64.23,25.77 64.23,26 64.12,26.11 63.91,26.11 63.8,26 63.8,25.77 63.69,25.67 63.17,25.67 v2(63.01,25.82)
  BOTTOM w0.076: v2(118.01,47.06) UC1.AN22
  BOTTOM w0.102: v2(63.01,25.82) 63.26,25.58 JDIMM2.237
DDR_B_D61: length 73.8
  IN3 w0.076: v2(117.37,47.06) 116.97,47.47 115.88,47.47 115.71,47.63 114.59,47.63 113.68,46.73 113.68,46.34 112.33,44.98 111.26,44.98 109.18,42.9 107.38,42.9 105.93,41.44 104.95,41.44
  IN3 w0.109: v2(61.49,25.82) 61.49,25.46 61.61,25.34 69.25,25.34 70.16,26.25 76.76,26.25 77,26.49 77.24,26.49 77.35,26.38 77.35,26.1 77.46,25.99 77.67,25.99 77.78,26.1 77.78,26.38 77.89,26.49 81.76,26.49 81.9,26.63 81.9,26.86 81.79,26.97 80.92,26.97 80.82,27.08 80.82,27.3 80.92,27.41 81.79,27.41 81.9,27.52 81.9,28.1 82.25,28.45 84.69,28.45 88.76,32.52 90.59,32.52 95.86,37.79 97.99,37.79 100.78,40.58 104.1,40.58 104.95,41.44
  BOTTOM w0.076: v2(117.37,47.06) UC1.AP22
  BOTTOM w0.102: v2(61.49,25.82) 61.9,26.23 63.21,26.23 63.56,26.58 JDIMM2.233
DDR_B_D62: length 72.2
  IN3 w0.076: v2(117.37,46.15) 117.37,45.97 117.22,45.81 115.88,45.81 115.35,45.29 114.62,45.29 111.11,41.78 109.82,41.78 107.34,39.3 105.69,39.3 104.33,37.94
  IN3 w0.109: 104.33,37.94 104.12,37.73 104.03,37.73 103.84,37.54 101.76,37.54 99.44,35.22 97.78,35.22 91.69,29.13 89.09,29.13 81.75,21.79 68.77,21.79 68.63,21.65 65.13,21.65 64.88,21.9 61.88,21.9 61.5,22.28 60.46,22.28 v2(59.97,22.78)
  BOTTOM w0.076: UC1.AP21 v2(117.37,46.15)
  BOTTOM w0.102: v2(59.97,22.78) 59.51,22.33 JDIMM2.250
DDR_B_D63: length 73.2
  IN3 w0.076: 104.65,37.89 105.87,39.11 107.38,39.11 109.84,41.56 111.13,41.56 114.69,45.12 115.42,45.12 115.93,45.63 117.49,45.63 v2(118.01,46.15)
  IN3 w0.109: 104.65,37.89 103.97,37.21 103.92,37.21 103.92,37.21 101.89,37.21 99.57,34.89 97.92,34.89 91.83,28.8 89.22,28.8 81.89,21.47 68.9,21.47 68.77,21.33 64.99,21.33 64.74,21.58 61.62,21.58 61.24,21.95 60.33,21.95 60.11,22.17 59.86,22.17 59.64,21.95 59.27,21.95 v2(58.44,22.78)
  BOTTOM w0.076: UC1.AN21 v2(118.01,46.15)
  BOTTOM w0.102: v2(58.44,22.78) 57.89,23.33 JDIMM2.246
DDR_B_DQS0: length 72.9
  IN3 w0.076: 112.38,78.82 112.4,78.84 114.3,78.84 115.78,77.37 115.78,76.04 116.22,75.6 116.69,75.6 118.95,73.35 118.95,73.13 119.94,72.14 119.94,70.84 v2(120.48,70.3)
  IN3 w0.114: v2(60.4,78.66) 60.18,78.88 60.18,79.09 60.44,79.35 63.26,79.35 63.55,79.06 63.88,79.06 64.27,78.67 64.87,78.67 65.26,79.06 69.46,79.06 70.74,80.34 79.44,80.34 80.26,79.52 82.67,79.52 83.46,78.73 111.77,78.73 111.86,78.82 112.38,78.82
  BOTTOM w0.076: UC1.AH65 v2(120.48,70.3)
  BOTTOM w0.102: JDIMM2.34 57.72,78.33 57.87,78.47 58.01,78.47 58.66,77.82 59.88,77.82 60.16,78.1 60.16,78.42 v2(60.4,78.66)
DDR_B_DQS1: length 83.6
  IN3 w0.076: v2(120.97,77.6) 120.97,77.69 121.12,77.85 121.39,77.85 121.61,78.06 121.61,79.6 122.08,80.07 122.08,81.4 122.1,81.42 122.1,81.44
  IN3 w0.114: 122.1,81.44 122.1,83.11 119.42,85.78 118.29,85.78 113.97,90.1 109.73,90.1 104.99,85.36 81.84,85.36 81.72,85.48 77.28,85.48 77.08,85.29 67.43,85.29 66.47,84.33 64.18,84.33 63.29,83.43 61.67,83.43 61.56,83.54 61.56,83.66 v2(61.87,83.97)
  BOTTOM w0.076: UC1.AG70 121.53,73.5 121.53,73.31 121.46,73.24 121.35,73.24 121.29,73.3 121.23,73.43 121.23,73.65 121.27,73.73 121.27,74.01 121.21,74.14 121.21,74.26 121.25,74.34 121.27,74.37 121.27,74.64 121.27,74.69 121.27,74.88 121.28,74.89 121.28,74.94 121.3,74.96 121.3,76 120.55,76.75 120.55,77.78 120.65,77.88 120.88,77.88 120.97,77.79 v2(120.97,77.6)
  BOTTOM w0.102: v2(61.87,83.97) 61.6,84.24 61.6,84.44 61.78,84.62 62.74,84.62 63.06,84.3 63.06,84.16 63.5,83.72 63.73,83.72 63.88,83.58 JDIMM2.13
DDR_B_DQS2: length 65.9
  IN3 w0.076: v2(116.74,70.84) 116.87,70.97 116.87,71.18 116.82,71.23 114.66,71.23 113.84,72.05 113.83,72.05 113.78,72.1 113.78,72.55 111.86,74.48 104,74.48 103.28,75.2
  IN3 w0.114: v2(61.9,73.33) 61.9,73.33 61.63,73.33 61.58,73.38 61.58,73.87 61.85,74.14 62.15,74.14 62.45,73.85 63.15,73.85 63.45,74.14 63.76,74.14 63.89,74.01 63.89,73.55 64.12,73.32 68.7,73.32 70.57,75.19 79.27,75.19 80.05,74.41 86.13,74.41 86.39,74.67 86.39,75.05 86.54,75.2 103.28,75.2
  BOTTOM w0.076: UC1.AR65 117.1,70.47 v2(116.74,70.84)
  BOTTOM w0.102: v2(61.9,73.33) 61.84,73.33 61.62,73.55 61.62,73.72 61.79,73.88 62.74,73.88 63.41,73.22 63.73,73.22 63.88,73.08 JDIMM2.55
DDR_B_DQS3: length 66.3
  IN3 w0.076: v2(116.74,68.09) 116.42,68.41 116.41,68.41 116.4,68.43 115.12,68.43 115.08,68.39 113.86,68.39 112.75,69.5 112.05,69.5 112.05,69.5 112.05,69.51 111.39,70.16 109.88,70.16 109.46,70.58 104.09,70.58 103.33,71.35 103.29,71.35 103.28,71.36
  IN3 w0.114: 103.28,71.36 103.25,71.39 96.04,71.39 95.94,71.29 95.94,70.82 95.71,70.6 80.83,70.6 80.06,69.83 77.65,69.83 77.4,69.57 70.35,69.57 68.21,67.43 63.95,67.43 63.7,67.18 62.71,67.18 62.47,67.42 62.47,67.62 62.36,67.73 62.03,67.73 61.9,67.6 61.9,67.42 61.66,67.18 60.07,67.18 59.84,67.41 59.84,67.59 v2(59.56,67.87)
  BOTTOM w0.076: v2(116.74,68.09) 117.1,67.73 UC1.AR60
  BOTTOM w0.102: JDIMM2.76 57.72,67.83 57.87,67.97 58.27,67.97 58.79,68.49 59.69,68.49 59.83,68.35 59.83,68.14 v2(59.56,67.87)
DDR_B_DQS4: length 69.2
  IN3 w0.076: v2(116.8,56.21) 116.63,56.04 116.63,55.85 116.44,55.66 113.57,55.66 111.88,53.97 111.81,53.97 111.81,53.96 111.35,53.96 110.27,52.88 103.71,52.88 101.97,51.14 101.17,51.14 101.15,51.11 101.13,51.11
  IN3 w0.114: 101.13,51.11 96.23,51.11 93.23,48.11 90.11,48.11 82.95,40.95 77.17,40.95 77.13,40.91 70.73,40.91 70.19,40.37 63.78,40.37 63.69,40.28 63.69,39.72 63.21,39.24 61.45,39.24 61.11,39.58 v2(61.11,40.26)
  BOTTOM w0.076: v2(116.8,56.21) 117.11,55.82 UC1.AR38
  BOTTOM w0.102: v2(61.11,40.26) 61.31,40.06 61.31,39.75 61.59,39.47 62.81,39.47 63.47,40.13 63.82,40.13 63.88,40.08 JDIMM2.179
DDR_B_DQS5: length 70.5
  IN3 w0.076: 100.62,47.37 100.7,47.37 100.72,47.35 101.59,47.35 103.59,49.35 110.29,49.35 111.32,50.38 111.32,50.47 111.81,50.96 112.65,50.96 113.95,52.25 114.26,52.25 115.1,53.09 116.34,53.09 116.55,52.89 116.55,52.74 v2(116.74,52.55)
  IN3 w0.114: v2(60.35,35) 60.18,34.84 60.18,34.58 60.64,34.12 66.1,34.12 66.92,34.95 68.65,34.95 69.55,35.85 75.89,35.85 76.5,36.46 79.06,36.46 79.95,37.35 84.45,37.35 87.99,40.89 89.55,40.89 93.09,44.44 94.65,44.44 97.59,47.37 100.62,47.37
  BOTTOM w0.076: UC1.AR32 v2(116.74,52.55)
  BOTTOM w0.102: v2(60.35,35) 60.07,34.73 60.07,34.5 59.84,34.26 58.68,34.26 57.98,34.97 57.87,34.97 57.72,34.83 JDIMM2.200
DDR_B_DQS6: length 71
  IN3 w0.076: v2(116.74,49.81) 116.89,49.81 117,49.69 117,49.53 116.9,49.43 116.33,49.43 116.33,49.44 115.33,49.44 114.95,49.82 114.18,49.82 113.66,49.3 113.66,48.34 112.13,46.81 112.13,46.64 111.69,46.2 110.11,46.2 109.33,45.41 106.46,45.41 104.26,43.22 103.41,43.22 103.38,43.25
  IN3 w0.114: v2(61.87,29.34) 61.76,29.34 61.62,29.21 61.62,28.93 61.73,28.82 65.31,28.82 65.47,28.66 67.13,28.66 67.63,29.16 68.64,29.16 69.85,30.38 76.71,30.38 77.43,31.09 81.69,31.09 81.79,31.19 83.05,31.19 83.15,31.09 83.59,31.09 87.79,35.29 89.61,35.29 94.77,40.45 96.49,40.45 99.3,43.26 100.64,43.26 100.64,43.25 103.38,43.25
  BOTTOM w0.076: v2(116.74,49.81) 117.1,49.44 UC1.AR27
  BOTTOM w0.102: JDIMM2.221 63.88,29.58 63.73,29.72 63.16,29.72 62.93,29.94 61.71,29.94 61.6,29.83 61.6,29.61 v2(61.87,29.34)
DDR_B_DQS7: length 72.1
  IN3 w0.076: v2(116.74,46.17) 116.74,46.47 116.67,46.53 115.31,46.53 114.56,45.78 114.41,45.78 112.38,43.75 110.96,43.75 107.91,40.7 106.12,40.7 104.18,38.76 103.38,38.76
  IN3 w0.114: v2(59.59,24.11) 59.85,23.85 59.85,23.59 60.09,23.34 77.35,23.34 77.73,23.72 82.03,23.72 89.27,30.97 91.88,30.97 97.32,36.41 98.65,36.41 101,38.76 103.38,38.76
  BOTTOM w0.076: UC1.AR21 116.74,46.15 v2(116.74,46.17)
  BOTTOM w0.102: JDIMM2.242 57.72,24.33 57.87,24.47 58.16,24.47 58.41,24.72 59.71,24.72 59.85,24.58 59.85,24.37 v2(59.59,24.11)
DDR_B_DQS#0: length 72.9
  IN3 w0.076: 112.38,79.03 112.4,79.03 112.42,79.01 114.37,79.01 115.95,77.43 115.95,76.12 116.29,75.78 116.77,75.78 119.12,73.42 119.12,73.2 120.11,72.21 120.11,70.98 120.16,70.93 v2(120.48,70.93)
  IN3 w0.114: v2(59.64,78.66) 59.9,78.66 59.97,78.74 59.97,79.18 60.35,79.56 63.34,79.56 63.63,79.27 63.97,79.27 64.35,78.88 64.78,78.88 65.17,79.27 69.37,79.27 70.65,80.55 79.52,80.55 80.35,79.73 82.75,79.73 83.54,78.94 111.69,78.94 111.78,79.03 112.38,79.03
  BOTTOM w0.076: UC1.AH66 v2(120.48,70.93)
  BOTTOM w0.102: JDIMM2.32 57.72,78.83 57.87,78.68 58.1,78.68 58.75,78.04 59.79,78.04 59.95,78.19 59.95,78.35 v2(59.64,78.66)
DDR_B_DQS#1: length 83.7
  IN3 w0.076: 121.89,81.44 121.89,81.42 121.91,81.4 121.91,80.14 121.44,79.67 121.44,78.13 121.32,78.01 121.21,78.01 v2(120.97,78.25)
  IN3 w0.114: 121.89,81.44 121.89,83.02 119.34,85.57 118.2,85.57 113.89,89.89 109.81,89.89 105.08,85.15 81.75,85.15 81.64,85.27 77.36,85.27 77.17,85.07 67.52,85.07 66.56,84.11 64.27,84.11 63.38,83.22 61.58,83.22 61.35,83.46 61.35,83.73 v2(61.11,83.97)
  BOTTOM w0.076: v2(120.97,78.25) 120.76,78.05 120.58,78.05 120.38,77.85 120.38,76.68 121.13,75.93 121.13,75.03 121.11,75.01 121.11,74.96 121.1,74.95 121.1,74.75 121.1,74.41 121.05,74.3 121.05,74.1 121.1,73.97 121.1,73.76 121.07,73.68 121.07,73.39 121.15,73.21 121.24,73.12 121.4,72.96 UC1.AG69
  BOTTOM w0.102: JDIMM2.11 63.88,84.08 63.73,83.93 63.59,83.93 63.27,84.25 63.27,84.39 62.83,84.83 61.69,84.83 61.38,84.53 61.38,84.24 v2(61.11,83.97)
DDR_B_DQS#2: length 66
  IN3 w0.076: 103.28,75.41 103.29,75.41 103.32,75.39 103.36,75.39 103.46,75.28 103.46,75.25 104.07,74.65 111.94,74.65 113.96,72.63 113.96,72.17 114.73,71.4 116.38,71.4 v2(116.74,71.75)
  IN3 w0.114: 103.28,75.41 86.45,75.41 86.18,75.14 86.18,74.76 86.04,74.62 80.13,74.62 79.36,75.4 70.48,75.4 68.61,73.53 64.2,73.53 64.1,73.64 64.1,74.1 63.85,74.35 63.36,74.35 63.06,74.06 62.54,74.06 62.24,74.35 61.77,74.35 61.37,73.95 61.37,73.57 v2(61.14,73.33)
  BOTTOM w0.076: v2(116.74,71.75) 117.1,71.39 UC1.AR66
  BOTTOM w0.102: v2(61.14,73.33) 61.41,73.61 61.41,73.81 61.7,74.1 62.83,74.1 63.5,73.43 63.73,73.43 63.88,73.58 JDIMM2.53
DDR_B_DQS#3: length 66.4
  IN3 w0.076: 103.43,71.51 103.44,71.5 103.44,71.47 104.16,70.75 109.54,70.75 109.96,70.34 111.45,70.34 112.12,69.67 112.82,69.67 113.93,68.56 115.01,68.56 115.05,68.6 116.33,68.6 v2(116.74,69.01)
  IN3 w0.114: 103.43,71.51 103.34,71.6 95.95,71.6 95.73,71.37 95.73,70.91 95.63,70.81 80.75,70.81 79.98,70.04 77.56,70.04 77.31,69.78 70.26,69.78 68.12,67.64 63.87,67.64 63.61,67.39 62.8,67.39 62.68,67.5 62.68,67.71 62.45,67.94 61.94,67.94 61.69,67.69 61.69,67.5 61.57,67.39 60.15,67.39 60.05,67.5 60.05,67.59 v2(60.32,67.87)
  BOTTOM w0.076: UC1.AR61 117.1,68.64 v2(116.74,69.01)
  BOTTOM w0.102: JDIMM2.74 57.72,68.33 57.87,68.18 58.18,68.18 58.7,68.7 59.78,68.7 60.05,68.43 60.05,68.14 v2(60.32,67.87)
DDR_B_DQS#4: length 69.2
  IN3 w0.076: v2(116.1,56.21) 116.35,56.21 116.47,56.09 116.47,55.92 116.37,55.82 113.5,55.82 111.81,54.14 111.28,54.14 110.19,53.04 103.64,53.04 101.9,51.31 101.17,51.31 101.15,51.33 101.13,51.33
  IN3 w0.114: v2(61.93,40.26) 61.69,40.26 61.32,39.89 61.32,39.67 61.54,39.45 63.12,39.45 63.48,39.81 63.48,40.37 63.69,40.58 70.1,40.58 70.64,41.12 77.04,41.12 77.08,41.16 82.86,41.16 90.02,48.32 93.14,48.32 96.15,51.33 101.13,51.33
  BOTTOM w0.076: v2(116.1,56.21) 116.31,56.18 116.48,55.96 UC1.AT38
  BOTTOM w0.102: JDIMM2.177 63.88,40.58 63.64,40.34 63.38,40.34 62.72,39.68 61.68,39.68 61.52,39.84 61.52,40.03 61.76,40.26 v2(61.93,40.26)
DDR_B_DQS#5: length 70.4
  IN3 w0.076: v2(116.1,52.55) 116.27,52.55 116.39,52.66 116.39,52.81 116.27,52.93 115.17,52.93 114.33,52.09 114.01,52.09 112.72,50.79 111.88,50.79 111.49,50.4 111.49,50.31 110.36,49.18 103.66,49.18 101.75,47.27 101.75,47.26 101.66,47.18 100.72,47.18 100.7,47.16 100.62,47.16
  IN3 w0.114: v2(59.59,35) 59.97,34.62 59.97,34.5 60.56,33.91 66.18,33.91 67.01,34.74 68.74,34.74 69.64,35.64 75.97,35.64 76.59,36.25 79.15,36.25 80.03,37.14 84.54,37.14 88.08,40.68 89.63,40.68 93.18,44.22 94.74,44.22 97.67,47.16 100.62,47.16
  BOTTOM w0.076: UC1.AT32 v2(116.1,52.55)
  BOTTOM w0.102: JDIMM2.198 57.72,35.33 57.87,35.18 58.07,35.18 58.77,34.48 59.75,34.48 59.86,34.59 59.86,34.73 v2(59.59,35)
DDR_B_DQS#6: length 71.1
  IN3 w0.076: 103.33,43.05 104.34,43.05 106.53,45.24 109.4,45.24 110.18,46.03 111.76,46.03 112.3,46.57 112.3,46.75 113.82,48.27 113.82,49.23 114.25,49.66 114.88,49.66 115.26,49.27 116.26,49.27 116.26,49.27 116.44,49.27 v2(116.79,48.92)
  IN3 w0.114: v2(61.11,29.34) 61.41,29.04 61.41,28.85 61.64,28.61 65.22,28.61 65.38,28.45 67.22,28.45 67.72,28.95 68.72,28.95 69.94,30.16 76.8,30.16 77.52,30.88 81.78,30.88 81.88,30.98 82.96,30.98 83.06,30.88 83.68,30.88 87.87,35.08 89.7,35.08 94.86,40.23 96.57,40.23 99.39,43.05 103.33,43.05
  BOTTOM w0.076: UC1.AR25 117.1,48.6 v2(116.79,48.92)
  BOTTOM w0.102: v2(61.11,29.34) 61.38,29.61 61.38,29.92 61.62,30.16 63.02,30.16 63.25,29.93 63.73,29.93 63.88,30.08 JDIMM2.219
DDR_B_DQS#7: length 72.2
  IN3 w0.076: 103.38,38.97 103.39,38.97 103.42,38.95 103.46,38.95 103.47,38.93 104.11,38.93 106.05,40.86 107.84,40.86 110.89,43.91 112.31,43.91 114.34,45.95 114.49,45.95 115.25,46.7 116.65,46.7 116.74,46.79 v2(116.74,47.08)
  IN3 w0.114: 103.38,38.97 100.92,38.97 98.56,36.62 97.23,36.62 91.79,31.18 89.19,31.18 81.94,23.94 77.65,23.94 77.26,23.55 60.18,23.55 60.06,23.68 60.06,23.82 v2(60.35,24.11)
  BOTTOM w0.076: UC1.AR22 117.04,46.68 116.74,47.06 v2(116.74,47.08)
  BOTTOM w0.102: JDIMM2.240 57.72,24.83 57.87,24.68 58.07,24.68 58.32,24.94 59.8,24.94 60.06,24.67 60.06,24.4 v2(60.35,24.11)
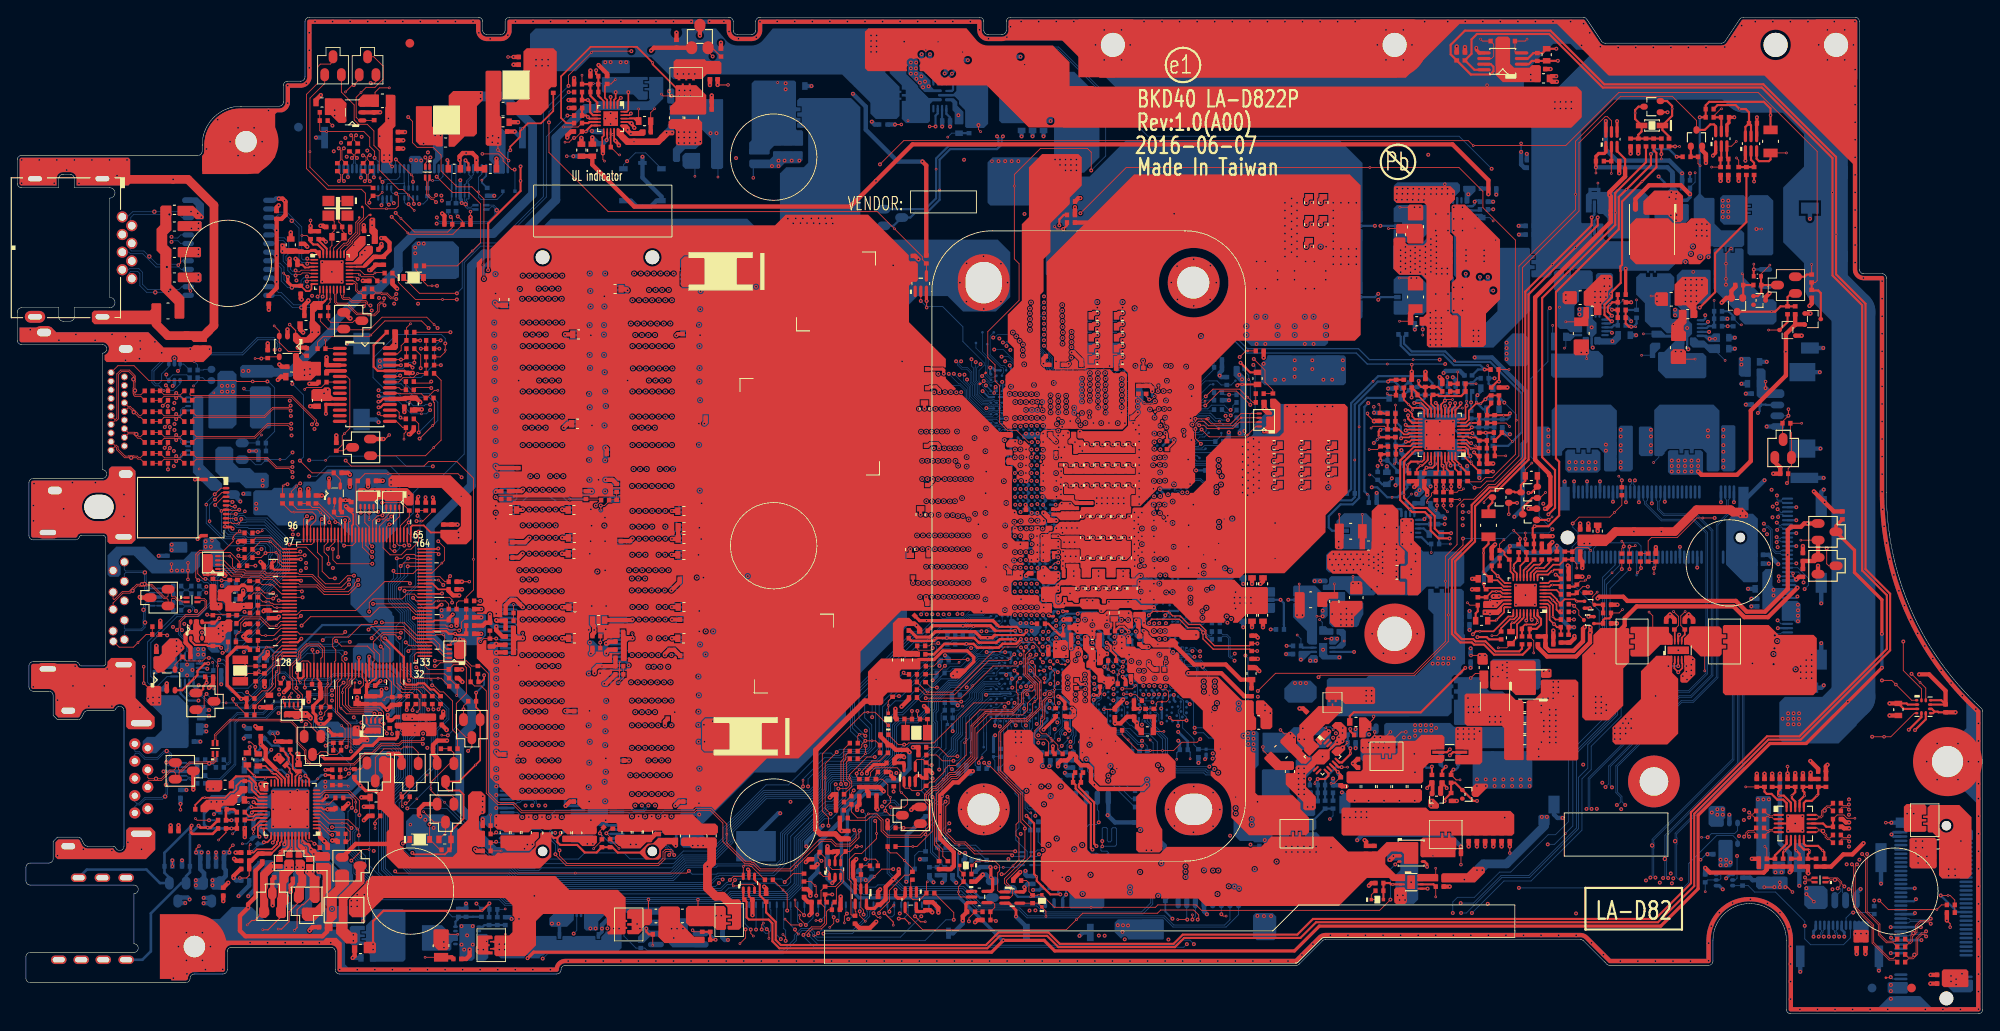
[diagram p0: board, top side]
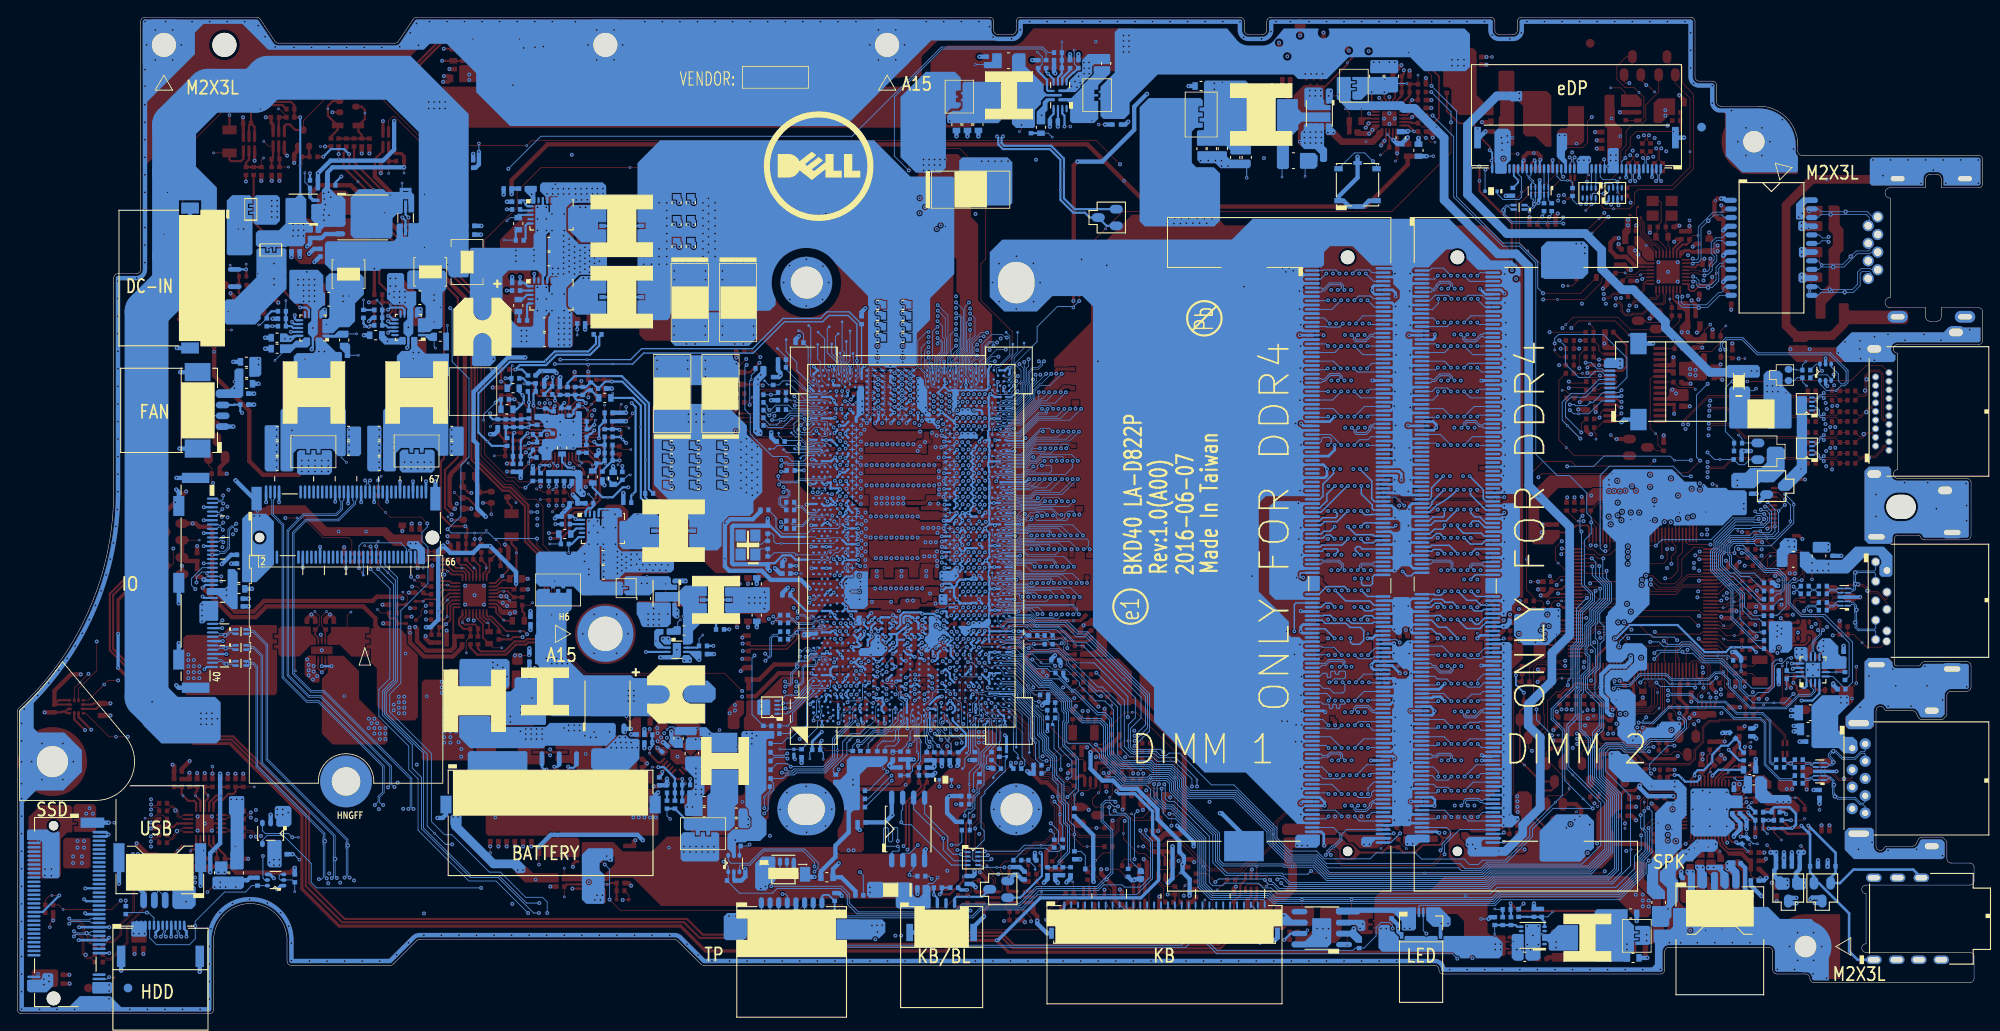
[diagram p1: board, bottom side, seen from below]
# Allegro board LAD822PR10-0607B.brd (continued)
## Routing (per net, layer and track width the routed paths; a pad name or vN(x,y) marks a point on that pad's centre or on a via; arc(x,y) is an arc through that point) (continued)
DDR_B_MA0: length 65.7
  IN3 w0.076: 103.41,59.12 103.8,59.12 104.55,59.88 109.19,59.88 v2(109.34,59.72)
  IN3 w0.175: v2(59.26,50.29) 59.7,50.74 62.69,50.74 63.12,51.17 64.83,51.17 65.01,50.99 65.01,50.57 65.18,50.39 65.53,50.39 65.71,50.57 65.71,50.99 65.88,51.17 66.24,51.17 66.41,50.99 66.41,50.65 66.66,50.39 69.85,50.39 70.37,50.91 70.37,51.55 71.06,52.23 71.37,52.23 71.55,52.06 71.55,51.98 71.72,51.81 72.07,51.81 72.25,51.98 72.25,52.06 72.42,52.23 72.78,52.23 72.95,52.06 72.95,51.98 73.13,51.81 73.48,51.81 73.65,51.98 73.65,52.06 73.83,52.23 74.18,52.23 74.35,52.06 74.35,51.98 74.53,51.81 74.88,51.81 75.05,51.98 75.05,52.06 75.23,52.23 75.81,52.23 76.18,51.86 82.48,51.86 87.4,56.78 91.5,56.78 91.94,57.23 91.94,58.25 92.16,58.47 102.32,58.47 102.97,59.12 103.41,59.12
  BOTTOM w0.076: v2(109.34,59.72) 109.57,59.5 111.58,59.5 111.68,59.4 112.89,59.4 113.16,59.66 UC1.BA46
  BOTTOM w0.17: JDIMM2.144 58.73,50.83 v2(59.26,50.29)
DDR_B_MA1: length 67.3
  IN3 w0.175: v2(62.29,53.28) 62.29,53.49 62.56,53.76 63.2,53.76 63.54,53.42 64.37,53.42 64.55,53.59 64.55,54.06 64.74,54.26 65.09,54.26 65.25,54.1 65.25,53.59 65.42,53.42 65.79,53.42 66.08,53.7 66.44,53.7 66.73,53.42 68.42,53.42 70.47,55.46 75.92,55.46 76.16,55.23 77.6,55.23 78.5,56.12 78.5,57.18 78.7,57.39 79.22,57.39 79.36,57.26 79.36,56.42 79.53,56.25 79.83,56.25 80,56.42 80,57.24 80.16,57.39 80.56,57.39 80.7,57.24 80.7,56.42 80.88,56.25 81.23,56.25 81.4,56.42 81.4,57.24 81.55,57.39 81.95,57.39 82.11,57.24 82.11,56.42 82.28,56.25 83.04,56.25 87.96,61.17 104.68,61.17 105.33,61.82 v2(105.33,61.92)
  BOTTOM w0.076: UC1.AY46 113.73,59.76 113.63,59.86 113.41,59.94 113.28,59.94 113.05,59.87 112.91,59.87 112.79,59.93 112.53,59.93 112.33,59.73 111.84,59.73 111.74,59.83 110.18,59.83 109.64,60.37 106.78,60.37 105.33,61.82 v2(105.33,61.92)
  BOTTOM w0.17: JDIMM2.133 63.76,53.58 63.57,53.77 62.78,53.77 v2(62.29,53.28)
DDR_B_MA2: length 67.1
  IN3 w0.175: v2(106.55,61.92) 106.15,62.33 104.08,62.33 103.83,62.08 87.59,62.08 83.45,57.95 82.68,57.95 82.33,58.3 78.32,58.3 77.59,57.56 77.59,56.5 77.28,56.19 76.75,56.19 76.62,56.32 76.62,56.65 76.18,57.09 75.45,57.09 75.21,56.85 71.01,56.85 70.53,56.37 70.09,56.37 68.88,55.16 64.28,55.16 63.78,54.67 58.43,54.67 58.26,54.49 58.26,53.94 58.42,53.78 58.99,53.78 59.24,53.53 v2(59.24,53.28)
  BOTTOM w0.076: UC1.AY47 114.01,60.06 113.58,60.06 113.42,60.11 113.28,60.11 113.06,60.05 112.94,60.05 112.86,60.08 112.83,60.1 112.46,60.1 112.26,59.89 111.92,59.89 111.82,59.99 110.29,59.99 109.66,60.62 107.91,60.62 106.6,61.92 v2(106.55,61.92)
  BOTTOM w0.17: JDIMM2.132 58.69,53.83 v2(59.24,53.28)
DDR_B_MA3: length 66.3
  IN3 w0.175: v2(60.76,53.28) 60.34,53.7 60.34,53.89 60.66,54.21 61,54.21 61.37,53.84 62,53.84 62.37,54.21 64.05,54.21 64.55,54.71 65.28,54.71 65.83,54.16 66.42,54.16 66.81,54.54 67.28,54.54 67.47,54.35 67.47,54.03 67.63,53.87 68.23,53.87 70.28,55.92 73.62,55.92 73.96,56.26 74.53,56.26 74.82,55.97 75.29,55.97 75.46,56.14 75.46,56.46 75.64,56.64 75.99,56.64 76.17,56.46 76.17,55.94 76.42,55.68 77.41,55.68 78.04,56.31 78.04,57.37 78.51,57.84 82.14,57.84 82.84,57.15 83.3,57.15 87.77,61.63 104.43,61.63 v2(104.72,61.92)
  BOTTOM w0.076: v2(104.72,61.92) 104.77,61.92 106.55,60.14 109.63,60.14 110.12,59.66 111.66,59.66 111.76,59.56 112.58,59.56 UC1.BB46
  BOTTOM w0.17: v2(60.76,53.28) 61.73,54.25 63.79,54.25 63.96,54.08 JDIMM2.131
DDR_B_MA4: length 66.3
  IN3 w0.175: v2(107.34,61.92) 107.34,62.27 106.75,62.86 104.09,62.86 103.95,63 87.21,63 86.7,62.48 85.96,62.48 85.44,63 84.88,63 82.01,60.13 78.7,60.13 78.3,59.73 78.3,59.56 77.58,58.84 76.74,58 76.39,58 76.21,58.18 76.21,58.5 76.04,58.67 71.01,58.67 70.7,58.36 70.7,58.28 68.5,56.07 65.74,56.07 65.55,56.27 65.55,56.69 65.23,57.02 64.25,57.02 63.89,56.66 63.89,56.3 63.71,56.12 61.93,56.12 61.76,55.94 61.76,55.74 61.58,55.57 61.23,55.57 61.06,55.74 61.06,55.94 60.88,56.12 59.83,56.12 59.66,55.94 59.66,55.49 v2(60.02,55.12)
  BOTTOM w0.076: UC1.BA47 113.44,60.55 113.21,60.55 113.2,60.55 113.2,60.56 113.2,60.56 113.11,60.59 112.91,60.59 112.82,60.56 112.34,60.56 112.21,60.68 110.12,60.68 109.91,60.89 108.42,60.89 107.39,61.92 v2(107.34,61.92)
  BOTTOM w0.17: JDIMM2.128 57.53,54.83 57.97,54.39 59.29,54.39 v2(60.02,55.12)
DDR_B_MA5: length 67.2
  IN3 w0.175: v2(60.78,56.56) 60.35,56.99 60.35,57.27 60.58,57.5 60.95,57.5 61.3,57.15 61.88,57.15 62.23,57.5 63.44,57.5 63.87,57.93 65.61,57.93 66.09,57.44 67.37,57.44 67.83,57.91 68.96,57.91 70.64,59.58 71.11,59.58 71.29,59.76 71.29,60.05 71.46,60.22 71.81,60.22 71.99,60.05 71.99,59.76 72.16,59.58 72.51,59.58 72.69,59.76 72.69,60.05 72.86,60.22 73.21,60.22 73.39,60.05 73.39,59.76 73.56,59.58 73.92,59.58 74.09,59.76 74.09,60.05 74.27,60.22 74.62,60.22 74.79,60.05 74.79,59.76 74.97,59.58 75.33,59.58 75.52,59.78 75.52,60.05 75.69,60.22 77.5,60.22 78.1,60.82 78.1,61.27 78.59,61.76 81.51,61.76 83.66,63.91 85.82,63.91 86.15,63.57 86.5,63.57 86.84,63.91 103.78,63.91 104.31,63.38 108.31,63.38 v2(109.78,61.92)
  BOTTOM w0.076: UC1.AY48 113.72,61.25 110.6,61.25 110.46,61.39 110.36,61.39 109.83,61.92 v2(109.78,61.92)
  BOTTOM w0.17: JDIMM2.126 57.72,55.33 58.05,55.66 60.11,55.66 60.78,56.33 v2(60.78,56.56)
DDR_B_MA6: length 65.5
  IN3 w0.076: v2(108.56,61.92) 108.19,61.55 107.12,61.55 106.94,61.72 106.94,62.29
  IN3 w0.175: v2(62.31,55.11) 62.31,55.41 62.52,55.62 64.17,55.62 64.35,55.79 64.35,56.39 64.52,56.56 64.87,56.56 65.05,56.39 65.05,55.79 65.23,55.62 68.69,55.62 70.38,57.31 75.02,57.31 75.26,57.55 76.93,57.55 78.14,58.75 78.6,58.75 78.75,58.91 78.75,59.55 78.89,59.68 79.45,59.68 79.64,59.48 79.64,58.94 79.83,58.75 80.16,58.75 80.34,58.93 80.34,59.48 80.54,59.68 80.87,59.68 81.04,59.51 81.04,58.93 81.22,58.75 81.58,58.75 81.75,58.92 81.75,59.37 81.94,59.56 82.26,59.56 82.45,59.37 82.45,58.82 82.87,58.4 83.26,58.4 87.4,62.54 102.84,62.54 102.9,62.59 106.64,62.59 106.94,62.29
  BOTTOM w0.076: v2(108.56,61.92) 108.61,61.92 109.47,61.06 110.11,61.06 110.32,60.84 112.3,60.84 112.42,60.72 112.79,60.72 112.88,60.76 112.89,60.76 113.14,60.76 113.23,60.72 113.44,60.72 113.52,60.75 113.52,60.75 113.62,60.79 113.67,60.89 113.63,60.99 UC1.BA48
  BOTTOM w0.17: JDIMM2.127 63.78,55.08 63.25,55.61 62.81,55.61 v2(62.31,55.11)
DDR_B_MA7: length 68.7
  IN3 w0.076: 114.27,62.09 117.01,62.09 v2(117.37,61.73)
  IN3 w0.175: 114.27,62.09 113.64,62.09 112.54,63.19 111.08,63.19 110.49,63.78 109.41,63.78 108.75,64.44 102.89,64.44 102.81,64.36 83.47,64.36 81.33,62.22 78.4,62.22 77.64,61.46 77.64,61.01 77.31,60.68 71.09,60.68 68.77,58.36 67.64,58.36 67.18,57.89 66.28,57.89 65.79,58.38 63.68,58.38 63.25,57.95 58.81,57.95 58.58,57.72 58.58,57.24 v2(59.26,56.56)
  BOTTOM w0.076: UC1.AP48 117.75,61.27 v2(117.37,61.73)
  BOTTOM w0.17: JDIMM2.122 57.61,56.33 57.66,56.38 57.66,56.38 58.35,57.06 59.01,57.06 59.26,56.81 v2(59.26,56.56)
DDR_B_MA8: length 63.8
  IN3 w0.175: v2(62.31,56.56) 62.31,56.88 62.45,57.02 63.61,57.02 64.06,57.47 65.42,57.47 65.91,56.98 66.63,56.98 67.04,56.57 67.35,56.57 67.76,56.98 68.77,56.98 70.26,58.48 70.26,58.57 70.82,59.13 75.76,59.13 75.94,59.3 75.94,59.59 76.11,59.77 76.46,59.77 76.64,59.59 76.64,59.3 76.81,59.13 77.22,59.13 77.85,59.75 77.85,59.92 78.55,60.63 78.55,61.08 78.78,61.31 79.31,61.31 79.48,61.13 79.48,60.76 79.66,60.59 80.01,60.59 80.18,60.76 80.18,61.13 80.36,61.31 80.71,61.31 80.88,61.13 80.88,60.76 81.06,60.59 81.41,60.59 81.59,60.76 81.59,61.19 81.87,61.48 82.12,61.48 82.29,61.3 82.54,61.3 82.79,61.55 82.79,61.8 82.61,61.97 82.61,62.22 82.86,62.47 83.11,62.47 83.28,62.3 83.53,62.3 83.78,62.54 83.78,62.79 83.61,62.96 83.61,63.21 83.85,63.45 85.63,63.45 86.15,62.93 86.51,62.93 87.03,63.45 103.87,63.45 104.2,63.12 108.2,63.12 109.17,62.16 v2(109.17,61.92)
  BOTTOM w0.076: v2(109.17,61.92) 109.22,61.92 109.92,61.22 110.35,61.22 110.53,61.04 112.42,61.04 112.46,60.99 UC1.BB48
  BOTTOM w0.17: v2(62.31,56.56) 62.31,56.33 62.52,56.12 63.46,56.12 64,55.58 JDIMM2.125
DDR_B_MA9: length 66
  IN3 w0.076: 114.14,62.97 117.02,62.97 v2(117.37,62.62)
  IN3 w0.175: 114.14,62.97 113.64,62.97 112.89,63.72 111.3,63.72 110.05,64.96 103.21,64.96 102.9,65.27 83.09,65.27 80.95,63.13 77.52,63.13 76.58,62.18 70.61,62.18 68.47,60.04 65.03,60.04 64.3,59.32 62.31,59.32 61.83,58.84 61.23,58.84 v2(60.78,58.39)
  BOTTOM w0.076: UC1.AP50 117.37,62.61 v2(117.37,62.62)
  BOTTOM w0.17: JDIMM2.121 63.9,56.58 63.4,57.07 62.1,57.07 v2(60.78,58.39)
DDR_B_MA10: length 67.5
  IN3 w0.076: v2(106.57,59.36) 106.22,59.71 104.62,59.71 103.76,58.86 103.41,58.86
  IN3 w0.175: 103.41,58.86 103.09,58.86 102.24,58.02 92.66,58.02 92.39,57.75 92.39,57.04 91.68,56.33 87.58,56.33 82.66,51.41 76.06,51.41 75.57,50.92 71.02,50.92 70.04,49.94 64.99,49.94 64.22,50.71 63.31,50.71 62.88,50.28 60.64,50.28 60.2,49.85 58.71,49.85 57.99,49.13 57.99,48.74 58.25,48.48 58.75,48.48 v2(59.19,48.92)
  BOTTOM w0.076: v2(106.57,59.36) 106.98,59.76 108.71,59.76 109.14,59.33 111.5,59.33 111.6,59.23 113.33,59.23 113.56,59.47 114.06,59.47 114.26,59.57 114.45,59.76 UC1.AW46
  BOTTOM w0.17: v2(59.19,48.92) 58.6,48.33 JDIMM2.146
DDR_B_MA11: length 69.9
  IN3 w0.076: v2(118.01,61.69) 118.37,62.05 118.37,62.83 118.05,63.14 115.6,63.14 115.43,63.31 115.09,63.31
  IN3 w0.175: 115.09,63.31 113.76,63.31 113.08,63.98 111.41,63.98 109.51,65.88 104.52,65.88 104.37,65.73 82.9,65.73 80.76,63.58 77.34,63.58 76.39,62.64 70.42,62.64 68.72,60.94 66.3,60.94 65.86,60.5 64.84,60.5 64.12,59.77 62.12,59.77 61.64,59.29 59.99,59.29 59.72,59.56 59.4,59.56 58.96,59.11 58.96,58.69 v2(59.26,58.39)
  BOTTOM w0.076: v2(118.01,61.69) UC1.AN48
  BOTTOM w0.17: v2(59.26,58.39) 59.26,58 58.79,57.53 58.18,57.53 57.48,56.83 JDIMM2.120
DDR_B_MA12: length 68.4
  IN3 w0.076: 113.38,62.86 113.93,62.31 114.98,62.31 115.03,62.26 117.66,62.26 v2(118.01,62.61)
  IN3 w0.175: 113.38,62.86 112.78,63.45 111.19,63.45 110.6,64.04 109.52,64.04 108.86,64.7 102.9,64.7 102.78,64.82 83.28,64.82 81.14,62.67 77.71,62.67 77.19,62.15 77.19,61.35 76.97,61.13 76.29,61.13 76.15,61.27 76.15,61.54 75.96,61.73 70.8,61.73 70.52,61.45 70.52,61.2 70.64,61.08 70.64,61.08 70.64,60.87 70.34,60.58 70.1,60.58 69.99,60.68 69.75,60.68 69.5,60.43 69.5,60.18 69.6,60.08 69.6,59.83 69.36,59.59 68.82,59.59 68.65,59.41 68.65,59.02 68.47,58.85 68.12,58.85 67.95,59.02 67.95,59.41 67.77,59.59 66.71,59.59 66.56,59.43 66.56,59.05 66.37,58.86 65.92,58.86 65.74,59.04 65.74,59.41 65.57,59.59 65.22,59.59 65.04,59.41 65.04,59.04 64.87,58.86 62.5,58.86 62.31,58.67 v2(62.31,58.39)
  BOTTOM w0.076: v2(118.01,62.61) UC1.AN50
  BOTTOM w0.17: v2(62.31,58.39) 62.31,57.69 62.48,57.52 63.63,57.52 64.07,57.08 JDIMM2.119
DDR_B_MA13: length 65.8
  IN3 w0.175: v2(108.27,57.74) 107,56.47 103.95,56.47 101.85,54.38 94.88,54.38 91.89,51.39 88.76,51.39 83.95,46.58 79.62,46.58 79.11,47.09 78.69,47.09 76.61,45.01 69.52,45.01 68.66,45.87 65.64,45.87 64.78,45.01 64.78,44.75 64.41,44.37 61.88,44.37 60.78,45.47 v2(60.78,45.65)
  BOTTOM w0.076: UC1.BA43 113.43,57.74 113.19,57.74 113.16,57.73 113.07,57.69 112.96,57.69 112.82,57.74 112.57,57.74 112.56,57.74 112.32,57.74 112.21,57.63 111.87,57.63 111.28,58.22 111.12,58.22 111,58.34 109.62,58.34 109.47,58.19 108.71,58.19 v2(108.27,57.74)
  BOTTOM w0.17: JDIMM2.158 57.47,45.33 58.18,44.61 59.74,44.61 v2(60.78,45.65)
DDR_B_ODT0: length 68
  IN3 w0.175: v2(105.77,57.77) 105.77,57.08 105.42,56.74 103.67,56.74 101.77,54.83 94.69,54.83 91.7,51.84 88.57,51.84 88.16,51.44 83.76,47.04 79.81,47.04 79.3,47.54 78.5,47.54 77.86,46.9 77.56,46.9 77.35,47.11 77.1,47.11 76.79,46.81 76.79,46.56 76.99,46.36 76.99,46.03 76.67,45.72 76.33,45.72 75.84,46.21 70.69,46.21 70.51,46.03 70.51,45.65 70.32,45.46 69.7,45.46 69.56,45.61 69.56,46.58 69.39,46.75 68.96,46.75 68.53,46.32 66.11,46.32 65.68,46.75 65.37,46.75 65.2,46.58 65.2,46.15 64.99,45.94 64.7,45.94 64.4,46.24 64.13,46.24 63.86,45.97 63.86,45.72 64.22,45.36 64.22,45.09 63.96,44.83 63.72,44.83 63.34,45.21 62.95,45.21 62.82,45.08 62.82,44.89 62.7,44.77 62.13,44.77 61.88,45.02 61.88,45.36 62.17,45.65 v2(62.31,45.65)
  BOTTOM w0.076: UC1.BA42 113.19,57.31 113.05,57.17 113.04,57.17 113.04,57.16 112.79,57.04 112.79,57.04 112.46,57.04 112.37,57.14 111.57,57.14 111.46,57.24 110.77,57.24 110.39,57.63 109.95,57.63 109.44,57.12 106.1,57.12 105.77,57.45 v2(105.77,57.77)
  BOTTOM w0.17: JDIMM2.155 63.39,46.08 63.33,46.13 62.79,46.13 v2(62.31,45.65)
DDR_B_ODT1: length 69.5
  IN3 w0.076: 102.12,53.85 102.12,53.88 103.99,55.75 109.11,55.75 110.86,57.49 v2(110.86,57.9)
  IN3 w0.175: 102.12,53.85 101.74,53.47 95.26,53.47 92.27,50.48 89.13,50.48 84.33,45.67 83.49,45.67 83.32,45.5 83.32,44.79 83.14,44.61 82.79,44.61 82.62,44.79 82.62,45.5 82.44,45.67 82.09,45.67 81.91,45.5 81.91,44.79 81.74,44.61 81.39,44.61 81.21,44.79 81.21,45.5 81.04,45.67 80.55,45.67 80.37,45.49 80.37,44.93 80.19,44.76 79.84,44.76 79.67,44.93 79.67,45.49 79.48,45.67 78.56,45.67 76.98,44.1 72.77,44.1 72.59,43.92 72.59,43.81 72.42,43.63 72.07,43.63 71.89,43.81 71.89,43.92 71.72,44.1 70.49,44.1 70.32,43.92 70.32,43.81 70.14,43.63 69.79,43.63 69.62,43.81 69.62,43.92 69.44,44.1 69.14,44.1 68.28,44.96 66.02,44.96 65.69,44.63 65.69,44.36 64.89,43.56 64.89,43.2 64.72,43.03 62.45,43.03 62.31,43.18 v2(62.31,43.47)
  BOTTOM w0.076: v2(110.86,57.9) 111.07,57.9 111.33,57.63 111.63,57.63 111.79,57.47 112.32,57.47 112.43,57.57 112.59,57.57 112.59,57.58 112.79,57.58 112.87,57.54 112.89,57.52 113.12,57.52 113.23,57.58 113.44,57.58 113.52,57.54 113.8,57.54 113.83,57.58 114.21,57.58 114.48,57.31 UC1.AW42
  BOTTOM w0.17: v2(62.31,43.47) 62.85,44.01 63.21,44.01 63.77,44.58 JDIMM2.161
DDR_B_PAR: length 70.4
  IN3 w0.076: v2(117.4,58.92) 117.4,58.54 117.32,58.46 112.26,58.46 110.65,60.08 104.43,60.08
  IN3 w0.175: v2(67.14,51.21) 67.14,50.96 67.32,50.78 68.06,50.78 68.57,51.29 68.9,51.29 69.05,51.14 69.05,50.98 69.18,50.85 69.66,50.85 69.92,51.1 69.92,51.74 70.87,52.69 75.91,52.69 76.21,52.98 76.73,52.98 76.91,52.81 76.91,52.49 77.08,52.32 77.43,52.32 77.61,52.49 77.61,52.81 77.78,52.98 78.23,52.98 78.39,52.83 78.39,52.51 78.58,52.32 79.09,52.32 79.22,52.45 79.22,52.83 79.37,52.98 79.82,52.98 79.92,52.88 79.92,52.49 80.1,52.32 80.45,52.32 80.62,52.49 80.62,52.74 80.8,52.92 81.15,52.92 81.33,52.74 81.33,52.49 81.5,52.32 81.85,52.32 82.03,52.49 82.03,52.74 82.2,52.92 82.89,52.92 87.53,57.56 87.96,57.56 88.29,57.24 88.58,57.24 88.74,57.4 88.74,57.7 88.35,58.09 88.35,58.38 88.89,58.92 89.21,58.92 89.38,58.75 89.38,57.41 89.55,57.24 89.91,57.24 90.08,57.42 90.08,58.75 90.26,58.92 90.61,58.92 90.78,58.75 90.78,57.41 90.96,57.24 91.31,57.24 91.48,57.42 91.48,58.75 91.66,58.92 102.39,58.92 102.85,59.39 103.74,59.39 104.43,60.08
  BOTTOM w0.076: UC1.AP43 117.4,58.92 v2(117.4,58.92)
  BOTTOM w0.17: v2(67.14,51.21) 66.63,50.71 66.16,50.71 65.79,51.08 JDIMM2.143
DDR_B_RAS#: length 64.2
  IN3 w0.076: 103.2,57.84 103.62,57.84 104.46,58.68 107.85,58.68 v2(108.52,59.36)
  IN3 w0.175: v2(59.26,47.09) 60.64,48.47 63.18,48.47 63.28,48.57 75.98,48.57 76.77,49.36 80.06,49.36 80.56,48.85 82.04,48.85 82.65,49.47 82.65,49.75 82.95,50.04 83.23,50.04 85.95,52.77 86.92,52.77 87.81,53.66 90.95,53.66 93.94,56.65 102,56.65 103.2,57.84
  BOTTOM w0.076: UC1.AW44 114.48,58.54 114.31,58.7 114.1,58.81 114.03,58.83 113.56,58.83 113.33,59.07 111.51,59.07 111.42,59.17 108.71,59.17 v2(108.52,59.36)
  BOTTOM w0.17: v2(59.26,47.09) 58.82,46.65 57.92,46.65 57.75,46.83 JDIMM2.152
DDR_B_WE#: length 60.8
  IN3 w0.076: 103.7,57.3 104.19,57.79 104.19,57.94 104.4,58.15 106.26,58.15 v2(106.63,57.78)
  IN3 w0.175: 103.7,57.3 103.49,57.3 101.93,55.74 94.31,55.74 91.32,52.75 88.19,52.75 83.38,47.94 80.19,47.94 79.68,48.45 77.15,48.45 76.36,47.66 64.27,47.66 63.25,46.65 62.75,46.65 v2(62.31,47.09)
  BOTTOM w0.076: v2(106.63,57.78) 106.94,57.78 107.72,58.57 109.27,58.57 109.37,58.67 111.17,58.67 111.27,58.57 112.32,58.57 112.52,58.37 112.79,58.37 112.91,58.42 113.05,58.42 113.28,58.36 113.41,58.36 113.63,58.43 113.64,58.43 113.74,58.54 UC1.AY44
  BOTTOM w0.17: JDIMM2.151 63.85,47.08 63.39,47.53 62.75,47.53 62.31,47.09 v2(62.31,47.09)
DDR_VTT_CNTL: length 19.2
  TOP w0.102: v2(104.57,82.55) UC14.2
  BOTTOM w0.076: UC1.AW67 114.45,71.98 113.87,71.71 112.49,71.71 112.36,71.83 112.36,72.01 111.75,72.62 111.75,72.83 111.31,73.27 111.31,74.5 111.92,75.11 111.92,75.37 110.01,77.28
  BOTTOM w0.102: 110.01,77.28 109.44,77.85 109.44,79.56 107.09,81.91 105.21,81.91 v2(104.57,82.55)
DEW1: length 4.3
  TOP w0.254: RS34.1 RS36.1 208.44,25.41 v1(208.28,25.26) 207.69,24.66 207.01,24.66 206.77,24.41 US2.16
DEW2: length 5.2
  TOP w0.102: RS35.1 202.48,19.15 v1(202.24,19.38)
  TOP w0.254: RS35.1 203.41,17.94 RS33.1 203.42,18.33 204.77,19.68 US2.6
DIMM_CHA_SA0: length 4.6
  TOP w0.102: RD28.1 68.72,21.45 v2(68.17,20.9) 68.61,20.46 RD1.2 68.61,20.18 v1(69.64,19.15)
  BOTTOM w0.127: JDIMM1.256 68.24,20.83 v2(68.17,20.9)
DIMM_CHA_SA1: length 5.5
  TOP w0.102: v1(66.7,19.12) 67.66,20.07 RD2.2 67.66,20.67 v2(67.43,20.9) 67.43,21.15 RD29.1
  BOTTOM w0.127: v2(67.43,20.9) 68.5,19.83 JDIMM1.260
DIMM_CHA_SA2: length 3.5
  TOP w0.102: RD3.2 67.48,43 v2(67.47,42.99) 67.48,42.97 RD30.1
  BOTTOM w0.102: v2(67.47,42.99) 67.81,43.33 JDIMM1.166
DIMM_CHB_SA0: length 4.3
  TOP w0.102: v1(54.78,23.03) RD38.1
  TOP w0.127: RD38.1 RD4.2 55.25,20.82 v2(55.43,21)
  BOTTOM w0.127: v2(55.43,21) 55.61,20.83 JDIMM2.256
DIMM_CHB_SA1: length 4.2
  TOP w0.102: v1(56,18.86) RD39.1
  TOP w0.127: RD39.1 RD5.2 55.32,19.81 v2(55.42,19.91)
  BOTTOM w0.127: v2(55.42,19.91) 55.51,19.83 JDIMM2.260
DIMM_CHB_SA2: length 4.2
  TOP w0.102: RD40.1 53.95,43.44 v1(53.61,43.1) ; RD40.1 RD6.2 ; RD40.1 55.42,43.44 v2(55.43,43.45)
  BOTTOM w0.102: v2(55.43,43.45) 55.56,43.33 JDIMM2.166
DMIC_CLK: length 110.1
  TOP w0.102: v2(43.79,92.74) 43.79,92.71 v1(44.4,92.11) 45.97,90.53 49.81,90.53 50.35,91.07 EC5206.1 50.35,92.11 v2(50.17,92.29) ; LA1.2 38,19.93 C6223.1 38.24,19.92 38.51,20.19 38.51,21.08 37.99,21.6 v2(36.43,21.6)
  IN1 w0.114: v2(36.43,21.6) 36.02,21.6 34.96,22.66 34.96,29.14 34.63,29.47 34.63,29.75 30.84,33.54 29.61,33.54 28.31,34.84 27.61,34.84 27.19,35.26 24.46,35.26 23.79,35.93 23.79,37.38 23.16,38.02 23.16,40.36 22.9,40.61 22.9,42.02 20.97,43.95 20.97,45.83 22.11,46.97 22.11,48.05 22.81,48.75 22.81,50.17 23.37,50.73 23.37,58.11 24.17,58.91 24.17,61.12 27.53,64.48 27.53,71.77 25.36,73.94 25.36,76.53 28.55,79.73 29.93,79.73 30.64,80.44 34.42,80.44 38.19,84.21 38.19,85.57 39.68,87.06 41.09,87.06 43.16,89.12 43.16,90.36 43.79,90.99 v2(43.79,92.74)
  BOTTOM w0.102: R5207.2 49.89,92.57 v2(50.17,92.29)
DMIC_CLK_C: length 3.1
  TOP w0.102: LA1.1 36.87,21.12 36.21,21.12 v1(35.98,21.35) 35.05,22.27 UA1.3
DMIC_CLK_EDP: length 4.2
  BOTTOM w0.102: JEDP.27 50.27,95.75 EU3405.1 EU3405.9 50.27,94.24 R5207.1
DMIC_DATA: length 109.6
  TOP w0.102: v2(50.98,92.34) 51.54,91.78 EC5205.1 50.41,90.27 45.36,90.27 v1(45.2,90.42) v2(43.34,92.29) ; UA1.2 35.01,21.87 36.17,20.71 v2(36.45,20.71)
  IN1 w0.114: v2(36.45,20.71) 36.34,20.71 35.65,21.39 35.65,21.58 34.72,22.52 34.72,29.04 34.39,29.37 34.39,29.65 30.74,33.29 29.51,33.29 28.21,34.6 27.51,34.6 27.09,35.02 24.36,35.02 23.55,35.83 23.55,37.28 22.91,37.92 22.91,40.26 22.66,40.51 22.66,41.92 20.73,43.85 20.73,45.93 21.87,47.07 21.87,48.15 22.57,48.85 22.57,50.27 23.13,50.83 23.13,58.21 23.93,59.01 23.93,61.22 27.29,64.58 27.29,71.67 25.12,73.84 25.12,76.63 28.45,79.97 29.83,79.97 30.54,80.68 34.32,80.68 37.95,84.31 37.95,85.67 39.6,87.32 41.01,87.32 42.9,89.21 42.9,90.44 43.34,90.87 v2(43.34,92.29)
  BOTTOM w0.102: R5215.2 50.78,92.54 v2(50.98,92.34)
DMIC_DATA_EDP: length 4
  BOTTOM w0.102: JEDP.28 50.77,95.75 EU3405.2 EU3405.8 50.77,93.87 R5215.1
E51_RX1: length 2.1
  BOTTOM w0.102: T4969.1 187.42,50.8 WLAN1.38
E51_TX1: length 11
  TOP w0.102: v1(187.49,51.07) 187.92,51.51 v2(187.92,51.62) 187.86,51.68 R6527.1
  BOTTOM w0.102: WLAN1.58 182.42,53.87 183.09,54.53 187.55,54.53 187.92,54.16 WLAN1.36 v2(187.92,51.62)
E51_TX2: length 3.7
  TOP w0.102: R5812.1 R6517.1 189.64,51.8 v2(189.42,51.58) v1(189.42,50.96)
  BOTTOM w0.102: WLAN1.30 v2(189.42,51.58)
EC_AGND: length 5.6
  TOP w0.203: UE1.112 30.3,47.82 v2(30.25,47.86)
  IN3 w0.254: v2(30.25,47.86) 29.54,47.15 v2(26.22,47.15)
EC_MISO_R: length 101.7
  TOP w0.102: RE416.1 48.03,35.37 v2(48.16,35.24) ; v2(115.49,18.82) 115.45,18.86 110.77,18.86 109.74,19.89 108.62,19.89 107.46,21.06 107.46,24.01 107.84,24.39 107.84,24.94 v2(107.65,25.13)
  IN1 w0.114: v2(48.16,35.24) 49.13,34.27 49.69,34.27 50.77,33.19 50.77,26 52.7,24.07 52.7,22.32 54.69,20.33 55.59,20.33 55.9,20.02 57.14,20.02 61.11,16.04 65.99,16.04 65.99,16.04 67.19,16.04 67.6,15.63 78.74,15.63 80.03,16.93 83.77,16.93 84.46,16.23 85.16,16.23 85.51,16.58 87.6,16.58 87.88,16.86 88.96,16.86 90.94,18.84 93.73,18.84 94.26,18.31 100.56,18.31 101.31,19.07 102.44,19.07 107.02,23.65 107.02,24.78 107.37,25.13 v2(107.65,25.13)
  BOTTOM w0.102: RPC5.8 115.59,18.72 v2(115.49,18.82) 111.62,18.82 110.93,19.51 v1(108.99,19.51) 107.74,19.51 RC1119.2
EC_MOSI_R: length 98.7
  TOP w0.102: v2(47.57,35.22) 47.08,35.71 RE414.1 ; v2(107.43,24.57) 107.23,24.37 107.23,20.97 108.53,19.67 109.64,19.67 110.8,18.51 114.98,18.51 v2(115.14,18.35)
  IN1 w0.114: v2(107.43,24.57) 107.43,23.72 102.54,18.83 101.41,18.83 100.06,17.48 94.76,17.48 93.63,18.6 91.04,18.6 89.06,16.62 87.98,16.62 87.7,16.34 85.63,16.34 85.28,15.99 84.36,15.99 83.67,16.69 80.13,16.69 78.84,15.39 67.5,15.39 67.09,15.8 66.09,15.8 66.09,15.8 60.91,15.8 57.36,19.35 55.33,19.35 54.35,20.33 52.46,22.22 52.46,23.97 50.53,25.9 50.53,33.09 49.59,34.03 48.76,34.03 v2(47.57,35.22)
  BOTTOM w0.102: v2(107.43,24.57) 106.81,23.95 v4(106.81,23.08) 106.81,22.13 106.48,21.8 RC58.2 ; RPC5.7 115.27,18.22 v2(115.14,18.35)
EC_MUTE#: length 57.5
  TOP w0.102: v2(25.58,53.78) RE435.1 ; UA1.47 33.39,20.23 33.62,20 34.06,20 v2(34.38,19.68) 34.56,19.68 RA14.2 ; RE433.1 24.39,42.26 v1(24.25,42.12) 23.92,41.79 v2(23.75,41.79)
  IN1 w0.114: v2(34.38,19.68) 36.99,17.08 39.02,17.08 39.64,17.7 39.64,18.74 37.3,21.08 37.3,21.58 35.2,23.69 35.2,29.24 34.87,29.57 34.87,29.85 30.94,33.78 29.71,33.78 28.41,35.08 27.71,35.08 27.29,35.5 24.56,35.5 24.03,36.03 24.03,41.51 v2(23.75,41.79)
  IN2 w0.127: v2(25.58,53.78) 25.14,53.34 25.14,43.17 v2(23.75,41.79)
EC_MUTE#_R: length 8.9
  TOP w0.102: RE433.2 25.3,43.82 v1(25.66,44.18) 25.87,44.39 25.87,45.24 26.35,45.73 28.11,45.73 29.23,44.61 30.13,44.61 30.54,45.02 UE1.119
EC_SPI_CLK: length 5.6
  TOP w0.102: RE413.2 49.06,38.86 v1(48.7,38.86) 45.84,38.86 45.54,39.16 UE1.32
EC_SPI_CS0#: length 7
  TOP w0.102: v1(46.27,34.96) 46.59,35.28 46.59,36.37 46.18,36.78 RE410.1 45.7,37.21 44.51,37.21 43.54,38.19 UE1.27
EC_SPI_MISO: length 5.8
  TOP w0.102: UE1.29 44.34,38.4 44.93,37.81 46.88,37.81 v1(46.93,37.85) 46.93,37.86 46.95,37.86 RE416.2
EC_SPI_MOSI: length 5.3
  TOP w0.102: UE1.28 43.94,38.27 v1(44.39,37.82) 44.62,37.58 46.28,37.58 RE414.2
EC_SPICLK_R: length 167.1
  TOP w0.102: v1(50.84,36.85) 50.91,36.91 RE413.1 CC1805.2 49.47,39.36 46.94,39.36 v2(46.18,40.13) ; RZ66.1 46.07,73.03 47.73,73.03 v2(47.91,73.21)
  IN1 w0.114: v2(114.71,17.91) 114.71,22.26 117.38,24.93 117.38,25.97 116.99,26.36 114.35,26.36 113.36,27.35 110.3,27.35 109.44,26.49 108.18,26.49 107.36,25.66 105.64,25.66 104.51,24.53 104.51,21.84 102.24,19.57 101.11,19.57 100.35,18.81 94.93,18.81 93.94,19.8 91.15,19.8 88.77,17.43 79.83,17.43 78.53,16.13 67.81,16.13 67.4,16.54 65.79,16.54 61.32,16.54 57.34,20.51 56.55,20.51 55.64,21.42 54.3,21.42 53.2,22.52 53.2,26.15 51.27,28.08 51.27,33.39 51.01,33.65 51.01,35.9 47.6,39.3 47.01,39.3 v2(46.18,40.13) 46.72,40.67 46.72,43.22 46.35,43.59 46.35,50.5 47.04,51.19 47.04,54.81 47.83,55.6 47.83,58.24 48.52,58.92 48.52,61.2 47.63,62.09 47.63,64.37 48.39,65.13 48.39,67.54 46.19,69.74 46.19,71.5 v2(47.91,73.21)
  BOTTOM w0.102: RC59.2 113.81,29.78 CC1823.2 112.98,29.51 113.14,29.36 113.14,28.08 113.29,27.92 113.34,27.92 115.48,25.78 115.48,25.49 115.93,25.04 115.93,21.52 115.56,21.15 115.56,20.13 116.88,18.8 116.88,17.84 116.76,17.72 RPC5.6 114.91,17.72 v2(114.71,17.91)
EC_SPICS#_R: length 133.5
  TOP w0.102: RE410.2 45.75,35.48 v2(45.75,35.16) ; v2(125.57,20) v4(125.57,19.38)
  IN1 w0.114: v2(125.57,20) 124.6,20.96 124.44,20.96 124.03,20.55 123.87,20.55 123.66,20.75 123.66,20.91 124.07,21.33 124.07,21.49 123.87,21.7 123.71,21.7 123.29,21.28 123.13,21.28 122.92,21.49 122.92,21.65 123.34,22.07 123.34,22.23 123.13,22.43 122.97,22.43 122.14,21.61 121.98,21.61 121.77,21.81 121.77,21.97 122.6,22.8 122.6,22.96 122.39,23.17 122.23,23.17 120.8,21.74 120.64,21.74 120.43,21.95 120.43,22.11 121.86,23.54 121.86,23.7 121.66,23.9 121.45,23.9 120.02,22.47 119.79,22.47 119.49,22.78 119.49,22.94 120.97,24.43 120.97,24.59 120.77,24.8 120.61,24.8 119.12,23.31 118.96,23.31 118.84,23.43 118.82,23.43 v2(118.82,24.25) 117.51,24.25 115.45,22.19 115.45,20.25 115.97,19.73 115.97,17.85 115.45,17.33 114.67,17.33 112.57,19.43 105.15,19.43 103.4,17.67 101.69,17.67 100.53,16.51 91.01,16.51 90.15,15.65 88.38,15.65 88.1,15.37 86.18,15.37 85.52,14.72 79.53,14.72 79.24,14.43 67.1,14.43 66.69,14.84 66.49,14.84 60.45,14.83 56.9,18.38 54.93,18.38 51.5,21.82 51.5,23.57 48.3,26.76 48.3,32.61 v2(45.75,35.16)
  BOTTOM w0.102: v2(125.57,20) 125.57,21.46 125.67,21.56 126.03,21.56 126.15,21.43 126.15,20.05 126.29,19.91 126.51,19.91 126.66,20.06 126.66,21.42 126.79,21.55 127.09,21.55 127.22,21.42 127.22,19.57 127.05,19.4 125.54,19.4 125.4,19.26 125.4,18.94 125.51,18.83 126.11,18.83 126.27,18.68 UC2.1 ; RC1125.2 v2(118.82,24.25)
EC_WAKE#: length 94.9
  TOP w0.102: v2(102.58,39.49) 102.58,39.43 102.71,39.3 RC391.1 ; UE1.35 45.49,42.22 v2(45.27,41.99) ; v2(90.94,26.32) v1(90.94,27.05)
  IN2 w0.127: v2(45.27,41.99) 45.27,40.36 47.11,38.51 49.97,38.51 52.72,35.76 52.72,31.74 53.37,31.09 53.37,26.37 54.49,25.26 54.49,19.03 55.07,18.45 56.79,18.45 58.01,17.23 58.45,17.23 60.02,15.65 78.35,15.65 79.2,16.49 79.87,16.49 82.47,19.1 83.3,19.1 90.53,26.32 v2(90.94,26.32)
  BOTTOM w0.102: v2(90.94,26.32) 90.94,27.18 93.41,29.65 95.38,29.65 95.89,30.16 98.54,30.16 99.34,30.96 99.34,36.25 v2(102.58,39.49)
EDP_AUX_DN: length 132.5
  TOP w0.094: v2(40.01,99.4) 40.16,99.4 40.37,99.2 40.37,98.83 C5209.1
  IN3 w0.076: 133.73,58.88 133.72,58.88 133.69,58.86 133.49,58.86 133.4,58.94 133.4,59.14 132.96,59.58 132.07,59.58 131.92,59.73 131.92,59.95 132.06,60.09 132.18,60.09 132.28,60 v2(132.28,59.95)
  IN3 w0.135: 133.73,58.88 134.1,58.88 134.26,59.04 134.26,59.95 134.2,60 134.2,60.89 134.33,61.02 134.33,62.53 134.02,62.84 134.02,65.76 134.28,66.01 134.28,75.7 131.14,78.83 131.14,87.24 122.95,95.44 102.49,95.44 101.8,94.75 57.73,94.75 55.1,97.38 44.98,97.38 44.22,98.13 40.83,98.13 40.43,98.53 40.43,99.23 40.26,99.4 v2(40.01,99.4)
  BOTTOM w0.076: v2(132.28,59.95) 132.59,59.64 UC1.E45
EDP_AUX_DN_C: length 3
  TOP w0.094: v2(40.22,96.42) 40.22,96.42 40.42,96.61 40.42,97.2 C5209.2
  BOTTOM w0.094: JEDP.7 40.27,97.36 40.42,97.21 40.42,96.61 40.22,96.42 v2(40.22,96.42)
EDP_AUX_DP: length 132.6
  TOP w0.094: v2(40.8,99.43) 40.64,99.43 40.55,99.34 40.55,98.93 C5212.1
  IN3 w0.076: v2(131.56,59.92) 131.73,59.75 131.73,59.65 131.99,59.39 132.89,59.39 133.22,59.06 133.22,58.86 133.41,58.67 133.69,58.67 133.72,58.64 133.73,58.64
  IN3 w0.135: v2(40.8,99.43) 40.68,99.31 40.68,98.63 40.93,98.38 44.32,98.38 45.08,97.62 55.2,97.62 57.83,94.99 101.7,94.99 102.39,95.68 123.05,95.68 131.39,87.34 131.39,78.94 134.52,75.8 134.52,65.91 134.27,65.65 134.27,62.94 134.58,62.63 134.58,60.92 134.45,60.79 134.45,60.1 134.5,60.05 134.5,58.94 134.2,58.64 133.73,58.64
  BOTTOM w0.076: v2(131.56,59.92) 131.94,59.54 UC1.F45
EDP_AUX_DP_C: length 3
  TOP w0.094: C5212.2 40.6,97.2 40.6,96.61 40.8,96.42 v2(40.8,96.42)
  BOTTOM w0.094: JEDP.8 40.77,97.38 40.6,97.21 40.6,96.61 40.8,96.42 v2(40.8,96.42)
EDP_BKLT_CTRL: length 19.7
  TOP w0.094: R5206.2 40.93,95.88 36.03,95.88 33.87,98.04 v1(33.87,99.83) 33.87,106.04 35.58,107.74 D5202.2
EDP_COMP: length 5.4
  IN2 w0.254: v2(132.81,63.52) 135.83,63.52 v2(136.43,62.92)
  BOTTOM w0.254: v2(132.81,63.52) UC1.E52 ; RC2.2 v2(136.43,62.92)
EDP_HPD: length 195.1
  TOP w0.094: v1(41.99,96.81) 41.99,96.61 v2(42.27,96.32)
  IN3 w0.102: 125.51,32.2 125.51,34.96 126.42,35.87 126.42,40.49 127.1,41.17 128.2,41.17 128.45,40.91 128.45,40.24 128.95,39.75 v2(129.82,39.75)
  IN3 w0.135: 125.51,32.2 125.51,30.3 124.78,29.56 124.78,28.51 124.37,28.11 124.37,25.32 115.64,16.59 113.71,16.59 113.49,16.37 112.16,16.37 111.84,16.68 106.78,16.68 104.6,18.86 96.36,18.86 95.71,18.21 90.97,18.21 90.77,18 87.67,18 85.8,16.13 81.6,16.13 80.92,15.45 79.28,15.45 78.5,14.68 76.77,14.68 76.33,15.12 59.12,15.12 58.01,16.24 57.46,16.24 55.81,17.89 54.78,17.89 51.9,20.77 51.9,25.69 48.13,29.45 46.91,29.45 45.44,30.91 45.44,33.54 44.42,34.57 44.42,35.72 43.19,36.95 42.13,36.95 41.61,37.47 41.61,38.95 42.5,39.83 42.5,42.73 42.07,43.16 42.07,44.38 42.62,44.93 42.62,47.15 41.68,48.08 41.68,50.65 39.63,52.7 39.63,57.06 40.29,57.72 40.29,59.16 39.63,59.82 39.63,61.45 41.18,63 41.18,66.94 42.34,68.1 42.34,72.83 40.05,75.11 40.05,81.13 39.63,81.55 39.63,82.07 40.56,83 40.56,84.42 43.09,86.96 43.09,90.47 42.57,90.99 42.57,96.02 v2(42.27,96.32)
  BOTTOM w0.089: v2(129.82,39.75) 129.34,39.27 UC1.L10
  BOTTOM w0.094: JEDP.15 44.27,96.94 43.92,96.59 42.51,96.59 42.27,96.35 v2(42.27,96.32) RN5203.6
EDP_TX0_DN: length 132.6
  TOP w0.094: C5203.1 38.81,101.14 38.81,101.56 v2(38.63,101.74)
  IN3 w0.135: v2(38.63,101.74) 38.83,101.54 38.83,100.77 39.2,100.4 43.08,100.4 45.34,98.14 55.59,98.14 58.23,95.51 101.33,95.51 102.25,96.43 123.28,96.43 132.17,87.54 132.17,80.04 135.8,76.41 135.8,74.01 135.17,73.38 135.17,67.9 135.47,67.6 135.47,67.19 135.17,66.89 135.17,65.69 134.88,65.41 134.88,63.11 135,62.99 135,60.55 v2(134.84,60.38)
  BOTTOM w0.076: UC1.C47 133.89,60.71 133.89,60.58 133.93,60.54 134.13,60.54 134.15,60.56 134.47,60.56 134.65,60.38 v2(134.84,60.38)
EDP_TX0_DN_C: length 2.5
  TOP w0.094: v2(38.73,99.11) 38.89,99.27 38.89,99.5 38.52,99.87 C5203.2
  BOTTOM w0.094: JEDP.4 38.77,98.36 38.93,98.52 38.93,98.91 v2(38.73,99.11)
EDP_TX0_DP: length 132.6
  TOP w0.094: C5210.1 38.99,101.19 38.99,101.51 v2(39.21,101.74)
  IN3 w0.135: v2(39.21,101.74) 39.07,101.59 39.07,100.87 39.3,100.64 43.18,100.64 45.44,98.38 55.7,98.38 58.33,95.75 101.23,95.75 102.15,96.67 123.38,96.67 132.41,87.64 132.41,80.14 136.05,76.51 136.05,73.91 135.41,73.27 135.41,68 135.72,67.7 135.72,67.09 135.41,66.78 135.41,65.59 135.12,65.3 135.12,63.21 135.25,63.09 135.25,60.55 v2(135.41,60.38)
  BOTTOM w0.076: v2(135.41,60.38) 135.03,60 134.61,60 UC1.C46
EDP_TX0_DP_C: length 2.4
  TOP w0.094: v2(39.31,99.11) 39.07,99.34 39.07,99.54 C5210.2
  BOTTOM w0.094: JEDP.5 39.27,98.36 39.11,98.52 39.11,98.91 v2(39.31,99.11)
EDP_TX1_DN: length 131.2
  TOP w0.094: v2(37.21,100.22) 37.39,100.04 37.39,98.84 C5211.1
  IN3 w0.135: v2(133.19,60.16) 133.38,59.86 133.49,59.83 133.6,59.91 133.68,60.23 133.68,60.47 133.25,60.89 133.25,61.04 133.25,61.04 133.25,64.54 133.12,64.66 133.12,66.8 133.44,67.11 133.44,73.46 129.74,77.16 129.74,86.71 122.08,94.38 102.6,94.38 102.21,93.98 57.35,93.98 55.96,95.37 45.79,95.37 43.79,97.37 38.52,97.37 37.4,98.48 37.4,100.03 v2(37.21,100.22)
  BOTTOM w0.076: v2(133.19,60.16) 133.57,60.16 UC1.D46
EDP_TX1_DN_C: length 3
  TOP w0.094: v2(37.23,96.43) 37.43,96.63 37.43,96.84 37.44,96.85 37.44,97.15 37.05,97.54 C5211.2
  BOTTOM w0.094: JEDP.1 37.27,97.31 37.43,97.15 37.43,96.63 v2(37.23,96.43)
EDP_TX1_DP: length 131.2
  TOP w0.094: v2(37.79,100.22) 37.57,100 37.57,98.92 C5213.1
  IN3 w0.135: v2(133.71,59.32) 133.91,60.17 133.92,60.18 133.92,60.57 133.5,60.99 133.5,61.14 133.49,61.14 133.49,64.64 133.37,64.76 133.37,66.7 133.69,67.01 133.69,73.57 129.99,77.26 129.99,86.81 122.18,94.62 102.5,94.62 102.11,94.23 57.45,94.23 56.06,95.61 45.89,95.61 43.89,97.61 38.62,97.61 37.65,98.58 37.65,100.08 v2(37.79,100.22)
  BOTTOM w0.076: UC1.C45 133.71,59.41 v2(133.71,59.32)
EDP_TX1_DP_C: length 3
  TOP w0.094: v2(37.81,96.43) 37.61,96.63 37.61,96.76 37.62,96.78 37.62,97.15 38,97.53 C5213.2
  BOTTOM w0.094: JEDP.2 37.77,97.3 37.61,97.14 37.61,96.63 v2(37.81,96.43)
EDP_VDD_EN: length 212
  TOP w0.102: D5201.2 39.58,108.19 v2(38.94,107.55) 38.78,107.55 v1(37.98,106.75)
  IN3 w0.135: v2(38.94,107.55) 38.28,106.89 38.28,103.59 35.34,100.65 35.34,96.94 36.8,95.48 41.01,95.48 41.68,94.8 41.68,92.91 42.06,92.54 42.06,90.78 42.58,90.26 42.58,87.2 41,85.62 39.13,85.62 38.81,85.29 38.81,82.71 38.57,82.47 38.57,81.15 38.98,80.74 38.98,52.61 41.16,50.43 41.16,48.6 40.03,47.47 40.03,44.43 40.59,43.87 40.59,42.65 41.38,41.87 41.38,40.27 40.58,39.46 40.58,37.03 41.9,35.7 42.97,35.7 43.39,35.29 43.39,34.14 44.32,33.21 44.32,30.58 46.48,28.42 47.54,28.42 50.83,25.13 50.83,19.77 52.63,17.97 53.25,17.97 54.37,16.84 55.39,16.84 57.01,15.21 57.58,15.21 58.7,14.09 75.81,14.09 76.26,13.65 78.93,13.65 79.3,14.02 82.84,14.02 83.25,14.42 85.55,14.42 88.01,16.88 90.29,16.88 90.87,16.3 93.32,16.3 93.89,16.88 99.63,16.88 99.97,17.22 103.06,17.22 105.54,14.74 115.85,14.74 116.2,15.1 116.98,15.1 121.56,19.68 121.56,20.68 125.88,25 125.88,25.29 127.33,26.74 127.33,32.67 127.8,33.14 127.8,34.49 128.8,35.49 128.8,36.3 128.3,36.8 128.3,37.79 127.28,38.81 127.28,39.8 v2(126.84,40.23)
  BOTTOM w0.102: UC1.U13 126.84,40.59 v2(126.84,40.23)
EDRAM_OPIO_RCOMP: length 2.1
  TOP w0.089: v2(131,71.14) 131.25,71.14 v1(131.6,71.48)
  TOP w0.102: v2(131,71.14) 130.65,71.49 RC90.1
  BOTTOM w0.102: v2(131,71.14) 130.7,71.44 UC1.H66
EMMC_RCOMP: length 4.1
  BOTTOM w0.076: 116.87,32.57 116.87,33.26 v2(116.73,33.4) 116.56,33.57 UC1.AT1
  BOTTOM w0.102: 116.87,32.57 116.87,30.53 RC4.1
EN_0.6VSP: length 4.1
  TOP w0.254: PU200.7 66.63,104.07 66.3,104.4 66.3,105.55 v2(66.03,105.82) 65.36,105.82 ; 65.36,105.82 PR202.2 ; 65.36,105.82 PC203.1
EN_1.0V_VCCST_ON: length 4.1
  TOP w0.254: UZ21.3 v1(159.2,14.98) 158.99,14.98 158.84,15.13 CZ1705.1 RZ1701.2 158.11,13.22 DZ1703.2
EN_1.2V: length 2.8
  TOP w0.254: PC202.1 65.36,104.88 PR201.2 65.86,104.02 v2(66.04,103.85) 66.22,103.67 PU200.8
EN_1.8VALW: length 5.5
  BOTTOM w0.102: PC502.1 50.35,11.22 v1(49.77,11.79)
  BOTTOM w0.254: PU500.5 50.71,10.66 50.98,10.93 50.98,11.16 PC502.1 PR502.2 52.74,11.22 52.75,11.23 53.65,11.23 53.65,11.22 PR501.2
EN_2.5V: length 2.5
  TOP w0.102: v1(73.55,7.93) PC805.1
  TOP w0.254: PC805.1 73.09,9.2 72.8,9.49 v2(72.8,9.86)
EN_3V: length 24.2
  TOP w0.254: v2(184.56,80.2) 184.43,80.2 183.7,80.93 183.7,82.13 184.56,82.99 184.56,83.62 185.57,84.64 185.57,86 185.54,86.04 185.54,86.54 185.73,86.74 185.73,94.06 v1(188.04,96.38) 189.7,98.04 189.7,99.69 189.39,100.01 PR121.1
  BOTTOM w0.254: PU100.12 184.31,79.94 v2(184.56,80.2)
EN_5V: length 24.3
  TOP w0.102: v2(190.27,99.56) v1(190.27,98.99)
  TOP w0.254: PR120.1 v2(190.27,99.56)
  IN3 w0.254: v2(195.67,80.13) 195.93,80.39 195.93,85.08 190.48,90.53 190.48,99.36 v2(190.27,99.56)
  BOTTOM w0.254: v2(195.67,80.13) 195.41,79.87 PU102.12
EN_+1VALW: length 5.2
  TOP w0.102: v2(150.51,27.18) 150.5,27.18 150.17,26.85 v1(150.17,26.64)
  TOP w0.254: PU300.11 151.74,27.82 151.74,27.55 151.37,27.18 v2(150.51,27.18)
  BOTTOM w0.254: v2(150.51,27.18) PR301.2 PR302.1 PC304.1
EN_+VCCEOPIO: length 4.8
  BOTTOM w0.102: v1(106.57,112.56) PR1204.1
  BOTTOM w0.254: PU1200.5 107.03,108.44 106.57,108.9 PR1205.1 PC1204.1 PR1204.1
ENLDO_3V5V: length 26.3
  TOP w0.254: PR102.1 PR103.1 184.6,82.39 v1(184.31,82.11) 184.08,81.87 184.08,81.31 v2(184.56,80.83)
  IN1 w0.254: v2(195.35,80.89) 196.31,81.85 196.31,85.47 195.55,86.23 188.05,86.23 184.08,82.25 184.08,81.31 v2(184.56,80.83)
  BOTTOM w0.254: v2(184.56,80.83) 184.43,80.83 183.99,80.39 PU100.11 ; v2(195.35,80.89) 195.35,80.51 195.16,80.32 PU102.11
EOPIO_RCOMP: length 3.8
  TOP w0.102: RC91.1 129.76,71.45 v1(130.41,70.79) 130.51,70.7 131.44,70.7 v2(131.67,70.93)
  BOTTOM w0.102: UC1.H65 130.93,70.53 131.33,70.93 v2(131.67,70.93)
FAN1_PWM: length 303.9
  TOP w0.102: v1(206.52,68.38) R6535.1 205.21,67.42 205.34,67.29 Q6502.3 205.34,63.51 204.96,63.13 R6534.2 204.96,61.6 v2(204.81,61.45)
  TOP w0.254: v2(49.11,47.37) 48.92,47.37 48.58,47.02 UE1.47
  IN1 w0.114: v2(132.02,28.79) 132,28.77 132,22.54 132.24,22.3 132.24,22.12 134.41,19.96 140.72,19.96 142.9,17.78 143.64,17.78 145.64,15.78 154.69,15.78 155.41,16.5 157.94,16.5 158.06,16.62 160.34,16.62 160.61,16.89 162.46,16.89 163.3,17.74 194.04,17.74 194.34,17.43 195.85,17.43 196.84,16.44 202.38,16.44 203.11,17.17 207.39,17.17 208.7,15.86 208.7,13.43 211.31,10.82 215.72,10.82 217.61,12.71 217.61,28.61 221.72,32.72 222.29,32.72 223.09,33.52 223.09,37.04 220.69,39.44 220.69,39.8 217.25,43.24 217.25,46.05 209.89,53.41 209.89,56.38 v2(204.81,61.45)
  IN2 w0.127: v2(49.11,47.37) 49.43,47.05 50.45,47.05 52.1,45.4 52.1,43.59 53.52,42.17 53.52,39.01 54.69,37.85 54.69,33.28 55.15,32.82 55.76,32.82 57,31.58 57,29.5 57.43,29.07 57.43,20.51 58.8,19.13 59.24,19.13 60.5,17.87 73.9,17.87 75.01,18.98 76.71,18.98 76.99,18.7 79.29,18.7 81.65,21.06 82.13,21.06 89.51,28.44 92.55,28.44 93.88,29.78 98.53,29.78 99.11,29.19 99.44,29.19 100.59,30.34 100.59,33.23 101.82,34.46 110.97,34.46 111.51,35.01 115.29,35.01 116.39,36.1 116.77,36.1 119.46,38.79 120.7,38.79 121.82,39.91 124.51,39.91 125.33,39.09 125.33,30.92 130.51,25.74 131.87,25.74 132.96,26.83 132.96,28.35 132.53,28.79 v2(132.02,28.79)
FAN1_PWM_R: length 5.1
  TOP w0.102: v2(204.98,69.25) 204.3,68.56 R6535.2 204.3,66.58 Q6502.1
  TOP w0.127: v2(204.98,69.25) v4(204.98,70.01)
  BOTTOM w0.102: JFAN1.2 v2(204.98,69.25)
FAN1_TACH: length 247.2
  TOP w0.254: UE1.40 48.1,44.22 48.19,44.31 49.64,44.31 49.94,44 v2(50.68,44) 50.8,43.87 51.83,43.87 CE75.1 RE441.1 ; v2(58.25,98.13) v4(58.25,96.45) 58.25,95.28 54.5,91.54 54.5,86.13 v2(54.49,86.11)
  IN1 w0.254: v2(201.45,69.58) 201.35,69.68 201.35,84.18 202.8,85.63 202.8,98.03 200.13,100.7 193.12,100.7 192.92,100.5 192.35,100.5 192.35,100.64 192.06,100.92 191.66,100.92 191.39,100.65 191.23,100.8 163.84,100.8 163.62,100.59 135.52,100.59 135.25,100.86 103.91,100.86 102.42,99.37 84.2,99.37 82.81,97.98 75.72,97.98 73.5,100.2 71.91,100.2 71.47,99.75 69.56,99.75 67.78,97.98 58.4,97.98 v2(58.25,98.13)
  IN2 w0.254: v2(54.49,86.11) 54.5,86.1 54.5,84.43 54.32,84.25 54.32,56 48.48,50.16 48.48,45.45 49.93,44 v2(50.68,44)
  BOTTOM w0.254: JFAN1.3 202.39,70.5 202.34,70.54 C2604.2 201.65,69.78 v2(201.45,69.58)
FB_1.2V: length 5.5
  TOP w0.102: v1(65.36,108.69) PR204.1
  TOP w0.254: PU200.6 67.12,105.52 66.34,106.31 PC214.1 66.33,106.75 PR207.1 65.36,107.65 PR204.1
FB_1.8VALW: length 4.2
  BOTTOM w0.102: v1(56.48,9.19) PR505.1
  BOTTOM w0.254: PU500.6 53.87,10.07 54.07,10.27 PC503.2 PR504.1 55.56,10.27 PR505.1
FB_+1VALW: length 6.7
  TOP w0.102: v2(153.28,28.56) v1(153.97,28.56)
  TOP w0.254: v2(153.28,28.56) 152.92,28.56 PU300.14
  BOTTOM w0.254: v2(153.28,28.56) 152.63,28.56 151.36,27.29 PR310.1 PR309.1 PC309.2
FB_IA: length 8.6
  TOP w0.102: v1(168.84,72.96) PR650.1
  TOP w0.203: 163.63,70.99 163.63,70.62 164.04,70.21 PU602.17
  TOP w0.254: PR650.1 PR645.2 167.62,72.04 167.11,71.53 164.53,71.53 164.39,71.67 PR648.2 163.63,71.45 163.63,70.99
FB_VSA: length 5.8
  TOP w0.102: v1(159.5,70.49) PR652.1
  TOP w0.203: PR652.1 PR646.1 159.5,67.68 PR649.1 159.91,67.67 160.48,67.1 160.93,67.1 161.07,67.24 PU602.25
FCCM_GT: length 27.1
  TOP w0.203: v2(167.05,70.72) 167.05,70.52 166.44,69.91 PU602.11
  IN3 w0.254: v2(170.82,93.16) v2(170.82,83.75) 170.82,82.76 167.54,79.48 167.54,75.31 168.05,74.8 168.05,72.64 167.05,71.64 v2(167.05,70.72)
  BOTTOM w0.254: v2(170.82,93.16) 170.81,93.15 PR664.2 ; PR671.1 v2(170.82,83.75)
FCCM_IA: length 19.5
  TOP w0.203: v2(160.68,69.91) 161,69.91 161.45,69.46 161.45,69.17 161.78,68.84 PU602.21
  IN3 w0.254: v2(165.19,56.7) 164.15,56.7 160.93,59.93 160.93,64.62 161.83,65.52 161.83,69.12 161.04,69.91 v2(160.68,69.91)
  BOTTOM w0.254: PR659.1 v2(165.19,56.7)
FCCM_VSA: length 47.4
  TOP w0.203: PU602.29 161.63,65.64 161,65.02
  TOP w0.254: v2(165.76,55.05) 164.49,55.05 163.57,55.97 163.57,57.43 162.91,58.1 161.45,58.1 v1(161.17,58.38) 160.05,59.49 160.05,64.07 161,65.02
  IN1 w0.254: v2(165.76,55.05) 165.76,54.1 160.95,49.28 156.61,49.28 155.31,47.99 155.31,43.31 153.72,41.73 153.72,40.94 152.56,39.77 148.31,39.77 147.35,40.74 147.35,42.16 v2(146.9,42.6)
  BOTTOM w0.254: PR679.1 v2(146.9,42.6)
FFS_INT1: length 198
  TOP w0.102: v2(218.28,43.11) 218.28,39.74 220.38,37.64 U5603.12 ; RC1123.2 96.57,26.31 96.57,26.92 96.32,27.17 v1(96.32,27.33) 96.32,27.69 98.35,29.73 v2(99.25,29.73)
  IN1 w0.114: v2(218.28,43.11) 218.28,42.55 220.93,39.9 220.93,39.54 223.33,37.14 223.33,33.41 222.39,32.48 221.82,32.48 217.85,28.51 217.85,12.61 215.82,10.58 211.21,10.58 208.8,12.99 206.65,12.99 205.41,14.23 202.56,14.23 202.37,14.42 198.02,14.42 197.44,13.84 196.64,13.84 194.96,12.16 149.29,12.16 147.76,10.62 143.07,10.62 139.38,14.31 131.13,14.31 127.47,17.97 127.47,20.9 126.61,21.76 126.61,23.49 122.34,27.76 122.34,28.57 121.12,29.8 116.18,29.8 115.51,30.47 112.75,30.47 110.9,32.32 110.9,37.05 110.15,37.8 v2(109.88,37.8)
  IN2 w0.127: v2(99.25,29.73) 100.18,30.66 100.18,33.28 101.69,34.78 102.56,34.78 103.9,36.13 106.25,36.13 107.92,37.8 v2(109.88,37.8)
  BOTTOM w0.076: UC1.BB11 111.85,40.01 109.88,38.05 v2(109.88,37.8)
FFS_INT2: length 145.4
  TOP w0.102: v2(219.23,39.36) v1(220.22,38.38) 220.88,37.72 U5603.11
  IN1 w0.114: v2(219.23,39.36) 218.14,39.36 215.33,36.56 215.33,21.34 217.13,19.54 217.13,12.91 215.52,11.3 211.51,11.3 209.18,13.63 209.18,16.06 207.59,17.66 203.01,17.66 202,18.66 199.43,18.66 v2(199.04,18.27) 196.83,18.27 196.47,17.91 194.54,17.91 194.24,18.22 163.01,18.22 162.49,17.71 159.31,17.71 158.7,17.1 157.86,17.1 157.74,16.98 155.21,16.98 154.52,16.29 145.82,16.29 143.84,18.26 143.1,18.26 142.07,19.3 142.07,19.5 140.54,21.03 139.55,21.03 138.97,20.44 134.61,20.44 132.72,22.32 132.72,22.5 132.48,22.74 132.48,27.72 132.91,28.15 132.91,33.17 v2(132.43,33.65)
  BOTTOM w0.076: v2(132.43,33.65) 132.12,33.95 132.12,34.63 131.89,34.86 131.66,34.86 131.33,35.19 130.99,35.19 130.76,35.42 130.76,35.55 UC1.J4
  BOTTOM w0.102: v2(199.04,18.27) 199.04,15.7 198.82,15.49 QC5.5
FFS_INT2_Q: length 19.4
  BOTTOM w0.102: HDD1.4 212.15,8.79 211.36,8 207.55,8 206.87,8.67 v2(206.87,10.18) 206.87,10.7 203.48,14.09 201.07,14.09 200.32,14.84 RS1.2 199.67,14.84 QC5.6
GC6_THM_DIS#: length 37.7
  TOP w0.102: v1(41.41,21.46) v2(41.41,22.03) 41.41,22.31 RE450.1 ; UE1.24 42.34,42.26 v2(42.07,42.53)
  IN3 w0.135: v2(41.41,22.03) 41.41,23.93 40.82,24.52 39.65,24.52 39.26,24.92 39.26,26.24 37.58,27.91 37.58,28.88 35.83,30.62 35.5,30.62 35.27,30.86 35.27,32.04 34.71,32.6 34.71,34.52 34.57,34.65 34.57,36.83 35,37.26 35,41.54 35.36,41.89 v2(35.36,43.26)
  BOTTOM w0.102: v2(42.07,42.53) 42.07,43.09 41.22,43.94 38.45,43.94 38.13,43.62 35.72,43.62 v2(35.36,43.26)
GPP_B23: length 11.1
  TOP w0.089: 119.37,36.63 119.73,36.63 119.86,36.77 119.86,37.21 119.67,37.4 119.29,37.4 v2(118.9,37)
  TOP w0.102: RC365.1 120.42,30.65 120.42,31.1 v1(119.64,31.89) 119.11,32.42 118.61,32.42 118.34,32.68 118.34,33.03 118.67,33.36 118.67,33.93 118.92,34.18 118.92,36.19 119.37,36.63
  BOTTOM w0.076: UC1.AM7 119.05,37.16 v2(118.9,37)
GPP_C5: length 5.8
  BOTTOM w0.076: UC1.W1 125.17,33.79 126.26,32.7 126.65,32.7 126.78,32.57
  BOTTOM w0.102: RC25.1 129,31.3 v1(128.57,31.73) 127.92,32.38 126.97,32.38 126.78,32.57
GPU_B+:
  vias: v1(168.72,90.98) v2(166.25,93.4) v2(166.25,92.05) v2(166.25,90.7) v2(166.25,84.12) v2(166.25,82.78) v2(166.25,81.43) v2(167.26,93.4) v2(167.26,92.05) v2(167.26,90.7) v2(167.26,84.12) v2(167.26,82.78) v2(167.26,81.43) v2(167.67,88.45) v2(167.67,87.82) v2(167.67,87.18) v2(168.53,79.13) v2(168.53,78.49) v2(168.53,77.86) v2(169.12,79.12) v2(169.12,78.49) v2(169.12,77.85) v2(169.76,88.41) v2(169.76,87.77) v2(169.76,87.14)
GPU_PWR_LEVEL: length 16.2
  TOP w0.102: UE1.21 41.14,40.71 41.3,40.88 41.3,41.79 40.52,42.58 37.52,42.58 v2(36.91,43.19)
  BOTTOM w0.102: RE451.1 29.4,41.45 v1(30.67,41.45) 32.22,41.45 33.83,43.06 34.85,43.06 35.13,42.78 36.5,42.78 v2(36.91,43.19)
GPU_THM_SMBCLK: length 86.4
  TOP w0.102: Q2601.3 85.32,14.74 85.11,14.95 83.53,14.95 83.38,14.8 v1(82.87,14.8) 82.79,14.88 82.79,15.15 83.06,15.42 v2(83.06,15.5) ; UE1.12 37.54,38.84 37.36,38.66 37.36,38.66 37.06,38.36 37.06,34.97 38.61,33.42 v2(38.61,30.39) ; RC399.2 89.8,16.23 v2(88.81,15.24)
  BOTTOM w0.102: v2(88.81,15.24) 88.45,15.6 83.25,15.6 83.15,15.5 v2(83.06,15.5) 83.06,15.5 83.06,15.41 82.62,14.97 82.17,14.97 81.49,14.28 57.13,14.28 56.37,15.04 42.85,15.04 40.77,17.13 40.77,25.23 43.64,28.1 43.64,30.23 43.18,30.69 41.87,30.69 41.49,30.31 38.69,30.31 v2(38.61,30.39)
GPU_THM_SMBDAT: length 78.9
  TOP w0.102: RC397.2 84.97,17.08 84.81,17.08 84.69,17.2 84.18,17.2 v1(84.02,17.05) Q2601.6 82.89,15.91 82.48,15.49 v2(82.48,15.49) ; UE1.11 37.14,38.75 36.83,38.45 36.83,34.88 38.29,33.42 38.29,31.08 v2(38.1,30.89)
  BOTTOM w0.102: v2(38.1,30.89) 38.73,30.89 39.06,30.56 41.42,30.56 41.77,30.92 43.43,30.92 43.92,30.43 43.92,27.56 41.81,25.45 41.81,16.42 42.95,15.27 56.46,15.27 57.23,14.51 81.39,14.51 82.08,15.2 82.18,15.2 v2(82.48,15.49)
GT1N: length 28
  IN3 w0.254: v2(168.26,70.8) 168.26,70.26 167.65,69.65 164.11,69.65 163.22,70.54 163.22,71.94 164.11,72.83 164.11,74.48 161.5,77.1 159.39,77.1 158.02,78.47 158.02,82.86 v2(157.51,83.37)
  BOTTOM w0.254: PL605.2 157.13,82.99 v2(157.51,83.37) ; PR673.1 v2(168.26,70.8) 168.26,71.94 PR670.1
GT1P: length 33.7
  IN3 w0.254: v2(157.51,82.69) 157.61,82.59 157.61,78.34 159.24,76.72 161.34,76.72 163.73,74.32 163.73,72.99 162.84,72.1 162.84,70.39 163.95,69.27 167.81,69.27 168.66,70.12 171.45,70.12 v2(172.1,70.78)
  BOTTOM w0.102: v2(172.1,70.78) 173.5,69.38 v1(173.5,68.74)
  BOTTOM w0.254: PL605.3 157.81,82.99 v2(157.51,82.69) ; PR674.2 PR675.1 171.73,71.15 v2(172.1,70.78)
GT2N: length 48.3
  TOP w0.102: v1(172.65,74.61) PR666.1
  TOP w0.254: PR677.2 170.59,72.53 171.27,73.21 v2(171.48,73.21) 171.48,74.56 PR666.1
  IN3 w0.254: v2(171.48,73.21) 171.73,73.46 171.73,78.42 172.24,78.93 172.24,95.18 170.87,96.55 158.18,96.55 157.25,95.63 157.25,91.37 v2(157.13,91.24)
  BOTTOM w0.254: PL604.2 v2(157.13,91.24)
GT2P: length 46.5
  IN3 w0.254: v2(157.76,91.24) 157.64,91.37 157.64,95.47 158.31,96.15 170.64,96.15 171.81,94.98 171.81,79.03 171.35,78.58 171.35,73.97 v2(170.97,73.59)
  BOTTOM w0.102: PR668.1 170.29,74.96 v1(170.18,75.06)
  BOTTOM w0.254: v2(170.97,73.59) PR668.1 170.29,72.94 PR667.2 ; PL604.3 v2(157.76,91.24)
GT_SNUB1: length 3
  TOP w0.102: v1(159.97,80.2) PC678.1
  TOP w0.635: PC678.1 161.26,81.08 PR676.2
GT_SNUB2: length 1.5
  TOP w0.102: PC670.1 v1(158.69,90.93)
GT_SW1: length 1.4
  TOP w0.102: v2(161.32,85.2) v1(159.93,85.2)
  vias: v2(161.95,85.2)
GT_SW2: length 1.7
  TOP w0.102: v2(161.7,93.4) v1(160.01,93.4)
  vias: v2(162.33,93.4)
H_CATERR#: length 8.7
  BOTTOM w0.076: UC1.D63 133.62,69.62 133.9,69.34 134.19,69.34 134.4,69.25 134.58,69.19 134.86,69.19 134.96,69.22 135.1,69.22 135.12,69.2 135.53,69.2 135.67,69.34 136.46,69.34 136.68,69.12 137.66,69.12 v1(137.83,68.95) 137.95,68.83
  BOTTOM w0.102: RC79.2 140.81,68.13 140.58,67.9 138.88,67.9 137.95,68.83
H_CPU_SVIDALRT#: length 4
  BOTTOM w0.076: UC1.B63 134.92,69.88 136.79,69.88 136.86,69.81 137.95,69.81
  BOTTOM w0.102: RC153.1 138.34,69.81 137.95,69.81
H_CPUPWRGD: length 6.7
  BOTTOM w0.102: UC1.A68 135.51,72.75 137.25,74.49 137.25,75.43 138.48,76.66 T9.1
H_DRAMRST#: length 118.9
  TOP w0.102: v1(67.54,58.33) v2(67.54,58.85) 67.95,58.85 68.49,59.39 RD31.2 68.53,59.52 RD35.2 RC1126.1 ; v2(105.14,36.55) 109.23,36.55 112.94,40.27 115.75,40.27 v2(116.13,40.65)
  IN1 w0.114: v2(58.58,29.33) 59.15,29.9 63.66,29.9 64.35,30.6 64.35,42.17 65.78,43.59 66.7,43.59 67.26,44.15 67.26,44.99 64.35,47.9 64.35,56.05 66.09,57.79 66.48,57.79 v2(67.54,58.85)
  IN3 w0.076: 104.89,36.55 v2(105.14,36.55)
  IN3 w0.135: v2(58.58,29.33) 57.59,28.34 57.59,22.71 58.98,21.32 60.94,21.32 61.85,20.41 69.5,20.41 69.93,20.84 82.15,20.84 89.44,28.13 93.27,28.13 96.26,31.12 96.26,32.35 97.63,33.71 99.29,33.71 100.45,34.88 102.32,34.88 103.99,36.55 104.89,36.55
  BOTTOM w0.102: v2(116.13,40.65) 116.45,40.97 UC1.AT13
H_PROCHOT#: length 307.1
  TOP w0.102: UE6.4 37.38,61.88 CE86.1 34.12,62.64 v2(32.71,64.05) ; PQ3.1 194.34,103.45 191.54,106.24 185.55,106.24 180.34,101.04 v1(180.34,94.89) 180.34,93.13 173.79,86.57 173.79,64.62 170.86,61.68 170.08,61.68 169.31,60.92 v2(168.66,60.92) ; PQ721.1 180.72,46.18 180.72,46.69 v2(180.18,47.23) 179.99,47.43 PR777.1 ; RC84.1 144.85,71.81 144.86,71.83 RC83.2 145.32,72.23 144.4,73.15 144.4,74.53 v2(143.11,75.83)
  TOP w0.254: PQ2.6 196.56,102.8 196.37,102.99 195.94,102.99 195.3,102.35 PQ3.1
  IN1 w0.114: v2(168.66,60.92) 168.66,60.9 167.37,59.62 157.44,59.62 154.45,62.61 154.45,68.94 152.42,70.98 141.86,70.98 140.39,72.45 140.39,74.18 140.94,74.72 143.39,74.72 143.58,74.91 143.58,75.36 v2(143.11,75.83) 141.1,77.83 141.1,93.63 134.92,99.81 104.24,99.81 100.99,96.57 54.22,96.57 52.92,95.27 50.13,95.27 49.89,95.51 48.15,95.51 47.89,95.25 47.89,92 45.11,89.22 45.11,88.29 41.25,84.43 41.07,84.43 36.78,80.14 36.78,78.74 32.22,74.19 32.22,73.34 v2(31.83,72.94)
  IN2 w0.127: v2(176.61,59.06) 176.21,58.66 176.21,53.83 176.7,53.34 176.7,49.55 177.97,48.28 179.32,48.28 180.18,47.42 v2(180.18,47.23)
  IN3 w0.135: v2(168.66,60.92) 173.16,60.92 175.01,59.06 v2(176.61,59.06)
  BOTTOM w0.102: v2(31.83,72.94) 33.13,71.65 33.13,64.47 v2(32.71,64.05) ; v2(168.66,60.92) 167.87,61.7 PC605.2 PR678.1
H_PROCHOT#_R: length 11.6
  TOP w0.102: v2(137.55,71.5) 138.38,72.33 141.47,72.33 v1(142.41,71.39) 143.01,70.8 CC1809.1 RC84.2
  BOTTOM w0.076: UC1.C65 134.01,70.75 134.53,70.99 134.58,71.01 137.06,71.01 v2(137.55,71.5)
H_PROCHOT_EC: length 5.5
  TOP w0.102: UE1.83 38.34,56.95 v1(38.47,57.09) 38.47,57.35 38.23,57.59 36.99,57.59 36.66,57.92 RE380.2 36.66,58.7 36.73,58.78 UE6.2
H_THERMTRIP#: length 8.2
  BOTTOM w0.076: UC1.C63 134.34,69.48 134.34,69.46 134.46,69.41 134.61,69.36 134.75,69.36 134.94,69.42 135.09,69.42 135.18,69.37 135.46,69.37 135.6,69.5 136.55,69.5 136.76,69.3 137.93,69.3 137.95,69.27
  BOTTOM w0.102: RC80.2 141.11,68.93 140.38,68.19 139.56,68.19 v1(139.13,68.63) 138.66,68.63 138.01,69.27 137.95,69.27
H_VCCST_PWRGD: length 106.3
  TOP w0.102: v2(136.62,10.9) 136.73,11.02 136.73,11.44 136.16,12.01 132.32,12.01 131.96,11.64 123.32,11.64 v1(122.58,10.9) 121.4,9.72 104.79,9.72 102.76,11.76 UC12.4
  IN1 w0.114: v2(143.58,36.71) 143.16,37.13 143.16,38.03 142.7,38.49 142.7,41.66 141.33,43.03 141.33,45.93 140.44,46.82 140.44,50.19 141.07,50.82 141.07,51.96 140.1,52.93 140.1,66.46 139.37,67.19 139.37,70.81 v2(140.25,71.69)
  IN2 w0.127: v2(140.36,20.61) 139.75,21.22 139.75,26.91 140.82,27.97 140.82,32.85 142.95,34.98 142.95,36.08 v2(143.58,36.71)
  IN3 w0.135: v2(136.62,10.9) 136.62,12.67 138.6,14.65 139.22,14.65 140.57,15.99 140.57,20.41 v2(140.36,20.61)
  BOTTOM w0.102: RC78.1 139.68,71.69 v2(140.25,71.69) RC1118.2
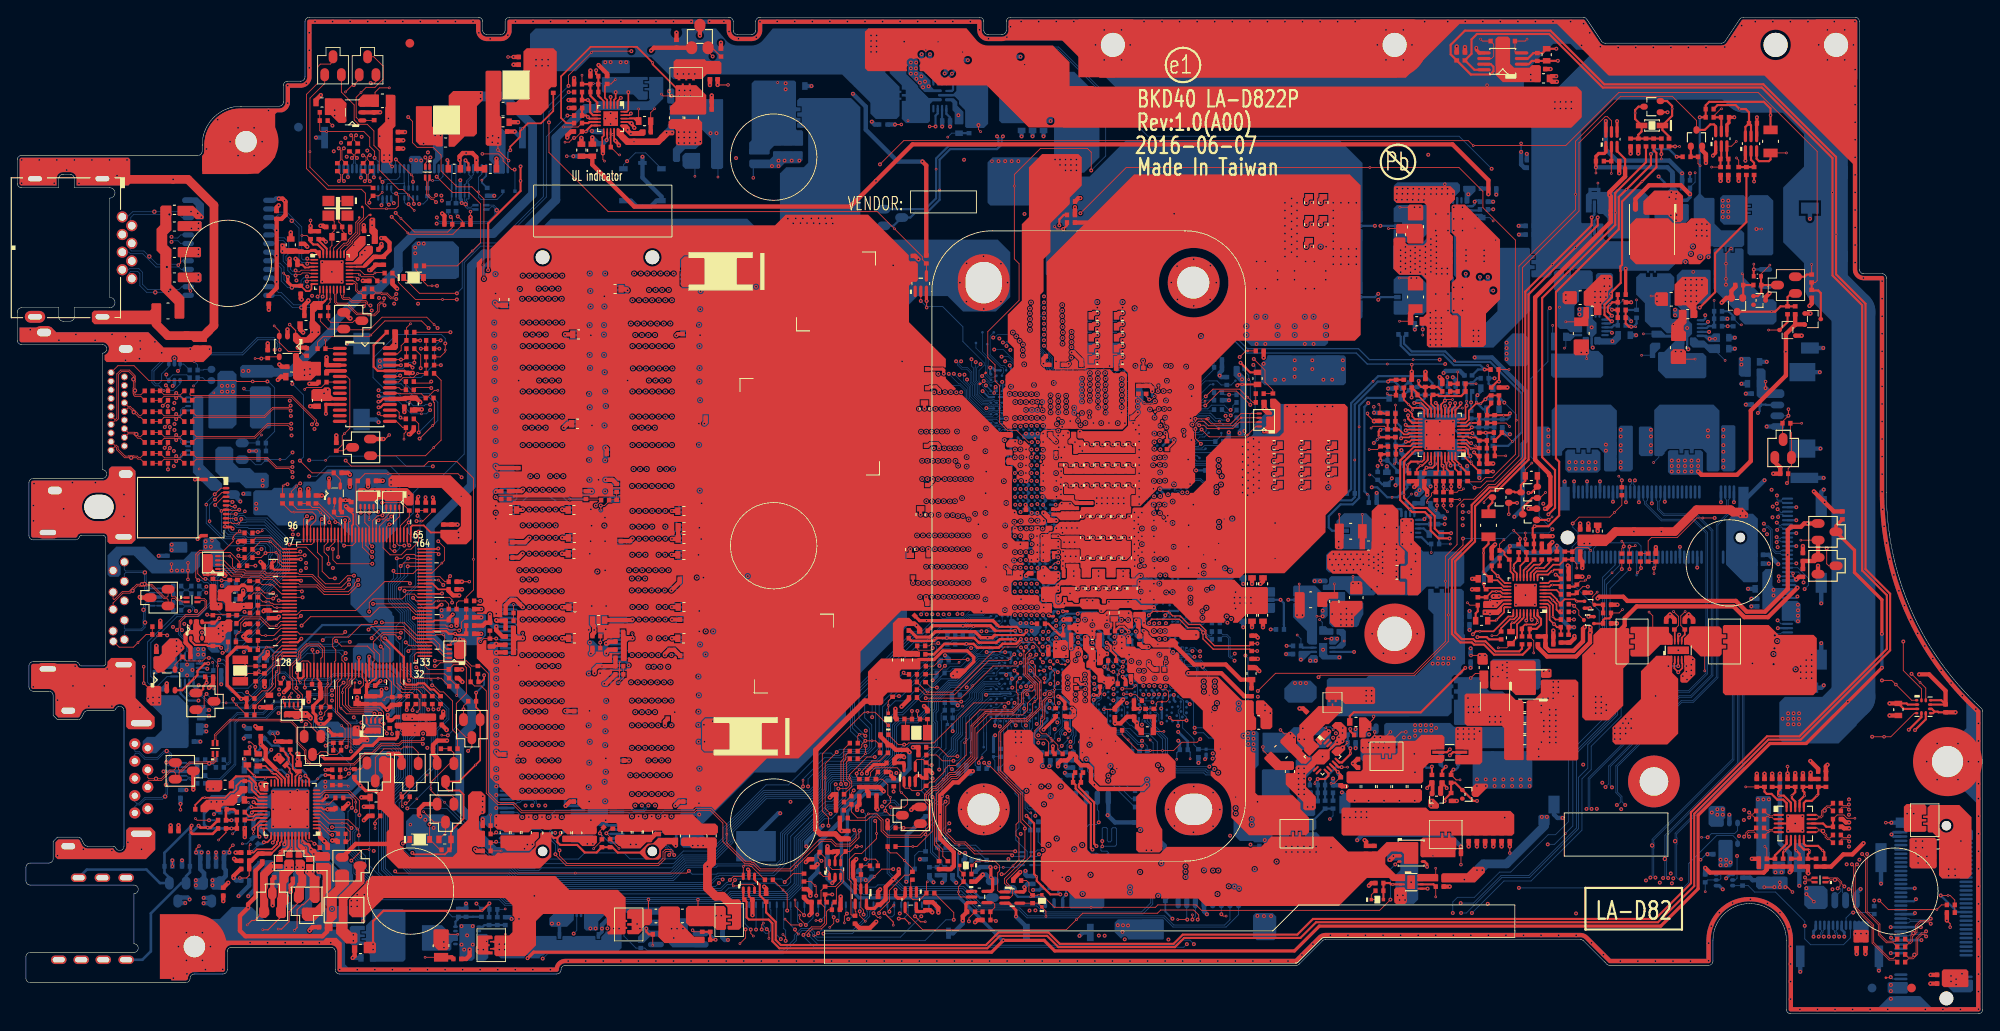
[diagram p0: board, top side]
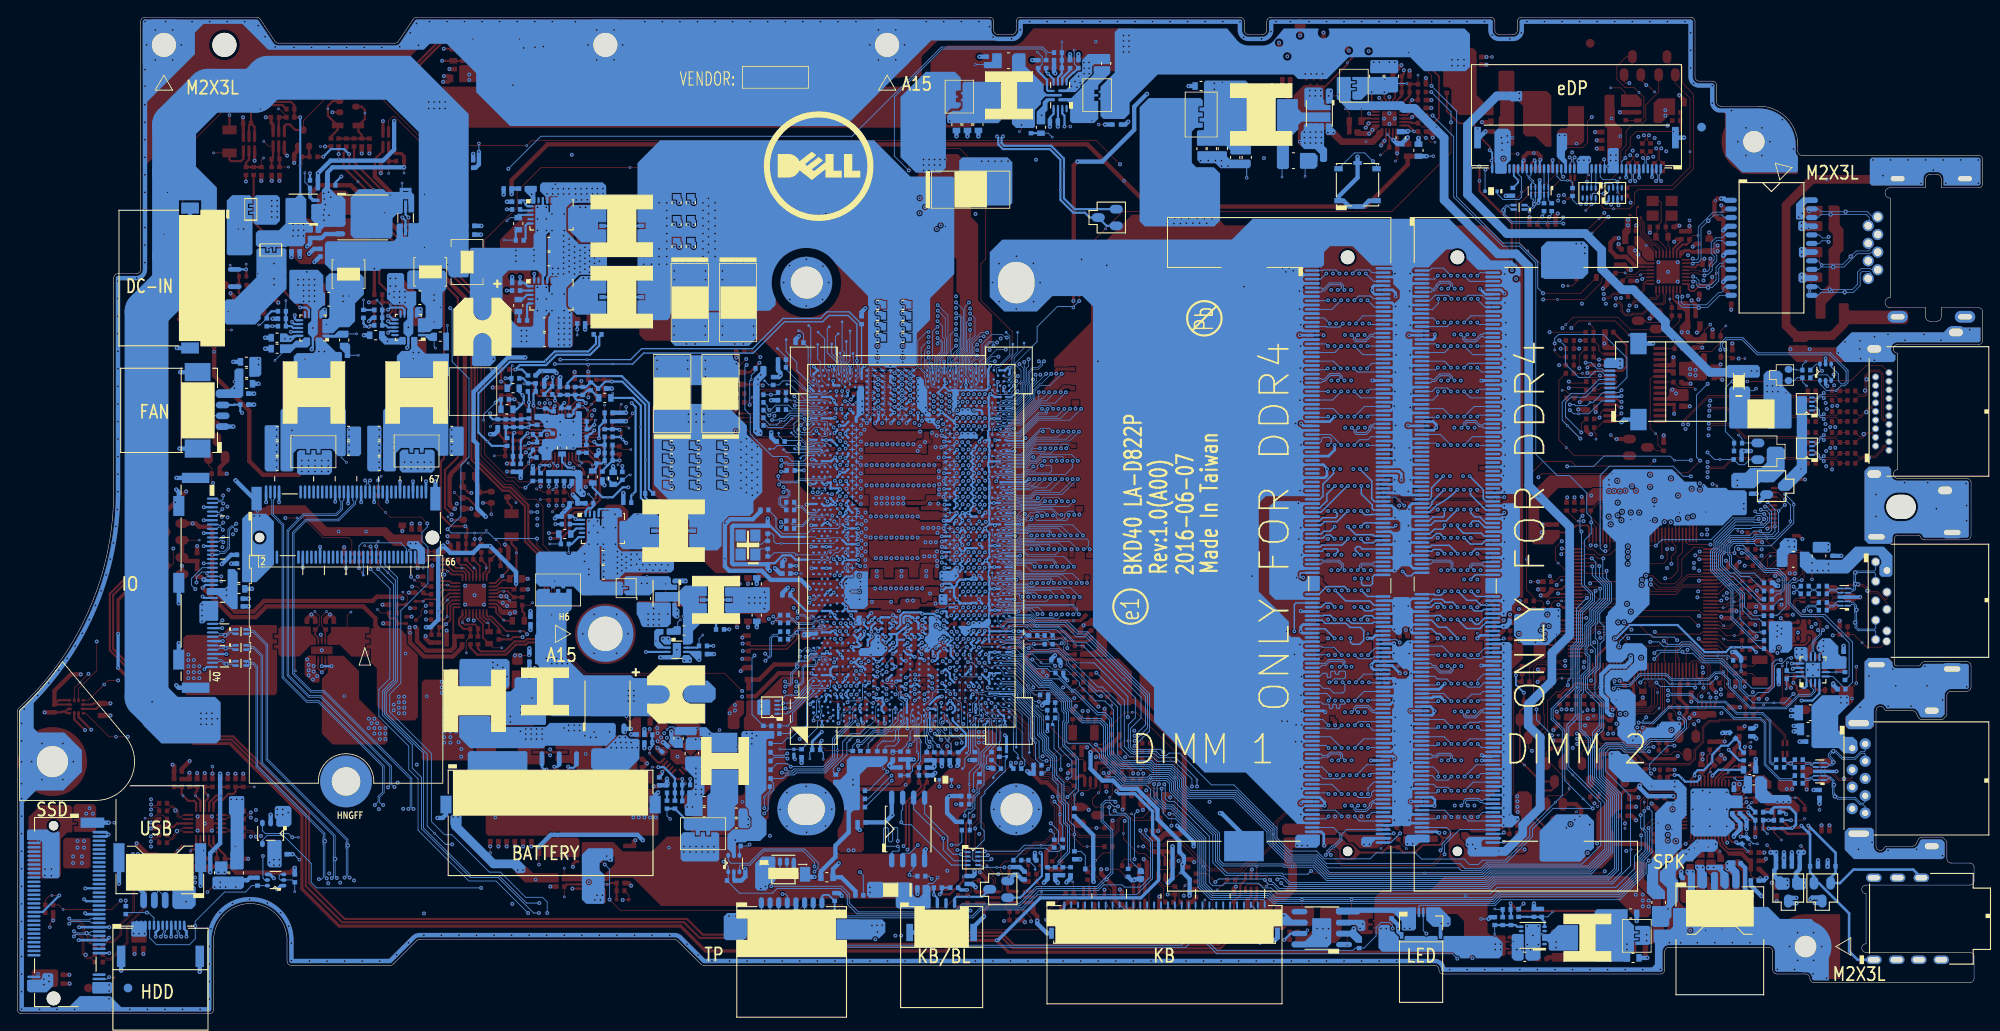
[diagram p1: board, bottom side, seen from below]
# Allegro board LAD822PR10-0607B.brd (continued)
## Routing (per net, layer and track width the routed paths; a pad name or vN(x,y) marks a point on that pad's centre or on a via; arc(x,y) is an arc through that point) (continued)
HDA_BIT_CLK: length 8
  BOTTOM w0.076: UC1.AY22 113.99,45.37 113.63,45.02 113.63,44.75 113.46,44.57 112.4,44.57 112.15,44.83 v1(110.66,44.83) 110.09,44.25 108.09,44.25 RC93.2
HDA_CODEC_BITCLK: length 102.8
  TOP w0.102: UA1.6 35.14,23.47 36.14,22.47 38.29,22.47 v1(39.36,21.4) 39.53,21.24 v2(39.53,20.66)
  IN1 w0.114: v2(98.94,34.35) 98.94,30.98 94.72,26.77 v2(94.72,26.58)
  BOTTOM w0.076: RC93.1 CC27.1 108.98,43.37 108.04,43.37 108.01,43.33 107.06,43.33 106.96,43.43 106.58,43.43 106.2,43.05 106.2,42.73 106.39,42.54 106.39,42.16 104.87,40.63 103.41,40.63
  BOTTOM w0.102: v2(39.53,20.66) 39.53,19.03 40.3,18.26 40.3,16.8 42.46,14.64 56.2,14.64 56.96,13.88 81.66,13.88 82.34,14.56 83.28,14.56 83.84,15.12 87.68,15.12 87.98,14.83 89.09,14.83 89.51,15.25 89.51,20.55 93.56,24.59 94.27,24.59 94.62,24.95 94.62,26.47 v2(94.72,26.58) ; v2(98.94,34.35) 98.94,36.73 102.84,40.63 103.41,40.63
HDA_CODEC_RST#: length 84.6
  TOP w0.102: v2(95.02,26.07) 96,26.07 96.35,26.41 96.35,26.79 95.99,27.15 95.99,29.17 RC95.1 ; v2(39.59,23) 39.59,24.68 38.39,25.88 35.53,25.88 35.12,25.47 UA1.11
  BOTTOM w0.102: v2(95.02,26.07) 95.02,24.78 94.44,24.19 93.73,24.19 89.92,20.38 89.92,15.08 89,14.16 82.51,14.16 81.82,13.47 56.8,13.47 56.03,14.23 42.29,14.23 39.9,16.63 39.9,18.06 39.07,18.89 39.07,21 39.59,21.52 v2(39.59,23)
HDA_CODEC_SDIN0: length 2.5
  TOP w0.102: RA130.2 36.09,24.27 v1(35.86,24.27) UA1.8
HDA_CODEC_SDOUT: length 82
  TOP w0.102: v2(95.91,26.6) 95.61,26.91 95.61,29.17 95.88,29.44 95.88,29.95 RC94.1 ; UA1.5 35.04,23.07 36.05,22.07 v1(37.6,22.07) 38.12,22.07 v2(38.68,21.51)
  BOTTOM w0.102: v2(95.91,26.6) 95.91,25.02 94.63,23.73 93.92,23.73 90.38,20.19 90.38,14.89 89.19,13.7 82.7,13.7 82.01,13.01 56.61,13.01 55.84,13.77 42.1,13.77 39.44,16.44 39.44,17.87 38.58,18.73 38.58,21.41 v2(38.68,21.51)
HDA_CODEC_SYNC: length 86
  TOP w0.102: v2(39.17,23.48) v1(39.17,24.5) 39.17,24.74 38.27,25.65 35.62,25.65 35.04,25.07 UA1.10 ; v2(95.33,26.6) 95.33,29.22 95.66,29.54 95.66,30.64 RC92.1
  BOTTOM w0.102: v2(39.17,23.48) 39.18,23.47 39.18,21.44 38.83,21.08 38.83,18.81 39.67,17.97 39.67,16.53 42.2,14 55.94,14 56.7,13.24 81.92,13.24 82.61,13.93 89.09,13.93 90.15,14.98 90.15,20.29 93.82,23.96 94.53,23.96 95.56,24.99 95.56,26.37 v2(95.33,26.6)
HDA_RST#: length 31
  TOP w0.102: v2(98.17,31.02) v1(98.17,30.13) 97.56,29.52 RC95.2
  BOTTOM w0.076: 105.95,45.53 109.58,45.53 110.15,46.09 111.8,46.09 112.06,46.35 112.82,46.35 112.87,46.3 114.38,46.3 UC1.AW22
  BOTTOM w0.102: v2(98.17,31.02) 98.16,31.02 96.43,32.74 96.43,37.04 103.63,44.23 104.65,44.23 105.95,45.53
HDA_SDIN0: length 112.2
  TOP w0.102: v2(94.13,23.15) 93.5,23.78 v1(93.5,27.33) 93.5,28.96 v2(94.84,30.3) ; RA130.1 38.56,25 38.8,24.76 38.8,23.93 v2(38.72,23.85)
  BOTTOM w0.089: 104.64,43.02 105.04,43.02 106.91,44.89 109.72,44.89 110.3,45.48 UC1.BA21
  BOTTOM w0.102: v2(94.13,23.15) 93.66,23.15 90.61,20.1 90.61,14.79 89.28,13.47 82.79,13.47 82.11,12.78 56.51,12.78 55.75,13.55 42.01,13.55 39.21,16.34 39.21,17.78 38.27,18.72 38.27,23.4 v2(38.72,23.85) ; 104.64,43.02 103.78,43.02 97.41,36.66 97.41,34.25 98.63,33.03 98.63,30.89 98.35,30.61 95.15,30.61 94.84,30.31 v2(94.84,30.3)
HDA_SDOUT: length 30.1
  TOP w0.102: RC94.2 97.74,30.9 97.74,31.2 v2(98.15,31.61) v1(98.91,31.61) 99.34,31.61 RC187.2 RC223.2
  BOTTOM w0.102: v2(98.15,31.61) 96.66,33.09 96.66,36.89 103.75,43.98 104.78,43.98 106.14,45.33 109.64,45.33 110.23,45.91 112.55,45.91 UC1.BB22
HDA_SYNC: length 27.3
  TOP w0.102: RC92.2 97.27,32.16 v1(97.46,32.35) 97.5,32.39 97.95,32.39 v2(98.15,32.19)
  BOTTOM w0.089: 104.92,43.67 106.35,45.1 109.68,45.1 110.31,45.73 113.02,45.73 UC1.BA22
  BOTTOM w0.102: v2(98.15,32.19) 96.89,33.45 96.89,36.73 103.83,43.67 104.92,43.67
HDD_A0_PRE0: length 4
  TOP w0.254: RS27.2 RS24.1 207.23,18.46 207.41,18.64 v1(207.41,18.89) 207.28,19.02 206.77,19.02 206.27,19.52 US2.9
HDD_A0_PRE1: length 4.3
  TOP w0.254: US2.19 205.27,24.44 204.45,25.26 v1(203.88,25.26) 203.79,25.34 203.79,25.75 203.99,25.95 RS30.2 RS23.1
HDD_B0_EQ: length 6.4
  TOP w0.102: v1(212.68,22.64) 211.79,22.64 211.41,23.02 210.62,23.02 RS38.1
  TOP w0.254: RS38.1 RS37.1 209.38,21.65 208.99,22.03 US2.13
HDD_B0_PRE0: length 3.3
  TOP w0.254: US2.8 205.77,19.02 v1(205.91,18.88) 206.28,18.51 RS21.1 RS28.2
HDD_B0_PRE1: length 3.5
  TOP w0.254: RS18.1 RS29.2 206.66,25.81 206.84,25.64 v1(206.84,25.24) 206.27,24.68 US2.17
HDD_DEVSLP: length 99.9
  IN1 w0.114: v2(138.98,27.92) 138.98,26.63 140.35,25.27 140.35,22.96 142.79,20.52 143.1,20.52 144.15,19.47 145.17,19.47 146.9,17.73 153.92,17.73 154.62,18.44 157.15,18.44 158.98,20.27 182.55,20.27 182.95,19.87 202.5,19.87 203.51,18.86 209.34,18.86 212.89,15.31 212.89,14.07 213.85,13.11 v2(214.91,13.11)
  BOTTOM w0.102: v2(138.98,27.92) 138.95,27.88 137.71,27.88 137.47,28.12 134.05,28.12 132.54,29.63 v1(132.54,30.47) 132.54,31.82 UC1.J1 ; R5605.2 v2(214.91,13.11)
HDD_DEVSLP_C: length 7
  TOP w0.102: v2(222.61,13.7) v1(223.46,13.7) 223.7,13.7 224.23,13.16 R6526.1 RB1.2
  BOTTOM w0.254: v2(222.61,13.7) 224.53,11.78 JSSD1.38
HDD_DEVSLP_R: length 4.4
  BOTTOM w0.102: HDD1.5 211.65,11.1 212.27,11.72 v2(212.47,11.72) 214.74,11.72 R5605.1
HDD_REXT_SATA0: length 6.3
  TOP w0.102: v1(200.04,26.27) RS26.2
  TOP w0.254: US2.20 204.77,24.4 204.37,24.8 203.69,24.8 203.03,25.46 202.47,25.46 202.21,25.71 RS31.1 RS26.2
HDMI_HPD: length 178.6
  IN2 w0.127: v2(31.86,65.01) 31.37,64.52 31.37,61.88 32.1,61.16 32.1,57.14 34.26,54.97 37.8,54.97 38.36,54.41 38.36,53.45 v2(36.53,51.62)
  IN3 w0.135: v2(131.38,36.07) 132,35.45 132,30.29 131.3,29.59 131.3,26.29 130.72,25.72 130.72,25.37 129.24,23.89 129.24,22.26 127.45,20.47 127.45,19.21 124.64,16.4 124.64,14.62 120.7,10.68 115.55,10.68 115.02,11.21 109.14,11.21 108.88,10.94 108.88,10.57 108.66,10.35 101.24,10.35 100.37,11.22 98.87,11.22 98,10.35 94.56,10.35 94.02,10.9 94.02,11.38 92.96,12.43 90.36,12.43 89.34,11.41 87.77,11.41 87.29,10.94 74.95,10.94 74.5,11.39 57.58,11.39 56.57,12.39 55.95,12.39 54.59,13.75 53.7,13.75 52.38,15.07 51.41,15.07 48.06,18.42 48.06,19.97 46.18,21.85 46.18,24.7 43.07,27.81 42.55,27.81 38.12,32.24 38.12,37.35 37.12,38.35 37.12,40.44 37.57,40.88 37.57,42.2 37.93,42.55 37.93,43.56 37.24,44.25 37.24,47.3 36.33,48.22 36.33,51.42 v2(36.53,51.62)
  BOTTOM w0.076: 129.65,38.2 129.34,38.51 UC1.L9
  BOTTOM w0.102: QX5.3 26.98,64.17 27.56,63.58 28.21,63.58 RX14.1 v1(30.41,64.19) 31.04,64.19 v2(31.86,65.01) ; 129.65,38.2 129.65,36.42 129.84,36.23 131.22,36.23 v2(131.38,36.07)
HDMIOUT_CLK+: length 6.4
  TOP w0.094: CHR13.2 18.87,69.04 18.57,69.04 v2(18.39,68.86) 18.19,69.07 17,69.07 16.95,69.02 16.95,69.02 CHO8.1 RHO3.1
  BOTTOM w0.094: v2(18.39,68.86) 18.6,69.07 18.8,69.07 19.07,69.34 19.07,69.84 19.25,70.03 19.34,70.03 19.5,69.87 RP58.1
HDMIOUT_CLK-: length 6.5
  TOP w0.094: RHO1.1 RHO9.1 17,69.25 18.19,69.25 v2(18.39,69.45) 18.62,69.22 18.84,69.22 CHR14.2
  BOTTOM w0.094: v2(18.39,69.45) 18.59,69.25 18.72,69.25 18.88,69.41 18.88,69.92 19.18,70.21 19.36,70.21 19.52,70.37 RP58.2
HDMIOUT_HPD: length 28.1
  TOP w0.102: v2(28.95,73.22) v4(27.25,73.22) 25.42,73.22 25.3,73.34 15.22,73.34 13.5,75.05 11.65,75.05 JHDMI.19
  BOTTOM w0.102: v2(28.95,73.22) 29.06,73.22 29.79,72.49 29.79,67.43 28.77,66.42 RX15.2 28.78,66.07 RX34.1
HDMIOUT_R_CK+: length 3.2
  TOP w0.094: JHDMI.10 12.81,70.16 12.99,70.16 v3(13.48,69.67) 14.08,69.07 14.28,69.07 RHO3.2
HDMIOUT_R_CK-: length 3.2
  TOP w0.094: JHDMI.12 12.81,70.34 13.06,70.34 13.38,70.03 13.43,70.03 13.93,69.53 13.93,69.48 14.15,69.25 14.28,69.25 RHO1.2
HDMIOUT_R_D0+: length 12.1
  TOP w0.094: JHDMI.7 11.26,68.66 11.47,68.66 11.71,68.9 11.71,74.02 12.04,74.36 12.91,74.36 13.44,73.84 v3(13.44,73.48) 13.44,72.5 13.4,72.46 13.4,71.88 13.44,71.84 13.44,71.67 13.61,71.5 14.3,71.5 RHO4.2
HDMIOUT_R_D0-: length 12.1
  TOP w0.094: RHO2.2 14.3,71.68 13.69,71.68 13.62,71.75 v3(13.62,72.17) 13.62,73.15 13.65,73.18 13.65,73.77 13.62,73.81 13.62,73.91 12.99,74.54 11.97,74.54 11.52,74.1 11.52,68.97 11.39,68.84 11.26,68.84 JHDMI.9
HDMIOUT_R_D1+: length 2.9
  TOP w0.094: RHO7.2 14.27,66.64 13.95,66.64 13.43,67.16 12.81,67.16 JHDMI.4
HDMIOUT_R_D1-: length 2.9
  TOP w0.094: RHO5.2 14.27,66.82 14.08,66.82 v3(13.78,67.12) 13.56,67.34 12.81,67.34 JHDMI.6
HDMIOUT_R_D2+: length 5
  TOP w0.094: JHDMI.1 11.26,65.66 11.39,65.66 11.49,65.56 11.49,65.32 12.42,64.39 v3(13.19,64.39) 13.81,64.39 13.97,64.23 14.27,64.23 RHO8.2
HDMIOUT_R_D2-: length 5
  TOP w0.094: RHO6.2 14.27,64.41 14.05,64.41 13.88,64.58 13.52,64.58 13.48,64.61 12.89,64.61 12.86,64.58 12.49,64.58 11.67,65.4 11.67,65.64 11.47,65.84 11.26,65.84 JHDMI.3
HDMIOUT_SCLK: length 12.5
  IN3 w0.135: JHDMI.15 11.19,72.25 11.47,72.53 11.47,74.48 11.92,74.93 17.73,74.93 18.21,74.44 v2(18.6,74.44)
  BOTTOM w0.094: RHR11.1 19.26,75.24 QX4.6 18.84,74.69 v2(18.6,74.44)
HDMIOUT_SDATA: length 14
  IN3 w0.135: JHDMI.16 11.98,72.33 11.8,72.33 11.71,72.42 11.71,74.38 12.02,74.68 17.63,74.68 17.92,74.39 17.92,74.17 17.77,74.02 v2(17.25,74.02)
  BOTTOM w0.094: RHR8.1 19.62,73.99 18.01,73.99 17.64,73.62 17.64,73.44 QX4.3 17.25,73.63 v2(17.25,74.02)
HDMIOUT_TX0+: length 5.9
  TOP w0.094: CHR11.2 18.91,71.48 18.57,71.48 v2(18.39,71.3) 18.19,71.5 16.99,71.5 CHO9.1 15.68,71.04 RHO4.1
  BOTTOM w0.094: v2(18.39,71.3) 18.59,71.5 18.73,71.5 19.18,71.05 19.33,71.05 19.5,70.87 RP58.3
HDMIOUT_TX0-: length 6
  TOP w0.094: CHR12.2 18.86,71.66 18.62,71.66 v2(18.39,71.89) 18.19,71.69 16.98,71.69 RHO10.1 15.68,72.14 RHO2.1
  BOTTOM w0.094: RP58.4 19.5,71.37 19.36,71.23 19.26,71.23 18.81,71.68 18.6,71.68 v2(18.39,71.89)
HDMIOUT_TX1+: length 6.2
  TOP w0.094: CHR9.2 18.87,66.63 18.58,66.63 v2(18.39,66.44) 18.22,66.62 16.98,66.62 CHO10.1 RHO7.1
  BOTTOM w0.094: RP59.3 19.51,65.73 19.33,65.91 19.18,65.91 18.91,66.18 18.91,66.43 18.7,66.64 18.59,66.64 v2(18.39,66.44)
HDMIOUT_TX1-: length 6.2
  TOP w0.094: RHO5.1 RHO11.1 17.03,66.8 18.17,66.8 v2(18.39,67.02) 18.61,66.81 18.84,66.81 CHR10.2
  BOTTOM w0.094: v2(18.39,67.02) 18.59,66.82 18.77,66.82 19.09,66.5 19.09,66.26 19.26,66.09 19.36,66.09 19.5,66.23 RP59.4
HDMIOUT_TX2+: length 6.1
  TOP w0.094: RHO8.1 CHO11.1 16.98,64.2 18.19,64.2 v2(18.39,64) 18.58,64.19 18.89,64.19 CHR7.2
  BOTTOM w0.094: v2(18.39,64) 18.59,64.2 18.8,64.2 19.08,64.49 19.08,64.68 19.26,64.86 19.39,64.86 19.52,64.73 RP59.1
HDMIOUT_TX2-: length 6.2
  TOP w0.094: RHO6.1 RHO12.1 17.03,64.39 18.19,64.39 v2(18.39,64.59) 18.6,64.38 18.82,64.38 CHR8.2
  BOTTOM w0.094: v2(18.39,64.59) 18.59,64.39 18.72,64.39 18.9,64.56 18.9,64.76 19.18,65.04 19.33,65.04 19.51,65.23 RP59.2
HOST_DEBUG_TX: length 329.5
  TOP w0.102: v2(196.44,57.41) v1(195.09,57.41) 194.37,57.41 192.11,55.16 189.14,55.16 188.75,54.76 R5812.2 R6527.2 ; v2(37.82,54.21) 38.76,54.21 39.14,54.58 UE1.81 ; JDEG1.8 25.22,57.37 v2(25.29,57.29)
  IN1 w0.114: v2(196.44,57.41) 196.44,60.61 201.4,65.57 201.4,68.72 201.87,69.18 201.87,70.35 201.66,70.55 201.66,84.06 203.11,85.5 203.11,98.16 200.22,101.05 192.38,101.05 192.19,101.23 191.53,101.23 191.39,101.09 191.36,101.11 163.71,101.11 163.65,101.05 135.5,101.05 135.38,101.17 103.78,101.17 102.29,99.68 83.77,99.68 v2(83.19,99.09)
  IN3 w0.135: v2(83.19,99.09) 81.94,97.85 64.8,97.85 53.93,108.72 38.54,108.72 35.57,105.76 35.57,101.63 34.73,100.78 34.73,96.82 36.58,94.96 40.79,94.96 41.17,94.59 41.17,92.7 41.54,92.33 41.54,87.73 39.95,86.14 38.89,86.14 38.29,85.54 38.29,82.92 37.51,82.14 37.51,55.83 37.82,55.52 v2(37.82,54.21)
  BOTTOM w0.102: v2(37.82,54.21) 37.14,54.9 31.44,54.9 28.92,57.42 26.49,57.42 26.2,57.7 25.71,57.7 v2(25.29,57.29) 25.7,56.89 26.44,56.89 26.51,56.96 28.6,56.96 30.88,54.69 30.88,53.9 31.27,53.51 31.27,51.39 28.91,49.03 28.91,45.85 26.29,43.24 RE73.2
HPOUT-L: length 2.5
  TOP w0.203: UA1.32 27.55,23.07 27.33,22.85 26.82,22.85 RA55.1
HPOUT-R: length 2.3
  TOP w0.203: UA1.33 27.66,22.67 27.44,22.45 v1(27.32,22.45) RA56.1
I2C_SCL_TP: length 56.3
  TOP w0.102: v2(93.07,17.7) 92.68,18.1 92.68,18.54 RZ21.2 93.48,18.09 93.48,16.9 93.99,16.38 Q6501.1 93.3,15.9 v1(92.9,16.3)
  IN3 w0.102: 126.03,32.57 126.03,35.02 126.86,35.85 v2(126.86,36.29)
  IN3 w0.135: 126.03,32.57 126.03,30.08 125.29,29.35 125.29,28.17 124.95,27.82 124.95,25.17 120.78,21 120.78,20 116.7,15.92 115.69,15.92 115.43,15.65 109.55,15.65 109.07,16.14 105.27,16.14 103.06,18.35 96.58,18.35 95.89,17.66 93.11,17.66 v2(93.07,17.7)
  BOTTOM w0.076: v2(126.86,36.29) 126.59,36.29 UC1.U6
I2C_SCL_TP_Q: length 63.3
  TOP w0.102: v1(136,11.44) v2(136,10.9) ; Q6501.6 93.99,17.03 94.33,16.7 95.34,16.7 95.65,16.39 95.65,15.33 94.8,14.47 94.8,13.13 R6506.2 94.28,12.61 C6226.1 93.87,12.05 93.67,11.84 93.67,10.42 93.07,9.82 92.03,9.82 91.57,9.37 v2(91.57,9.1)
  IN1 w0.114: v2(136.17,8.06) 136,8.23 v2(136,10.9)
  BOTTOM w0.102: v2(91.57,9.1) 92.74,7.93 134.04,7.93 134.62,8.52 135.72,8.52 v2(136.17,8.06) ; TPAD1.6 136.35,11.25 v2(136,10.9)
I2C_SDA_TP: length 48.1
  TOP w0.102: v1(97.73,19.38) v2(97.16,19.38) 96.97,19.38 96.38,18.79 RZ20.2 95.29,18.22 Q6501.4
  IN3 w0.102: 125,32.67 125,34.82 126.21,36.03 126.21,36.59 v2(125.81,36.99)
  IN3 w0.135: v2(97.16,19.38) 104.81,19.38 106.99,17.2 111.15,17.2 111.37,17.42 113.67,17.42 113.99,17.1 115.42,17.1 123.82,25.5 123.82,28.32 124.23,28.74 124.23,29.75 125,30.51 125,32.67
  BOTTOM w0.076: v2(125.81,36.99) UC1.U7
I2C_SDA_TP_Q: length 61.5
  TOP w0.102: v2(135.41,10.9) v1(134.31,10.9) ; v2(90.99,9.13) 91.91,10.05 92.97,10.05 93.44,10.52 93.44,12.34 C6225.1 93.02,13.11 93.02,14.26 R6508.2 94.68,14.73 95.29,15.34 Q6501.3
  IN1 w0.114: v2(135.41,10.9) 135.41,8.11 v2(135.36,8.06)
  BOTTOM w0.102: v2(135.36,8.06) 135,7.7 92.23,7.7 90.99,8.95 v2(90.99,9.13) ; TPAD1.7 135.35,10.97 v2(135.41,10.9)
I_ADP: length 238.5
  TOP w0.102: RE399.2 28.16,49.2 28.62,48.73 v2(29.61,48.73) ; v2(181.77,49.46) 181.18,49.46 PC748.1
  TOP w0.254: PC748.1 180.29,48.57 PR774.1
  IN2 w0.127: v2(181.77,49.46) 182.14,49.46 183.33,48.27 183.33,43.96 181.69,42.32 181.69,29.84 182.27,29.26 182.27,26.54 180.08,24.35 180.08,16.83 173.85,10.6 150.31,10.6 148.54,8.82 134.6,8.82 133.84,9.58 127.24,9.58 126.33,10.5 122.05,10.5 120.39,8.84 115.29,8.84 114.39,9.74 111.88,9.74 110.98,8.84 95.01,8.84 94.03,9.81 90.71,9.81 90.22,9.33 89.82,9.33 88.92,10.23 84.02,10.23 83.3,9.51 80.11,9.51 79.5,8.9 65.38,8.9 64.52,9.76 63.88,9.76 63.02,8.9 57.91,8.9 55.23,11.58 51.46,11.58 48.83,14.21 41.7,14.21 39.11,11.62 38.41,11.62 38.03,11.23 36.14,11.23 35.75,11.62 35.75,12.4 36.54,13.19 36.54,17.72 36.87,18.05 36.87,25.14 36.68,25.33 36.68,31.6 35.42,32.86 34.69,32.86 34.44,33.12 33.07,33.12 32.48,33.7 32.48,35.86 33.05,36.44 33.05,36.86 32.62,37.29 32.18,37.29 31.89,37.58 31.89,40.51 31.32,41.08 31.32,47.86 30.45,48.73 v2(29.61,48.73)
I_ADP_R: length 5.2
  TOP w0.102: CE87.1 RE399.1 27.89,50.11 28.31,49.69 v1(29.24,49.69) 29.52,49.69 30.59,48.62 UE1.110
I_BATT: length 236.5
  TOP w0.102: v2(26.29,46.54) 26.42,46.41 RE400.2 ; PC749.2 180.89,50.1 181.38,50.1 v1(181.51,50.22) v2(181.89,50.6)
  TOP w0.254: PC749.2 180.25,49.46 PR775.1
  IN2 w0.127: v2(26.29,46.54) 25.73,45.98 25.73,43.01 26.93,41.82 26.93,37.7 27.09,37.54 27.09,35.58 29.32,33.36 30.63,33.36 33.53,30.46 33.53,29.49 34.74,28.28 34.74,25.5 35.07,25.17 35.07,21.23 35.97,20.33 35.97,19.08 35.56,18.68 35.56,14.32 35.25,14 35.25,11.67 35.93,10.98 39.25,10.98 41.3,13.04 49.23,13.04 51.2,11.07 55.02,11.07 57.7,8.39 79.71,8.39 80.32,9 87.3,9 87.81,9.51 88.88,9.51 90.05,8.33 111.19,8.33 112.09,9.23 114.18,9.23 115.08,8.33 120.9,8.33 122.56,9.99 126.12,9.99 127.03,9.08 133.53,9.08 133.83,8.77 133.83,7.99 134.27,7.55 147.98,7.55 150.52,10.09 174.06,10.09 180.59,16.62 180.59,24.49 182.53,26.44 182.53,29.37 181.96,29.94 181.96,42.23 183.83,44.1 183.83,48.48 181.89,50.43 v2(181.89,50.6)
I_BATT_R: length 4.7
  TOP w0.102: UE1.114 v1(30.05,47.02) 29.75,47.02 29.46,47.3 CE88.1 RE400.1
I_SYS: length 20.9
  TOP w0.203: PU703.8 177.2,49.87 177.42,50.1 178.38,50.1 PR727.1 178.16,50.85 v2(178.04,50.85)
  TOP w0.254: PR620.1 v2(170.79,62.79)
  IN2 w0.127: v2(178.04,50.85) 178.61,51.41 178.61,54.36 178.28,54.69 178.28,58.32 175.32,61.27 172.3,61.27 v2(170.79,62.79)
ICSP_CLK: length 15.6
  TOP w0.102: v2(27.89,53.36) 27.64,53.36 RE435.2 28.11,54.67 v1(29.28,54.67) 29.32,54.67 30.42,53.56 30.42,52.45 30.65,52.22 UE1.101
  BOTTOM w0.102: v2(27.89,53.36) 27.52,53.36 25.26,51.1 23.85,51.1 23.2,50.45 23.2,49.2 23.45,48.95 RE420.1
ICSP_CLR: length 21.8
  TOP w0.102: UE1.87 36.74,54.63 v2(35.94,53.83)
  IN3 w0.135: v2(28.26,53.81) 30.95,56.5 32.6,56.5 33.38,55.72 34.05,55.72 v2(35.94,53.83)
  BOTTOM w0.102: RE421.1 23.79,48.61 23.47,48.61 22.98,49.1 22.98,50.55 23.76,51.33 25.16,51.33 27.65,53.81 v2(28.26,53.81)
ICSP_DAT: length 19.5
  TOP w0.102: UE1.102 30.66,51.82 30.19,52.29 30.19,53.2 v1(29.96,53.43) 28.81,53.43 v2(28.73,53.35) 28.21,52.83 RE436.2
  BOTTOM w0.102: v2(28.73,53.35) 28.73,54 28.51,54.22 27.72,54.22 25.06,51.56 23.66,51.56 22.75,50.64 22.75,47.16 23.82,46.1 RE423.1
ILMT_+1VALW: length 3.9
  TOP w0.102: PR304.1 153.11,27.38 152.42,26.68 v1(152.05,26.68)
  TOP w0.254: PU300.13 152.16,28.68 v2(152.82,28.01) 153.17,27.67 PR304.1
  BOTTOM w0.254: v2(152.82,28.01) 152.82,27.72 PR304.1
IMON_IA: length 3.5
  TOP w0.203: PU602.14 165.24,70.27 165.26,70.29 v2(165.26,70.37)
  BOTTOM w0.102: PR629.2 167.2,70.1 v1(167.25,70.14)
  BOTTOM w0.254: PR629.2 166.08,70.1 165.75,69.76 PC625.2 165.4,70.23 v2(165.26,70.37)
IMON_VSA: length 4.1
  TOP w0.203: PU602.23 160.84,68.04 v2(160.68,68.19)
  BOTTOM w0.102: v1(160.57,68.74) 160.68,68.63 v2(160.68,68.19)
  BOTTOM w0.254: v2(160.68,68.19) 160.77,68.19 161.27,67.69 PC643.1 PR651.1
IMVP_VR_ON: length 205.1
  TOP w0.102: RC1135.2 v2(53.57,47.81) ; v2(123.04,92.7) 128.34,98 v1(156.54,98) 166.86,98 169.62,95.23 169.62,93.35 173.38,89.59 173.38,64.78 170.69,62.09 169.91,62.09 169.42,61.6 167.94,61.6 PR616.1
  IN3 w0.135: v2(53.57,47.81) 52.48,48.9 52.48,62.9 51.43,63.95 51.43,87.75 54.54,90.86 69.57,90.86 70.74,92.03 87.63,92.03 88.65,91.02 94.69,91.02 96.06,92.38 115.91,92.38 116.2,92.1 119.55,92.1 120.16,92.7 v2(123.04,92.7)
INT-SPK-L+:
  vias: v1(30.41,18.8)
INT-SPK-L-:
  vias: v1(31.77,19.29)
INT-SPK-R+:
  vias: v1(33.38,19.2)
INT_TP#: length 124.8
  TOP w0.102: v2(49.84,32.24) 49.15,32.24 v1(49.13,32.27) ; R6203.1 51.64,35.64 v2(51.64,35.25) Q6204.3
  IN2 w0.127: v2(49.84,32.24) 50.18,32.24 50.49,31.94 50.49,27.27 49.91,26.7 49.91,18.47 52.09,16.29 56.26,16.29 57.22,15.32 57.66,15.32 59.28,13.7 79.17,13.7 79.86,14.38 82.34,14.38 82.78,14.82 83.99,14.82 92.75,23.57 94.37,23.57 95.81,22.12 95.81,21.34 99.1,18.05 99.1,16.5 100.42,15.18 101.86,15.18 102.86,14.18 103.57,14.18 103.95,13.8 115.55,13.8 116.53,12.82 129.36,12.82 130.2,11.98 131.84,11.98 132.85,12.99 138.03,12.99 v2(138.9,13.86)
  BOTTOM w0.102: v2(49.84,32.24) 51.64,34.04 v2(51.64,35.25) ; TPAD1.4 138.35,13.67 138.55,13.86 v2(138.9,13.86)
INTRUDER#: length 32
  TOP w0.102: RC69.2 97.15,27.47 v2(97.15,27.81) 97.15,27.95 v1(97.46,28.27)
  IN3 w0.135: v2(117.37,43.4) 116.93,42.96 115.3,42.96 114.71,42.37 114.71,41.71 110.38,37.38 109.22,37.38 106.19,34.35 100.29,34.35 99.34,33.4 97.68,33.4 97.15,32.86 v2(97.15,27.81)
  BOTTOM w0.102: UC1.AP16 v2(117.37,43.4)
IR_CAM_DET#: length 259.5
  TOP w0.102: v4(53.83,99.58) 55.71,99.58 56.23,99.05 56.23,98.76 57.23,97.76 v2(57.56,97.76)
  IN1 w0.114: v2(32.82,51.32) 30.52,53.62 30.52,58.98 29.23,60.27 29.23,72.08 27.52,73.78 27.52,77.66 29.11,79.24 30.13,79.24 30.83,79.94 34.61,79.94 38.68,84.01 38.68,85.35 39.89,86.57 41.29,86.57 43.68,88.96 43.68,90.19 44.62,91.13 44.62,93.71 48.55,97.64 53.11,97.64 53.23,97.76 v2(57.56,97.76)
  IN3 w0.135: v2(141.02,23.19) 141.02,22.44 139.6,21.02 139.6,18.02 140,17.63 140,16.16 139.01,15.17 138.38,15.17 134.69,11.48 134.69,10.65 130.97,6.94 62.31,6.94 61.31,5.94 51.03,5.94 49.81,7.15 49.81,10.93 48.9,11.84 45.75,11.84 36.91,20.68 36.91,25.86 36.35,26.42 36.35,28.35 35.8,28.9 34.86,28.9 33.9,29.86 33.9,30.98 31.37,33.51 31.37,35.67 32.03,36.33 32.03,37.23 31.84,37.42 31.84,38.25 31.98,38.4 33.06,38.4 33.43,38.77 33.43,40.46 32.99,40.9 32.99,42.93 33.82,43.76 33.82,50.31 v2(32.82,51.32)
  BOTTOM w0.076: 128.96,33.41 128.77,33.41 128.16,34.02 128.16,35.5 UC1.P4
  BOTTOM w0.102: v2(57.56,97.76) 57.6,97.72 DZ1704.2 ; v2(141.02,23.19) 140.57,23.65 140.57,25.27 139.92,25.92 139.92,26.66 140.29,27.03 RC293.2 138.89,27.24 138.47,27.66 137.56,27.66 137.32,27.89 133.96,27.89 131.94,29.91 131.94,31.48 130.99,32.43 129.94,32.43 128.96,33.41
IR_CAM_DET#_D: length 6.9
  BOTTOM w0.102: DZ1704.1 56.2,94.98 55.52,94.29 53.66,94.29 53.38,94.57 v1(53.38,95.18) 53.38,96.87 53.77,97.26 JEDP.34
IR_LED-: length 2.7
  BOTTOM w0.203: JEDP.35 54.27,97.03 v1(53.77,96.53) 53.77,96.25 R6530.1
ISEN1_GT: length 7.9
  TOP w0.203: PR615.2 PR677.1 170.32,71.61 169.92,71.2 v2(169.92,71.15) 169.87,71.15 v1(169.38,70.67) 168.84,70.67 168,69.83 168,68.8 167.64,68.44 PU602.9
  TOP w0.254: PR615.2 171.48,70.75 PC635.2
  BOTTOM w0.254: v2(169.92,71.15) PR675.2
ISEN2_GT: length 7.4
  TOP w0.102: v2(167.73,70.42) v1(167.73,70.94)
  TOP w0.203: v2(167.73,70.42) 167.62,70.3 167.62,68.96 167.5,68.84 PU602.10
  BOTTOM w0.254: v2(167.73,70.42) 167.73,71.79 167.47,72.05 PR670.2 167.47,72.99 PR634.2 PC638.2 168.95,73.59 PR668.2
ISOLATE#: length 4.4
  TOP w0.102: UL1.20 39.47,85.71 v1(39.61,85.57) 39.83,85.35 41.19,85.35 RL2.2 RL4.1
ISUMN_GT: length 31.1
  TOP w0.254: PC635.1 170.58,70.57 170.11,70.1 PR638.1 170.97,69.31 PR632.1 v1(172.01,69.32) 172.54,69.32 v2(172.75,69.53) ; PR666.2 v2(169.83,74.61)
  IN3 w0.254: v2(169.83,74.61) 169.83,73.64 171.57,71.9 172.55,71.9 172.97,71.48 172.97,69.74 v2(172.75,69.53)
  BOTTOM w0.254: PH602.2 160.11,78.4 160.11,77.38 161.17,76.32 165.07,76.32 166.27,75.12 169.32,75.12 v2(169.83,74.61) 169.05,74.61 PC638.1 ; v2(172.75,69.53) 172.75,69.15 172.44,68.84 PC641.1 171.85,68.83 PR633.2 PC626.2 PC624.2 169.04,68.93 PR673.2
ISUMN_IA: length 30.7
  TOP w0.254: PR640.2 PR644.2 158.86,73.42 v2(158.65,73.21)
  BOTTOM w0.254: PR656.2 PC646.2 161.65,72.58 PC642.2 160.95,73.11 PC645.1 160.22,72.4 159.41,73.21 v2(158.65,73.21) 157.45,73.21 154.79,70.55 v1(154.79,64.13) PH605.2 154.79,59.82 154.42,59.46 152.94,59.46 151.27,57.79 151.27,56.32 150.89,55.94 PL603.2
ISUMN_VSA: length 35.3
  TOP w0.102: v2(157.76,64.07) 157.76,63.76 v1(157.95,63.57)
  TOP w0.254: v2(157.76,64.07) 157.78,64.08 PR641.2 158.16,64.79 158.17,64.8 PR636.2
  IN3 w0.254: v2(157.76,64.07) 157.13,64.07 152.68,59.62 147.92,59.62 146.4,58.1 146.4,48.13 v2(146.21,47.94)
  BOTTOM w0.254: PC633.2 PR643.1 PC637.2 ; PH604.2 146.6,45.11 146.59,45.12 146.59,47.56 v2(146.21,47.94) PL601.2 ; PC637.2 159.74,62.9 PC644.1 ; PC637.2 v2(157.76,64.07)
ISUMP_GT: length 13.8
  TOP w0.203: PU602.7 168.07,67.64 v2(168.34,67.91)
  IN1 w0.254: v2(168.34,67.91) 168.34,69.59 168.99,70.24 v2(168.99,71.64)
  BOTTOM w0.254: PR637.1 168.07,68.19 v2(168.34,67.91) 169.14,67.91 PC624.1 PC626.1 PR633.1 170.92,66.82 PR628.1 ; PR667.1 169.38,72.03 v2(168.99,71.64) 168.86,71.5 v1(168.86,70.84) 168.86,70.81 169.67,70 PR674.1
ISUMP_IA: length 9.3
  TOP w0.203: v2(161.67,70.72) v1(162.44,70.72) 162.49,70.72 163.24,69.98 PU602.19
  BOTTOM w0.254: PR656.1 PR657.1 PR653.1 ; PR656.1 162.9,71.27 162.69,71.06 162.02,71.06 v2(161.67,70.72) ; PR656.1 PC646.1 161.47,72.2 PC642.1 161.04,72.2 PR661.2
ISUMP_VSA: length 7.8
  TOP w0.203: v2(160.71,66.24) 161.15,66.24 161.36,66.44 PU602.27
  BOTTOM w0.254: v2(160.71,66.24) 160.34,65.87 PC633.1 ; PC633.1 PR642.1 ; PC633.1 PR643.2 PC637.1 159.82,63.74 PR654.1 160.43,63.3 PR624.2
JACK_PLUG#: length 28.2
  IN1 w0.114: v2(29.39,30.56) 28.13,29.31 28.13,27.4 25.94,25.2 25.94,21.98 24.78,20.82 20.16,20.82 15.09,15.75 JHP.5
  BOTTOM w0.254: RA4.1 28.16,29.33 v2(29.39,30.56)
JACK_SENSE#: length 10.2
  TOP w0.203: v2(33.35,27.57) 33.79,27.13 UA1.13
  BOTTOM w0.254: RA4.2 28.11,30.69 28.11,31.4 RA13.1 29.47,31.05 30.25,31.05 31.3,30.01 31.3,29.2 v1(31.35,29.15) 32.29,28.21 32.97,28.21 33.35,27.84 v2(33.35,27.57)
JTAG_CLK: length 20.8
  TOP w0.102: v2(24.9,59.27) 24.8,59.37 JDEG1.4
  BOTTOM w0.102: RE422.2 28.92,50.66 29.16,50.66 30.36,51.86 30.36,53.1 29.96,53.5 29.96,54.31 29.13,55.14 26.68,55.14 26.34,55.47 24.41,55.47 24.05,55.83 v4(24.05,56.46) 24.05,58.41 v2(24.9,59.27)
JTAG_TDI: length 20.5
  TOP w0.102: JDEG1.2 23.69,60.37 v2(22.88,59.56)
  BOTTOM w0.102: v2(22.88,59.56) 22.25,58.94 v4(22.25,57.04) 22.25,56.78 24.02,55.01 26.15,55.01 26.49,54.68 28.94,54.68 29.5,54.12 29.5,53.16 29.31,52.97 29.31,51.97 27.99,50.64 27,50.64 RE420.2
JTAG_TDO: length 22.2
  TOP w0.102: v2(25.19,58.73) 24.75,58.73 24.62,58.87 JDEG1.5
  BOTTOM w0.102: RE423.2 26.55,46.1 27.58,47.12 27.58,48.67 30.58,51.68 30.58,53.2 30.19,53.59 30.19,54.4 29.23,55.36 27.02,55.36 26.49,55.89 v4(25.74,55.89) 25.54,55.7 24.73,55.7 24.43,56 24.43,58.13 25.03,58.73 v2(25.19,58.73)
JTAG_TMS: length 20.7
  TOP w0.102: JDEG1.3 23.85,59.87 v2(22.9,58.92)
  BOTTOM w0.102: RE421.2 25.72,48 28.75,51.04 29.21,51.04 30.13,51.95 30.13,53.01 29.73,53.4 29.73,54.21 29.04,54.91 26.58,54.91 26.25,55.24 24.2,55.24 23.63,55.81 v4(23.63,58.22) 22.93,58.92 v2(22.9,58.92)
KB_BL_CTRL#: length 5
  BOTTOM w0.254: JKBBL.4 118.99,13.34 118.79,13.55 v1(117.3,13.55) 115.79,13.55 Q6202.1
KB_DET#: length 49.6
  IN2 w0.127: v2(108.17,28.33) 106.41,26.58 105.07,26.58 103.76,27.89 v2(101.74,27.89)
  BOTTOM w0.076: 109.38,32.57 109.38,34.29 111.53,36.44 111.53,37.12 111.94,37.52 112.62,37.52 UC1.BB7
  BOTTOM w0.102: v2(101.74,27.89) 101.74,27.86 101.32,27.44 100.48,27.44 99.51,26.47 96.79,26.47 96.32,26 96.32,25.1 94.85,23.63 94.85,23.21 94.22,22.59 93.42,22.59 90.83,20 90.83,14.7 89.37,13.24 83.29,13.24 83.1,13.05 JKB.30 ; RC288.1 108.67,27.83 v2(108.17,28.33) 108.17,28.32 107.9,28.58 107.9,29.49 108.79,30.37 108.79,31.67 109.38,32.26 109.38,32.57
KB_LED_BL_DET: length 33.3
  TOP w0.254: v2(120.72,13.83) 119.55,13.83 117.99,15.39 v1(117.99,15.87) 117.68,16.17 117.68,22.04 v2(116.81,22.92)
  IN2 w0.254: v2(124.68,37.59) 124.49,37.59 124.11,37.21 124.11,34.67 123.22,33.78 123.22,27.59 121.42,25.79 119.17,25.79 116.81,23.43 v2(116.81,22.92)
  BOTTOM w0.254: v2(120.72,13.83) 120.48,14.07 R6206.1 R6207.1 ; UC1.W8 125.01,37.92 v2(124.68,37.59)
KB_LED_DET_C: length 2
  BOTTOM w0.254: JKBBL.2 120.99,13.4 v2(121.39,13.8) R6206.2
KB_LED_PWM: length 103.9
  TOP w0.254: UE1.44 45.91,45.82 v2(45.89,45.84)
  IN2 w0.254: v2(45.89,45.84) 45.94,45.8 46,45.8 46.04,45.76 46.04,43.97 50.41,39.59 50.41,38.55 53.04,35.92 53.04,31.87 53.79,31.12 53.79,26.78 54.89,25.67 54.89,19.17 55.21,18.85 56.84,18.85 58.15,17.55 58.58,17.55 59.9,16.22 76.91,16.22 77.07,16.06 77.96,16.06 78.71,16.81 79.73,16.81 82.34,19.41 82.81,19.41 90.25,26.86 93.3,26.86 94.5,28.05 95.8,28.05 96.81,27.05 98.5,27.05 99.19,26.36 101.49,26.36 109.06,18.79 v2(109.06,18.64)
  BOTTOM w0.254: v2(109.06,18.64) 108.88,18.46 108.88,15.96 v1(110.75,14.09) 111.39,13.45 Q6202.2
KSI0: length 103.8
  TOP w0.102: v2(30.84,36.61) 30.81,36.58 30.81,35.95 RPE2.4 ; v2(90.01,9.76) 90.01,9.61 v1(90.39,9.23) ; UE1.98 32.65,53.42 v2(32.76,53.53)
  IN1 w0.114: v2(90.01,9.76) 90.01,8.6 88.81,7.41 61.3,7.41 60.16,8.55 57.23,8.55 54.41,11.37 51.7,11.37 45.55,17.52 45.49,17.52 43.74,19.28 43.74,20.69 41.42,23.01 41.42,24.73 40.16,25.99 39.53,25.99 39.28,26.23 39.28,27.08 39.63,27.42 39.63,28.29 38.43,29.48 38.14,29.48 37.18,30.45 37.18,31.61 36.89,31.9 36.89,33.01 35.91,33.99 35.91,35 35.18,35.72 33.48,35.72 32.98,36.22 31.23,36.22 v2(30.84,36.61)
  IN3 w0.135: v2(32.76,53.53) 32.55,53.53 31.55,52.52 31.55,41.59 32.86,40.27 32.86,39.23 32.55,38.92 31.6,38.92 31.3,38.62 31.3,37.06 v2(30.84,36.61)
  BOTTOM w0.102: JKB.22 89.5,12.12 89.54,12.09 89.54,10.23 v2(90.01,9.76)
KSI1: length 101.5
  TOP w0.102: v1(31.73,37.13) 31.52,36.93 v2(31.52,36.63) 31.49,36.6 RPE2.3 ; UE1.99 32.48,53.02 32.55,53.09 v2(33.26,53.09)
  IN1 w0.114: v2(88.37,8.64) 87.62,7.89 61.5,7.89 60.36,9.03 57.43,9.03 54.61,11.86 51.9,11.86 45.75,18.01 45.69,18.01 44.22,19.48 44.22,20.89 41.9,23.21 41.9,24.93 40.53,26.3 40.53,28.07 38.63,29.97 38.34,29.97 37.67,30.64 37.67,31.83 37.37,32.13 37.37,33.21 36.71,33.87 36.71,35.14 36,35.85 36,36.53 35.23,37.29 32.29,37.29 31.63,36.63 v2(31.52,36.63)
  IN3 w0.135: v2(31.52,36.63) 31.58,36.69 31.58,38.36 31.87,38.66 32.66,38.66 33.13,39.12 33.13,40.39 31.86,41.66 31.86,52.38 32.57,53.09 v2(33.26,53.09)
  BOTTOM w0.102: JKB.24 87.9,9.11 v2(88.37,8.64)
KSI2: length 93
  TOP w0.102: UE1.6 35.14,41.16 35.31,41.33 35.31,42.22 34.93,42.6 33.55,42.6 32.81,41.86 32.81,41.22 31.83,40.24 31.83,39.07 32.31,38.59 v2(32.31,37.75) 32.31,37.63 33,36.94 33,35.41 32.86,35.26 32.15,35.26 31.99,35.42 RPE2.2 ; v1(86.99,8.72) 86.99,9.55 v2(86.74,9.79)
  IN1 w0.114: v2(86.74,9.79) 86.74,9.13 85.75,8.13 61.6,8.13 60.46,9.27 57.53,9.27 54.71,12.1 52,12.1 46.4,17.7 46.4,19.06 42.14,23.31 42.14,25.03 40.77,26.4 40.77,28.17 39.04,29.9 39.04,30.54 37.91,31.67 37.91,32.01 37.61,32.3 37.61,33.31 36.95,33.98 36.95,37.56 35.97,38.54 33.1,38.54 v2(32.31,37.75)
  BOTTOM w0.102: JKB.26 86.3,10.24 v2(86.74,9.79)
KSI3: length 92.3
  TOP w0.102: v1(88.61,9.18) 88.93,8.86 v2(88.93,8.44) ; UE1.7 35.54,42.38 35.08,42.83 33.46,42.83 32.58,41.96 32.58,41.32 31.55,40.29 31.55,38.97 31.88,38.64 31.88,37.6 32.54,36.94 v2(32.54,36.75) 32.49,36.7 RPE2.1
  IN1 w0.114: v2(32.54,36.75) 35.22,36.75 35.69,36.28 35.69,35.81 36.47,35.04 36.47,33.77 37.13,33.11 37.13,32.03 37.42,31.74 37.42,30.55 38.24,29.73 38.53,29.73 40.29,27.97 40.29,26.2 41.66,24.83 41.66,23.11 43.98,20.79 43.98,19.38 45.59,17.76 45.65,17.76 51.8,11.62 54.51,11.62 57.33,8.79 60.26,8.79 61.4,7.65 88.14,7.65 v2(88.93,8.44)
  BOTTOM w0.102: v2(88.93,8.44) 88.93,9.66 88.7,9.89 JKB.23
KSI4: length 101.1
  TOP w0.102: RPE3.4 24.59,53.01 v1(24.59,53) 24.59,53 24.91,52.68 24.91,51.82 25.31,51.42 26.32,51.42 26.48,51.26 28.64,51.26 28.87,51.02 UE1.104 32.5,51.02 32.67,50.85 34.19,50.85 35.65,49.39 37.5,49.39 v2(38.4,50.29)
  IN1 w0.114: v2(85.5,9.75) 84.85,9.1 83.23,9.1 83.11,9.22 80.2,9.22 79.6,8.62 61.8,8.62 60.66,9.75 57.73,9.75 55.15,12.34 55.15,12.86 54.47,13.54 51.37,13.54 46.88,18.03 46.88,19.28 42.62,23.54 42.62,25.28 41.28,26.63 41.28,28.34 39.52,30.1 39.52,30.74 38.4,31.87 38.4,32.23 38.17,32.46 38.17,33.44 37.43,34.18 37.43,37.76 37.06,38.13 37.06,42.7 38.81,44.45 38.81,49.88 38.4,50.29 v2(38.4,50.29)
  BOTTOM w0.102: v2(85.5,9.75) JKB.27
KSI5: length 103.1
  TOP w0.102: v2(38.4,49.71) 37.85,49.16 35.56,49.16 34.09,50.62 UE1.105 30.25,50.62 30.09,50.79 28.76,50.79 28.52,51.03 26.34,51.03 26.2,51.16 25.25,51.16 23.9,52.51 RPE3.3 ; v1(86.35,10.5) 86.16,10.31 v2(86.16,9.76)
  IN1 w0.114: v2(86.16,9.76) 85.26,8.86 83.13,8.86 83.01,8.98 80.3,8.98 79.7,8.38 61.7,8.38 60.56,9.51 57.63,9.51 54.81,12.34 52.95,12.34 51.99,13.3 51.27,13.3 46.64,17.93 46.64,19.18 42.38,23.44 42.38,25.13 41.04,26.48 41.04,28.24 39.28,30 39.28,30.64 38.15,31.77 38.15,32.11 37.93,32.33 37.93,33.34 37.19,34.08 37.19,37.66 36.81,38.04 36.81,41.94 36.3,42.45 36.3,43.5 38.4,45.6 v2(38.4,49.71)
  BOTTOM w0.102: v2(86.16,9.76) 86.6,9.32 86.9,9.32 87.21,9.63 87.21,12.01 87.1,12.12 JKB.25
KSI6: length 101.6
  TOP w0.102: v2(84.89,9.75) 84.89,9.3 v1(85.2,9) ; RPE3.2 23.94,52.01 25.03,50.91 25.95,50.91 26.07,50.79 28.29,50.79 28.54,50.54 29.73,50.54 30.45,49.82 UE1.107 32.56,49.82 32.72,49.66 34.73,49.66 35.52,48.88 38.31,48.88 39.02,49.59 39.02,49.82 v2(39.45,50.25)
  IN1 w0.114: v2(84.89,9.75) 84.89,9.74 84.49,9.34 83.33,9.34 83.21,9.46 80.1,9.46 79.5,8.86 61.9,8.86 60.74,10.02 58.75,10.02 54.99,13.78 51.47,13.78 47.17,18.08 47.17,19.33 42.87,23.64 42.87,25.38 41.52,26.73 41.52,28.44 39.76,30.2 39.76,30.84 38.64,31.97 38.64,32.33 38.41,32.56 38.41,33.54 37.75,34.2 37.75,37.79 37.3,38.23 37.3,42.6 39.05,44.35 39.05,49.85 v2(39.45,50.25)
  BOTTOM w0.102: JKB.28 84.23,12.15 84.23,10.42 v2(84.89,9.75)
KSI7: length 99.2
  TOP w0.102: v1(83.63,8.12) 84.29,8.78 v2(84.29,9.77) ; v2(39.48,49.66) 38.36,48.55 35.52,48.55 34.65,49.42 UE1.108 30.4,49.42 29.51,50.31 28.45,50.31 28.2,50.56 25.94,50.56 25.82,50.68 24.77,50.68 23.94,51.51 RPE3.1
  IN1 w0.114: v2(84.29,9.77) 84.11,9.58 83.43,9.58 83.31,9.7 80,9.7 79.4,9.1 65.36,9.1 64.75,9.71 62,9.71 61.07,10.65 58.8,10.65 55.19,14.26 51.81,14.26 48.2,17.87 48.2,19.2 44,23.41 44,25.18 42.61,26.57 42.61,28.8 41.76,29.65 41.76,29.78 39.31,32.23 39.31,32.56 38.89,32.98 38.89,33.74 38.48,34.15 38.48,34.5 38.78,34.79 38.78,38.73 39.06,39.01 39.06,42.57 39.48,42.98 v2(39.48,49.66)
  BOTTOM w0.102: JKB.29 83.9,10.16 v2(84.29,9.77)
KSO0: length 85.7
  TOP w0.102: v2(33.28,37.78) 33.28,37.95 33.23,38 33.23,38.59 33.54,38.9 UE1.2 ; v2(42.77,32.46) 42.77,32.62 42.06,33.33 40.75,33.33 40.43,33.65 RPE4.8 40.43,34.34 40.03,34.73 38.11,34.73 v1(37.46,35.38) 37.3,35.54 37.3,37.89 v2(37.76,38.35)
  IN1 w0.114: v2(96.17,10.96) 96.11,11.01 95.76,11.01 95.1,11.67 93.84,11.67 92.64,12.86 88.87,12.86 88.56,12.55 84.1,12.55 83.81,12.26 66.07,12.26 65.68,12.64 59.54,12.64 55.99,16.19 52.76,16.19 50.24,18.72 50.24,19.98 49.32,20.89 49.32,22.67 44.6,27.39 44.6,30.84 43.61,31.83 43.34,31.83 42.77,32.4 v2(42.77,32.46)
  BOTTOM w0.102: v2(33.28,37.78) 33.36,37.78 33.48,37.9 37.31,37.9 v2(37.76,38.35) ; v2(96.17,10.96) 96.32,10.96 96.7,11.33 JKB.13
KSO1: length 81
  TOP w0.102: UE1.14 38.34,38.86 38.17,38.7 38.17,38.15 37.63,37.61 v1(37.63,37.21) 37.63,35.8 38.47,34.96 41.12,34.96 v2(41.34,34.74) 41.35,34.73 41.35,34.65 40.93,34.23 RPE4.7
  IN1 w0.114: v2(94.92,10.78) 94.77,10.62 94.14,10.62 92.38,12.38 90.65,12.38 89.68,11.41 86.02,11.41 85.36,12.07 84.3,12.07 84.01,11.77 65.81,11.77 65.47,12.12 59.38,12.12 55.79,15.71 52.46,15.71 49.76,18.41 49.76,19.75 48.84,20.66 48.84,22.47 44.12,27.19 44.12,30.62 43.42,31.31 42.98,31.31 42.12,32.18 42.12,32.91 41.74,33.28 41.74,34.22 41.34,34.62 v2(41.34,34.74)
  BOTTOM w0.102: JKB.15 95.1,10.85 95.02,10.78 v2(94.92,10.78)
KSO2: length 80.6
  TOP w0.102: v2(96.02,11.6) 95.72,11.3 v1(95.72,10.52) ; UE1.15 38.74,38.87 38.4,38.53 38.4,38.05 37.98,37.63 37.98,35.78 38.56,35.19 41.53,35.19 41.96,34.75 v2(41.96,34.73) 41.43,34.19 RPE4.6
  IN1 w0.114: v2(41.96,34.73) 41.96,34.59 42.61,33.95 42.77,33.95 43.83,32.89 43.83,31.95 44.84,30.94 44.84,27.49 49.57,22.77 49.57,20.99 50.48,20.08 50.48,18.82 52.86,16.44 56.09,16.44 59.65,12.88 65.78,12.88 66.17,12.5 83.71,12.5 84,12.79 88.46,12.79 88.77,13.1 92.8,13.1 94,11.91 95.29,11.91 95.6,11.6 v2(96.02,11.6)
  BOTTOM w0.102: JKB.14 95.9,11.71 v2(96.02,11.6)
KSO3: length 80.1
  TOP w0.102: UE1.16 39.14,38.94 38.63,38.44 38.63,37.96 38.32,37.65 38.32,35.76 38.65,35.43 41.87,35.43 42.38,34.92 42.38,34.44 41.93,33.98 RPE4.5 41.93,33.8 42.12,33.61 42.42,33.61 v2(42.4,33.59) ; v2(94.49,11.18) 94.49,10.46 v1(94.03,10)
  IN1 w0.114: v2(42.4,33.59) 42.36,33.55 42.36,32.28 43.08,31.55 43.55,31.55 44.36,30.74 44.36,27.29 49.08,22.57 49.08,20.76 50,19.85 50,18.52 52.56,15.95 55.89,15.95 59.46,12.38 65.6,12.38 65.97,12.02 83.91,12.02 84.2,12.31 88.66,12.31 88.97,12.62 92.54,12.62 93.98,11.18 v2(94.49,11.18)
  BOTTOM w0.102: JKB.16 94.3,11.38 v2(94.49,11.18)
KSO4: length 89.7
  TOP w0.102: v2(91.06,11.41) 90.02,12.45 v1(90.02,13.18) ; v2(41.02,43.49) 41.02,43.61 41.94,44.53 44.7,44.53 46.21,43.02 UE1.37 48.05,43.02 48.53,42.54 48.53,42.24 49.55,41.22 RPE5.8
  IN1 w0.114: v2(91.06,11.41) 90.71,11.41 89.98,10.69 83.95,10.69 83.69,10.43 79.31,10.43 78.69,11.05 65.51,11.05 65.18,11.38 59.1,11.38 55.49,14.99 52.13,14.99 48.97,18.15 48.97,19.5 45.93,22.55 45.93,24.27 43.39,26.81 43.39,29.04 42.5,29.94 42.5,30.72 41.39,31.83 41.39,32.61 41.02,32.98 41.02,33.8 40.45,34.37 40.45,35.34 40.87,35.77 40.87,39.9 41.18,40.2 41.18,41.66 40.59,42.25 40.59,43.07 v2(41.02,43.49)
  BOTTOM w0.102: v2(91.06,11.41) 91.1,11.45 JKB.20
KSO5: length 92.4
  TOP w0.102: v1(88.85,10.96) 89.53,10.28 v2(90.67,10.28) ; RPE5.7 49.49,41.72 48.9,42.31 48.9,42.73 48.21,43.42 UE1.38 46.14,43.42 44.72,44.84 41,44.84 v2(40.65,44.49)
  IN1 w0.114: v2(90.67,10.28) 90.59,10.21 84.15,10.21 83.89,9.94 79.9,9.94 79.3,9.34 66.06,9.34 64.5,10.9 58.89,10.9 55.29,14.5 51.93,14.5 48.47,17.97 48.47,19.28 44.24,23.51 44.24,25.28 42.91,26.61 42.91,28.84 42,29.75 42,30.53 40.91,31.63 40.91,32.33 40.54,32.7 40.54,33.6 39.96,34.17 39.96,35.54 40.35,35.93 40.35,38.81 40.06,39.1 40.06,43.9 v2(40.65,44.49)
  BOTTOM w0.102: v2(90.67,10.28) 90.3,10.65 JKB.21
KSO6: length 90.3
  TOP w0.102: v2(42.19,45.32) 42.24,45.27 44.8,45.27 46.25,43.82 UE1.39 48.37,43.82 48.44,43.9 v1(49.32,43.9) 49.47,43.75 49.47,42.44 49.69,42.22 RPE5.6
  IN1 w0.114: v2(92.59,11.48) 91.94,12.12 90.74,12.12 89.78,11.17 85.92,11.17 85.26,11.82 84.4,11.82 83.49,10.91 79.51,10.91 78.89,11.53 65.71,11.53 65.38,11.86 59.3,11.86 55.69,15.47 52.36,15.47 49.49,18.34 49.49,19.67 48.6,20.56 48.6,22.37 43.88,27.09 43.88,30.52 43.32,31.07 42.88,31.07 41.88,32.08 41.88,32.81 41.5,33.18 41.5,34 40.93,34.57 40.93,35.14 41.35,35.57 41.35,39.7 41.77,40.11 41.77,41.85 41.3,42.32 41.3,42.71 41.67,43.07 41.67,44.8 v2(42.19,45.32)
  BOTTOM w0.102: JKB.18 92.7,11.6 v2(92.59,11.48)
KSO7: length 100.8
  TOP w0.102: v1(90.55,11.41) 90.55,10.98 v2(91.27,10.27) ; v2(50.7,43.37) 50.57,43.24 50.5,43.24 50,42.74 RPE5.5 ; v2(40.73,46.57) 40.73,47.6 41.17,48.04 44.53,48.04 45.09,48.6 45.95,48.6 46.33,48.22 UE1.50 50.04,48.22 50.32,47.94 v2(50.32,47.62)
  IN1 w0.114: v2(40.73,46.57) 40.73,46.56 40.72,46.55 40.72,45 41.1,44.62 41.1,44.3 40.3,43.5 40.3,39.2 40.59,38.91 40.59,35.83 40.21,35.44 40.21,34.27 40.78,33.7 40.78,32.88 41.15,32.51 41.15,31.73 42.24,30.63 42.24,29.85 43.15,28.94 43.15,26.71 44.48,25.38 44.48,23.61 48.71,19.38 48.71,18.07 52.03,14.75 55.39,14.75 59,11.14 65.08,11.14 65.41,10.81 78.59,10.81 79.21,10.19 83.79,10.19 84.05,10.45 90.2,10.45 90.48,10.73 90.81,10.73 v2(91.27,10.27) ; v2(50.7,43.37) 50.55,43.37 49.74,44.18 49.74,45.19 49.94,45.4 49.94,47.24 v2(50.32,47.62)
  BOTTOM w0.102: JKB.19 91.9,11.97 92.09,11.78 92.09,11.09 v2(91.27,10.27)
KSO8: length 104
  TOP w0.102: v2(41.17,47.47) 45.25,47.47 46.1,46.62 UE1.46 ; RPE7.8 41.23,58.3 41.41,58.12 v2(41.75,58.12) ; v2(92.97,10.8) v1(92.43,10.8)
  IN1 w0.114: v2(41.75,58.12) 41.75,57.81 39.9,55.96 39.9,51.09 41.17,49.82 v2(41.17,47.47) 41.17,46.42 40.96,46.21 40.96,45.1 41.43,44.63 41.43,43.21 40.92,42.71 40.92,42.26 41.46,41.73 41.46,40.14 41.11,39.8 41.11,35.67 40.69,35.24 40.69,34.47 41.26,33.9 41.26,33.08 41.63,32.71 41.63,31.93 42.73,30.83 43.22,30.83 43.63,30.42 43.63,26.91 46.18,24.36 46.18,22.64 49.24,19.58 49.24,18.23 52.23,15.23 55.59,15.23 59.2,11.62 65.28,11.62 65.61,11.29 78.79,11.29 79.41,10.67 83.59,10.67 83.85,10.93 89.88,10.93 90.8,11.84 91.86,11.84 92.14,11.56 92.14,11.25 92.59,10.8 v2(92.97,10.8)
  BOTTOM w0.102: JKB.17 93.5,11.34 v2(92.97,10.8)
KSO9: length 110.9
  TOP w0.102: UE1.68 44.34,56.52 45.37,57.55 RE389.1 44.45,59.19 v2(42.24,59.19)
  TOP w0.127: v2(100.35,11.65) 101.39,10.61 v1(101.39,10.26)
  IN1 w0.114: v2(42.24,59.19) 42.75,58.68 42.75,57.08 40.62,54.95 40.62,51.59 42.19,50.02 42.19,46.62 43.13,45.68 43.13,44.54 43.01,44.41 43.01,43.04 42.99,43.04 42.76,42.81 42.76,39.72 43.74,38.74 43.74,38.63 43.74,37.15 43.53,36.93 43.53,34.3 44.56,33.28 44.56,32.25 45.56,31.24 45.56,27.79 50.29,23.07 50.29,21.32 51.28,20.32 51.28,19.04 53.16,17.16 56.39,17.16 59.92,13.63 66.14,13.63 66.54,13.22 79.74,13.22 80.03,13.51 88.16,13.51 88.47,13.83 90.1,13.83 91,14.72 96,14.72 98.09,12.63 99.74,12.63 100.35,12.02 v2(100.35,11.65)
  BOTTOM w0.102: v2(100.35,11.65) 100.78,11.22 101.25,11.22 101.5,11.47 JKB.7
KSO10: length 106
  TOP w0.102: UE1.72 42.74,56.35 v2(43.06,56.68) 43.31,56.68 44.21,57.58 RPE6.8
  TOP w0.127: v1(103.24,10.49) 102.72,11.01 v2(102.02,11.01)
  IN1 w0.114: v2(43.06,56.68) 41.76,55.38 41.76,51.28 42.68,50.36 42.68,46.82 43.62,45.88 43.62,44.34 43.49,44.21 43.49,42.84 43.25,42.59 43.25,39.92 44.23,38.94 44.23,36.95 44.02,36.73 44.02,34.5 45.04,33.48 45.04,32.45 46.05,31.44 46.05,27.99 50.77,23.27 50.77,21.52 51.81,20.47 51.81,19.19 53.34,17.66 56.6,17.66 60.15,14.11 66.39,14.11 66.8,13.7 79.54,13.7 79.83,14 87.96,14 88.27,14.31 89.83,14.31 91.31,15.79 95.61,15.79 98.22,13.18 100.21,13.18 101.52,11.86 101.52,11.51 v2(102.02,11.01)
  BOTTOM w0.102: JKB.5 103.1,11.54 102.57,11.01 v2(102.02,11.01)
KSO11: length 103.8
  TOP w0.102: UE1.74 41.94,56.47 42.68,57.21 v1(42.9,57.21) 42.92,57.21 v2(43.29,57.58) 43.71,58 RPE6.7
  IN1 w0.114: v2(43.29,57.58) 43.5,57.37 43.5,56.53 42.04,55.08 42.04,51.34 42.92,50.46 42.92,46.92 43.87,45.96 43.87,44.25 43.74,44.13 43.74,42.75 43.49,42.49 43.49,40.02 44.47,39.04 44.47,36.85 44.26,36.63 44.26,34.66 45.28,33.64 45.28,32.55 46.29,31.54 46.29,28.09 51.01,23.37 51.01,21.62 52.06,20.57 52.06,19.29 53.44,17.9 56.7,17.9 60.25,14.35 66.49,14.35 66.9,13.95 79.44,13.95 79.73,14.24 87.86,14.24 88.17,14.55 89.73,14.55 91.21,16.03 95.71,16.03 98.32,13.42 100.33,13.42 v2(102.14,11.62)
  BOTTOM w0.102: v2(102.14,11.62) 102.3,11.78 JKB.6
KSO12: length 102.7
  TOP w0.102: UE1.75 41.54,56.88 v2(41.81,57.15) 41.95,57.28 42.41,57.28 43.21,58.09 RPE6.6 ; v1(98.14,10.71) 97.5,11.36 v2(97.5,11.87)
  IN1 w0.114: v2(97.5,11.87) 97.5,12.52 95.78,14.24 91.2,14.24 90.3,13.34 88.67,13.34 88.36,13.03 80.23,13.03 79.94,12.74 66.34,12.74 65.95,13.13 59.73,13.13 56.19,16.68 52.96,16.68 50.8,18.84 50.8,20.1 49.81,21.09 49.81,22.87 45.08,27.59 45.08,31.04 44.07,32.05 44.07,32.99 42.87,34.19 42.71,34.19 42.4,34.5 42.4,36.48 43.26,37.35 43.26,38.05 43.26,38.54 42.07,39.73 42.07,41.9 41.55,42.42 41.55,42.59 41.91,42.96 41.91,44.24 42.65,44.98 42.65,45.48 41.66,46.47 41.66,49.87 40.14,51.39 40.14,55.48 v2(41.81,57.15)
  BOTTOM w0.102: JKB.12 v2(97.5,11.87)
KSO13: length 103.5
  TOP w0.102: v1(99.86,11.15) 99.6,11.15 v2(99.1,11.64) ; RPE6.5 42.71,58.17 v2(42.26,57.72) 41.75,57.72 41.14,57.1 UE1.76
  IN1 w0.114: v2(99.1,11.64) 98.35,12.39 97.98,12.39 95.88,14.48 91.1,14.48 90.2,13.58 88.57,13.58 88.26,13.27 80.13,13.27 79.84,12.98 66.44,12.98 66.05,13.37 59.83,13.37 56.29,16.92 53.06,16.92 51.04,18.94 51.04,20.22 50.05,21.22 50.05,22.97 45.32,27.69 45.32,31.14 44.31,32.15 44.31,33.18 43.29,34.2 43.29,37.03 43.5,37.25 43.5,38.39 43.5,38.64 42.52,39.62 42.52,42.81 42.15,43.17 42.15,44.14 42.89,44.88 42.89,45.58 41.93,46.54 41.93,49.94 40.38,51.49 40.38,55.09 42.26,56.97 v2(42.26,57.72)
  BOTTOM w0.102: JKB.9 99.1,11.82 v2(99.1,11.64)
KSO14: length 100.8
  TOP w0.102: RPE7.6 40.23,56.89 40.74,56.38 UE1.77 40.74,54.46 v2(41.08,54.12) ; v2(100.93,11.82) 100.93,12.07 v1(101.44,12.58)
  IN1 w0.114: v2(100.93,11.82) 99.81,12.94 98.12,12.94 95.51,15.55 91.41,15.55 89.93,14.07 88.37,14.07 88.06,13.76 79.93,13.76 79.64,13.46 66.64,13.46 66.24,13.87 60.05,13.87 56.5,17.42 53.24,17.42 51.54,19.12 51.54,20.41 50.53,21.42 50.53,23.17 45.81,27.89 45.81,31.34 44.8,32.35 44.8,33.38 43.77,34.4 43.77,36.83 43.99,37.05 43.99,38.84 43.01,39.82 43.01,42.71 43.09,42.79 43.11,42.79 43.25,42.94 43.25,44.31 43.37,44.44 43.37,45.78 42.43,46.72 42.43,50.26 41.51,51.19 41.51,53.69 v2(41.08,54.12)
  BOTTOM w0.102: v2(100.93,11.82) 100.7,12.05 JKB.8
KSO15: length 122.2
  TOP w0.102: v1(40.73,57.22) v2(40.73,58.04) RPE7.7 ; UE1.86 v2(37.14,52.89)
  IN1 w0.114: v2(93.3,9.28) 90.95,6.93 61.1,6.93 59.96,8.07 57.03,8.07 54.21,10.89 51.5,10.89 45.35,17.04 45.29,17.04 43.25,19.08 43.25,19.55 40.94,21.86 40.94,24.53 39.96,25.51 39.12,25.51 38.8,25.83 38.8,27.28 39.06,27.53 39.06,28.17 38.23,29 37.94,29 36.7,30.25 36.7,31.36 34.65,33.41 34.65,34.86 34.27,35.24 33.24,35.24 32.74,35.74 30.61,35.74 29.56,36.79 29.56,38.63 35.45,44.52 35.45,52.32 36.03,52.9 37.12,52.9 v2(37.14,52.89) 37.15,52.9 37.79,52.9 38.8,53.91 38.8,56.49 39.07,56.77 39.07,58.09 39.46,58.48 40.29,58.48 v2(40.73,58.04)
  BOTTOM w0.102: v2(93.3,9.28) 96.64,9.28 98.66,11.29 98.66,11.82 99.1,12.26 JKB.10
KSO16: length 122.2
  TOP w0.102: v2(92.69,9.33) 92.4,9.04 v1(92.18,9.04) ; v2(36.76,50.43) 36.1,50.43 35.28,51.24 35.28,52.89 34.74,53.44 UE1.92 ; RPE7.5 39.73,58.07 v2(39.76,58.04)
  IN1 w0.114: v2(39.76,58.04) 39.76,57.11 39.04,56.39 39.04,52.71 v2(36.76,50.43) 36.76,45.47 29.81,38.53 29.81,36.88 30.71,35.98 32.84,35.98 33.34,35.48 35.02,35.48 35.67,34.83 35.67,33.89 36.65,32.91 36.65,31.75 36.94,31.46 36.94,30.35 38.04,29.24 38.33,29.24 39.3,28.27 39.3,27.43 39.04,27.18 39.04,25.93 39.22,25.75 40.06,25.75 41.18,24.63 41.18,22.91 43.49,20.59 43.49,19.18 45.39,17.28 45.45,17.28 51.6,11.13 54.31,11.13 57.13,8.31 60.06,8.31 61.2,7.17 90.53,7.17 v2(92.69,9.33)
  BOTTOM w0.102: JKB.11 98.3,11.9 98.38,11.82 98.38,11.34 96.74,9.7 93.06,9.7 v2(92.69,9.33)
L_BKLT_CTRL: length 193.5
  TOP w0.102: v1(42.24,95.12) 41.84,94.72 R5206.1 40.75,94.29 v2(40.75,93.93)
  IN3 w0.135: v2(40.75,93.93) 40.75,92.78 40.63,92.67 40.63,90.84 41.15,90.32 41.15,87.78 39.81,86.43 38.8,86.43 38.03,85.66 38.03,83.03 37.25,82.25 37.25,68.09 36.45,67.29 36.45,64.04 34.7,62.29 34.7,57.16 37.09,54.77 37.09,53.93 38.19,52.83 38.19,52.31 40.39,50.11 40.39,48.92 39.18,47.72 39.18,44.19 39.82,43.55 39.82,41.86 39.98,41.69 39.98,40.29 39.17,39.48 39.17,38.18 39.78,37.57 39.78,35.7 41.91,33.56 41.91,32.37 43.54,30.74 43.54,30.26 50.04,23.76 50.04,19.26 52.23,17.08 53.04,17.08 54.09,16.02 55.07,16.02 56.66,14.43 57.26,14.43 58.41,13.28 75.48,13.28 75.89,12.87 79.25,12.87 79.62,13.24 83.16,13.24 83.57,13.65 86.34,13.65 88.8,16.1 89.97,16.1 90.55,15.52 93.64,15.52 94.22,16.1 99.02,16.1 99.1,16.03 103.03,16.03 105.15,13.91 117.92,13.91 122.75,18.75 122.75,20.77 126.66,24.68 126.66,24.97 128.11,26.42 128.11,32.37 128.51,32.77 128.51,34.22 129.48,35.19 129.48,37.24 128.38,38.34 128.38,39.18 v2(127.94,39.62)
  BOTTOM w0.102: v2(127.94,39.62) 127.58,39.62 UC1.R11
L_BKLT_EN_EC: length 154.3
  TOP w0.089: v2(127.94,40.21) 127.49,39.75 v1(127.49,39.34) 127.36,39.21 RC390.2
  TOP w0.102: UE1.91 35.11,55.48 35.11,57.13 v2(35.26,57.28)
  IN3 w0.135: v2(127.94,40.21) 127.53,39.8 127.53,38.87 129.26,37.15 129.26,35.28 128.29,34.31 128.29,32.92 127.85,32.48 127.85,26.53 126.4,25.08 126.4,24.79 122.07,20.46 122.07,19.46 116.84,14.22 105.21,14.22 103.14,16.29 99.21,16.29 99.13,16.36 94.11,16.36 93.53,15.79 90.66,15.79 90.08,16.36 88.69,16.36 86.23,13.91 83.46,13.91 83.05,13.5 79.51,13.5 79.14,13.13 76,13.13 75.58,13.55 58.51,13.55 57.37,14.69 56.8,14.69 55.21,16.28 54.2,16.28 53.13,17.36 52.43,17.36 50.3,19.48 50.3,23.87 43.8,30.37 43.8,32.99 42.4,34.4 42.4,34.96 42.17,35.19 41.61,35.19 40.06,36.74 40.06,39.76 40.29,39.99 40.29,42.12 40.08,42.33 40.08,43.66 39.44,44.3 39.44,47.61 40.65,48.82 40.65,50.22 38.45,52.41 38.45,52.94 37.4,53.99 37.4,54.99 35.26,57.13 v2(35.26,57.28)
  BOTTOM w0.102: v2(127.94,40.21) 127.64,40.21 UC1.R12
LAN_CLKREQ#_R: length 7.7
  TOP w0.102: UL1.12 v1(36.21,82.76) 36.21,82.41 35.98,82.18 RL7.2 RL10.2 35.98,80.37 36.29,80.07 38.81,80.07 39.01,80.26 QL1.1
LAN_EN: length 46.3
  TOP w0.102: v1(27.52,75.88) v2(28.25,75.88) 28.3,75.93 R3023.2 29.13,76.08 UL3.4 ; UE1.3 33.94,40.57 33.66,40.85 32.97,40.85 32.41,40.29 v2(32.41,40.11)
  IN2 w0.127: v2(32.41,40.11) 32.41,40.35 31.58,41.19 31.58,47.99 30.79,48.78 30.79,65.06 32.34,66.61 32.34,74.86 31.32,75.88 v2(28.25,75.88)
LAN_GND: length 30.5
  TOP w1.016: 19.69,78.53 17.42,78.53 16.03,79.92 ; 12.68,96.63 v4(18.04,96.63) 19.75,96.63 22.76,93.62 22.76,79.7 22.01,78.95
  vias: v2(0.5,96.18) v2(0.51,98.88) v2(2.54,98.88) v2(4.27,96.18) v2(4.58,98.88) v2(5.72,97.71) v2(6.61,98.88) v2(7.14,96.16) v2(8.64,98.88) v2(10.67,98.88) v2(11.55,97.06) v2(12.7,98.88)
LAN_MIDI0+: length 10
  TOP w0.089: UL1.1 33.69,87.31 v2(33.56,87.45)
  BOTTOM w0.089: TL1.2 29.78,93.2 30.15,92.84 30.3,92.84 30.31,92.83 31.21,92.83 32.92,91.12 32.92,87.46 33.07,87.31 33.41,87.31 v2(33.56,87.45)
LAN_MIDI0-: length 10
  TOP w0.089: UL1.2 34.02,86.91 33.93,86.99 33.69,86.99 v2(33.56,86.86)
  BOTTOM w0.089: v2(33.56,86.86) 33.43,86.99 32.94,86.99 32.6,87.32 32.6,90.99 v3(31.76,91.83) 31.08,92.51 30.17,92.51
  BOTTOM w0.102: TL1.3 29.85,92.2 30.17,92.51
LAN_MIDI1+: length 9.2
  TOP w0.089: v2(32.21,86.08) 32.37,85.92 32.67,85.92 32.86,86.11 UL1.4
  BOTTOM w0.089: TL1.5 29.83,90.2 30.17,89.86 30.9,89.86 31.42,89.34 31.42,88.04 31.09,87.71 31.09,87.28 31.63,86.75 31.63,86.21 31.88,85.95 32.08,85.95 v2(32.21,86.08)
LAN_MIDI1-: length 9.2
  TOP w0.089: UL1.5 33.86,85.71 33.77,85.79 33,85.79 32.81,85.6 32.32,85.6 v2(32.21,85.5)
  BOTTOM w0.089: TL1.6 29.82,89.2 30.17,89.54 30.77,89.54 31.11,89.21 31.11,88.18 30.78,87.85 30.78,87.15 31.31,86.62 31.31,86.08 31.75,85.63 32.08,85.63 v2(32.21,85.5)
LAN_MIDI2+: length 8
  TOP w0.089: UL1.6 33.97,85.31 33.89,85.23 33.68,85.23 v2(33.52,85.38)
  BOTTOM w0.089: TL1.8 29.8,87.2 30.08,86.92 30.4,86.92 30.86,86.46 30.86,84.99 31.44,84.42 32.68,84.42 32.84,84.58 32.84,84.93 33.15,85.23 33.36,85.23 33.51,85.38 v2(33.52,85.38)
LAN_MIDI2-: length 8
  TOP w0.089: v2(33.52,84.8) 33.63,84.91 UL1.7
  BOTTOM w0.089: TL1.9 29.64,86.2 30.05,86.61 30.26,86.61 30.55,86.32 30.55,84.86 31.31,84.1 v3(31.78,84.1) 32.81,84.1 33.16,84.45 33.16,84.8 33.28,84.92 33.4,84.92 v2(33.52,84.8)
LAN_MIDI3+: length 8.6
  TOP w0.089: UL1.9 35.01,83.31 v2(34.76,83.05)
  BOTTOM w0.089: v2(34.76,83.05) 34.9,82.91 34.9,82.4 34.6,82.1 31.98,82.1 30.56,83.52 30.24,83.52 30.04,83.72 30.04,84.03 29.87,84.2 TL1.11
LAN_MIDI3-: length 8.6
  TOP w0.089: UL1.10 35.41,83.12 v2(35.34,83.05)
  BOTTOM w0.089: v2(35.34,83.05) 35.21,82.92 35.21,82.27 34.73,81.78 v3(32.87,81.78) 31.85,81.78 30.43,83.2 TL1.12
LAN_WAKE#: length 19.7
  TOP w0.089: RC391.2 RC70.2
  TOP w0.102: RC70.2 105.29,37.24 v1(105.35,37.24) 108.23,37.24 112.93,41.94 113.72,41.94 114.25,42.48 115.66,42.48 116.21,43.02 117.59,43.02 118.27,42.35 118.27,42.03 v2(118.71,41.59)
  BOTTOM w0.102: v2(118.71,41.59) 119.05,41.93 UC1.AM15
LAN_X1: length 7.8
  TOP w0.102: UL1.28 36.61,88.65 36.68,88.73 37.81,89.86 RL8.1 37.81,90.47 37.61,90.67 CL16.1 37.61,91.28 37.21,91.68 37.21,93.94 37.4,94.13 YL1.1
LAN_X2: length 4.9
  TOP w0.102: UL1.29 36.21,88.76 36.41,88.96 RL8.2 36.41,90.41 36.68,90.67 CL17.1 36.68,91.76 YL1.3
LANWAKEB: length 4.4
  TOP w0.102: RL1.1 42.45,85.83 41.43,85.83 v1(41.4,85.8) 41.19,85.59 40.17,85.59 39.66,86.11 UL1.21
LCD_BRIGHTNESS: length 2.2
  BOTTOM w0.102: RN5201.2 45.3,96.38 45.27,96.41 JEDP.17
LCD_TST: length 84.3
  TOP w0.102: D5202.3 37.51,106.74 38.99,105.25 38.99,103.51 39.5,103 40.5,103 41.28,102.23 41.28,100.55 41.89,99.94 41.89,97.72 44.15,95.46 44.63,95.46 v1(45.27,94.82) 45.88,94.22 45.88,93.81 v2(45.9,93.78) ; UE1.26 43.14,42.25 42.09,43.29 42.09,43.63 42.36,43.9 43.72,43.9 44.07,43.54 v2(44.25,43.54)
  IN3 w0.135: v2(45.9,93.78) 45.9,92.77 43.93,90.8 43.93,86.7 41.35,84.12 41.35,82.78 41.94,82.19 41.94,81.71 43.11,80.53 43.11,68.05 44.13,67.03 44.13,56.48 46.59,54.01 46.59,43.99 45.15,42.55 44.58,42.55 44.25,42.88 v2(44.25,43.54)
  BOTTOM w0.102: v2(45.9,93.78) 45.8,93.89 RN5201.6
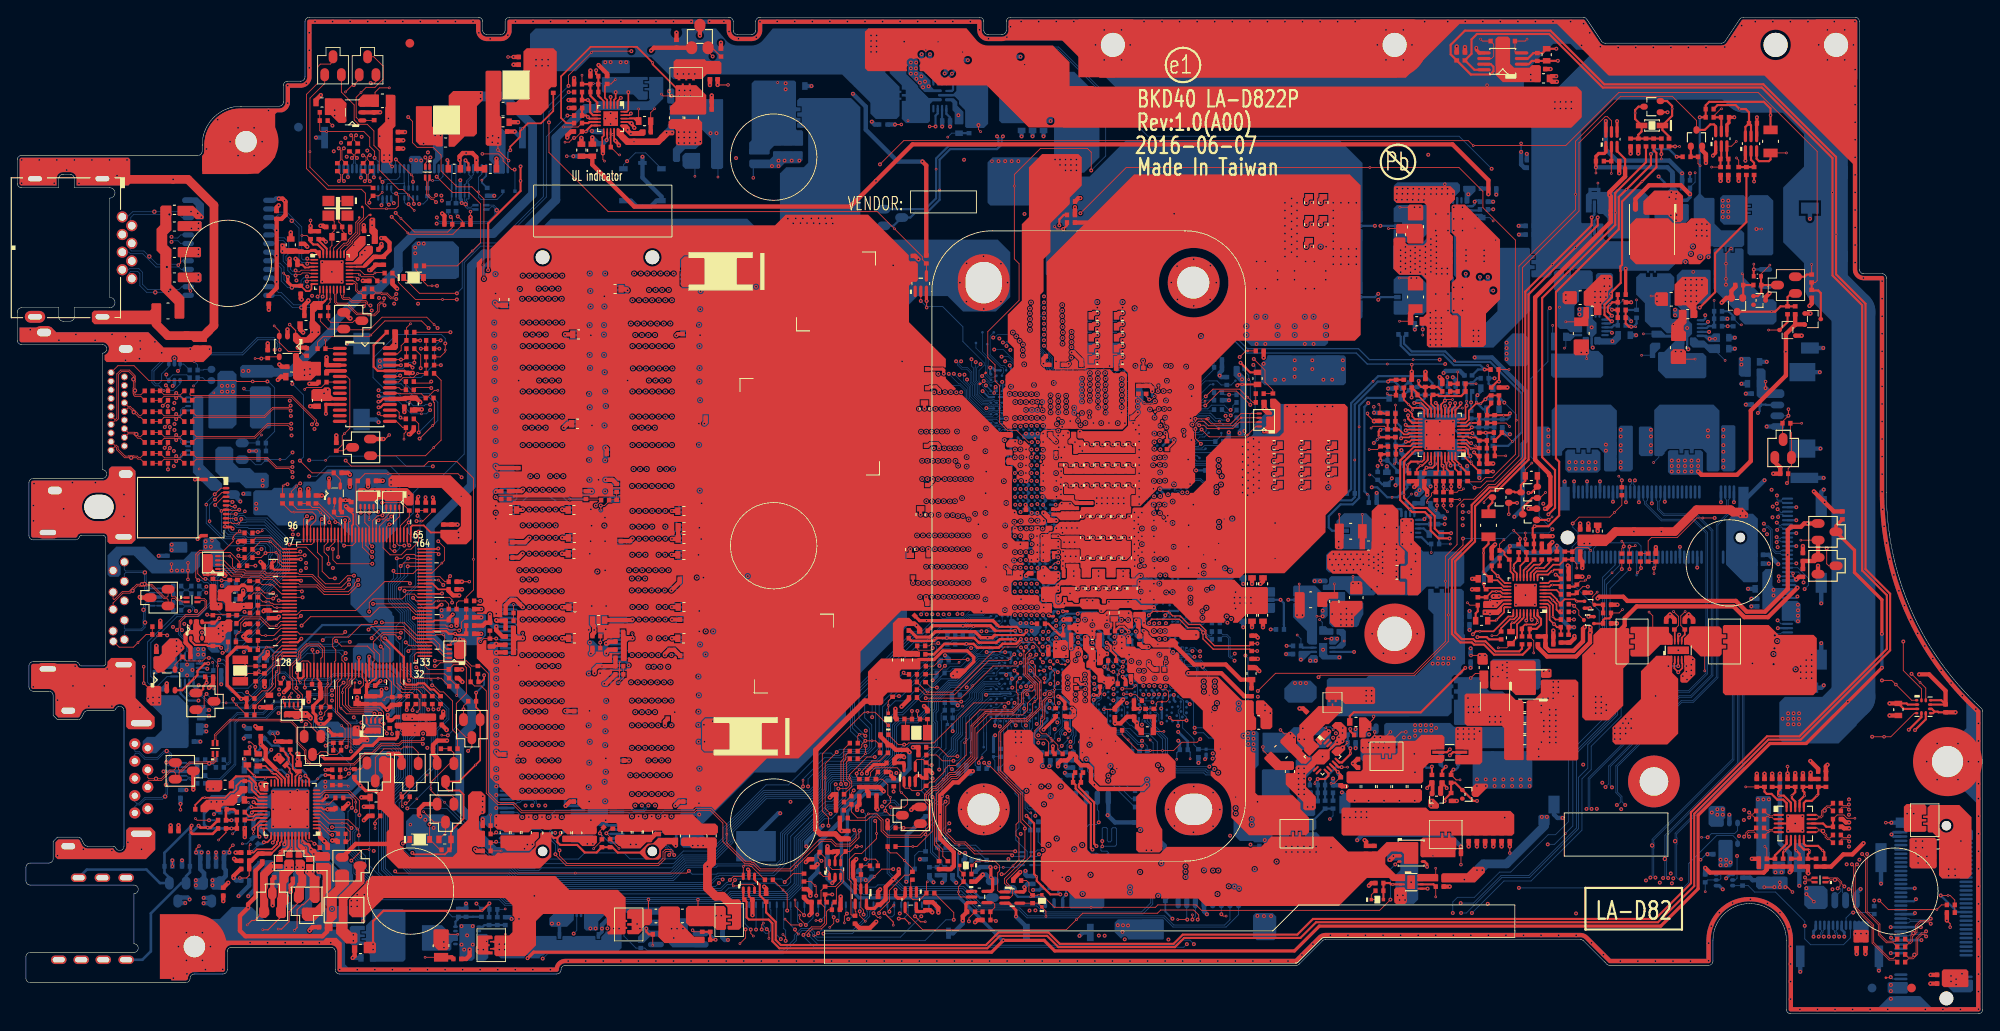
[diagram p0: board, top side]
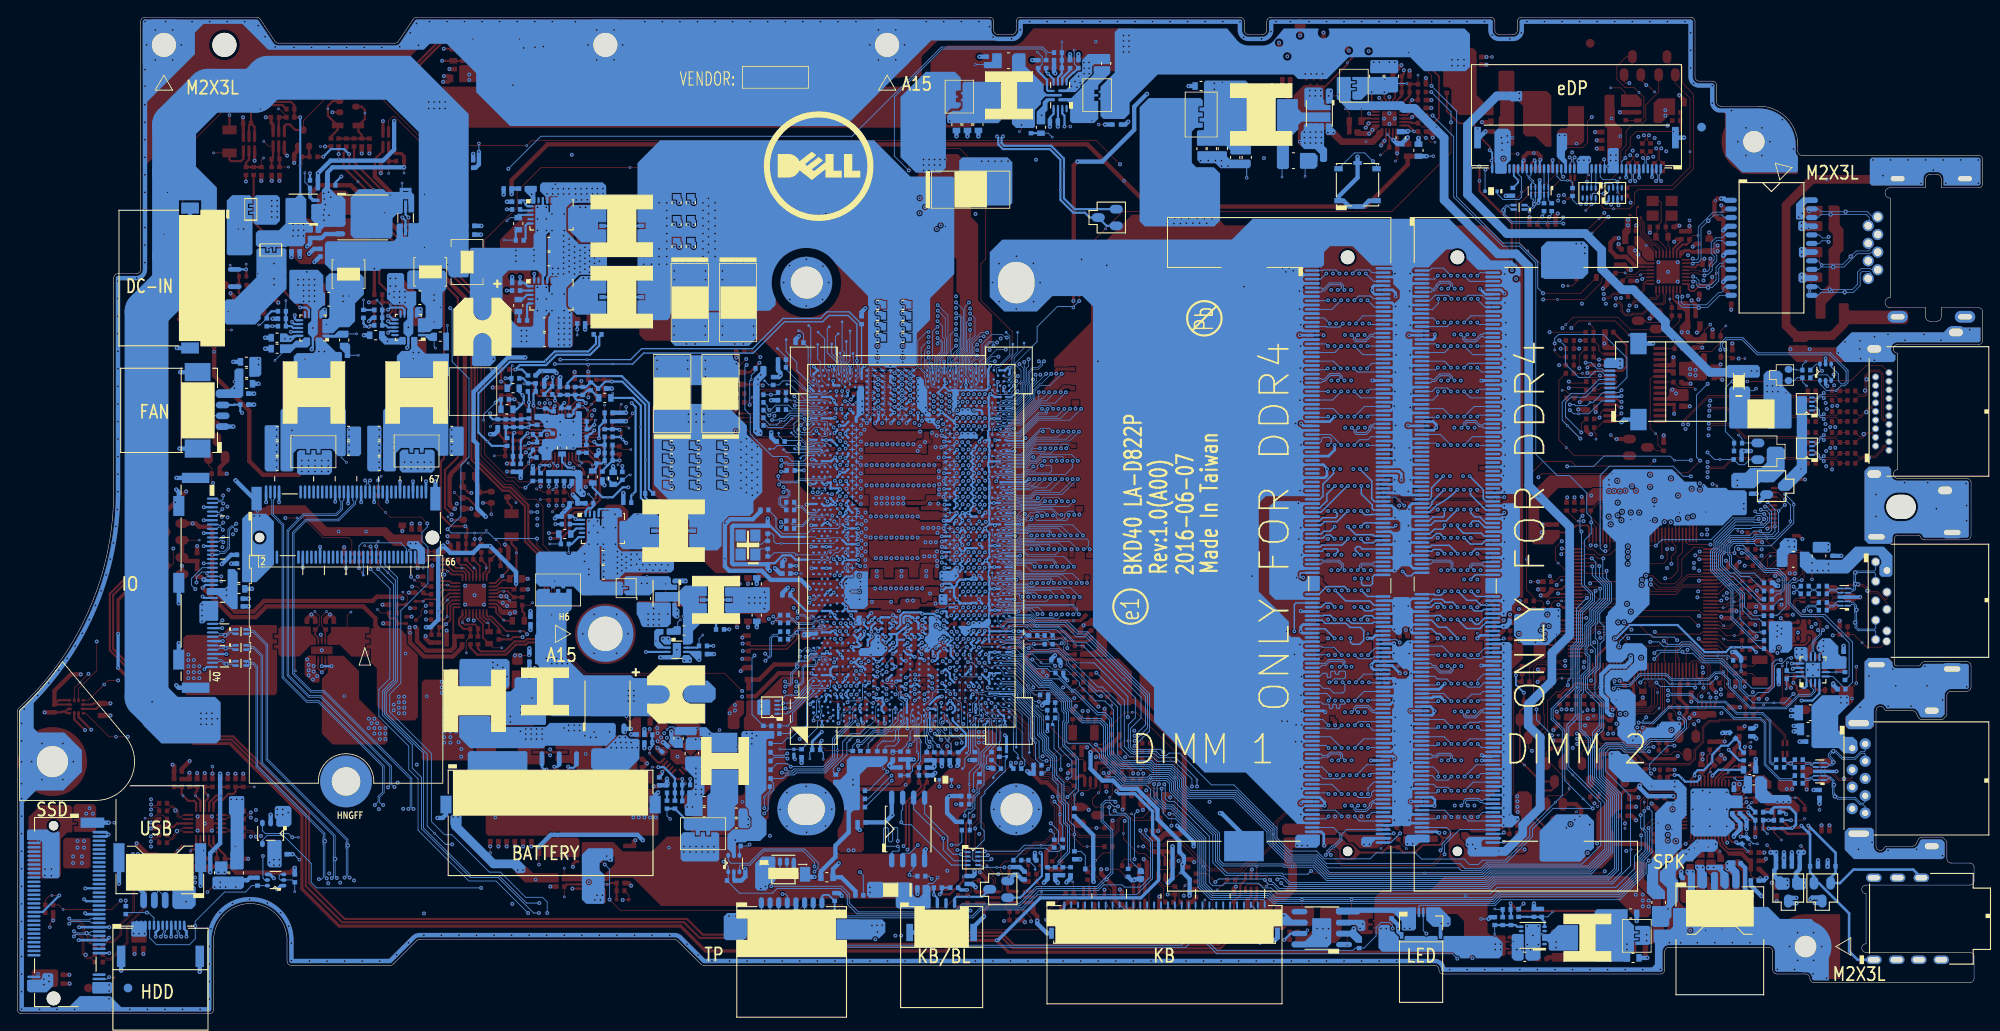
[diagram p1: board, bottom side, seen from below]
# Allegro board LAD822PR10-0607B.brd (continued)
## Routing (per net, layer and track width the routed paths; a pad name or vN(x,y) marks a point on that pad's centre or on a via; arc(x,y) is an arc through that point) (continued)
LCD_TST_C: length 5.2
  TOP w0.102: v2(45.8,96.35) 45.8,96.96 v1(45.61,97.15) v2(43.82,98.94)
  BOTTOM w0.102: JEDP.14 43.77,98.89 v2(43.82,98.94) ; RN5201.3 v2(45.8,96.35)
LCD_VCC_TEST_EN: length 4
  TOP w0.102: RE442.2 28.4,47.71 v1(28.77,47.71) 29.19,47.71 29.35,47.54 29.55,47.54 29.67,47.42 UE1.113
LCD_VCC_TEST_EN_R: length 83.3
  TOP w0.102: RE442.1 26.94,48.31 27.36,48.72 28.2,48.72 28.84,48.09 v2(29.62,48.09) 29.69,48.09 v1(30.01,48.41) ; v2(40.9,107.78) 41.33,107.78 41.51,107.96 D5201.3
  IN1 w0.114: v2(29.62,48.09) 29.62,48.1 30.25,48.74 30.25,58.9 28.99,60.17 28.99,71.97 27.28,73.68 27.28,77.76 29.01,79.48 30.03,79.48 30.73,80.18 34.51,80.18 38.43,84.11 38.43,85.45 39.79,86.81 41.19,86.81 43.44,89.06 43.44,90.29 43.81,90.66 43.81,90.66 44.38,91.23 44.38,93.81 48.75,98.18 48.75,99.88 46.94,101.68 46.94,103.69 42.85,107.78 v2(40.9,107.78)
LCDVDD_EN: length 12.3
  TOP w0.102: D5201.1 41.25,110.83 42.33,109.75 42.33,108.22 41.39,107.28 40.37,107.28 v1(39.78,106.69) 39.22,106.13 39.22,103.82 39.59,103.45 U5201.1 41.27,103.45 R5202.2
LDO1_CAP: length 11
  TOP w0.203: UA1.27 28,25.07 27.59,25.48 27.59,25.48 27.13,25.94 27.13,26.68 26.86,26.95 CA62.2 25.91,26.95 25.35,26.4 25.35,26.01 24.99,25.65 24.67,25.65 24.03,25.01 v1(21.68,25.01) 21.43,25.01 20.6,24.19 RA12.2
LDO2_CAP: length 5.6
  TOP w0.102: CA63.2 26.84,19.48 v1(26.97,19.6)
  TOP w0.203: CA63.2 27.35,18.66 27.73,19.04 29.44,19.04 30.04,19.64 30.04,19.89 30.19,20.03 UA1.39
LDO3_CAP: length 2.3
  TOP w0.203: UA1.7 35.22,23.87 35.42,23.67 v2(35.9,23.67)
  TOP w0.508: CA64.2 36.7,23.67 v2(35.9,23.67)
LDO_+1VALW: length 1.6
  TOP w0.127: v2(153.38,30.81) 153.91,31.34 v1(153.91,31.44)
  BOTTOM w0.254: PC306.1 153.32,30.81 v2(153.38,30.81)
LG_1.2V: length 5
  TOP w0.762: 74.64,101.47 74.17,100.99 v1(71.38,100.99) 70.61,100.99 70.07,101.53
  vias: v2(75.15,102.04) v2(75.78,102.04)
LGATE_CHG: length 10.3
  IN3 w0.762: 172.19,48.1 172.66,47.63 172.66,47.09 173.04,46.71 173.04,44.83 177,40.86 177,40.5
  BOTTOM w0.102: v1(170.48,47.86) 170.87,48.25 v2(170.87,48.36)
  vias: v2(171.48,48.36) v2(176.66,39.68) v2(177.3,39.68)
LID_CLOSE#: length 109.7
  TOP w0.102: v2(50.88,83.43) 46.54,83.43 D5203.1 ; UE1.41 49.76,44.62 49.94,44.45 51.08,44.45 v2(51.15,44.38) 51.4,44.64 51.4,45.35 RE25.2 CE8.1 ; CE2.1 80.42,111.87 UE7.3 79.95,111.4 v2(80.48,110.87) ; v2(63.8,107.46) 63.8,108.68 v1(66.44,111.31) 66.6,111.48 v2(71.07,111.48)
  IN1 w0.114: v2(71.07,111.48) 71.57,110.98 73.87,110.98 74.73,111.84 79.51,111.84 v2(80.48,110.87)
  IN3 w0.135: v2(51.15,44.38) 51.39,44.38 51.9,44.89 51.9,56.73 50.91,57.72 50.91,62.36 50.35,62.92 50.35,72.32 48.06,74.61 48.06,80.61 v2(50.88,83.43)
  BOTTOM w0.102: v2(50.88,83.43) 51.5,84.05 51.5,87.09 53.67,89.26 55.53,89.26 60.89,94.62 60.89,104.54 v2(63.8,107.46)
LINE1-L: length 4.9
  TOP w0.203: CA67.1 26.63,28.36 v1(27.44,27.56) 27.6,27.4 29.89,27.4 30.19,27.1 UA1.22
LINE1-R: length 3.7
  TOP w0.203: UA1.21 30.59,27.13 29.93,27.78 29.65,27.78 v1(29.47,27.95) 28.74,28.69 CA68.1
LINE1-VREFO-L: length 3.7
  TOP w0.203: UA1.31 27.32,23.47 v2(27.14,23.3)
  BOTTOM w0.127: v1(26.33,21.42) RA165.1
  BOTTOM w0.305: RA165.1 27.14,23.22 v2(27.14,23.3)
LINE1-VREFO-R: length 3.2
  TOP w0.203: v2(27.09,23.93) 27.16,23.87 UA1.30
  BOTTOM w0.127: v2(27.09,23.93) 27.09,24.12 v1(26.74,24.48)
  BOTTOM w0.305: v2(27.09,23.93) 26.91,23.93 RA166.1
LINE-IN-L: length 6.3
  TOP w0.305: RA55.2 25.08,23.68 RA83.1 24.15,23.59 LA8.2 v2(24.79,22.41)
  BOTTOM w0.127: RA165.2 25.42,21.33 v1(24.92,20.84)
  BOTTOM w0.305: RA165.2 v2(24.79,22.41) RA80.2
LINE-IN-R: length 13.1
  TOP w0.127: LA9.2 24.15,20.98 v1(23.29,20.12)
  TOP w0.305: RA56.2 25.41,21.46 RA84.1 v2(24.79,21.46) LA9.2
  BOTTOM w0.305: v2(24.79,21.46) 22.06,21.46 21.62,21.9 21.62,23.17 22.36,23.91 24.13,23.91 24.43,23.62 RA82.2 RA166.2
LP#_+VCCEOPIO: length 2
  BOTTOM w0.254: PU1200.6 107.53,108.22 v2(108.18,108.87) 108.4,109.09 PR1201.1
LPC_LAD0: length 154.8
  TOP w0.102: RZ124.1 v2(45.95,75.39) ; v2(45.19,51.81) 45.2,51.82 UE1.59
  IN1 w0.114: v2(45.95,75.39) 45.47,75.39 44.76,74.68 44.76,73.57 43.91,72.72 43.91,65.66 44.22,65.35 44.22,55.66 42.89,54.34 42.89,53.1 43.69,52.31 44.69,52.31 v2(45.19,51.81)
  BOTTOM w0.076: UC1.AY13 113.83,41.21 113.72,41.31 113.61,41.41 113.4,41.48 113.28,41.48 113.05,41.42 112.91,41.42 112.79,41.47 112.52,41.47 112.48,41.43 112.41,41.37 111.31,41.37
  BOTTOM w0.102: JDB1.8 43.82,74.46 44.05,74.68 44.61,74.68 45.32,75.39 v2(45.95,75.39) ; v2(45.19,51.81) 45.19,50.79 43.87,49.47 43.87,48.13 45.24,46.75 45.24,45.53 45.83,44.95 45.83,42.71 46.03,42.5 46.03,41.67 45.7,41.34 45.7,39.96 46.47,39.18 46.47,37.49 46.7,37.26 46.7,32.84 45.65,31.78 45.65,26.8 v1(44.39,25.54) 43.51,24.67 43.51,18.98 45.62,16.87 57.13,16.87 57.89,16.11 75.65,16.11 77.24,17.7 80.37,17.7 82.6,19.94 82.6,21.14 86.64,25.18 91.95,25.18 92.97,26.2 92.97,27.1 94.03,28.16 96,28.16 96.46,28.62 99.68,28.62 101.07,30 101.07,34.03 101.65,34.62 102.48,34.62 105.26,37.4 105.52,37.4 106.9,38.78 108.59,38.78 111.18,41.37 111.31,41.37
LPC_LAD1: length 169.1
  TOP w0.102: RZ125.1 48.99,77.97 v2(49,77.99) ; v2(44.38,51.85) 44.75,52.22 UE1.60
  IN1 w0.114: v2(44.38,51.85) 43.8,51.85 42.65,53 42.65,54.47 43.98,55.79 43.98,65.25 43.67,65.56 43.67,75.98 45.26,77.56 48.58,77.56 v2(49,77.99)
  BOTTOM w0.076: UC1.BA13 113.13,41.21 112.88,40.95 111.4,40.95 111.05,40.61
  BOTTOM w0.102: JDB1.7 43.71,73.96 44.1,74.35 44.92,74.35 45.58,73.69 46.74,73.69 48.29,75.24 48.29,77.27 v2(49,77.99) ; 111.05,40.61 108.83,38.39 107.83,38.39 105.67,36.22 105.67,35.46 104.13,33.92 102.09,33.92 101.53,33.35 101.53,29.81 99.1,27.39 96.67,27.39 96.36,27.7 94.21,27.7 93.42,26.91 93.42,26.01 88.34,20.93 88.34,17.83 87.86,17.34 80.93,17.34 80.79,17.2 77.39,17.2 75.84,15.65 57.7,15.65 56.94,16.42 45.4,16.42 43.06,18.76 43.06,25.08 45.16,27.18 45.16,32.58 44.38,33.36 44.38,35.83 v1(45.3,36.75) 45.98,37.43 45.98,39.03 44.83,40.18 44.83,42.22 45.37,42.76 45.37,44.76 44.78,45.34 44.78,46.57 43.41,47.94 43.41,49.66 44.35,50.6 44.35,51.82 v2(44.38,51.85)
LPC_LAD2: length 156.8
  TOP w0.102: v2(46.56,66.61) v1(48.08,68.12) 48.26,68.31 48.26,70.75 48.17,70.84 RZ121.1 ; v2(45.24,52.74) 46.08,52.74 46.2,52.62 UE1.61
  IN1 w0.114: v2(45.24,52.74) 44.99,52.74 44.11,53.61 44.11,54.49 44.73,55.11 44.73,64.77 v2(46.56,66.61)
  BOTTOM w0.076: 111.24,41.12 112.6,41.12 UC1.BB13
  BOTTOM w0.102: JDB1.6 44.41,73.46 46.05,71.81 47.68,71.81 48.67,70.82 48.67,68.71 v2(46.56,66.61) ; 111.24,41.12 108.72,38.59 107.76,38.59 105.44,36.27 105.44,35.55 104.09,34.2 102.05,34.2 101.3,33.45 101.3,29.91 99.78,28.39 96.55,28.39 96.09,27.93 94.12,27.93 93.2,27.01 93.2,26.1 92.05,24.95 86.74,24.95 82.83,21.05 82.83,19.84 80.46,17.47 77.33,17.47 75.75,15.88 57.8,15.88 57.03,16.64 45.49,16.64 43.29,18.85 43.29,24.9 45.39,27.01 45.39,31.85 46.47,32.93 46.47,36.93 46.21,37.2 46.21,39.12 45.46,39.88 45.46,41.42 45.8,41.77 45.8,42.41 45.6,42.61 45.6,44.85 45.01,45.44 45.01,46.66 43.64,48.03 43.64,49.56 44.78,50.7 44.78,52.28 v2(45.24,52.74)
LPC_LAD3: length 158.2
  TOP w0.102: UE1.62 46.13,53.02 45.96,53.2 45.01,53.2 44.56,52.74 v2(43.92,52.74) ; RZ122.1 46.46,68.32 v2(46.46,67.32)
  IN1 w0.114: v2(46.46,67.32) 44.49,65.34 44.49,55.59 43.13,54.24 43.13,53.44 43.84,52.74 v2(43.92,52.74)
  BOTTOM w0.076: UC1.AY12 114.12,40.64 113.84,40.92 113.83,40.92 113.83,40.91 113.49,40.91 113.36,40.79 111.56,40.79 111.1,40.32
  BOTTOM w0.102: v2(46.46,67.32) 48.29,69.15 48.29,70.77 47.65,71.41 45.96,71.41 44.41,72.96 JDB1.5 ; 111.1,40.32 108.96,38.18 107.9,38.18 105.91,36.2 105.91,35.37 104.22,33.69 102.19,33.69 101.76,33.26 101.76,29.72 99.2,27.16 96.58,27.16 96.26,27.47 94.31,27.47 93.65,26.82 93.65,25.91 88.57,20.83 88.57,17.73 87.96,17.11 81.02,17.11 80.88,16.97 77.49,16.97 75.94,15.43 57.61,15.43 56.84,16.19 45.31,16.19 42.83,18.66 42.83,25.17 44.94,27.28 44.94,32.34 v1(44.45,32.82) 44.15,33.13 44.15,36.07 45.75,37.67 45.75,38.93 44.56,40.13 44.56,43.21 44.83,43.49 44.83,44.97 44.56,45.25 44.56,46.47 43.18,47.84 43.18,49.75 43.97,50.54 43.97,52.69 v2(43.92,52.74)
LPC_LFRAME#: length 180.7
  TOP w0.102: UE1.58 46.25,51.42 45.81,50.99 43.77,50.99 43.54,51.21 v2(43.54,51.29) ; v2(49.53,77.63) v1(49.53,76.87) 49.53,76.65 48.95,76.07 RZ123.1
  IN1 w0.114: v2(43.54,51.29) 43.54,51.67 42.41,52.8 42.41,54.57 43.74,55.89 43.74,65.14 43.43,65.44 43.43,76.08 45.77,78.42 49.15,78.42 49.53,78.04 v2(49.53,77.63)
  BOTTOM w0.089: 112.05,40.56 113.59,40.56 UC1.BA12
  BOTTOM w0.102: 112.05,40.56 111.64,40.56 109.07,37.99 107.97,37.99 106.15,36.17 106.15,35.29 105.81,34.95 105.81,33.77 106.02,33.57 106.02,31.51 105.78,31.28 103.39,31.28 102.21,30.09 102.21,29.53 99.39,26.7 96.39,26.7 96.07,27.02 94.5,27.02 94.11,26.63 94.11,25.72 89.11,20.72 89.11,17.51 87.62,16.02 81.26,16.02 81.16,15.92 80.9,15.92 80.18,15.2 57.51,15.2 56.75,15.96 43.48,15.96 42.6,16.84 42.6,25.26 44.71,27.37 44.71,32.1 43.92,32.89 43.92,36.16 44.89,37.13 44.89,39.48 44.28,40.09 44.28,42.86 43.83,43.3 43.83,44.88 44.33,45.37 44.33,46.38 42.95,47.75 42.95,49.84 43.54,50.43 43.54,51.29 v2(43.54,51.29) ; v2(49.53,77.63) 49.53,78.21 49.08,78.67 43.91,78.67 41.18,75.94 41.18,73.67 42.38,72.46 JDB1.4
LPSS_UART2_CTS#: length 13.4
  TOP w0.102: v2(119.5,37.04) 118.68,36.21 118.68,34.42 v1(118.59,34.34) 118.42,34.17 118.42,33.45 117.76,32.79 117.76,32.06 118.01,31.81 119,31.81 119.36,31.45 119.36,30.31 RC382.1
  BOTTOM w0.089: v2(119.5,37.04) 119.5,37.36 119.7,37.56 121.09,37.56 121.57,37.08 121.57,36.54 121.79,36.32 UC1.AD4
LX_1.2V: length 10.6
  IN3 w0.762: 71.97,101.66 72.74,101.66 74.42,103.34 78.99,103.34 79.72,102.61
  BOTTOM w0.102: PR203.1 v1(81.09,96.9)
  vias: v2(70.64,102.36) v2(71.02,101.91) v2(80.23,101.98) v2(80.93,101.98)
LX_1.8VALW: length 1.9
  TOP w0.102: PR506.1 v1(50.98,9.2)
  vias: v2(49.37,8.31) v2(49.38,7.65)
LX_3V: length 0.7
  TOP w0.102: v2(181.64,76.58) v1(181.64,75.86)
  vias: v2(180.8,81.58) v2(180.8,81) v2(181,76.58)
LX_5V: length 1.9
  TOP w0.102: PR112.1 v1(194.19,75.81)
  vias: v2(191.86,81.53) v2(191.86,80.89) v2(191.93,76.69) v2(192.56,76.69)
LX_+1VALW: length 6.2
  TOP w0.102: v4(146.19,32.86) 146.64,32.42 v2(147.35,32.42)
  IN3 w0.762: 148.14,32.67 148.92,33.46 152.67,33.46
  vias: v2(147.76,31.99) v2(152.29,31.96) v2(152.61,32.48)
MCT1:
  vias: v2(20.88,92.69) v2(21.3,92.26) v4(20.11,92.9)
MCT2:
  vias: v2(20.98,91.55) v2(20.97,90.94) v4(20.16,90.94)
MCT3: length 1.5
  TOP w0.127: RL22.1 18.9,86.96 v4(18.63,86.7)
  vias: v2(20.97,88.54) v2(20.95,87.93)
MCT4: length 1.3
  TOP w0.127: 19.87,84.96 19.87,83.88 v4(20.04,83.7)
  vias: v2(20.95,85.57) v2(20.94,84.96)
ME_FWP_EC: length 109.1
  TOP w0.102: v2(51.43,62.12) 51.01,62.54 v1(42.9,62.54) 40.24,62.54 RE357.1 39.21,61.51 39.21,56.68 39.54,56.35 UE1.80 ; RC223.1 99.8,29.27 98.92,29.27 97.74,28.09 v2(97.74,27.8)
  IN1 w0.114: v2(51.43,62.12) 52.66,60.89 52.66,43.7 53.45,42.91 53.45,39.04 54.5,37.99 54.5,31.41 55.02,30.89 55.54,30.89 55.87,30.56 55.87,29.24 58.29,26.83 63.05,26.83 64.73,25.14 64.73,22.28 65.6,21.42 68.31,21.42 68.97,20.75 87,20.75 90.88,24.63 96.16,24.63 97.74,26.22 v2(97.74,27.8)
ME_SUS_PWR_ACK: length 136
  TOP w0.102: v2(117.26,41.58) 116.88,41.2 116.88,39.41 118.11,38.19 118.11,36.49 v1(117.77,36.16) 117.52,35.91 117.52,34.97 116.73,34.19 112.74,34.19 111.06,32.5 111.06,29.54 108.75,27.22 108.14,27.22 106.37,25.45 106.37,19.77 107.12,19.03 107.12,18.25 RC74.2 ; v2(50.24,44.89) 49.66,44.89 49.53,45.02 UE1.42
  IN3 w0.135: v2(117.26,41.58) 117.25,41.59 116.65,41.59 116.12,41.06 115.13,41.06 107.9,33.82 100.51,33.82 99.93,33.25 99.93,28.77 98.52,27.36 96.98,27.36 96.49,27.85 89.53,27.85 82.26,20.58 70.41,20.58 69.72,19.89 67.62,19.89 66.95,19.21 65.69,19.21 64.78,20.12 61.76,20.12 60.83,21.06 58.79,21.06 57.28,22.57 57.28,32.34 55.78,33.84 54.72,33.84 53.57,34.98 53.57,40.17 51.07,42.67 50.76,42.67 50.24,43.2 v2(50.24,44.89)
  BOTTOM w0.089: UC1.AR13 117.1,41.31 117.26,41.47 v2(117.26,41.58)
MEC_XTAL1: length 3.1
  TOP w0.102: C5225.1 RE366.2 26.54,40.27 Y1.1
MEC_XTAL1_R: length 5
  TOP w0.102: RE366.1 27.78,41.18 28.44,41.84 28.44,42.06 28.84,42.46 v1(28.86,42.46) 29.69,42.46 30.65,43.42 UE1.123
MEC_XTAL2: length 8.1
  TOP w0.102: Y1.2 26.72,39.4 RE368.1 C5226.1 29.58,40.38 v1(29.58,41.13) 29.58,41.6 30.6,42.62 UE1.125
MIC1-L: length 4.8
  TOP w0.254: v2(31.27,27.58) 31.39,27.46 UA1.19
  BOTTOM w0.254: v2(31.27,27.58) 30.6,28.25 v1(30.1,28.25) CA74.1
MIC_IN_R: length 38.4
  TOP w0.127: v2(24.54,18.68) 24.54,19.1 v4(24.96,19.51)
  IN2 w1.016: 23.65,19.62 23.65,22.73 24.86,23.93 24.86,26.56 27.98,29.69 29.02,29.69
  IN3 w1.016: 21.87,16.16 21.47,16.56 19.26,16.56 15.17,12.47 15.17,5.46 14.41,4.69 8.66,4.69 7.4,5.96 JHP.3
  vias: v2(22.6,15.46) v2(22.6,14.88) v2(23.9,18.68) v2(29.85,29.54) v2(30.27,29.97)
MODEL_ID: length 25.7
  TOP w0.102: R2446.2 22.81,50.19 v2(23.64,50.19) 24.55,50.19 R2407.2 24.6,50.24 C2403.1 ; v2(32.94,48.92) 32.83,49.02 UE1.109
  IN1 w0.114: v2(32.94,48.92) 32.94,48.74 31.99,47.79 31.99,46.78 30.67,45.46 26.95,45.46 26.7,45.71 25.79,45.71 24.5,44.43 24.5,43.54 24.16,43.2 23.31,43.2 22.39,44.12 22.39,47.98 23.07,48.66 23.07,49.61 v2(23.64,50.19)
MONO_PC_BEEP_R: length 5.4
  TOP w0.203: UA1.16 32.59,27.28 v2(32.77,27.46)
  TOP w0.254: v2(35.67,27.64) 36.22,27.64 RA1114.2
  BOTTOM w0.254: v2(35.67,27.64) 35.21,27.64 v1(34.76,27.2) 34.45,26.88 33.06,26.88 32.77,27.17 v2(32.77,27.46)
MPHYP_PWR_EN: length 1
  TOP w0.089: v2(118.87,38.85) 118.86,38.84 T4974.1
  BOTTOM w0.076: UC1.AM10 119.05,39.03 v2(118.87,38.85)
MSCLK: length 22.8
  TOP w0.102: v2(25.68,58.37) 25.62,58.3 24.73,58.3 24.66,58.37 JDEG1.6
  BOTTOM w0.102: RE72.2 25.87,45.7 26.75,45.7 27.82,46.77 27.82,48.59 30.81,51.58 30.81,53.32 30.42,53.71 30.42,54.5 28.72,56.2 26.78,56.2 26.67,56.31 25.38,56.31 24.66,57.03 24.66,57.92 25.04,58.3 25.62,58.3 v2(25.68,58.37)
MSDATA: length 23.7
  TOP w0.102: v2(25.3,57.88) 25.28,57.87 JDEG1.7
  BOTTOM w0.102: v4(26.34,58.19) 26.1,57.95 25.36,57.95 v2(25.3,57.88) 24.89,57.47 24.89,57.12 25.43,56.58 28.66,56.58 30.65,54.59 30.65,53.81 31.04,53.41 31.04,51.49 28.09,48.53 28.09,45.72 26.56,44.19 RE75.2
NCT7718_DXN: length 97.4
  TOP w0.254: THM26.3 174.83,110.62 175.47,111.26 C2607.2 176.51,111.26 C2606.2 v2(178.12,111.75)
  IN1 w0.254: v2(178.12,111.75) 177.59,111.23 176.73,111.23 176.22,110.71 176.22,103.86 174.85,102.48 114.27,102.48 v2(113.39,101.61)
  BOTTOM w0.254: v2(113.39,101.61) 113.55,101.44 113.55,100.83 113.24,100.52 107.81,100.52 106.34,99.05 v1(106.34,97.81) 106.34,94.43 105.08,93.17 Q2603.3
NCT7718_DXP: length 97.9
  TOP w0.254: v2(178.3,110.36) C2606.1 176.99,110.35 C2607.1 175.29,110.35 174.91,109.97 THM26.2
  IN1 w0.254: v2(178.3,110.36) 177.81,110.85 176.89,110.85 176.6,110.55 176.6,103.7 175,102.1 114.57,102.1 v2(114.07,101.61)
  BOTTOM w0.254: v2(114.07,101.61) 113.94,101.47 113.94,100.67 113.39,100.13 107.97,100.13 106.75,98.92 v1(106.75,95.4) 106.75,94.26 105.25,92.77 103.91,92.77 103.36,92.21 Q2603.1 101.4,91.24 Q2603.2
NRB_BIT: length 14.4
  BOTTOM w0.076: UC1.AR7 116.85,37.46 116.57,37.18 116.41,37.18 116.24,37.01 115.98,37.01 115.89,36.93 115.44,36.93 115.29,36.78 114.55,36.78 114.47,36.85 114.1,36.85 114.01,36.76 113.26,36.76 113.24,36.75 112.58,36.75 112.2,36.37
  BOTTOM w0.102: 112.2,36.37 112.14,36.37 110.18,34.41 110.18,31.92 v1(109.64,31.38) 109.64,29.49 RC186.2
NTC_IA: length 3.5
  TOP w0.102: v2(165.23,71) 165.36,71.13 v1(166.11,71.13)
  TOP w0.203: v2(165.23,71) 164.79,70.56 164.79,70.08 164.84,70.03 PU602.15
  BOTTOM w0.254: PR635.2 165.23,71.41 v2(165.23,71)
PANEL_BKEN_EC: length 60.8
  TOP w0.102: UE1.117 32.58,45.82 v2(32.83,46.07)
  TOP w0.127: v1(45.94,93.04) 45.29,93.68 v2(45.29,93.76)
  IN1 w0.114: v2(32.83,46.07) 33.96,47.2 33.96,55.63 32.55,57.05 32.55,58.46 30.2,60.81 30.2,71.51 30.9,72.22 30.9,74.98 33.63,77.71 33.63,79.27 34.06,79.7 34.71,79.7 38.92,83.91 38.92,85.25 39.23,85.57 40.76,85.57 43.97,88.78 43.97,90.14 45.26,91.43 45.26,93.73 v2(45.29,93.76)
  BOTTOM w0.102: v2(45.29,93.76) 44.99,93.76 44.8,93.95 RN5201.8
PBAT_CHG_SMBCLK: length 222.5
  TOP w0.102: UE1.9 36.34,38.16 35.86,37.68 35.86,35.86 RE425.1 35.58,34.93 35.58,34.62 v2(35.16,34.2) ; PR770.1 v2(180.19,46.54)
  TOP w0.254: PR20.2 163.17,26.2 v2(163.17,26.13)
  IN2 w0.127: v2(81.64,15.55) 81.64,15.74 83.32,17.42 85.31,17.42 92.25,24.35 95.3,24.35 100.08,19.58 100.08,16.7 100.82,15.96 103.17,15.96 104.42,14.7 115.74,14.7 116.65,13.79 118.46,13.79 119.23,14.56 125.79,14.56 126.57,15.34 129.62,15.34 130.58,14.37 138.04,14.37 139.46,15.79 144.54,15.79 145.04,16.29 160.15,16.29 165.79,21.93 165.79,24.72 165.17,25.34 163.52,25.34 163.17,25.69 v2(163.17,26.13) 164.02,26.13 164.14,26.25 164.14,26.57 164.41,26.84 165.76,26.84 168.96,23.64 175.56,23.64 179.63,27.71 179.63,29.65 179.91,29.93 179.91,41.19 177.04,44.06 177.04,45.29 177.74,45.99 179.65,45.99 v2(180.19,46.54)
  BOTTOM w0.102: v2(81.64,15.55) 81.54,15.65 80.96,15.65 80.27,14.97 57.42,14.97 56.65,15.73 43.39,15.73 42.37,16.75 42.37,25.36 44.38,27.37 44.38,30.61 43.62,31.38 41.58,31.38 41.23,31.02 39.25,31.02 38.52,31.74 35.91,31.74 34.52,33.13 34.52,33.87 34.85,34.2 v2(35.16,34.2)
PBAT_CHG_SMBDAT: length 220.5
  TOP w0.102: v2(35.11,34.81) 35.11,35.47 RE424.1 35.63,35.99 35.63,37.77 35.94,38.08 35.94,38.23 v1(35.94,38.23) UE1.8 ; PR769.1 v2(180.17,45.65)
  TOP w0.254: v2(165.43,26.13) 165.43,26.21 PR18.2
  IN2 w0.127: v2(180.17,45.65) 177.76,45.65 177.3,45.19 177.3,44.17 180.17,41.3 180.17,29.83 179.89,29.55 179.89,27.61 175.67,23.39 168.86,23.39 165.66,26.59 164.52,26.59 164.39,26.46 164.39,26.25 164.51,26.13 v2(165.43,26.13) 165.43,25.44 166.04,24.83 166.04,21.82 160.26,16.04 145.14,16.04 144.65,15.54 139.57,15.54 138.15,14.12 130.48,14.12 129.51,15.08 126.68,15.08 125.9,14.3 119.33,14.3 118.56,13.53 116.55,13.53 115.63,14.45 104.32,14.45 103.06,15.7 100.71,15.7 99.83,16.59 99.83,19.47 95.2,24.1 92.35,24.1 85.42,17.17 83.42,17.17 82.06,15.8 82.06,15.27 81.84,15.06 81.29,15.06 v2(81.21,15.14)
  BOTTOM w0.102: v2(81.21,15.14) 80.81,14.74 57.32,14.74 56.56,15.5 43.29,15.5 42.14,16.65 42.14,25.45 44.15,27.46 44.15,30.52 43.52,31.15 41.68,31.15 41.32,30.79 39.15,30.79 38.43,31.52 35.81,31.52 34.29,33.03 34.29,33.99 v2(35.11,34.81)
PBAT_PRES#: length 294.3
  TOP w0.102: CE76.1 27.6,55.11 29.4,55.11 30.7,53.82 UE1.97 32.28,53.82 32.49,54.03 33.43,54.03 34.83,52.64 34.83,50.63 35.67,49.79 37.27,49.79 38.21,50.73 v2(38.97,50.73)
  TOP w0.254: v2(168.94,24.65) 168.51,24.65 PD3.2 166.4,26.75 PR15.2 PR16.1 165.19,24.81 v2(165.19,24.63) ; PC14.1 v2(192.05,99.25) ; PR764.1 175.54,54.4 PC753.2 PR756.1 175.39,55.44 175.39,56.23 v2(175.62,56.46) 177.21,56.46 178.45,57.7 178.45,63.93 178.08,64.3 178.08,83.59 185.35,90.85 185.35,94.57 v1(186.22,95.44) 189.07,98.29 v2(189.07,99.56)
  IN2 w0.127: v2(165.19,24.63) 165.19,21.71 160.02,16.54 144.93,16.54 144.51,16.12 139.41,16.12 138.07,14.78 130.65,14.78 129.77,15.67 126.18,15.67 125.71,15.2 110.65,15.2 110.06,15.78 103.7,15.78 103.27,16.21 100.93,16.21 100.45,16.7 100.45,19.63 95.44,24.63 92.17,24.63 85.23,17.7 83.05,17.7 80.45,15.1 79.85,15.1 78.96,14.2 59.5,14.2 57.87,15.83 57.43,15.83 56.47,16.8 52.31,16.8 50.42,18.68 50.42,25.66 51.84,27.08 51.84,29.04 51.34,29.55 51.34,33.9 48.86,36.37 46.47,36.37 44.63,38.21 44.63,38.72 38.97,44.38 v2(38.97,50.73)
  IN2 w0.254: v2(168.94,24.65) 169.49,24.1 175.57,24.1 179.31,27.84 179.31,29.78 179.59,30.06 179.59,41 176.6,44 176.6,48.96 176.2,49.35 176.2,53.14 175.62,53.72 v2(175.62,56.46)
  BOTTOM w0.254: v2(189.07,99.56) 189.64,100.13 191.16,100.13 v2(192.05,99.25)
PC_BEEP: length 7
  TOP w0.102: DA8.1 34.78,30.03 35.08,30.34 35.77,30.34 36.08,30.03 37.01,30.03 37.48,30.5 RA79.2 37.48,31.36 RA19.1 37.94,31.85 37.94,32.96 v1(37.53,33.37)
PCH_ALW_ON: length 163.2
  TOP w0.102: v2(43.68,53.57) 43.44,53.57 43.14,53.88 UE1.71 ; v1(28.35,55.95) 28.19,55.79 v2(27.85,55.79) 27.33,55.79 RE448.2
  IN2 w0.127: v2(129.95,16.42) 129.39,16.97 119.49,16.97 118.39,15.88 115.72,15.88 112.29,19.31 108.98,19.31 101.57,26.73 99.27,26.73 98.63,27.36 96.94,27.36 95.94,28.37 94.36,28.37 93.17,27.17 90.12,27.17 82.68,19.73 82.21,19.73 79.6,17.13 77.62,17.13 77.03,16.54 60.03,16.54 58.71,17.86 58.28,17.86 55.97,20.17 55.97,26.41 55.6,26.78 54.79,26.78 54.11,27.47 54.11,31.25 53.36,32 53.36,36.16 51.95,37.57 51.95,40.04 50.51,41.47 49.14,41.47 46.51,44.1 46.51,46.08 42.9,49.69 42.9,52.8 v2(43.68,53.57)
  IN3 w0.135: v2(27.85,55.79) 27.85,56.16 31.81,60.12 32.97,60.12 33.18,60.32 33.18,61.63 v2(33.79,62.24)
  BOTTOM w0.102: v2(33.79,62.24) 34.66,62.24 35.83,63.41 43.21,63.41 44.28,62.34 44.28,53.93 43.92,53.57 v2(43.68,53.57) ; v2(129.95,16.42) 129.56,16.02 RE446.1
PCH_BATLOW#: length 14.1
  TOP w0.089: RC72.1 104.49,37.52 105.07,36.94
  TOP w0.102: 105.07,36.94 108.47,36.94 112.46,40.93 114.68,40.93 v1(114.87,41.11) v2(115.38,41.63)
  BOTTOM w0.076: v2(115.38,41.63) 115.8,41.2 UC1.AU13
PCH_DPWROK: length 46
  TOP w0.089: RC216.2 104.16,42.26 104.32,42.1 105.69,42.1 v2(105.95,42.35)
  TOP w0.102: v2(98.16,17.9) 99.32,17.9 99.6,17.62 RC1139.2
  IN1 w0.076: v2(105.95,42.35) 105.95,39.95 109.66,36.24 109.66,33.43 108.83,32.61
  IN1 w0.114: 108.83,32.61 107.85,31.62 107.54,31.62 106.92,31.01 105.15,31.01 102.44,28.3 100.86,28.3 99.06,26.5 99.06,25.87 97.81,24.61 v2(97.81,23.48)
  BOTTOM w0.076: v2(105.95,42.35) 105.95,43.24 v1(106.19,43.48) 107.22,44.51 109.95,44.51 110.54,45.11 112.18,45.11 112.44,44.85 UC1.BB20
  BOTTOM w0.102: v2(98.16,17.9) 98.16,23.12 v2(97.81,23.48)
PCH_JTAG_TCK1: length 5.7
  BOTTOM w0.076: 136.75,66.38 136.26,65.88 135.65,65.88 135.47,66.06 135.21,66.06 135.09,66 134.87,66 UC1.B56
  BOTTOM w0.102: 136.75,66.38 136.77,66.4 138.52,66.4 RC348.1 139.35,66.96 T117.1
PCH_PCIE_WAKE#: length 9
  TOP w0.089: v2(107.36,40.29) 106.38,39.31 RC395.2
  BOTTOM w0.076: v2(107.36,40.29) 107.59,40.52 108.82,40.52 v1(108.99,40.7) 109.88,41.59 110.64,41.59 111.64,42.58 112.54,42.58 UC1.BB15
PCH_PLTRST#: length 27
  TOP w0.102: 103.28,26.12 102.75,26.12 102.63,26.24 UC7.1 ; 103.28,26.12 UC7.2 ; 103.28,26.12 103.56,25.84 104.63,25.84 CC1806.1 105.63,26.84 106.1,26.84 107.34,28.08 107.34,28.31 107.77,28.74 108.61,28.74 109.82,29.95 v1(109.82,31.76) 109.82,33.6 111.41,35.19 115.12,35.19 115.83,35.9 115.83,37.04 115.62,37.24 115.62,38.44 v2(116.04,38.86)
  BOTTOM w0.076: v2(116.04,38.86) 116.2,39.01 118.12,39.01 UC1.AN10
PCH_PLTRST#_EC: length 280.4
  TOP w0.102: v2(105.82,28.8) 105.48,28.8 RC65.1 104.84,29.43 104.12,29.43 103.93,29.25 UC7.4 ; UZ13.16 42.1,69.26 v2(41.82,69.53) ; UE1.56 48.91,50.62 49.49,50.03 CE72.1 49.93,50.52 v2(50.09,50.68) ; v2(39.4,85.09) 39.19,85.31 UL1.19 ; R5807.2 v2(185.7,51.49)
  IN1 w0.114: v2(39.4,85.09) 39.64,85.33 40.86,85.33 44.21,88.68 44.21,89.67 46.51,91.97 v2(46.51,93.78) ; v2(105.82,28.8) 109.7,28.8 110.39,29.48 115.1,29.48 116.1,28.48 117.09,28.48 117.98,27.58 120.16,27.58 120.79,26.94 120.97,26.94 125.57,22.34 125.57,21.39 126.48,20.49 126.48,17.56 131.3,12.74 139.5,12.74 142.61,9.63 148.24,9.63 149.78,11.17 166.6,11.17 v2(167.1,11.67)
  IN3 w0.135: v2(41.82,69.53) 41.33,70.02 41.33,71.72 v2(41.81,72.21) 41.81,72.49 39.54,74.76 39.54,80.91 39.1,81.35 39.1,82.27 39.4,82.57 39.4,85.09 v2(39.4,85.09) ; v2(47.78,70.54) 48.14,70.54 48.52,70.16 48.52,62.16 49.73,60.95 49.73,51.04 v2(50.09,50.68) 50.09,49.77 49.71,49.39 49.71,45.75 49.15,45.19 49.15,42.98 52.02,40.11 52.02,36.81 52.79,36.04 52.79,34.03 54.99,31.83 55.71,31.83 56.67,30.87 56.67,22.44 58.93,20.18 60.65,20.18 61.47,19.36 62.69,19.36 62.93,19.6 64.56,19.6 65.47,18.69 67.17,18.69 67.84,19.36 69.94,19.36 70.63,20.05 82.47,20.05 83.27,20.85 83.99,20.85 90.22,27.07 96.04,27.07 96.72,26.4 98.99,26.4 100.97,28.38 104.85,28.38 105.27,28.8 v2(105.82,28.8)
  BOTTOM w0.102: v2(41.81,72.21) 42.06,71.96 JDB1.3 43.93,71.96 45.08,70.81 v1(45.43,70.81) 45.83,70.42 47.11,70.42 47.23,70.54 v2(47.78,70.54) ; v2(167.1,11.67) 167.71,11.67 171.82,15.77 175.03,15.77 180.68,21.43 180.68,27.37 181.76,28.44 181.76,31.15 185.22,34.61 185.22,37.37 183.94,38.65 183.94,49.73 v2(185.7,51.49) ; v2(46.51,93.78) 46.99,93.78 47.48,94.27 R5212.2
PCH_POPIRCOMP: length 13.5
  TOP w0.305: RC89.1 103.47,43.19 106.05,43.19 106.38,43.52 v4(107.59,43.52) 110.75,43.52 111.28,42.98 113.34,42.98 113.72,43.37 v2(115.47,43.37)
  BOTTOM w0.254: v2(115.47,43.37) 115.47,43.28 UC1.AU16
PCH_RSMRST#: length 122.6
  TOP w0.102: UZ6.1 98.28,14.98 v1(99.18,15.88) 100.04,16.75 v2(101.37,16.75) ; UE1.88 36.34,56.68 v2(36.1,56.91) 36.1,57.49 34.97,58.63 34.15,58.63 RE355.1 CC1810.1
  IN2 w0.127: v2(36.1,56.91) 36.91,57.72 38.33,57.72 40.21,55.84 40.21,43.7 44.91,39 44.91,38.34 46.59,36.66 48.93,36.66 51.67,33.92 51.67,29.73 52.1,29.29 52.1,26.97 50.68,25.55 50.68,18.79 52.41,17.05 56.57,17.05 57.54,16.09 57.97,16.09 59.6,14.46 78.85,14.46 79.74,15.35 80.34,15.35 82.94,17.95 85.13,17.95 92.66,25.48 94.26,25.48 94.61,25.13 96.16,25.13 96.41,24.87 97.01,24.87 98.86,23.02 98.86,22.04 101.37,19.53 v2(101.37,16.75)
PCH_RSMRST#_Q: length 53.7
  TOP w0.089: v2(106.58,42.92) 106.48,42.82 105.77,42.82 105.55,42.6 RC216.1
  TOP w0.102: v2(99.29,22.33) 99.44,22.18 v1(99.44,20.87) 99.44,20.28 97.72,18.55 96.96,18.55 96.29,17.89 96.29,15.51 96.49,15.32 96.49,11.5 96.64,11.35 RC75.2 97.06,11.45 97.06,11.81 96.98,11.88 UZ6.4
  IN1 w0.114: v2(106.58,42.92) 106.58,42.44 106.16,42.02 106.16,40.15 109.93,36.37 109.93,32.89 108.02,30.98 107.69,30.98 107.14,30.42 105.26,30.42 101.61,26.77 100.37,26.77 99.74,26.14 99.74,25.71 98.64,24.61 98.64,23.24 99.29,22.59 v2(99.29,22.33)
  BOTTOM w0.076: v2(106.58,42.92) 106.71,42.79 RC158.1 107.79,42.79 108.18,43.19 108.18,43.19 108.25,43.19 108.26,43.2 108.87,43.2 108.88,43.19 110.43,43.19 111.13,43.89 113.72,43.89 UC1.AY17
PCH_RTCRST#: length 48.4
  TOP w0.102: CC25.1 99.37,27.77 RC57.1 100.12,27.16 100.75,26.53 100.75,25.36 v1(101.04,25.06) 101.04,24.47 100.47,23.89 v2(100.47,23.53) 101.01,22.98 Q1901.1
  IN3 w0.135: v2(118.67,42.52) 118.67,42.39 119.1,41.96 119.1,41.43 118.87,41.2 118.67,41.2 118.05,40.58 118.05,40.42 117.84,40.21 117.84,39.75 117.26,39.17 116.91,39.17 115.76,38.02 115.76,37.38 115.11,36.73 113.93,36.73 107.55,30.35 107.55,25.63 105.98,24.06 103.31,24.06 102.72,23.48 100.52,23.48 v2(100.47,23.53)
  BOTTOM w0.102: v2(100.47,23.53) 100.18,23.24 99.25,23.24 98.66,22.64 98.66,17.76 CLRP1.2 ; UC1.AM16 118.98,42.94 v2(118.67,42.52)
PCH_RTCX1: length 23.2
  TOP w0.102: v2(104.18,35.06) 104.18,34.41 RC54.2 CC23.1 105.33,32.57 YC2.1
  IN3 w0.076: 115.49,43.75 115.53,43.79 118.9,43.79 v2(119.35,44.24)
  IN3 w0.135: 115.49,43.75 115.29,43.75 113.46,41.92 113.46,41.5 110.28,38.33 109.27,38.33 106,35.06 v2(104.18,35.06)
  BOTTOM w0.102: v2(119.35,44.24) 119.05,43.94 UC1.AM18
PCH_RTCX2: length 23.5
  TOP w0.102: v2(103.55,35.06) 103.55,35.05 103.55,35.05 RC54.1 103.54,34.13 CC26.1 102.81,34 YC2.2
  IN3 w0.076: 115.11,44.04 115.2,43.95 118.44,43.95 v2(118.72,44.23)
  IN3 w0.135: v2(103.55,35.06) 103.55,35.35 104.32,36.12 106.29,36.12 109.06,38.9 110.03,38.9 112.89,41.75 112.89,42.05 114.88,44.04 115.11,44.04
  BOTTOM w0.102: v2(118.72,44.23) 119.05,44.57 UC1.AM20
PCH_SMB_ALERT#: length 2.3
  TOP w0.089: RC23.1 v1(126.25,39.91) 126.57,39.6 v2(126.86,39.6)
  BOTTOM w0.102: UC1.R10 126.95,39.6 v2(126.86,39.6)
PCH_SMBCLK: length 246.1
  TOP w0.102: U5603.1 219.24,36.3 v4(217.42,38.13) 216.94,38.6 v2(215.8,38.6) ; v2(76.03,18.38) 75.89,18.52 75.89,18.82 75.69,19.02 74.99,19.02 74.73,18.76 74.73,18 74.14,17.41 63.63,17.41 62.75,18.28 v2(62.75,18.92)
  IN1 w0.114: v2(206.86,49.18) 208.92,49.18 216.25,41.86 216.25,39.05 v2(215.8,38.6) 214.15,36.95 214.15,21.49 216.4,19.24 216.4,13.21 215.65,12.46 213.82,12.46 212.4,13.88 212.4,14.93 208.95,18.38 203.31,18.38 202.3,19.39 194.82,19.39 194.38,18.94 163.69,18.94 163.08,19.55 159.28,19.55 157.44,17.71 154.91,17.71 154.22,17.01 146.36,17.01 v2(145.75,17.62)
  IN3 w0.135: v2(76.03,18.38) 76.39,18.75 79.62,18.75 80.4,19.53 82.69,19.53 83.23,20.07 84.31,20.07 87.9,23.66 91.34,23.66 92.26,24.57 94.79,24.57 95.02,24.34 99.75,24.34 v2(100.08,24.01)
  BOTTOM w0.102: v2(145.75,17.62) 145.19,17.06 QC2.1 145.19,15.57 RN20.2 143.87,13.96 140.07,13.96 139.53,14.51 132.18,14.51 131.41,13.74 131.41,12.69 130.28,11.56 118.91,11.56 117.99,12.48 111.46,12.48 109.43,14.51 102.45,14.51 100.68,16.28 100.68,21.24 101.81,22.37 101.81,24.14 101.5,24.44 101.02,24.44 100.59,24.01 v2(100.08,24.01) ; v2(206.86,49.18) 207.29,49.61 207.29,50.43 206.06,51.66 JIO1.17 ; JDIMM2.253 62.06,21.58 61.62,21.13 61.62,20.64 62.56,19.69 62.56,19.11 v2(62.75,18.92) ; JDIMM1.253 75.14,21.58 74.4,20.83 74.4,20.18 75.15,19.43 75.34,19.43 75.9,18.87 75.9,18.51 v2(76.03,18.38)
PCH_SMBDATA: length 254.8
  TOP w0.102: U5603.4 219.56,34.8 216.83,32.08 v4(216.06,32.08) v2(214.67,32.08) ; v2(75.44,18.38) 75.66,18.59 75.66,18.73 75.59,18.79 75.09,18.79 74.96,18.66 74.96,17.9 74.24,17.18 63.5,17.18 62.28,18.4 v2(62.28,18.47)
  IN1 w0.114: v2(142.73,19.59) 143.57,18.75 144.04,18.75 146.02,16.77 154.32,16.77 155.01,17.46 157.54,17.46 159.38,19.31 162.98,19.31 163.59,18.7 194.48,18.7 194.92,19.15 202.2,19.15 203.21,18.14 207.79,18.14 209.67,16.26 209.67,13.83 211.13,12.37 213.44,12.37 213.59,12.22 215.75,12.22 216.64,13.11 216.64,19.34 214.67,21.31 v2(214.67,32.08) 214.67,36.59 216.52,38.43 216.52,41.93 208.5,49.94 v2(206.73,49.94)
  IN3 w0.135: v2(142.73,19.59) 140.86,17.72 140.86,15.41 v2(140.21,14.77) ; v2(75.44,18.38) 75.44,18.68 75.77,19.01 79.51,19.01 80.3,19.79 82.58,19.79 83.12,20.33 84.21,20.33 87.79,23.92 91.23,23.92 92.9,25.59 94.14,25.59 94.94,24.79 100.14,24.79 v2(100.38,24.54)
  BOTTOM w0.102: v2(140.21,14.77) 132.06,14.77 131.18,13.89 131.18,12.85 130.13,11.79 119,11.79 118.09,12.71 111.55,12.71 109.52,14.74 102.54,14.74 100.91,16.38 100.91,21.15 102.04,22.28 102.04,24.23 101.55,24.72 100.56,24.72 v2(100.38,24.54) ; v2(62.28,18.47) 62.28,19.59 60.55,21.33 JDIMM2.254 ; v2(75.44,18.38) 75.67,18.61 75.67,18.78 75.24,19.2 75.05,19.2 74.17,20.09 74.17,20.79 73.63,21.33 JDIMM1.254 ; v2(142.73,19.59) 142.89,19.43 RN19.2 143.89,19.29 QC2.4 ; v2(206.73,49.94) 206.73,50.55 206.13,51.16 JIO1.18
PCH_SPI1_CLK_R: length 2.9
  TOP w0.102: UZ13.21 44.18,72.51 44.43,72.26 RZ127.2 RZ66.2
PCH_SPI_CLK: length 5.6
  BOTTOM w0.076: UC1.AV2 114.5,34.84 114.25,34.58 114.25,34.33 114.14,34.22 113.72,34.22 113.51,34.01 113.51,33.49 v2(113.72,33.28) 113.72,32.57
  BOTTOM w0.102: 113.72,32.57 113.72,31.59 113.82,31.49 RC59.1
PCH_SPI_CLK_R: length 10.8
  BOTTOM w0.102: UC2.6 123.73,23.72 v2(120.3,20.29) 120.3,18.98 119.03,17.72 RPC5.3
PCH_SPI_CS2#: length 146.9
  TOP w0.102: RZ115.1 v2(49.03,75.12)
  IN1 w0.114: v2(49.03,75.12) 48.87,75.12 45.7,71.94 45.7,69.38 47.53,67.55 47.53,65.4 47.07,64.95 47.07,61.2 47.67,60.6 47.67,59.32 47.34,58.99 47.34,55.81 46.55,55.02 46.55,51.39 45.86,50.71 45.86,49.67 45.22,49.04 45.22,44.57 45.58,44.22 45.58,43.66 46.17,43.07 46.17,41.62 45.62,41.08 45.62,39.59 46.24,38.97 46.24,35.96 48.42,33.79 49.49,33.79 50.29,32.99 50.29,25.8 52.22,23.87 52.22,22.12 55.23,19.11 57.26,19.11 60.81,15.56 66.19,15.56 66.19,15.56 66.99,15.56 67.4,15.15 78.94,15.15 80.23,16.45 83.53,16.45 84.22,15.75 85.4,15.75 85.75,16.1 87.8,16.1 88.08,16.38 89.16,16.38 91.14,18.36 93.53,18.36 94.66,17.24 100.16,17.24 101.48,18.56 103.03,18.56 108.11,23.63 108.11,25.46 108.64,25.99 109.64,25.99 110.5,26.85 113.15,26.85 114.19,25.81 v2(116.8,25.81)
  BOTTOM w0.076: 115.03,32.57 115.03,33.27 114.92,33.38 114.92,34.04 115.07,34.18 115.38,34.18 115.68,33.89 UC1.AU1
  BOTTOM w0.102: 115.03,32.57 115.03,31.17 115.93,30.27 115.93,28.96 116.04,28.85 116.04,28.58 116.8,27.83 v2(116.8,25.81)
PCH_SPI_CS2#_R: length 6.5
  TOP w0.102: UZ13.22 44.13,73.16 44.65,73.67 45.84,73.67 v1(46.33,74.16) RZ120.1 RZ115.2 RZ123.2
PCH_SPI_CS#0: length 12.2
  BOTTOM w0.076: UC1.AU3 115.89,35 115.64,34.74 115.64,34.37
  BOTTOM w0.102: RC1125.1 RC53.2 v1(117.3,26.56) 117.3,27.91 116.18,29.03 116.18,30.63 116.6,31.04 116.6,32.95 116.23,33.31 116.23,33.97 115.98,34.22 115.79,34.22 115.64,34.37
PCH_SPI_D0: length 157.5
  TOP w0.102: RZ64.1 v2(48.85,77.02)
  IN1 w0.114: v2(48.85,77.02) 47.41,75.59 47.41,74.05 45.46,72.09 45.46,69.27 47.29,67.45 47.29,65.5 46.83,65.05 46.83,59.05 47.1,58.78 47.1,55.91 46.31,55.12 46.31,51.49 45.34,50.53 44.76,50.53 43.64,49.41 43.64,47.22 44.64,46.21 44.64,44.81 45.34,44.12 45.34,43.56 45.92,42.98 45.92,41.72 45.38,41.18 45.38,39.49 46,38.87 46,35.86 48.88,32.98 48.88,26.87 51.98,23.77 51.98,22.02 55.13,18.87 57.16,18.87 60.71,15.32 66.29,15.32 66.89,15.32 67.3,14.91 79.04,14.91 80.33,16.21 83.43,16.21 84.12,15.51 85.54,15.51 85.89,15.86 87.9,15.86 88.18,16.14 89.26,16.14 91.24,18.12 93.35,18.12 94.47,16.99 100.28,16.99 101.52,18.23 103.15,18.23 106.98,22.06 v2(107.86,22.06)
  IN3 w0.135: v2(107.86,22.06) 108.51,22.7 108.51,26.97 110.02,28.48 110.02,30.89 113.25,34.12 114.14,34.12 114.28,34.26 114.28,34.98 114.42,35.11 114.69,35.11 114.82,34.98 114.82,34.29 114.96,34.16 115.31,34.16 115.41,34.26 v2(115.41,36)
  BOTTOM w0.076: v2(115.41,36) 115.2,35.79 UC1.AV3
  BOTTOM w0.102: v2(107.86,22.06) 106.98,21.17 106.98,19.74 RC58.1 106.92,18.8 108.02,18.8 108.4,19.18 110.77,19.18 RC355.2
PCH_SPI_D0_R: length 9.7
  BOTTOM w0.102: UC2.5 122.46,23.17 119.78,20.49 119.78,19.1 119.15,18.47 v2(118.25,18.47) 118,18.22 RPC5.2
PCH_SPI_D1: length 144.8
  TOP w0.102: RZ62.1 46.69,76.28 v2(46.69,74.76)
  IN1 w0.114: v2(46.69,74.76) 46.69,73.71 45.22,72.23 45.22,69.17 47.04,67.35 47.04,65.6 45.99,64.55 45.99,59.15 46.85,58.29 46.85,56.88 45.91,55.94 45.91,51.45 45.24,50.77 44.66,50.77 43.4,49.51 43.4,47.12 44.4,46.11 44.4,44.71 45.1,44.02 45.1,43.46 45.68,42.88 45.68,41.82 45.14,41.28 45.14,39.39 45.76,38.77 45.76,35.76 48.64,32.88 48.64,26.77 51.74,23.67 51.74,21.92 55.03,18.63 57,18.63 60.55,15.08 66.39,15.08 66.79,15.08 67.2,14.67 79.14,14.67 80.43,15.97 83.32,15.97 84.02,15.27 85.64,15.27 85.99,15.62 88,15.62 88.28,15.9 90.05,15.9 90.91,16.75 100.43,16.75 101.59,17.91 103.24,17.91 106.55,21.22 v2(107.87,21.22)
  IN3 w0.135: v2(107.87,21.22) 107.44,21.65 107.44,22.62 108.16,23.34 108.16,27.17 109.68,28.68 109.68,30.97 v2(114.27,35.55)
  BOTTOM w0.076: UC1.AW3 114.64,35.18 v2(114.27,35.55)
  BOTTOM w0.102: RC1119.1 107.46,20.81 v2(107.87,21.22)
PCH_SPI_D1_R: length 10.8
  IN1 w0.114: v2(118.67,18.96) 118.67,20.2 119.27,20.8 121.99,20.8 v2(123.25,19.53)
  BOTTOM w0.102: UC2.2 125,18.5 124.91,18.59 124.2,18.59 v2(123.25,19.53) ; RPC5.1 117.82,18.72 118.06,18.96 v2(118.67,18.96)
PCH_SPI_D2: length 15
  BOTTOM w0.076: UC1.AW2 114.64,34.4 114.4,34.17 114.33,34.17 114.17,34 114.17,32.57
  BOTTOM w0.102: RC1120.1 RC30.2 117.4,22.39 117.4,23.16 v1(117.3,23.26) 117.15,23.26 116.64,23.77 116.64,25.03 116.15,25.52 116.15,25.98 115.59,26.54 115.59,28.66 115.29,28.95 115.29,29.71 RC354.2 114.71,30.67 114.17,31.21 114.17,32.57
PCH_SPI_D2_R: length 2.9
  BOTTOM w0.102: UC2.3 123.73,16.85 124.22,16.36 v2(124.22,16.09) 124.06,15.93 RC61.2
PCH_SPI_D3: length 9.3
  BOTTOM w0.076: UC1.AU4 115.89,35.6 115.46,35.16 115.46,34.69 115.31,34.54 115.19,34.54 114.73,34.08 114.73,33.41 114.58,33.27 114.58,32.57
  BOTTOM w0.102: RC60.1 115.81,28.04 115.81,28.75 115.6,28.97 v1(115.6,29.84) 115.6,30.22 114.58,31.24 114.58,32.57
PCH_SPI_D3_R: length 12.7
  BOTTOM w0.102: UC2.7 125,23.63 125.16,23.46 v2(125.16,22.17) 124.9,21.9 124.04,21.9 119.36,17.22 RPC5.4
PCH_SPI_MISO: length 3
  TOP w0.102: RZ62.2 RZ124.2 44.72,75.76 v2(44.41,75.76) UZ13.26
PCH_SPI_MOSI: length 8.1
  TOP w0.102: RZ125.2 RZ64.2 v2(46.71,77.02) ; UZ13.23 44.21,73.81 v2(44.31,73.91)
  IN1 w0.114: v2(46.71,77.02) 45.06,77.02 43.99,75.95 43.99,74.23 v2(44.31,73.91)
PCI_CLK_LPC1: length 8.4
  BOTTOM w0.076: RC22.1 RC18.1 108.93,35.15 v1(109.41,35.63) 109.51,35.63 110.49,36.61 110.49,37.12 111.85,38.48 113.52,38.48 113.83,38.78 UC1.AY9
PCIE_PRX_C_LANTX_N6: length 2.8
  TOP w0.094: UL1.18 38.87,84.91 38.98,84.81 39.07,84.81 39.32,84.55 39.32,83.83 39.56,83.59 39.8,83.59 CL14.1
PCIE_PRX_C_LANTX_P6: length 2.8
  TOP w0.094: UL1.17 38.82,84.51 38.93,84.61 39,84.61 39.14,84.48 39.14,83.75 39.48,83.41 39.79,83.41 CL13.1
PCIE_PRX_LANTX_N6: length 150.1
  TOP w0.094: CL14.2 41.45,83.56 42.14,83.56 42.24,83.46 42.8,83.46 43.28,82.98 43.5,82.98 43.86,83.34 v2(43.86,83.36)
  IN1 w0.076: v2(131.54,44.32) 131.83,44.04 131.83,43.88 131.72,43.77 131.41,43.77 131.08,44.1 131.08,44.47 130.67,44.88 129.37,44.88 129.09,45.16 129.09,45.96 130.16,47.03
  IN1 w0.114: v2(43.86,83.36) 44.11,83.1 44.32,83.1 48.95,87.74 50.95,87.74 56.59,93.38 58.91,93.38 59.7,94.18 102.02,94.18 104.37,96.53 118.27,96.53 131.4,83.4 131.4,80.05 134.47,76.98 134.47,74.56 135.3,73.74 135.3,68.21 135.56,67.95 135.56,66.73 135.28,66.45 135.28,64.72 132.68,62.11 131.36,62.11 130.85,61.6 130.85,47.73 130.16,47.03
  BOTTOM w0.102: v2(131.54,44.32) UC1.G18
PCIE_PRX_LANTX_P6: length 150.1
  TOP w0.094: CL13.2 41.38,83.38 42.07,83.38 42.17,83.28 42.73,83.28 43.2,82.8 43.83,82.8 v2(43.86,82.77)
  IN1 w0.076: v2(132.27,44.32) 131.99,44.04 131.99,43.81 131.79,43.61 131.34,43.61 130.92,44.03 130.92,44.4 130.61,44.71 129.3,44.71 128.92,45.09 128.92,46.03 129.98,47.08 129.98,47.11 130.01,47.14 130.01,47.17 130.02,47.18
  IN1 w0.114: v2(43.86,82.77) 43.99,82.9 44.4,82.9 49.04,87.54 51.03,87.54 56.67,93.17 58.99,93.17 59.79,93.97 102.1,93.97 104.45,96.32 118.18,96.32 131.19,83.31 131.19,79.97 134.27,76.89 134.27,74.48 135.09,73.65 135.09,68.13 135.36,67.86 135.36,66.82 135.08,66.54 135.08,64.8 132.59,62.31 131.28,62.31 130.65,61.69 130.65,47.81 130.02,47.18
  BOTTOM w0.102: v2(132.27,44.32) UC1.F18
PCIE_PRX_WLANTX_N5: length 121.3
  IN1 w0.076: v2(132.17,43.4) 132.27,43.4 132.46,43.59 132.46,43.8 132.63,43.96 133.39,43.96 133.4,43.98 133.42,43.98
  IN1 w0.114: 133.42,43.98 133.67,43.98 134.53,43.12 134.53,41.26 135.91,39.89 137.08,39.89 138.15,38.81 138.15,36.98 138.41,36.72 138.97,36.72 139.46,36.23 139.46,35.32 138.55,34.41 138.55,30.83 139.02,30.36 139.02,29.43 140.02,28.43 140.02,26.82 141.21,25.63 141.21,24.49 141.63,24.07 141.63,23.88 141.84,23.68 141.84,22.35 143.03,21.15 144.3,21.15 145.3,20.15 151.43,20.15 152.52,19.06 156.89,19.06 158.73,20.89 179.53,20.89 181.81,23.17 181.81,23.53 v2(181.62,23.72)
  BOTTOM w0.076: UC1.F16 v2(132.17,43.4)
  BOTTOM w0.094: WLAN1.35 188.17,59.5 188.33,59.35 188.33,59.02 190.27,57.08 194.02,57.08 195.44,55.66 195.44,39.44 193.42,37.42 191.94,37.42 181.81,27.28 181.81,23.91 v2(181.62,23.72)
PCIE_PRX_WLANTX_P5: length 121.3
  IN1 w0.076: v2(132.85,43.4) 132.63,43.62 132.63,43.73 132.69,43.8 133.39,43.8 133.4,43.78 133.42,43.78
  IN1 w0.114: 133.42,43.78 133.59,43.78 134.33,43.03 134.33,41.17 135.82,39.68 137,39.68 137.95,38.73 137.95,36.89 138.32,36.52 138.88,36.52 139.25,36.15 139.25,35.4 138.34,34.5 138.34,30.74 138.81,30.27 138.81,29.35 139.82,28.35 139.82,26.73 141.01,25.54 141.01,24.4 141.43,23.98 141.43,23.8 141.63,23.59 141.63,22.26 142.95,20.95 144.22,20.95 145.22,19.95 151.34,19.95 152.43,18.85 156.97,18.85 158.81,20.69 179.61,20.69 182.01,23.09 182.01,23.53 v2(182.2,23.72)
  BOTTOM w0.076: UC1.E16 v2(132.85,43.4)
  BOTTOM w0.094: WLAN1.33 188.67,59.5 188.52,59.35 188.52,59.09 190.35,57.26 194.1,57.26 195.62,55.74 195.62,39.36 193.5,37.23 192.02,37.23 181.99,27.21 181.99,23.92 v2(182.2,23.72)
PCIE_PTX_C_LANRX_N6: length 154.5
  TOP w0.094: UL1.14 37.01,83.46 36.9,83.35 36.9,82.44 37.05,82.29 38.2,82.29 39.36,81.13 40.57,81.13 40.69,81.01 41.31,81.01 41.69,81.4 41.69,82.12 41.99,82.42 42.35,82.42 42.45,82.52 v2(42.45,82.85)
  IN1 w0.114: v2(42.45,82.85) 42.45,82.64 42.66,82.43 42.84,82.43 43.02,82.61 43.02,83.9 44.83,85.71 45.89,85.71 48.69,88.5 50.67,88.5 56.31,94.14 57.94,94.14 58.7,94.9 101.72,94.9 104.07,97.25 118.59,97.25 121.02,94.82 121.9,94.82 124.58,92.15 124.58,91.27 132.11,83.73 132.11,80.39 136.5,76 136.5,69.56 137.64,68.42 137.64,52.85 139.54,50.96 139.54,45.88 139.6,45.82 139.78,45.82 v2(139.97,46.01)
  BOTTOM w0.094: CC135.1 139.6,45.73 139.69,45.73 v2(139.97,46.01)
PCIE_PTX_C_LANRX_P6: length 154.5
  TOP w0.094: UL1.13 36.61,83.44 36.71,83.34 36.71,82.37 36.97,82.11 38.12,82.11 39.28,80.95 40.5,80.95 40.62,80.83 41.38,80.83 41.88,81.32 41.88,82.04 42.06,82.23 42.31,82.23 v2(42.5,82.04)
  IN1 w0.114: v2(140.06,45.29) 140.06,45.39 139.83,45.61 139.51,45.61 139.34,45.79 139.34,50.87 137.44,52.77 137.44,68.34 136.3,69.47 136.3,75.91 131.91,80.31 131.91,83.65 124.37,91.18 124.37,92.06 121.82,94.62 120.93,94.62 118.51,97.05 104.15,97.05 101.8,94.7 58.79,94.7 58.03,93.94 56.39,93.94 50.75,88.3 48.77,88.3 45.98,85.5 44.91,85.5 43.22,83.81 43.22,82.53 42.92,82.23 42.69,82.23 v2(42.5,82.04)
  BOTTOM w0.094: CC136.1 139.45,45.55 139.8,45.55 v2(140.06,45.29)
PCIE_PTX_C_WLANRX_N5: length 111.8
  IN3 w0.135: v2(140.91,41.7) 140.91,41.4 141.02,41.3 141.56,41.3 142.42,40.43 142.42,34.59 141.31,33.47 141.31,31.54 142.57,30.28 142.57,26.43 145.96,23.04 152.39,23.04 153.24,22.18 177.35,22.18 180.7,25.53 183.9,25.53 184.13,25.77 184.13,25.94 v2(183.82,26.25)
  BOTTOM w0.094: v2(183.82,26.25) 184.18,26.61 184.18,28.69 192.32,36.84 193.66,36.84 196.06,39.23 196.06,55.92 194.28,57.7 190.53,57.7 189.83,58.39 189.83,59.35 189.67,59.5 WLAN1.29 ; v2(140.91,41.7) 140.59,41.39 140.45,41.39 140.36,41.47 140.36,43.56 140.02,43.9 139.52,43.9 CC1815.1
PCIE_PTX_C_WLANRX_P5: length 111.8
  IN3 w0.135: v2(140.88,40.89) 141.05,41.05 141.45,41.05 142.18,40.33 142.18,34.69 141.06,33.58 141.06,31.44 142.33,30.17 142.33,26.33 145.86,22.79 152.29,22.79 153.14,21.94 177.45,21.94 180.8,25.29 184,25.29 184.37,25.66 184.37,26.03 v2(184.56,26.22)
  BOTTOM w0.094: v2(140.88,40.89) 140.56,41.21 140.37,41.21 140.18,41.4 140.18,43.48 139.94,43.72 139.52,43.72 CC1816.1 ; v2(184.56,26.22) 184.36,26.42 184.36,28.62 192.4,36.65 193.74,36.65 196.24,39.15 196.24,55.99 194.35,57.88 190.6,57.88 190.02,58.46 190.02,59.35 190.17,59.5 WLAN1.27
PCIE_PTX_LANRX_N6: length 5.2
  BOTTOM w0.076: 135.94,45.28 135.93,45.28 135.92,45.27 135.45,45.27 135.16,45.55 134.69,45.55 134.55,45.69 134.22,45.69 133.94,45.41 UC1.D20
  BOTTOM w0.094: CC135.2 137.9,45.81 137.69,45.81 137.16,45.28 135.94,45.28
PCIE_PTX_LANRX_P6: length 5.3
  BOTTOM w0.076: 135.94,45.09 135.93,45.09 135.92,45.1 135.38,45.1 135.09,45.39 134.74,45.39 134.66,45.3 134.66,45.16 134.61,45.11 134.17,45.11 134.11,45.17 134.11,45.33 134.18,45.41 UC1.C20
  BOTTOM w0.094: 135.94,45.09 137.23,45.09 137.76,45.62 137.9,45.62 CC136.2
PCIE_PTX_WLANRX_N5: length 5.4
  BOTTOM w0.076: UC1.C19 134.12,44.95 134.34,44.95 134.36,44.92 134.36,44.8 134.28,44.72 134.28,44.68 134.35,44.61 134.5,44.61 134.56,44.59 136.44,44.59 136.45,44.6 136.47,44.6
  BOTTOM w0.094: 136.47,44.6 137.06,44.6 137.84,43.82 138.2,43.82 138.26,43.88 CC1815.2
PCIE_PTX_WLANRX_P5: length 5.5
  BOTTOM w0.076: UC1.D19 133.96,44.45 134.47,44.45 134.54,44.42 136.44,44.42 136.45,44.42 136.47,44.42
  BOTTOM w0.094: 138.26,43.37 137.98,43.64 137.76,43.64 v3(137.26,44.14) 136.99,44.42 136.47,44.42
PCIE_RCOMPN: length 9.2
  IN3 w0.305: v2(132.14,36.99) 133.38,35.75 133.38,32.61 v2(134.37,31.62)
  BOTTOM w0.127: v1(134.19,29.47) 134.19,30.22 RC45.1
  BOTTOM w0.254: v2(132.14,36.99) 132.14,36.74 UC1.F5
  BOTTOM w0.305: v2(134.37,31.62) 134.55,31.44 RC45.1
PCIE_RCOMPP: length 9.2
  IN3 w0.305: v2(132.82,36.98) 133.82,35.98 133.82,33.17 v2(134.36,32.64)
  BOTTOM w0.076: 134.42,32.57 v2(134.36,32.64)
  BOTTOM w0.127: v1(135.74,29.52) 135.74,30.3 RC45.2
  BOTTOM w0.254: UC1.E5 132.59,36.76 v2(132.82,36.98)
  BOTTOM w0.305: 134.42,32.57 135.46,31.53 RC45.2
PCIE_WAKE#: length 186
  TOP w0.089: RC395.1 105.74,37.78 v2(106.43,37.78)
  TOP w0.094: RE354.2 34.12,38.69 34.34,38.91 UE1.4 34.34,41.67 34.17,41.84 v2(34.17,42.15) ; v2(50.87,82.72) v1(49.22,82.72) 46.09,82.72 44.12,84.68 44.12,85.07 RL1.2
  IN1 w0.114: v2(106.43,37.78) 106.32,37.67 102.35,37.67 99.97,35.29 99.97,31.29 96.43,27.76 96.43,26.18 95.8,25.55 91.2,25.55 86.86,21.2 69.12,21.2 68.48,21.84 67.85,21.84 65.73,23.96 65.73,26.37 63.78,28.32 57.39,28.32 56.29,29.42 56.29,31.28 55.73,31.83 55.22,31.83 54.92,32.14 54.92,39.14 53.87,40.18 53.87,43.08 53.08,43.87 53.08,81.26 51.62,82.72 v2(50.87,82.72) 49.93,82.72 46.05,78.84 45.6,78.84 42.99,76.23 42.99,65.39 39.72,62.11 39.72,59.89 41.2,58.4 41.2,57.87 39.46,56.12 39.46,52.39 37.87,50.81 37.87,45.8 35.87,43.79 35.87,43.04 35.28,42.45 34.47,42.45 v2(34.17,42.15)
PECI_EC: length 174.5
  TOP w0.102: RE353.2 30.7,61.06 v1(30.77,61.13) 30.97,61.32 v2(31.27,61.32)
  IN1 w0.114: v2(143.06,75.14) 140.67,77.53 140.67,93.45 134.73,99.39 104.43,99.39 101.18,96.15 55.5,96.15 49.61,90.25 46.74,90.25 45.53,89.05 45.53,88.12 41.42,84.01 41.24,84.01 37.29,80.06 37.29,78.42 34.52,75.65 34.52,74.05 34.04,73.57 33.76,73.57 31.88,71.69 31.55,71.69 30.99,71.13 30.99,61.6 v2(31.27,61.32)
  BOTTOM w0.102: UC1.A54 135.83,64.67 136.49,64 137.81,64 138.34,64.53 140.06,64.53 142.64,67.11 142.64,69.36 143.26,69.98 143.26,74.94 v2(143.06,75.14)
PECI_MEC1404: length 6.9
  TOP w0.102: UE1.94 33.94,56.5 34.55,57.11 34.55,57.72 34.17,58.1 v1(32.03,58.1) 31.7,58.1 RE353.1
PHASE_CHG: length 7.6
  IN3 w0.762: 171.42,46.93 171.53,46.82 171.53,46.12 171.71,45.94 171.71,41.9 171.02,41.22 171.02,39.76
  vias: v2(170.79,47.23) v2(170.77,39.05) v2(171.28,47.59) v2(171.38,39.05) v2(171.9,40.38) v2(171.9,39.78) v2(172.42,40.69) v2(172.42,40.09) v2(172.42,39.5) v2(172.42,38.91) v4(171.26,40.11)
PHASE_ID1: length 27.1
  BOTTOM w0.076: 108.69,32.75 108.69,34.49 110.77,36.57 110.77,37.15 111.91,38.29 113.59,38.29 UC1.BA8
  BOTTOM w0.102: RC372.2 103.86,18.32 104.35,18.8 RC373.1 v4(105.12,20.77) 105.12,21.72 105.82,22.42 105.82,24.27 106.33,24.77 106.33,26.78 107.18,27.63 107.18,29.73 108.1,30.66 108.1,31.96 108.69,32.54 108.69,32.75
PHASE_ID2: length 27.8
  BOTTOM w0.076: UC1.AY8 114.13,38.21 113.76,37.84 113.57,37.84 113.31,38.1 111.96,38.1 111.03,37.17 111.03,36.49 108.92,34.38 108.92,32.57
  BOTTOM w0.102: RC371.1 RC370.2 106.79,17.29 106.79,17.57 105.69,18.66 105.69,21.76 106.15,22.22 106.15,24.22 106.58,24.65 106.58,26.57 v1(107.17,27.16) 107.41,27.4 107.41,29.64 108.33,30.56 108.33,31.86 108.92,32.45 108.92,32.57
PLT_RST_NGFF#: length 2.9
  TOP w0.102: R5807.1 185.7,53.91 v2(185.92,54.13) 185.92,54.5 v1(185.7,54.72)
  BOTTOM w0.102: WLAN1.44 v2(185.92,54.13)
PM_MSM#: length 1.1
  TOP w0.089: v2(118.11,66.2) 117.78,66.53 T4949.1
  BOTTOM w0.076: v2(118.11,66.2) 117.75,65.84 UC1.AP56
PM_ZVM#: length 78.7
  TOP w0.102: v2(117.43,66.2) 117.03,66.2 115.66,67.57 114.57,67.57 113.69,68.44 113.69,72.74 113.16,73.27 113.16,75.15 112.32,75.99 112.32,79 115.94,82.62 115.94,86.86 115.4,87.41 v1(115.4,95.86) 115.4,97.19 118.42,100.21 123.85,100.21 124.29,99.77 v2(124.29,97.66)
  BOTTOM w0.076: UC1.AR56 117.43,66.13 v2(117.43,66.2)
  BOTTOM w0.102: PR1201.2 108.4,111.22 108.9,111.72 120.42,111.72 125.96,106.18 125.96,99.33 v2(124.29,97.66)
PME#: length 1.2
  TOP w0.089: v2(115.41,39.75) 115.78,39.38 T115.1
  BOTTOM w0.076: v2(115.41,39.75) 115.8,40.14 UC1.AU11
POK: length 315.1
  TOP w0.102: RC1139.1 RC220.1 CC266.1 97.64,15.6 97.63,15.59 UZ6.2 97.63,12.32 97.95,12 v2(97.95,11.49) ; v2(150.6,38.98) 150.82,39.2 161.71,39.2 165.62,43.12 v1(165.62,46.18) 165.62,52.58 167.32,54.27 v2(167.32,55.03)
  TOP w0.254: PR113.2 PR107.2 184.59,81.5 v2(184.56,81.53) ; v2(194.72,81.78) 196.5,83.56 196.5,88.07 200.12,91.69 PR13.1
  IN1 w0.114: v2(149.6,27.18) 149.95,27.54 149.95,34.78 150.6,35.43 v2(150.6,38.98)
  IN1 w0.254: v2(184.56,81.53) 184.56,81.97 188.31,85.72 195.23,85.72 195.74,85.21 195.74,82.8 v2(194.72,81.78)
  IN2 w0.127: v2(177.37,81.72) 179.66,81.72 180.45,82.51 181.25,82.51 182.22,81.53 v2(184.56,81.53) ; v2(177.67,56.1) 176.9,55.33 176.9,54.11 177.38,53.63 177.38,50.72 179.13,48.97 180.19,48.97 180.93,48.23 180.93,29.51 180.65,29.23 180.65,27.26 178.08,24.7 178.08,17.5 173.85,13.27 166.07,13.27 164.84,12.03 150.4,12.03 148.03,9.66 134.89,9.66 134.15,10.4 129.99,10.4 128.84,11.55 120.69,11.55 118.99,9.85 115.35,9.85 113.8,11.4 108.27,11.4 107.65,10.78 103.48,10.78 102.9,11.36 102.9,11.66 102.46,12.1 101.96,12.1 101.07,11.21 98.23,11.21 v2(97.95,11.49) 97.95,12.02 97.22,12.75 94.05,12.75 92.56,14.23 89.54,14.23 87.42,12.11 84.31,12.11 83.13,10.93 79.05,10.93 78.91,11.07 58.1,11.07 56.56,12.61 55.62,12.61 54.83,13.39 53.78,13.39 v2(53.14,12.76)
  BOTTOM w0.102: v2(177.37,81.72) 177.14,81.49 177.14,75.52 175.19,73.57 175.19,64.49 176.13,63.55 176.13,57.64 v2(177.67,56.1) 177.25,55.68 172.91,55.68 172.26,55.03 v2(167.32,55.03) ; v2(53.14,12.76) 53.71,12.18 PR501.1
  BOTTOM w0.254: PU100.9 182.66,81.53 182.91,81.78 184.31,81.78 v2(184.56,81.53) ; PU102.9 193.71,81.47 194.02,81.78 v2(194.72,81.78) ; PR301.1 v2(149.6,27.18)
POWER_SW#_MB: length 307.9
  TOP w0.102: RE428.2 v1(25.36,35.78) 24.97,36.17 v2(24.97,36.46)
  IN1 w0.114: v2(203.73,45.56) 201.04,45.56 195.36,51.24 195.36,60.2 200.8,65.65 200.8,84.41 202.25,85.86 202.25,97.8 199.9,100.15 193.37,100.15 193.01,99.79 191.32,99.79 190.57,99.03 139.76,99.03 138.83,99.97 135.36,99.97 135.1,100.23 104.06,100.23 101.25,97.42 75.2,97.42 73.88,98.74 v2(70.58,98.74) 69.68,98.74 67.92,96.98 53.2,96.98 52.06,95.85 50.44,95.85 50.06,96.22 47.81,96.22 47.21,95.62 47.21,91.91 44.69,89.39 44.69,88.48 41.06,84.85 40.89,84.85 35.5,79.45 35.5,78.65 31.39,74.53 31.39,72.02 30.72,71.35 30.72,61.04 32.46,59.29 35.86,59.29 37.52,57.63 37.52,56.87 34.22,53.57 34.22,46.85 31.17,43.8 31.17,41.77 28.13,38.73 28.13,37.42 27.67,36.96 26.94,36.96 26.74,36.76 26.3,36.76 26.14,36.91 25.43,36.91 v2(24.97,36.46)
  BOTTOM w0.102: SW1.4 70.16,98.32 v2(70.58,98.74) 71.53,99.69 72.72,99.69 SW1.3 ; JIO1.30 204.13,45.16 v2(203.73,45.56)
POWER_SW_IN#: length 9.6
  TOP w0.102: UE1.127 30.69,41.82 30.15,41.28 30.15,39.78 v1(29.98,39.61) 29.89,39.52 29.89,37.87 29.18,37.16 C6218.2 28.78,36.89 RE31.2 RE428.1
PROG: length 3.3
  TOP w0.203: PU703.9 175.94,50.78 176.03,50.86 177.17,50.86 177.56,51.25 v1(177.68,51.25) 177.86,51.43 178.46,51.43 PR753.2
PROH: length 5.8
  TOP w0.203: 180.43,47.81 180.24,48 179.09,48 178.64,47.56 PR777.2 178.18,47.89 178.18,47.99 177.5,48.67 PU703.5
  TOP w0.254: PQ720.2 v1(180.49,47.77) 180.49,47.81 180.48,47.81 180.43,47.81
PROJECT_ID: length 26.4
  BOTTOM w0.076: UC1.BA7 113.25,37.59 112.93,37.91 112.04,37.91 111.28,37.14 111.28,36.51 109.15,34.37 109.15,32.57
  BOTTOM w0.102: RC377.1 RC376.2 107.01,17.29 107.01,17.67 105.92,18.76 105.92,21.67 106.38,22.13 106.38,24.12 107.03,24.77 v4(107.03,25.17) 107.03,26.51 107.64,27.12 107.64,29.54 108.56,30.47 108.56,31.77 109.15,32.35 109.15,32.57
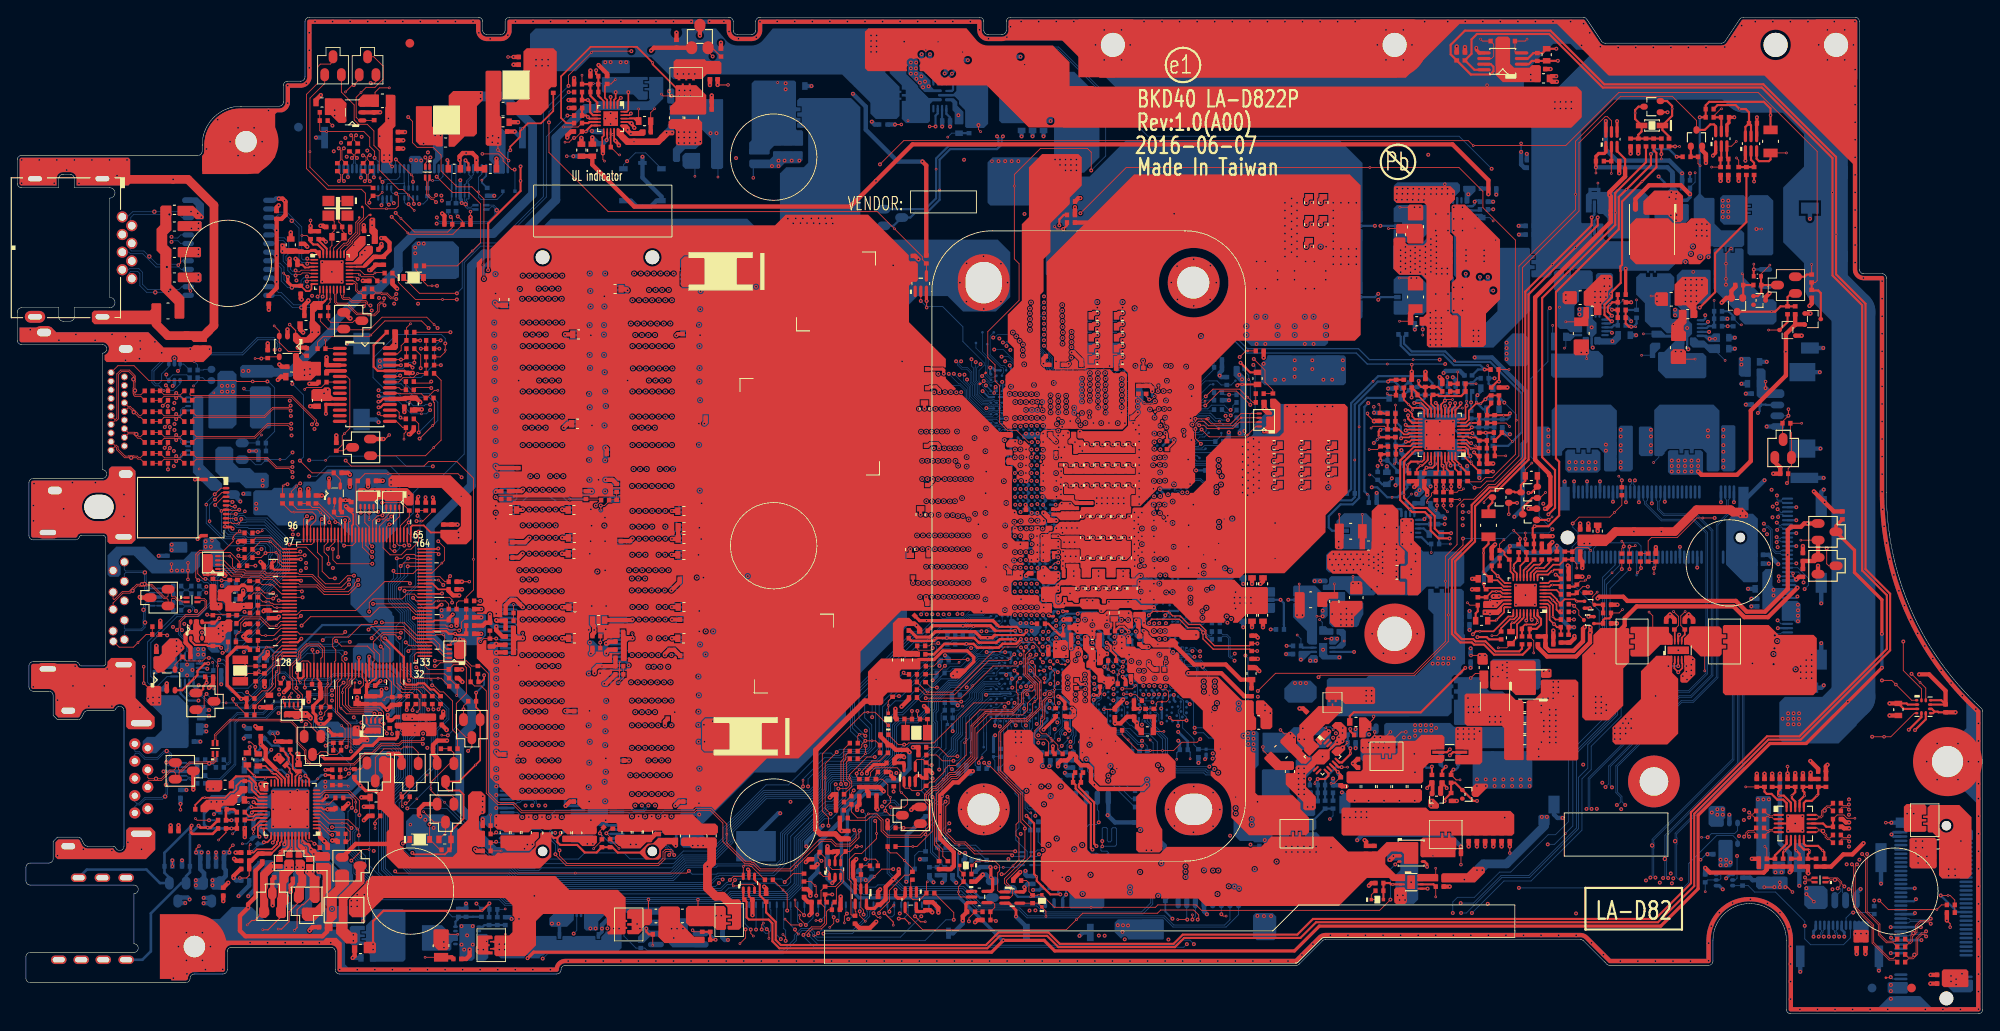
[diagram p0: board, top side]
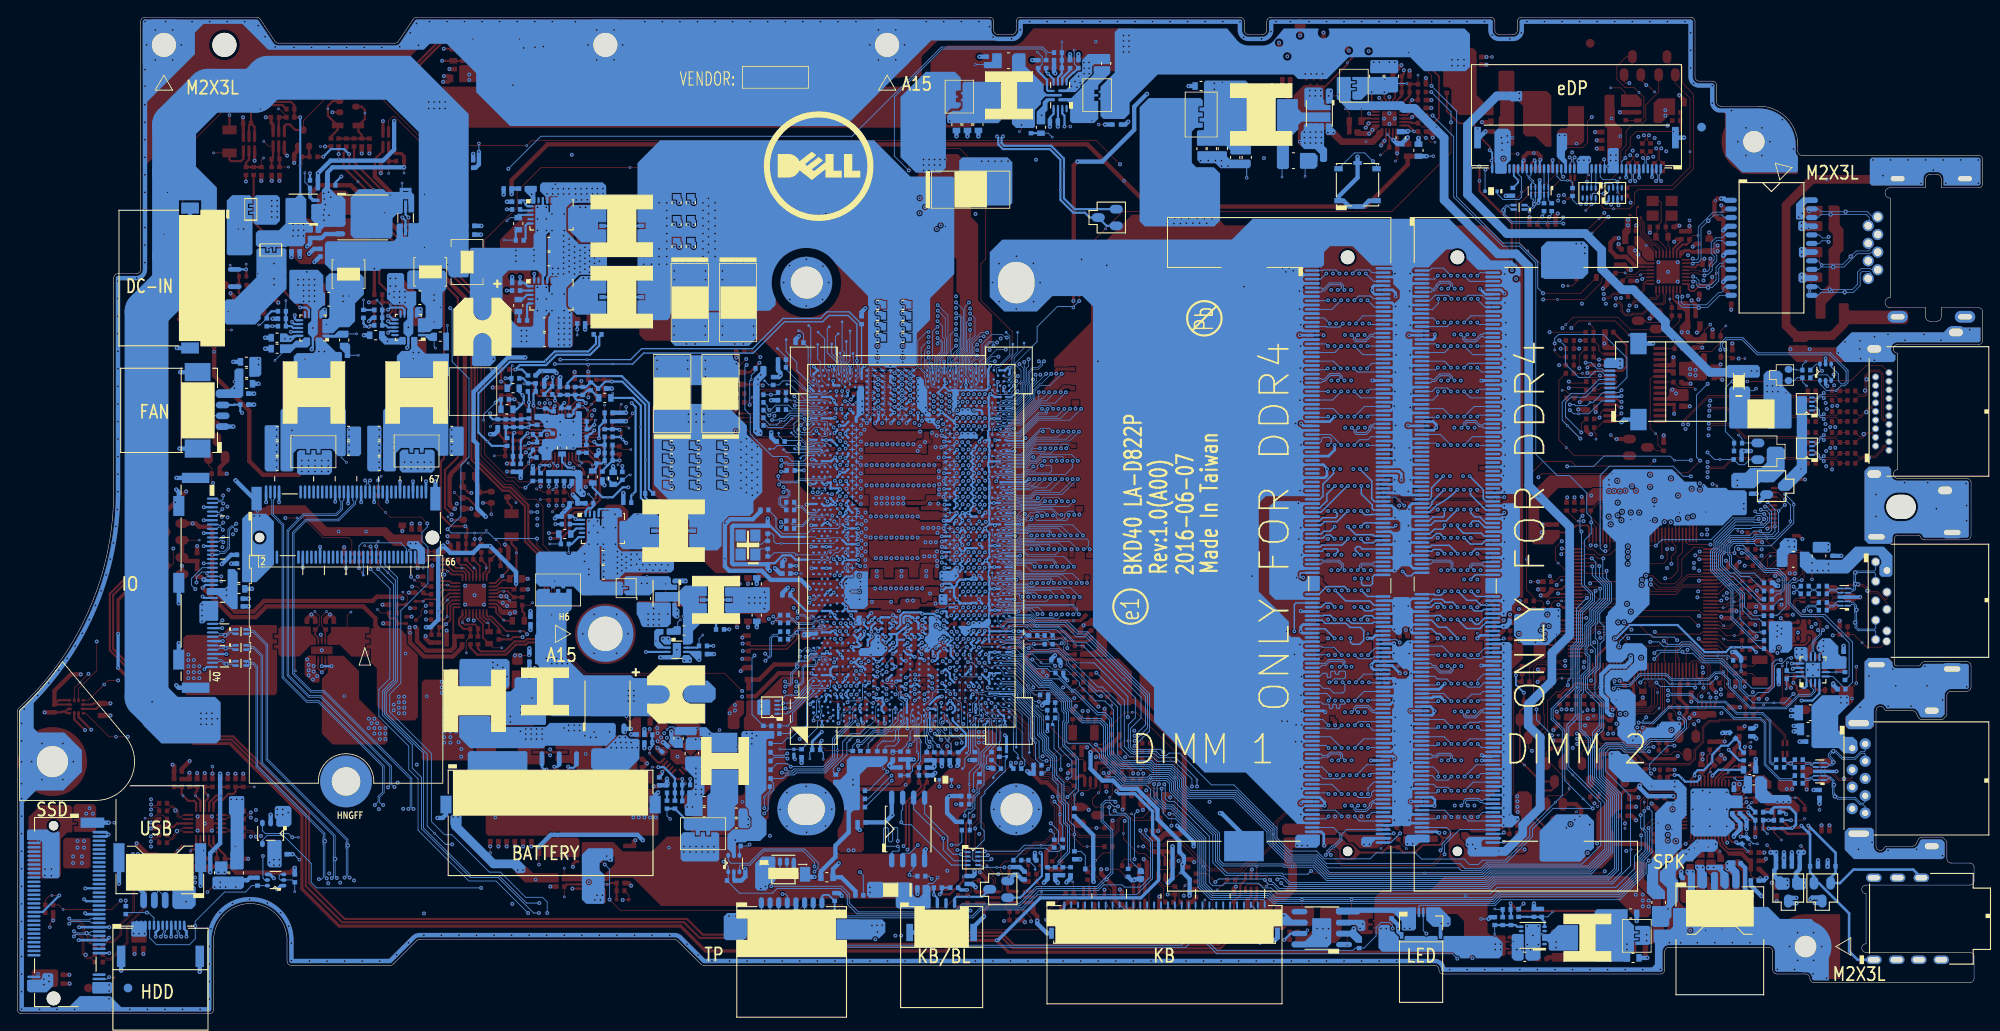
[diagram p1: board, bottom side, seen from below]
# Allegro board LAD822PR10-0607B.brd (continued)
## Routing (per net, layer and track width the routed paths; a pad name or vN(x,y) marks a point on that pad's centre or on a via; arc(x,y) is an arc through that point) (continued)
PS_ID: length 276.5
  TOP w0.102: v2(99.84,98.37) 102.59,101.11 167.94,101.11 v1(168.51,100.54) 179.2,100.54 185.35,106.69 201.49,106.69 208.31,99.87 208.31,84.89 208.11,84.69 PR4.2 ; v2(44.96,43.01) 45.35,42.62 UE1.36
  TOP w0.254: PR4.2 PR3.1 207.75,83.75 208.44,83.75 208.73,83.46 PD5.1
  IN3 w0.135: v2(44.96,43.01) 45.24,43.01 46.33,44.1 46.33,53.91 43.87,56.37 43.87,66.92 42.85,67.94 42.85,80.43 41.68,81.6 41.68,82.08 41.09,82.67 41.09,84.22 43.61,86.74 43.61,90.91 44.43,91.73 44.43,95.71 43.29,96.85 41.98,96.85 41.13,95.99 37.01,95.99 35.86,97.15 35.86,100.27 38.38,102.8 55.07,102.8 61.09,96.78 98.26,96.78 v2(99.84,98.37)
PSID: length 2.7
  TOP w0.102: v2(200.98,86.2) v1(200.98,86.81)
  TOP w0.254: v2(200.98,86.2) 200.96,86.18 PL2.2
  BOTTOM w0.254: PJPDC1.3 v2(200.98,86.2)
PSID-1: length 4
  TOP w0.102: PR9.2 199.75,85.58 v1(199.63,85.69)
  TOP w0.254: PR6.1 PR9.2 199.75,82.96 PQ5.2
PSID-2: length 9.1
  TOP w0.254: PR11.1 204.07,81.92 203.44,81.3 v1(203.05,81.3) PQ5.1 ; PR11.1 PR8.2 ; PR11.1 204.88,82.99 205.31,83.42 PQ6.2
PSID-3: length 3.2
  TOP w0.102: v1(207.67,86.77) PR4.1
  TOP w0.254: PR4.1 207.12,85.61 206.86,85.35 PQ6.3
PTP_DIS#: length 66.9
  TOP w0.102: v2(32.74,61.42) 32.66,61.42 v1(32.34,61.11) 31.72,60.49 RE434.1 ; v2(44.63,19.72) 44.95,19.72 D3801.1 ; RE436.1 25.81,52.83 v2(25.59,53.04)
  IN2 w0.127: v2(32.74,61.42) 33.25,60.92 33.25,59.86 32.6,59.21 32.6,57.35 34.43,55.53 37.98,55.53 38.87,54.64 38.87,53.14 36.27,50.55 36.27,38.95 41.3,33.92 41.3,31.73 42.42,30.61 42.42,29.37 43.89,27.9 43.89,23.3 44.83,22.36 44.83,19.92 v2(44.63,19.72)
  IN3 w0.135: v2(32.74,61.42) 28.13,56.81 27.54,56.81 26.06,55.34 26.06,53.51 v2(25.59,53.04)
PTP_DIS#_R: length 6.7
  TOP w0.102: RE434.2 32.44,58.38 34.74,58.38 v1(35.11,58) 35.67,57.45 35.67,56.65 35.54,56.52 UE1.90
PWM1_GT: length 19.6
  TOP w0.203: PU602.12 166.04,69.98 166.41,70.35 v2(166.41,70.72)
  IN3 w0.254: v2(166.41,70.72) 166.41,71.83 167.54,72.96 167.54,74.54 167.09,74.99 167.09,79.67 169.28,81.86 v2(169.28,85.33)
  BOTTOM w0.254: PU605.1 168.39,84.25 168.79,84.64 PR680.1 v2(169.28,85.33)
PWM2_GT: length 27.9
  TOP w0.203: PU602.13 165.64,70.12 165.82,70.31 v2(165.82,70.69)
  IN3 w0.254: v2(165.82,70.69) 165.82,72 167.03,73.21 167.03,74.29 166.59,74.74 166.59,79.87 168.67,81.96 v2(168.67,94.04)
  BOTTOM w0.254: PR681.1 169.13,94.19 168.82,94.19 v2(168.67,94.04) 168.67,93.75 168.45,93.52 PU604.1
PWM_IA: length 16.9
  TOP w0.254: PU602.22 161.44,68.44 160.96,68.92 v2(160.96,69.3)
  IN3 w0.254: v2(162.85,57.29) 160.54,59.6 160.54,64.78 161.45,65.68 161.45,68.82 v2(160.96,69.3)
  BOTTOM w0.254: PU603.1 162.76,57.2 v2(162.85,57.29) 163.15,57.59 PR662.1
PWM_VSA: length 39.1
  TOP w0.203: 161.45,64.89 161.8,65.24 PU602.30
  TOP w0.254: 161.45,64.89 160.49,63.94 v1(160.49,60.15) 160.49,59.75 161.67,58.57 163.13,58.57 164.05,57.65 164.05,56.19 164.58,55.66 v2(165.94,55.66)
  IN3 w0.254: v2(165.94,55.66) 166.3,55.3 166.3,52.98 162.6,49.28 156.58,49.28 155.32,48.03 155.32,42.51 v2(154.71,41.9)
  BOTTOM w0.254: PU606.3 v2(154.71,41.9)
RESERVE_ID1: length 6.6
  BOTTOM w0.076: UC1.AB3 123.98,35.05 123.98,34.81 124.1,34.69 124.1,33.71 123.79,33.4 123.79,33.02 124.14,32.67 124.14,32.57
  BOTTOM w0.102: 124.14,32.57 v1(124.14,31.96) 124.14,31.69 124.51,31.33 124.51,31.16 125.25,30.41 RC374.2 RC375.1
RESERVE_ID2: length 8.1
  BOTTOM w0.102: UC1.AC1 123.35,34.04 123.35,30.32 v1(123.26,30.23) 123.16,30.12 123.16,29.4 123.85,28.7 123.85,28.11 RC1129.2 RC1128.1
RESET_OUT#: length 131.1
  TOP w0.102: v2(46.32,57.67) CE82.1 RE367.1 ; UE1.73 42.34,53.96 43.15,53.14 44.43,53.14 45.09,53.8 45.57,53.8 46.44,54.68 v2(46.44,55.84)
  BOTTOM w0.076: 104.46,42.61 104.88,42.61 106.96,44.7 109.82,44.7 110.43,45.31 112.88,45.31 UC1.BA20
  BOTTOM w0.102: 104.46,42.61 104.1,42.61 98.07,36.58 98.07,34.27 98.89,33.46 98.89,30.82 98.45,30.39 95.66,30.39 95.17,29.89 94.48,29.89 94.19,30.18 92.95,30.18 89.27,26.5 86.67,26.5 81.69,21.52 81.69,20.38 80.15,18.84 77.09,18.84 76.19,17.94 70.89,17.94 70.21,18.63 65.66,18.63 64.95,17.91 60.02,17.91 59.39,17.28 58.37,17.28 57.87,17.79 55.22,17.79 52.42,20.59 52.42,21.52 v1(49.44,24.49) 48.66,25.28 48.66,32.81 49.95,34.1 49.95,35.3 47.43,37.83 47.43,42.4 46.79,43.04 46.79,46.57 45.39,47.96 45.39,48.63 46.44,49.68 v2(46.44,55.84) 46.61,56.01 46.61,57.37 v2(46.32,57.67)
RING2: length 4.6
  TOP w0.203: UA1.17 32.19,27.49 32.54,27.85 LA10.2 32.19,28.07 31.88,28.38 31.88,29.85 31.59,30.14 RA1109.1
RING2_R: length 46.6
  TOP w0.127: v4(21.03,19.43) 20.69,19.08 v2(20.69,18.68)
  IN1 w1.016: 19.78,15.12 18.29,15.12 15.14,11.97 15.14,5.01 14.82,4.69 5.74,4.69 4.8,5.64 JHP.4
  IN2 w1.016: 21.16,17.81 22.28,16.7 25.09,16.7 26.19,17.8 26.19,19.11 25.43,19.87 25.43,20.86 26.19,21.62 26.19,26.09 28.29,28.19 30.64,28.19 31.46,29.01
  vias: v2(20.67,15.46) v2(20.67,14.88) v2(21.33,18.68) v2(32.41,30.09) v2(32.41,29.46)
RJ45_MIDI0+: length 8
  BOTTOM w0.089: JRJ45.1 12.75,92.28 13.35,92.88 v3(15.87,92.88) 18.71,92.88 19.03,93.2 TL1.23
RJ45_MIDI0-: length 7.9
  BOTTOM w0.089: JRJ45.2 13.13,91.38 13.13,92.22 13.48,92.57 v3(17.61,92.57) 18.71,92.57 19.08,92.2 TL1.22
RJ45_MIDI1+: length 8.3
  IN3 w0.102: JRJ45.3 13.86,90.24 14.52,89.58 16.04,89.58 16.27,89.81 17.69,89.81 v2(17.85,89.97)
  BOTTOM w0.089: v2(17.85,89.97) 17.98,89.83 18.56,89.83 18.92,90.2 TL1.20
RJ45_MIDI1-: length 8.3
  IN3 w0.102: JRJ45.6 14.2,88.13 14.2,88.97 14.56,89.33 16.15,89.33 16.37,89.56 17.68,89.56 v2(17.85,89.38)
  BOTTOM w0.089: v2(17.85,89.38) 17.98,89.52 18.6,89.52 18.91,89.2 TL1.19
RJ45_MIDI2+: length 8.4
  BOTTOM w0.089: TL1.17 19.07,87.2 18.67,86.8 16.19,86.8 v3(15.28,87.7) 14.65,88.34 13.22,88.34 13.05,88.51 13.05,89.02 JRJ45.4
RJ45_MIDI2-: length 8.5
  BOTTOM w0.089: JRJ45.5 12.9,88.2 13.09,88.02 14.52,88.02 16.05,86.48 v3(17.31,86.48) 18.69,86.48 18.97,86.2 TL1.16
RJ45_MIDI3+: length 9.6
  BOTTOM w0.089: JRJ45.7 12.87,86.16 13,86.29 14.07,86.29 14.51,85.85 14.51,84.45 15.1,83.86 v3(17.71,83.86) 18.71,83.86 19.05,84.2 TL1.14
RJ45_MIDI3-: length 9.7
  BOTTOM w0.089: JRJ45.8 12.94,85.45 12.94,85.78 13.13,85.97 13.94,85.97 14.19,85.72 14.19,84.32 14.97,83.54 v3(15.97,83.54) 18.74,83.54 19.08,83.2 TL1.13
RTC_DET#: length 161.7
  TOP w0.102: Q2505.1 209.65,51.87 209.41,52.11 v2(209.41,53.88)
  IN1 w0.114: v2(209.41,53.88) 209.41,53.5 216.97,45.94 216.97,43.18 219.66,40.49 219.66,39.14 219.33,38.81 218.04,38.81 215.61,36.38 215.61,21.39 217.37,19.64 217.37,12.81 215.62,11.06 211.41,11.06 208.94,13.53 208.94,15.96 207.49,17.41 203.01,17.41 202.28,16.68 196.94,16.68 195.95,17.67 194.44,17.67 194.14,17.98 163.2,17.98 162.36,17.13 160.51,17.13 160.24,16.86 157.96,16.86 157.84,16.74 155.31,16.74 154.59,16.02 145.74,16.02 143.74,18.02 143,18.02 140.82,20.2 134.51,20.2 132.48,22.22 132.48,22.4 132.24,22.64 132.24,28.13 v2(132.41,28.3)
  BOTTOM w0.076: 129.24,32.57 128.8,33.01 128.24,33.01 127.83,33.43 UC1.P1
  BOTTOM w0.102: v2(132.41,28.3) 132.41,28.03 RC384.1 133.04,27.99 133.04,28.39 131.46,29.97 131.46,31.37 v1(131.12,31.71) 130.71,32.12 129.7,32.12 129.24,32.57
RTC_PWR: length 6.8
  TOP w0.102: D2501.3 v1(206.42,54.85)
  TOP w0.508: D2501.3 Q2505.2 208,52.43 R2504.1 R2502.2
RTCRST_ON: length 88.3
  TOP w0.102: R1902.1 v2(102.57,21.52) 104.02,21.52 Q1901.2 ; UE1.31 45.14,38.81 v2(45.35,38.6)
  IN2 w0.127: v2(102.57,21.52) 101.1,22.99 99.61,22.99 97.22,25.38 96.63,25.38 96.37,25.64 94.82,25.64 94.47,25.99 92.45,25.99 84.92,18.46 82.73,18.46 80.13,15.86 79.53,15.86 78.64,14.97 59.81,14.97 58.18,16.59 57.75,16.59 56.79,17.56 52.62,17.56 51.18,19 51.18,25.34 52.71,26.87 52.71,30.77 52.09,31.39 52.09,33.86 49.01,36.94 47,36.94 v2(45.35,38.6)
RUNPWROK: length 3.7
  TOP w0.102: UE1.48 48.03,47.42 48.42,47.81 v1(48.73,47.81) 49.56,47.81 49.93,47.44 RE438.1
SA_SNUB: length 1.3
  TOP w0.102: PC622.1 v1(152.43,49.78)
SA_SW: length 1.8
  TOP w0.102: PR627.1 v1(148.36,49.77)
  vias: v2(148.11,46.16) v2(148.75,46.16)
SATA3_PRX_C_SSDTX_N2: length 8.6
  TOP w0.094: CHD2.2 218.85,8.11 219.09,8.11 219.34,8.36 219.34,8.91 219.87,9.44 219.87,10.17 220.33,10.63 221.25,10.63 v2(221.45,10.43)
  BOTTOM w0.094: v2(221.45,10.43) 221.2,10.68 219.07,10.68 218.92,10.53 JSSD1.43
SATA3_PRX_C_SSDTX_P2: length 8.6
  TOP w0.094: v2(221.45,11.01) 221.26,10.82 220.25,10.82 219.68,10.24 219.68,9.57 v3(219.45,9.33) 219.15,9.04 219.15,8.43 219.01,8.29 218.85,8.29 CHD1.2
  BOTTOM w0.094: JSSD1.41 218.93,11.03 219.09,10.87 221.31,10.87 v2(221.45,11.01)
SATA3_PRX_HDDTX_N0: length 93.7
  TOP w0.094: v2(199.85,20.51) 200.05,20.71 200.05,20.95 200.32,21.22 200.94,21.22 CS33.1
  IN1 w0.076: v2(132.17,45.23) 132.38,45.23 132.48,45.13 132.48,44.88 132.66,44.7 133.14,44.7 133.29,44.7 133.32,44.73 133.35,44.73 133.36,44.74
  IN1 w0.114: 133.36,44.74 133.37,44.75 133.74,44.75 135.09,43.4 135.09,41.4 136.05,40.44 137.23,40.44 139.88,37.8 139.88,35.15 138.97,34.24 138.97,31 139.44,30.53 139.44,29.61 140.44,28.61 140.44,26.99 141.63,25.8 141.63,24.66 142.05,24.24 142.05,24.06 145.54,20.57 151.6,20.57 152.69,19.48 156.72,19.48 158.55,21.31 178.34,21.31 181.22,24.19 183.01,24.19 186.13,21.06 199.91,21.06 200.04,20.93 200.04,20.7 v2(199.85,20.51)
  BOTTOM w0.076: UC1.F20 v2(132.17,45.23)
SATA3_PRX_HDDTX_P0: length 93.7
  TOP w0.094: v2(200.44,20.51) 200.24,20.71 200.24,20.87 200.4,21.03 201.06,21.03 201.25,20.84 CS35.1
  IN1 w0.076: 133.21,44.88 133.19,44.86 132.73,44.86 132.65,44.95 132.65,45.13 132.75,45.23 v2(132.94,45.23)
  IN1 w0.114: v2(200.44,20.51) 200.25,20.7 200.25,21.01 199.99,21.27 186.22,21.27 183.09,24.39 181.13,24.39 178.26,21.52 158.47,21.52 156.63,19.68 152.78,19.68 151.68,20.77 145.62,20.77 142.25,24.14 142.25,24.32 141.83,24.74 141.83,25.88 140.64,27.08 140.64,28.69 139.64,29.69 139.64,30.61 139.17,31.08 139.17,34.15 140.08,35.06 140.08,37.88 137.31,40.65 136.13,40.65 135.3,41.48 135.3,43.48 133.82,44.95 133.28,44.95 133.21,44.88
  BOTTOM w0.076: UC1.E20 v2(132.94,45.23)
SATA3_PRX_SSDTX_N2: length 127.7
  TOP w0.094: CHD2.1 217.12,8.22 216.31,8.22 215.39,9.14 215.39,10.31 213.91,11.79 213.91,18.1 v2(213.51,18.5)
  IN1 w0.114: v2(213.51,18.5) 213.78,18.78 213.78,18.91 213.67,19.02 213,19.02 212.71,18.73 211.52,18.73 210.33,19.92 204.54,19.92 200.22,24.24 194.77,24.24 193.55,23.02 188.79,23.02 184.42,27.39 182.78,27.39 181.69,26.3 178.24,26.3 175.21,23.27 157.87,23.27 156.36,21.76 153.05,21.76 152.36,22.45 146.39,22.45 144,24.84 144,24.93 143.5,25.43 143.5,26.64 142.38,27.76 142.38,29.3 141.3,30.38 141.3,31.3 140.83,31.77 140.83,33.24 142.52,34.93 142.52,37.79 138.69,41.62 138.69,49.57 138.17,50.1 136.94,50.1 136.09,50.95 133.52,50.95 133.18,51.29 132.79,51.29 132.68,51.18 132.68,50.97 v2(132.88,50.77)
  BOTTOM w0.076: UC1.E30 132.59,51.06 v2(132.88,50.77)
SATA3_PRX_SSDTX_P2: length 127.8
  TOP w0.094: v2(214.09,18.5) 214.09,11.87 215.57,10.38 215.57,9.22 216.39,8.4 217.34,8.4 CHD1.1
  IN1 w0.114: v2(214.09,18.5) 213.99,18.6 213.99,18.99 213.76,19.22 212.92,19.22 212.63,18.93 211.61,18.93 210.41,20.12 204.63,20.12 200.31,24.44 194.69,24.44 193.47,23.22 188.87,23.22 184.5,27.59 182.69,27.59 181.6,26.5 178.15,26.5 175.12,23.47 157.78,23.47 156.27,21.96 153.14,21.96 152.45,22.65 146.47,22.65 144.2,24.92 144.2,25.02 143.7,25.52 143.7,26.73 142.59,27.84 142.59,29.39 141.51,30.47 141.51,31.39 141.04,31.86 141.04,33.15 142.73,34.84 142.73,37.87 138.9,41.7 138.9,49.66 138.26,50.3 137.02,50.3 136.17,51.15 133.61,51.15 133.26,51.49 132.71,51.49 132.48,51.26 132.48,50.97 v2(132.27,50.77)
  BOTTOM w0.076: v2(132.27,50.77) 132.27,50.84 UC1.F30
SATA3_PTX_C_SSDRX_N2: length 7.9
  TOP w0.094: v2(220.91,9.54) 220.74,9.37 220.38,9.37 219.76,8.75 219.76,7.01 v3(219.57,6.82) 219.29,6.55 218.81,6.55 CHD3.2
  BOTTOM w0.094: v2(220.91,9.54) 220.73,9.35 219.09,9.35 218.92,9.53 JSSD1.47
SATA3_PTX_C_SSDRX_P2: length 8
  TOP w0.094: v2(220.91,8.96) 220.69,9.19 220.46,9.19 219.94,8.67 219.94,6.89 219.42,6.37 218.88,6.37 CHD4.2
  BOTTOM w0.094: JSSD1.49 218.93,9.03 219.07,9.17 220.7,9.17 v2(220.91,8.96)
SATA3_PTX_HDDRX_N0: length 91.8
  TOP w0.094: CS36.1 200.86,22.92 200.64,22.92 v2(200.44,22.72)
  IN1 w0.114: v2(200.44,22.72) 200.24,22.91 199.38,22.91 198.87,22.4 188.53,22.4 185.32,25.6 178.58,25.6 175.62,22.65 158.12,22.65 156.62,21.14 152.79,21.14 152.12,21.81 146.14,21.81 143.37,24.58 143.37,24.68 142.87,25.18 142.87,26.38 141.76,27.5 141.76,29.04 140.68,30.12 140.68,31.05 140.21,31.52 140.21,33.51 141.88,35.17 141.88,37.56 138.02,41.41 138.02,45.89 137.79,46.12 137.44,46.12 v2(137.16,45.85)
  BOTTOM w0.076: v2(137.16,45.85) 136.94,46.07 136.44,46.07 136.09,45.72 135.17,45.72 UC1.B21
SATA3_PTX_HDDRX_P0: length 91.9
  TOP w0.094: v2(200.44,23.31) 200.64,23.11 200.86,23.11 CS37.1
  IN1 w0.114: v2(137.16,46.6) 137.44,46.33 137.87,46.33 138.22,45.98 138.22,41.49 142.08,37.64 142.08,35.09 140.41,33.43 140.41,31.6 140.88,31.13 140.88,30.21 141.96,29.13 141.96,27.58 143.08,26.47 143.08,25.26 143.58,24.76 143.58,24.67 146.23,22.02 152.2,22.02 152.88,21.34 156.53,21.34 158.04,22.85 175.54,22.85 178.5,25.81 185.4,25.81 188.61,22.6 198.78,22.6 199.3,23.12 200.24,23.12 v2(200.44,23.31)
  BOTTOM w0.076: UC1.A21 135.31,46.04 135.43,46.16 135.58,46.16 135.63,46.12 135.63,45.92 135.67,45.88 136.02,45.88 136.37,46.23 137.2,46.23 137.31,46.34 137.31,46.45 v2(137.16,46.6)
SATA3_PTX_SSDRX_N2: length 119.4
  TOP w0.094: v2(212.92,17.31) 212.72,17.1 212.72,12.42 214.85,10.28 214.85,8.26 216.71,6.4 217.12,6.4 CHD3.1
  IN1 w0.114: v2(135.78,48.19) 135.95,48.01 136.31,48.01 136.6,47.72 136.6,45.09 137.6,44.1 137.6,41.24 140.7,38.14 140.7,34.68 139.79,33.77 139.79,31.34 140.26,30.87 140.26,29.95 141.33,28.88 141.33,27.27 142.46,26.14 142.46,25 142.91,24.55 142.91,24.36 145.88,21.39 151.94,21.39 152.62,20.72 156.79,20.72 158.3,22.23 177.26,22.23 180.16,25.13 183.4,25.13 186.56,21.97 201.67,21.97 204.14,19.5 210.09,19.5 211.47,18.12 212.27,18.12 212.54,17.85 212.54,17.69 v2(212.92,17.31)
  BOTTOM w0.076: UC1.A25 135.16,48.45 135.07,48.36 135.07,48.2 135.26,48.01 135.61,48.01 v2(135.78,48.19)
SATA3_PTX_SSDRX_P2: length 119.5
  TOP w0.094: v2(212.33,17.31) 212.53,17.1 212.53,12.34 214.67,10.21 214.67,8.19 216.64,6.22 217.34,6.22 CHD4.1
  IN1 w0.114: v2(212.33,17.31) 212.33,17.77 212.19,17.91 211.39,17.91 210,19.3 204.05,19.3 201.59,21.76 186.48,21.76 183.32,24.93 180.24,24.93 177.34,22.02 158.38,22.02 156.87,20.51 152.53,20.51 151.86,21.19 145.79,21.19 142.71,24.28 142.71,24.46 142.25,24.92 142.25,26.06 141.13,27.18 141.13,28.8 140.06,29.87 140.06,30.79 139.59,31.26 139.59,33.85 140.5,34.76 140.5,38.05 137.4,41.15 137.4,44.01 136.4,45.01 136.4,47.63 136.22,47.81 135.99,47.81 v2(135.78,47.6)
  BOTTOM w0.076: UC1.B25 134.81,48.45 134.91,48.35 134.91,48.13 135.19,47.85 135.53,47.85 v2(135.78,47.6)
SATA_ARX_RC_DTX_N0: length 3.2
  TOP w0.094: US2.12 208.29,21.53 208.45,21.37 208.78,21.37 v3(208.99,21.16) 209.42,20.74 209.42,20.51 209.58,20.34 209.78,20.34 CS31.1
SATA_ARX_RC_DTX_N0_C: length 16.3
  TOP w0.094: CS31.2 211.34,20.41 211.88,20.41 v2(212.01,20.54)
  IN3 w0.135: v2(210.27,8.93) 210.41,9.07 210.41,11.42 209.32,12.5 209.32,18.45 211.31,20.43 211.9,20.43 v2(212.01,20.54)
  BOTTOM w0.094: v2(210.27,8.93) 210.47,9.13 210.47,9.26 210.31,9.42 210.31,9.62 210.15,9.77 HDD1.8
SATA_ARX_RC_DTX_P0: length 3.2
  TOP w0.094: CS34.1 209.78,20.16 209.5,20.16 209.23,20.43 209.23,20.66 209.09,20.8 209.04,20.8 208.65,21.19 208.43,21.19 208.27,21.03 US2.11
SATA_ARX_RC_DTX_P0_C: length 16.2
  TOP w0.094: v2(212.01,19.96) 211.74,20.23 211.15,20.23 211.05,20.13 CS34.2
  IN3 w0.135: v2(212.01,19.96) 211.78,20.19 211.41,20.19 209.57,18.35 209.57,12.61 210.65,11.52 210.65,9.12 v2(210.85,8.93)
  BOTTOM w0.094: v2(210.85,8.93) 210.65,9.13 210.65,9.34 210.49,9.5 210.49,9.61 210.65,9.77 HDD1.7
SATA_ATX_RC_DRX_N0: length 3.5
  TOP w0.094: US2.14 208.29,22.53 208.45,22.69 208.78,22.69 208.98,22.89 208.98,23.35 v3(209.17,23.53) 209.51,23.88 209.75,23.88 CS32.1
SATA_ATX_RC_DRX_N0_C: length 20.4
  TOP w0.094: v2(211.99,23.64) 211.71,23.92 211.17,23.92 211.05,23.81 CS32.2
  IN3 w0.135: v2(209.07,8.93) 208.87,9.13 208.87,11.38 208.43,11.82 208.43,21.42 210.87,23.86 211.77,23.86 v2(211.99,23.64)
  BOTTOM w0.094: v2(209.07,8.93) 208.87,9.13 208.87,9.32 208.99,9.44 208.99,9.63 209.15,9.79 HDD1.10
SATA_ATX_RC_DRX_P0: length 3.5
  TOP w0.094: CS30.1 209.82,24.06 209.43,24.06 209.26,23.89 209.22,23.89 208.8,23.48 208.8,22.96 208.71,22.87 208.43,22.87 208.27,23.03 US2.15
SATA_ATX_RC_DRX_P0_C: length 20.4
  TOP w0.094: CS30.2 211.33,24.11 211.86,24.11 v2(211.99,24.23)
  IN3 w0.135: v2(211.99,24.23) 211.86,24.1 210.76,24.1 208.18,21.52 208.18,11.71 208.62,11.28 208.62,9.06 v2(208.49,8.93)
  BOTTOM w0.094: v2(208.49,8.93) 208.69,9.13 208.69,9.39 208.81,9.51 208.81,9.66 208.65,9.81 HDD1.11
SATA_CRX_C_DTX_N0: length 2
  TOP w0.094: CS33.2 202.48,21.2 202.65,21.2 202.8,21.35 203.13,21.35 203.31,21.53 US2.4
SATA_CRX_C_DTX_P0: length 2
  TOP w0.094: CS35.2 202.16,20.58 202.6,21.02 202.73,21.02 202.87,21.17 203.15,21.17 203.29,21.03 US2.5
SATA_CTX_C_DRX_N0: length 2
  TOP w0.094: CS36.2 202.48,22.85 202.66,22.85 202.78,22.73 203.1,22.73 203.3,22.53 US2.2
SATA_CTX_C_DRX_P0: length 2
  TOP w0.094: US2.1 203.25,23.03 203.13,22.91 202.86,22.91 202.73,23.04 202.61,23.04 CS37.2
SATA_LED#: length 199
  TOP w0.102: R2405.1 48.99,35.49 v2(48.75,35.25) ; v2(21.91,37.03) 21.63,36.76 21.63,35.49 21.35,35.21 Q6105.3
  IN2 w0.127: v2(38.01,41.09) 38.74,40.37 42.17,40.37 44.02,38.51 44.02,37.65 45.9,35.77 48.23,35.77 v2(48.75,35.25)
  IN3 w0.135: v2(137.96,28.62) 137.96,26.64 139.63,24.97 139.63,22.16 138.82,21.35 138.82,17.79 137.96,16.94 137.96,15.87 129.81,7.72 58.9,7.72 57.9,6.72 51.35,6.72 50.69,7.38 50.69,11.18 48.94,12.94 46.51,12.94 40.61,18.85 40.61,22.75 38.84,24.52 38.84,26.19 37.27,27.77 37.27,28.82 35.73,30.36 35.4,30.36 35.01,30.75 35.01,31.93 34.45,32.49 34.45,34.37 34.24,34.58 34.24,36.94 34.57,37.27 34.57,41.56 34.75,41.74 v2(34.75,41.92)
  BOTTOM w0.102: v2(21.91,37.03) 22.94,36 v1(24.17,36) 26.59,36 28.2,37.61 28.2,38.5 30.34,40.63 32.44,40.63 33.54,41.74 34.57,41.74 v2(34.75,41.92) 34.8,41.87 37.24,41.87 v2(38.01,41.09) ; RC248.1 139.58,28.96 138.31,28.96 v2(137.96,28.62) 134.21,28.62 133.11,29.71 133.11,31.9 131.14,33.87 UC1.H1
SATA_LED_EN: length 39.2
  TOP w0.254: R6110.2 21.91,38.86 v2(21.91,38.34) 21.52,37.94 21.52,37.59 21.07,37.14 Q6105.2 ; v2(42.57,43.47) 44.74,41.31 UE1.30 44.74,38.44 45.06,38.11 46.23,38.11 46.37,38.26 47.1,38.26 47.81,37.55 48.21,37.55 R2405.2
  IN2 w0.254: v2(21.91,38.34) 22.91,38.34 24.29,39.71 24.29,41.36 24.81,41.89 v2(26.22,41.89)
  BOTTOM w0.254: v2(42.57,43.47) 42.4,43.47 40.85,45.02 35.31,45.02 32.17,41.88 29.73,41.88 29.18,42.44 v1(27.92,42.44) 26.78,42.44 v2(26.22,41.89)
SD_RCOMP: length 1.7
  TOP w0.089: RC96.1 122.72,37.59 v2(123.61,37.59)
  BOTTOM w0.076: UC1.AB7 123.93,37.27 v2(123.61,37.59)
SDVO_SCLK: length 236.4
  IN1 w0.114: v2(129.81,40.66) 129.56,40.92 129.56,40.92 129.56,41.11 129.75,41.3 130.98,41.3 132.35,39.92 133.66,39.92 137.12,36.47 137.12,35.71 137.54,35.29 137.54,30.04 137.88,29.71 138.17,29.71 v2(138.34,29.55) ; v2(30.38,76.89) 30.38,76.09 29.71,75.43 29.71,60.47 31,59.18 31,53.84 32.82,52.01 33.23,52.01 v2(33.42,52.2)
  IN3 w0.135: v2(138.34,29.55) 138.49,29.7 138.71,29.7 138.92,29.49 138.92,28.63 139.54,28.01 139.54,25.44 139.9,25.08 139.9,22.05 139.08,21.24 139.08,17.8 139.45,17.43 139.45,16.36 138.79,15.69 138.16,15.69 134.13,11.66 134.13,10.84 130.76,7.46 59.03,7.46 58.03,6.46 51.24,6.46 50.43,7.27 50.43,11.07 48.99,12.51 46.15,12.51 37.58,21.08 37.58,26.25 36.97,26.86 36.97,28.55 36.1,29.42 35.08,29.42 34.43,30.07 34.43,31.21 32.4,33.24 32.4,34.61 33.25,35.47 33.25,36.67 34.19,37.61 34.19,40.87 33.58,41.47 33.58,42.43 34.4,43.24 34.4,51.75 34.04,52.1 33.52,52.1 v2(33.42,52.2)
  BOTTOM w0.076: v2(129.81,40.66) 129.81,40.7 UC1.L13
  BOTTOM w0.102: QX4.1 18.84,72.95 18.05,72.16 v1(16.97,72.16) 16.42,72.72 15.96,72.72 15.59,73.09 15.59,74.52 17.61,76.54 26,76.54 27.75,78.29 29.73,78.29 30.38,77.65 v2(30.38,76.89) ; v2(138.34,29.55) 138.43,29.55 138.58,29.7 139.86,29.7 RC175.1
SDVO_SDATA: length 236.4
  IN1 w0.114: v2(29.79,76.89) 30.13,76.55 30.13,76.19 29.47,75.53 29.47,60.37 30.76,59.08 30.76,53.74 32.72,51.77 33.27,51.77 v2(33.42,51.62) ; v2(128.94,40.84) 129.14,40.84 129.31,41.02 129.31,41.21 129.65,41.54 131.08,41.54 132.45,40.17 133.76,40.17 137.36,36.57 137.36,35.81 137.79,35.39 137.79,30.14 137.98,29.95 138.17,29.95 v2(138.36,30.14)
  IN3 w0.135: v2(138.36,30.14) 138.54,29.96 138.82,29.96 139.18,29.6 139.18,28.73 139.8,28.12 139.8,25.55 140.16,25.19 140.16,21.95 139.34,21.13 139.34,17.91 139.71,17.54 139.71,16.25 138.9,15.43 138.27,15.43 134.39,11.55 134.39,10.73 130.86,7.2 59.14,7.2 58.14,6.2 51.13,6.2 50.17,7.16 50.17,10.96 48.88,12.25 46.04,12.25 37.32,20.97 37.32,26.14 36.71,26.75 36.71,28.44 35.99,29.16 34.97,29.16 34.17,29.97 34.17,31.1 32.13,33.13 32.13,34.72 32.99,35.57 32.99,36.78 33.93,37.72 33.93,40.76 33.32,41.37 33.32,42.53 34.13,43.35 34.13,51.64 33.93,51.84 33.64,51.84 v2(33.42,51.62)
  BOTTOM w0.076: v2(128.94,40.84) 129.27,40.52 UC1.L12
  BOTTOM w0.102: v2(29.79,76.89) 30.15,77.25 30.15,77.55 29.64,78.06 27.85,78.06 26.1,76.31 17.7,76.31 15.82,74.42 15.82,73.18 16.06,72.94 16.36,72.94 16.71,73.29 16.71,74.09 17.54,74.92 QX4.4 ; RC178.1 139.93,29.93 138.66,29.93 138.45,30.14 v2(138.36,30.14)
SERIRQ: length 143.4
  TOP w0.102: RC21.2 104.6,36.14 109.24,36.14 v2(109.24,36.15) ; UE1.55 v1(48.74,50.22) v2(49.3,49.65) ; RZ126.1 v2(50.13,78.93)
  IN1 w0.076: v2(109.24,36.15) 105.29,36.15
  IN1 w0.114: 105.29,36.15 101.83,36.15 100.45,34.77 100.45,28.59 98.57,26.7 98.57,26.08 96.06,23.56 93.96,23.56 93.62,23.23 91.07,23.23 88.28,20.44 69.36,20.44 68.99,20.06 67.66,20.06 66.62,21.1 65.47,21.1 64.42,22.15 64.42,25.01 62.91,26.51 58.16,26.51 54.18,30.48 54.18,37.86 52.7,39.34 51.29,39.34 50.37,40.26 50.37,41.8 49.42,42.74 49.42,45.33 49.62,45.53 49.62,48.84 49.3,49.16 v2(49.3,49.65) 50.13,49.65 50.52,50.05 50.52,56.93 51.01,57.42 51.01,78.04 v2(50.13,78.93)
  BOTTOM w0.076: UC1.AY11 113.89,40.07 113.38,39.56 113.38,39.24 113.25,39.11 112.23,39.11 110.21,37.09 110.21,36.66 109.7,36.15 v2(109.24,36.15)
SIO_EXT_SCI#: length 162
  TOP w0.102: v2(45.37,54.25) 45.14,54.48 UE1.66
  IN1 w0.114: 126.41,37.8 126.19,38.02 126.19,38.62 125.15,39.65 121.08,39.65 119.64,38.21 v2(119.56,38.21) ; 126.41,37.8 126.41,36.01 127.87,34.55 129.72,34.55 130.17,34.11 v2(130.17,33.47) ; 126.41,37.8 126.76,38.16 128.17,38.16 128.43,37.9 129.44,37.9 129.89,38.35 133.81,38.35 136.18,35.98 136.18,35.52 136.94,34.76 136.94,32.51 136.48,32.05 136.48,29.88 137.3,29.05 138.45,29.05 139.4,28.1 139.4,26.56 140.59,25.37 140.59,24.23 v2(141.01,23.81)
  IN2 w0.127: v2(45.37,54.25) 48.03,51.58 48.03,45.07 50.37,42.73 51.34,42.73 53.17,40.9 53.17,38.92 54.37,37.71 54.37,32.42 55.03,31.76 55.71,31.76 56.21,31.25 56.21,29.6 57.12,28.7 57.12,20.46 58.7,18.88 59.13,18.88 60.45,17.56 76.61,17.56 77.25,18.19 79.23,18.19 81.78,20.75 82.26,20.75 89.7,28.19 92.74,28.19 94.01,29.46 98.4,29.46 98.98,28.87 99.61,28.87 101.02,30.28 101.02,33.22 101.95,34.15 111.14,34.15 111.71,34.71 117.49,34.71 118.37,35.59 118.37,37.02 v2(119.56,38.21)
  BOTTOM w0.076: v2(130.17,33.47) 130.17,34.02 130.48,34.33 UC1.J2
  BOTTOM w0.102: v2(141.01,23.81) v1(141.01,25.09) 141.01,25.17 140.36,25.81 RC237.1
SIO_EXT_SMI#: length 143.1
  TOP w0.102: v2(41.51,45.32) 41.28,45.09 39.83,45.09 38.36,43.62 36.73,43.62 36.5,43.39 36.5,42.5 36.86,42.15 36.86,40.9 36.74,40.78 UE1.10
  IN3 w0.135: v2(128.42,35.99) 128.42,35.65 127.43,34.66 127.43,33.43 126.81,32.81 126.81,29.76 126.08,29.02 126.08,28.53 126.58,28.02 v2(126.77,28.02) 126.77,26.91 125.37,25.5 125.37,25.22 121.04,20.89 121.04,19.89 116.81,15.65 115.96,15.65 115.68,15.37 109.38,15.37 108.88,15.88 105.17,15.88 103.31,17.74 99.65,17.74 99.31,17.4 93.68,17.4 93.1,16.82 91.08,16.82 90.42,17.48 87.88,17.48 85.34,14.94 83.03,14.94 82.63,14.53 79.09,14.53 78.71,14.16 76.53,14.16 76.08,14.61 58.91,14.61 57.79,15.73 57.24,15.73 55.61,17.36 54.58,17.36 53.42,18.52 52.89,18.52 51.36,20.05 51.36,25.46 47.89,28.93 46.69,28.93 44.83,30.79 44.83,33.42 43.9,34.35 43.9,35.5 42.97,36.43 41.92,36.43 41.09,37.26 41.09,39.17 41.94,40.01 41.94,42.04 41.48,42.5 41.48,45.3 v2(41.51,45.32)
  BOTTOM w0.076: v2(128.42,35.99) 128.71,35.99 UC1.L6
  BOTTOM w0.102: RC239.2 128.96,25.84 v2(126.77,28.02) 127.14,28.39 v1(127.25,28.39)
SIO_EXT_WAKE#: length 129.6
  TOP w0.102: v2(45.44,49.84) 45.24,50.05 42.52,50.05 39.17,46.69 32.85,46.69 32.37,46.22 UE1.116
  IN2 w0.127: v2(120.88,31.02) 120.35,30.49 110.58,30.49 109.79,31.28 103.48,31.28 100.32,28.11 98.67,28.11 98.08,28.7 94.33,28.7 93.06,27.43 90.02,27.43 82.58,19.98 82.1,19.98 79.5,17.38 77.51,17.38 76.93,16.79 60.14,16.79 58.81,18.12 58.38,18.12 58.11,18.39 58.11,18.39 56.29,20.21 56.29,27.26 55.76,27.8 54.94,27.8 54.41,28.33 54.41,31.3 53.61,32.1 53.61,37.3 52.2,38.71 52.2,40.17 50.64,41.73 49.55,41.73 46.76,44.51 46.76,48.52 v2(45.44,49.84)
  BOTTOM w0.076: UC1.AD3 122.52,35.06 122.23,34.77 122.23,34.33 122.1,34.06 122.1,32.64 122.04,32.57
  BOTTOM w0.102: 122.04,32.57 122.04,32.38 v1(121.61,31.95) 121.53,31.87 121.53,31.66 v2(120.88,31.02) 120.46,30.6 RC387.1
SIO_PWRBTN#: length 125.6
  TOP w0.089: RC1102.2 106.07,40.25 106.85,41.03 v2(110,41.03)
  TOP w0.102: UE1.52 46.19,49.02 46.18,49.03 44.86,49.03 v2(44.81,48.98)
  BOTTOM w0.076: UC1.BA15 113.17,42.43 112.89,42.15 112.49,42.15 112.32,42.33 111.96,42.33 111.36,41.73 111.02,41.73 110.32,41.03 v2(110,41.03) 109.21,40.24 107.98,40.24 107.65,39.91 106.09,39.91 104.55,38.37
  BOTTOM w0.102: v2(44.81,48.98) 44.94,48.85 44.94,47.77 46.33,46.38 46.33,42.85 46.93,42.25 46.93,37.67 47.16,37.45 47.16,34.43 48.14,33.45 48.14,28.35 v1(47.43,27.65) 44.2,24.42 44.2,19.52 46.39,17.33 57.32,17.33 58.08,16.57 60.35,16.57 60.68,16.9 75.79,16.9 77.05,18.16 80.18,18.16 82.15,20.13 82.15,21.33 86.45,25.64 91.76,25.64 92.51,26.39 92.51,27.29 93.84,28.62 95.81,28.62 96.27,29.07 99.49,29.07 100.61,30.19 100.61,35.24 101.6,36.23 102.7,36.23 104.55,38.08 104.55,38.37
SIO_RCIN#: length 122.6
  TOP w0.102: v2(44.28,49.23) 44.46,49.42 UE1.53
  BOTTOM w0.076: 111.48,41.56 111.95,41.56 111.97,41.53 112.34,41.53 112.45,41.64 112.83,41.64 112.86,41.62 112.94,41.59 113.06,41.59 113.28,41.65 113.42,41.65 113.58,41.6 113.66,41.6 114.13,41.45 UC1.AW13
  BOTTOM w0.102: 111.48,41.56 111.1,41.56 109.5,39.96 108.26,39.96 107.95,39.66 107.51,39.66 RC13.2 106.87,39.02 106.87,39.02 105.44,37.59 105.1,37.59 102.39,34.88 101.55,34.88 100.84,34.17 100.84,30.1 99.59,28.84 96.36,28.84 95.9,28.39 93.93,28.39 92.74,27.2 92.74,26.29 91.86,25.41 86.55,25.41 82.38,21.24 82.38,20.03 80.27,17.93 77.14,17.93 75.56,16.34 57.98,16.34 57.22,17.1 45.71,17.1 43.74,19.07 43.74,24.43 47.91,28.59 47.91,33.21 v1(47.31,33.81) 46.93,34.19 46.93,37.35 46.7,37.58 46.7,42.15 46.05,42.8 46.05,45.04 45.47,45.63 45.47,46.9 44.28,48.09 v2(44.28,49.23)
SIO_SLP_A#: length 1.3
  TOP w0.089: T4975.1 118.27,43.11 v2(117.96,43.42)
  BOTTOM w0.102: UC1.AN16 v2(117.96,43.42)
SIO_SLP_LAN#: length 43.3
  TOP w0.089: v2(116.17,42.42) 116.5,42.09 T4938.1
  TOP w0.102: T4938.1 116.5,39.26 117.7,38.06 117.7,37.6 117.46,37.37 116.73,37.37 116.42,37.06 116.42,35.96 115.27,34.81 112.09,34.81 110.6,33.32 110.6,29.72 108.57,27.7 107.96,27.7 106.37,26.1 106,26.1 105.22,25.33 105.22,24.78 105.68,24.33 105.68,21.51 104.61,20.44 100.7,20.44 99.97,21.17 99.97,22.34 99.53,22.79 98.7,22.79 98.31,22.4 96.38,22.4 RC68.1
  BOTTOM w0.076: v2(116.17,42.42) 116.17,42.42 116.17,42.41 116.11,42.48 UC1.AW15
SIO_SLP_S0#: length 185.5
  TOP w0.102: v2(47.61,79.41) 46.78,80.23 42.55,80.23 v1(40.92,78.6) 40.73,78.42 35.4,78.42 34.75,77.77 RZ116.1 ; UC15.2 114.93,13.46 115.2,13.73 115.2,14.5 114.49,15.2 114.49,15.46 117.31,18.28 117.31,21.52 116.37,22.47 116.37,25.54 113.82,28.09 113.82,32.58 115.05,33.8 116.89,33.8 118.49,35.4 118.49,38.57 117.85,39.21 117.85,40.32 v2(117.44,40.73)
  IN3 w0.135: v2(117.44,40.73) 116.76,40.73 116.25,40.22 114.61,40.22 106.94,32.55 106.94,31.6 104.54,29.19 100.72,29.19 98.63,27.1 96.87,27.1 96.38,27.59 89.64,27.59 82.37,20.31 70.52,20.31 69.83,19.62 67.73,19.62 67.06,18.95 65.58,18.95 64.67,19.86 61.65,19.86 60.72,20.79 58.68,20.79 56.98,22.5 56.98,31.83 55.93,32.88 54.82,32.88 53.31,34.38 53.31,36.25 52.66,36.91 52.66,40.71 51.04,42.33 50.58,42.33 49.81,43.1 49.81,45.08 50.17,45.44 50.39,45.44 50.88,45.93 50.88,47.95 50.4,48.43 50.4,49.18 50.75,49.54 50.75,52 50.24,52.51 50.24,61.35 49.69,61.91 49.69,72.23 47.61,74.31 v2(47.61,79.41)
  BOTTOM w0.102: v2(117.44,40.73) 117.4,40.7 116.95,40.7 UC1.AT11
SIO_SLP_S3#: length 455.3
  TOP w0.102: UE1.23 41.94,41.59 41.21,42.32 41.21,43.07 42.27,44.13 v2(44.4,44.13) ; CE74.1 46.94,57.06 v1(46.79,57.06) v2(46.21,57.06) ; v2(117.93,41.59) 117.55,41.2 117.26,41.2 117.07,41.01 117.07,40.51 117.66,39.92 117.66,39.05 118.3,38.42 118.3,35.48 116.81,33.99 114.97,33.99 113.59,32.62 113.59,28 116.14,25.45 116.14,22.19 116.61,21.71 v2(116.61,21.46) 116.61,18.02 114.27,15.67 114.27,15.11 114.96,14.41 114.96,14.21 114.86,14.11 UC15.1 113.62,14.11 113.47,14.26 113.47,16.33 113.68,16.54 113.68,17.13 113.13,17.68 110.98,17.68 DZ1702.1 110.43,17.13 RC130.1
  TOP w0.203: UZ2.5 192.63,40.62 192.7,40.55 192.7,40.03 v2(192.23,39.56) 191.77,40.01 191.77,40.56 191.83,40.62 UZ2.3
  IN1 w0.114: v2(192.23,39.56) 192.23,38.39 192.46,38.16 196.37,38.16 198.35,40.14 198.35,47.91 195.11,51.14 195.11,60.3 200.56,65.75 200.56,84.51 202,85.96 202,97.7 199.8,99.91 193.72,99.91 192.6,98.79 171.58,98.79 v2(170.64,97.85) ; v2(180.4,11.62) 169.14,11.62 167.77,10.24 167.75,10.24 167.68,10.18 150.19,10.18 148.65,8.64 139.95,8.64 136.84,11.75 129.66,11.75 125.4,16.01 125.4,19.49 124.64,20.25 123.22,20.25 122.19,21.28 120.42,21.28 118.22,23.49 117.69,23.49 117.31,23.11 117.31,22.16 v2(116.61,21.46) 116.08,21.46 115.69,21.06 115.69,20.35 116.21,19.83 116.21,17.75 115.55,17.09 114.57,17.09 112.54,19.11 106.44,19.11 104.35,17.03 103.05,17.03 102.3,16.27 91.11,16.27 89.63,14.79 88.4,14.79 88.06,15.13 86.27,15.13 85.62,14.48 79.63,14.48 79.34,14.19 67,14.19 66.59,14.59 60.35,14.59 56.8,18.14 54.83,18.14 51.25,21.72 51.25,23.47 46.53,28.19 46.53,31.64 45.52,32.65 45.52,33.74 44.5,34.76 44.5,36.5 44.71,36.71 44.71,39.14 43.73,40.12 43.73,42.39 44.16,42.82 44.16,42.82 44.73,43.39 44.73,43.8 v2(44.4,44.13) 44.16,44.37 44.16,46.01 43.16,47.02 43.16,49.61 44.56,51.01 45.06,51.01 45.67,51.62 45.67,52.98 45.08,53.58 44.73,53.58 44.35,53.96 44.35,54.39 45.19,55.23 45.19,56.04 v2(46.21,57.06)
  IN2 w0.127: v2(192.23,39.56) 192.23,36.46 182.88,27.11 182.88,26.11 181.03,24.25 181.03,12.25 v2(180.4,11.62)
  BOTTOM w0.102: v2(170.64,97.85) 166.87,101.62 130.85,101.62 120.52,111.95 108.81,111.95 108.16,111.31 PR1204.2 ; v2(117.93,41.59) 117.93,41.73 117.75,41.91 UC1.AP15
SIO_SLP_S4#: length 317.1
  TOP w0.102: v2(157.41,13.18) 157.37,13.22 DZ1703.1 156.71,13.76 RZ1701.1 ; UE1.67 44.74,56.33 v2(45.3,56.9) ; PR201.1 v2(63.67,104.02)
  IN2 w0.127: v2(157.41,13.18) 157.38,13.15 150.8,13.15 147.84,10.19 139.96,10.19 138.21,11.95 133.29,11.95 132.31,10.97 129.78,10.97 128.94,11.81 120.2,11.81 118.86,10.47 115.09,10.47 113.66,11.91 107.53,11.91 106.91,11.29 v2(104.63,11.29)
  IN3 w0.135: v2(45.14,23.78) 45.14,21.29 47.12,19.31 47.12,18.09 51.43,13.79 52.31,13.79 52.64,13.46 52.64,12.57 52.94,12.28 53.29,12.28 54.62,10.95 56.03,10.95 57.14,9.84 63.33,9.84 63.98,10.48 68.01,10.48 68.29,10.21 v2(68.29,9.88)
  BOTTOM w0.076: 103.41,38.22 105.82,40.63 105.82,40.95 106.96,42.1 107.79,42.1 107.92,41.97 110.56,41.97 111.62,43.03 113.63,43.03 UC1.BA16
  BOTTOM w0.102: v2(63.67,104.02) 61.23,101.58 61.23,94.58 55.54,88.89 53.62,88.89 51.73,87 51.73,64.82 49.24,62.33 47.85,62.33 45.83,60.31 45.83,58 45.3,57.48 v2(45.3,56.9) 45.3,55.62 46.1,54.82 46.1,49.66 45.16,48.72 45.16,47.87 46.56,46.47 46.56,42.94 47.16,42.34 47.16,37.77 49.72,35.21 49.72,34.2 48.37,32.84 48.37,27.01 v1(46.24,24.89) v2(45.14,23.78) 49.71,23.78 52.1,21.39 52.1,20.52 55.06,17.56 57.41,17.56 58.17,16.8 59.9,16.8 60.48,17.38 75.95,17.38 76.96,18.38 80.01,18.38 81.92,20.29 81.92,21.43 86.36,25.86 91.67,25.86 92.28,26.48 92.28,27.38 93.74,28.84 95.71,28.84 96.17,29.3 99.4,29.3 100.15,30.05 100.15,35.53 102.01,37.4 102.58,37.4 103.41,38.22 ; v2(68.29,9.88) 68.29,10.21 68.66,10.57 69.62,10.57 70.21,9.99 70.21,9 71.61,7.6 PR803.1 72.62,7.6 72.88,7.35 88.65,7.35 89.93,8.63 89.93,9.09 90.71,9.86 91.85,9.86 92.27,9.44 92.27,9.16 92.56,8.87 102.21,8.87 v2(104.63,11.29)
SIO_SLP_S5#: length 144.2
  TOP w0.102: v1(177.63,57.54) 177.28,57.19 v2(177.21,57.19)
  TOP w0.254: PQ711.2 v2(177.21,57.19)
  IN1 w0.114: v2(110.39,42.35) 110.5,42.35 111.14,41.71 111.14,32.42 112.85,30.71 115.61,30.71 116.28,30.04 121.22,30.04 122.58,28.67 122.58,27.86 126.85,23.59 126.85,21.86 127.71,21 127.71,18.07 131.23,14.56 139.48,14.56 141.63,12.4 169.86,12.4 v2(170.18,12.73)
  IN2 w0.127: v2(170.18,12.73) 173.67,12.73 178.34,17.39 178.34,24.26 181.23,27.16 v2(181.23,28.85)
  IN3 w0.135: v2(177.21,57.19) 177.28,57.12 178.6,57.12 179.4,56.32 180.31,56.32 180.7,55.93 181.77,55.93 183.8,53.89 183.8,44.33 181.94,42.48 181.94,29.56 v2(181.23,28.85)
  BOTTOM w0.076: UC1.AY16 114.16,43.2 113.97,43.2 113.8,43.37 113.51,43.37 113.33,43.19 111.55,43.19 110.75,42.39 110.44,42.39 v2(110.39,42.35)
SIO_SLP_SUS#: length 125.8
  TOP w0.102: v2(33.53,57.61) 33.48,57.61 33.14,57.27 UE1.96 ; RC76.2 100.73,18.94 101.04,18.63 101.79,18.63 v1(102.67,17.75) 103.6,16.82 RC1137.1 103.2,16.05 102.7,16.05 100.93,14.28 100.93,13 99.74,11.81 v2(99.74,11.65)
  IN2 w0.127: v2(99.74,11.65) 99.29,12.1 98.93,12.1 97.88,13.15 94.12,13.15 92.79,14.49 89.44,14.49 87.32,12.36 84.2,12.36 83.66,11.82 80.7,11.82 80.2,11.32 58.2,11.32 56.63,12.9 55.82,12.9 54.92,13.8 50.96,13.8 47.25,17.51 46.16,17.51 45.24,18.42 45.24,18.83 45.83,19.41 45.83,22.49 44.4,23.91 44.4,29.68 42.09,31.99 42.09,32.77 42.47,33.15 43.05,33.15 43.56,33.67 43.56,35.77 43.11,36.23 41.81,36.23 40.65,37.39 39.24,37.39 38.66,37.97 38.66,39.07 36.83,40.89 36.83,41.97 37.65,42.79 37.65,43.75 37.49,43.9 37.49,46.44 37.7,46.64 37.7,50.66 39.65,52.61 39.65,54.99 38.36,56.29 34.7,56.29 33.53,57.45 v2(33.53,57.61)
SIO_SLP_SUS#_R: length 36.5
  TOP w0.102: RC76.1 v1(103.65,19.36) 104.13,19.36 105.91,21.15 105.91,24.42 105.45,24.88 105.45,25.23 106.1,25.87 106.47,25.87 108.06,27.47 108.67,27.47 110.83,29.63 110.83,33.09 112.36,34.62 116.36,34.62 116.93,35.19 116.93,35.97 117.89,36.93 117.89,38.13 116.69,39.34 116.69,41.6 v2(117.57,42.48)
  BOTTOM w0.076: UC1.AN15 117.96,42.48 117.57,42.48 117.57,42.48 v2(117.57,42.48)
SIO_SLP_WLAN#: length 1.5
  BOTTOM w0.076: T4945.1 111.55,43.57 111.61,43.63 UC1.BB17
SLEEVE: length 4.6
  TOP w0.203: RA53.1 31.06,30.17 31.06,30.03 31.42,29.66 31.42,29.17 LA7.2 31.52,28.38 v1(31.52,28) 31.79,27.74 UA1.18
SM_RCOMP0: length 15.5
  TOP w0.254: v2(116.8,44.35) 116.8,44.2 116.44,43.85 113.13,43.85
  TOP w0.381: RC5.1 103.31,44.38 104.07,43.62 105.62,43.62 106.24,44.24 110.85,44.24 111.53,43.56 v4(112.3,43.56) 112.84,43.56 113.13,43.85
  BOTTOM w0.254: UC1.AR18 116.8,44.17 v2(116.8,44.35)
SM_RCOMP1: length 13.6
  TOP w0.254: v2(116.1,44.32) 116.1,44.37 115.66,44.81 113.64,44.81 113.47,44.97
  TOP w0.381: 113.47,44.97 112.92,45.52 v1(105.24,45.52) 104.43,45.52 RC6.1
  BOTTOM w0.254: UC1.AT18 116.45,43.97 116.1,44.32 v2(116.1,44.32)
SM_RCOMP2: length 11.2
  TOP w0.254: 113.19,44.36 v2(115.48,44.36)
  TOP w0.381: 113.19,44.36 112.61,44.94 v4(109.44,44.94) 105.96,44.94 RC7.1
  BOTTOM w0.254: UC1.AU18 115.48,44.18 v2(115.48,44.36)
SMBCLK: length 46
  IN1 w0.114: v2(126.26,27) 126.26,25.55 127.82,23.99 127.82,22.26 128.67,21.4 128.67,19.71 131.73,16.66 135,16.66 v2(135.21,16.45)
  IN3 w0.135: v2(126.88,36.99) 127.33,36.54 127.33,35.7 126.29,34.66 126.29,29.97 125.55,29.24 125.55,27.72 126.26,27.01 v2(126.26,27)
  BOTTOM w0.076: v2(126.88,36.99) UC1.R7
  BOTTOM w0.102: RC12.1 129.32,23.93 v2(126.26,27) ; v2(135.21,16.45) 134.79,16.87 134.79,17.52 136.34,19.07 141.13,19.07 142.77,17.43 144.86,17.43 145.19,17.76 QC2.6
SMBDATA: length 43.5
  IN1 w0.114: v2(135.21,17.05) 135.07,16.91 131.81,16.91 128.91,19.81 128.91,21.5 128.06,22.36 128.06,24.09 126.67,25.48 126.67,27.2 v2(126.29,27.58)
  IN3 w0.135: v2(126.29,27.58) 125.81,28.05 125.81,29.13 126.55,29.87 126.55,34.55 127.59,35.59 127.59,36.65 127.28,36.96 127.28,37.21 v2(126.87,37.62)
  BOTTOM w0.089: v2(126.87,37.62) 127.16,37.92 UC1.R8
  BOTTOM w0.102: QC2.3 143.89,17.07 143.75,17.2 142.68,17.2 141.04,18.84 136.5,18.84 135.21,17.55 v2(135.21,17.05) ; v2(126.29,27.58) 128.98,24.89 RC14.1
SML0_SMBCLK: length 11.3
  BOTTOM w0.076: 124.71,33.68 124.71,33.91 124.85,34.35 124.86,34.39 124.86,35.99 125.12,36.24 125.22,36.24 125.48,36.5 125.48,36.82 125.45,36.85 125.45,37.12 125.71,37.47 125.71,37.8 126.13,38.22 126.99,38.22 UC1.R9
  BOTTOM w0.102: 124.71,33.68 124.72,33.68 124.72,33.65 125.47,32.9 v1(125.47,31.72) 125.47,31.47 125.93,31.01 126.87,31.01 127.05,30.83 RC19.1
SML0_SMBDATA: length 6.2
  BOTTOM w0.076: UC1.W2 125.03,34.4 125.03,34.37 125.03,34.37 125.01,34.31 124.94,34.08 124.93,34.07 124.91,33.98 124.91,33.74
  BOTTOM w0.102: 124.91,33.74 124.91,33.73 125.84,32.8 125.84,31.79 126.07,31.56 v1(127.11,31.56) 127.37,31.56 127.94,30.98 RC20.1
SML1CLK: length 64.7
  TOP w0.102: v2(92.46,13.67) 92.46,14.7 v1(92.33,14.83) 91.85,15.31 RC399.1
  IN3 w0.135: v2(130.17,31.03) 130.3,31.17 130.6,31.17 130.8,30.97 130.8,30.46 129.92,29.58 129.92,25.67 128.46,24.21 128.46,22.58 126.67,20.79 126.67,19.53 123.27,16.13 123.27,14.82 119.92,11.47 116.98,11.47 116.46,11.99 107.99,11.99 107.22,11.21 105.82,11.21 105,12.03 103.47,12.03 102.94,12.55 97.14,12.55 96.9,12.31 94.19,12.31 92.83,13.67 v2(92.46,13.67)
  BOTTOM w0.102: UC1.W3 125.52,34.84 125.52,33.94 126.59,32.88 126.85,32.88 127.12,32.61 128.26,32.61 129.7,31.17 130.03,31.17 v2(130.17,31.03) 130.17,30.71 RC15.1
SML1DATA: length 71.2
  TOP w0.102: RC397.1 v1(88.62,14.33) 89.11,13.85 v2(89.11,11.95)
  IN3 w0.135: v2(130.17,31.62) 130.17,31.59 130.33,31.43 130.71,31.43 131.06,31.08 131.06,30.36 130.18,29.47 130.18,25.56 128.73,24.11 128.73,22.48 126.94,20.69 126.94,19.42 123.54,16.02 123.54,14.72 120.03,11.21 116.87,11.21 116.35,11.73 108.1,11.73 107.32,10.95 105.71,10.95 104.9,11.76 103.36,11.76 102.83,12.29 97.25,12.29 97.01,12.05 94.08,12.05 93.18,12.95 90.11,12.95 v2(89.11,11.95)
  BOTTOM w0.102: RC17.1 130.78,31.01 v2(130.17,31.62) 129.95,31.4 129.79,31.4 128.36,32.84 127.21,32.84 126.94,33.11 126.74,33.11 126.16,33.69 126.16,35.19 UC1.V3
SNUB_+1VALW: length 2
  TOP w0.102: v4(144.16,30.89) 144.16,30.52 145.3,29.38
SOC_DP2_AUXN: length 152.6
  IN3 w0.076: 132.82,58.18 132.81,58.19 132.81,58.23 132.65,58.39 131.19,58.39 130.93,58.66 130.93,61.88 131.34,62.29 132.41,62.29 132.59,62.11 132.59,62.04 132.6,61.94 v2(132.85,61.74)
  IN3 w0.135: v2(203.64,59.09) 203.41,59.31 203.19,59.31 200.79,61.72 188.24,61.72 187.66,62.3 178.49,62.3 176.5,64.29 176.5,96.35 172.01,100.84 148.15,100.84 139.63,92.32 139.63,82.48 137.85,80.69 137.85,77.81 136.88,76.84 136.88,69.6 137.7,68.79 137.7,67.33 136.43,66.06 136.43,63.72 135.91,63.2 135.91,62.52 136.42,62.01 136.42,59.9 134.58,58.07 132.93,58.07 132.82,58.18
  BOTTOM w0.076: v2(132.85,61.74) 132.59,61.48 UC1.E48
  BOTTOM w0.094: v2(203.64,59.09) 203.84,59.29 204.23,59.29 204.37,59.16 JIO1.2
SOC_DP2_AUXP: length 152.6
  IN3 w0.076: v2(132.21,61.68) 132.42,61.92 132.41,62.03 132.33,62.11 131.42,62.11 131.12,61.81 131.12,58.73 131.27,58.58 132.72,58.58 132.94,58.36 132.98,58.36 132.99,58.35
  IN3 w0.135: v2(203.65,60.02) 203.65,59.63 203.58,59.56 203.29,59.56 200.89,61.96 188.34,61.96 187.76,62.54 178.59,62.54 176.75,64.39 176.75,96.45 172.11,101.08 148.05,101.08 139.39,92.43 139.39,82.58 137.6,80.8 137.6,77.91 136.64,76.94 136.64,69.5 137.46,68.69 137.46,67.43 136.18,66.16 136.18,63.82 135.66,63.3 135.66,62.42 136.17,61.91 136.17,60 134.48,58.31 133.03,58.31 132.99,58.35
  BOTTOM w0.076: UC1.F48 132.19,61.24 132.33,61.37 132.33,61.56 v2(132.21,61.68)
  BOTTOM w0.094: JIO1.1 204.35,59.66 204.17,59.47 203.76,59.47 203.65,59.58 v2(203.65,60.02)
SOC_DP2_N0: length 143.1
  IN3 w0.135: v2(139.4,62.25) 139.4,61.88 139.27,61.75 138.62,61.75 138.18,62.19 138.18,65.24 138.93,65.99 138.93,72.58 140.09,73.73 140.09,80.79 141.15,81.85 141.15,91.69 148.25,98.79 164.11,98.79 164.59,99.28 171.42,99.28 174.98,95.72 174.98,63.66 178.75,59.89 187.46,59.89 188.47,60.9 199.98,60.9 202.88,58.01 203.69,58.01 203.79,57.91 v2(203.79,57.52)
  BOTTOM w0.076: 135.77,61.94 135.75,61.94 135.74,61.94 134.52,61.94 134.49,61.97 134.07,61.97 134.01,62.03 UC1.C50
  BOTTOM w0.094: 135.77,61.94 136.97,61.94 137.24,61.68 139.18,61.68 139.4,61.89 v2(139.4,62.25) ; JIO1.5 204.48,57.66 204.29,57.85 203.86,57.85 203.79,57.78 v2(203.79,57.52)
SOC_DP2_N1: length 139.5
  IN3 w0.135: v2(203.68,56.03) 203.68,56.33 203.55,56.46 203.18,56.46 199.63,60.01 189.39,60.01 187.77,58.4 179.17,58.4 174.22,63.34 174.22,95.4 171.18,98.45 165.49,98.45 164.91,97.87 148.4,97.87 141.96,91.43 141.96,81.59 140.99,80.61 140.99,73.49 140.64,73.15 140.64,72.36 141.18,71.83 141.18,68.73 140.4,67.95 140.14,67.95 139.78,67.6 139.78,64.01 139.47,63.7 139.15,63.7 139.05,63.6 v2(139.05,63.43)
  BOTTOM w0.076: 135.92,63.52 135.9,63.52 135.89,63.53 135.52,63.53 135.47,63.57 134.52,63.57 134.48,63.53 134.09,63.53 134.01,63.45 UC1.C52
  BOTTOM w0.094: v2(203.68,56.03) 203.68,56.12 203.92,56.36 204.19,56.36 204.4,56.16 JIO1.8 ; v2(139.05,63.43) 139.05,63.64 138.99,63.7 138.42,63.7 138.24,63.52 135.92,63.52
SOC_DP2_P0: length 143.1
  IN3 w0.135: v2(139.31,61.29) 139.09,61.5 138.52,61.5 137.94,62.09 137.94,65.34 138.69,66.09 138.69,72.68 139.84,73.84 139.84,80.89 140.91,81.95 140.91,91.8 148.15,99.04 164.01,99.04 164.49,99.53 171.52,99.53 175.23,95.82 175.23,63.76 178.86,60.13 187.35,60.13 188.37,61.15 200.08,61.15 202.98,58.25 203.55,58.25 v2(203.73,58.43)
  BOTTOM w0.076: 135.77,61.76 135.75,61.76 135.74,61.77 134.46,61.77 134.42,61.81 134,61.81 133.62,62.19 UC1.D50
  BOTTOM w0.094: v2(139.31,61.29) 139.1,61.49 137.17,61.49 136.9,61.76 135.77,61.76 ; JIO1.4 204.37,58.16 204.25,58.04 204.13,58.04 v2(203.73,58.43)
SOC_DP2_P1: length 139.5
  IN3 w0.135: v2(139.04,64.13) 139.23,63.94 139.37,63.94 139.54,64.11 139.54,67.7 140.03,68.2 140.3,68.2 140.93,68.83 140.93,71.73 140.4,72.26 140.4,73.25 140.74,73.59 140.74,80.71 141.72,81.69 141.72,91.53 148.3,98.11 164.81,98.11 165.39,98.69 171.28,98.69 174.47,95.5 174.47,63.44 179.27,58.64 187.67,58.64 189.29,60.26 199.73,60.26 203.29,56.7 203.47,56.7 v2(203.64,56.87)
  BOTTOM w0.076: 135.92,63.7 135.9,63.7 135.89,63.7 135.58,63.7 135.54,63.74 134.45,63.74 134.41,63.69 133.74,63.69 UC1.D52
  BOTTOM w0.094: v2(203.64,56.87) 203.97,56.54 204.09,56.54 204.2,56.66 JIO1.7 ; v2(139.04,64.13) 138.79,63.88 138.34,63.88 138.17,63.7 135.92,63.7
SOC_XDP_TDI: length 12.3
  TOP w0.102: v2(136.78,68.16) 137.33,68.16 137.72,67.76 T111.1 140.68,67.76 141.43,68.51 142.52,68.51 142.53,68.52 RPC1.7
  BOTTOM w0.076: v2(136.78,68.16) 136.4,68.54 136.2,68.54 136.15,68.59 135.64,68.59 135.53,68.69 134.48,68.69 134.37,68.59 133.86,68.59 133.69,68.41 UC1.D60 133.36,67.38 UC1.D59
SOC_XDP_TDO: length 13.7
  TOP w0.102: v2(136.98,66) 136.35,66.64 v2(136.35,67.72) 136.4,67.77 136.4,68.31 136.71,68.61 137.35,68.61 137.88,68.09 140.68,68.09 141.6,69.01 T118.1 141.64,69.02 RPC1.6
  BOTTOM w0.076: UC1.A61 135.86,67.72 v2(136.35,67.72)
  BOTTOM w0.102: UC1.A56 135.41,65.7 136.68,65.7 v2(136.98,66)
SOC_XDP_TMS: length 11.4
  TOP w0.089: 137.95,66.86 137.86,66.86 137.07,67.65
  TOP w0.102: v2(137.06,67.66) 137.07,67.65 ; RPC1.8 143.36,68.02 T112.1 142.15,66.81 138,66.81 137.95,66.86
  BOTTOM w0.076: 135.72,67.32 135.16,67.87 134.5,67.87 UC1.C60
  BOTTOM w0.089: UC1.C59 134.01,67.38 UC1.C60
  BOTTOM w0.102: v2(137.06,67.66) 136.72,67.32 135.72,67.32
SOC_XDP_TRST#: length 3.6
  TOP w0.089: v2(134.98,67.52) 135.04,67.46 T110.1
  BOTTOM w0.076: UC1.C61 134.01,67.63 133.7,67.31 133.7,66.99 133.82,66.86 134.38,66.86 UC1.B59 134.66,67.2 v2(134.98,67.52)
SPK_L1-_CONN: length 3.4
  TOP w0.127: DA13.3 30.48,11.18 29.02,9.72 v1(28.41,9.72)
  vias: v2(31.14,16.95) v2(31.78,16.95)
SPK_L2+_CONN: length 2.6
  TOP w0.127: v1(26.61,10.28) 27.13,10.8 27.49,10.8 DA13.2
  vias: v2(29.57,17.38) v2(29.57,16.75)
SPK_R1-_CONN: length 5
  TOP w0.127: v1(30.19,9.81) 30.59,9.81 31.46,10.69 31.46,11.81 32.53,12.87 DA14.3
  vias: v2(32.41,16.95) v2(33.05,16.95)
SPK_R2+_CONN: length 5.2
  TOP w0.127: DA14.2 34.09,13.6 33.13,12.63 32.97,12.63 32.39,12.05 32.39,9.98 v1(32.07,9.66)
  vias: v2(33.56,16.44) v2(34.19,16.44)
SPKR: length 108.6
  TOP w0.089: v2(114.71,36) 110.71,36 108.07,33.37
  TOP w0.102: DA8.3 33.2,33.33 v2(33.41,33.53) ; v2(43.73,16.49) 43.94,16.29 v1(64.58,16.29) 77.47,16.29 v2(77.73,16.54) ; 108.07,33.37 106.07,31.36 103.15,31.36 102.96,31.17 v2(102.64,31.17) 101.97,31.17 RC183.2
  IN1 w0.114: v2(33.41,33.53) 33.79,33.53 36.22,31.1 36.22,30.05 37.35,28.92 37.35,25.89 37.67,25.56 37.67,24.14 42.51,19.3 42.51,17.71 v2(43.73,16.49)
  BOTTOM w0.076: v2(114.71,36) 114.84,36.13 114.84,36.17 UC1.AW5
  BOTTOM w0.102: v2(77.73,16.54) 78.11,16.16 80.95,16.16 81.07,16.28 87.44,16.28 88.8,17.64 88.8,20.74 93.88,25.82 93.88,26.72 94.4,27.24 96.17,27.24 96.48,26.93 99.29,26.93 101.98,29.62 101.98,30.51 v2(102.64,31.17)
SRTCRST#: length 51.1
  TOP w0.102: RC56.1 98.76,27.58 98.76,27.95 99.29,28.48 101.83,28.48 102.15,28.17 102.15,25.79 v1(102.34,25.6) 103.03,24.91 103.03,24.27 102.69,23.93 v2(101.09,23.93)
  IN3 w0.135: v2(101.09,23.93) 102.8,23.93 103.19,24.32 105.81,24.32 107.2,25.72 107.2,30.37 113.92,37.09 115.15,37.09 115.54,37.48 115.54,39.05 115.85,39.36 116.33,39.36 117.31,40.35 117.6,40.35 117.82,40.57 117.82,40.93 118.32,41.43 118.32,42.35 118.28,42.39 118.28,43 v2(118.69,43.41)
  BOTTOM w0.102: UC1.AN18 v2(118.69,43.41) ; CC24.1 98.88,16.79 98.88,22.55 99.34,23.01 100.96,23.01 101.09,23.14 v2(101.09,23.93)
SSD_DEVSLP: length 110.2
  TOP w0.102: v2(215.5,13.11) 216.55,12.06 222.15,12.06 v1(222.16,12.07) 222.7,12.61 R6526.2
  IN1 w0.114: v2(215.5,13.11) 215.08,12.7 213.92,12.7 212.64,13.98 212.64,15.21 209.24,18.62 203.41,18.62 202.4,19.63 182.85,19.63 182.45,20.03 159.08,20.03 157.25,18.19 154.72,18.19 154.02,17.49 146.8,17.49 145.07,19.23 144.05,19.23 143,20.28 142.69,20.28 140.11,22.86 140.11,25.17 138.55,26.73 v2(138.55,28.35)
  BOTTOM w0.102: v2(138.55,28.35) 138.31,28.11 137.82,28.11 137.59,28.35 134.15,28.35 132.87,29.63 132.87,31.82 130.78,33.91 130.78,34.89 UC1.J3
SUS_STAT#/LPCPD#: length 28.6
  TOP w0.102: RC1127.1 106.68,18.99 v1(106.61,19.07) 106.14,19.54 106.14,24.88 v2(105.92,25.1)
  BOTTOM w0.076: UC1.BA11 113.13,40.01 112.8,39.68 111.85,39.68 110.29,38.12 110.29,37.7 110.01,37.42 107.95,37.42 106.63,36.1 106.63,35.13 106.47,34.97
  BOTTOM w0.102: v2(105.92,25.1) 104.94,26.08 104.94,29.52 106.47,31.06 106.47,33.8 106.33,33.94 106.33,34.82 106.47,34.97
SUSACK#: length 37.6
  TOP w0.094: UE1.34 46.24,41.82 45.95,41.54 45.95,40.93 v2(46.13,40.75) ; RE449.2 v2(27.56,51.89) ; v2(41.09,52.12) 36.97,52.12 36.53,52.56 v2(36.53,53.82)
  IN3 w0.135: v2(41.09,52.12) 42.27,50.93 42.27,48.22 43.13,47.36 43.13,44.67 43.02,44.56 43.02,42.11 44.38,40.75 v2(46.13,40.75) ; v2(36.53,53.82) 36.53,54.16 34.45,56.24 33.59,56.24 32.81,57.02 30.73,57.02 27.46,53.75 27.46,53 27.56,52.91 v2(27.56,51.89)
SUSCLK: length 334.1
  TOP w0.094: R6518.2 v2(186.59,51.49) ; v2(27.56,37.88) 27.59,37.9 RE368.2 ; RC48.1 101.44,25.75 v2(101.41,25.73)
  IN1 w0.114: v2(168.35,11.66) 167.37,10.68 149.98,10.68 148.45,9.14 142.4,9.14 139.3,12.24 129.87,12.24 125.98,16.13 125.98,20.29 120.44,25.83 118.23,25.83 117.2,26.85 114.55,26.85 113.56,27.84 111.63,27.84 110.95,28.52 110.39,28.52 108.87,27 107.99,27 107.43,26.43 105.23,26.43 v2(104.23,25.43) 102.91,24.11 102.91,22.56 100.45,20.1 94.52,20.1 94.32,20.3 90.94,20.3 88.63,17.99 77.03,17.99 75.99,16.95 70,16.95 68.9,18.05 65.4,18.05 63.51,19.95 61.98,19.95 60.53,21.39 58.3,21.39 56.04,23.66 56.04,24.05 51.76,28.32 51.76,33.61 52.2,34.04 52.2,35.44 47.22,40.43 47.22,43.42 47.22,50.25 47.81,50.85 47.81,54.83 48.44,55.46 48.44,57.65 49.03,58.24 49.03,62.46 v2(48.1,63.39)
  IN3 w0.135: v2(33.79,64.1) 33.79,63.22 27.92,57.35 27.12,57.35 25.28,55.51 20.73,55.51 17.11,51.89 17.11,48.13 19.52,45.71 21.17,45.71 22.51,44.38 22.51,41.82 22.79,41.54 22.79,39.64 24.66,37.76 27.45,37.76 v2(27.56,37.88) ; v2(104.23,25.43) 103.94,25.73 v2(101.41,25.73) 100.99,25.31 95.15,25.31 94.14,26.32 v2(91.52,26.32)
  BOTTOM w0.076: UC1.BA17 113.07,43.36 111.48,43.36 110.92,42.79 110.33,42.79 109.69,42.16 108.11,42.16 107.98,42.29 106.84,42.29 103.41,38.86
  BOTTOM w0.094: v2(91.52,26.32) 91.52,27.19 93.57,29.25 95.55,29.25 96.06,29.75 98.71,29.75 99.75,30.79 99.75,35.7 101.88,37.84 102.39,37.84 103.41,38.86 ; v2(186.59,51.49) 184.34,49.24 184.34,38.81 185.62,37.53 185.62,34.44 182.16,30.98 182.16,28.28 181.09,27.21 181.09,21.26 175.2,15.37 172.06,15.37 v2(168.35,11.66) ; v2(33.79,64.1) v1(35.68,64.1) 36.16,64.57 43.84,64.57 45.03,63.39 v2(48.1,63.39)
SUSCLK_R: length 2.8
  TOP w0.094: R6518.1 v2(186.59,54.1) 187.15,54.1 v1(187.27,54.21)
  BOTTOM w0.094: v2(186.59,54.1) 186.42,53.93 WLAN1.42
SW_VCCEOPIO: length 0.9
  TOP w0.102: v1(111.48,102.15) 111.24,102.4 v2(111.24,102.92)
SYS_PWROK: length 157.9
  TOP w0.102: v2(36.03,52.1) 36.03,52.94 35.51,53.46 35.51,54.17 35.94,54.6 UE1.89
  TOP w0.127: v4(133.38,34.28) 133.69,33.97 v2(135.32,33.97)
  IN3 w0.135: v2(36.03,52.1) 35.79,51.86 35.79,47.77 36.72,46.84 36.72,44.03 37.37,43.39 37.37,42.76 37.01,42.4 37.01,41.05 36.5,40.55 36.5,38.23 37.61,37.13 37.61,32.03 42.57,27.06 43.01,27.06 45.65,24.42 45.65,21.55 47.53,19.67 47.53,18.22 51.2,14.55 52.17,14.55 54.77,11.95 55.51,11.95 57.28,10.17 60.99,10.17 61.69,10.87 74.29,10.87 74.74,10.42 87.51,10.42 87.98,10.9 89.58,10.9 90.6,11.92 92.75,11.92 93.5,11.16 93.5,10.68 94.34,9.83 111.09,9.83 111.55,10.3 115.2,10.3 115.33,10.17 120.91,10.17 125.15,14.41 125.15,16.18 127.97,19 127.97,20.26 129.76,22.05 129.76,23.68 131.24,25.16 131.24,25.5 133.69,27.96 133.69,29.84 134.89,31.03 134.89,33.54 v2(135.32,33.97)
  BOTTOM w0.102: UC1.B6 134.61,36.47 134.76,36.47 134.98,36.25 134.98,34.69 135.32,34.35 v2(135.32,33.97)
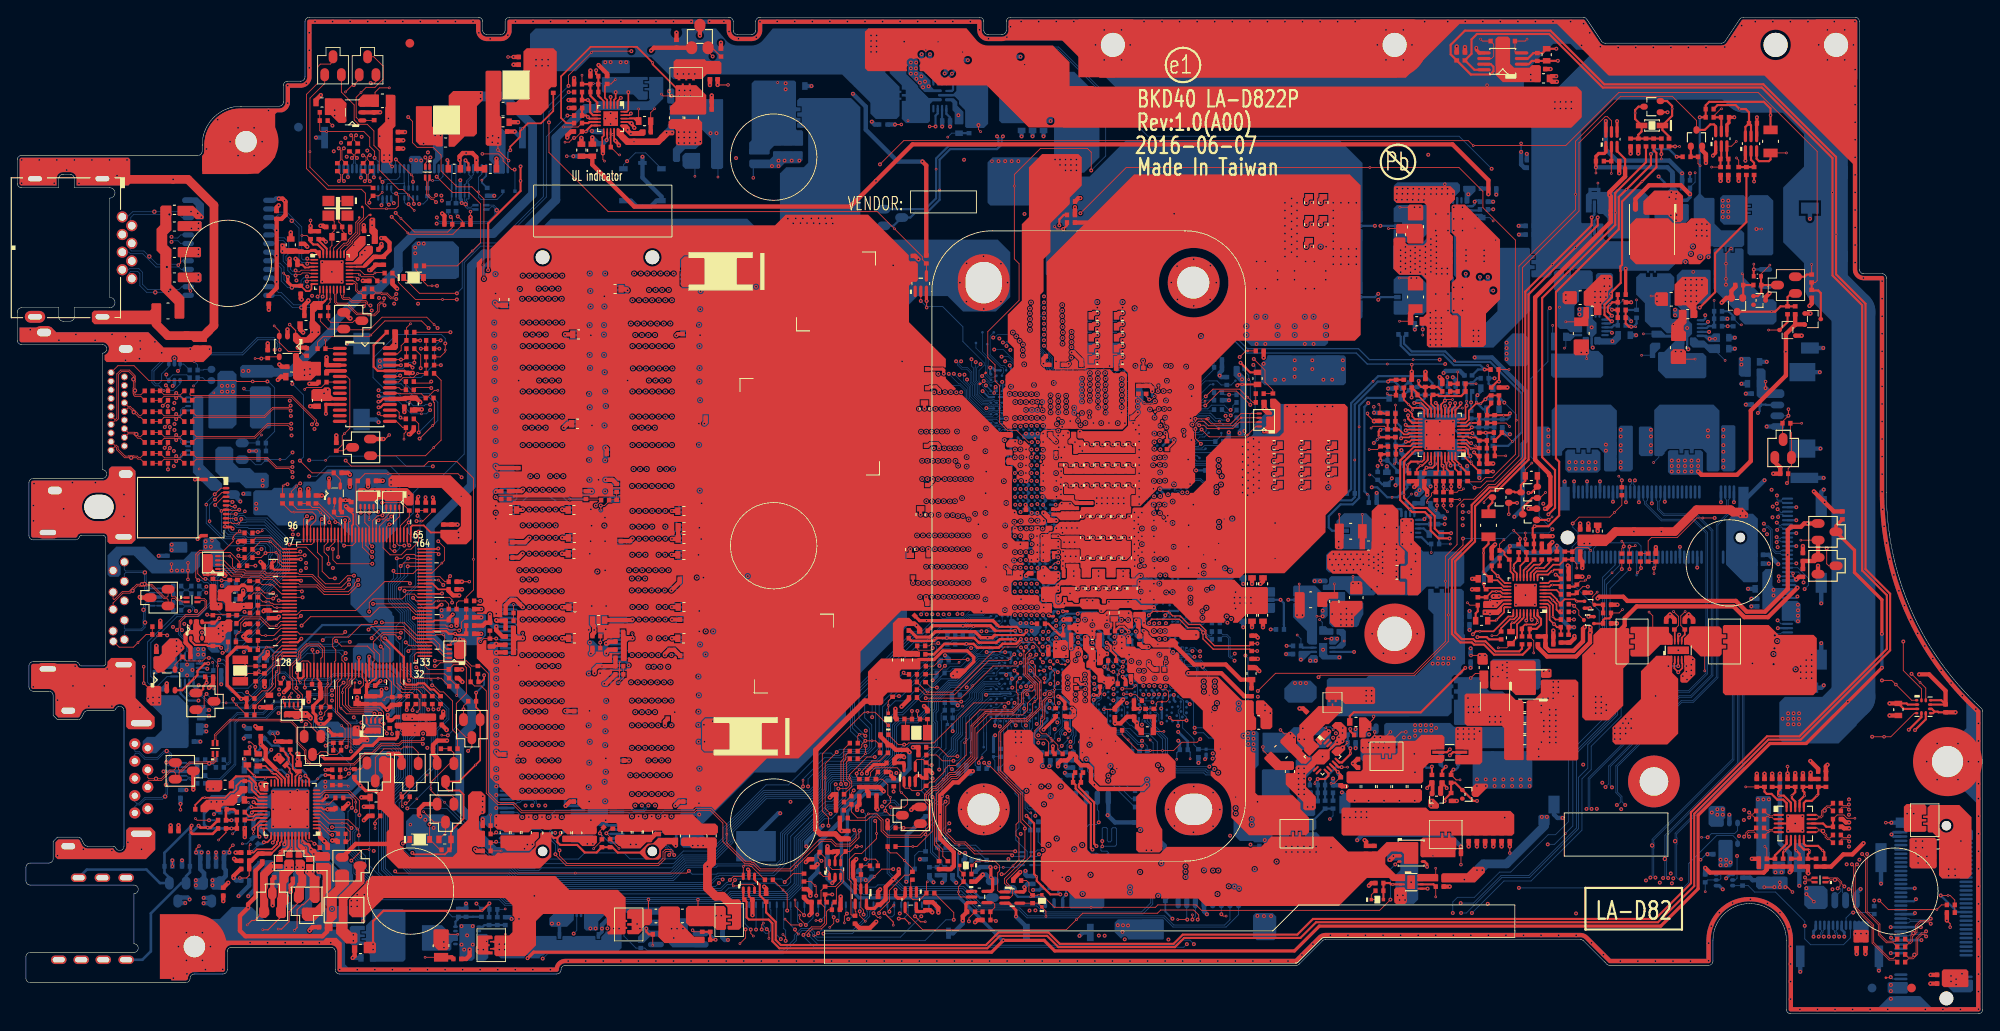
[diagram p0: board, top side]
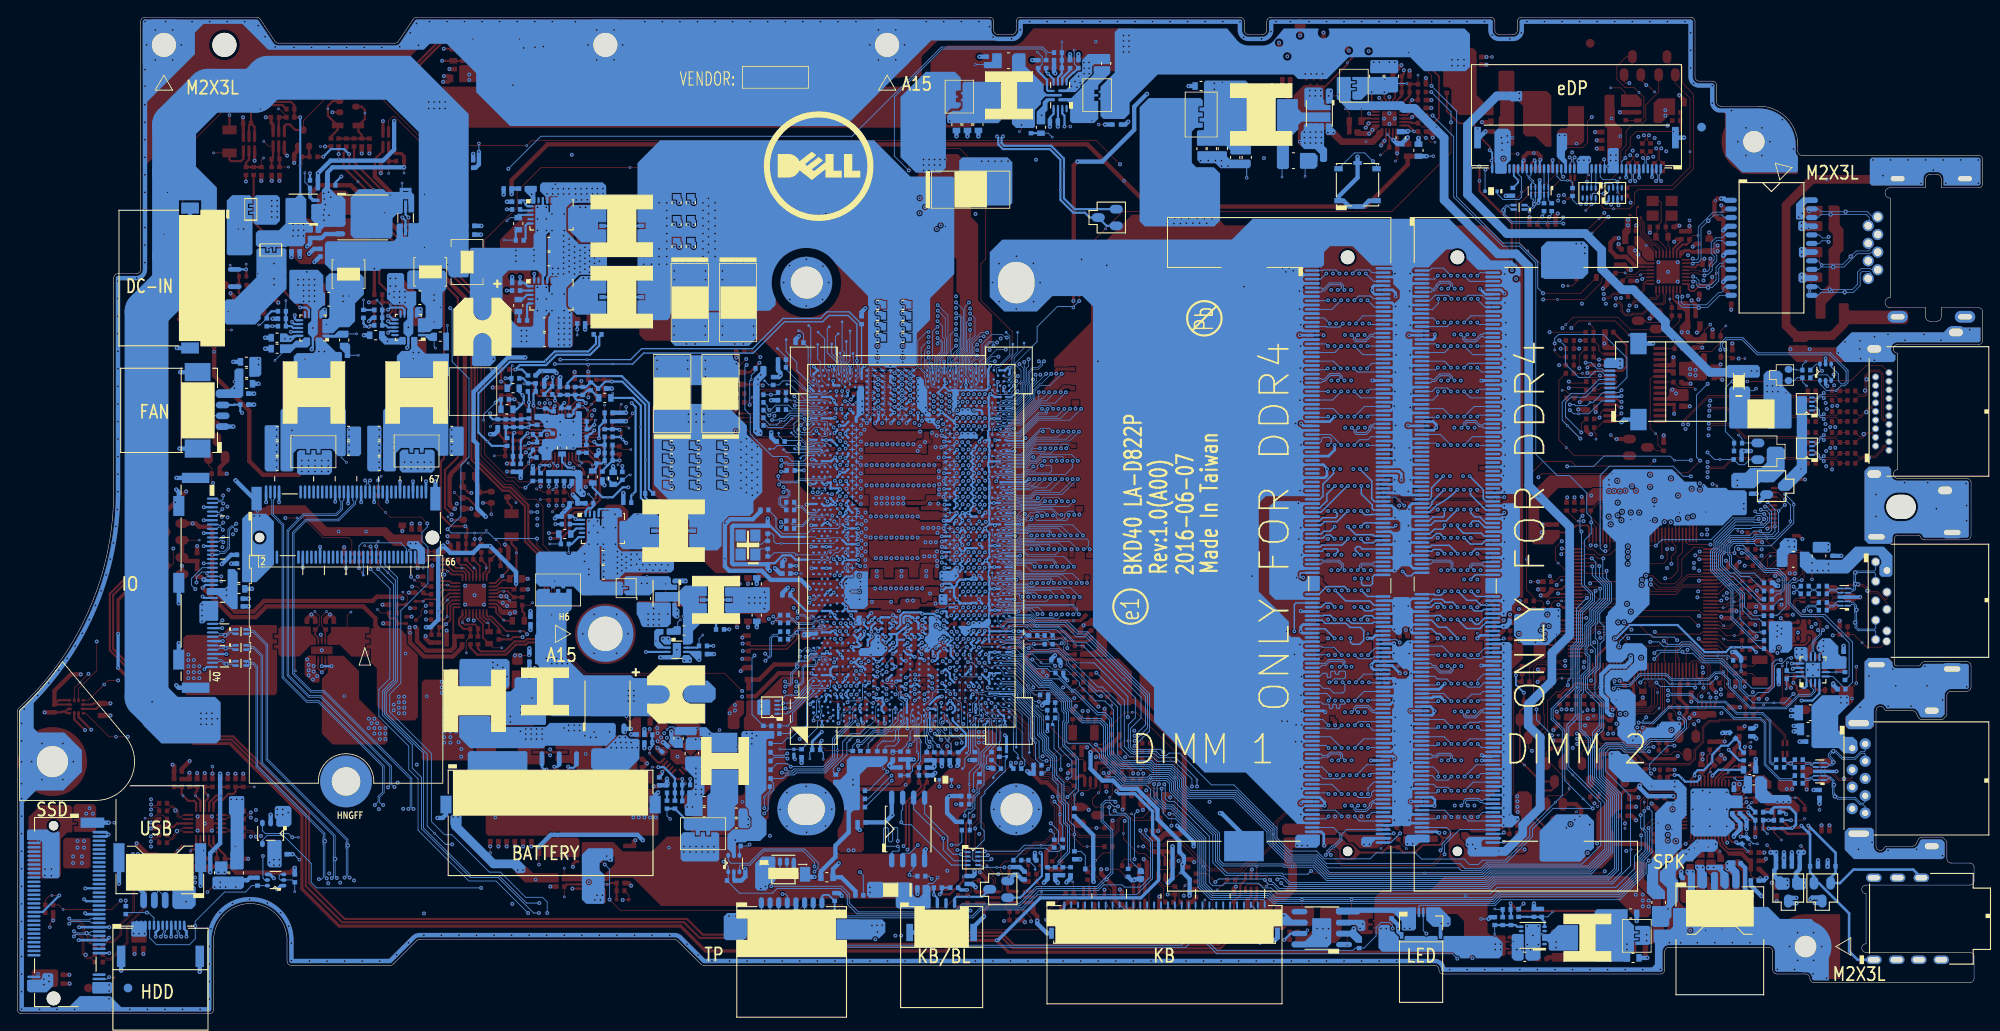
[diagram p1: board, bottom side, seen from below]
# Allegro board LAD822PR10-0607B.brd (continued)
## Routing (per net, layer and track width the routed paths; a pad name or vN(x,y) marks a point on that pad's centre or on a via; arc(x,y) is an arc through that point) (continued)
SYS_RESET#: length 9.2
  BOTTOM w0.089: UC1.B5 134.66,35.45 134.36,35.15 134.36,34.85 134.52,34.69 134.52,34.21 134.88,33.85 134.88,33.09 135.4,32.57
  BOTTOM w0.102: v1(139.23,30.65) 139.21,30.63 CC1807.1 RC291.2 136.17,31.16 136.17,31.8 135.4,32.57
T_CRIT#: length 3.5
  TOP w0.102: v1(174.73,112.87) 174.5,112.64 R2604.2 173.33,111.41 173.48,111.27 THM26.4
THM_SML1_CLK: length 270.2
  TOP w0.254: Q2601.4 85.32,15.52 85.93,14.92 85.93,13.71 RE432.2 86.67,11.73 87.78,10.63 87.78,8.55 88.37,7.96 112.11,7.96 113.56,9.41 119.34,9.41 120.65,8.1 133.83,8.1 134.89,9.16 148.14,9.16 149.96,10.98 189.57,10.98 193.7,15.11 193.7,23.32 202.51,32.13 206.25,32.13 216.37,42.25 216.37,48.48 213.52,51.34 213.52,82.07 210.09,85.5 v1(210.09,95.12) 210.09,99.09 201.92,107.26 183.5,107.26 177.29,113.47 168.94,113.47 168.3,112.83 168.3,111.17 C2608.1 168.63,109.32 THM26.8
THM_SML1_DATA: length 278.6
  TOP w0.254: THM26.7 170.53,109.97 170.84,109.66 170.84,109.15 170.46,108.77 168.23,108.77 C2609.1 165.89,111.11 165.89,112.2 167.54,113.85 177.45,113.85 183.66,107.64 202.07,107.64 210.49,99.22 v1(210.49,90.27) 210.49,85.63 213.9,82.23 213.9,51.49 216.75,48.64 216.75,42.09 206.41,31.74 202.66,31.74 194.08,23.17 194.08,14.79 189.89,10.6 150.32,10.6 148.5,8.78 135.05,8.78 133.98,7.72 120.49,7.72 119.18,9.02 113.71,9.02 112.27,7.58 88.21,7.58 87.39,8.39 87.39,10.47 86.96,10.9 84.67,10.9 84.41,11.17 84.41,12.96 RE32.2 84.02,13.34 Q2601.1
TON_1.2V: length 4.1
  TOP w0.102: PR208.2 64.9,102.69 v1(63.22,102.69)
  TOP w0.254: PU200.9 66.2,103.27 66.08,103.15 PR208.2
TOUCH_SCREEN_PD#: length 167.5
  TOP w0.102: R5205.2 46.16,86.12 D5203.2 47.01,84.79 47.5,84.3 v1(48,84.3) v2(48.58,84.3)
  IN1 w0.114: v2(109.57,98.9) 109.83,99.15 118.41,99.15 121.27,96.29 132.91,96.29 139.78,89.42 139.78,72.99 139.13,72.34 139.13,67.09 139.86,66.36 139.86,52.83 140.83,51.86 140.83,50.92 140.2,50.29 140.2,46.72 141.09,45.83 141.09,42.54 v2(142.14,41.49)
  IN2 w0.127: v2(109.57,98.9) 109.57,97.94 104.78,93.15 89.26,93.15 87.86,91.75 61.4,91.75 60.13,93.02 55.9,93.02 48.58,85.71 v2(48.58,84.3)
  BOTTOM w0.102: v2(142.14,41.49) 142.44,41.19 142.44,34.66 RC277.2 140.2,33.35 RC394.1
TOUCH_SCREEN_PD#_R: length 6.3
  BOTTOM w0.102: UC1.A7 135.31,37.29 137.74,34.87 137.74,33.92 v1(138.32,33.33) RC394.2
TOUCHPAD_INTR#: length 130.7
  TOP w0.102: v2(52.18,30.44) 52.61,30.87 Q6204.1 51.96,31.97 50.75,33.18 50.75,34.65 50.82,34.72 50.82,35.95 51.97,37.1 51.97,40.09 51.64,40.42 50.47,40.42 RE440.1 47.59,39.87 47.16,40.3 UE1.33 ; v2(111.89,29.07) 112.31,28.65 112.62,28.65 115.91,25.36 115.91,22.25 115.59,21.93 115.59,20.64 115.93,20.3 115.93,17.83 v1(115.24,17.13) 114.27,16.16 v2(113.92,16.16)
  IN1 w0.114: v2(120.76,26.31) 119.8,27.26 117.96,27.26 117.15,28.07 114.85,28.07 114.28,28.64 112.32,28.64 v2(111.89,29.07)
  IN2 w0.127: v2(113.92,16.16) 113.41,15.65 111.03,15.65 110.34,16.34 106.89,16.34 102.26,20.96 101.28,20.96 97.11,25.13 96.52,25.13 96.27,25.38 94.72,25.38 94.36,25.74 92.55,25.74 85.02,18.21 82.84,18.21 80.23,15.6 79.64,15.6 78.75,14.71 59.71,14.71 58.08,16.34 57.65,16.34 56.68,17.31 52.52,17.31 50.93,18.89 50.93,25.45 52.35,26.87 52.35,30.26 v2(52.18,30.44)
  BOTTOM w0.102: DZ3.1 v2(120.76,26.31)
TOUCHPAD_INTR#_D: length 21.1
  TOP w0.102: v1(111.66,29.66) 111.28,29.28 v2(111.28,29.05)
  IN1 w0.114: v2(119.36,26.35) 118.7,27.01 117.87,27.01 117.05,27.83 114.75,27.83 114.18,28.4 111.94,28.4 v2(111.28,29.05)
  BOTTOM w0.076: 111.18,32.57 111.18,34.63 112.55,36 112.93,36 113.37,36.44 UC1.BA5
  BOTTOM w0.102: v2(111.28,29.05) 111.5,28.84 111.5,28.62 RC272.2 110.86,28.8 110.86,29.41 111.18,29.72 111.18,32.57 ; DZ3.2 v2(119.36,26.35)
TP_LOCK#: length 109.3
  TOP w0.102: v2(139.35,11.53) 139.57,11.31 v1(139.91,11.31) ; R6505.2 48.93,18.98 D3801.2 47.72,21.86 47.7,21.88 v2(47.7,21.95)
  IN2 w0.127: v2(47.7,21.95) 47.7,18.38 51.32,14.77 55.63,14.77 56.63,13.76 57.06,13.76 58.65,12.17 79.8,12.17 80.49,12.86 82.97,12.86 83.41,13.29 86.05,13.29 87.25,14.49 87.25,14.63 89.13,16.5 95.24,16.5 99.14,12.61 102.94,12.61 103.38,12.16 113.98,12.16 115.41,10.73 118.76,10.73 120.09,12.06 129.05,12.06 129.88,11.22 132.16,11.22 133.16,12.23 138.65,12.23 v2(139.35,11.53)
  BOTTOM w0.102: TPAD1.3 v2(139.35,11.53)
TP_ON#_GATE: length 11.2
  TOP w0.102: C6204.2 R6214.2 50.52,30.21 Q6203.2 50.03,28.98 47.87,26.82 v1(47.87,26.07) 47.87,25.86 48.49,25.24 50.32,25.24 50.52,25.04 Q2405.2
TP_PW_EN#: length 21.4
  TOP w0.102: v2(45.8,48.17) 46.14,47.82 UE1.49 ; R6214.1 50.96,32.29 50.37,32.87 50.37,36.23 49.33,37.27 48.92,37.27 48.16,38.03 v2(48.01,38.03)
  BOTTOM w0.102: v2(48.01,38.03) 48.01,38.59 v1(47.88,38.72) 47.65,38.95 47.65,42.49 47.02,43.13 47.02,46.95 v2(45.8,48.17)
TP_RESET: length 3.6
  BOTTOM w0.102: R5212.1 47.48,96.23 47.75,96.5 v1(48.06,96.5) 48.8,96.5 49.27,96.97 JEDP.25
TP_RS: length 19.6
  TOP w0.102: v2(48.54,96.93) 50.37,95.11 52.3,95.11 53.62,93.78 53.62,89.31 v1(52.65,88.34) 50.92,86.61 R5205.1
  BOTTOM w0.102: v2(48.54,96.93) 48.77,97.16 JEDP.24
TPM_ID: length 7.7
  BOTTOM w0.102: UC1.AC2 122.84,34.52 122.84,33.78 123.12,33.49 123.12,31.93 122.91,31.72 v1(122.91,31.47) 122.91,29.22 123.1,29.03 RC1130.2 RC1131.1
TPM_LPM#: length 12.3
  TOP w0.102: UZ13.6 38.14,73.81 38.48,73.46 38.48,67.8 v1(37.86,67.17) 37.61,66.92 37.61,65.88 RZ119.1 37.76,65.2 38.16,65.59 QZ11.1
UART_2_CRXD_DTXD: length 32.7
  IN1 w0.114: v2(121.9,30.92) 122.98,29.84 122.98,27.81 127.09,23.69 127.09,21.96 127.95,21.1 127.95,19.41 132.43,14.93 137.35,14.93 v2(139.01,16.58)
  BOTTOM w0.102: UC1.AD1 122.52,32.19 122.36,32.03 122.36,31.37 121.9,30.91 ; v2(121.9,30.92) 121.9,30.91 ; 121.9,30.91 122.22,30.58 RC62.1 ; JWDB1.2 139.2,16.78 v2(139.01,16.58)
UART_2_CTXD_DRXD: length 32.9
  IN1 w0.114: v2(121.9,31.5) 123.26,30.14 123.26,27.87 127.33,23.79 127.33,22.06 128.19,21.2 128.19,19.51 132.53,15.17 136.98,15.17 v2(138.4,16.58)
  BOTTOM w0.076: 122.27,32.57 122.27,34.02 122.37,34.24 122.38,34.24 122.38,34.25 122.52,34.39 UC1.AD2
  BOTTOM w0.102: RC63.1 121.49,30.43 121.49,31.09 v2(121.9,31.5) 122.13,31.74 122.13,32.13 122.27,32.26 122.27,32.57 ; v2(138.4,16.58) 138.4,17.6 JWDB1.3
UG_1.2V: length 5.6
  TOP w0.102: v1(74.55,106.5) 74.76,106.29 v2(75.71,106.29)
  IN3 w0.762: 71.81,103.27 74.87,106.33
  vias: v2(71.09,103.12) v2(71.4,102.61) v2(75.44,106.84)
UGATE_CHG: length 4.7
  TOP w0.102: v2(169.27,41.5) 168.25,41.5 v4(168.24,41.49)
  IN3 w0.762: 170.34,45.64 170.51,45.46 170.51,42.45 170.23,42.17
  vias: v2(169.88,46.5) v2(169.87,41.5) v2(170.45,46.34)
UL1_RSET_P31: length 3.8
  TOP w0.102: v1(32.95,90.13) 33.52,90.13 RL5.2
  TOP w0.203: 35.41,88.44 UL1.31
  TOP w0.254: 35.41,88.44 34.76,89.09 34.26,89.09 33.94,89.4 RL5.2
USB2_ID: length 2.9
  TOP w0.508: v2(122.07,35.33) 122.29,35.11 v1(122.29,34.75) 122.29,34.61 122.06,34.39 121.34,34.39 RC366.1
  BOTTOM w0.254: UC1.AG3 121.34,35.33 v2(122.07,35.33)
USB2_VBUSSENSE: length 6.4
  BOTTOM w0.076: 120.25,32.57 120.25,32.57 120.94,33.26 120.94,35.58 UC1.AG4
  BOTTOM w0.102: 120.25,32.57 120.08,32.4 120.08,31.91 v1(119.75,31.58) 119.41,31.24 119.41,30.42 RC393.1
USB3_CRX_DTX_N1: length 171.1
  IN3 w0.076: 130.43,35.01 130.44,35.02 130.44,35.48 129.78,36.14 129.78,37.3 130.06,37.57 131.13,37.57 131.21,37.65 131.21,37.75 v2(130.99,37.96)
  IN3 w0.135: 130.43,35.01 129.91,34.49 129.49,34.49 128.94,33.94 128.94,32.51 128.55,32.12 128.55,26.24 127.1,24.79 127.1,23.15 123.69,19.74 123.69,19.06 118.02,13.39 104.2,13.39 103.65,13.94 97.63,13.94 96.7,14.87 95.19,14.87 94.83,14.51 93.92,14.51 93.34,15.09 90.12,15.09 88.25,13.21 83.75,13.21 83.31,12.77 79.77,12.77 79.43,12.43 75.66,12.43 75.25,12.83 58.22,12.83 57.1,13.95 56.49,13.95 54.87,15.58 53.91,15.58 52.87,16.62 52.05,16.62 49.6,19.07 49.6,23.49 43.52,29.56 42.86,29.56 42.5,29.93 42.5,31.07 41.41,32.16 41.41,33.45 38.88,35.97 38.88,37.76 38.73,37.91 38.73,42 39.3,42.57 39.3,43.31 38.73,43.88 38.73,47.46 37.6,48.6 37.6,51.53 34.1,55.03 31.26,55.03 29.03,52.8 29.03,52.28 28.17,51.42 25.17,51.42 24.92,51.67 21.33,51.67 20.18,50.53 20.18,46.88 19.93,46.63 v2(19.92,46.63)
  BOTTOM w0.076: UC1.H8 v2(130.99,37.96)
  BOTTOM w0.094: v2(19.92,46.63) 20.17,46.63 20.3,46.76 20.3,46.94 20.11,47.13 19.36,47.13 R3411.2
USB3_CRX_DTX_N1_C: length 9.8
  BOTTOM w0.094: JUSB1.5 12.39,44.27 12.48,44.36 14.41,44.36 14.79,44.74 v3(14.79,45.31) 14.79,46.45 14.83,46.49 14.83,47.07 14.79,47.12 14.79,47.21 14.98,47.4 15.18,47.4 15.33,47.25 U3402.1 U3402.9 16.75,47.25 16.85,47.36 17,47.36 17.24,47.11 17.67,47.11 R3411.1
USB3_CRX_DTX_N2: length 151.9
  IN3 w0.076: 131.17,35.08 131.17,35.1 131.2,35.13 131.2,35.49 130.66,36.02 130.66,36.76 130.47,36.95 v2(130.33,36.95)
  IN3 w0.135: v2(39.82,33.71) 39.82,33.85 39.55,34.12 39.35,34.12 38.92,33.69 38.92,32.53 42.77,28.68 43.42,28.68 48.87,23.22 48.87,18.77 51.78,15.86 52.67,15.86 54.01,14.51 54.91,14.51 56.18,13.24 56.8,13.24 57.89,12.15 74.9,12.15 75.3,11.75 79.72,11.75 80,12.03 83.54,12.03 84.03,12.52 88.63,12.52 90.48,14.37 93.09,14.37 94.46,13 96.52,13 96.76,13.24 103.25,13.24 103.78,12.71 118.48,12.71 120.54,14.77 121.71,14.77 122.51,15.56 122.51,16.33 125.99,19.82 125.99,21.08 127.78,22.87 127.78,24.5 129.24,25.96 129.24,31.76 131.17,33.69 131.17,35.08
  BOTTOM w0.076: v2(130.33,36.95) 129.99,37.3 UC1.J6
  BOTTOM w0.094: v2(39.82,33.71) 39.44,33.71 39.32,33.59 38.12,33.59 36.3,35.41 30.1,35.41 28.8,34.11 25.76,34.11 25.29,33.64 25.29,28.82 23.5,27.03 22.09,27.03 R3417.2
USB3_CRX_DTX_N2_C: length 10.6
  BOTTOM w0.094: R3417.1 20.48,27.04 20.06,27.04 19.89,27.21 19.73,27.21 19.59,27.06 U3403.9 U3403.1 18.05,27.06 17.89,27.22 17.65,27.22 17.39,26.96 17.39,26.83 17.44,26.79 17.44,26.18 17.39,26.14 17.39,25.44 v3(17.12,25.16) 16.8,24.84 14.82,24.84 14.16,24.19 13.81,24.19 13.6,23.98 JUSB2.5
USB3_CRX_DTX_N3: length 116.8
  IN3 w0.135: v2(130.4,39.71) 130.61,39.47 133.75,39.47 134.43,38.78 136.04,38.78 136.54,39.29 138.98,39.29 139.74,38.53 139.74,31.11 141.1,29.75 141.1,25.95 145.38,21.67 151.57,21.67 152.42,20.82 179.97,20.82 181.76,22.6 191.27,22.6 197.82,29.15 197.82,50.59 202.25,55.03 203.45,55.03 v2(203.62,55.2)
  BOTTOM w0.076: v2(130.4,39.71) 129.99,39.3 UC1.J10
  BOTTOM w0.094: JIO1.10 204.16,55.16 204,55 203.82,55 v2(203.62,55.2)
USB3_CRX_DTX_P1: length 171.1
  IN3 w0.076: v2(131.6,37.97) 131.39,37.75 131.39,37.57 131.21,37.38 130.13,37.38 129.97,37.22 129.97,36.22 130.63,35.56 130.63,34.99 130.66,34.96 130.66,34.94
  IN3 w0.135: v2(20.69,46.64) 20.43,46.89 20.43,50.42 21.43,51.43 24.82,51.43 25.07,51.17 28.27,51.17 29.28,52.18 29.28,52.7 31.36,54.78 34,54.78 37.35,51.43 37.35,48.5 38.48,47.36 38.48,43.78 39.05,43.21 39.05,42.67 38.48,42.1 38.48,37.81 38.64,37.66 38.64,35.87 41.16,33.35 41.16,32.06 42.25,30.97 42.25,29.83 42.76,29.32 43.42,29.32 49.36,23.39 49.36,18.97 51.95,16.38 52.77,16.38 53.81,15.33 54.77,15.33 56.39,13.71 57,13.71 58.12,12.59 75.15,12.59 75.56,12.19 79.53,12.19 79.87,12.52 83.41,12.52 83.85,12.96 88.35,12.96 90.22,14.84 93.24,14.84 93.82,14.26 94.93,14.26 95.29,14.62 96.6,14.62 97.52,13.7 103.54,13.7 104.1,13.15 118.12,13.15 123.93,18.96 123.93,19.64 127.34,23.05 127.34,24.68 128.8,26.14 128.8,32.01 129.19,32.41 129.19,33.84 129.59,34.24 130.01,34.24 130.66,34.89 130.66,34.94
  BOTTOM w0.076: UC1.G8 v2(131.6,37.97)
  BOTTOM w0.094: R3410.2 19.28,47.31 20.18,47.31 20.48,47.01 20.48,46.84 v2(20.69,46.64)
USB3_CRX_DTX_P1_C: length 9.8
  BOTTOM w0.094: R3410.1 17.72,47.29 17.32,47.29 16.86,47.76 U3402.8 U3402.2 15.33,47.76 15.17,47.59 14.9,47.59 14.6,47.29 v3(14.6,46.78) 14.6,45.64 14.56,45.6 14.56,45 14.6,44.96 14.6,44.81 14.34,44.54 12.48,44.54 12.39,44.64 JUSB1.6
USB3_CRX_DTX_P2: length 152
  IN3 w0.076: 131.41,35.08 131.41,35.1 131.38,35.13 131.38,35.57 130.85,36.1 130.85,36.84 v2(130.96,36.95)
  IN3 w0.135: v2(38.95,34.33) 38.95,34.07 38.67,33.79 38.67,32.43 42.67,28.44 43.32,28.44 48.63,23.12 48.63,18.67 51.68,15.61 52.57,15.61 53.91,14.27 54.81,14.27 56.08,13 56.7,13 57.79,11.9 74.8,11.9 75.2,11.5 79.82,11.5 80.1,11.79 83.64,11.79 84.13,12.28 88.73,12.28 90.58,14.13 92.99,14.13 94.36,12.76 96.62,12.76 96.86,12.99 103.15,12.99 103.68,12.46 118.58,12.46 120.64,14.52 121.81,14.52 122.75,15.46 122.75,16.23 126.24,19.71 126.24,20.98 128.02,22.77 128.02,24.4 129.48,25.86 129.48,31.66 131.41,33.59 131.41,35.08
  BOTTOM w0.076: UC1.H6 130.64,37.28 v2(130.96,36.95)
  BOTTOM w0.094: v2(38.95,34.33) 39.33,33.94 39.33,33.87 39.24,33.78 38.19,33.78 36.38,35.59 30.02,35.59 28.73,34.3 25.68,34.3 25.1,33.72 25.1,28.89 23.43,27.22 22.11,27.22 R3418.2
USB3_CRX_DTX_P2_C: length 10.5
  BOTTOM w0.094: JUSB2.6 13.6,24.58 13.81,24.37 14.09,24.37 14.74,25.03 16.67,25.03 17.21,25.56 v3(17.21,26.5) 17.21,27.04 17.58,27.4 17.89,27.4 18.05,27.56 U3403.2 U3403.8 19.59,27.56 19.76,27.39 19.97,27.39 20.13,27.22 20.47,27.22 R3418.1
USB3_CRX_DTX_P3: length 117
  IN3 w0.135: v2(130.33,38.79) 130.83,39.22 133.65,39.22 134.33,38.54 136.14,38.54 136.64,39.05 138.88,39.05 139.5,38.43 139.5,31.01 140.86,29.65 140.86,25.85 145.28,21.43 151.47,21.43 152.32,20.57 180.07,20.57 181.86,22.36 191.37,22.36 198.06,29.05 198.06,50.49 202.36,54.78 203.45,54.78 v2(203.62,54.61)
  BOTTOM w0.076: v2(130.33,38.79) UC1.H10
  BOTTOM w0.094: v2(203.62,54.61) 203.82,54.81 203.97,54.81 204.13,54.66 JIO1.11
USB3_CTX_DRX_N1: length 184.4
  IN3 w0.135: v2(21.87,48.76) 24.24,48.76 25.35,49.88 28.2,49.88 32.29,53.97 33.42,53.97 34.89,52.5 34.89,47.56 35.85,46.59 35.85,41.61 35.6,41.36 35.6,33.41 35.35,33.16 35.35,32.57 36.16,31.77 36.16,30.93 38.27,28.82 38.5,28.82 43.45,23.87 43.45,18.06 47.78,13.72 48.9,13.72 51.9,10.72 52.9,10.72 53.28,10.35 53.28,9.49 53.95,8.82 56.2,8.82 56.55,8.47 79.68,8.47 80.22,9 82.49,9 83.33,8.16 87.29,8.16 88.25,9.13 89.57,9.13 90.28,8.42 112.01,8.42 112.51,8.92 114.45,8.92 114.95,8.42 121.11,8.42 126.52,13.84 126.52,15.62 129.33,18.43 129.33,18.74 132.61,22.01 132.61,24.94 135.12,27.45 135.12,29.01 137.66,31.55 137.66,36.43 138.01,36.79 138.01,37.95 138.12,38.06 138.42,38.06 v2(138.59,37.89)
  BOTTOM w0.076: UC1.C13 133.84,41.01 133.76,40.93 133.76,40.86 133.89,40.72 134.19,40.72 134.34,40.87 134.34,41.17 134.38,41.2 134.61,41.28 134.75,41.28 134.94,41.22 135.09,41.22 135.21,41.28 135.46,41.28 135.97,40.78 136.4,40.78 136.41,40.77 136.43,40.77
  BOTTOM w0.094: v2(138.59,37.89) 138.44,38.04 138.02,38.04 137.77,38.29 137.77,39.36 137.19,39.94 v3(137.19,40.2) 137.19,40.5 136.92,40.77 136.43,40.77 ; v2(21.87,48.76) 21.63,49 21.42,49 C3403.1
USB3_CTX_DRX_N1_C: length 8.8
  BOTTOM w0.094: JUSB1.8 12.39,50.93 12.55,51.09 14.46,51.09 14.73,50.82 v3(14.73,49.78) 14.73,49.15 14.91,48.97 15.09,48.97 15.31,48.76 U3402.4 U3402.7 16.77,48.76 16.99,48.97 17.72,48.97 R3409.1
USB3_CTX_DRX_N1_R: length 1.5
  BOTTOM w0.094: C3403.2 19.8,48.99 19.31,48.99 R3409.2
USB3_CTX_DRX_N2: length 164.9
  IN3 w0.135: v2(36.43,36.88) 36.59,37.04 36.73,37.04 36.89,36.88 36.89,31.16 38.48,29.57 38.72,29.57 44.38,23.92 44.38,20.77 46.42,18.73 46.42,17.78 50.99,13.21 50.99,12.73 52.2,11.52 53.08,11.52 54.33,10.27 55.74,10.27 56.86,9.15 63.63,9.15 64.22,9.75 64.98,9.75 65.54,9.18 79.43,9.18 79.99,9.74 82.87,9.74 83.63,8.97 87.02,8.97 88.25,10.2 89.88,10.2 90.4,10.73 92.03,10.73 93.02,9.74 93.46,9.74 94.05,9.15 111.55,9.15 112.01,9.61 114.84,9.61 115.3,9.15 120.86,9.15 125.84,14.12 125.84,15.9 128.65,18.71 128.65,19.02 131.92,22.3 131.92,25.22 134.38,27.68 134.38,29.55 135.59,30.77 135.59,33.13 136.36,33.9 136.36,37.75 136.69,38.07 137.14,38.07 v2(137.32,37.89)
  BOTTOM w0.094: v2(137.32,37.89) 137.12,38.09 136.75,38.09 136.46,38.39 136.46,40.02 136.27,40.21 135.13,40.21 134.88,40.46 134.88,40.8 UC1.B13 ; C3406.1 24.21,28.84 24.45,28.84 24.71,29.09 24.71,33.89 25.52,34.7 28.5,34.7 29.82,36.02 32.95,36.02 33.81,36.88 v2(36.43,36.88)
USB3_CTX_DRX_N2_C: length 10.8
  BOTTOM w0.094: JUSB2.8 13.6,30.06 13.7,30.16 14.05,30.16 14.74,29.48 16.27,29.48 16.59,29.8 17,30.21 17.48,30.21 17.65,30.03 17.65,29.81 17.27,29.43 v3(17.27,29.12) 17.27,28.91 17.45,28.72 17.84,28.72 17.99,28.56 U3403.4 U3403.7 19.61,28.56 19.78,28.74 19.88,28.74 20.04,28.9 20.46,28.9 R3419.1
USB3_CTX_DRX_N2_R: length 1.5
  BOTTOM w0.094: R3419.2 22.1,28.89 22.64,28.89 C3406.2
USB3_CTX_DRX_N3: length 161.6
  IN3 w0.135: v2(136,42.01) 136.19,42.01 136.32,42.14 136.32,42.33 134.25,44.39 134.25,56.48 135.61,57.84 137.01,57.84 139.93,60.76 139.93,63.22 140.3,63.58 140.3,66.77 140.64,67.11 140.64,67.44 141.74,68.54 141.74,72.69 142.18,73.13 142.18,76.87 141.5,77.54 141.5,80.4 142.48,81.37 142.48,91.22 148.6,97.34 171.56,97.34 173.28,95.62 173.28,89.51 173.71,89.08 173.71,63.13 178.96,57.88 188.76,57.88 189.67,58.79 199.96,58.79 201.45,57.3 201.45,56.76 201.62,56.59 201.98,56.59 v2(202.14,56.75)
  BOTTOM w0.076: UC1.B15 134.66,42.43 134.72,42.49 134.93,42.49 135.02,42.4 135.02,42.06 135.17,41.9 135.57,41.9 135.85,42.18 135.9,42.18 136,42.09 v2(136,42.01)
  BOTTOM w0.094: JIO1.13 204.18,53.66 204.03,53.5 203.58,53.5 203.09,53.98 203.09,56.08 202.69,56.48 202.41,56.48 v2(202.14,56.75)
USB3_CTX_DRX_P1: length 184.4
  IN3 w0.135: v2(138.61,38.48) 138.43,38.3 138.02,38.3 137.77,38.05 137.77,36.89 137.42,36.54 137.42,31.66 134.88,29.12 134.88,27.56 132.36,25.04 132.36,22.12 129.09,18.84 129.09,18.53 126.28,15.72 126.28,13.94 121.01,8.67 115.05,8.67 114.55,9.17 112.41,9.17 111.91,8.67 90.38,8.67 89.67,9.37 88.15,9.37 87.19,8.41 83.43,8.41 82.59,9.24 80.12,9.24 79.58,8.71 56.66,8.71 56.3,9.07 54.05,9.07 53.52,9.59 53.52,10.45 53,10.97 52,10.97 49,13.97 47.88,13.97 43.69,18.16 43.69,23.97 38.6,29.07 38.37,29.07 36.4,31.03 36.4,31.87 35.6,32.67 35.6,33.06 35.84,33.31 35.84,41.26 36.1,41.51 36.1,46.69 35.13,47.66 35.13,52.6 33.52,54.21 32.19,54.21 28.1,50.12 25.25,50.12 24.14,49.01 22.34,49.01 v2(21.88,49.46)
  BOTTOM w0.076: UC1.D13 133.73,41.22 133.83,41.28 134,41.37 134.35,41.37 134.58,41.45 134.77,41.45 134.89,41.41 135.08,41.41 135.14,41.43 135.17,41.45 135.53,41.45 136.03,40.94 136.4,40.94 136.41,40.95 136.43,40.95
  BOTTOM w0.094: C3404.1 21.4,49.18 21.61,49.18 v2(21.88,49.46) ; 136.43,40.95 136.99,40.95 137.41,40.54 137.41,39.98 137.95,39.43 137.95,38.36 138.09,38.22 138.35,38.22 v2(138.61,38.48)
USB3_CTX_DRX_P1_C: length 8.8
  BOTTOM w0.094: JUSB1.9 12.39,51.43 12.54,51.27 14.6,51.27 v3(14.77,51.1) 14.91,50.96 14.91,50.15 14.96,50.11 14.96,49.49 14.91,49.44 14.91,49.22 14.99,49.15 15.13,49.15 15.24,49.25 U3402.5 U3402.6 16.77,49.25 16.87,49.15 17.68,49.15 R3408.1
USB3_CTX_DRX_P1_R: length 1.5
  BOTTOM w0.094: C3404.2 19.79,49.17 19.32,49.17 R3408.2
USB3_CTX_DRX_P2: length 165
  IN3 w0.135: v2(36.43,37.46) 36.6,37.28 36.83,37.28 37.14,36.98 37.14,31.26 38.58,29.82 38.82,29.82 44.62,24.02 44.62,20.87 46.66,18.83 46.66,17.88 51.24,13.31 51.24,12.83 52.3,11.77 53.18,11.77 54.44,10.51 55.84,10.51 56.96,9.4 63.52,9.4 64.12,9.99 65.08,9.99 65.64,9.43 79.33,9.43 79.89,9.98 82.97,9.98 83.73,9.22 86.92,9.22 88.15,10.45 89.78,10.45 90.3,10.97 92.13,10.97 93.12,9.98 93.56,9.98 94.15,9.4 111.45,9.4 111.91,9.86 114.94,9.86 115.41,9.4 120.76,9.4 125.59,14.23 125.59,16 128.41,18.81 128.41,19.13 131.68,22.4 131.68,25.32 134.13,27.78 134.13,29.65 135.35,30.87 135.35,33.23 136.12,34.01 136.12,37.85 136.58,38.32 137.16,38.32 v2(137.32,38.48)
  BOTTOM w0.094: C3405.1 23.9,29.33 24.22,29.02 24.38,29.02 24.52,29.17 24.52,33.96 25.44,34.88 28.43,34.88 29.75,36.2 32.87,36.2 33.73,37.06 36.03,37.06 v2(36.43,37.46) ; UC1.A13 135.2,41.01 135.06,40.88 135.06,40.54 135.21,40.39 136.35,40.39 136.64,40.1 136.64,38.46 136.83,38.28 137.12,38.28 v2(137.32,38.48)
USB3_CTX_DRX_P2_C: length 10.8
  BOTTOM w0.094: JUSB2.9 13.6,30.44 13.69,30.35 14.13,30.35 14.81,29.66 16.2,29.66 16.96,30.43 v3(17.29,30.43) 17.52,30.43 17.83,30.11 17.83,29.73 17.49,29.39 17.49,28.98 17.56,28.9 17.88,28.9 18.04,29.06 U3403.5 U3403.6 19.56,29.06 19.71,28.92 19.8,28.92 19.97,29.08 20.49,29.08 R3416.1
USB3_CTX_DRX_P2_R: length 1.5
  BOTTOM w0.094: C3405.2 22.64,29.07 22.1,29.07 R3416.2
USB3_CTX_DRX_P3: length 161.6
  IN3 w0.135: v2(136.88,41.99) 136.69,41.99 136.56,42.11 136.56,42.43 134.5,44.5 134.5,56.38 135.72,57.6 137.11,57.6 140.18,60.66 140.18,63.11 140.54,63.48 140.54,66.67 140.88,67.01 140.88,67.34 141.98,68.44 141.98,72.59 142.42,73.03 142.42,76.97 141.75,77.64 141.75,80.3 142.72,81.27 142.72,91.12 148.7,97.1 171.46,97.1 173.04,95.52 173.04,89.41 173.47,88.98 173.47,63.03 178.85,57.64 188.86,57.64 189.77,58.54 199.86,58.54 201.21,57.2 201.21,56.66 201.52,56.35 202,56.35 202.15,56.19 v2(202.15,56)
  BOTTOM w0.076: 136.18,42.37 135.81,42.37 135.5,42.07 135.24,42.07 135.18,42.13 135.18,42.23 UC1.A15
  BOTTOM w0.094: 136.18,42.37 136.24,42.37 136.62,41.99 v2(136.88,41.99) ; JIO1.14 204.17,53.16 204.01,53.31 203.5,53.31 202.91,53.91 202.91,56 202.61,56.3 202.45,56.3 v2(202.15,56)
USB_EN#: length 230.6
  TOP w0.102: UE1.13 37.94,40.59 37.57,40.95 37.57,41.33 v2(38,41.77) ; v2(22.18,41.21) 21.8,41.21 21.44,40.85 v1(21.11,40.85) 19.6,40.85 RE388.1 18.25,40.44 U3504.4
  IN2 w0.127: v2(173.79,14.57) 173.26,14.04 161.68,14.04 159.94,15.78 145.53,15.78 144.94,15.18 139.58,15.18 137.66,13.27 132.77,13.27 131.74,12.24 130.31,12.24 129.47,13.08 116.63,13.08 115.6,14.1 104,14.1 103.67,14.43 102.97,14.43 101.97,15.44 100.52,15.44 99.37,16.59 99.37,18.15 96.07,21.45 96.07,22.23 94.47,23.82 92.64,23.82 83.9,15.08 82.68,15.08 82.24,14.64 79.75,14.64 79.06,13.95 59.39,13.95 57.76,15.58 57.33,15.58 56.36,16.54 52.2,16.54 50.17,18.57 50.17,25.76 51.59,27.19 51.59,28.81 50.93,29.47 50.93,33.94 48.77,36.1 46.16,36.1 44.28,37.98 44.28,38.62 41,41.89 38.13,41.89 v2(38,41.77)
  BOTTOM w0.102: v2(22.18,41.21) 22.56,41.21 23.19,40.57 23.78,40.57 24.11,40.24 24.11,37.9 24.82,37.19 26.01,37.19 26.39,36.81 27.08,36.81 27.97,37.7 27.97,38.62 30.21,40.86 32.28,40.86 33.97,42.55 34.7,42.55 35.16,42.1 37.67,42.1 v2(38,41.77) ; U3505.4 199.1,20.09 198.56,20.63 196.68,20.63 193.45,17.41 193.45,15.2 192.82,14.57 v2(173.79,14.57)
USB_OC#0: length 188.1
  TOP w0.254: v2(22.1,40.56) 21.71,40.56 20.86,39.71 20.86,39.23 v1(20.51,38.88) 19.1,37.47 U3504.3
  IN2 w0.127: v2(133.23,8.59) 132.82,8.19 127.56,8.19 126.01,9.74 122.84,9.74 121.18,8.08 89.9,8.08 88.75,9.23 87.89,9.23 86.74,8.08 57.65,8.08 55.13,10.6 50.87,10.6 48.94,12.53 42.54,12.53 40.1,10.09 39.14,10.09 38.57,10.66 35.77,10.66 34.99,11.44 34.99,14.22 35.31,14.54 35.31,19.39 34.81,19.88 34.81,25.06 34.48,25.39 34.48,28.18 33.27,29.39 33.27,30.36 30.53,33.1 29.16,33.1 26.34,35.92 22.04,35.92 21.42,36.55 21.42,40.17 21.81,40.56 v2(22.1,40.56)
  IN3 w0.135: v2(138.84,35.97) 138.46,35.97 138.1,35.62 138.1,31.35 140.16,29.3 140.16,25.56 140.42,25.3 140.42,25 141.44,23.97 141.44,22.49 139.87,20.91 139.87,18.13 140.26,17.73 140.26,16.05 139.12,14.91 138.49,14.91 134.97,11.38 134.97,10.33 v2(133.23,8.59)
  BOTTOM w0.102: RPC3.3 139.07,35.74 v2(138.84,35.97) 137.7,35.97 136.45,37.22 136.45,37.34 135.31,38.48 UC1.A9
  BOTTOM w0.254: UUS5.13 v2(22.1,40.56)
USB_OC#1: length 82.8
  IN3 w0.135: v2(195.64,20.44) 194.13,18.93 153.15,18.93 151.1,20.99 142.9,20.99 141.71,22.18 141.71,24.07 140.68,25.1 140.68,25.41 140.42,25.66 140.42,29.4 138.59,31.24 v2(138.59,35.39)
  BOTTOM w0.102: RPC3.2 138.73,35.24 v2(138.59,35.39) 137.93,35.39 136.1,37.22 136.1,37.42 135.51,38.01 134.77,38.01 134.24,38.54 UC1.C9 ; v1(194.93,20.44) v2(195.64,20.44) 196.06,20.86 198.76,20.86 199.1,21.2 U3505.3
USB_OC#2: length 8.4
  BOTTOM w0.102: UC1.D9 133.36,37.86 133.55,37.68 133.88,37.68 133.94,37.73 134.17,37.73 134.24,37.65 134.5,37.65 134.55,37.7 135.55,37.7 135.87,37.38 135.87,37.07 138.01,34.93 v1(138.24,34.93) 138.42,34.74 RPC3.1
USB_OC#3: length 6.3
  BOTTOM w0.102: UC1.B9 135.02,38.9 135.49,38.9 135.94,38.44 135.94,38.18 136.68,37.43 136.68,37.32 137.11,36.89 v1(137.95,36.89) 138.54,36.89 139.18,36.24 RPC3.4
USB_PN1: length 146.5
  IN3 w0.076: 124.12,35.07 124.13,35.08 124.17,35.08 125.1,36.01 125.1,38.43 124.94,38.59 124.76,38.59 124.64,38.47 v2(124.64,38.2)
  IN3 w0.135: 124.12,35.07 123.38,34.34 123.38,30.67 122.62,29.9 122.62,25.64 116.49,19.5 115.11,19.5 113.96,18.36 110.98,18.36 110.76,18.14 107.01,18.14 105.1,20.06 94.54,20.06 94.37,20.23 90.73,20.23 90.16,19.66 87.45,19.66 85.25,17.45 84.26,17.45 83.7,16.89 81.29,16.89 80.61,16.21 78.96,16.21 78.19,15.44 77.13,15.44 76.69,15.88 59.44,15.88 58.32,17 57.79,17 56.14,18.65 55.09,18.65 52.66,21.09 52.66,27.33 49.78,30.21 47.3,30.21 46.3,31.21 46.3,32.53 46.76,33 46.76,35.64 44.28,38.13 42.81,38.13 42.61,38.33 v2(42.61,38.52)
  BOTTOM w0.094: UUS5.2 19.9,37.85 19.58,37.53 19.58,37.35 19.98,36.96 21.35,36.96 22.81,35.5 26.85,35.5 29.22,37.87 29.22,38.66 30.13,39.57 31.02,39.57 31.79,38.8 36,38.8 36.59,39.38 39.67,39.38 40.95,38.11 42.61,38.11 42.73,38.24 42.73,38.4 v2(42.61,38.52)
  BOTTOM w0.102: UC1.AB9 v2(124.64,38.2)
USB_PN1_CHR: length 10.4
  TOP w0.094: v2(19.06,44.43) 18.91,44.58 18.91,45.4 19.54,46.03 20.92,46.03 21.92,47.03 21.92,47.82 21.68,48.06 21.26,48.06 21.13,48.19 TR3404.2
  BOTTOM w0.094: v2(19.06,44.43) 18.85,44.22 18.85,43.99 19.74,43.1 19.74,41.96 19.9,41.79 UUS5.11
USB_PN1_CHR_C: length 12.3
  TOP w0.094: JUSB1.2 11.09,48.06 11.14,48 11.26,48 12.16,48.89 12.93,48.89 13.39,49.35 13.44,49.35 13.82,49.73 v3(14.42,49.73) 15.57,49.73 17.06,48.25 17.33,48.25 17.45,48.37 EU3403.3 17.83,48.78 17.83,48.38 17.93,48.28 18.29,48.28 18.56,48.02 18.92,48.02 19.09,48.19 TR3404.1
USB_PN2: length 134.7
  TOP w0.094: v2(46.94,31.84) 46.73,31.62 44.51,31.62 44.16,31.28 42.09,31.28 41.07,30.26 40.21,30.26 38.94,28.99 33.99,28.99 33.41,29.57 33.41,30.56 32.46,31.5 32.46,33.21 31.7,33.97 30.61,33.97 30.48,34.1 24.6,34.1 22.81,32.31 22.81,31.76 22.64,31.59 TR3405.2
  IN3 w0.076: 123.19,35.36 123.23,35.36 124.04,36.17 124.04,36.6 123.95,36.69 123.73,36.69 123.6,36.57 v2(123.6,36.29)
  IN3 w0.135: v2(46.94,31.84) 47.17,31.61 48.43,31.61 48.96,31.07 50.03,31.07 53.34,27.76 53.34,21.37 55.32,19.39 56.39,19.39 58.04,17.74 58.58,17.74 59.75,16.57 77.04,16.57 77.49,16.12 77.9,16.12 78.7,16.91 80.34,16.91 81,17.58 83.41,17.58 83.99,18.15 84.97,18.15 87.8,20.98 94.72,20.98 94.96,20.74 105.53,20.74 106.9,19.38 109.96,19.38 110.28,19.06 113.69,19.06 114.82,20.19 116.21,20.19 121.77,25.75 121.77,30.02 122.59,30.85 122.59,34.77 123.19,35.36 123.19,35.36
  BOTTOM w0.102: UC1.AD6 v2(123.6,36.29)
USB_PN2_C: length 11.8
  TOP w0.094: JUSB2.2 15.1,27.36 15.24,27.22 v3(16.06,27.22) 16.64,27.22 17.65,28.23 18.14,28.23 18.29,28.38 EU3404.2 18.65,28.74 18.65,28.33 18.77,28.21 18.95,28.21 19.91,29.16 21.89,29.16 21.92,29.2 22.51,29.2 22.55,29.16 22.66,29.16 22.82,29.33 22.82,29.64 22.64,29.82 TR3405.1
USB_PN3: length 119
  IN1 w0.114: v2(120.54,35.99) 120.12,35.58 120.12,35.42 120.71,34.84 120.71,34.61 121.48,33.84 122.4,33.84 123.77,32.48 125.7,32.48 128.1,30.07 128.1,25.81 129.3,24.61 129.3,22.87 130.58,21.6 130.58,21.43 133.72,18.3 139.94,18.3 144.25,13.99 156.23,13.99 156.67,14.43 158.23,14.43 158.75,14.96 161,14.96 161.89,14.07 188.27,14.07 189.13,14.94 189.13,15.64 v2(189.01,15.76)
  BOTTOM w0.076: v2(120.54,35.99) 120.57,35.99 120.57,35.99 120.53,35.95 UC1.AH3
  BOTTOM w0.094: TR3406.2 200.69,44.5 200.53,44.35 200.08,44.35 198.49,42.75 198.49,29.48 189.21,20.2 v3(189.21,19.49) 189.21,15.97 v2(189.01,15.76)
USB_PN3_C: length 3
  BOTTOM w0.094: TR3406.1 202.45,44.5 202.59,44.36 202.83,44.36 203.15,44.04 203.7,44.04 203.74,44 204.08,44 204.23,44.16 JIO1.32
USB_PN4: length 103.6
  TOP w0.094: TR5802.2 207.75,15.24 207.59,15.4 207.1,15.4 v2(206.9,15.2)
  IN1 w0.114: v2(123.56,38.72) 123.75,38.91 123.91,38.91 124,38.81 124,36.07 124.77,35.3 126.15,35.3 128.17,33.28 128.17,31.62 129.14,30.65 129.14,26.24 130.34,25.04 130.34,23.32 131.62,22.04 131.62,21.87 134.15,19.34 140.47,19.34 142.64,17.16 143.38,17.16 145.38,15.16 154.95,15.16 155.67,15.88 158.2,15.88 158.32,16 160.6,16 160.88,16.27 162.29,16.27 162.63,15.93 185.52,15.93 186.7,17.11 193.19,17.11 195.31,14.99 202.31,14.99 202.71,15.39 206.71,15.39 v2(206.9,15.2)
  BOTTOM w0.076: v2(123.56,38.72) 123.41,38.57 UC1.AD9
USB_PN4_C: length 4.7
  TOP w0.094: TR5802.1 209.53,15.24 209.8,15.51 v3(210.37,15.51) 210.64,15.51 210.96,15.19 210.96,14.8 v2(210.68,14.52)
  BOTTOM w0.094: v2(210.68,14.52) 210.96,14.52 211.05,14.42 211.05,14.21 210.35,13.5 JIO2.2
USB_PN5: length 167.6
  IN3 w0.135: v2(118.16,31.39) 117.37,31.39 116.68,30.7 116.68,27.35 115.47,26.15 115.47,22.43 113.25,20.2 110.73,20.2 110.41,20.52 107.6,20.52 105.32,22.8 95.51,22.8 94.53,23.77 92.53,23.77 91.23,22.48 87.71,22.48 84.56,19.33 83.51,19.33 83.01,18.83 80.67,18.83 79.88,18.04 76.81,18.04 76.46,17.69 70.47,17.69 69.68,18.48 68.11,18.48 67.32,17.69 60.31,17.69 59.11,18.89 58.55,18.89 57.58,19.86 57.58,20.5 55.86,22.22 55.86,28.9 50.78,33.98 50.78,40.3 47.97,43.11 47.97,56.97 45.75,59.19 45.75,70.29 45.08,70.96 45.08,90 47.3,92.22 v2(48.56,92.22)
  BOTTOM w0.076: 119.58,32.57 119.58,32.59 119.57,32.6 119.57,33.59 UC1.AJ1
  BOTTOM w0.094: v2(48.56,92.22) 48.56,92.05 48.88,91.73 54.47,91.73 55.3,92.57 55.3,92.72 55.27,92.75 55.27,93.27 55.08,93.46 54.87,93.46 54.55,93.14 TR5209.2 ; v2(118.16,31.39) 118.16,31.66 118.56,32.06 119.27,32.06 119.58,32.37 119.58,32.57
USB_PN5_C: length 6.1
  BOTTOM w0.094: TR5209.1 52.79,93.14 52.72,93.21 52.1,93.21 51.89,93.43 v3(51.89,93.75) 51.89,94.02 51.77,94.13 EU3405.7 EU3405.4 51.77,95.99 51.98,96.2 51.98,96.43 52.43,96.88 52.43,97.01 52.27,97.17 JEDP.31
USB_PN6: length 115.4
  IN1 w0.114: v2(122.48,36.36) 122.68,36.55 122.89,36.55 123.02,36.42 123.02,35.64 124.06,34.6 124.25,34.6 128.52,30.33 128.52,25.98 129.72,24.78 129.72,23.06 131,21.79 131,21.61 133.89,18.72 140.17,18.72 144.35,14.54 155.21,14.54 155.93,15.25 158.46,15.25 158.58,15.37 160.86,15.37 161.13,15.65 161.94,15.65 162.29,15.29 185.95,15.29 187.06,16.41 190.29,16.41 190.65,16.05 190.65,15.88 v2(190.48,15.71)
  BOTTOM w0.089: v2(122.48,36.36) 122.22,36.62 UC1.AF6
  BOTTOM w0.094: v2(190.48,15.71) 190.68,15.91 v3(190.68,17.93) 190.68,20.66 199.07,29.05 199.07,41.49 200.08,42.5 200.59,42.5 200.75,42.66 TR5803.2
USB_PN6_C: length 2.8
  BOTTOM w0.094: JIO1.35 204.25,42.66 204.1,42.5 203.71,42.5 203.67,42.55 203.06,42.55 203.02,42.5 202.6,42.5 202.45,42.66 TR5803.1
USB_PN7: length 167.2
  TOP w0.094: TR5201.2 47.71,96.58 47.55,96.41 47.55,94.91 47.98,94.48 48.24,94.48 48.47,94.71 v2(48.47,94.82)
  IN3 w0.135: v2(120.06,32.96) 119.87,33.15 119.59,33.15 119.42,32.99 119.42,30.93 118.17,29.68 118.17,27.78 116.16,25.78 116.16,22.14 113.53,19.51 110.44,19.51 110.13,19.83 107.08,19.83 104.8,22.11 102.42,22.11 101.65,21.34 98.16,21.34 97.8,21.7 95.42,21.7 94.81,22.31 92.14,22.31 91.35,21.52 87.72,21.52 84.8,18.6 83.77,18.6 83.3,18.13 80.94,18.13 80.16,17.36 77.13,17.36 76.78,17.01 59.98,17.01 58.81,18.18 58.27,18.18 56.11,20.34 55.15,20.34 54.38,21.1 54.38,29.21 49.77,33.82 49.77,40.05 47.28,42.54 47.28,53.97 44.61,56.64 44.61,67.25 43.62,68.24 43.62,76.58 44.4,77.36 44.4,90.58 47.07,93.24 47.07,94.27 47.49,94.69 48.35,94.69 v2(48.47,94.82)
  BOTTOM w0.076: v2(120.06,32.96) 120.42,33.32 120.45,33.32 120.72,33.59 120.72,34.02 UC1.AH1
USB_PN7_C: length 2.7
  TOP w0.094: TR5201.1 47.71,98.49 47.59,98.61 47.59,98.95 v2(47.81,99.17)
  BOTTOM w0.094: v2(47.81,99.17) 47.59,98.95 47.59,98.67 47.77,98.5 JEDP.22
USB_PN8: length 128.7
  IN3 w0.135: v2(185.13,24.18) 185.52,24.17 185.66,24.31 185.66,24.61 185.44,24.83 184.77,24.83 184.41,24.47 181.66,24.47 178.45,21.26 152.76,21.26 151.9,22.11 145.58,22.11 141.56,26.13 141.56,29.96 140.31,31.2 140.31,38.91 139.35,39.87 130.88,39.87 130.27,40.48 130.27,41.78 130.08,41.97 128.43,41.97 127.98,41.52 126.84,41.52 126.34,41.02 125.76,41.02 124.93,40.19 124.73,40.19 123.22,40.19 122.71,39.68 122.71,38.13 122.43,37.85 121.75,37.85 v2(121.57,37.67)
  BOTTOM w0.094: v2(185.13,24.18) 185.22,24.18 185.53,24.49 185.53,25.08 185.01,25.61 185.01,28.7 192.56,36.25 193.9,36.25 196.64,38.99 196.64,56.67 197.83,57.86 197.83,59.49 197.67,59.65 WLAN1.5
  BOTTOM w0.102: UC1.AF8 v2(121.57,37.67)
USB_PN9: length 122.6
  IN1 w0.114: v2(191.66,15.67) 191.88,15.89 191.88,16.37 192.19,16.68 192.98,16.68 193.5,16.16 193.5,15.04 191.7,13.25 161.53,13.25 160.65,14.13 159.1,14.13 158.57,13.6 157.02,13.6 156.58,13.16 143.9,13.16 139.6,17.47 133.36,17.47 130.92,19.91 130.46,19.91 129.33,21.04 129.33,21.68 128.48,22.53 128.48,24.27 127.19,25.56 127.19,29.82 125.35,31.65 123.03,31.65 122.71,31.97 121.77,31.97 121.37,31.57 120.97,31.57 120.81,31.73 v2(120.54,31.73)
  BOTTOM w0.076: UC1.AG1 121.31,34 121.36,34 121.44,33.93 121.44,33.45 120.91,32.91 120.89,32.91 120.88,32.9
  BOTTOM w0.094: v2(191.66,15.67) 191.87,15.88 v3(191.87,19.98) 191.87,20.9 199.66,28.68 199.66,40.22 200.11,40.67 200.6,40.67 200.75,40.82 TR5804.2 ; 120.88,32.9 120.65,32.67 120.65,32.32 120.73,32.25 120.73,31.92 v2(120.54,31.73)
USB_PN9_C: length 2.9
  BOTTOM w0.094: TR5804.1 202.48,40.82 202.64,40.66 202.93,40.66 202.97,40.7 203.52,40.7 203.81,41 204.12,41 204.28,41.16 JIO1.38
USB_POWERSHARE_VBUS_EN: length 31.6
  TOP w0.102: RE448.1 25.4,55.68 25,55.28 v1(25,55.02) 25,54.73 23.94,53.67 21.12,53.67 20.66,53.21 20.66,50.49 v2(20.94,50.21)
  BOTTOM w0.102: UUS5.5 17.34,39.06 15.89,37.61 R6532.1 15.87,37.59 15.08,38.37 15.08,43.06 18.24,46.22 20.91,46.22 22.29,47.6 22.29,49.7 22.04,49.95 21.6,49.95 21.34,50.21 v2(20.94,50.21)
USB_PP1: length 146.5
  IN3 w0.076: 124.29,34.9 124.3,34.91 124.3,34.95 125.28,35.93 125.28,38.51 125.02,38.77 124.8,38.77 v2(124.64,38.93)
  IN3 w0.135: v2(42.72,37.68) 42.93,37.89 44.18,37.89 46.52,35.54 46.52,33.1 46.05,32.64 46.05,31.11 47.2,29.96 49.68,29.96 52.41,27.23 52.41,20.99 54.99,18.41 56.04,18.41 57.69,16.76 58.22,16.76 59.34,15.64 76.58,15.64 77.03,15.19 78.29,15.19 79.06,15.97 80.71,15.97 81.39,16.65 83.8,16.65 84.36,17.21 85.35,17.21 87.55,19.41 90.26,19.41 90.83,19.99 94.27,19.99 94.43,19.82 105,19.82 106.91,17.9 110.86,17.9 111.08,18.12 114.07,18.12 115.21,19.26 116.59,19.26 122.86,25.54 122.86,29.8 123.63,30.57 123.63,34.23 124.29,34.9
  BOTTOM w0.094: v2(42.72,37.68) 42.47,37.93 40.87,37.93 39.6,39.2 36.67,39.2 36.08,38.61 31.72,38.61 30.94,39.39 30.21,39.39 29.4,38.59 29.4,37.79 26.93,35.31 22.74,35.31 21.28,36.77 19.9,36.77 19.4,37.27 UUS5.3 ; v2(124.64,38.93) 124.42,38.93 UC1.AB10
USB_PP1_CHR: length 10.1
  TOP w0.094: TR3404.3 21.1,47.69 21.29,47.88 21.6,47.88 21.73,47.75 21.73,47.11 20.84,46.21 19.46,46.21 18.73,45.48 18.73,44.68 v2(18.48,44.43)
  BOTTOM w0.094: UUS5.10 19.4,41.81 19.56,41.96 19.56,43.02 18.67,43.91 18.67,44.24 v2(18.48,44.43)
USB_PP1_CHR_C: length 12.3
  TOP w0.094: TR3404.4 19.09,47.69 18.95,47.83 18.48,47.83 18.21,48.1 17.93,48.1 17.83,48.01 17.83,47.61 EU3403.2 17.45,47.95 17.34,48.07 16.98,48.07 15.5,49.55 14.75,49.55 14.71,49.51 14.13,49.51 14.09,49.55 13.9,49.55 v3(13.34,48.99) 13.06,48.71 12.23,48.71 11.09,47.57 JUSB1.3
USB_PP2: length 134.7
  TOP w0.094: TR3405.3 23.14,31.61 22.99,31.76 22.99,32.23 24.68,33.92 30.41,33.92 30.53,33.79 31.63,33.79 32.28,33.13 32.28,31.43 33.23,30.48 33.23,29.49 33.91,28.81 39.01,28.81 40.28,30.08 41.15,30.08 42.16,31.09 44.23,31.09 44.58,31.44 46.75,31.44 v2(46.94,31.25)
  IN3 w0.076: 123.36,35.19 123.38,35.2 123.38,35.24 124.23,36.09 124.23,36.68 124.03,36.88 123.75,36.88 v2(123.6,37.03)
  IN3 w0.135: v2(46.94,31.25) 47.06,31.37 47.07,31.37 48.32,31.37 48.86,30.83 49.93,30.83 53.1,27.66 53.1,21.27 55.22,19.14 56.29,19.14 57.94,17.49 58.47,17.49 59.65,16.32 76.94,16.32 77.39,15.88 78,15.88 78.8,16.67 80.44,16.67 81.11,17.33 83.51,17.33 84.09,17.91 85.07,17.91 87.9,20.73 94.62,20.73 94.86,20.5 105.43,20.5 106.8,19.13 109.86,19.13 110.18,18.81 113.79,18.81 114.92,19.94 116.31,19.94 122.01,25.65 122.01,29.92 122.84,30.74 122.84,34.66 123.36,35.19
  BOTTOM w0.102: UC1.AD7 v2(123.6,37.03)
USB_PP2_C: length 11.8
  TOP w0.094: TR3405.4 23.14,29.82 23.01,29.69 23.01,29.25 22.74,28.98 v3(22.22,28.98) 19.98,28.98 19.03,28.02 18.8,28.02 18.72,27.95 18.72,27.59 EU3404.3 18.29,27.87 18.12,28.04 17.73,28.04 16.71,27.02 16.36,27.02 16.34,27 15.76,27 15.73,27.03 15.21,27.03 15.1,26.92 JUSB2.3
USB_PP3: length 119.1
  IN1 w0.114: v2(119.45,35.41) 119.85,35.41 120.51,34.75 120.51,34.52 121.39,33.64 122.32,33.64 123.68,32.27 125.61,32.27 127.9,29.99 127.9,25.73 129.1,24.53 129.1,22.79 130.38,21.51 130.38,21.35 133.63,18.09 139.86,18.09 144.17,13.79 156.32,13.79 156.76,14.23 158.31,14.23 158.84,14.75 160.92,14.75 161.8,13.87 188.35,13.87 189.34,14.85 189.34,15.51 v2(189.59,15.76)
  BOTTOM w0.076: UC1.AJ3 119.67,35.19 v2(119.45,35.41)
  BOTTOM w0.094: v2(189.59,15.76) 189.39,15.97 189.39,19.16 189.43,19.2 189.43,19.78 189.39,19.82 189.39,20.12 198.67,29.41 198.67,42.68 200.16,44.16 200.53,44.16 200.68,44 TR3406.3
USB_PP3_C: length 3
  BOTTOM w0.094: JIO1.33 204.24,43.66 204.08,43.81 v3(203.41,43.81) 203.11,43.81 202.75,44.17 202.63,44.17 202.46,44 TR3406.4
USB_PP4: length 103.6
  TOP w0.094: TR5802.3 207.75,15.74 207.59,15.58 207.1,15.58 v2(206.9,15.78)
  IN1 w0.114: v2(123.56,39.28) 123.73,39.11 123.99,39.11 124.21,38.89 124.21,36.15 124.86,35.5 126.24,35.5 128.38,33.37 128.38,31.71 129.35,30.74 129.35,26.33 130.55,25.13 130.55,23.4 131.82,22.13 131.82,21.95 134.23,19.54 140.55,19.54 142.73,17.36 143.46,17.36 145.46,15.36 154.87,15.36 155.59,16.08 158.12,16.08 158.24,16.2 160.52,16.2 160.79,16.47 162.38,16.47 162.71,16.14 185.44,16.14 186.62,17.32 193.27,17.32 195.39,15.2 202.23,15.2 202.62,15.59 206.71,15.59 v2(206.9,15.78)
  BOTTOM w0.076: v2(123.56,39.28) 123.41,39.12 123.16,39.12 UC1.AD10
USB_PP4_C: length 4.6
  TOP w0.094: v2(211.46,14.74) 211.15,15.05 211.15,15.27 210.68,15.73 209.77,15.73 209.7,15.66 209.65,15.66 209.57,15.74 TR5802.4
  BOTTOM w0.094: v2(211.46,14.74) 211.24,14.52 211.24,14.05 211.6,13.68 JIO2.3
USB_PP5: length 167.5
  IN3 w0.135: v2(48.53,91.5) 48.53,91.64 48.2,91.97 47.4,91.97 45.33,89.9 45.33,71.06 45.99,70.39 45.99,59.29 48.21,57.07 48.21,43.21 51.02,40.41 51.02,34.08 56.11,28.99 56.11,22.31 57.82,20.6 57.82,19.97 58.65,19.13 59.21,19.13 60.41,17.93 67.22,17.93 68.01,18.72 69.78,18.72 70.57,17.93 76.36,17.93 76.71,18.29 79.78,18.29 80.57,19.07 82.91,19.07 83.41,19.58 84.46,19.58 87.61,22.72 91.13,22.72 92.43,24.02 94.64,24.02 95.61,23.04 105.42,23.04 107.7,20.76 110.51,20.76 110.83,20.44 113.14,20.44 115.23,22.53 115.23,26.25 116.43,27.45 116.43,30.8 117.27,31.63 117.78,31.63 118.17,32.02 v2(118.17,32.24)
  BOTTOM w0.076: 119.4,32.57 119.4,32.59 119.41,32.6 119.41,33.66 119.61,33.86 119.61,34.03 UC1.AJ2
  BOTTOM w0.094: v2(118.17,32.24) 119.2,32.24 119.4,32.44 119.4,32.57 ; TR5209.3 55.16,93.64 55.49,93.31 v3(55.49,93.05) 55.49,92.49 54.54,91.55 48.58,91.55 v2(48.53,91.5)
USB_PP5_C: length 6.1
  BOTTOM w0.094: TR5209.4 52.76,93.64 52.52,93.4 52.18,93.4 52.11,93.47 52.11,94.06 51.96,94.21 51.96,94.3 52.01,94.36 52.22,94.36 52.27,94.41 EU3405.6 EU3405.5 52.27,96.09 52.16,96.2 52.16,96.35 52.61,96.8 52.61,97.01 52.77,97.17 JEDP.32
USB_PP6: length 115.5
  IN1 w0.114: v2(122.48,36.99) 122.71,36.76 122.96,36.76 123.22,36.51 123.22,35.73 124.14,34.81 124.33,34.81 128.72,30.41 128.72,26.07 129.93,24.87 129.93,23.15 131.2,21.87 131.2,21.69 133.97,18.92 140.26,18.92 144.44,14.74 155.13,14.74 155.84,15.46 158.37,15.46 158.49,15.58 160.78,15.58 161.05,15.85 162.02,15.85 162.38,15.5 185.86,15.5 186.97,16.61 190.38,16.61 190.85,16.13 190.85,15.93 v2(191.06,15.71)
  BOTTOM w0.089: v2(122.48,36.99) 122.21,37.27 UC1.AF7
  BOTTOM w0.094: v2(191.06,15.71) 190.86,15.91 190.86,17.55 190.9,17.58 190.9,18.24 190.86,18.28 190.86,20.58 199.26,28.97 199.26,41.42 200.16,42.32 200.59,42.32 200.75,42.16 TR5803.3
USB_PP6_C: length 2.8
  BOTTOM w0.094: TR5803.4 202.46,42.16 202.62,42.32 v3(203.37,42.32) 204.08,42.32 204.24,42.16 JIO1.36
USB_PP7: length 167.1
  TOP w0.094: v2(48.46,93.99) 48.16,94.29 47.9,94.29 47.36,94.83 47.36,96.42 47.21,96.57 TR5201.3
  IN3 w0.135: v2(120.37,33.74) 120.03,33.4 119.48,33.4 119.18,33.09 119.18,31.03 117.92,29.78 117.92,27.88 115.91,25.88 115.91,22.24 113.43,19.76 110.55,19.76 110.23,20.08 107.18,20.08 104.9,22.36 102.32,22.36 101.55,21.59 98.26,21.59 97.9,21.94 95.52,21.94 94.91,22.55 92.04,22.55 91.25,21.77 87.62,21.77 84.7,18.84 83.67,18.84 83.2,18.37 80.83,18.37 80.06,17.6 77.03,17.6 76.68,17.25 60.08,17.25 58.91,18.42 58.37,18.42 56.22,20.58 55.25,20.58 54.63,21.2 54.63,29.31 50.02,33.92 50.02,40.15 47.53,42.64 47.53,54.07 44.86,56.74 44.86,67.35 43.86,68.35 43.86,76.48 44.64,77.26 44.64,90.48 47.31,93.14 47.31,94.17 47.59,94.45 48.26,94.45 48.46,94.24 v2(48.46,93.99)
  BOTTOM w0.076: UC1.AH2 120.24,34.86 120.12,34.74 120.12,33.99 v2(120.37,33.74)
USB_PP7_C: length 2.7
  TOP w0.094: v2(47.23,99.17) 47.41,98.99 47.41,98.68 47.21,98.49 TR5201.4
  BOTTOM w0.094: v2(47.23,99.17) 47.41,98.99 47.41,98.68 47.27,98.54 JEDP.21
USB_PP8: length 128.7
  IN3 w0.135: v2(121.57,38.28) 121.75,38.09 122.33,38.09 122.47,38.23 122.47,39.78 123.12,40.43 124.83,40.43 125.66,41.26 126.23,41.26 126.74,41.77 127.88,41.77 128.32,42.21 130.18,42.21 130.51,41.88 130.51,40.58 130.98,40.12 139.45,40.12 140.56,39.01 140.56,31.3 141.8,30.06 141.8,26.23 145.68,22.35 152,22.35 152.86,21.5 178.35,21.5 181.56,24.71 184.31,24.71 184.67,25.08 185.54,25.08 185.91,24.71 185.91,24.36 v2(186.09,24.17)
  BOTTOM w0.094: v2(186.09,24.17) 185.71,24.55 185.71,25.16 185.19,25.68 185.19,28.62 192.64,36.07 193.98,36.07 196.82,38.91 196.82,56.59 198.01,57.78 198.01,59.49 198.17,59.65 WLAN1.3
  BOTTOM w0.102: UC1.AF9 v2(121.57,38.28)
USB_PP9: length 122.7
  IN1 w0.114: v2(121.28,32.42) 120.91,32.05 120.91,31.92 121.06,31.77 121.28,31.77 121.69,32.18 122.79,32.18 123.11,31.85 125.44,31.85 127.39,29.9 127.39,25.64 128.68,24.35 128.68,22.62 129.54,21.76 129.54,21.12 130.55,20.11 131,20.11 133.44,17.67 139.68,17.67 143.99,13.37 156.49,13.37 156.93,13.81 158.48,13.81 159.01,14.33 160.73,14.33 161.62,13.45 191.62,13.45 193.3,15.13 193.3,16.08 192.9,16.48 192.27,16.48 192.08,16.29 192.08,15.65 192.14,15.59 v2(192.56,15.59)
  BOTTOM w0.076: 121.01,32.77 121.02,32.79 121.02,32.8 121.61,33.38 121.61,33.99 121.47,34.13 UC1.AG2
  BOTTOM w0.094: v2(121.28,32.42) 121.15,32.3 120.94,32.3 120.83,32.4 120.83,32.6 121.01,32.77 ; TR5804.3 200.75,40.32 200.58,40.49 200.18,40.49 199.84,40.15 199.84,28.61 192.05,20.82 192.05,20.38 192.09,20.34 192.09,19.66 192.05,19.62 192.05,15.77 192.24,15.59 v2(192.56,15.59)
USB_PP9_C: length 2.9
  BOTTOM w0.094: JIO1.39 204.29,40.66 204.13,40.81 203.89,40.81 203.56,40.48 v3(203.27,40.48) 202.62,40.48 202.46,40.32 TR5804.4
USB_PWR_SHR_EN_L#: length 25.9
  TOP w0.102: RE449.1 25.68,52.38 24.65,53.41 21.18,53.41 20.89,53.12 20.89,50.96 21.49,50.36 v2(21.78,50.36)
  BOTTOM w0.102: v2(21.78,50.36) 22.02,50.36 22.52,49.86 22.52,47.51 21,45.99 18.48,45.99 v1(16.25,43.76) 15.46,42.97 15.46,39.07 15.88,38.65 RUS29.1
USBCHG_DET#: length 23.6
  TOP w0.102: UE1.126 30.71,42.22 29.91,41.42 29.91,40.36 29.53,39.97 v1(29.53,38.2) 29.53,37.97 28.96,37.4 28.34,37.4 RE437.1 27.33,36.51 v2(26.6,37.24) ; R6531.1 17.25,43.92 v2(17.35,43.82)
  IN3 w0.135: v2(17.35,43.82) 17.35,41.52 17.73,41.14 19.93,41.14 23.83,37.24 v2(26.6,37.24)
USBCOMP: length 2.2
  TOP w0.305: RC44.1 125.32,37.09 v1(125.14,36.91) 125.12,36.89 124.62,36.89 v2(124.58,36.92)
  BOTTOM w0.254: UC1.AB6 124.44,36.92 v2(124.58,36.92)
UUS5_CTL1: length 2.2
  BOTTOM w0.102: UUS5.6 v1(16.97,39.56) 15.95,39.56 RUS29.2
UUS5_ILIM_H: length 2.9
  BOTTOM w0.102: v1(22.75,37.61) 22.69,37.68 RUS27.1 22.42,39.06 UUS5.16
UUS5_ILIM_L: length 2.7
  BOTTOM w0.102: v1(22.6,40.7) 22.69,40.61 RUS26.1 22.42,39.48 21.77,39.48 21.69,39.56 UUS5.15
VCIN0_PH: length 120.5
  TOP w0.254: v2(124.9,19.41) 124.63,19.68 124.63,24.47 122.86,26.24 122.86,26.55 C2612.1 123.1,27.69 R2610.1
  IN1 w0.254: v2(124.9,19.41) 124.82,19.49 124.22,19.49 122.88,18.14 122.88,15.46 122.39,14.98 119.45,14.98 117.2,12.73 117.2,12 v2(117.15,11.95)
  IN2 w0.254: v2(46.03,33.38) 47.35,33.38 48.03,32.7 48.03,24.77 49.22,23.59 49.22,18.18 51.81,15.59 55.97,15.59 56.97,14.59 57.4,14.59 59,13 79.46,13 80.15,13.69 82.63,13.69 83.06,14.12 84.28,14.12 92.68,22.52 93.54,22.52 93.8,22.26 94.13,22.26 94.46,21.93 94.46,20.29 94.68,20.07 94.68,19.09 97.14,16.63 97.77,16.63 98.8,15.6 98.8,14.21 99.58,13.43 103.33,13.43 103.7,13.06 115.3,13.06 116.42,11.95 v2(117.15,11.95)
  vias: v1(46.02,32.55)
VCREF0: length 6.3
  TOP w0.102: RE396.2 RE397.1 44.17,36.67 CE91.1 ; v1(42.43,36.35) 42.75,36.67 CE91.1 ; CE91.1 43.31,36.77 43.31,38.42 42.74,38.99 UE1.25
VD_IN1_C: length 121
  TOP w0.254: v2(124.44,19.01) 124.25,19.2 124.25,24.32 122.48,26.08 122.48,26.5 C2612.2 122.19,27.69 R2610.2
  IN1 w0.254: v2(117.83,11.97) 117.76,12.05 117.76,12.66 119.68,14.58 122.63,14.58 123.37,15.32 123.37,17.94 v2(124.44,19.01)
  IN2 w0.254: v2(117.83,11.97) 117.33,12.48 116.42,12.48 115.46,13.44 103.85,13.44 103.43,13.86 99.69,13.86 99.18,14.37 99.18,15.76 97.93,17.01 97.3,17.01 95.06,19.25 95.06,20.22 94.84,20.45 94.84,22.12 94.31,22.65 93.95,22.65 93.67,22.93 92.56,22.93 84.13,14.5 82.91,14.5 82.47,14.07 79.99,14.07 79.3,13.38 59.15,13.38 57.54,14.99 57.1,14.99 56.13,15.97 51.96,15.97 49.6,18.34 49.6,23.74 48.42,24.93 48.42,32.86 47.08,34.2 v2(45.7,34.2)
  vias: v1(45.05,34.46)
VIDALERT_N: length 35.5
  TOP w0.102: PR607.1 v2(165.07,58.86) 165.07,58.59 v1(165.53,58.13)
  IN1 w0.076: v2(140.43,69.29) 140.49,69.29
  IN1 w0.114: v2(165.07,58.86) 164.65,58.44 163.82,58.44 163.64,58.62 157.03,58.62 153.46,62.2 153.46,66.41 152.5,67.36 146.89,67.36 145.65,68.61 144.25,68.61 143.57,69.29 140.49,69.29
  BOTTOM w0.076: v2(140.43,69.29) 140.46,69.29 140.49,69.33
  BOTTOM w0.102: RC152.2 140.53,69.33 140.49,69.33 ; RC153.2 139.74,69.65 140.07,69.65 v2(140.43,69.29)
VIDSCLK: length 40
  TOP w0.102: v2(165.95,58.86) PR606.1 166.02,59.55 v1(166.94,59.55)
  IN1 w0.114: v2(165.95,58.86) 165.04,57.95 163.59,57.95 163.41,58.13 156.83,58.13 152.96,62 152.96,66.2 152.31,66.85 146.71,66.85 145.44,68.12 144.02,68.12 143.39,68.75 v2(140.11,68.75)
  BOTTOM w0.089: 137.95,69.55 136.83,69.55 136.68,69.71 135.4,69.71 UC1.A63
  BOTTOM w0.102: 137.95,69.55 138.1,69.55 138.71,68.94 139.23,68.94 139.42,68.75 v2(140.11,68.75)
VIDSOUT: length 40.7
  TOP w0.102: PR609.1 164.32,59.34 v2(164.32,58.86) 164.32,58.43 v1(164.18,58.29)
  IN1 w0.114: v2(164.32,58.86) 164.06,59.12 157.24,59.12 153.95,62.41 153.95,66.61 152.69,67.88 147.08,67.88 145.85,69.11 144.52,69.11 143.7,69.92 v2(140.43,69.92)
  BOTTOM w0.076: 136.55,70.06 136.54,70.04 134.64,70.04 134.47,69.87 134.25,69.87 134.19,69.9 UC1.D64 ; 140.49,69.98 v2(140.43,69.92)
  BOTTOM w0.102: RC157.2 141.08,70.8 140.68,70.4 140.68,70.18 140.49,69.98 ; 136.55,70.06 137.78,70.06 138.2,70.48 139.69,70.48 140.25,69.92 v2(140.43,69.92)
VL: length 0.6
  TOP w0.127: v2(195.86,78.16) v4(196.5,78.16)
VR_ALERT#: length 2.7
  TOP w0.203: PU602.36 164.84,63.62 164.95,63.51 v2(164.95,63.46) 165.07,63.34 PR625.2
  BOTTOM w0.102: v2(164.95,63.46) 165.14,63.46 v1(165.46,63.77)
VR_CAP: length 3.9
  TOP w0.102: T4931.1 39.07,37.6 C5224.1 40.06,38.05 40.06,38.77 39.94,38.89 UE1.18
VR_SCLK: length 2.3
  TOP w0.203: PU602.37 165.24,63.9 165.41,63.72 165.41,63.14 PR618.2
VR_SDA: length 2.1
  TOP w0.203: PU602.35 164.44,62.85 PR626.2
VRALERT#: length 5.5
  TOP w0.089: v2(119.54,40.06) 120.04,39.56 v1(120.04,37.54) 120.04,35.87 120.17,35.75 RC73.1
  BOTTOM w0.076: v2(119.54,40.06) 119.4,40.2 UC1.AM11
VRAM_ID1: length 38.4
  TOP w0.102: v2(117.33,37.9) 117.31,37.9 116.97,37.56 116.66,37.56 116.23,37.13 116.23,36.98 116.23,36.04 115.19,35 112.01,35 110.37,33.36 110.37,29.82 108.48,27.93 107.87,27.93 106.28,26.33 105.91,26.33 104.99,25.42 104.99,24.69 105.45,24.23 105.45,21.64 104.49,20.67 100.79,20.67 100.2,21.26 100.2,22.43 99.49,23.15 v1(98.5,23.15) 98.05,22.69 97.23,22.69 96.54,23.38 RC1105.1 96.36,24.25 RC1104.2
  BOTTOM w0.089: UC1.AP8 117.75,38.32 v2(117.33,37.9)
VRAM_ID2: length 27.5
  TOP w0.102: v2(96.8,25.86) 96.54,25.6 RC1107.1 95.85,24.52 RC1106.2
  IN3 w0.135: v2(115.15,37.77) 115.06,37.68 113.42,37.68 112.07,36.33 111.09,36.33 107.2,32.44 107.2,31.46 106.29,30.55 106.29,28.62 106,28.33 105.72,28.33 104.62,27.22 101.01,27.22 99.65,25.86 v2(96.8,25.86)
  BOTTOM w0.076: v2(115.15,37.77) 115.06,37.68 114.68,37.68 UC1.AW7
VSA_SEN+: length 63.6
  TOP w0.152: v2(131,45.23) 131,45.39 131.3,45.69 134.48,45.69 135.47,44.7 136.77,44.7 137.23,44.24 137.23,43.41 138.41,42.22 142.65,42.22 RC168.2 v2(143.5,42.01)
  TOP w0.254: PR649.2 PC640.2 157.74,66.75 v1(157.62,66.87) 157.56,66.94 157.56,67.42 v2(157.76,67.62)
  IN3 w0.152: v2(157.76,67.62) 157.17,67.03 147.93,67.03 146.71,65.81 146.71,61.02 144.75,59.05 144.75,52.22 144.24,51.72 141.51,51.72 139.4,49.61 139.4,46.7 139.08,46.38 139.08,43.95 140.81,42.22 143.28,42.22 v2(143.5,42.01)
  BOTTOM w0.152: UC1.H20 131,45.13 v2(131,45.23)
  BOTTOM w0.254: PC650.1 PC652.1 157.85,67.71 v2(157.76,67.62)
VSA_SEN-: length 65.5
  TOP w0.152: v2(130.96,46.15) 131.42,46.6 133.18,46.6 v1(133.38,46.4) 133.72,46.07 134.59,46.07 135.58,45.08 136.87,45.08 137.57,44.38 137.57,43.6 138.55,42.62 142.61,42.62 RC166.1 v2(143.52,42.87)
  TOP w0.203: PU602.26 161.17,66.84 161.08,66.75 160.25,66.75 v2(160.15,66.64)
  IN3 w0.152: v2(160.15,66.64) 148.09,66.64 147.09,65.65 147.09,60.83 145.13,58.86 145.13,52.06 144.4,51.33 141.67,51.33 139.78,49.45 139.78,46.54 139.46,46.22 139.46,44.11 140.97,42.6 143.26,42.6 v2(143.52,42.87)
  BOTTOM w0.152: v2(130.96,46.15) 130.96,46.01 UC1.H21
  BOTTOM w0.254: v2(160.15,66.64) 160.13,66.67 160.13,67.99 PC650.2 159.49,69.6 PC649.1
VTTREF_1.2V: length 3.8
  TOP w0.102: PC210.1 68.71,107.68 v1(69.21,108.17)
  TOP w0.203: PU200.4 68.27,105.82 68.01,106.08 68.01,107.42 PC210.1
WLAN_RADIO_DIS#: length 99.3
  IN1 w0.114: v2(136.26,33.12) 135.7,32.56 135.7,29.23 139.86,25.07 139.86,22.76 142.59,20.04 142.9,20.04 143.95,18.99 144.97,18.99 146.7,17.25 154.12,17.25 154.81,17.95 157.34,17.95 159.18,19.79 176.96,19.79 v2(177.13,19.62)
  BOTTOM w0.076: 136.43,33.12 v2(136.26,33.12)
  BOTTOM w0.102: v2(136.26,33.12) 136.13,33.24 136.13,36.11 135.18,37.07 135.01,37.07 UC1.B7 ; 136.43,33.12 137.51,33.12 138.18,32.44 RE439.1 ; WLAN1.48 184.92,51.99 183.48,50.54 183.48,38.46 184.76,37.18 184.76,34.8 180.03,30.07 180.03,21.74 v1(179.16,20.87) 177.91,19.62 v2(177.13,19.62)
XCLK_BIASREF: length 11.7
  BOTTOM w0.102: RC52.1 139.67,57.48 v1(139.67,57.3) 139.67,56.33 138.92,55.59 136.07,55.59 135.45,56.2 132.48,56.2 132.26,56.42 132.26,57.25 UC1.E42
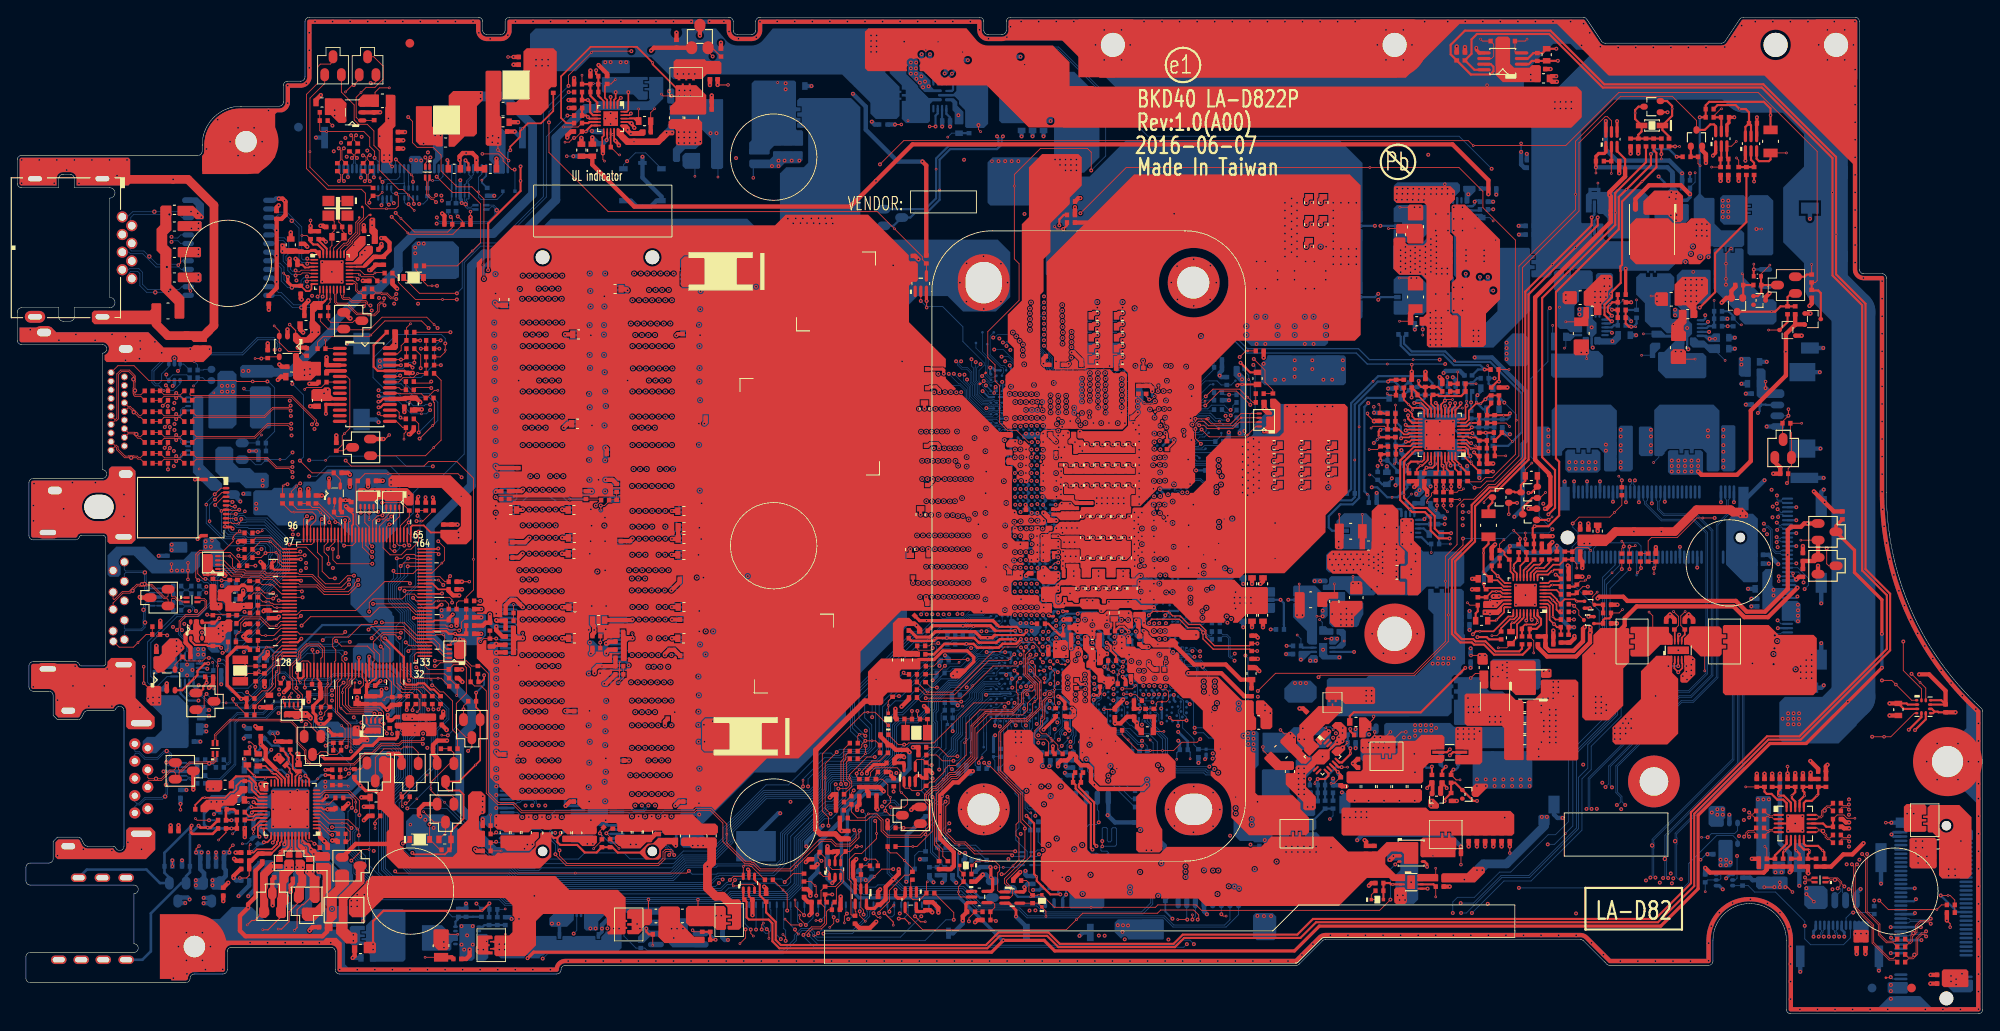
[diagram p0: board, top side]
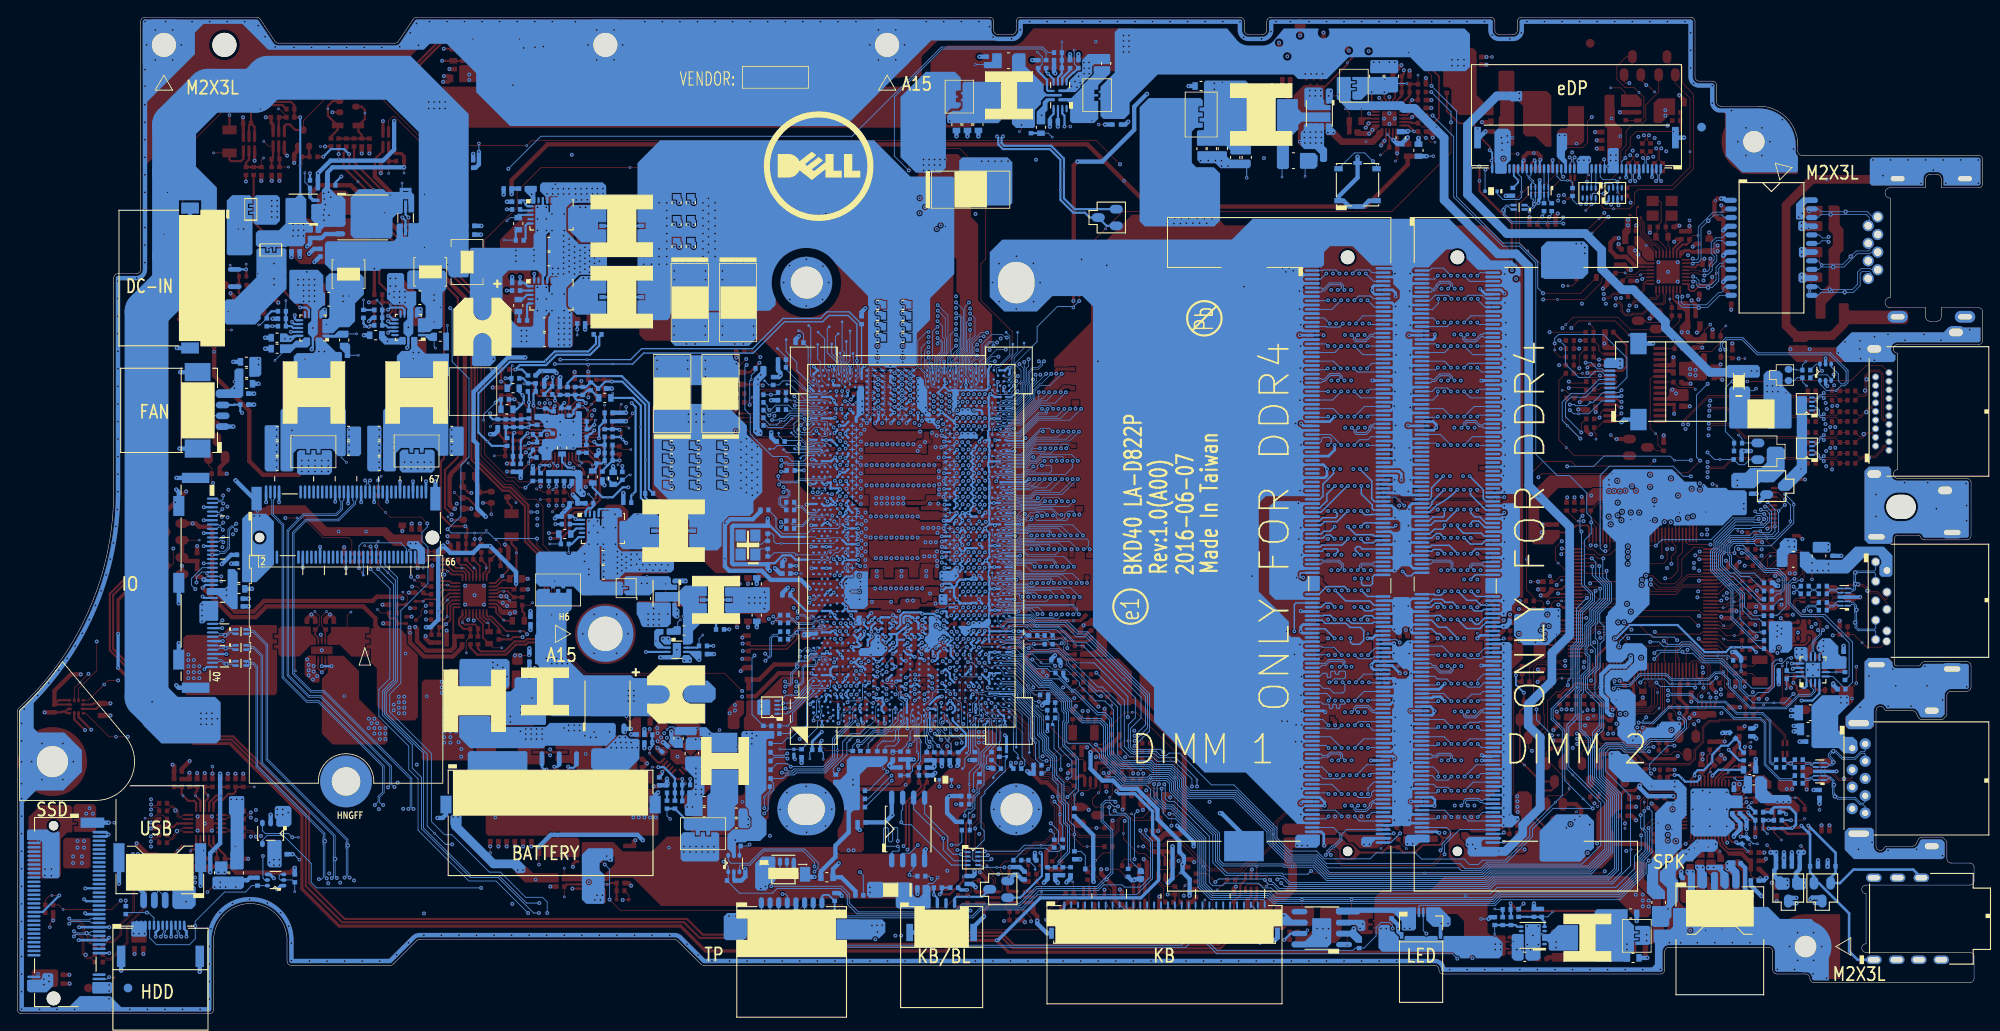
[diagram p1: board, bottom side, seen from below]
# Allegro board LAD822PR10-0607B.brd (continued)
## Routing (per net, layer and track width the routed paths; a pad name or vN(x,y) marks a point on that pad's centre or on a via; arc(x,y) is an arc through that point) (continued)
XDP_HOOK0: length 1.2
  BOTTOM w0.076: T121.1 109.19,42.73 109.12,42.79 RC158.2
XDP_ITP_PMODE: length 6.2
  TOP w0.089: v2(132.28,37.92) 132.28,37.73 132.49,37.52 133,37.52 133.25,37.27 133.25,36.38 133,36.13 T125.1 131.98,36.13 131.85,36 131.85,35.62 131.55,35.31 RC353.2 RC115.1
  BOTTOM w0.076: v2(132.28,37.92) 132.59,38.23 UC1.E8
XDP_OBS0_R: length 3.3
  BOTTOM w0.102: UC1.C55 134.42,65.32 137.4,65.32 T4942.1
XDP_OBS1_R: length 5.5
  BOTTOM w0.102: UC1.D55 133.92,65.23 134.21,64.94 134.46,64.94 134.65,65.12 135.97,65.12 136.11,64.98 138.45,64.98 T4941.1
XDP_OBS2_R: length 2.5
  BOTTOM w0.102: T10.1 136.56,64.61 136.21,64.61 135.89,64.93 134.93,64.93 UC1.B54
XDP_OBS3_R: length 6.8
  BOTTOM w0.102: UC1.C56 134.19,65.79 134.48,65.51 137.1,65.51 137.41,65.81 139.51,65.81 139.91,65.41 T11.1
XDP_PRDY#: length 5.2
  BOTTOM w0.076: UC1.D56 133.78,66.07 134.31,66.07 134.38,66.14 134.71,66.14 134.75,66.19 135.1,66.19 135.17,66.23 135.54,66.23 135.7,66.06 136.12,66.06 136.85,66.8 137.19,66.8
  BOTTOM w0.102: T120.1 137.4,66.8 137.19,66.8
XDP_PREQ#: length 1.5
  TOP w0.102: v2(133,67.9) 132.71,68.19 132.71,68.42 T119.1
  BOTTOM w0.076: UC1.D61 132.99,67.9 v2(133,67.9)
XDP_SPI_IO2: length 2.9
  BOTTOM w0.102: T131.1 114.51,27.49 RC347.1 114.62,29.38 RC354.1
XDP_SPI_SI: length 2.2
  BOTTOM w0.102: T124.1 109.67,17 RC9.2 RC355.1
XTAL24_IN: length 13.6
  BOTTOM w0.076: UC1.E37 132.96,54.46 135.93,54.46
  BOTTOM w0.102: 135.93,54.46 v1(139.04,54.46) 139.65,54.46 139.91,54.72 139.91,55.35 140.16,55.61 CC21.1 RC46.2 140.96,54.75 141.33,54.38 142.75,54.38 YC1.3
XTAL24_OUT: length 11.3
  BOTTOM w0.076: 136.07,53.14 134.2,53.14 134.18,53.12 133.86,53.12 133.67,53.31 133.67,53.53 133.5,53.7 132.81,53.7 UC1.E35
  BOTTOM w0.102: 136.07,53.14 v1(137.3,53.14) 137.54,53.39 139.87,53.39 140.29,52.97 CC22.1 RC46.1 141.41,53.83 YC1.1
N16662348: length 2.5
  TOP w0.203: CA23.2 26.53,25.01 v1(27.4,25.01) 27.55,25.01 27.89,24.67 UA1.28
N17298963: length 3.1
  TOP w0.102: PC640.1 158.24,68.03 156.89,68.03 v1(156.68,67.83)
  TOP w0.254: PR646.2 158.6,68.6 PC640.1
N17298971: length 2
  TOP w0.102: PC601.1 157.71,70.44 v1(157.57,70.58)
  TOP w0.203: PR652.2 158.17,69.5 158.09,69.57 PC601.1
N17298982: length 4.8
  TOP w0.102: PR636.1 159.57,63.84 v1(159.4,63.67)
  TOP w0.203: PC632.1 159.62,65.74 161.22,65.74 161.52,66.04 PU602.28
  TOP w0.254: PR636.1 PC632.1
N17298983: length 2.3
  TOP w0.102: PR641.1 157.41,65.34 v1(156.47,65.34)
  TOP w0.254: PR641.1 157.79,65.69 PC632.2
N17298992: length 39.9
  IN3 w0.254: v2(145.06,44.51) 144.68,44.13 141.63,44.13 141.06,44.7 141.06,45.97 140.24,46.79 140.24,49.08 141.86,50.71 144.78,50.71 145.82,51.75 145.82,58.48 147.73,60.38 152.17,60.38 157,65.21 v2(157,66.1)
  BOTTOM w0.254: PH604.1 v2(145.06,44.51) ; PR642.2 158.58,66.8 157.71,66.8 v1(157.41,66.51) v2(157,66.1)
N17299006: length 2.5
  TOP w0.254: PR607.2 v2(165.07,61.06) PR625.1
  BOTTOM w0.102: v2(165.07,61.06) 165.1,61.06 165.47,60.69 v1(165.5,60.69)
  BOTTOM w0.254: PR604.2 v2(165.07,61.06)
N17299007: length 3.5
  TOP w0.102: v1(167.38,60.79) 167.2,60.61 166.84,60.61 166.62,60.4 PR606.2
  TOP w0.203: v2(165.95,61.06) PR618.1
  TOP w0.254: PR606.2 v2(165.95,61.06)
  BOTTOM w0.203: v2(165.95,61.06) PR601.2
N17299016: length 3.7
  TOP w0.102: v1(163.19,59.23) 163.19,59.49 163.68,59.99 163.68,60.28 163.8,60.4 PR609.2
  TOP w0.381: PR609.2 v2(164.18,61.06) PR626.1
  BOTTOM w0.381: PR605.2 v2(164.18,61.06)
N17299020: length 2.6
  TOP w0.203: v1(167.01,63.5) 167.01,63.58 166.44,64.16 PU602.40
  TOP w0.254: PR616.2 167.01,63.44 v1(167.01,63.5)
N17299022: length 2.3
  TOP w0.203: PU602.39 166.04,64.07 166.39,63.72 166.39,63.11 PR612.2
N17299031: length 3.3
  TOP w0.203: v2(165.88,63.48) 165.88,63.75 165.64,63.99 PU602.38
  BOTTOM w0.254: v2(165.88,63.48) 165.93,63.53 v1(166.91,63.53) 167.06,63.38 167.06,62.77 PR678.2
N17299032: length 5.4
  TOP w0.203: PU602.34 164.04,63.47 163.81,63.24 v2(163.1,63.24) 162.84,62.99 PR602.1
  BOTTOM w0.254: PC603.1 164.42,63.91 v1(164.16,63.66) 163.75,63.24 v2(163.1,63.24)
N17299033: length 9.4
  TOP w0.203: PU602.33 163.64,63.82 v2(163.54,63.73)
  IN1 w0.254: v2(159.08,62.01) 160.8,63.73 v2(163.54,63.73)
  BOTTOM w0.102: v1(156.52,62.4) 156.75,62.4 157.32,61.83 PR603.1
  BOTTOM w0.254: v2(159.08,62.01) 159.08,61.88 PC604.1 157.97,61.31 PR603.1
N17299046: length 2.6
  TOP w0.203: PU602.32 163.24,64.1 162.62,63.49 v1(162.42,63.49) 161.97,63.04 PR608.1
N17299048: length 3.6
  TOP w0.203: 162.07,63.94 162.59,63.94 162.84,64.19 PU602.31
  TOP w0.254: PR611.1 160.91,62.75 v1(160.91,63.56) 161.29,63.94 162.07,63.94
N17299099: length 4.6
  TOP w0.203: PC630.1 160.48,71.1 v1(161,70.58) 161.42,70.16 162.56,70.16 162.84,69.89 PU602.20
  TOP w0.254: PC630.1 160.48,72.49 PR640.1
N17299117: length 22.2
  BOTTOM w0.254: PR657.2 163.79,73.03 162.97,73.85 157.51,73.85 v1(156.91,73.25) 154.37,70.71 154.37,60.75 PH605.1
N17299153: length 0.9
  TOP w0.254: PC639.2 PR645.1
N17299162: length 2.2
  TOP w0.102: PR650.2 v1(166.7,74.33)
  TOP w0.254: PC647.2 PR650.2
N17299166: length 3
  BOTTOM w0.102: v1(161.47,69.9) 161.99,70.42 PC629.2
  BOTTOM w0.254: PC629.2 163.1,69.84 163.1,69.48 163.29,69.28 PR639.1
N17299193: length 2.8
  TOP w0.102: v1(172.71,68) 172.31,68.4 PR632.2
  TOP w0.254: PR632.2 170.97,68.42 PC627.1
N17299198: length 25.7
  BOTTOM w0.254: PH602.1 160.49,78.4 160.49,77.59 161.38,76.7 165.26,76.7 v1(166.35,75.61) 166.47,75.5 170.46,75.5 174.11,71.85 174.11,67.33 172.55,65.77 PR628.2
N17299204: length 3.1
  TOP w0.203: PU602.8 167.73,68.04 168.11,68.42 v1(168.27,68.42) PC627.2
  TOP w0.254: PC627.2 PR638.2
N17299248: length 2.2
  TOP w0.102: PC621.2 v1(172.27,64.61)
  TOP w0.254: PR623.1 PC621.2
N17299249: length 4.1
  TOP w0.203: PU602.5 167.9,66.84 168.01,66.74 v1(168.28,66.74) 168.79,66.74 169.16,66.37 PR622.2
  TOP w0.254: PR623.2 PR621.2 169.22,66.39 PR622.2
N17299259: length 4.1
  TOP w0.203: v2(168.26,66.08) 168.08,66.08 167.71,66.44 PU602.4
  BOTTOM w0.102: v1(168.78,65.77) 168.61,65.77 168.31,66.08 v2(168.26,66.08)
  BOTTOM w0.254: PR617.2 167.31,66.63 PC616.2 167.43,66.08 v2(168.26,66.08)
N17299260: length 1.7
  BOTTOM w0.254: PR617.1 166.45,67.55 165.87,67.55 PC614.2
N17299268: length 2.4
  TOP w0.203: PU602.3 167.65,66.04 168.27,65.42 v1(168.27,65.41) 168.29,65.41 168.35,65.48 169.17,65.48 PR610.2
N17299272: length 4.2
  TOP w0.203: v2(168.18,64.57) 167.9,64.85 167.9,65.32 167.58,65.64 PU602.2
  BOTTOM w0.102: v2(168.18,64.57) 168.18,64.02 v1(168.28,63.91)
  BOTTOM w0.254: PC613.2 167.8,65.15 168.18,64.77 v2(168.18,64.57) 168.02,64.42 PR613.2
N17299296: length 2.9
  TOP w0.102: PC617.2 171.98,67.3 v1(173.04,66.25)
  TOP w0.254: PR621.1 171.81,67.2 PC617.2
N17299297: length 2.3
  BOTTOM w0.102: PC631.1 162.49,64.14 v1(162.12,63.77)
  BOTTOM w0.254: PR630.2 161.62,64.99 PC631.1
N17299304: length 2
  TOP w0.102: PC630.2 158.75,71.63 v1(158.55,71.83)
  TOP w0.254: PC630.2 159.58,71.64 PR644.1
N17299307:
  vias: v1(153.56,43.16)
N17299308: length 1.4
  BOTTOM w0.102: PR619.1 151.03,45.33 v1(150.73,45.64)
N17299330: length 28
  TOP w0.254: v2(168.6,65.02) 169.02,64.59 PR610.1 169.21,63.73 PR631.2
  IN1 w0.254: v2(168.6,65.02) 168.85,65.27 169.64,65.27 173.41,69.05 173.41,72.96 169.88,76.49 163.35,76.49 162.67,77.17 v2(162.67,79.26)
  BOTTOM w0.102: v2(162.67,79.26) v1(162.67,78.6)
  BOTTOM w0.254: PH601.2 v2(162.67,79.26)
N17299350: length 24.7
  IN1 w0.254: v2(165.51,73.72) 165.51,73.67 164.23,72.38 161.26,72.38 159.59,70.72 v2(156.35,70.72)
  BOTTOM w0.254: v2(165.51,73.72) 165.51,72.71 PR647.2 166.46,71.75 PR635.1 ; v2(156.35,70.72) 155.91,70.28 155.91,60.5 v1(156.25,60.16) 156.42,59.99 PH603.2
N17299365: length 4.5
  TOP w0.102: v2(151.08,46.03) v1(150.41,46.03)
  IN3 w1.016: 150.52,45.33 149.95,44.76 149.95,41.71
  vias: v2(149.63,40.89) v2(150.27,40.89) v2(151.08,46.67)
N17299369: length 6.3
  TOP w0.102: v2(152.11,43.43) v1(151.4,43.43)
  IN3 w1.016: 152.43,44.29 152.21,44.5 152.21,48.79 151.48,49.52
  vias: v2(150.14,50.1) v2(150.78,50.1) v2(152.75,43.43)
N17299387: length 3
  BOTTOM w0.102: v1(148.13,43.85) 148.57,43.42 PR679.2
  BOTTOM w0.254: PR679.2 148.77,42.4 PU606.7
N17301560: length 22.3
  BOTTOM w0.254: PL603.3 152.16,55.94 151.78,56.32 151.78,57.62 153.15,58.99 154.55,58.99 155.3,59.74 v1(155.3,67.97) 155.3,70.42 156.21,71.32 PR661.1
N17301607: length 1.6
  BOTTOM w0.254: PU605.3 168.5,83.25 169.04,82.71 PR672.2
N17301608: length 1.1
  BOTTOM w0.254: PR672.1 169.38,81.21 PC671.1
N17301618: length 1.6
  BOTTOM w0.254: PR660.2 162.77,56.2 PU603.3
N17301619: length 2.6
  BOTTOM w0.102: v1(165.85,54.4) PC655.1
  BOTTOM w0.254: PC655.1 164.56,55.3 PR660.1
N17301744: length 1.2
  BOTTOM w0.254: PR671.2 169.28,83.75 PU605.2
N17312499: length 27.8
  IN3 w0.254: v2(147.09,47.94) 146.84,48.19 146.84,57.91 148.1,59.18 153.13,59.18 154.92,60.97 v2(156.76,60.97)
  BOTTOM w0.254: v2(156.76,60.97) 157.39,60.97 158.55,59.81 v1(159.11,59.81) 159.74,59.81 160.87,60.94 PR624.1 ; PL601.3 v2(147.09,47.94)
N17415515: length 0.6
  TOP w0.102: v2(201.27,90.88) v1(201.88,90.88)
N17481633:
  vias: v2(167.94,35.52) v2(167.95,34.89) v2(168.53,35.54) v2(168.53,34.91) v2(169.17,35.54) v2(169.18,34.91) v2(170.41,34.42) v2(170.41,33.79) v2(171.05,34.42) v2(171.05,33.79) v2(171.68,34.42) v2(171.68,33.79) v4(167.9,36.56)
N18390627: length 4.1
  TOP w0.102: PQ710.2 176.24,59.73 v1(176.88,60.37)
  TOP w0.254: PQ711.1 174.23,58.62 175.35,59.73 PQ710.2
N20173493: length 5.1
  TOP w0.102: UE1.120 30.52,44.62 29.7,43.8 v1(28.74,43.8) 28.26,43.8 RE358.1 RE356.1
N23700319: length 6.6
  TOP w0.102: PL2.1 201.81,85.67 v1(202.84,86.7)
  TOP w0.254: PR6.2 PQ6.1 ; PR6.2 201.81,84.42 PL2.1 ; PR6.2 201.84,83.51 201.44,83.11 PD4.2
N27266810: length 30
  TOP w0.381: PQ709.6 v2(183.85,103.38)
  IN3 w0.508: v2(192.68,97.33) 192.68,89.99 193.81,88.86 v2(193.93,88.86)
  BOTTOM w0.508: PR778.2 PR762.1 v2(192.68,97.33) 191.2,98.8 185.13,98.8 183.85,100.08 v2(183.85,103.38) ; PQ718.4 190.18,90.29 191.8,90.29 192.26,89.83 PC744.1 PC742.1 193.58,89.21 v2(193.93,88.86)
N27286345: length 3.4
  TOP w0.102: PD704.1 170.25,59.81 169.75,59.32 v1(169.75,59.19)
  TOP w0.254: PD704.1 170.72,59.2 170.27,58.76 PR743.2
N28103940: length 13
  TOP w0.102: v2(27.53,30.89) 27.53,30.95 27.03,31.45 v1(26.83,31.45)
  TOP w0.254: CA68.2 27.53,30.45 v2(27.53,30.89)
  IN1 w0.305: v2(27.53,30.89) 27.69,30.73 27.69,27.43 23.37,23.11 v2(22.76,23.11)
  BOTTOM w0.254: RA82.1 23,23.35 v2(22.76,23.11)
N28103942: length 15.5
  TOP w0.102: v2(22.19,22.41) 20.81,22.41 v1(20.62,22.6)
  TOP w0.254: v2(26.9,30.89) 26.9,30.48 CA67.2
  IN1 w0.305: v2(26.9,30.89) 26.83,30.81 26.83,27.58 24.29,25.04 22.23,25.04 21.78,24.59 21.78,22.82 v2(22.19,22.41)
  BOTTOM w0.203: v2(22.19,22.41) RA80.1
N28204071: length 8.9
  TOP w0.102: v2(35.69,31.05) 36.02,31.38 CA69.1 36.58,30.53 RA79.1 ; RA81.2 CA65.2 37.95,27.39 v2(38.38,27.82)
  BOTTOM w0.102: v2(35.69,31.05) 36.41,31.05 38.55,28.91 v1(38.55,28.39) 38.55,27.99 v2(38.38,27.82)
N28424999: length 5.6
  BOTTOM w0.076: T113.1 112.6,78.49 112.6,76.34 113.88,75.05 114.27,75.05 114.45,74.87 UC1.AW71
N28425002: length 4.6
  BOTTOM w0.076: UC1.AW70 113.97,74.05 114.14,74.23 114.14,74.74 114.01,74.86 113.82,74.86 112.25,76.44 T114.1
N28483977: length 4.9
  TOP w0.102: PR2.1 199.23,98.85 v1(198.97,99.11)
  TOP w0.254: PQ1.2 200.65,98.9 201.01,98.55 PR12.2 PR13.2 PR2.1
N28483985: length 5.3
  TOP w0.102: v1(204.75,99.69) PR5.2
  TOP w0.254: PR5.2 202.91,98.93 202.72,98.74 201.58,98.74 201.3,99.01 PQ1.3
N28484391: length 3.8
  TOP w0.102: v1(198.95,101.02) 198.39,100.47 PQ2.3
  TOP w0.254: PR28.2 198.03,98.06 PC16.1 197.86,99.16 PQ2.3
N28484395: length 3.5
  TOP w0.102: v1(196.09,98.05) PR29.1
  TOP w0.254: PR29.1 197.12,98.06 PC16.2 197.21,99.09 PQ2.2
N28484412: length 3.9
  TOP w0.102: v1(197.25,104.8) 197.16,104.8 196.32,103.96 PR31.1
  TOP w0.254: PQ2.5 197.21,103.79 PR33.2 PR31.1
N28484439: length 3.2
  TOP w0.102: PR32.1 194.52,98.45 v1(194.76,98.2)
  TOP w0.254: PQ3.2 193.69,99.28 PC14.2 PR32.1
N28484451: length 9.2
  TOP w0.254: PQ1.5 200.65,102.89 PR10.2 ; PQ1.6 200,102.7 PR10.2 ; PR10.2 200.42,104.39 200.04,104.77 v1(199.34,104.77) 198.89,105.23 196.78,105.23 PR7.1
N28714500: length 3.8
  TOP w0.203: PU703.3 177.18,47.87 177.73,47.32 v1(177.73,45.98) 177.73,45.96 178.03,45.65 PR769.2
N28714504: length 3.2
  TOP w0.203: PR770.2 178.4,46.54 178.15,46.79 178.15,47.45 v1(177.7,47.9) 177.33,48.27 PU703.4
N28714507: length 14.5
  TOP w0.102: v1(182.71,97.37) v2(182.71,98.03)
  TOP w0.381: v2(182.71,98.03) PR737.1 182.71,99.3 183.04,99.63 183.67,99.63 183.85,99.81 PQ709.1
  BOTTOM w0.508: PR763.1 191.56,97.45 190.99,98.03 v2(182.71,98.03)
  vias: v2(191.19,94.56) v2(191.38,92.46) v2(191.43,95.14) v2(191.82,93.71) v2(192,94.99) v2(191.95,94.36) v2(191.95,93.1) v2(191.98,91.89) v2(192.04,92.5)
N28714524: length 2.8
  TOP w0.203: PU703.27 173.94,45.96 173.86,45.88 173.86,45.87 173.28,45.28 v1(173.02,45.28) 172.88,45.14 PC750.1
N28714534: length 3.4
  TOP w0.102: 179.96,53.52 180.43,53.98 181.78,53.98 v1(182.11,53.65)
  TOP w0.203: PR754.1 179.96,53.52 PC752.2
N28714559: length 2.3
  TOP w0.203: PR774.2 178.14,49.07 PU703.6
N28714562: length 2.2
  TOP w0.203: PR775.2 178.45,49.65 v1(177.68,49.65) 177.51,49.65 177.33,49.47 PU703.7
N28714564: length 3.2
  TOP w0.102: PC721.1 168.11,47.32 v1(167.83,47.59)
  TOP w0.254: PR771.2 168.79,46.36 169.03,46.6 PC721.1
N28714572: length 7.8
  TOP w0.203: PC757.2 170.64,50.2 171.31,50.2 172.04,49.47 PU703.18
  TOP w0.254: PR743.1 170.27,54.41 169.7,53.84 v1(169.7,53.37) 169.7,51.14 PC757.2
N28714582: length 3.1
  TOP w0.203: PU703.12 174.74,51.2 175.54,52 176.18,52 176.43,52.25 PR755.2
N28714583: length 3.2
  TOP w0.203: PR776.1 174.69,53.42 PC708.1 173.94,51.85 PU703.14
N28714585: length 3.3
  TOP w0.203: PU703.15 173.54,50.99 173.19,51.34 v1(173.19,51.65) 173.19,52.02 PC708.2 173.77,53.44 PR742.1
N28714598: length 4.4
  TOP w0.203: PU703.31 175.54,46.01 175.94,45.61 v1(175.94,45.31) 175.7,45.07 175.41,45.07 175.4,45.08 174.7,45.08 174.68,45.06 174.47,45.06 174.13,44.72 PC747.1
  TOP w0.254: PR740.2 174.15,44.56 PC747.1
N28714599: length 6
  TOP w0.102: PR772.2 175.5,43.21 v1(175.5,41.79)
  TOP w0.254: PR772.2 175.02,44.55 PC747.2 175.84,44.57 176.34,45.08 176.34,45.71 175.94,46.11 PU703.32
N28714601: length 5.8
  TOP w0.102: PC750.2 172.39,42.37 v1(171.4,42.37)
  TOP w0.203: PC750.2 173.57,43.56 173.57,45.11 174.19,45.73 174.19,45.74 174.34,45.89 PU703.28
N28714604: length 26.5
  TOP w0.203: PU703.25 173.14,46.1 173.05,46.01 172.57,46.01 170.86,44.29 v1(169.27,44.29) 168.81,44.29 v2(168.47,43.95)
  TOP w0.254: v2(167.58,40.05) 162.44,34.91 154.68,34.91 154.22,34.45 PR773.1
  IN3 w0.254: v2(167.58,40.05) 167.58,43.06 v2(168.47,43.95)
N28714606: length 1.7
  TOP w0.102: PR761.2 168.74,39.4 v4(168.22,38.88)
N28714608: length 4.4
  TOP w0.102: v1(170.67,43.78) 171.25,43.78 PR745.1
  TOP w0.203: PR745.1 171.73,44.65 172.76,45.68 173.21,45.68 173.54,46.01 PU703.26
N28714612: length 3.3
  TOP w0.203: PR771.1 171.1,45.51 v1(171.19,45.6) 172.08,46.49 172.08,47 172.15,47.07 PU703.24
N28714614: length 3
  TOP w0.203: PU703.17 172.16,49.87 v2(171.34,50.69) 170.64,51.39 PR757.2
N28714617: length 1.2
  BOTTOM w0.102: 182.93,95.03 v1(182.93,96.2)
N28714625: length 0.9
  TOP w0.203: PR757.1 PR779.2
N28714693: length 9
  TOP w0.254: PC779.1 154.27,32.74 v2(154.27,32.98)
  IN1 w0.254: v2(154.27,32.98) 154.27,33.33 154.61,33.68 157.17,33.68 157.42,33.42 v2(161.77,33.42)
  vias: v2(160.48,32) v2(161.12,32) v2(161.77,32.79) v2(161.78,32.19) v2(162.39,33.42) v2(162.39,32.79) v2(163.02,33.42) v2(163.02,32.79) v2(163.66,33.42) v2(163.66,32.79) v2(164.2,33.09) v2(166.73,32.98) v2(166.73,32.39) v2(166.73,31.81) v2(167.36,32.98) v2(167.36,32.39) v2(167.36,31.81) v2(168,32.98) v2(168,32.39) v2(168,31.81) v2(168.62,32.98) v2(168.62,32.39) v2(168.62,31.81) v4(169.24,32.72)
N28714721: length 43
  TOP w0.102: v2(173.92,54.99) 173.92,55.24 v1(173.18,55.98)
  TOP w0.203: v2(173.92,54.99) 173.92,54.52 PR742.2
  TOP w0.254: PR765.2 166.16,30.28 v2(165.8,29.93)
  IN3 w0.254: v2(165.8,29.93) 165.65,30.08 164.66,30.08 164.65,30.07 159.97,30.07 159.24,30.8 159.24,37.38 166.32,44.46 166.32,49.64 169.19,52.51 173,52.51 174.02,53.53 174.02,54.88 v2(173.92,54.99)
N28714724: length 41.7
  TOP w0.102: v1(174.53,55.68) v2(174.53,54.99)
  TOP w0.203: PR776.2 174.53,54.48 v2(174.53,54.99)
  TOP w0.254: PR765.3 165.47,30.28 v2(165.8,30.61)
  IN3 w0.254: v2(165.8,30.61) 165.65,30.46 160.11,30.46 159.62,30.96 159.62,37.22 166.7,44.3 166.7,49.48 169.35,52.13 173.16,52.13 174.4,53.37 174.4,54.85 v2(174.53,54.99)
N28714743: length 4
  TOP w0.102: v1(184.48,97.32) PR738.1
  TOP w0.254: PR737.2 PR738.1 184.5,98.76 PQ709.2
N28714752: length 67.5
  TOP w0.254: PR772.1 175.02,42.39 174.22,41.59 170.91,41.59 169.76,42.74 168.6,42.74 168.35,43 167.02,43 166.04,43.98 166.04,52.57 168.33,54.85 168.33,58.92 170.36,60.95 171.16,60.95 174.53,64.32 174.53,83.62 v1(177.66,86.75) 182.21,91.31 v2(182.21,92.22)
  BOTTOM w0.254: PR703.2 182.53,92.54 v2(182.21,92.22)
N28714753: length 66.2
  TOP w0.254: PR740.1 174.15,42.27 173.84,41.97 171.07,41.97 169.92,43.12 168.76,43.12 168.51,43.38 167.19,43.38 166.42,44.14 166.42,52.41 168.71,54.69 168.71,58.76 170.52,60.57 171.32,60.57 174.91,64.16 174.91,83.31 v1(180.35,88.75) 182.91,91.31 v2(182.91,92.22)
  BOTTOM w0.254: v2(182.91,92.22) 182.53,91.84 PR703.3
N28714793: length 1.8
  TOP w0.127: v4(156.98,34.44) 156.98,34.17 156.43,33.62
  BOTTOM w0.508: PQ717.4 v2(156.45,33)
N28716223: length 2.5
  BOTTOM w0.254: PU604.5 168.41,91.52 168.65,91.28 168.65,89.78 PC663.2
N28716225: length 3.3
  BOTTOM w0.102: PR665.2 170.42,92.2 v1(170.81,91.82)
  BOTTOM w0.254: 169.78,92.2 169.45,92.52 PU604.3
N28716227: length 2.7
  BOTTOM w0.102: PC663.1 169.8,89.59 v1(171.1,89.59)
  BOTTOM w0.254: PR665.1 169.78,90.51 PC663.1
N28810503: length 3.9
  TOP w0.102: CZ45.1 192.26,44.97 192.26,46.01 v1(191.68,46.58)
  TOP w0.203: UZ2.12 191.83,44.45 CZ45.1
N28810563: length 4
  TOP w0.102: CZ23.1 192.52,44.97 192.52,46.07 v1(193.03,46.58)
  TOP w0.203: UZ2.10 192.63,43.54 192.99,43.9 CZ23.1
N28842863: length 5
  BOTTOM w0.254: 118.03,30.69 117.68,31.04 117.68,32.44 119.21,33.96 UC1.AL1
  BOTTOM w0.305: 118.03,30.69 118.45,30.27 CC204.1
N28843886: length 5.1
  BOTTOM w0.076: CC214.1 109.77,36.93 110.57,37.73 v1(110.57,37.99) 110.57,38.02 112,39.45 UC1.BB10
N28856399: length 6.5
  BOTTOM w0.076: T16.1 111.7,76.67 112.36,76.01 112.36,75.09 112.24,74.97 112.24,74.03 112.55,73.72 113.06,73.72 113.22,73.89 UC1.BA70
N28856402: length 2.6
  TOP w0.089: T17.1 112.04,74.23 v2(111.66,73.85)
  BOTTOM w0.076: UC1.BA68 112.96,73.24 112.83,73.11 112.56,73.11 111.83,73.85 v2(111.66,73.85)
N28857231: length 1.6
  TOP w0.089: T12.1 111.52,72.94 v2(111.85,73.27)
  BOTTOM w0.076: UC1.BB68 112.25,73.19 111.94,73.19 v2(111.85,73.27)
N28857234: length 5.1
  BOTTOM w0.076: UC1.BB69 112.57,73.52 112.5,73.52 112.08,73.94 112.08,75.04 112.11,75.07 112.11,75.94 110.95,77.1 T13.1
N28857237: length 1.1
  TOP w0.089: v2(119.54,40.83) T14.1
  BOTTOM w0.076: v2(119.54,40.83) 119.88,41.17 UC1.AK13
N28857240: length 1.6
  TOP w0.089: T15.1 120.75,40.44 v2(120.36,40.83)
  BOTTOM w0.076: UC1.AK12 120.05,40.52 120.36,40.83 120.36,40.83 v2(120.36,40.83)
N28861827: length 14.3
  TOP w0.102: v2(137.49,70.44) 139.16,72.11 141.11,72.11 v2(142.7,70.52)
  BOTTOM w0.076: v2(137.49,70.44) 135.91,70.44 135.76,70.29 134.52,70.29 134.42,70.19 UC1.C64
  BOTTOM w0.102: v2(142.7,70.52) 142.7,73.26 v1(142.52,73.44) 142.52,73.93 142.03,74.43 RC120.1
N29189918: length 2.6
  TOP w0.203: PU703.13 174.34,51.36 v1(174.61,51.63) 175.54,52.56 PR764.2
N29708559: length 6.5
  BOTTOM w0.076: 111.85,32.57 111.85,34.73 112.42,35.3 112.8,35.3 113,35.49 113.52,35.49 UC1.AY4
  BOTTOM w0.102: T126.1 111.85,32.57
N29708561: length 5.8
  BOTTOM w0.076: 112.18,32.57 112.18,34.49 112.69,34.99 UC1.BB3
  BOTTOM w0.102: T127.1 111.65,30.02 112.18,30.55 112.18,32.57
N29708599: length 9.5
  BOTTOM w0.076: 117.15,32.57 117.15,33.59 117.11,33.59 116.82,33.88 116.82,34.36 116.64,34.54 116.23,34.54 116.15,34.63 116.15,34.69 116.11,34.73 116.11,35 116.15,35.04 116.15,35.34 116.11,35.38 116.11,35.66 116.17,35.72 116.17,35.95 116.17,35.95 116.17,36.18 UC1.AU5
  BOTTOM w0.102: T128.1 117.81,28.65 117.81,29.52 117.15,30.19 117.15,32.57
N29708601: length 7.2
  BOTTOM w0.076: UC1.AT5 116.45,36.33 116.9,35.89 116.9,34.95 117,34.86 117.38,34.86 117.5,34.74 117.5,33.07
  BOTTOM w0.089: 117.38,32.95 117.5,33.07
  BOTTOM w0.102: 117.38,32.95 117.38,30.42 T129.1
N29708639: length 7.2
  BOTTOM w0.076: UC1.BB5 112.58,36.41 110.41,34.24 110.41,32.57
  BOTTOM w0.102: T130.1 110.34,31.62 110.41,31.69 110.41,32.57
N32777150: length 1.3
  BOTTOM w0.254: PR664.1 169.15,93.02 PU604.2
N32842463: length 29.7
  TOP w0.089: RC361.2 127.87,32.57
  TOP w0.102: v2(136.91,31.81) 136.54,31.44 134.79,31.44 133.82,30.47 v1(131.13,30.47) 129.7,30.47 127.87,32.3 127.87,32.57
  IN1 w0.114: v2(136.91,31.81) 137.18,32.08 137.18,34.86 136.38,35.66 136.38,36.17 133.34,39.21 129.22,39.21 128.67,38.66 127.54,38.66 127.16,39.05 126.58,39.05 125.82,39.81 v2(125.82,40.19)
  BOTTOM w0.254: UC1.U12 126.15,40.52 v2(125.82,40.19) 126.15,39.87 UC1.U11
N33124395: length 4.9
  TOP w0.203: v2(68.2,101.18) 68.2,101.3 68.27,101.37 PU200.12
  TOP w0.508: PR210.1 v2(66.55,101.48)
  BOTTOM w0.102: v1(68.92,101.83) 68.27,101.18 v2(68.2,101.18)
  BOTTOM w0.508: v2(66.55,101.48) 67.28,100.76 PC204.2 67.78,100.76 v2(68.2,101.18)
N33124472: length 1.8
  BOTTOM w0.102: PR203.2 v1(78.43,96.98)
N34661441: length 23.8
  TOP w0.102: v2(25.92,57.3) 25.92,57.08 v1(25.63,56.79) 24.85,56.79 24.77,56.87 JDEG1.9
  BOTTOM w0.102: v2(25.92,57.3) 26.03,57.19 28.72,57.19 31.1,54.81 31.1,54 31.5,53.6 31.5,51.3 29.14,48.94 29.14,45.71 25.71,42.29 RE74.2
N34661623: length 20.8
  TOP w0.102: v2(22.85,60.15) 23.56,60.87 JDEG1.1
  BOTTOM w0.102: RE71.2 26.43,51.02 28.04,51.02 29.09,52.06 29.09,53.06 29.28,53.25 29.28,54.02 28.85,54.45 26.42,54.45 26.17,54.2 24.49,54.2 21.87,56.81 v4(21.87,58.96) 21.87,59.18 v2(22.85,60.15)
N36085760: length 3.5
  TOP w0.102: PD6.1 v1(202.68,79.18)
  TOP w0.254: PD6.1 204.88,80.1 PR11.2
N39282118:
  vias: v1(54.32,8.38) v2(53.31,7.42) v2(53.94,7.42)
N39282176: length 3.4
  TOP w0.102: v1(47.2,6.54) PR506.2
  TOP w0.508: PC504.1 50.28,6.54 PR506.2
N39282188: length 1.8
  BOTTOM w0.102: v1(56.47,12.14) 56.42,12.09 PR503.1
  BOTTOM w0.254: PR504.2 55.56,12.09 PR503.1
N39732053: length 5
  TOP w0.102: UZ13.27 43.99,76.41 44.43,76.84 44.43,77.36 RZ65.1 RZ126.2 45.04,79.43 v1(45.51,79.9)
N39732069: length 17
  TOP w0.102: QZ11.2 47.25,64.63 v1(48.19,65.57) 49.05,66.43 49.05,73.35 RZ120.2
N39734476: length 6.1
  TOP w0.102: UZ13.20 44.31,71.86 44.36,71.8 46.77,71.8 RZ121.2 47.39,71.31 48.28,72.19 v1(48.67,72.19)
N39734479: length 2.5
  TOP w0.102: RZ122.2 44.5,68.89 v2(44.35,69.04) 44.2,69.2 44.2,69.64 43.94,69.91 UZ13.17
N39737552: length 2.7
  TOP w0.102: UZ13.1 35.7,77.06 RZ116.2 v1(35.67,78.04)
N39880170: length 5.7
  BOTTOM w0.102: PR1202.2 108.86,109.98 108.86,110.83 v1(109.4,111.37)
  BOTTOM w0.254: PU1200.7 108.17,106.87 108.3,106.99 108.3,108.15 109.31,109.16 PR1202.2
N39880453: length 1.3
  BOTTOM w0.102: PC1209.1 v1(116.59,109.92)
N40598435: length 1.4
  BOTTOM w0.102: v1(177.7,79.72) 177.7,78.55 PR100.2
N40598492: length 1.8
  BOTTOM w0.102: v1(197.66,75.66) 197.59,75.73 196.69,76.63 PC119.1
N40598500: length 1.3
  BOTTOM w0.102: PC114.1 v1(187.99,76.26)
N40598503: length 2.4
  BOTTOM w0.102: v1(187.4,82.67) PR108.1
  BOTTOM w0.254: PR108.1 187.39,81.5 PC113.2
N40598539: length 3.1
  BOTTOM w0.102: v1(199.54,79.78) 199.34,79.78 PR117.1
  BOTTOM w0.254: PR117.1 198.59,80.82 198.06,81.35 PC127.2
N40598592: length 8.5
  TOP w0.254: PC128.1 187.61,101.79 188,102.17 PD102.2 187.24,103.62 v1(187.24,104.31) 187.24,104.66 187.63,105.05 PQ102.1 ; PC128.1 PR114.2 PR121.2 PR120.2 ; PC128.1 PR122.1
N40598619: length 6.1
  TOP w0.254: PQ102.3 190.95,105.7 191.52,105.13 v1(191.52,104.8) 191.52,103.99 PD102.1 190.4,102.36 191.16,101.59 PR116.2
N40605947: length 4.4
  TOP w0.254: PU300.15 153.01,29.1 153.32,29.1 154.28,30.07 v1(154.28,30.18) v2(154.28,30.74)
  BOTTOM w0.254: PR303.2 PC305.1 153.98,31.05 v2(154.28,30.74)
N40606056: length 0.9
  BOTTOM w0.254: PR309.2 152.28,24.67 PR308.1
N40638141:
  vias: v4(17.53,83.64)
N40638178: length 1.8
  TOP w0.102: T4973.1 216.77,4.17 v2(216.83,4.24)
  BOTTOM w0.102: JSSD1.61 217.04,4.03 v2(216.83,4.24)
N40638747: length 4.5
  TOP w0.102: PR790.2 185.39,46.41 v1(185.78,46.81)
  TOP w0.254: PR790.2 184.45,45.98 184.24,45.78 183.73,45.78 183.53,45.58 PC790.1 183.51,45.19 PQ721.2
N40641471: length 3.7
  TOP w0.102: PQ720.1 182.34,47.56 182.34,48.32 v1(182.85,48.83)
  TOP w0.254: PR790.1 PR791.2 183.53,47.37 PQ720.1
N40740280:
  vias: v1(38.94,88.97)
N40862903: length 2.5
  TOP w0.254: RS19.2 204.37,18.7 v1(204.54,18.87) 205.27,19.6 US2.7
N40862946: length 4
  TOP w0.254: RS25.2 209.13,18.71 v1(208.92,18.93) 208.41,19.44 207.01,19.44 206.77,19.68 US2.10
N40863062: length 3.5
  TOP w0.254: RS22.2 RS20.2 205.77,25.66 v1(205.39,25.28) 205.39,24.95 205.77,24.57 US2.18
N40870793: length 4.1
  TOP w0.102: RHO9.2 17.44,70.36 v2(17.42,70.38) ; v2(17.07,67.94) 17.44,68.31 CHO8.2
  IN1 w0.114: v2(17.42,70.38) 17.42,68.29 v2(17.07,67.94)
N40871013: length 4.2
  TOP w0.102: v2(17.66,67.94) 17.66,67.52 RHO11.2 ; CHO10.2 17.44,65.92 v2(17.06,65.54)
  IN1 w0.114: v2(17.06,65.54) 17.66,66.14 v2(17.66,67.94)
N40871311: length 4.1
  TOP w0.102: CHO9.2 17.44,71.01 v2(16.84,70.41) ; v2(17.2,72.78) 17.44,72.54 RHO10.2
  IN1 w0.114: v2(16.84,70.41) 17.2,70.77 v2(17.2,72.78)
N40871582: length 4
  TOP w0.102: RHO12.2 17.44,65.31 v2(17.66,65.53) ; CHO11.2 v2(17.44,63.04)
  IN1 w0.114: v2(17.66,65.53) 17.44,65.31 v2(17.44,63.04)
N40969705: length 1.1
  BOTTOM w0.102: 27.19,72.16 26.47,72.16 v4(26.23,72.4)
N41096148: length 3
  TOP w0.102: v1(164.16,13.53) CZ70.1
  TOP w0.254: UZ21.6 163.91,14.98 CZ70.1
N41096439: length 20.2
  TOP w0.508: R6511.2 28.35,17.33 27.59,16.57 27.59,13.56 26.71,12.68 v4(26.71,12.28) 25.77,11.34 25.77,9.61 26.41,8.97 35.32,8.97 35.86,9.51 R6529.2
N41121585: length 5.4
  TOP w0.102: DZ1702.2 109.08,16.61 RC130.2 CC93.2 108.93,14.71 v1(108.93,14.09) 108.93,13.79 109.2,13.52 UC13.2
N41122944: length 21.5
  IN1 w0.114: v2(113.23,16.95) 113.23,15.62 113.64,15.21 117.17,15.21 117.82,15.86 v2(117.82,22.92)
  BOTTOM w0.102: RPC5.5 115.97,17.22 115.7,16.95 v1(114.11,16.95) v2(113.23,16.95) ; v2(117.82,22.92) 117.82,23.41 117.53,23.71 117.03,23.71 116.87,23.87 116.87,25.14 116.39,25.62 116.39,26.55 RC60.2
N41123043: length 18.6
  IN1 w0.114: v2(121.63,15.62) 121.63,16.12 121.38,16.38 120.74,16.38 120.58,16.54 120.58,16.85 120.74,17.01 122.08,17.01 122.2,17.14 122.2,17.46 122.08,17.58 118.65,17.58 118.5,17.73 118.5,18.01 118.65,18.16 121.63,18.16 121.76,18.28 121.76,18.6 121.63,18.73 119.54,18.73 119.35,18.92 v2(119.35,19.55)
  BOTTOM w0.102: RC1120.2 118.15,19.91 118.51,19.55 v2(119.35,19.55) ; v2(121.63,15.62) 121.95,15.93 RC61.1
N41149073: length 4
  BOTTOM w0.102: QC5.3 197,16.14 197.16,15.98 197.16,15.63 197.02,15.49 QC5.2 195.62,15.49 RS39.2 v1(195.35,14.13)
N41335354: length 6
  TOP w0.102: R3022.2 33.25,76.21 32.77,76.69 31.37,76.69 30.32,77.74 UL3.3 30.32,79.08 v1(29.73,79.66)
N41378522: length 3.6
  TOP w0.127: PR15.1 166.53,27.08 v1(166.98,27.08)
  TOP w0.254: PR15.1 165.94,28 v2(166.22,28.28)
  BOTTOM w0.254: v2(166.22,28.28) 166.49,28.28 166.75,28.54 PBATT1.5
N41421024: length 1.6
  BOTTOM w0.102: T4932.1 23.45,48 RE422.1
N41548189: length 4.4
  TOP w0.102: v1(33.26,72.31) 33.48,72.52 35.17,72.52 RZ1709.1 35.8,73.16 UZ13.7
N41548228: length 3.6
  TOP w0.102: UZ13.15 43.89,68.61 44.62,67.88 RZ1708.2 44.97,67.38 44.76,67.16 v1(44.76,66.54)
N41548319:
  vias: v2(43.79,77.62)
N41715557: length 6.3
  TOP w0.102: JUSB1.10 11.79,42.45 13.44,42.45 v1(13.97,42.98) 14.91,43.92 R6531.2 15.62,44.81 C6220.2
N41825015: length 14.9
  TOP w0.254: RC1134.2 v1(141.75,72.88) 141.31,72.88 v2(141.19,72.77)
  IN2 w0.254: v2(132.3,68.1) 132.66,68.47 134.3,68.47 136.68,70.84 136.68,71.75 137.69,72.77 v2(141.19,72.77)
  BOTTOM w0.254: UC1.G61 131.74,68.1 v2(132.3,68.1)
N41863697: length 2.9
  BOTTOM w0.102: v1(28.27,67.03) 27.85,66.61 RX15.1 27.84,66.1 QX5.2
N41863897: length 2.8
  BOTTOM w0.102: DX4.3 21.61,74.62 21.53,74.54 RHR11.2 20.87,75.14 v1(20.46,75.55)
N41863899: length 2.9
  BOTTOM w0.102: DX4.2 21.8,73.32 21.47,73.65 RHR8.2 20.87,73.19 v1(20.39,72.7)
N41864735:
  vias: v1(21.05,63.09)
N41865724: length 3.1
  BOTTOM w0.102: v1(161.36,60.19) 160.8,59.62 PR655.2
  BOTTOM w0.254: PU603.14 161.69,58.22 161.33,58.58 161.03,58.58 160.8,58.81 PR655.2
N41866336: length 2.8
  BOTTOM w0.102: PC655.2 v1(163.64,53.41)
  BOTTOM w0.254: PU603.5 162.5,55.2 163.3,54.4 PC655.2
N41866349: length 1.4
  BOTTOM w0.254: PR659.2 163.53,56.7 PU603.2
N41866816: length 17.4
  TOP w0.508: v2(30.27,94.4) 30.69,94.4 v1(30.93,94.17) 31.04,94.05 31.04,92.5 30.59,92.05 CL46.2 30.02,92.04 v2(30.02,90.72) v2(30.02,87.79) v2(30.02,84.76) 30.02,84.05 C229.2
  BOTTOM w0.508: TL1.1 29.73,94.2 29.93,94.4 v2(30.27,94.4) ; v2(30.02,87.79) 29.61,88.2 TL1.7 ; v2(30.02,84.76) 29.58,85.2 TL1.10 ; TL1.4 29.54,91.2 v2(30.02,90.72)
N41870308: length 2.3
  BOTTOM w0.254: PU605.5 168.31,82.25 168.47,82.09 PC671.2
N41918231: length 6.8
  TOP w0.102: UL1.26 37.41,88.52 37.9,89.01 38.18,89.01 38.54,89.36 38.54,89.51 39.41,90.39 39.41,91.56 40.06,92.2 40.06,93.3 T4977.1
N41918233: length 5.9
  TOP w0.102: UL1.25 37.81,88.32 38.76,89.27 38.76,89.42 39.64,90.3 39.64,91.46 40.69,92.51 T4976.1
N41918243: length 5.5
  TOP w0.102: T4978.1 39.58,92.05 39.18,91.65 39.18,90.49 38.31,89.61 38.31,89.46 38.09,89.24 37.81,89.24 37.01,88.45 UL1.27
N42060658: length 5.4
  TOP w0.102: R6211.2 49.56,20.95 Q2405.1 48.23,22.19 v1(47.02,23.4)
N42923938: length 3.6
  TOP w0.203: PR620.2 v1(168.29,63.7) 167.57,64.42 167.57,65.18 167.51,65.24 PU602.1
N124752685: length 2.2
  TOP w0.102: v1(69.54,38.32) 70.15,38.93 RH211.1 CH101.2
N124753277: length 1.9
  TOP w0.102: CH100.2 RH212.1 v1(57.43,47.39)

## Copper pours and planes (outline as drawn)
2.5V_VIN on TOP (solid shape): 73.47,12.03 73.47,10.59 73.12,10.24 72.67,10.24 72.34,9.91 72.34,9.63 71.91,9.2 70.7,9.2 70.58,9.33 70.58,9.69 71.1,9.69 71.1,10.2 70.58,10.2 70.58,10.49 71.1,10.49 71.1,11 70.58,11 70.58,11.87 70.77,12.06 70.78,12.06 70.84,12.11 73.38,12.11
2.5V_VIN on BOTTOM (solid shape): 74.85,10.72 74.85,10.4 74.68,10.22 74.65,10.22 74.64,10.22 73.13,10.22 73.05,10.29 72.57,10.29 72.34,10.07 72.34,9.71 72.22,9.58 71.66,9.58 71.45,9.79 71.45,10.62 71.72,10.89 74.68,10.89
3V_VIN on TOP (solid shape): 180.5,83.56 180.5,82.29 180.37,82.16 179.1,82.16 178.84,82.42 178.84,83.43 179.1,83.69 180.37,83.69
3V_VIN on BOTTOM (solid shape): 179.02,85.58 179.52,85.58 179.52,86.1 179.82,86.1 179.82,85.58 180.32,85.58 180.32,86.05 180.37,86.1 182.08,86.1 182.34,85.85 182.34,84.01 182.27,83.94 181.14,83.94 180.74,83.55 180.74,82.5 180.31,82.07 180.21,81.97 180.21,80.65 180.33,80.53 181.02,80.53 181.11,80.44 181.11,78.99 181.04,78.93 179.73,78.93 179.35,79.31 178.53,79.31 178.25,79.59 178.25,83.5 177.83,83.91 177.83,85.85 178.08,86.1 179.02,86.1
5V_HDD on TOP (solid shape): 214.28,9.58 214.28,8.31 214.21,8.25 212.56,8.25 212.5,8.31 212.5,9.59 212.62,9.71 214.15,9.71
5V_HDD on BOTTOM (solid shape): 204.89,15.73 204.89,14.54 204.75,14.41 201.52,14.41 201.23,14.7 201.23,15.78 201.33,15.88 204.74,15.88
5V_HDD on BOTTOM (solid shape): 214.28,10.6 214.28,9.08 214.12,8.93 212.61,8.93 212.5,9.04 212.5,10.6 212.59,10.69 214.19,10.69
5V_HDD on IN2 (solid shape): 213.96,9.59 214.08,9.59 214.26,9.41 214.26,9.06 213.94,8.73 212.65,8.73 211.33,10.05 211.33,10.32 212.13,11.11 212.44,11.11
5V_HDD on IN2 (solid shape): 206.02,14.28 206.02,13.77 205.45,13.2 203.93,13.2 203.74,13.39 203.36,13.39 203.04,13.71 203.04,14.85 203.23,15.04 205.26,15.04
5V_SN on TOP (solid shape): 193.2,81.4 193.2,80 192.88,79.69 192.88,79.18 193.13,78.93 193.13,77.97 193.07,77.91 191.48,77.91 191.42,77.97 191.42,79.75 192.31,80.64 192.31,81.47 192.37,81.53 193.07,81.53
5V_VIN on TOP (solid shape): 191.04,83.43 191.04,82.04 190.97,81.97 189.77,81.97 189.51,82.23 189.51,83.37 189.7,83.56 190.91,83.56
5V_VIN on BOTTOM (solid shape): 188.48,85.33 188.99,85.33 188.99,85.76 189.28,85.76 189.28,85.33 189.79,85.33 189.79,85.76 191.32,85.76 191.78,85.3 191.78,83.86 191.35,83.43 191.35,80.64 191.54,80.45 192.05,80.45 192.16,80.34 192.16,78.91 192.05,78.8 190.91,78.8 190.21,79.5 189.07,79.5 188.37,80.2 188.37,82.28 187.35,83.29 187.35,85.28 187.83,85.76 188.48,85.76
+0.6V_DDR_VTT on TOP (solid shape): 60.36,20.98 60.36,20.4 59.85,19.89 59.85,19.45 59.27,18.86 56.67,18.86 56.36,19.17 56.02,19.17 55.91,19.29 55.91,20.58 55.99,20.66 59.28,20.66 59.67,21.05 60.3,21.05
+0.6V_DDR_VTT on TOP (solid shape): 74.51,20.57 74,20.57 73.5,20.06 73.5,19.97 73.37,19.85 72.81,19.85 72.1,19.14 69.92,19.14 69.91,19.19 69.82,19.36 69.64,19.43 69.61,19.43 69.17,19.87 69.17,20.54 69.36,20.73 71.86,20.73 71.87,20.73 73.42,20.73 73.76,21.08 74.51,21.08
+0.6V_DDR_VTT on BOTTOM (solid shape): 71.94,20.25 71.94,19.62 71.66,19.34 70.89,19.34 70.74,19.49 70.74,19.67 70.25,20.16 68.62,20.16 68.52,20.26 68.52,20.38 68.62,20.48 70.23,20.48 70.25,20.5 71.69,20.5
+0.6V_DDR_VTT on BOTTOM (solid shape): 74.76,108.38 74.76,105.97 74.62,105.82 73.26,105.82 73.12,105.97 73.12,106.95 72.58,106.95 72.58,107.2 73.12,107.2 73.12,107.75 72.58,107.75 72.58,108 73.12,108 73.12,108.46 73.16,108.49 74.65,108.49
+0.6V_DDR_VTT on BOTTOM (solid shape): 59.85,20.12 59.85,19.46 59.62,19.24 59.62,18.5 59.31,18.19 56.29,18.19 56.06,18.42 56.06,19.16 56.24,19.34 57.92,19.34 58,19.43 58,19.93 57.78,20.16 55.84,20.16 55.71,20.29 55.71,20.35 55.84,20.48 59.49,20.48
+0.6V_DDR_VTT on IN2 (solid shape): 71.91,19.68 71.91,19.17 71.09,18.35 70.39,18.35 70.39,19.36 70.87,19.85 71.75,19.85
+0.6V_DDR_VTT on IN2 (solid shape): 60.29,20.61 60.29,19.94 59.71,19.36 58.89,19.36 58.76,19.5 58.76,19.91 59.6,20.76 60.14,20.76
+0.6VSP on BOTTOM (solid shape): 72.97,108.43 72.97,108.13 72.45,108.13 72.45,107.62 72.97,107.62 72.97,107.33 72.45,107.33 72.45,106.82 72.97,106.82 72.97,105.99 72.82,105.84 71.9,105.84 71.28,106.46 68.99,106.46 68.78,106.68 67.82,106.68 67.65,106.84 67.65,108.41 67.74,108.49 72.91,108.49
+1.0V_APLL on TOP (solid shape): 125.53,42.44 126.01,41.96 126.25,41.96 126.36,41.85 126.36,41.51 126.25,41.4 125.96,41.4 125.67,41.1 125.67,40.51 125.52,40.36 125,40.36 124.96,40.39 124.96,40.78 124.97,40.86 124.96,40.93 124.96,42.11 124.8,42.27 124.8,42.48 124.8,42.48 124.8,43.3 124.88,43.39 124.88,44.02 124.97,44.11 125.53,44.11
+1.0V_CLK2 on TOP (solid shape): 130.5,44.38 130.71,44.38 130.92,44.17 130.92,43.95 131.36,43.51 131.55,43.51 131.95,43.11 132.01,43.11 132.02,43.11 132.17,43.07 132.31,43.11 132.32,43.11 132.69,43.11 132.7,43.11 132.85,43.07 132.99,43.11 133,43.11 133.05,43.11 133.08,43.09 133.47,43.48 133.92,43.48 134.33,43.07 134.33,42.69 134.05,42.41 131.46,42.41 131.25,42.62 131.25,42.63 131.05,42.83 130.54,42.83 130.34,43.03 130.34,44.06 130.14,44.25 130.14,44.51 130.2,44.57 130.31,44.57
+1.0V_CLK5 on TOP (solid shape): 130.01,45.63 130.01,44.32 130.01,44.32 130.01,44.16 130.23,43.95 130.23,43.52 130.16,43.44 129.65,43.44 129.56,43.54 129.56,43.96 129.59,43.97 129.73,44.11 129.77,44.29 129.71,44.51 129.52,44.64 129.5,44.64 129.5,45.22 129.22,45.49 129.22,45.66 129.34,45.78 129.86,45.78
+1.0V_CLK5 on IN1 (solid shape): outline of 123 points within 129.43,45.24 132.47,47.77
+1.0V_MPHYPLL on TOP (solid shape): outline of 1399 points within 126.76,20.67 149.51,43.87
+1.0V_MPHYPLL on BOTTOM (solid shape): 128.35,44.03 128.35,43.9 128.32,43.87 128.3,43.84 128.24,43.77 128.24,43.51 128.73,43.01 128.73,42.56 128.93,42.36 129.83,42.36 130.09,42.1 130.09,41.58 129.93,41.42 128.53,41.42 128.52,41.43 127.4,41.43 126.77,42.05 126.77,42.48 126.9,42.6 127.09,42.6 127.55,43.06 127.55,43.14 127.62,43.3 127.56,43.47 127.55,43.49 127.55,43.53 127.54,43.54 127.54,43.75 127.73,43.94 127.96,43.94 128.16,44.14 128.24,44.14
+1.0V_MPHYPLL on IN3 (solid shape): outline of 659 points within 122.3,41.56 128.73,46.26
+1.0V_PRIM on TOP (solid shape): outline of 278 points within 121.56,43.42 129.13,46.73
+1.0V_PRIM on TOP (solid shape): outline of 1510 points within 114.14,12.47 162.14,32.89
+1.0V_PRIM on BOTTOM (solid shape): 147.16,20.52 147.86,20.52 147.86,21.03 148.36,21.03 148.36,20.52 149.06,20.52 149.06,21.03 150.36,21.03 150.71,20.68 150.71,17.92 150.43,17.64 146.44,17.64 146.24,17.85 146.24,20.8 146.46,21.03 147.16,21.03
+1.0V_PRIM on IN1 (solid shape): outline of 4620 points within 113.46,31.17 129.72,48.45
+1.0V_PRIM on IN2 (solid shape): outline of 824 points within 125.56,38.41 136.49,46.64
+1.0V_PRIM on VCC: 114.31,31.17 113.44,32.04 113.44,44.66 115.2,46.41 126.29,46.41 131.11,41.59 136.32,41.59 136.81,41.1 136.81,36.74 132.89,32.82 120.45,32.82 118.8,31.17
+1.0V_VCCST on TOP (solid shape): 169.85,16.82 169.85,16.35 168.71,15.21 164.88,15.21 164.81,15.28 164.81,16.1 164.97,16.27 167.76,16.27 168.52,17.03 169.65,17.03
+1.0V_VCCST on TOP (solid shape): outline of 204 points within 129.16,43.29 136.83,46.54
+1.0V_VCCST on BOTTOM (solid shape): 177.35,22.85 177.35,21.9 177.05,21.59 176.33,21.59 176.05,21.87 176.05,22.89 176.21,23.04 177.16,23.04
+1.0V_VCCST on BOTTOM (solid shape): 136.68,44.01 136.68,43.72 136.54,43.58 135.75,43.58 135.56,43.78 134.9,43.78 134.77,43.91 134.77,44.2 134.82,44.25 136.44,44.25
+1.0V_VCCST on BOTTOM (solid shape): 170.28,17.4 170.28,16.92 169.64,16.29 168.87,16.29 168.66,16.5 168.66,16.61 168.65,16.61 168.65,17.08 169.44,17.86 169.82,17.86
+1.0V_VCCST on BOTTOM (solid shape): 162.87,62.97 163.11,62.89 163.34,62.98 166.19,62.98 166.27,62.89 166.27,62.32 166.2,62.24 163.04,62.24 162.86,62.06 162.86,60.43 162.27,59.84 161.83,59.84 161.68,59.99 161.68,60.46 162.04,60.82 162.04,62.71 162.32,62.98 162.86,62.98
+1.0V_VCCST on BOTTOM (solid shape): 130.35,46.03 130.35,45.66 130.39,45.62 130.4,45.61 130.46,45.51 130.56,45.45 130.57,45.44 130.66,45.36 130.66,45.1 130.58,45.03 130.57,45.02 130.51,45 130.47,44.96 129.87,44.96 129.71,45.11 129.71,45.32 129.82,45.56 129.71,45.8 129.71,46.03 129.8,46.12 130.26,46.12
+1.0V_VCCST on BOTTOM (solid shape): 141.49,74.92 141.49,74.35 142.27,73.57 142.26,73.53 142.25,73.38 142.32,73.24 142.32,67.33 141.89,66.9 141.41,66.9 141.4,66.91 141.34,66.91 141.23,67.01 141.23,67.53 141.55,67.84 141.55,72.72 141.55,72.77 141.55,72.81 141.55,73.11 141.25,73.4 141.25,73.41 141.18,73.51 141.09,73.57 141.08,73.58 140.76,73.89 140.76,74.92 140.87,75.03 141.38,75.03
+1.0V_VCCST on IN1 (solid shape): 143.37,73.56 143.37,73.21 142.94,72.78 142.55,72.78 142.17,73.16 141.33,73.16 141.09,73.41 141.09,74.08 141.28,74.27 142.66,74.27
+1.0V_VCCST on IN1 (solid shape): outline of 114 points within 157.4,59.98 162.65,62.07
+1.0V_VCCST on IN3 (solid shape): 137,45 137,43.85 136.72,43.57 136.18,43.57 135.77,43.97 135.77,44.96 135.99,45.17 136.83,45.17
+1.0V_VCCST on IN3 (solid shape): 177.35,23.79 177.35,22.71 177.19,22.56 176.22,22.56 176.08,22.7 176.08,23.77 176.31,24.01 177.14,24.01
+1.0V_VCCST on IN3 (solid shape): 136.53,52.68 136.53,50.25 135.97,49.68 135.21,49.68 134.87,50.03 134.87,51.63 135.23,51.63 135.23,51.58 135.23,51.52 135.25,51.48 135.27,51.43 135.31,51.39 135.34,51.35 135.38,51.32 135.43,51.3 135.48,51.28 135.53,51.27 135.58,51.27 135.63,51.28 135.68,51.3 135.73,51.32 135.77,51.35 135.81,51.39 135.84,51.43 135.86,51.48 135.88,51.52 135.89,51.58 135.89,51.63 135.88,51.68 135.86,51.73 135.84,51.77 135.81,51.82 135.77,51.85 135.73,51.88 135.68,51.91 135.63,51.92 135.58,51.93 135.53,51.93 135.48,51.92 135.43,51.91 135.38,51.88 135.34,51.85 135.31,51.82 135.27,51.77 135.25,51.73 135.23,51.68 135.23,51.63 134.87,51.63 134.87,52.75 135.31,53.19 136.02,53.19
+1.0V_VCCST on IN3 (solid shape): 163.31,60.69 164.34,60.69 164.59,60.44 164.59,59.47 164.35,59.23 162.41,59.23 161.65,59.98 161.65,60.13 162.82,60.13 162.82,60.08 162.83,60.02 162.84,59.97 162.86,59.93 162.89,59.88 162.93,59.84 162.97,59.81 163.02,59.78 163.07,59.76 163.12,59.75 163.17,59.75 163.23,59.75 163.28,59.76 163.33,59.78 163.37,59.81 163.42,59.84 163.45,59.88 163.48,59.93 163.51,59.97 163.52,60.02 163.53,60.08 163.53,60.13 163.52,60.18 163.51,60.23 163.48,60.28 163.45,60.33 163.42,60.37 163.37,60.4 163.33,60.43 163.28,60.44 163.23,60.46 163.17,60.46 163.12,60.46 163.07,60.44 163.02,60.43 162.97,60.4 162.93,60.37 162.89,60.33 162.86,60.28 162.84,60.23 162.83,60.18 162.82,60.13 161.65,60.13 161.65,60.36 162.18,60.88 163.12,60.88
+1.0V_VCCST on IN3 (solid shape): 142.56,67.67 142.56,66.75 142.36,66.55 142.35,66.54 142.2,66.45 142.1,66.3 142.1,66.29 141.86,66.05 141.84,66.05 141.48,65.81 141.61,65.4 141.61,65.1 141.46,64.8 141.61,64.51 141.61,64.21 141.46,63.91 141.61,63.62 141.61,63.32 141.46,63.03 141.61,62.73 141.61,62.43 141.46,62.14 141.61,61.84 141.61,61.54 141.46,61.25 141.61,60.95 141.61,60.65 141.46,60.36 141.61,60.06 141.61,59.84 141.33,59.56 140.77,59.56 140.44,59.89 140.44,60.4 140.55,60.51 140.55,62.96 140.91,63.33 140.91,66.52 141.26,66.86 141.26,67.19 142.1,68.03 142.21,68.03
+1.0V_VCCST_C on TOP (solid shape): 164.46,16.09 164.46,15.37 164.42,15.32 162.11,15.32 162.02,15.42 162.02,16.06 162.14,16.19 164.37,16.19
+1.0V_VCCSTG on TOP (solid shape): 146.21,70.65 146.21,67.65 145.75,67.19 144.15,67.19 144.07,67.27 144.07,67.62 144.55,68.11 144.55,69.08 144.62,69.15 145.21,69.15 145.44,69.38 145.44,69.78 145,70.23 145,71.18 145.06,71.24 145.62,71.24
+1.0V_VCCSTG on IN2 (solid shape): outline of 272 points within 130.74,42.81 134.6,45.55
+1.0V_VCCSTG_C on TOP (solid shape): 165.05,20.41 165.59,20.41 165.59,20.96 165.83,20.96 165.85,20.95 165.85,20.51 165.85,20.51 165.85,20.41 166.45,20.41 166.55,20.3 166.55,18.99 166.44,18.88 166.44,18.13 166.42,18.12 162.55,18.12 162.4,18.27 162.4,20.14 162.67,20.41 164.79,20.41 164.79,20.96 165.05,20.96
+1.0VS_VCCIO on TOP (solid shape): 119.55,57.71 119.55,57.54 119.61,57.48 119.78,57.48 119.87,57.39 120.32,57.39 120.5,57.21 120.5,57.01 120.34,56.85 119.26,56.85 119.2,56.92 119.2,57.19 118.52,57.86 118.52,58.18 118.62,58.28 118.98,58.28
+1.0VS_VCCIO on TOP (solid shape): 163.41,23.49 172.81,23.49 173.26,23.05 173.26,20.89 173,20.63 165.97,20.63 165.97,21.09 165.47,21.09 165.47,20.63 165.17,20.63 165.17,21.09 164.67,21.09 164.67,20.63 153.44,20.63 153.25,20.82 153.25,23.68 153.44,23.87 163.03,23.87
+1.0VS_VCCIO on TOP (solid shape): 119.64,51.24 120.56,51.24 120.7,51.1 120.7,50.63 120.7,50.39 120.05,49.74 118.62,49.74 117.99,50.37 117.99,51.24 118.03,51.29 118.26,51.29 118.48,51.5 118.48,51.76 118.61,51.9 118.98,51.9
+1.0VS_VCCIO on BOTTOM (solid shape): 119,58.13 119,57.84 119.56,57.29 120.38,57.29 120.46,57.2 120.46,57.02 120.35,56.91 120.06,56.91 119.99,56.92 119.92,56.91 119.49,56.91 118.53,57.87 118.53,58.14 118.59,58.2 118.93,58.2
+1.0VS_VCCIO on BOTTOM (solid shape): 119.39,51.3 120.14,51.3 120.2,51.3 120.26,51.32 120.56,51.32 120.76,51.12 120.76,50.36 120.5,50.1 119,50.1 118.62,50.48 118.59,50.5 118.48,50.61 118.48,50.93 118.51,50.95 118.66,51.18 118.51,51.41 118.49,51.42 118.48,51.43 118.48,51.74 118.61,51.88 118.82,51.88
+1.0VS_VCCIO on IN2 (solid shape): outline of 3887 points within 118.52,20.97 157.83,58.22
+1.0VS_VCCOPC on TOP (solid shape): outline of 3427 points within 114.08,67.66 128.43,99.56
+1.0VS_VCCOPC on BOTTOM (solid shape): 125.25,106.17 125.25,99.18 123.47,97.4 120.55,97.4 119.99,97.96 119.99,104.25 119.41,104.83 118.58,104.83 118.27,105.15 118.27,105.53 118.84,105.53 118.84,106.93 118.27,106.93 118.27,108.39 118.96,109.09 122.33,109.09
+1.0VS_VCCOPC on BOTTOM (solid shape): 122.48,68.93 122.48,68.83 122.45,68.75 122.35,68.65 122.33,68.65 122.27,68.63 122.21,68.59 122.02,68.4 121.58,68.4 121.17,67.99 121.16,67.93 121.15,67.88 121.12,67.84 121.06,67.78 121,67.75 120.93,67.74 120.83,67.73 120.69,67.87 120.69,68.11 120.78,68.21 120.91,68.21 121.01,68.22 121.21,68.39 121.22,68.66 121.21,68.67 121.21,68.92 121.29,69.01 122.4,69.01
+1.0VS_VCCOPCP on BOTTOM (solid shape): 118.08,107.75 118.08,104.9 118.39,104.58 119.26,104.58 119.85,103.98 119.85,103.26 119.73,103.13 113.94,103.13 113.63,103.44 113.63,107.75 113.82,107.94 117.88,107.94
+1.2V_DDR on TOP (solid shape): 93.87,37.7 85.87,37.7 85.87,45.7 93.87,45.7
+1.2V_DDR on TOP (solid shape): 98.76,79.66 90.76,79.66 90.76,87.66 98.76,87.66
+1.2V_DDR on TOP (solid shape): 99.21,62.98 84.21,62.98 84.21,72.98 99.21,72.98
+1.2V_DDR on TOP (solid shape): outline of 27038 points within 53.18,23.57 119.76,92.54
+1.2V_DDR on BOTTOM (solid shape): 97.58,104.97 97.58,91.78 96.98,91.18 88.93,91.18 88.26,91.85 88.26,97.31 88.99,98.04 91.02,98.04 91.53,98.55 91.53,102.17 91.09,102.61 90.26,102.61 90.26,103.18 90.78,103.18 90.78,103.89 90.26,103.89 90.26,104.38 90.78,104.38 90.78,105.09 90.26,105.09 90.26,105.79 90.52,106.04 96.51,106.04
+1.2V_DDR on BOTTOM (solid shape): 66.51,58.61 66.77,58.35 67.66,58.35 68.04,58.73 68.29,58.73 68.29,57.21 67.72,57.21 67.4,56.89 67.4,56.07 67.66,55.81 68.29,55.81 68.29,51.18 68.23,51.11 67.97,51.11 67.28,51.81 66.32,51.81 66.18,51.67 66.07,51.64 66.01,51.74 66.01,51.87 66.13,52 66.13,58.8 66.51,58.8
+1.2V_DDR on BOTTOM (solid shape): 67.91,48.25 68.12,48.25 68.31,48.06 68.31,44.4 67.78,43.87 67.4,43.87 67.21,44.06 67.21,44.61 67.17,44.61 67.15,44.64 66.82,44.88 66.44,44.73 66.4,44.71 66.35,44.72 66.21,44.79 66.05,44.79 66.02,44.79 65.94,44.86 65.94,45.41 65.95,45.43 65.98,45.58 65.95,45.72 65.94,45.74 65.94,45.91 65.95,45.93 65.98,46.08 65.95,46.22 65.94,46.24 65.94,46.79 66.2,47.05 66.2,48.02 66.43,48.25 67.91,48.25
+1.2V_DDR on BOTTOM (solid shape): 54.97,45.79 55.01,45.67 55.12,45.28 55.52,45.15 55.61,45.18 55.67,45.15 55.68,45.13 55.8,45.01 55.98,44.97 57.42,44.97 57.44,44.97 57.53,44.93 57.57,44.84 57.57,44.76 57.51,44.7 55.72,44.7 55.59,44.57 55.02,44.57 54.7,44.89 54.7,44.91 54.49,45.12 54.49,45.67 54.54,45.77 54.64,45.8 54.74,45.79 54.85,45.82
+1.2V_DDR on BOTTOM (solid shape): outline of 107 points within 76.71,47.94 82.58,59.37
+1.2V_DDR on BOTTOM (solid shape): outline of 130 points within 53.56,45.98 57.57,59.11
+1.2VP on BOTTOM (solid shape): 90.13,107.89 90.13,104.98 90.14,104.98 90.14,104.96 90.65,104.96 90.65,104.51 90.14,104.51 90.14,104.49 90.13,104.49 90.13,103.78 90.14,103.78 90.14,103.76 90.65,103.76 90.65,103.31 90.14,103.31 90.14,103.29 90.13,103.29 90.13,102.44 90.25,102.32 90.79,102.32 90.94,102.17 90.94,100.6 90.86,100.52 87.6,100.52 87.09,100.01 87.09,99.63 86.96,99.51 84.77,99.51 84.7,99.58 84.7,100.87 84.99,101.16 84.99,107.75 85.31,108.07 89.94,108.07
+1.8V_PRIM on TOP (solid shape): 37.94,10.66 38,10.6 38,10.09 38.7,9.39 39.21,9.39 39.38,9.22 39.38,8.33 39.17,8.12 38.07,8.12 36.9,9.29 36.9,10.62 36.95,10.66 37.94,10.66
+1.8V_PRIM on TOP (solid shape): outline of 940 points within 120.87,18.68 134.06,42.58
+1.8V_PRIM on BOTTOM (solid shape): 40.22,10.12 40.22,9.68 39.7,9.68 39.7,9.17 40.22,9.17 40.22,8.88 39.7,8.88 39.7,8.37 40.22,8.37 40.22,8.09 40.23,8.09 40.23,7.99 40.2,7.96 38.67,7.96 38.47,8.16 38.47,10 38.66,10.19 40.16,10.19
+1.8V_PRIM on IN2 (solid shape): 39.84,9.2 39.84,7.04 39.02,7.04 38.7,7.36 38.7,9.27 38.83,9.39 39.65,9.39
+1.8V_PRIM on IN2 (solid shape): 126.29,9.18 126.29,8.24 126.14,8.08 123.96,8.08 123.55,8.49 123.55,9.15 123.93,9.53 125.95,9.53
+1.8V_PRIM on IN3 (solid shape): outline of 316 points within 124.67,8.72 134.35,19.4
+1.8VALWP on TOP (solid shape): 41.51,8.14 41.51,7.14 41.38,7.01 40.14,7.01 40.09,7.05 40.09,8.21 40.23,8.34 41.32,8.34
+1.8VALWP on BOTTOM (solid shape): 44.92,11.83 44.92,6.28 44.67,6.03 40.86,6.03 40.8,6.09 40.8,6.85 40.35,7.3 40.35,7.94 40.36,7.94 40.36,8.14 40.35,8.14 40.35,8.5 39.83,8.5 39.83,8.75 40.35,8.75 40.35,9.3 39.83,9.3 39.83,9.55 40.35,9.55 40.35,10.22 41.1,10.97 41.1,12.05 41.15,12.11 44.65,12.11
+1VALWP on BOTTOM (solid shape): 147.25,28.18 147.25,25.61 147.62,25.24 147.62,22.83 147.79,22.65 150.07,22.65 150.35,22.37 150.35,21.46 150.09,21.2 148.95,21.2 148.94,21.19 148.94,20.65 148.49,20.65 148.49,21.15 148.46,21.15 148.46,21.17 147.76,21.17 147.76,21.15 147.74,21.15 147.74,20.65 147.29,20.65 147.29,21.15 147.28,21.15 147.28,21.19 145.05,21.19 144.43,21.81 144.43,23.98 144.04,24.37 144.04,28.17 144.18,28.3 147.13,28.3
+2.5V_MEM on TOP (solid shape): 80.97,20.21 80.97,19.38 80.75,19.16 78.08,19.16 77.82,19.43 76.96,19.43 76.83,19.55 76.83,20.24 77.02,20.43 80.74,20.43
+2.5V_MEM on TOP (solid shape): 64.58,20.63 67,20.63 67.08,20.55 67.08,19.81 66.69,19.42 65.38,19.42 64.93,19.87 63.15,19.87 63.09,19.93 63.09,20.57 63.16,20.64 64.57,20.64
+2.5V_MEM on TOP (solid shape): 83.77,13.03 83.77,12.81 83.77,12.81 83.77,9.96 83.54,9.72 82.29,9.72 82.2,9.81 82.2,10.2 82.72,10.2 82.72,10.71 82.2,10.71 82.2,11 82.72,11 82.72,11.51 82.2,11.51 82.2,13.07 82.39,13.27 83.53,13.27
+2.5V_MEM on BOTTOM (solid shape): 79.56,20.5 79.56,19.35 79.44,19.23 77.09,19.23 76.71,19.61 76.71,20.62 76.82,20.74 79.32,20.74
+2.5V_MEM on BOTTOM (solid shape): 66.86,20.43 66.86,19.54 66.74,19.42 65.64,19.42 65.23,19.82 64.11,19.82 64.01,19.93 64.01,20.62 64.12,20.74 66.56,20.74
+2.5V_MEM on IN2 (solid shape): 73.88,20.74 79.42,20.74 79.78,20.38 79.78,19.47 79.22,18.9 77.06,18.9 76.79,19.17 76.67,19.17 76.54,19.31 76.55,19.33 76.55,19.39 76.55,19.44 76.37,19.78 75.98,19.74 72.5,19.74 72.09,20.15 70.54,20.15 69.81,19.42 65.74,19.42 65.55,19.61 65.55,20.18 65.88,20.51 68.29,20.51 68.53,20.74 68.84,20.74 69.26,21.17 73.46,21.17
+2.5VP on TOP (solid shape): 82.01,12.25 82.01,11.37 82.59,11.37 82.59,11.13 82.04,11.13 82.04,10.58 82.59,10.58 82.59,10.33 82.58,10.33 82.04,10.33 82.04,9.84 81.9,9.7 80.94,9.7 80.51,10.13 77.78,10.13 77.38,10.52 77.38,12.23 77.65,12.49 81.77,12.49
+2.5VP on BOTTOM (solid shape): 81.82,11.54 81.82,10.93 81.11,10.22 78.32,10.22 78.13,10.41 78.13,10.69 78.33,10.9 79.9,10.9 80.66,11.67 81.69,11.67
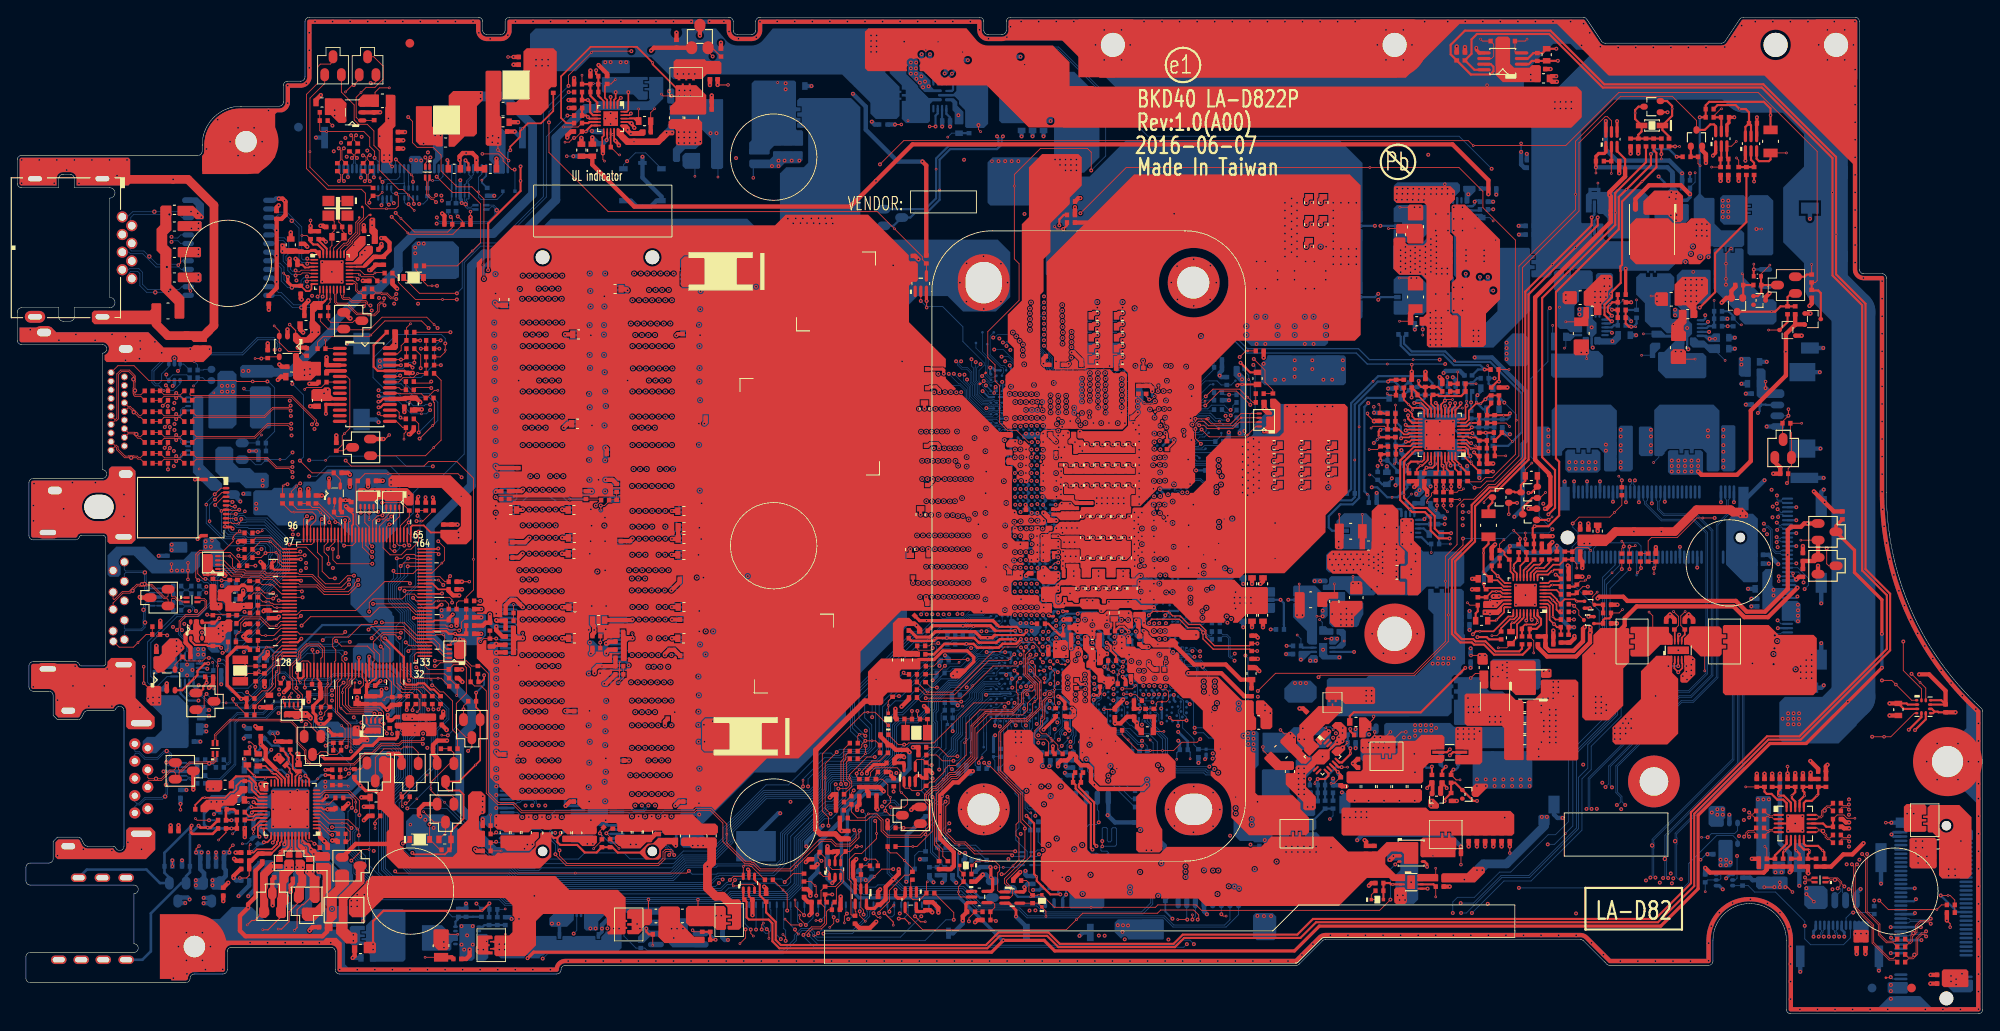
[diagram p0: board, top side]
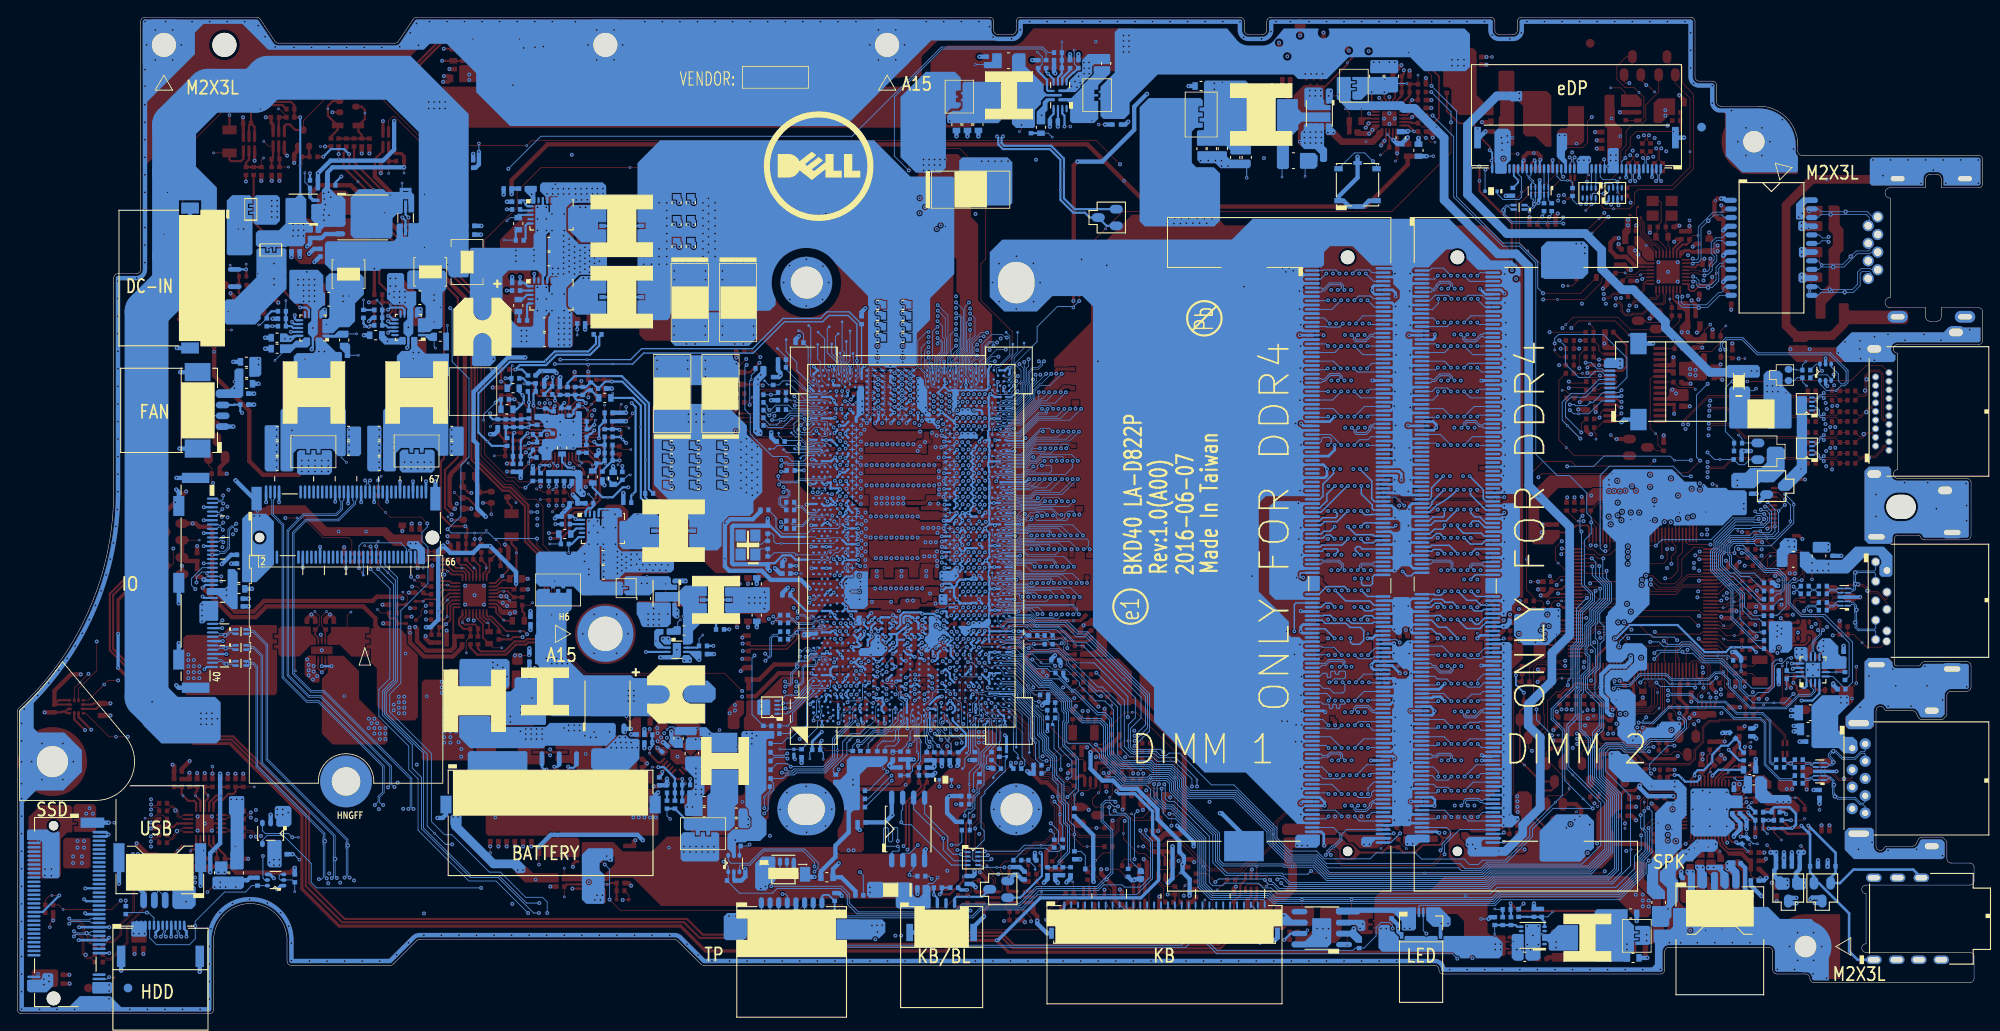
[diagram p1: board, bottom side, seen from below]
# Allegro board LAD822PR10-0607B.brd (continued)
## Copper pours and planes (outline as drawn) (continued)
+3.3V_ALW_DSW on TOP (solid shape): 109.88,39.83 109.88,39.64 109.06,38.82 108.15,38.82 107.93,39.05 107.93,39.4 108.52,39.99 109.73,39.99
+3.3V_ALW_DSW on TOP (solid shape): 104.52,40.98 104.52,40 104.39,39.87 102.34,39.87 102.14,39.67 102.14,38.98 102.39,38.73 103.44,38.73 103.53,38.63 103.53,37.29 103.44,37.2 100.74,37.2 100.23,36.69 100.23,35.97 99.99,35.73 98.61,35.73 98.45,35.89 98.45,39.62 99.98,41.14 104.36,41.14
+3.3V_ALW_DSW on IN2 (solid shape): outline of 1009 points within 108.06,38.18 120.53,44.74
+3.3V_LAN on TOP (solid shape): 41.16,88.82 41.16,88.3 41.15,88.29 41.15,88.08 39.84,86.78 38.03,86.78 37.97,86.84 37.97,86.95 38.05,87.02 38.86,87.02 39.02,87.18 39.56,87.72 39.56,87.73 39.56,88.13 40.39,88.96 41.02,88.96
+3.3V_LAN on TOP (solid shape): 35.74,82.57 35.74,82.5 35.33,82.1 35.33,81.59 35.27,81.53 34.76,81.53 34.45,81.21 34.45,80.26 35.08,79.62 35.08,78.73 34.06,77.72 33.24,77.72 33.05,77.53 32.29,77.53 31.91,77.91 31.91,78.73 32.03,78.86 32.35,78.86 32.86,78.35 33.43,78.35 33.87,78.8 33.87,82.16 34.26,82.54 35.4,82.54 35.53,82.67 35.63,82.67
+3.3V_LAN on TOP (solid shape): 31.03,89.1 31.03,88.78 31.16,88.66 32.39,88.66 32.54,88.51 33.11,88.51 33.18,88.45 33.81,88.45 33.94,88.58 34.57,88.58 34.73,88.42 35.07,88.42 35.12,88.37 35.12,87.6 35.12,87.6 35.12,87.56 35.05,87.49 34.94,87.49 34.88,87.56 34.88,87.7 34.37,88.21 34.17,88.21 34.1,88.21 33.95,88.21 33.75,88.01 30.57,88.01 30.45,88.13 30.45,89.15 30.51,89.21 30.92,89.21
+3.3V_LAN on IN3 (solid shape): outline of 144 points within 29.3,78.23 40.53,91.88
+3.3V_RUN_UZ2 on TOP (solid shape): 197.27,44.58 197.27,43.96 197.27,43.96 197.27,43.94 197.61,43.94 197.79,43.94 197.79,43.49 197.27,43.49 197.27,43.46 197.27,43.46 197.27,42.76 197.27,42.76 197.27,42.74 197.61,42.74 197.79,42.74 197.79,42.29 197.27,42.29 197.27,42.26 197.27,42.26 197.27,41.63 197.01,41.37 194.83,41.37 194.49,41.71 193.46,42.74 192.96,42.74 192.89,42.81 192.89,43.47 193.22,43.8 193.22,43.81 193.48,44.06 193.48,44.71 193.63,44.86 196.99,44.86
+3.3V_WLAN on TOP (solid shape): 200.31,57.97 200.31,57.53 200.18,57.4 199.36,57.4 199.16,57.59 198.47,57.59 198.21,57.84 198.21,58.41 198.4,58.61 199.67,58.61
+3.3V_WLAN on TOP (solid shape): 184.5,55.37 184.5,54.73 183.92,54.16 180.69,54.16 180.56,54.29 180.56,55.37 180.69,55.49 184.37,55.49
+3.3V_WLAN on BOTTOM (solid shape): 181.52,54.72 182.21,54.72 182.36,54.57 182.36,54.23 181.92,53.79 181.34,53.79 181.31,53.75 181.3,53.75 181.23,53.7 181.18,53.62 181.17,53.62 181.13,53.58 181.13,52.19 181,52.06 180.37,52.06 180.3,52.14 180.3,53.91 180.99,54.6 180.99,54.71 181.01,54.73 181.51,54.73
+3.3V_WLAN on BOTTOM (solid shape): 201.45,57.34 201.45,50.1 201.32,49.97 199.8,49.97 197.77,52 197.77,55.15 198.62,55.15 198.63,55.07 198.64,54.99 198.66,54.91 198.69,54.84 198.72,54.77 198.76,54.7 198.81,54.64 198.87,54.58 198.93,54.52 198.99,54.48 199.06,54.44 199.13,54.4 199.21,54.38 199.29,54.36 199.36,54.35 199.44,54.35 199.52,54.36 199.6,54.37 199.68,54.39 199.75,54.42 199.83,54.46 199.89,54.5 199.95,54.55 200.01,54.61 200.06,54.67 200.11,54.73 200.15,54.8 200.18,54.88 200.2,54.95 200.22,55.03 200.22,55.11 200.22,55.19 200.22,55.27 200.2,55.35 200.18,55.42 200.15,55.5 200.11,55.57 200.06,55.63 200.01,55.7 199.95,55.75 199.89,55.8 199.83,55.84 199.75,55.88 199.68,55.91 199.6,55.93 199.52,55.95 199.44,55.95 199.36,55.95 199.29,55.94 199.21,55.92 199.13,55.9 199.06,55.86 198.99,55.82 198.93,55.78 198.87,55.72 198.81,55.67 198.76,55.6 198.72,55.53 198.69,55.46 198.66,55.39 198.64,55.31 198.63,55.23 198.62,55.15 197.77,55.15 197.77,57.02 198.66,57.91 200.88,57.91
+3VALW on TOP (solid shape): 194.21,41.07 194.21,39.29 193.25,38.33 192.64,38.33 192.46,38.5 192.46,39.21 192.93,39.68 192.93,40.66 192.9,40.69 192.9,41.41 192.97,41.48 193.8,41.48
+3VALW on TOP (solid shape): 32.6,76.39 32.6,76 33.05,75.56 33.94,75.56 34,75.5 35.08,75.5 35.14,75.43 35.14,73.98 35.06,73.9 34.56,73.9 34,73.34 32.16,73.34 31.91,73.59 31.91,76.39 32.03,76.51 32.48,76.51
+3VALW on TOP (solid shape): 34.19,34.45 34.19,34.07 34.06,33.94 33.86,33.94 33.56,34.25 33.03,34.25 33.02,34.25 32.9,34.27 32.77,34.25 32.76,34.25 32.72,34.25 32.57,34.09 32.08,34.09 31.88,34.3 31.88,34.3 31.85,34.32 30.89,34.32 30.84,34.37 30.84,34.91 30.99,35.06 33.58,35.06
+3VALW on TOP (solid shape): 40.27,60.88 40.59,60.69 40.92,60.88 45.15,60.88 45.88,60.14 45.88,59.03 45.71,58.86 45.04,58.86 44.53,59.37 44.51,59.37 44.49,59.39 44.48,59.37 42.63,59.37 42.44,59.57 41.85,59.57 41.63,59.35 39.55,59.35 39.39,59.51 39.39,60.69 39.58,60.88
+3VALW on TOP (solid shape): 51.97,43.26 51.97,41.46 51.57,41.05 50.8,41.05 50.55,41.31 50.55,42.91 50.58,42.99 50.66,43.01 50.95,43.11 51.06,43.39 51.09,43.46 51.16,43.49 51.74,43.49
+3VALW on TOP (solid shape): 22.64,53.08 22.64,51.53 22.78,51.38 22.83,51.33 22.9,51.27 22.96,51.26 23.01,51.25 23.41,51.25 23.46,51.26 23.51,51.27 23.93,51.27 24.36,50.84 24.36,50.71 24.14,50.5 23.82,50.5 23.6,50.72 23.22,50.72 23.21,50.71 23.04,50.71 23.04,50.75 22.23,50.75 22.23,50.66 21.97,50.66 21.96,50.66 21.77,50.71 21.59,50.66 21.58,50.66 21.44,50.79 21.44,53.16 21.52,53.23 22.49,53.23
+3VALW on TOP (solid shape): 39.54,33.38 39.62,33.34 39.63,33.25 39.91,32.79 40.33,33.13 40.35,33.15 41.99,33.15 42.08,33.06 42.08,32.5 42.02,32.44 40.24,32.44 40.24,32.45 40.11,32.47 39.99,32.45 39.98,32.44 39.9,32.44 39.56,32.1 39.4,32.1 39.4,32.13 38.88,32.13 38.79,32.22 38.79,33.2 38.97,33.38 39.46,33.38 39.47,33.38
+3VALW on TOP (solid shape): 63.88,14.35 69.5,14.35 70.41,13.43 70.41,9.33 70.27,9.19 68.39,9.19 68.29,9.29 68.29,9.52 68.35,9.52 68.65,9.89 68.32,10.23 68.29,10.24 68.25,10.27 68.23,10.33 68.23,11.11 67.78,11.55 60.86,11.55 60.04,10.73 60.04,7.93 58.77,6.66 55.4,6.66 55.21,6.85 55.21,7.42 54.7,7.42 54.7,7.61 55.21,7.61 55.21,8.25 54.7,8.25 54.7,8.44 55.21,8.44 55.21,8.95 55.34,9.08 56.92,9.08 57.31,9.46 57.31,10.64 57.34,10.65 57.56,10.98 57.34,11.31 57.31,11.32 57.31,12.56 56.47,13.39 42.41,13.39 40.19,11.17 38.76,11.17 38.38,11.55 38.38,13.17 40.31,15.1 40.31,15.26 41.01,15.96 62.27,15.96
+3VALW on TOP (solid shape): 24.96,45.46 24.88,45.38 24.88,44.39 24.73,44.23 24.37,44.23 24.09,43.95 24.09,43.47 24.01,43.47 24.01,43.37 23.57,42.93 23.34,42.93 23.33,42.95 23.04,42.95 23.04,42.97 22.23,42.97 22.23,42.95 22.14,42.86 22.02,42.97 21.67,42.97 21.58,43.03 21.6,43.15 21.69,43.26 21.72,43.41 21.72,43.58 21.7,43.7 21.65,43.8 21.63,43.86 21.65,43.93 21.38,44.51 21.11,43.93 21.13,43.86 21.11,43.8 21.06,43.7 21.04,43.58 21.04,43.41 21.07,43.26 21.16,43.15 21.18,43.03 21.09,42.97 20.66,42.97 20.39,43.25 20.4,43.28 20.42,43.34 20.42,43.41 20.42,43.58 20.41,43.69 20.35,43.79 20.35,45.1 20.41,45.2 20.42,45.31 20.42,45.48 20.42,45.52 20.42,45.56 20.44,45.64 20.52,45.68 20.94,45.68 21.02,45.64 21.04,45.56 21.04,45.52 21.04,45.48 21.04,45.31 21.05,45.23 21.07,45.15 21.08,45.14 21.08,45.04 21.35,44.77 22.9,44.77 23.03,44.9 23.04,44.9 23.04,44.91 23.61,45.48 24.02,45.48 24.22,45.68 24.74,45.68
+3VALW on BOTTOM (solid shape): 180.31,64.84 181.01,64.84 181.01,65.34 181.51,65.34 181.51,64.84 182.21,64.84 182.21,65.34 182.91,65.34 183.23,65.02 183.23,62.99 182.91,62.67 179.48,62.67 179.16,62.99 179.16,65.08 179.42,65.34 180.31,65.34
+3VALW on BOTTOM (solid shape): 23.29,45.46 23.37,45.45 23.44,45.46 24.64,45.46 24.76,45.35 24.76,41.96 24.61,41.81 24.11,41.81 24.1,41.85 24.05,41.98 23.95,42.09 23.91,42.14 23.92,42.22 23.51,42.72 23.4,42.08 23.44,42.02 23.43,41.95 23.41,41.9 23.4,41.85 23.39,41.81 22.5,41.81 22.04,42.27 22.04,45.25 22.25,45.46
+3VALW on BOTTOM (solid shape): 69.94,10 69.94,7.61 69.5,7.17 62.26,7.17 62.21,7.12 61.3,7.12 60.9,6.73 60.88,6.73 60.61,6.68 60.46,6.45 60.45,6.41 59.42,6.41 59.41,6.46 59.06,6.79 58.7,6.46 58.7,6.41 55.97,6.41 55.59,6.79 55.59,8.25 56.31,8.97 56.34,8.95 56.53,8.91 56.7,9.01 62.37,9.01 62.38,8.97 62.4,8.93 62.42,8.88 62.42,8.55 63.08,8.55 63.08,8.88 63.1,8.93 63.12,8.97 63.13,9.01 64.16,9.01 64.39,8.92 64.63,9.01 66.87,9.01 66.88,8.97 66.9,8.93 66.92,8.88 66.92,8.55 67.58,8.55 67.58,8.88 67.6,8.93 68.05,9.37 68.05,9.44 68.09,9.52 68.18,9.54 68.58,9.66 68.59,10.07 68.56,10.11 68.74,10.28 69.67,10.28
+3VALW on BOTTOM (solid shape): outline of 262 points within 48.86,42.68 54.26,46.98
+3VALW on IN2 (solid shape): 196.29,41.79 196.29,40.96 193.68,38.34 192.64,38.34 192.46,38.52 192.46,39.17 192.85,39.55 192.85,40.42 194.36,41.94 196.14,41.94
+3VALW on IN2 (solid shape): outline of 1156 points within 18.44,43.26 34.22,82.56
+3VALW on IN2 (solid shape): outline of 1740 points within 31.12,11.81 41.56,56.43
+3VALW on VCC: 46.36,16.57 43.84,19.09 43.84,35.28 30.64,48.3 30.64,77.66 40.65,77.66 45.6,82.61 48.95,82.61 49.43,82.12 49.43,33.96 50.27,33.13 50.27,31.28 49.43,30.44 49.43,25.35 52.76,22.03 57.65,22.03 58.66,21.01 63.55,21.01 64,20.57 69.48,20.57 69.92,21.01 94.5,21.01 95.77,22.28 99.32,22.28 103.77,26.73 124.59,26.73 126.12,28.25 142.45,28.25 152.35,38.16 164.85,38.16 176.05,49.36 176.05,65.23 176.92,66.1 189.03,66.1 189.51,65.61 189.51,47.58 194.08,43.01 194.08,39.15 192.96,38.03 174.29,38.03 159.12,22.85 144.34,22.85 144.34,22.86 144.24,22.85 144.13,22.85 144.13,22.85 143.98,22.71 143.98,22.7 137.97,16.57
+3VALW_EC on TOP (solid shape): 23.07,49.61 23.07,47.71 23.15,47.63 23.63,47.63 23.76,47.5 23.76,46.93 23.54,46.71 22.44,46.71 22.27,46.89 22.27,47.97 22.23,48.01 22.23,49.37 22.24,49.46 22.23,49.54 22.23,49.67 22.32,49.76 22.93,49.76
+3VALW_EC on TOP (solid shape): 52.58,59.93 52.58,54.97 51.97,54.36 49.75,54.36 48.96,55.15 48.96,55.96 49.04,56.04 50.91,56.04 51.34,56.47 51.34,58.66 49.1,60.89 45.31,60.89 45.2,61 43.13,61 42.95,61.18 42.95,61.98 43.34,62.36 50.14,62.36
+3VALW_EC on TOP (solid shape): 40.71,31.94 40.73,31.94 40.73,31.55 40.61,31.43 39.91,31.43 39.6,31.12 38.89,31.12 38.83,31.19 38.83,31.82 38.85,31.85 39.4,31.85 39.49,31.85 39.92,32.28 39.97,32.32 40.34,32.32
+3VALW_EC on BOTTOM (solid shape): outline of 2011 points within 27.3,31.2 44,63.06
+3VALW_EC on IN1 (solid shape): outline of 285 points within 49.88,39.63 53.11,56.5
+3VALW_EC on IN1 (solid shape): outline of 532 points within 22.91,46.29 30.03,59.93
+3VALW_PCH on TOP (solid shape): 121.59,43.02 121.59,42.24 121.66,42.17 121.69,42.12 121.69,41.27 121.62,41.19 119.96,41.19 119.87,41.28 119.87,42.37 120.8,42.37 120.8,42.31 120.81,42.26 120.82,42.21 120.85,42.17 120.88,42.13 120.91,42.09 120.96,42.06 121,42.03 121.05,42.02 121.1,42.01 121.16,42.01 121.21,42.02 121.26,42.03 121.3,42.06 121.34,42.09 121.38,42.13 121.41,42.17 121.44,42.21 121.45,42.26 121.46,42.31 121.46,42.37 121.45,42.42 121.44,42.47 121.41,42.51 121.38,42.56 121.34,42.59 121.3,42.62 121.26,42.65 121.21,42.66 121.16,42.67 121.1,42.67 121.05,42.66 121,42.65 120.96,42.62 120.91,42.59 120.88,42.56 120.85,42.51 120.82,42.47 120.81,42.42 120.8,42.37 119.87,42.37 119.87,43.1 120.01,43.24 120.13,43.24 120.16,43.23 120.21,43.23 120.26,43.23 120.31,43.23 120.34,43.24 120.61,43.24 120.65,43.28 121.33,43.28
+3VALW_PCH on BOTTOM (solid shape): 141.84,36.29 141.84,34.73 141.7,34.6 140.42,34.6 140.33,34.69 140.33,36.3 140.42,36.39 141.74,36.39
+3VALW_PCH on BOTTOM (solid shape): 131.47,29.4 131.47,27.87 132.24,27.11 132.93,27.11 133.06,26.98 133.06,26.61 132.13,25.29 131.78,23.72 131.78,23.67 131.79,23.55 130.11,23.55 129.95,23.71 129.95,27.68 129.06,28.57 127.47,28.57 127.46,28.57 127.38,28.63 127.29,28.66 126.75,29.2 126.75,29.75 126.82,29.82 131.05,29.82
+3VALW_PCH on IN2 (solid shape): outline of 2554 points within 117.16,26.22 142.24,46.67
+3VALWP on BOTTOM (solid shape): 185.13,69.84 185.13,62.99 184.94,62.8 183.8,62.8 183.64,62.96 183.64,64.92 183.04,65.53 182.07,65.53 182.07,64.97 181.63,64.97 181.63,65.52 180.88,65.52 180.88,64.97 180.43,64.97 180.43,65.46 180.43,65.53 179.21,65.53 178.79,65.11 178.79,64.71 178.7,64.62 177.68,64.62 177.57,64.73 177.57,69.91 178.21,70.54 184.43,70.54
+3VLP on BOTTOM (solid shape): 185.6,79.03 185.6,78.13 184.96,77.49 182.61,77.49 182.53,77.57 182.53,77.59 182.53,78.31 182.6,78.39 183.16,78.39 183.32,78.23 184.56,78.23 184.94,78.61 184.94,78.99 185,79.05 185.58,79.05
+3VS on TOP (solid shape): 38.1,105.46 38.1,103.34 37.94,103.18 37.18,103.18 36.29,104.07 35.65,104.07 35.59,104.14 35.59,105.93 35.67,106.01 37.54,106.01
+3VS on TOP (solid shape): 172.77,112.91 172.77,110.02 173.23,109.56 174.98,109.56 175.29,109.86 176.18,109.86 176.34,109.7 176.34,107.98 176.24,107.88 171.94,107.88 171.07,108.75 171.07,109.02 171.1,109.05 171.1,109.76 171.07,109.79 171.07,112.89 171.35,113.16 172.52,113.16
+3VS on TOP (solid shape): 220.95,24.02 220.95,23.06 220.43,23.06 220.43,22.56 220.95,22.56 220.95,22.26 220.43,22.26 220.43,21.76 220.95,21.76 220.95,21.21 220.8,21.06 218.52,21.06 218.34,21.23 218.34,23.98 218.64,24.28 220.69,24.28
+3VS on TOP (solid shape): 36.3,72.32 36.3,71.66 36.56,71.41 38.04,71.41 38.15,71.3 38.15,71.12 38.03,71.01 36.37,71.01 36.32,70.96 34.18,70.96 34.03,71.11 34.03,72.15 34.23,72.35 35.35,72.35 35.45,72.45 35.46,72.45 35.55,72.55 36.07,72.55
+3VS on TOP (solid shape): outline of 83 points within 72.04,17.84 76.48,20.38
+3VS on TOP (solid shape): outline of 156 points within 197.4,36.89 208.27,45.02
+3VS on TOP (solid shape): outline of 173 points within 41.68,16.82 61.81,29.82
+3VS on BOTTOM (solid shape): 43.85,75.62 43.85,74.92 43.72,74.79 42.38,74.79 42.22,74.63 41.79,74.63 41.56,74.86 41.56,75.78 41.74,75.95 43.51,75.95
+3VS on BOTTOM (solid shape): 25,65.37 25,63.84 25,63.84 25.63,63.2 26.93,63.2 27.47,62.66 28.82,62.66 29.11,62.37 29.11,61.05 28.91,60.85 26.43,60.85 25.74,61.54 24.18,61.54 22.91,62.81 22.91,65.33 23.25,65.67 24.7,65.67
+3VS on BOTTOM (solid shape): 203.13,51.41 203.13,49.56 203.39,49.3 205.46,49.3 205.54,49.22 205.54,48.61 205.43,48.49 204.29,48.49 202.65,46.85 202.03,46.85 201.96,46.92 201.96,51.11 202.34,51.49 203.04,51.49
+3VS on BOTTOM (solid shape): 143.68,32.52 143.68,28.79 143.21,28.33 143.21,24.05 142.8,23.64 142.8,23.01 142.48,22.69 142.48,21.68 142.81,21.36 144.67,21.36 145.29,20.73 145.29,19.11 144.77,18.59 144.77,18.16 144.64,18.03 144.44,18.03 144.3,18.16 144.3,19.72 144.18,19.84 143.18,19.84 143.01,20 141.5,20 140.76,20.75 140.76,22.43 141.25,22.92 141.35,23.02 141.35,23.07 141.36,23.08 141.38,23.19 141.36,23.31 141.35,23.32 141.35,23.72 141.36,23.81 141.35,23.9 141.35,25.08 141.35,25.33 140.77,25.91 140.77,31.66 140.59,31.84 139.93,31.84 139.86,31.91 139.86,32.67 139.93,32.75 143.45,32.75
+3VS on IN2 (solid shape): outline of 461 points within 35.14,60.49 42.38,85.34
+3VS on IN3 (solid shape): 22.7,75.04 22.7,71.81 23.02,71.5 25.98,71.5 27.08,72.6 31.75,72.6 31.83,72.59 31.91,72.6 36.06,72.6 36.27,72.4 36.27,71.73 35.45,70.92 32.02,70.92 31.93,70.95 31.89,71.03 31.43,71.34 31.23,70.81 31.26,70.77 29.95,69.46 29.95,61.15 29.53,60.73 28.2,60.73 27.92,61.01 27.92,65.32 27.61,65.63 22.04,65.63 19.65,68.02 19.65,71.74 19.09,72.31 17.91,72.31 17.72,72.5 17.72,72.91 17.9,73.1 18.96,73.1 19.52,73.65 19.52,75.06 19.03,75.56 17.94,75.56 17.81,75.69 17.81,76.25 18,76.44 21.3,76.44
+3VS on IN3 (solid shape): outline of 575 points within 200.82,18.96 220.12,41.97
+3VS on VCC: outline of 116 points within 30.64,21.52 222.84,114.13
+3VS_SSD on TOP (solid shape): 225.81,4.91 225.81,3.18 225.71,3.08 222.96,3.08 222.74,3.31 222.74,4.94 222.94,5.14 225.58,5.14
+3VS_SSD on TOP (solid shape): outline of 93 points within 220.56,15.65 226.18,24.18
+3VS_SSD on BOTTOM (solid shape): 224.59,4.5 224.59,4.15 224.81,3.94 226.23,3.94 226.34,3.83 226.34,2.72 226.09,2.47 224.08,2.47 223.3,3.24 223.3,4.51 223.49,4.7 224.39,4.7
+3VS_SSD on BOTTOM (solid shape): 226.35,21.19 226.35,20.22 226.24,20.11 224.83,20.11 224.59,19.88 224.59,15.88 224.39,15.68 222.76,15.68 222.56,15.88 222.56,20.67 222.56,20.67 222.56,20.96 222.7,21.1 222.84,21.1 223.44,20.99 223.94,21.34 226.2,21.34
+3VS_SSD on IN3 (solid shape): 226.09,16.97 226.09,3.61 225.58,3.11 223.55,3.11 223.04,3.61 223.04,17.15 223.32,17.43 225.63,17.43
+5V_KB_BL on BOTTOM (solid shape): 125.81,15 125.81,12.43 125.57,12.18 121.9,12.18 121.77,12.32 121.77,14.69 122,14.91 122.61,14.91 122.71,14.82 122.71,13.83 123.08,13.46 123.48,13.46 123.83,13.81 123.83,15.04 124,15.21 125.6,15.21
+5V_PVDD on TOP (solid shape): 33.09,21.01 33.09,20.15 33.43,19.81 33.75,19.81 34,19.55 34,19.36 34.26,19.11 34.45,19.11 34.6,18.96 34.6,18.85 34.62,18.83 34.73,18.73 35.97,18.73 36.2,18.5 36.2,17.79 36.11,17.7 34.51,17.7 34.42,17.79 34.42,18.12 33.75,18.79 33.75,19.3 33.49,19.55 33.24,19.55 32.88,19.9 32.88,21.02 32.94,21.07 33.03,21.07
+5V_PVDD on BOTTOM (solid shape): 34.34,19.02 34.79,19.02 37.37,16.44 37.37,15.38 36.54,14.55 36.54,13.46 36.53,13.45 36.53,13.28 36.54,13.28 36.54,12.72 36.8,12.46 38.09,12.46 38.1,12.47 38.22,12.47 38.28,12.4 38.28,10.23 38.11,10.06 36.49,10.06 36.28,10.27 36.28,10.92 36.01,11.19 36.01,12.25 35.26,13.01 35.26,15.43 35.52,15.7 35.52,16.44 35.27,16.7 35.27,16.7 34.33,17.65 33.62,17.65 32.52,18.74 31.08,18.74 30.77,19.05 30.77,19.06 30.66,19.16 30.66,19.87 30.98,20.19 33.18,20.19
+5V_PVDD on IN1 (solid shape): 34.5,18.89 34.75,18.89 37.05,16.59 37.05,12.09 36.83,11.87 35.39,11.87 35.28,11.98 35.28,15.73 35.3,15.76 35.3,16.43 35.25,16.49 35.14,16.71 34.92,16.81 34.8,16.93 33.75,16.93 32.19,18.48 30.68,18.48 30.4,18.76 30.4,19.62 30.69,19.91 33.47,19.91
+5V_RUN_UZ2 on TOP (solid shape): 190.95,44.81 191.08,44.81 191.15,44.74 191.15,44.17 191.58,43.73 191.58,42.79 191.51,42.72 190.16,42.72 188.8,41.36 186.85,41.36 186.69,41.52 186.69,42.14 186.69,42.14 186.69,42.16 187.21,42.16 187.21,42.86 186.69,42.86 186.69,42.89 186.69,42.89 186.69,43.34 186.69,43.34 186.69,43.36 187.21,43.36 187.21,44.06 186.69,44.06 186.69,44.09 186.69,44.09 186.69,44.69 186.81,44.81 190.95,44.81
+5VA on BOTTOM (solid shape): 27.65,27.45 27.65,26.49 27.85,26.29 27.85,25.72 27.65,25.52 26.77,25.52 26.69,25.6 26.69,27.42 26.81,27.54 27.56,27.54
+5VALW on TOP (solid shape): 160.24,18.35 160.24,18.22 160.11,18.09 159.55,18.09 159.05,17.58 158.69,17.58 158.59,17.69 158.59,17.93 159.16,18.5 160.09,18.5
+5VALW on TOP (solid shape): 160.63,14.53 160.63,14.46 160.8,14.29 160.8,12.92 160.6,12.71 159.57,12.71 159.36,12.91 159.36,13.06 159.35,13.08 159.35,14.41 159.56,14.62 160.54,14.62
+5VALW on TOP (solid shape): 19.1,43.03 19.1,42.82 19.14,42.78 19.14,42.77 19.34,42.56 19.34,42.27 18.29,41.22 18.29,40.99 16.86,39.56 16.22,39.56 15.78,40 15.75,40.03 15.75,41.26 15.9,41.4 16.41,41.4 16.73,41.72 16.73,42.55 17.65,43.47 18.65,43.47
+5VALW on TOP (solid shape): 191.53,41.4 191.53,39.49 192.22,38.8 192.22,32.44 190.96,31.17 184.95,31.17 184.62,31.51 184.62,33.15 187.91,36.45 187.91,39.68 189.69,41.46 191.47,41.46
+5VALW on BOTTOM (solid shape): 198.53,20 198.53,17.2 198.28,16.95 197.01,16.95 196.88,17.08 196.88,20 197.02,20.14 198.39,20.14
+5VALW on BOTTOM (solid shape): 150.43,41.96 150.43,41.84 150.36,41.77 149.71,41.77 148.7,40.76 148.43,40.76 148.29,40.9 148.29,41.93 148.4,42.03 150.35,42.03
+5VALW on BOTTOM (solid shape): 192.24,64.76 192.95,64.76 192.95,65.27 193.44,65.27 193.44,64.76 194.15,64.76 194.15,65.27 194.85,65.27 195.1,65.02 195.1,62.67 194.85,62.42 191.35,62.42 191.04,62.73 191.04,65.08 191.23,65.27 192.24,65.27
+5VALW on BOTTOM (solid shape): 74.86,12.1 74.86,11.67 74.68,11.49 72.23,11.49 72.04,11.68 68.23,11.68 67.25,10.7 67.25,9.77 67.12,9.63 65.83,9.63 65.59,9.88 65.59,12.24 65.66,12.31 74.64,12.31
+5VALW on BOTTOM (solid shape): 19.09,42.99 19.09,42.8 19.2,42.69 19.2,42.11 19,41.91 18.97,41.92 18.75,41.88 18.65,41.68 18.65,41.56 18.51,41.42 18.51,40.83 18.63,40.7 18.63,40 18.57,39.94 16.35,39.94 16.35,39.95 15.89,39.95 15.78,40.06 15.78,41.27 15.91,41.4 16.41,41.4 16.71,41.7 16.71,42.54 17.64,43.47 18.61,43.47
+5VALW on BOTTOM (solid shape): 162.13,18.42 162.13,13.23 161.62,12.72 159.65,12.72 159.49,12.88 159.49,15.26 160.96,15.26 160.96,15.21 160.97,15.16 160.99,15.1 161.01,15.06 161.04,15.01 161.08,14.97 161.12,14.94 161.16,14.91 161.21,14.89 161.27,14.88 161.32,14.88 161.37,14.88 161.42,14.89 161.47,14.91 161.52,14.94 161.56,14.97 161.6,15.01 161.63,15.06 161.65,15.1 161.67,15.16 161.67,15.21 161.67,15.26 161.67,15.31 161.65,15.37 161.63,15.41 161.6,15.46 161.56,15.5 161.52,15.53 161.47,15.56 161.42,15.58 161.37,15.59 161.32,15.59 161.27,15.59 161.21,15.58 161.16,15.56 161.12,15.53 161.08,15.5 161.04,15.46 161.01,15.41 160.99,15.37 160.97,15.31 160.96,15.26 159.49,15.26 159.49,16.05 160.06,16.63 160.06,17.46 159.78,17.74 159.15,17.74 159.01,17.6 158.58,17.6 158.5,17.69 158.5,19.01 158.66,19.17 161.38,19.17
+5VALW on VCC: outline of 114 points within 16.47,4.87 204.24,66.1 ; 1 cut-out
+5VALWP on BOTTOM (solid shape): 197.01,69.85 197.01,62.99 196.82,62.8 195.67,62.8 195.51,62.96 195.51,64.92 195.03,65.41 194.04,65.41 194.04,65.4 194.02,65.4 194.02,64.89 193.57,64.89 193.57,65.4 193.55,65.4 193.55,65.41 192.84,65.41 192.84,65.4 192.82,65.4 192.82,64.89 192.37,64.89 192.37,65.4 192.35,65.4 192.35,65.41 191.05,65.41 190.65,65.01 190.65,64.86 190.37,64.58 189.58,64.58 189.45,64.7 189.45,69.91 190.09,70.54 196.31,70.54
+5VS on TOP (solid shape): 23.74,26.96 23.74,26.04 23.42,25.72 23.42,25.71 22,25.71 21.8,25.91 21.8,26.83 22,27.04 23.66,27.04
+5VS on TOP (solid shape): 53.88,106.8 53.88,105.79 53.18,105.09 53.18,101.91 52.86,101.59 51.78,101.59 50.6,100.41 49.97,100.41 49.92,100.46 49.92,106.34 50.45,106.87 53.81,106.87
+5VS on TOP (solid shape): 186.56,44.56 186.56,43.96 186.57,43.96 186.57,43.94 187.08,43.94 187.08,43.49 186.57,43.49 186.57,43.46 186.56,43.46 186.56,42.76 186.57,42.76 186.57,42.74 187.08,42.74 187.08,42.29 186.57,42.29 186.57,42.26 186.56,42.26 186.56,41.65 186.56,41.65 186.56,40.69 185.87,40 185.87,35.68 184.15,33.97 181.49,33.97 181.11,34.35 181.11,41.54 182.4,42.84 182.4,43.85 183.21,44.66 186.46,44.66
+5VS on BOTTOM (solid shape): 29.73,74.87 29.73,73.9 29.49,73.65 25.99,73.65 25.79,73.85 25.79,74.87 26.06,75.14 29.47,75.14
+5VS on BOTTOM (solid shape): 129.13,15.07 129.13,13.68 128.88,13.43 127.41,13.43 127.28,13.56 127.28,15.13 127.44,15.29 128.91,15.29
+5VS on BOTTOM (solid shape): 200.63,75.94 200.63,73.85 200.56,73.78 199.48,73.78 199.23,74.04 199.23,75.94 199.36,76.07 200.5,76.07
+5VS on BOTTOM (solid shape): 202.82,18.69 202.82,16.77 202.76,16.7 201.38,16.7 201.26,16.82 201.26,18.73 201.51,18.98 202.53,18.98
+5VS on BOTTOM (solid shape): 53.94,106.8 54.64,106.8 54.7,106.74 54.7,105.79 54.58,105.66 53.5,105.66 53.31,105.85 53.31,106.74 53.43,106.87 53.88,106.87
+5VS on BOTTOM (solid shape): 202.97,25.08 202.97,23.17 202.72,22.92 201.45,22.92 201.2,23.17 201.2,25.08 201.32,25.2 202.85,25.2
+5VS on BOTTOM (solid shape): outline of 283 points within 34.27,13.28 43.31,30.44
+5VS on IN1 (solid shape): 203.1,25.97 203.1,24.7 202.85,24.44 201.32,24.44 200.82,24.95 199.67,24.95 199.42,25.2 199.42,26.22 199.67,26.47 202.59,26.47
+5VS on IN1 (solid shape): 184.17,36.65 184.17,33.43 183.94,33.21 182.15,33.21 181.98,33.37 181.98,36.58 182.38,36.98 183.83,36.98
+5VS on IN2 (solid shape): 183.67,38 183.67,36.58 183.55,36.46 182.51,36.46 182.41,36.56 182.41,37.98 182.59,38.16 183.51,38.16
+5VS on IN2 (solid shape): 199.86,75.88 199.86,74.54 199.42,74.1 198.97,74.1 198.59,74.48 198.59,74.8 198.91,75.12 198.91,75.81 199.16,76.07 199.67,76.07
+5VS on IN2 (solid shape): outline of 1221 points within 25.3,25.82 36.31,74.91
+5VS on IN3 (solid shape): outline of 455 points within 20.55,25.79 30.75,38.46
+5VS on VCC: 30.13,94.78 30.13,48.09 43.34,35.07 43.34,18.88 46.15,16.06 137.97,16.06 137.98,16.06 138.08,16.06 138.18,16.06 138.19,16.06 138.33,16.21 138.33,16.21 144.34,22.35 159.33,22.35 174.51,37.52 183.57,37.52 184.05,37.04 184.05,31.79 168.2,15.93 159.77,15.93 159.65,16.06 146.23,16.06 143.18,13.01 41.92,13.01 39.21,15.72 39.21,32.23 24.92,46.52 24.92,55.41 24.01,56.32 19.47,56.32 19.47,77.17 22.43,77.17 24.45,79.19 24.45,94.15 21.37,97.23 21.37,97.95 22.43,99.01 22.61,99.44 22.67,99.9 22.67,100.6 23.62,102.88 25.9,103.83 28.68,103.83 28.68,103.83 30.3,103.83 31.55,104.35 32.07,105.6 32.07,106.73 32.8,106.73 34.05,107.25 34.57,108.5 34.57,114.13 35.12,114.13 35.12,114.13 46.02,114.13 46.02,114.13 52.59,114.13 52.59,113.9 53.11,112.65 54.36,112.13 54.51,112.13 54.51,106.21 53.9,105.6 36.5,105.6 35.72,104.81 35.72,100.37
+5VS_HDMI on BOTTOM (solid shape): 25.38,74.04 25.38,68.26 24.89,67.77 22.25,67.77 22.13,67.9 22.13,71.69 23.16,72.72 23.16,74.09 23.52,74.46 24.96,74.46
+5VS_HDMI on IN1 (solid shape): outline of 104 points within 11.98,71.51 25.23,75.04
+17.4V_BATT+ on TOP (solid shape): 165.17,32.03 165.17,30.6 163.63,30.6 163.63,29.97 165.17,29.97 165.17,29.34 164.85,29.03 163.38,29.03 162.72,28.37 162.72,26.9 162.49,26.66 154.02,26.66 153.83,26.85 153.83,27.92 153.99,28.08 155.5,28.08 155.71,28.29 155.71,29.85 155.87,30.02 157.02,30.02 157.02,30.02 157.81,30.02 157.81,29.48 158.32,29.48 158.32,30.02 158.61,30.02 158.61,29.48 159.12,29.48 159.12,30.02 159.56,30.02 159.74,30.2 159.74,31.37 159.98,31.61 161.81,31.61 162.5,32.3 164.9,32.3
+17.4V_BATT++ on TOP (solid shape): 159.53,31.94 159.53,30.24 159.43,30.14 158.99,30.14 158.99,29.71 158.89,29.61 158.74,29.61 158.74,30.14 158.19,30.14 158.19,29.61 157.94,29.61 157.94,30.14 155.71,30.14 155.45,30.4 155.45,31.72 155.58,31.85 156.54,31.85 156.58,31.85 156.95,32.23 159.23,32.23
+17.4V_BATT++ on BOTTOM (solid shape): 159.36,30.74 160.83,30.74 161.05,30.52 161.05,28.53 160.73,28.21 156.76,28.21 155.46,29.51 155.46,31.69 155.62,31.85 156.6,31.85 156.98,32.23 157.87,32.23
+19V_ADPIN on BOTTOM (solid shape): 197.47,88.12 197.98,88.12 197.98,88.64 198.27,88.64 198.27,88.12 198.78,88.12 198.78,88.64 199.61,88.64 199.8,88.45 199.8,85.28 202.34,82.74 203.23,82.74 203.61,82.35 203.61,80.2 203.23,79.81 199.93,79.81 199.29,80.45 199.29,80.96 196.31,83.94 196.31,88.49 196.46,88.64 197.47,88.64
+19V_VIN on TOP (solid shape): outline of 210 points within 186.66,86.8 195.99,92.12
+19V_VIN on BOTTOM (solid shape): 195.29,94.48 196.31,94.48 196.43,94.36 196.43,91.5 197.2,90.74 199.55,90.74 199.86,90.42 199.86,89.02 199.67,88.83 199.66,88.83 199.61,88.78 198.67,88.78 198.67,88.77 198.65,88.77 198.65,88.25 198.4,88.25 198.4,88.77 198.38,88.77 198.38,88.78 197.87,88.78 197.87,88.77 197.85,88.77 197.85,88.25 197.61,88.25 197.6,88.26 197.6,88.77 197.58,88.77 197.58,88.78 196.34,88.78 196.24,88.87 194.49,88.87 194.15,89.21 194.15,90.36 194.02,90.48 193.32,90.48 193.26,90.55 193.26,91.18 194.02,91.94 194.02,94.36 194.59,94.93 194.85,94.93
+19VB on TOP (solid shape): 157.16,37.62 157.16,36.02 157,35.86 153.69,35.86 153.19,36.36 151.54,36.36 151.41,36.49 151.41,37.67 151.61,37.87 156.9,37.87
+19VB on TOP (solid shape): 79.74,110.34 81.27,110.34 81.4,110.22 81.4,110.21 81.5,110.1 81.5,108.94 81.39,108.83 79.82,108.83 79.24,108.25 76.22,108.25 75.94,108.53 75.94,110.25 76.23,110.54 79.54,110.54
+19VB on TOP (solid shape): 62.44,111.42 62.44,107.46 62.29,107.31 61.81,107.31 61.5,106.99 61.5,104.96 60.61,104.07 56.66,104.07 56.61,104.13 56.61,105.51 56.66,105.56 57.72,105.56 58.58,106.42 58.58,111.44 58.96,111.82 62.05,111.82
+19VB on TOP (solid shape): outline of 455 points within 98.1,102.61 181.07,114.13
+19VB on BOTTOM (solid shape): 212.88,35.3 212.88,33.4 210.79,31.3 204.44,31.3 203.93,31.81 203.93,36.06 204.56,36.7 211.48,36.7
+19VB on BOTTOM (solid shape): 185.26,110.04 185.26,106.36 181,102.1 181,91.65 181.09,91.56 182.15,91.56 182.21,91.5 182.21,90 182.85,90 182.85,91.52 183.48,91.52 183.57,91.43 183.57,89.82 183.92,89.47 191.61,89.47 191.86,89.21 191.86,86.8 191.1,86.04 185.96,86.04 185.95,86.04 185.59,86.04 185.36,86.27 177.89,86.27 177.57,85.95 177.57,85.59 177.26,85.28 175.35,85.28 175.23,85.4 175.23,86.1 175.74,86.1 175.74,86.81 175.23,86.81 175.23,87.3 175.74,87.3 175.74,88 175.23,88 175.23,104.2 181.96,110.93 184.37,110.93
+19VB on BOTTOM (solid shape): 211.86,98.1 211.86,87.18 210.98,86.29 207.42,86.29 204.37,89.34 204.37,92.4 206.97,92.4 206.97,92.06 206.97,92.03 206.98,91.97 206.99,91.9 207.01,91.84 207.05,91.79 207.08,91.74 207.13,91.69 207.18,91.65 207.23,91.62 207.29,91.59 207.35,91.57 207.41,91.56 207.48,91.55 207.54,91.56 207.6,91.57 207.66,91.59 207.72,91.62 207.77,91.65 207.82,91.69 207.87,91.74 207.9,91.79 207.94,91.84 207.96,91.9 207.97,91.97 207.98,92.03 207.98,92.06 207.98,92.4 208.76,92.4 208.76,94.2 206.19,94.2 206.19,92.4 204.37,92.4 204.37,95.69 207.93,99.25 210.72,99.25
+19VB on BOTTOM (solid shape): 163.92,48.76 164.63,48.76 164.63,49.21 165.12,49.21 165.12,48.76 165.83,48.76 165.83,49.21 167.14,49.21 167.43,48.92 167.43,48.69 167.41,48.68 167.41,44.01 167.56,43.87 167.56,40.54 167.5,40.53 167.29,40.44 167.14,40.26 167.11,39.93 167.29,39.66 167.35,39.57 167.31,39.47 167.08,39.24 166.3,39.24 166.02,38.96 166.02,37.41 166.02,37.41 166.02,34.89 165.58,34.45 152.03,34.45 151.56,34.92 151.56,38.64 151.79,38.87 156.11,38.87 156.43,39.19 161.9,39.19 163.9,41.18 163.9,46.25 163.29,46.86 163.29,49.12 163.38,49.21 163.92,49.21
+19VB on BOTTOM (solid shape): outline of 366 points within 59.34,103.63 102.11,114.1
+19VB on IN1 (solid shape): 206.85,37.21 206.85,33.46 206.09,32.7 200.37,32.7 199.67,33.4 199.67,36.82 200.69,37.84 206.21,37.84
+19VB on IN1 (solid shape): outline of 617 points within 163.33,36.21 184.01,43.09
+19VB_1.2V on TOP (solid shape): 79.74,106.39 79.74,104.25 79.62,104.13 75.59,104.13 75.53,104.2 75.53,105.02 76.17,105.66 76.17,107.44 76.27,107.54 78.59,107.54
+19VB_1.2V on BOTTOM (solid shape): 78.51,107.08 78.51,105.09 78.07,104.64 75.51,104.64 75.49,104.67 75.49,105.2 75.51,105.22 76.07,105.22 76.23,105.39 76.23,105.79 76.36,105.91 76.36,107.04 76.59,107.27 78.33,107.27
+19VB_+1VALW on TOP (solid shape): 153.28,35.45 153.28,35.04 151.76,33.53 151.39,33.53 150.02,32.15 150.02,31.64 150.65,31.01 150.65,30.92 149.61,29.88 149.5,29.88 148.94,30.44 148.94,30.79 148.38,31.35 148.38,31.36 148.12,31.62 148.12,32.33 148.38,32.58 148.38,33.42 150.59,35.63 153.1,35.63
+19VB_+1VALW on BOTTOM (solid shape): 150.12,31.76 150.12,30.6 150.07,30.55 148.4,30.55 148.14,30.82 148.14,31.9 148.25,32.01 149.86,32.01
+VCC_CORE on TOP (solid shape): 122.41,58.77 122.84,58.77 122.89,58.71 122.89,58.33 122.88,58.32 120.76,58.32 120.66,58.22 119.69,58.22 119.64,58.26 119.64,58.6 119.72,58.68 119.99,58.68 120.08,58.63 120.19,58.62 120.36,58.65 120.49,58.77 120.49,58.88 120.5,58.95 120.5,59.02 120.77,59.3 121.88,59.3
+VCC_CORE on TOP (solid shape): outline of 2501 points within 118.42,50.47 153.97,70.62
+VCC_CORE on BOTTOM (solid shape): outline of 478 points within 141.25,53.65 153.79,70.62
+VCC_CORE on IN2 (solid shape): outline of 2546 points within 120,50.5 154,70.64
+VCC_CORE on IN3 (solid shape): outline of 213 points within 118.43,51.93 122.21,59.32
+VCC_CORE on BOTTOM: 118.62,55.88 118.62,55.95 118.47,56.1 118.47,56.41 118.51,56.43 118.56,56.46 118.6,56.5 118.86,56.5 119.15,56.43 119.31,56.67 119.34,56.76 119.44,56.8 120.16,56.8 120.24,56.79 120.32,56.8 121.28,56.8 121.44,56.64 121.44,55.02 121.4,54.94 121.3,54.93 120.82,54.63 121.3,54.34 121.4,54.33 121.44,54.24 121.44,51.76 121.16,51.47 120.7,51.47 120.42,51.75 120.42,51.78 118.98,51.78 118.47,52.29 118.47,52.76 118.51,52.77 118.64,52.92 118.63,53.13 118.62,53.14 118.62,53.16 118.47,53.31 118.47,53.56 118.62,53.71 118.62,53.78 118.63,53.8 118.64,54 118.51,54.15 118.47,54.17 118.47,54.52 118.52,54.61 118.54,54.62 118.66,54.84 118.52,55.06 118.51,55.07 118.47,55.11 118.47,55.5 118.51,55.52 118.64,55.67 118.63,55.87
+VCC_CORE on BOTTOM: 131.03,50.84 130.43,51.44 130.32,51.44 130.19,51.32 129.12,51.32 128.96,51.48 128.96,52.62 128.99,52.77 128.96,52.91 128.96,55.01 128.96,55.02 128.99,55.15 128.96,55.29 128.96,55.3 128.96,57.52 128.97,57.59 128.96,57.67 128.96,57.87 128.96,57.88 128.96,58.32 129.28,58.65 129.84,58.65 129.84,58.65 131.02,58.65 132,57.66 132,51.04 131.8,50.84
+VCC_CORE on VCC: 119.39,51.24 118.27,52.36 118.27,56.14 119.29,57.16 119.29,59.05 119.4,59.16 122.83,59.16 123.65,58.35 134.37,58.35 138.08,62.06 138.08,69.04 139.45,70.42 152.2,70.42 152.68,69.93 152.68,59.02 151.41,57.75 151.41,55.76 146.16,50.51 122.66,50.51 121.93,51.24
+VCC_FAN1 on BOTTOM (solid shape): 202.34,74.48 202.34,72.86 202.87,72.32 204.24,72.32 204.5,72.07 204.5,71.56 204.24,71.31 201.58,71.31 201.31,71.58 201.31,74.66 201.38,74.73 202.09,74.73
+VCC_GT on TOP (solid shape): outline of 4268 points within 118.38,58.77 155.48,97.21
+VCC_GT on BOTTOM (solid shape): outline of 744 points within 119.03,74.83 155.69,101.15
+VCC_GT on IN2 (solid shape): 136.42,71.84 136.42,70.95 134.19,68.72 133.22,68.72 133.13,68.77 133.13,68.87 133.17,68.99 133.16,69.12 133.17,69.21 133.26,69.25 133.27,69.25 134.02,70 134.02,71.38 134.84,71.38 135.41,71.95 136.32,71.95
+VCC_GT on IN2 (solid shape): outline of 4213 points within 119.5,58.86 136.53,83.31
+VCC_GT on BOTTOM: outline of 256 points within 118.44,57.4 131.46,75.67
+VCC_GT on VCC: 118.12,66.1 110.75,66.1 110.39,66.46 110.39,71.2 111.64,72.45 115.2,72.45 118.37,75.62 120.45,75.62 121.08,74.99 122.18,74.99 122.96,75.77 122.96,99.65 123.45,100.13 153.47,100.13 155.6,98 155.6,80.05 152.68,77.13 152.68,71.41 152.2,70.92 139.24,70.92 137.57,69.25 137.57,62.27 134.16,58.86 123.86,58.86 123.05,59.67 119.32,59.67 119.28,59.71 119.28,60.74 118.65,61.38 118.65,65.57 ; 1 cut-out
+VCC_SA on TOP (solid shape): outline of 764 points within 120.24,45.27 144.75,50.26
+VCC_SA on BOTTOM (solid shape): 120.83,48.47 120.83,47.52 120.67,47.37 119.91,47.37 119.81,47.46 119.81,48.47 119.94,48.6 120.7,48.6
+VCC_SA on BOTTOM (solid shape): 145.57,49.33 145.57,48.32 144.62,48.32 144.62,47.56 145.57,47.56 145.57,47.43 145.57,46.54 145.44,46.41 140.74,46.41 140.36,46.79 140.36,49.27 140.49,49.4 145.51,49.4
+VCC_SA on BOTTOM (solid shape): outline of 176 points within 129.02,46.89 131.78,51.34
+VCC_SA on VCC: 131.33,42.1 126.5,46.92 120.15,46.92 119.54,47.53 119.54,50.25 120.02,50.73 121.72,50.73 122.47,49.99 144.05,49.99 144.05,42.45 143.69,42.1
GND on TOP (solid shape): 82.57,33.73 82.57,30.59 82.35,30.38 79.54,30.38 79.25,30.67 79.25,33.83 79.63,34.21 82.09,34.21
GND on TOP (solid shape): 162.58,25.83 162.58,24.73 162.28,24.44 154.14,24.44 153.8,24.79 153.8,25.78 154.05,26.03 162.37,26.03
GND on TOP (solid shape): 170.22,26.49 170.22,26.26 169.07,25.1 168.55,25.1 168.32,25.33 168.32,26.2 168.77,26.65 170.06,26.65
GND on TOP (solid shape): 222.15,20.15 222.15,17 221.97,16.82 219.22,16.82 218.99,17.06 218.99,20.2 219.17,20.38 221.92,20.38
GND on TOP (solid shape): 81.44,86.93 81.44,85.03 80.56,84.15 77,84.15 76.77,84.37 76.77,85.91 76.82,85.96 76.82,87.31 77.21,87.7 80.67,87.7
GND on TOP (solid shape): 144.62,71.05 144.62,70.23 145.21,69.63 145.21,69.46 145.13,69.38 144.51,69.38 143.98,69.91 143.98,71.05 144.05,71.11 144.55,71.11
GND on TOP (solid shape): 145.25,35.3 145.25,33.21 145,32.95 144.09,32.95 143.88,33.15 143.88,34.23 143.35,34.77 143.35,36.16 143.48,36.29 144.26,36.29
GND on TOP (solid shape): 164.54,24.28 164.54,23.89 164.39,23.74 163.56,23.74 163.3,24.01 163.3,24.77 163.44,24.91 163.91,24.91
GND on TOP (solid shape): 76.7,12.23 76.7,10.56 78.33,8.93 79.46,8.93 79.54,8.85 79.54,8.24 79.48,8.19 74.9,8.19 74.2,8.88 74.2,12.12 74.5,12.43 76.5,12.43
GND on TOP (solid shape): 180.67,38.37 180.67,29.5 180.51,29.33 174.74,29.33 174.68,29.4 174.68,36.15 174.84,36.31 175.49,36.31 176.32,37.15 176.32,38.54 176.48,38.7 180.35,38.7
GND on TOP (solid shape): 155.67,47.75 155.67,46.92 154.71,45.97 154.71,44.89 154.59,44.76 152.49,44.76 151.92,45.33 151.92,47.56 152.17,47.81 155.6,47.81
GND on TOP (solid shape): 69.18,102.5 69.18,101.47 69.5,101.15 69.5,101.09 69.88,100.71 69.88,100.45 69.75,100.32 69.5,100.32 69.37,100.45 69.37,100.64 68.96,101.05 68.96,102.5 69.02,102.56 69.13,102.56
GND on TOP (solid shape): 79.27,103.22 79.27,100.78 79.07,100.58 76.42,100.58 76.21,100.78 76.21,102.31 76.05,102.47 75.54,102.47 75.37,102.65 75.37,103.31 75.67,103.61 78.88,103.61
GND on TOP (solid shape): 184.62,85.34 184.62,84.2 184.12,83.69 184.12,82.93 183.35,82.16 183.35,80.96 183.29,80.89 182.53,80.89 182.46,80.96 182.46,81.73 182.21,81.99 181.43,81.99 181.29,82.13 181.29,83.59 183.29,85.59 184.37,85.59
GND on TOP (solid shape): 195.67,85.02 195.67,83.37 194.34,82.04 194.34,81.53 194.47,81.4 194.47,80.7 194.34,80.58 193.7,80.58 193.64,80.64 193.64,81.53 193.13,82.04 191.86,82.04 191.8,82.1 191.8,84.45 192.69,85.34 195.35,85.34
GND on TOP (solid shape): 103.6,45.46 103.91,45.46 104.75,44.62 104.75,44.05 104.7,44 104.17,44 104.12,44.05 104.12,44.56 103.79,44.89 102.77,44.89 102.58,44.7 102.58,42.29 102.84,42.03 104.2,42.03 104.27,41.96 104.43,41.96 104.48,41.91 104.48,41.39 104.42,41.33 101.38,41.33 101.34,41.37 101.34,45.23 101.96,45.85 103.21,45.85
GND on TOP (solid shape): 159.86,58.29 159.86,54.35 159.86,54.31 160.56,53.61 160.56,52.13 160.05,52.13 159.86,51.94 159.86,50.22 160.05,50.03 160.56,50.03 160.62,49.97 160.62,48.62 160.54,48.55 157.41,48.55 156.11,49.84 156.11,49.87 155.02,50.96 152.23,50.96 151.59,51.6 151.59,53.12 152.12,53.65 156.49,53.65 156.75,53.91 156.75,58.22 157.48,58.96 159.19,58.96
GND on TOP (solid shape): 36.33,17.18 36.33,14.66 36.32,14.66 36.32,14.49 35.82,14 35.82,13.99 35.69,13.86 35.69,13.83 35.68,13.82 35.68,12.17 35.66,12.17 35.66,12.01 34.4,10.74 33.37,10.74 32.92,11.18 32.92,12.12 33.1,12.3 34.47,12.3 35.12,12.95 35.12,14.56 35.13,14.56 35.13,14.59 35.33,14.79 35.33,16 35.14,16.19 34.76,16.19 34.64,16.31 34.64,16.63 34.56,16.71 34.56,17.38 34.64,17.46 36.05,17.46
GND on TOP (solid shape): 124.06,43.6 124.06,42.65 124.13,42.58 124.55,42.58 124.7,42.43 124.7,42.14 124.83,42.01 124.83,40.21 125.02,40.01 125.52,40.01 125.71,39.82 125.71,39.28 125.95,39.05 126.9,39.05 127,38.95 127,38.28 126.51,37.79 126.51,37.62 126.48,37.58 125.98,37.58 125.94,37.62 125.94,38.03 125.65,38.33 125.14,38.33 125.02,38.45 125.02,39.15 124.1,40.06 123.81,40.06 123.75,40.13 123.75,40.61 123.75,40.61 123.75,40.78 124,41.03 124,41.57 123.35,42.22 123.35,43.68 123.51,43.85 123.82,43.85
GND on TOP (solid shape): 166.4,95.32 166.4,94.29 165.83,93.72 165.83,90.36 166.14,90.04 166.14,85.15 165.83,84.83 165.83,81.15 166.08,80.89 166.59,80.89 166.78,80.7 166.78,77.3 166.65,77.17 163.36,77.17 163.13,77.4 163.13,79.53 162.97,79.69 162.33,79.69 162.29,79.74 162.29,80.65 162.33,80.7 162.72,80.7 163.08,81.07 163.08,85.03 162.53,85.58 159.95,85.58 159.26,86.27 159.26,89.72 159.45,89.9 160.55,89.9 160.66,89.8 160.66,89.29 160.94,89 162.76,89 163.1,89.34 163.1,93.61 162.82,93.89 159.64,93.89 159.31,94.22 159.31,95.71 159.44,95.84 165.88,95.84
GND on TOP (solid shape): 153.86,33.14 153.86,31.97 153.6,31.71 153.6,31.52 153.34,31.26 153.24,31.26 153.07,31.09 152.56,31.09 151.9,30.43 151.9,29.51 151.26,28.87 150.34,28.87 149.17,27.7 149.17,26.27 150.3,25.14 150.3,23.79 150.05,23.55 149.04,23.55 148.82,23.77 148.82,24.52 146.81,26.53 146.81,27.76 146.91,27.86 147.64,27.86 147.94,28.16 147.94,28.55 148.17,28.78 149.25,28.78 149.78,29.31 149.82,29.35 149.82,29.79 150.65,30.62 151.71,30.62 152.48,31.38 152.48,31.63 152.65,31.8 152.65,32.05 152.75,32.16 152.94,32.36 152.93,32.64 152.93,32.67 152.62,32.98 152.47,32.98 152.13,33.32 152.13,33.37 152.55,33.78 153.22,33.78
GND on TOP (solid shape): 15.97,21.08 15.97,18.98 14.89,17.9 4.66,17.9 4.4,18.16 4.4,19.85 4.76,20.2 7.01,20.2 7.14,20.16 7.23,20.06 7.47,19.57 7.75,19.26 8.15,19.15 11.11,19.15 11.13,19.14 11.15,19.12 11.99,18.66 12.6,19.4 12.6,21.27 12.92,21.58 15.46,21.58
GND on TOP (solid shape): 122.58,67.33 122.58,66.66 122.77,66.48 123.29,66.48 123.33,66.44 123.33,66.37 123.52,66.19 123.92,66.19 124.01,66.1 124.01,65.78 124.2,65.59 124.54,65.59 124.72,65.78 124.72,66.16 124.77,66.2 125.18,66.2 125.22,66.16 125.22,65.78 125.41,65.59 125.74,65.59 125.93,65.78 125.93,66.16 125.97,66.2 126.38,66.2 126.43,66.16 126.43,65.78 126.61,65.59 126.95,65.59 127.14,65.78 127.14,66.16 127.18,66.2 127.59,66.2 127.63,66.16 127.63,65.78 127.82,65.59 128.16,65.59 128.34,65.78 128.34,66.16 128.39,66.2 128.8,66.2 128.84,66.16 128.84,65.84 128.96,65.71 129.09,65.59 129.33,65.59 129.33,64.93 122.79,64.93 122.69,64.83 122.25,64.83 122.22,64.86 122.22,65.88 122.1,66.01 121.71,66.01 121.65,66.07 121.65,66.43 121.68,66.46 121.94,66.71 121.94,67.34 122,67.41 122.51,67.41
GND on TOP (solid shape): 122.78,63.66 122.78,63.33 122.93,63.18 123.39,63.18 123.52,63.31 123.52,63.66 123.64,63.79 123.91,63.79 124.01,63.68 124.01,63.37 124.2,63.18 124.54,63.18 124.72,63.37 124.72,63.75 124.77,63.79 125.18,63.79 125.22,63.75 125.22,63.37 125.41,63.18 125.74,63.18 125.93,63.37 125.93,63.75 125.97,63.79 126.38,63.79 126.43,63.75 126.43,63.37 126.61,63.18 126.95,63.18 127.14,63.37 127.14,63.75 127.18,63.79 127.59,63.79 127.63,63.75 127.63,63.37 127.82,63.18 128.16,63.18 128.34,63.37 128.34,63.75 128.39,63.79 128.8,63.79 128.84,63.75 128.84,63.43 128.96,63.3 129.09,63.18 129.33,63.18 129.33,62.52 121.21,62.52 121.14,62.58 121.14,63.19 120.96,63.37 120.57,63.37 120.55,63.4 120.55,63.7 120.61,63.76 121.46,63.76 121.56,63.66 121.56,63.31 121.69,63.18 122.2,63.18 122.32,63.31 122.32,63.66 122.45,63.79 122.65,63.79
GND on TOP (solid shape): 23.15,10.43 24.25,7.72 24.1,7.48 24.05,7.2 24.05,6.56 23.57,5.62 22.85,4.85 20.5,4.85 20.13,4.76 19.86,4.5 19.77,4.31 19.75,4.1 19.74,4.06 19.74,4.03 16.5,4.03 16.5,11.53 20.44,11.53
GND on TOP (solid shape): 4.52,78.92 15.17,78.92 16.92,77.17 20.15,77.17 20.38,77.4 20.42,77.4 20.42,77.41 22.34,77.41 22.52,77.23 22.52,76.45 21.54,75.47 18.56,75.47 18.45,75.54 18.46,75.67 18.19,76.26 17.92,75.67 17.93,75.54 17.82,75.47 10.35,75.47 10.1,75.71 10.1,76.29 10.59,77.13 9.85,77.76 0.5,77.76 0.33,77.83 0.26,78 0.26,79.44 0.29,79.48 3.96,79.48
GND on TOP (solid shape): 13.68,40.76 13.68,36.57 15.9,34.35 15.9,33.27 15.59,32.95 12.88,32.95 12.6,33.23 12.6,35.1 12.28,35.72 11.58,35.81 11.32,35.64 11.15,35.38 11.13,35.36 11.11,35.35 8.84,35.35 8.36,35.35 8.15,35.35 7.93,35.32 7.73,35.22 7.58,35.1 7.47,34.94 7.23,34.44 7.14,34.34 7.01,34.3 4.76,34.3 4.4,34.66 4.4,36.85 4.18,37.38 3.65,37.6 1.85,37.6 1.68,37.68 1.6,37.85 1.6,40.28 1.68,40.45 1.85,40.52 6.72,40.52 6.86,40.47 7.12,40.11 7.39,40.02 8.36,40.02 9.3,40.02 9.98,40.02 10.3,40.16 10.44,40.48 10.44,40.78 10.86,41.21 13.24,41.21
GND on TOP (solid shape): outline of 179 points within 1.6,54.41 13.68,63.37
GND on TOP (solid shape): 53.36,115.15 53.53,115.07 53.61,114.9 53.61,113.9 53.83,113.37 54.36,113.15 55.96,113.15 56.49,113.37 56.71,113.9 56.71,114.9 56.79,115.07 56.96,115.15 78.23,115.15 78.23,114.64 57.22,114.64 57.22,113.9 56.85,113.01 55.96,112.64 54.36,112.64 53.47,113.01 53.1,113.9 53.1,114.64 34.06,114.64 34.06,108.5 33.69,107.61 32.8,107.24 31.56,107.24 31.56,105.6 31.3,104.83 30.62,104.38 30.05,104.38 29.85,104.18 29.85,99.22 27.92,97.29 21.72,97.29 21.39,97.62 21.39,99.33 21.58,99.58 21.65,99.9 21.65,100.6 22.28,102.81 23.96,104.38 23.97,104.38 24.9,104.73 25.9,104.85 30.3,104.85 30.83,105.07 31.05,105.6 31.05,107.5 31.13,107.67 31.3,107.75 32.8,107.75 33.33,107.97 33.55,108.5 33.55,114.9 33.63,115.07 33.8,115.15
GND on TOP (solid shape): outline of 152 points within 119.68,57.15 129.33,61.44
GND on TOP (solid shape): 119.81,56.45 119.81,56.03 119.73,55.95 119.51,55.95 119.22,55.67 118.51,55.67 118.32,55.47 118.3,55.45 118.3,52.45 118.11,52.25 117.1,52.25 117.01,52.35 117.03,52.39 117.06,52.61 116.95,52.81 116.95,53.17 117,53.23 117.07,53.26 117.14,53.23 117.65,53.27 117.52,53.76 117.48,53.78 117.48,54.06 117.52,54.08 117.73,54.43 117.43,54.72 117.4,54.72 117.37,54.75 117.34,54.88 117.44,54.97 117.49,55.6 117.12,55.08 117.14,54.94 117.02,54.87 116.37,54.87 116.28,54.94 116.31,55.05 116.33,55.54 115.85,55.52 115.77,55.49 115.69,55.52 115.53,55.62 115.33,55.61 115.24,55.62 115.19,55.71 115.19,56.29 115.33,56.42 115.62,56.42 115.78,56.27 115.78,56.25 115.98,55.9 116.37,56.01 116.45,56.05 116.54,56.01 116.77,55.88 117.02,55.96 117.09,55.98 117.16,55.96 117.56,55.93 117.68,56.32 117.7,56.42 117.78,56.46 118.23,56.46 118.33,56.41 118.35,56.29 118.63,55.85 118.99,56.23 118.99,56.41 119.1,56.52 119.73,56.52
GND on TOP (solid shape): outline of 163 points within 118.48,46.4 131.75,52.13
GND on TOP (solid shape): outline of 92 points within 55.2,20.69 81.09,23.1
GND on TOP (solid shape): outline of 109 points within 119.71,52.53 128.89,55.51
GND on TOP (solid shape): outline of 402 points within 114.43,61.45 117.25,66.53
GND on TOP (solid shape): outline of 911 points within 17.81,0.25 227.22,115.15
GND on BOTTOM (solid shape): 51.11,88.78 51.11,85.43 50.78,85.1 46.31,85.1 45.65,85.76 45.65,88.96 46.14,89.45 50.44,89.45
GND on BOTTOM (solid shape): 52.94,10.37 52.94,6.42 52.67,6.15 51.46,6.15 51.17,6.45 51.17,10.36 51.2,10.38 52.93,10.38
GND on BOTTOM (solid shape): 64.41,12.24 64.41,10.84 63.63,10.07 61.8,10.07 61.57,10.29 61.57,11.08 62.83,12.34 64.31,12.34
GND on BOTTOM (solid shape): 70.88,110.32 70.88,108.99 70.81,108.92 67.76,108.92 67.64,109.05 67.64,110.32 67.76,110.45 70.75,110.45
GND on BOTTOM (solid shape): 118.45,98.81 118.45,93.8 118.25,93.6 112.61,93.6 112.3,93.91 112.3,98.61 112.87,99.18 118.08,99.18
GND on BOTTOM (solid shape): 145.71,11.26 145.71,8.77 145.46,8.52 143.45,8.52 143.02,8.95 143.02,11.39 143.3,11.67 145.3,11.67
GND on BOTTOM (solid shape): 150.38,37.87 150.38,36.55 149.86,36.03 147.12,36.03 146.64,36.51 146.64,37.68 147.55,38.59 149.66,38.59
GND on BOTTOM (solid shape): 175.34,30.18 175.34,26.27 175.13,26.06 168.66,26.06 168.43,26.29 168.43,30.22 168.62,30.41 175.11,30.41
GND on BOTTOM (solid shape): 186.97,68 186.97,63.05 186.72,62.8 185.58,62.8 185.32,63.05 185.32,67.88 185.55,68.1 186.88,68.1
GND on BOTTOM (solid shape): 189.32,67.75 189.32,64.7 189.2,64.58 187.93,64.58 187.67,64.83 187.67,67.88 187.8,68 189.07,68
GND on BOTTOM (solid shape): 204.6,17.57 204.6,16.29 204.44,16.12 203.33,16.12 203.15,16.3 203.15,17.6 203.2,17.65 204.52,17.65
GND on BOTTOM (solid shape): 19.67,54.53 19.67,53.47 19.6,53.4 17.77,53.4 17.6,53.56 17.6,54.46 17.8,54.66 19.55,54.66
GND on BOTTOM (solid shape): 174.84,78.29 174.84,75.18 174.65,74.99 172.75,74.99 172.11,75.62 172.11,77.85 173.07,78.8 174.34,78.8
GND on BOTTOM (solid shape): 177.45,67.75 177.45,64.7 177.36,64.62 175.91,64.62 175.8,64.73 175.8,64.83 175.8,67.88 175.92,68 177.19,68
GND on BOTTOM (solid shape): 198.85,68 198.85,63.05 198.59,62.8 197.45,62.8 197.2,63.05 197.2,68.03 197.32,68.16 198.7,68.16
GND on BOTTOM (solid shape): 218.8,3.57 218.8,2.47 218.67,2.34 216.66,2.34 216.46,2.54 216.46,3.51 216.63,3.67 216.94,3.67 216.94,3.68 218.69,3.68
GND on BOTTOM (solid shape): 151.6,42.91 151.6,41.65 151.72,41.53 153.19,41.53 153.32,41.41 153.32,41.14 153.19,41.02 151.03,41.02 150.68,41.37 150.68,42.93 150.69,42.94 151.57,42.94
GND on BOTTOM (solid shape): 151.71,80.79 151.71,77.68 151.37,77.34 142.79,77.34 141.95,78.18 141.95,80.77 142.41,81.23 151.28,81.23
GND on BOTTOM (solid shape): 144.02,23.6 144.02,21.7 143.81,21.48 142.87,21.48 142.61,21.74 142.61,22.64 142.93,22.96 142.93,23.59 143.12,23.78 143.84,23.78
GND on BOTTOM (solid shape): 77.6,11 77.6,9.23 78.45,8.38 79.78,8.38 79.98,8.19 79.98,7.87 79.78,7.68 75.85,7.68 75.4,8.12 75.4,11 75.46,11.06 77.54,11.06
GND on BOTTOM (solid shape): 90.9,99.82 90.9,98.86 90.52,98.48 88.8,98.48 88.23,97.91 84.93,97.91 84.74,98.1 84.74,98.8 84.86,98.93 87.09,98.93 87.47,99.31 87.47,99.82 87.47,99.82 87.54,99.89 90.83,99.89
GND on BOTTOM (solid shape): 23.5,54.52 23.5,54.03 23.85,53.68 23.85,51.82 23.78,51.75 22.71,51.75 22.57,51.88 22.57,53.11 22.34,53.34 21.76,53.34 21.48,53.62 21.48,54.86 21.7,55.07 22.96,55.07
GND on BOTTOM (solid shape): 55.59,42.98 55.59,42.98 55.66,42.92 55.66,42.61 55.65,21.65 55.59,21.58 54.45,21.58 53.62,22.41 53.62,22.79 53.75,22.92 54.26,22.92 54.51,23.17 54.51,42.79 54.77,43.05 55.53,43.05
GND on BOTTOM (solid shape): 155.79,47.56 155.79,46.27 155.48,45.67 155.26,45.01 155.02,44.78 152.22,44.78 151.82,45.18 151.82,47.48 151.96,47.62 155.73,47.62
GND on BOTTOM (solid shape): 46.88,99.08 46.89,99.07 46.93,98.96 47.01,98.88 47.01,98.63 46.93,98.54 46.93,97.39 46.85,97.3 45.7,97.3 45.61,97.4 45.61,98.37 45.32,98.66 45.32,99.15 45.51,99.35 46.61,99.35
GND on BOTTOM (solid shape): 78.58,102.93 78.58,102.42 78.94,102.06 78.94,100.56 78.51,100.13 77.28,100.13 76.71,99.56 76.71,98.79 76.56,98.64 76.04,98.64 75.87,98.8 75.87,100.16 76.23,100.52 76.23,102.99 76.36,103.12 78.39,103.12
GND on BOTTOM (solid shape): 104.23,110.47 104.23,109.21 104.36,109.09 104.68,109.09 105.69,108.07 105.69,107.44 106.07,107.06 106.9,107.06 106.98,106.98 106.98,106.81 106.91,106.74 104.99,106.74 104.42,107.31 104.42,107.49 103.11,108.8 103.11,108.81 103.06,108.86 103.06,109.72 102.81,109.97 101.12,109.97 100.97,110.11 100.97,111.06 101.05,111.15 103.56,111.15
GND on BOTTOM (solid shape): 150.18,29.65 150.18,28.35 149.16,27.33 149.16,26.11 149.39,25.87 149.87,25.87 149.95,25.79 149.95,24.38 150.22,24.11 150.22,23.05 150.05,22.89 149.84,22.89 149.84,22.88 148.19,22.88 148.15,22.92 148.15,25.21 147.95,25.41 147.95,29.35 148.42,29.81 150.02,29.81
GND on BOTTOM (solid shape): 153.77,76.03 153.77,73.05 153.51,72.79 144.35,72.79 143.93,73.22 143.93,75.3 144.25,75.62 144.27,75.62 144.5,75.73 144.61,75.96 144.61,75.98 144.68,76.06 144.68,76.21 144.73,76.26 153.55,76.26
GND on BOTTOM (solid shape): 142.08,17.41 142.08,14.57 141.76,14.26 140.85,14.26 140.52,14.58 140.54,14.62 140.46,15.02 140.07,15.09 140.03,15.07 139.73,15.37 139.73,18.09 139.86,18.22 141.27,18.22
GND on BOTTOM (solid shape): 200.12,94.48 200.12,94.28 200.11,94.28 200.11,93.7 200.12,93.7 200.12,93.68 200.63,93.68 200.63,93.43 200.12,93.43 200.12,93.41 200.11,93.41 200.11,92.9 200.12,92.9 200.12,92.88 200.63,92.88 200.63,92.63 200.12,92.63 200.12,92.61 200.11,92.61 200.11,92.03 200.12,92.03 200.12,91.63 199.86,91.37 197.51,91.37 197.07,91.82 197.07,94.48 197.39,94.8 199.8,94.8
GND on BOTTOM (solid shape): 33.82,25.87 33.82,20.95 33.4,20.53 29.64,20.53 28.84,21.33 28.77,21.33 28.69,21.41 28.69,22.05 29.42,22.78 29.42,23.56 29.18,23.81 27.84,23.81 27.78,23.87 27.78,25.11 27.95,25.28 29.09,25.28 29.14,25.33 29.14,25.33 29.35,25.53 29.35,25.87 29.57,26.09 33.6,26.09
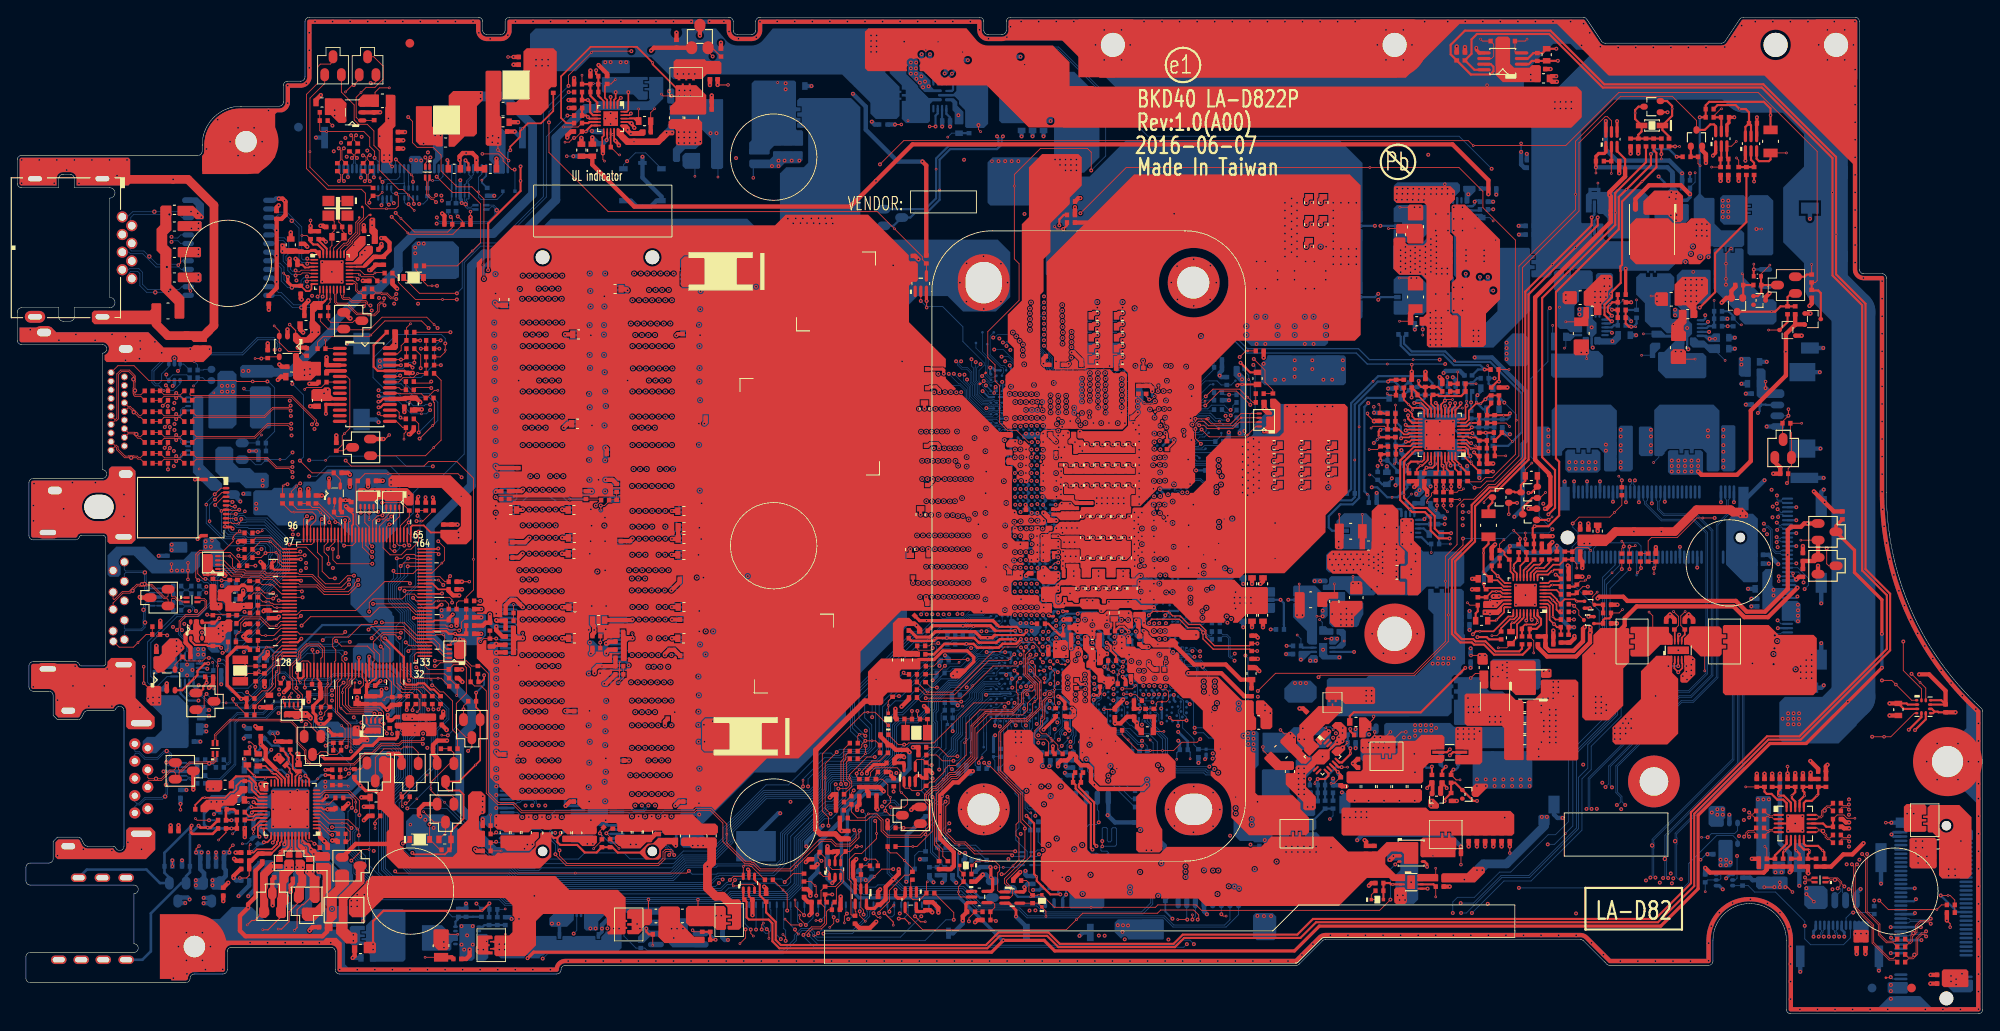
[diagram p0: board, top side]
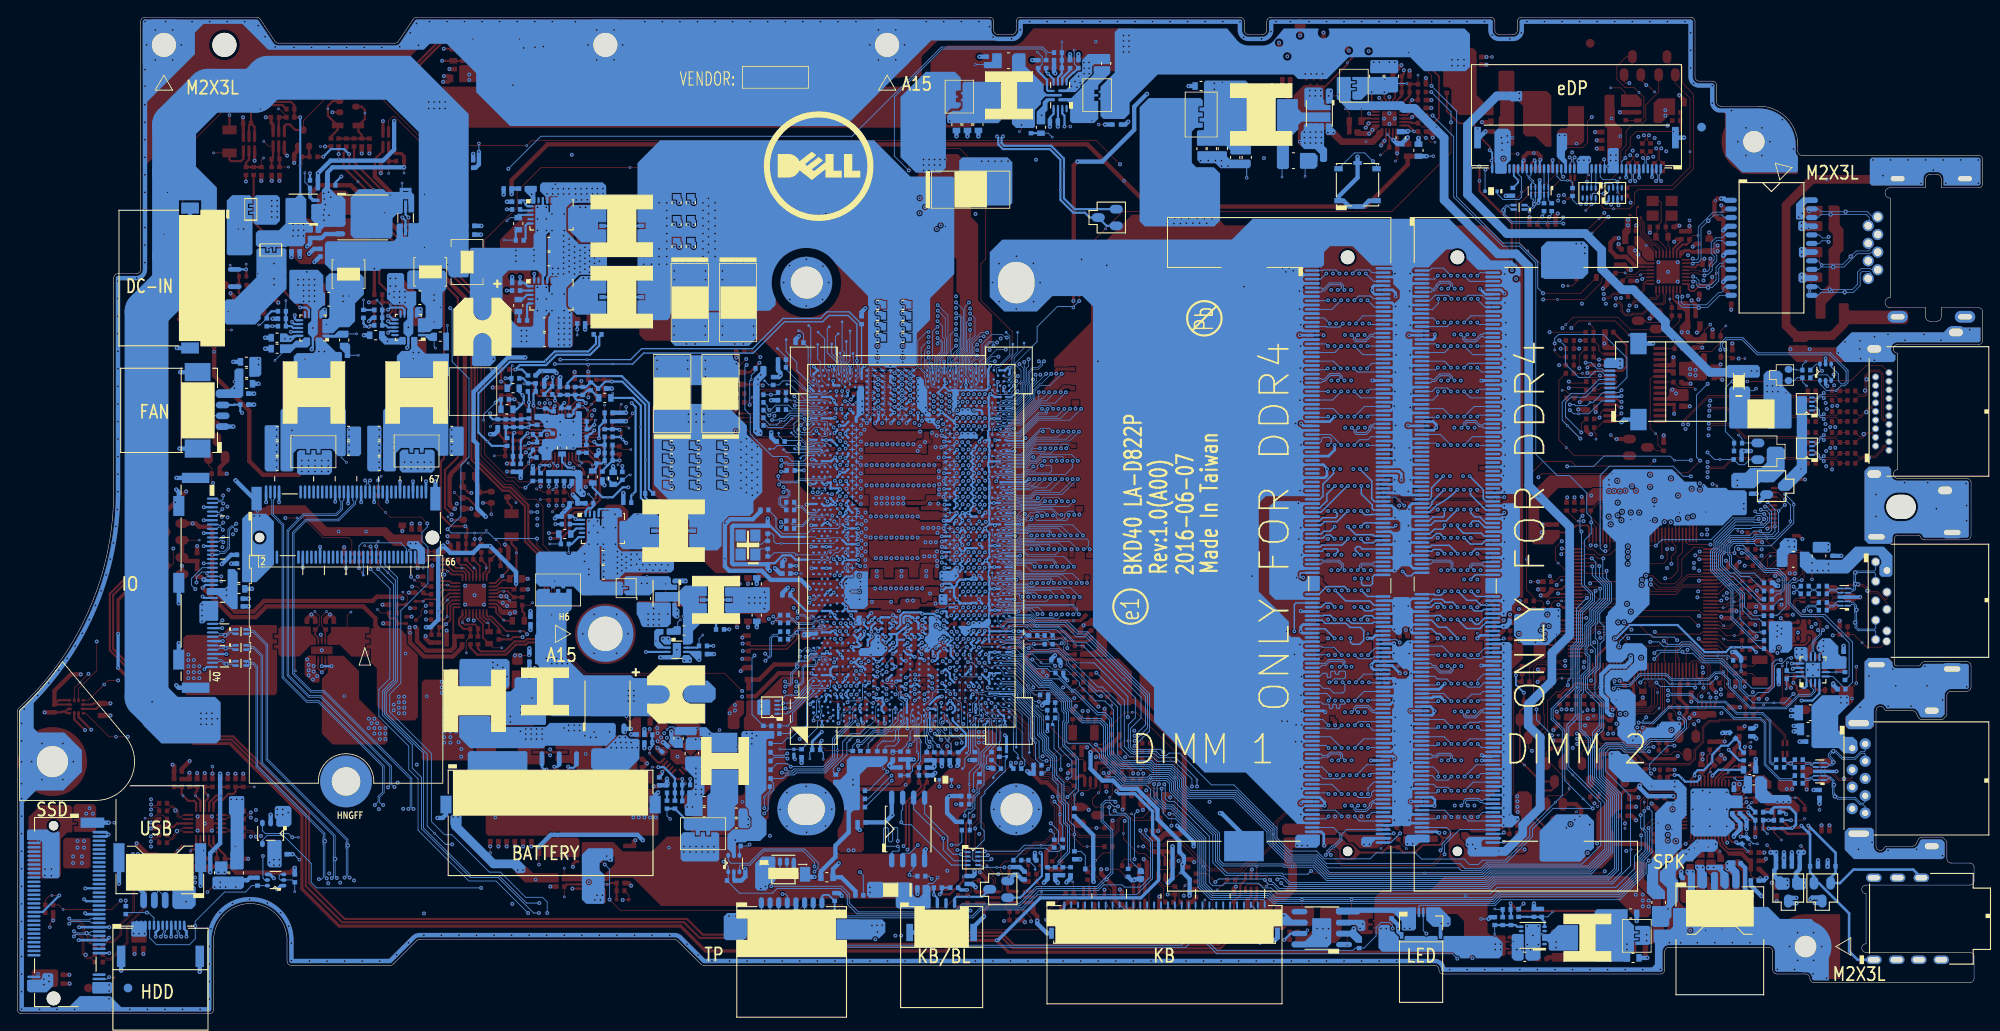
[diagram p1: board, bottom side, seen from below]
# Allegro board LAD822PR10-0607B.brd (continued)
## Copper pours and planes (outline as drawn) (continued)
GND on BOTTOM (solid shape): 195.99,86.04 195.99,82.86 195.35,82.23 193.96,82.23 193.45,81.72 193.45,80.26 193.83,79.88 193.83,78.73 193.39,78.29 193.39,77.34 193.64,77.08 193.64,76.83 193.51,76.7 193.26,76.7 193.13,76.83 193.13,78.29 192.69,78.73 192.69,81.4 192.07,82.02 191.88,82.02 191.85,82.04 191.85,83.45 192.05,83.65 192.05,85.53 192.69,86.16 195.86,86.16
GND on BOTTOM (solid shape): 132.69,10.85 132.69,8.67 132.62,8.59 128.53,8.59 128.53,8.64 128.24,8.97 127.85,8.77 127.78,8.72 127.69,8.75 127,9.43 127,10.55 127.38,10.93 132.62,10.93
GND on BOTTOM (solid shape): 184.69,85.57 184.69,82.8 183.99,82.1 182.78,82.1 182.34,81.66 182.34,80.45 182.78,80 182.78,78.8 182.34,78.35 182.34,77.46 182.59,77.21 182.59,77.02 182.46,76.89 182.27,76.89 182.08,77.08 182.08,78.35 181.64,78.8 181.64,81.78 181.31,82.12 181.31,83.61 181.34,83.64 182.29,83.64 182.69,84.04 182.69,85.57 182.91,85.78 184.48,85.78
GND on BOTTOM (solid shape): 162.84,69.73 162.84,69.15 163.1,68.89 164.04,68.89 164.12,68.97 164.12,69.38 164.23,69.49 164.81,69.49 164.96,69.34 165.79,69.34 165.93,69.48 167.57,69.48 167.61,69.44 167.61,68.83 167.54,68.77 167.03,68.77 166.59,68.32 166.59,68 166.39,67.8 165.24,67.8 165.03,67.59 165.03,66.82 165.28,66.57 166.57,66.57 166.75,66.38 166.75,65.86 166.92,65.69 167.08,65.69 167.16,65.6 167.16,65.04 167.01,64.89 166.97,64.89 166.79,64.71 166.79,64.17 166.73,64.11 165.78,64.11 165.64,64.26 165.64,64.51 165.64,64.51 165.64,65.02 165.32,65.34 162.95,65.34 162.72,65.56 162.21,65.56 162.11,65.67 162.11,69.66 162.23,69.78 162.79,69.78
GND on BOTTOM (solid shape): 4.52,78.92 15.17,78.92 16.92,77.17 16.92,76.44 15.95,75.47 10.35,75.47 10.1,75.71 10.1,76.29 10.59,77.13 9.85,77.76 0.5,77.76 0.33,77.83 0.26,78 0.26,79.44 0.29,79.48 3.96,79.48
GND on BOTTOM (solid shape): 130.21,72.61 130.21,72.22 130.34,72.09 130.34,69.36 130.58,69.13 130.58,68.54 130.44,68.41 130.28,68.41 130.2,68.49 130.2,68.96 129.86,69.3 129.68,69.3 129.45,69.53 129.45,69.84 129.45,69.85 129.47,69.96 129.45,70.07 129.45,70.08 129.45,70.49 129.45,70.5 129.47,70.61 129.45,70.73 129.45,70.73 129.45,71.14 129.45,71.15 129.47,71.26 129.45,71.38 129.45,71.38 129.45,71.79 129.45,71.8 129.47,71.91 129.45,72.03 129.45,72.03 129.45,72.44 129.47,72.5 129.47,72.55 129.6,72.67 129.61,72.67 129.68,72.75 130.07,72.75
GND on BOTTOM (solid shape): 15.97,21.08 15.97,18.98 14.89,17.9 4.66,17.9 4.4,18.16 4.4,19.85 4.76,20.2 7.01,20.2 7.14,20.16 7.23,20.06 7.47,19.57 7.75,19.26 8.15,19.15 11.11,19.15 11.13,19.14 11.15,19.12 11.99,18.66 12.6,19.4 12.6,21.27 12.86,21.53 15.51,21.53
GND on BOTTOM (solid shape): 116.91,67.4 117.1,67.33 117.29,67.4 117.56,67.4 117.75,67.33 117.94,67.4 118.21,67.4 118.24,67.38 118.3,67.35 118.33,67.31 118.33,67.01 118.56,66.79 118.56,66.61 118.5,66.58 118.45,66.55 118.22,66.55 118.01,66.62 117.8,66.55 117.58,66.55 117.37,66.62 117.17,66.55 116.95,66.55 116.74,66.62 116.53,66.55 116.39,66.55 116.3,66.64 116.3,67.05 116.46,67.21 116.46,67.23 116.58,67.36 116.64,67.4
GND on BOTTOM (solid shape): 123.35,73.64 123.35,70.19 123.13,69.97 123.12,69.97 123.01,69.89 122.93,69.77 122.92,69.76 122.76,69.59 122.73,69.59 122.57,69.51 122.49,69.35 122.49,69.32 122.3,69.13 121.78,69.13 121.68,69.23 121.68,69.45 121.71,69.5 121.87,69.66 121.89,69.66 122.1,69.79 122.15,70.04 122.15,70.05 122.15,70.53 122.16,70.61 122.15,70.7 122.15,71.18 122.16,71.26 122.15,71.35 122.15,71.83 122.16,71.91 122.15,72 122.15,72.32 122.18,72.34 122.28,72.43 122.32,72.56 122.32,72.59 122.54,72.81 122.54,73.38 122.93,73.77 123.22,73.77
GND on BOTTOM (solid shape): 115.57,45.48 115.6,45.47 115.81,45.39 116.03,45.48 116.23,45.48 116.45,45.39 116.68,45.48 116.88,45.48 116.94,45.43 117.02,45.4 117.06,45.37 117.07,45.32 117.16,45.01 117.48,44.93 118.47,44.93 118.57,44.83 118.57,44.7 118.3,44.44 118.3,44.16 117.88,43.74 117.8,43.71 117.63,43.71 117.16,44.18 117.16,44.54 117.02,44.68 115.56,44.68 115.48,44.69 115.4,44.68 115.18,44.68 114.94,44.93 114.94,44.95 114.89,45.07 114.8,45.16 114.8,45.61 114.92,45.74 115.32,45.74
GND on BOTTOM (solid shape): outline of 84 points within 44.99,17.64 51.29,23.1
GND on BOTTOM (solid shape): 160.32,58.43 160.32,57.57 160.25,57.49 160.24,57.49 160.15,57.49 160.06,57.57 160.06,58.21 159.95,58.33 159.86,58.33 159.69,58.38 159.53,58.32 159.44,58.29 159.36,58.32 159.09,58.36 158.94,58.13 158.94,57.62 159.09,57.39 159.36,57.43 159.44,57.46 159.53,57.43 159.62,57.38 159.72,57.37 159.82,57.33 159.86,57.24 159.86,50.48 159.66,50.28 157.96,50.28 157.14,51.1 151.81,51.1 151.46,51.44 151.46,53.12 151.9,53.55 157.53,53.55 157.95,53.97 157.99,54.01 157.99,57.43 157.91,57.51 157.52,57.51 157.49,57.54 157.49,58.27 157.8,58.58 160.17,58.58
GND on BOTTOM (solid shape): 118.98,72.4 119.14,72.4 119.27,72.27 119.27,71.77 119.26,71.76 119.23,71.61 119.26,71.46 119.27,71.45 119.27,71.42 119.35,71.33 119.35,71.22 119.21,70.94 119.33,70.66 119.35,70.65 119.35,70.58 119.34,70.56 119.23,70.3 119.35,70.04 119.35,69.9 119.28,69.8 119.24,69.68 119.24,69.66 119.19,69.62 119.12,69.62 118.98,69.76 118.99,69.79 118.97,70.04 118.77,70.2 118.71,70.24 118.67,70.53 118.5,70.67 118.49,70.67 118.46,70.7 118.46,70.99 118.5,71 118.63,71.09 118.7,71.23 118.71,71.25 118.75,71.29 118.71,71.34 118.7,71.36 118.64,71.49 118.52,71.58 118.49,71.59 118.49,72.15 118.75,72.41
GND on BOTTOM (solid shape): 13.68,40.76 13.68,36.57 15.87,34.39 15.87,33.35 15.48,32.96 12.99,32.96 12.6,33.35 12.6,35.1 11.99,35.84 11.15,35.38 11.13,35.36 11.11,35.35 8.15,35.35 7.75,35.24 7.47,34.94 7.23,34.44 7.14,34.34 7.01,34.3 4.76,34.3 4.4,34.66 4.4,36.85 4.18,37.38 3.65,37.6 1.85,37.6 1.68,37.68 1.6,37.85 1.6,40.28 1.68,40.45 1.85,40.52 6.72,40.52 6.86,40.47 7.12,40.11 7.39,40.02 9.98,40.02 10.3,40.16 10.44,40.48 10.44,40.68 10.97,41.21 13.24,41.21
GND on BOTTOM (solid shape): 117.51,70.19 117.75,70.07 117.99,70.19 118.16,70.19 118.22,70.13 118.29,70.09 118.35,70.05 118.35,69.97 118.44,69.65 118.77,69.57 118.8,69.58 118.9,69.48 118.85,69.38 118.82,69.35 118.8,69.35 118.61,69.35 118.45,69.24 118.28,69.24 118.02,69.36 117.75,69.25 117.74,69.24 117.65,69.24 117.63,69.25 117.37,69.36 117.12,69.25 117.1,69.24 117.01,69.24 117,69.25 116.74,69.36 116.48,69.25 116.47,69.24 116.38,69.24 116.33,69.28 116.24,69.36 116.24,69.59 116.27,69.61 116.33,69.65 116.39,69.71 116.49,69.71 116.5,69.69 116.88,69.62 117.07,69.96 117.09,70.04 117.15,70.08 117.26,70.12 117.34,70.19
GND on BOTTOM (solid shape): 67.34,42.54 67.72,42.54 67.91,42.73 67.91,42.98 68.04,43.11 68.23,43.11 68.35,42.98 68.35,41.21 67.08,39.94 66.64,39.94 66.39,39.68 66.39,39.17 66.77,38.79 67.78,38.79 67.97,38.98 68.35,38.98 68.35,38.41 68.16,38.22 68.16,36.76 68.29,36.63 68.29,36 68.16,35.87 68.16,35.49 68.35,35.3 68.35,31.11 68.23,30.98 68.23,30.21 67.78,29.75 67.78,29.67 67.77,29.66 67.85,29.34 68.16,29.22 68.24,29.19 68.27,29.12 68.27,28.14 68.35,28.06 68.35,21.71 67.4,21.71 67.24,21.76 67.08,21.71 66.32,21.71 66.13,21.9 66.13,22.79 66.01,22.92 66.01,24.12 66.04,24.2 66.12,24.22 66.54,24.58 66.12,24.93 66.04,24.95 66.01,25.03 66.01,25.9 65.94,25.97 65.94,34.66 65.99,34.74 66.08,34.75 66.59,35.08 66.08,35.4 65.99,35.41 65.94,35.49 65.94,43.24 66.64,43.24
GND on BOTTOM (solid shape): outline of 179 points within 1.6,54.41 13.68,63.37
GND on BOTTOM (solid shape): outline of 81 points within 159.22,77.15 166.97,96.29
GND on BOTTOM (solid shape): outline of 82 points within 119.63,41.84 122.51,46.08
GND on BOTTOM (solid shape): outline of 1146 points within 17.81,0.25 227.22,115.15
GND on BOTTOM (solid shape): outline of 2927 points within 53.5,21.97 114.93,92.07
GND on IN1 (solid shape): 159.88,56.46 159.88,50.52 159.71,50.35 158.25,50.35 157.64,50.96 152.05,50.96 151.46,51.54 151.46,53.32 152.02,53.88 152.62,53.88 152.94,53.68 153.26,53.88 155.55,53.88 157.69,56.01 157.69,56.32 157.91,56.55 159.79,56.55
GND on IN1 (solid shape): 15.97,21.08 15.97,18.98 14.89,17.9 4.66,17.9 4.4,18.16 4.4,19.85 4.76,20.2 7.01,20.2 7.14,20.16 7.23,20.06 7.47,19.57 7.75,19.26 8.15,19.15 11.11,19.15 11.13,19.14 11.15,19.12 11.99,18.66 12.6,19.4 12.6,21.27 12.92,21.58 15.46,21.58
GND on IN1 (solid shape): outline of 95 points within 159.19,77.13 166.4,96.27
GND on IN1 (solid shape): 4.52,78.92 15.18,78.92 16.93,77.17 20.15,77.17 20.37,77.4 22.37,77.4 22.53,77.24 22.53,76.45 21.55,75.47 18.56,75.47 18.45,75.54 18.46,75.67 18.19,76.26 17.92,75.67 17.93,75.54 17.82,75.47 10.35,75.47 10.1,75.71 10.1,76.29 10.59,77.13 9.85,77.76 0.5,77.76 0.33,77.83 0.26,78 0.26,79.44 0.29,79.48 3.96,79.48
GND on IN1 (solid shape): 13.68,40.76 13.68,36.57 15.9,34.35 15.9,33.27 15.59,32.96 12.96,32.96 12.6,33.31 12.6,35.1 11.99,35.84 11.15,35.38 11.13,35.36 11.11,35.35 8.15,35.35 7.75,35.24 7.47,34.94 7.23,34.44 7.14,34.34 7.01,34.3 4.76,34.3 4.4,34.66 4.4,36.85 4.18,37.38 3.65,37.6 1.85,37.6 1.68,37.68 1.6,37.85 1.6,40.28 1.68,40.45 1.85,40.52 6.72,40.52 6.86,40.47 7.12,40.11 7.39,40.02 9.98,40.02 10.3,40.16 10.44,40.48 10.44,40.78 10.86,41.21 13.24,41.21
GND on IN1 (solid shape): outline of 179 points within 1.6,54.41 13.68,63.37
GND on IN1 (solid shape): outline of 2581 points within 17.81,0.25 227.22,115.15
GND on VCC (solid shape): 36.3,8.46 37.19,8.09 37.56,7.2 37.56,5.75 37.56,5.36 62.2,5.36 62.64,6.08 63.43,6.36 66.03,6.36 66.03,5.85 63.43,5.85 62.9,5.63 62.61,4.93 62.43,4.85 37.3,4.85 37.13,4.93 37.05,5.1 37.05,5.75 37.05,7.2 36.83,7.73 36.3,7.95 24.8,7.95 24.27,7.73 24.05,7.2 24.05,5.63 24.05,5.1 23.97,4.93 23.8,4.85 20.5,4.85 19.97,4.63 19.67,3.93 19.5,3.85 16.47,3.85 16.47,4.36 19.27,4.36 19.56,4.94 20.1,5.3 20.65,5.27 21.19,5.36 23.54,5.36 23.54,7.2 23.91,8.09 24.8,8.46
GND on VCC (solid shape): outline of 236 points within 21.39,0.25 227.22,115.15
GND on IN2 (solid shape): 159.88,58.14 159.88,50.49 159.74,50.35 158.25,50.35 157.64,50.96 152.05,50.96 151.46,51.54 151.46,53.32 152.02,53.88 152.62,53.88 152.94,53.68 153.26,53.88 155.55,53.88 157.13,55.46 157.13,58.53 157.43,58.83 159.19,58.83
GND on IN2 (solid shape): 4.52,78.92 15.18,78.92 16.97,77.13 16.97,76.39 16.87,76.28 14.93,76.28 14.11,75.47 10.35,75.47 10.1,75.71 10.1,76.29 10.59,77.13 9.85,77.76 0.5,77.76 0.33,77.83 0.26,78 0.26,79.44 0.29,79.48 3.96,79.48
GND on IN2 (solid shape): 15.97,21.08 15.97,18.98 14.89,17.9 4.66,17.9 4.4,18.16 4.4,19.85 4.76,20.2 7.01,20.2 7.14,20.16 7.23,20.06 7.47,19.57 7.75,19.26 8.15,19.15 11.11,19.15 11.13,19.14 11.15,19.12 11.99,18.66 12.6,19.4 12.6,21.27 12.92,21.58 15.46,21.58
GND on IN2 (solid shape): outline of 97 points within 159.19,77.12 166.4,96.27
GND on IN2 (solid shape): 13.68,40.76 13.68,36.57 15.9,34.35 15.9,33.27 15.6,32.96 12.96,32.96 12.6,33.32 12.6,35.1 11.99,35.84 11.15,35.38 11.13,35.36 11.11,35.35 8.15,35.35 7.75,35.24 7.47,34.94 7.23,34.44 7.17,34.36 7.08,34.31 7.04,34.31 7.01,34.3 4.76,34.3 4.4,34.66 4.4,36.85 4.18,37.38 3.65,37.6 1.85,37.6 1.68,37.68 1.6,37.85 1.6,40.28 1.68,40.45 1.85,40.52 6.72,40.52 6.86,40.47 7.12,40.11 7.39,40.02 8.19,40.02 8.57,40.02 9.98,40.02 10.25,40.11 10.41,40.33 10.43,40.4 10.44,40.48 10.44,40.78 10.86,41.21 13.24,41.21
GND on IN2 (solid shape): outline of 179 points within 1.6,54.41 13.68,63.37
GND on IN2 (solid shape): outline of 3458 points within 17.81,0.25 227.22,115.15
GND on IN2 (solid shape): outline of 22577 points within 54.7,21.01 124.49,92.2
GND on IN3 (solid shape): 159.88,58.14 159.88,50.48 159.75,50.35 158.25,50.35 157.64,50.96 152.05,50.96 151.46,51.54 151.46,53.32 152.02,53.88 152.62,53.88 152.94,53.68 153.26,53.88 155.55,53.88 157.13,55.46 157.13,58.53 157.43,58.83 159.19,58.83
GND on IN3 (solid shape): 4.52,78.92 15.18,78.92 16.97,77.13 16.97,76.39 16.87,76.28 14.93,76.28 14.11,75.47 10.35,75.47 10.1,75.71 10.1,76.29 10.59,77.13 9.85,77.76 0.5,77.76 0.33,77.83 0.26,78 0.26,79.44 0.29,79.48 3.96,79.48
GND on IN3 (solid shape): 15.97,21.08 15.97,18.98 14.89,17.9 4.66,17.9 4.4,18.16 4.4,19.85 4.76,20.2 7.01,20.2 7.14,20.16 7.23,20.06 7.47,19.57 7.75,19.26 8.15,19.15 11.11,19.15 11.13,19.14 11.15,19.12 11.99,18.66 12.6,19.4 12.6,21.27 12.92,21.58 15.46,21.58
GND on IN3 (solid shape): outline of 93 points within 159.19,77.12 166.39,95.89
GND on IN3 (solid shape): 13.68,40.76 13.68,36.57 15.9,34.35 15.9,33.27 15.6,32.97 13.04,32.97 12.6,33.4 12.6,35.1 11.99,35.84 11.15,35.38 11.13,35.36 11.11,35.35 8.15,35.35 7.75,35.24 7.47,34.94 7.23,34.44 7.14,34.34 7.01,34.3 4.76,34.3 4.4,34.66 4.4,36.85 4.18,37.38 3.65,37.6 1.85,37.6 1.68,37.68 1.6,37.85 1.6,40.28 1.68,40.45 1.85,40.52 6.72,40.52 6.86,40.47 7.12,40.11 7.39,40.02 9.98,40.02 10.3,40.16 10.44,40.48 10.44,40.82 10.82,41.21 13.24,41.21
GND on IN3 (solid shape): outline of 179 points within 1.6,54.41 13.68,63.37
GND on IN3 (solid shape): outline of 4551 points within 17.81,0.25 227.22,115.15
GND on GND1: outline of 379 points within 0.26,0.26 227.21,115.15
GND on VCC: outline of 88 points within 0.26,17.46 19.9,79.49
GND on VCC: 205.25,0.25 205.08,0.33 205,0.5 205,8.51 204.05,11.29 201.58,12.88 201.58,31.7 204.75,34.88 204.75,37.29 205.24,37.78 224.6,37.78 224.98,37.35 225.36,36.94 226.23,36.04 227.14,35.18 227.19,35.1 227.22,35 227.22,0.5 227.14,0.33 226.97,0.25
GND on VCC: 64.21,21.08 63.76,21.52 58.87,21.52 58.01,22.39 58.2,28.86 55.02,32.04 55.02,43.9 56.29,45.17 56.29,47.66 55.02,48.93 55.02,87.07 59.82,91.75 59.82,91.75 59.9,91.83 59.97,91.9 59.97,92.11 59.97,92.11 59.97,99.9 65.29,105.21 120.57,105.21 122.46,103.33 122.46,75.98 121.97,75.5 121.29,75.5 120.66,76.13 118.16,76.13 114.99,72.96 111.43,72.96 109.88,71.41 109.88,66.25 110.54,65.59 117.9,65.59 118.14,65.35 118.14,61.17 118.77,60.53 118.77,57.43 117.76,56.41 117.76,52.15 119.03,50.88 119.03,47.53 118.41,46.92 114.99,46.92 112.93,44.87 112.93,32.8 112.32,32.19 99.75,32.19 91.09,23.53 91.09,22.01 90.6,21.52 69.71,21.52 69.27,21.08
GND on GND2: outline of 356 points within 0.26,0.26 227.21,115.15
GNDA on TOP (solid shape): 29.05,26.73 29.05,25.89 28.92,25.76 28.16,25.76 28.09,25.83 28.09,25.84 28.03,25.9 28.03,26.21 27.94,26.3 27.92,26.36 27.9,26.4 27.9,26.73 28.1,26.92 28.85,26.92
GNDA on TOP (solid shape): 26.64,26.29 26.64,25.67 26.49,25.52 26.09,25.52 25.48,24.91 25.48,24.5 25.06,24.09 24.84,24.09 23.85,24.09 23.8,24.09 23.65,23.93 23.65,23.93 23.59,23.87 23.59,23.41 23.57,23.38 23.06,23.38 22.83,23.62 22.23,23.62 21.94,23.33 21.29,23.33 21.19,23.43 21.19,24.09 21.88,24.78 24.12,24.78 24.13,24.79 24.76,25.42 25.12,25.42 25.68,25.98 25.68,26.26 25.79,26.37 26.56,26.37
GNDA on BOTTOM (solid shape): 26.36,27.26 26.36,25.02 25.71,24.38 22.19,24.38 22.13,24.44 22.13,25.01 22.44,25.33 24.39,25.33 24.95,25.89 24.95,27.05 25.39,27.49 26.13,27.49
GNDA on GND1: 24.12,14.41 18.59,14.41 15.95,11.77 15.95,3.86 1.5,3.86 1.33,3.93 1.26,4.1 1.26,6.6 1.33,6.77 1.5,6.85 13.5,6.85 14.24,7.47 13.75,8.31 13.75,13.69 14.24,14.53 13.5,15.16 1.5,15.16 1.33,15.23 1.26,15.4 1.26,16.95 1.33,17.12 1.5,17.2 3.65,17.2 3.72,17.2 3.78,17.21 3.78,17.1 3.93,16.95 15.06,16.95 18.44,20.34 18.44,24.72 18.93,25.2 24.01,25.2 24.29,25.48 24.29,26.88 25.94,28.53 25.94,31.96 26.3,32.32 28.5,32.32 29.39,31.43 31.6,31.43 32.79,30.23 32.79,29.33 32.79,29.28 32.79,29.14 33.47,28.47 33.47,28.28 33.9,27.85 33.9,26.34 33.78,26.22 29.39,26.22 28.98,25.82 28.98,22.71 28.88,22.6 27.73,22.6 26.57,21.45 26.57,20.07 27.47,19.17 28.78,19.17 29.75,20.14 29.75,21.09 29.8,21.14 30.58,21.14 30.64,21.09 30.64,20.18 30.25,19.8 30.25,19.59 28.94,18.28 27.46,18.28 26.22,17.04 26.22,15.23 26.03,15.04 24.75,15.04
GNDA on VCC: 24.12,14.41 19.35,14.41 19.35,14.4 18.59,14.4 15.96,11.77 15.96,3.86 1.5,3.86 1.33,3.93 1.26,4.1 1.26,6.6 1.33,6.77 1.5,6.85 13.5,6.85 14.24,7.47 13.75,8.31 13.75,13.69 14.24,14.53 13.5,15.16 1.5,15.16 1.33,15.23 1.26,15.4 1.26,16.95 1.26,17.01 1.32,16.95 15.06,16.95 18.44,20.34 18.44,24.72 18.93,25.2 24.01,25.2 24.29,25.48 24.29,26.88 25.94,28.53 25.94,31.96 26.3,32.32 28.5,32.32 29.39,31.43 31.6,31.43 32.79,30.23 32.79,29.33 32.79,29.28 32.79,29.14 33.47,28.47 33.47,28.29 33.9,27.86 33.9,26.33 33.78,26.22 29.39,26.22 28.98,25.82 28.98,22.71 28.88,22.6 27.73,22.6 26.57,21.45 26.57,20.07 27.47,19.17 28.78,19.17 29.75,20.14 29.75,21.09 29.8,21.14 30.58,21.14 30.64,21.09 30.64,20.18 30.25,19.8 30.25,19.59 28.94,18.28 27.46,18.28 26.22,17.04 26.22,15.23 26.03,15.04 24.75,15.04
GNDA on GND2: 24.12,14.41 18.58,14.41 15.95,11.78 15.95,3.86 1.5,3.86 1.33,3.93 1.26,4.1 1.26,6.6 1.33,6.77 1.5,6.85 13.5,6.85 14.24,7.47 13.75,8.31 13.75,13.69 14.24,14.53 13.5,15.16 1.5,15.16 1.33,15.23 1.26,15.4 1.26,16.95 1.33,17.12 1.5,17.2 3.65,17.2 3.72,17.2 3.78,17.21 3.78,17.1 3.93,16.95 15.06,16.95 18.44,20.34 18.44,24.72 18.93,25.2 24.01,25.2 24.29,25.48 24.29,26.88 25.94,28.53 25.94,31.96 26.3,32.32 28.5,32.32 29.39,31.43 31.6,31.43 32.79,30.23 32.79,29.33 32.79,29.28 32.79,29.14 33.47,28.47 33.47,28.29 33.9,27.85 33.9,26.33 33.79,26.22 29.39,26.22 28.98,25.82 28.98,22.71 28.88,22.6 27.73,22.6 26.57,21.45 26.57,20.07 27.47,19.17 28.78,19.17 29.75,20.14 29.75,21.09 29.8,21.14 30.58,21.14 30.64,21.09 30.64,20.18 30.25,19.8 30.25,19.59 28.94,18.28 27.46,18.28 26.22,17.04 26.22,15.23 26.03,15.04 24.75,15.04
VCC_GT_5V on BOTTOM (solid shape): 168.75,95.8 168.75,95.25 168.07,94.56 168.07,93.9 167.96,93.8 167.58,93.8 167.5,93.88 167.5,95.09 167.35,95.24 167.35,95.82 167.41,95.88 168.67,95.88
VCCSA_B+ on TOP (solid shape): 155.67,49.91 155.67,48.64 155.6,48.57 154.33,48.57 154.27,48.64 154.27,49.91 154.46,50.1 155.48,50.1
VCCSA_B+ on BOTTOM (solid shape): 157.2,50.48 157.2,49.54 156.67,49.54 156.65,49.51 156.65,49.03 157.2,49.03 157.23,49 157.23,48.67 157,48.45 154.27,48.45 153.64,49.08 151.14,49.08 151.1,49.13 151.1,49.65 151.13,49.69 151.64,49.69 151.82,49.87 151.82,50.43 152.07,50.68 157,50.68
VIN_+VCCEOPIO on BOTTOM (solid shape): 102.9,109.61 102.9,108.82 104.27,107.45 104.27,107.26 105.49,106.04 106.89,106.04 106.99,105.94 106.99,105.75 106.9,105.66 105.95,105.66 105.63,105.34 105.63,103.37 105.4,103.14 102.85,103.14 102.37,103.63 102.37,103.86 102.37,105.72 102.82,105.72 102.82,106.22 102.37,106.22 102.37,106.52 102.82,106.52 102.82,107.02 102.37,107.02 102.37,107.53 100.97,108.92 100.97,109.65 101.06,109.74 102.77,109.74
+DCBATOUT_LCD on TOP (solid shape): 56.04,109.07 56.04,105.79 55.85,105.6 55.85,104.07 55.85,104.07 55.85,103.98 56.04,103.8 56.04,100.64 55.91,100.52 54.38,100.52 54.21,100.69 54.21,109.09 54.34,109.21 55.89,109.21
+DCBATOUT_LCD on BOTTOM (solid shape): 56.52,102.12 56.52,98.63 56.42,98.53 56.42,97.39 56.32,97.28 55.22,97.28 55.1,97.39 55.1,98.37 54.61,98.86 54.61,99.06 55.11,99.06 55.11,99 55.12,98.95 55.13,98.9 55.15,98.85 55.18,98.81 55.22,98.77 55.26,98.73 55.31,98.71 55.36,98.69 55.41,98.68 55.46,98.67 55.52,98.68 55.57,98.69 55.62,98.71 55.66,98.73 55.71,98.77 55.74,98.81 55.77,98.85 55.8,98.9 55.81,98.95 55.82,99 55.82,99.06 55.81,99.11 55.8,99.16 55.77,99.21 55.74,99.25 55.71,99.29 55.66,99.32 55.62,99.35 55.57,99.37 55.52,99.38 55.46,99.39 55.41,99.38 55.36,99.37 55.31,99.35 55.26,99.32 55.22,99.29 55.18,99.25 55.15,99.21 55.13,99.16 55.12,99.11 55.11,99.06 54.61,99.06 54.61,102.14 54.97,102.5 56.14,102.5
+LAN_VDDREG on TOP (solid shape): 41.43,92.07 41.43,91.04 41.73,90.74 41.73,89.23 41.66,89.15 41.03,89.15 41.03,89.15 41.03,90.17 40.73,90.46 40.73,92.01 40.92,92.2 41.3,92.2
+LAN_VDDREG on IN1 (solid shape): 42.5,91.76 42.5,89.75 42.33,89.58 41.56,89.58 40.76,88.78 35.13,88.78 34.66,89.25 33.27,89.25 33.05,89.03 33.05,86.86 32.68,86.5 32.04,86.5 31.78,86.24 31.78,85.25 31.5,84.97 30.52,84.97 30.13,85.36 30.13,87.08 30.48,87.43 31.16,87.43 31.16,87.38 31.17,87.33 31.19,87.28 31.22,87.23 31.25,87.19 31.29,87.16 31.33,87.13 31.38,87.1 31.43,87.09 31.49,87.08 31.54,87.08 31.59,87.09 31.64,87.1 31.69,87.13 31.73,87.16 31.77,87.19 31.81,87.23 31.83,87.28 31.85,87.33 31.87,87.38 31.87,87.43 31.87,87.49 31.85,87.54 31.83,87.59 31.81,87.64 31.77,87.68 31.73,87.71 31.69,87.74 31.64,87.77 31.59,87.78 31.54,87.79 31.49,87.79 31.43,87.78 31.38,87.77 31.33,87.74 31.29,87.71 31.25,87.68 31.22,87.64 31.19,87.59 31.17,87.54 31.16,87.49 31.16,87.43 30.48,87.43 31.16,88.11 31.16,89.41 32.61,90.86 35.15,90.86 35.95,90.05 38.81,90.05 38.81,90.06 39.8,90.06 40.53,90.79 40.53,92.01 40.76,92.24 42.01,92.24
+LCDVDD on TOP (solid shape): 41.85,106.4 41.85,105.06 41.82,105.02 39.65,105.02 39.46,105.21 39.46,105.9 40.02,106.46 41.8,106.46
+LCDVDD_LCD on TOP (solid shape): 43.78,106.29 43.78,102.8 43.46,102.48 43.46,98.74 43.27,98.55 42.26,98.55 42.07,98.74 42.07,100.1 41.72,100.45 41.72,102.45 42.57,103.31 42.57,105.02 42.64,105.02 42.64,106.42 43.65,106.42
+LCDVDD_LCD on BOTTOM (solid shape): 43.4,100.07 43.4,97.4 43.34,97.34 42.19,97.34 42.13,97.4 42.13,100.13 42.26,100.26 43.21,100.26
+RTC_VCC on BOTTOM (solid shape): 206.15,50.48 206.15,50.16 205.96,49.97 204.31,49.97 204.18,50.1 204.18,50.22 204.31,50.35 205.51,50.35 205.71,50.54 206.09,50.54
+TPAN_VDD on TOP (solid shape): 47.98,105.06 47.98,102.79 48.23,102.55 48.86,102.55 49.24,102.17 49.24,100.52 49.16,100.44 48.49,100.44 48.36,100.57 47.41,100.57 47.4,100.58 46.57,100.58 46.13,101.02 46.13,105.04 46.18,105.09 47.96,105.09
+TPAN_VDD on BOTTOM (solid shape): 49.3,101.85 49.3,99.25 48.42,98.36 48.42,97.4 48.35,97.34 48.16,97.34 48.1,97.4 48.1,98.86 48.35,99.12 48.35,99.88 48.1,100.13 48.1,101.85 48.23,101.98 49.18,101.98
+USB30_VCCA on BOTTOM (solid shape): 21.81,42.35 21.81,41.31 21.52,41.02 20.73,41.02 20.54,40.83 20.35,40.83 20.29,40.89 20.29,42.29 20.48,42.48 21.68,42.48
+USB30_VCCA on BOTTOM (solid shape): 16.28,52.57 19.23,52.57 20.1,53.44 21.09,53.44 21.17,53.37 21.17,51.8 20.35,50.99 15.58,50.99 13.48,53.08 12.16,53.08 11.97,52.89 11.97,52.82 11.74,52.33 11.97,51.83 11.97,50.86 11.71,50.6 10.7,50.6 10.44,50.86 10.44,53.09 11.45,54.1 14.76,54.1
+USB30_VCCA on IN2 (solid shape): outline of 416 points within 15.12,40.29 21.94,52.13
+USB30_VCCB on TOP (solid shape): 16.67,37.84 16.67,35.81 16.54,35.68 15.46,35.68 14.95,36.19 14.95,37.71 15.21,37.97 16.54,37.97
+USB30_VCCB on BOTTOM (solid shape): 19.83,35.67 19.83,30.97 19.63,30.77 17.67,30.77 17.66,30.78 16.81,30.78 16.8,30.77 16.68,30.77 16.07,30.16 14.82,30.16 14.51,30.47 14.51,31.55 15.01,32.06 15.93,32.06 16.72,32.85 16.72,34.55 15.46,35.81 15.46,36.76 15.59,36.89 18.61,36.89
+USB30_VCCC on BOTTOM (solid shape): 209.51,14.35 209.51,12.42 209.22,12.12 207.27,12.12 206.81,12.58 206.81,14.64 206.99,14.82 209.05,14.82
+USB30_VCCC on BOTTOM (solid shape): 197.68,23.86 197.68,22.7 197.49,22.52 197.49,21.82 197.32,21.65 196.04,21.65 195.74,21.95 195.74,23.81 195.99,24.06 197.47,24.06
+USB30_VCCC on BOTTOM (solid shape): 206.4,47.43 206.4,45.33 206.28,45.21 205.9,45.21 205.58,45.52 204.3,45.52 204.21,45.61 204.21,47.72 204.3,47.81 206.02,47.81
+USB30_VCCC on IN2 (solid shape): 206.53,47.39 206.53,43.37 206.28,43.11 204.88,43.11 204.5,43.49 204.5,47.05 205.07,47.62 206.3,47.62
+USB30_VCCC on IN2 (solid shape): 198.53,25.59 198.53,24.7 197.7,23.87 197.7,21.27 197.52,21.09 195.94,21.09 195.74,21.29 195.74,24.95 196.82,26.03 198.08,26.03
+USB30_VCCC on IN2 (solid shape): 209.61,15.75 209.61,14.04 209.07,13.5 206.99,13.5 206.73,13.75 206.73,14.64 206.89,14.79 207.85,14.79 208.08,15.02 208.08,15.75 208.21,15.88 209.48,15.88
+V_DDR_REFA on TOP (solid shape): 70.36,43.86 70.48,43.74 71.31,43.74 71.44,43.61 71.44,43.36 71.31,43.23 70.74,43.23 70.55,43.04 70.55,40.98 70.42,40.85 69.93,40.85 69.85,40.94 69.85,44.5 70.36,44.5
+V_DDR_REFB on TOP (solid shape): 57.72,44.91 57.72,43.99 57.91,43.8 58.61,43.8 58.74,43.67 58.74,43.36 58.61,43.23 57.85,43.23 57.75,43.13 57.75,41.6 57.68,41.53 57.17,41.53 57.12,41.58 57.12,41.6 57.12,44.93 57.14,44.94 57.68,44.94
BST_1.2V on TOP (solid shape): 72.23,102.93 71.59,102.93 71.59,103.31 71.34,103.56 69.88,103.56 69.88,103.75 70.77,103.75 70.83,103.82 72.23,103.82
BST_3V on BOTTOM (solid shape): 179.67,78.73 181.03,78.73 181.11,78.65 181.11,78.52 181.05,78.46 180.29,78.46 179.74,77.91 178.97,77.91 178.91,77.97 178.91,78.86 179.54,78.86
BST_5V on BOTTOM (solid shape): 190.75,78.64 192.09,78.64 192.16,78.58 192.16,78.46 191.99,78.29 189.26,78.29 189.13,78.42 189.13,79.05 189.2,79.12 190.27,79.12
BST_+1VALW on TOP (solid shape): 152.07,32.74 152.07,32.54 151.9,32.37 151.85,32.33 151.8,32.28 151.24,31.71 151.23,31.7 150.97,31.44 150.97,31.24 150.88,31.15 150.78,31.15 150.25,31.68 150.25,31.79 151.26,32.8 151.54,32.8 151.67,32.93 151.88,32.93
BST_+1VALW on BOTTOM (solid shape): 152.03,32.77 152.04,32.76 152.04,32.21 151.93,31.96 152.04,31.71 152.04,31.42 151.4,30.78 150.49,30.78 150.43,30.84 150.43,31.72 150.81,32.1 151.44,32.1 151.49,32.15 151.51,32.15 151.51,32.18 151.52,32.19 151.52,32.22 151.53,32.23 151.53,32.81 151.63,32.91 151.9,32.91
BST_+1VALW_R on BOTTOM (solid shape): 151.39,33.08 151.39,32.27 151.37,32.25 148.98,32.25 148.84,32.39 148.84,33.13 148.92,33.22 151.25,33.22
BST_+VCCEOPIO on BOTTOM (solid shape): 108.8,105.6 108.8,105.15 109.5,104.45 109.5,103.06 109.44,102.99 108.55,102.99 108.49,103.06 108.49,104.38 108.23,104.63 108.23,105.47 108.04,105.66 107.47,105.66 107.38,105.75 107.38,105.94 107.45,106.02 108.38,106.02
CORE_SW on TOP (solid shape): 153.51,56.7 153.51,53.97 153.32,53.78 152.68,53.78 152.49,53.97 152.49,56.7 152.56,56.76 153.44,56.76
CORE_SW on BOTTOM (solid shape): 157,57.08 157.64,57.08 157.76,56.95 157.76,54.16 157.38,53.78 152.83,53.78 152.67,53.94 152.67,55.4 152.83,55.56 154.25,55.56 154.25,56.32 152.81,56.32 152.67,56.46 152.67,57.07 153.57,57.97 156.11,57.97
CPU_B+ on TOP (solid shape): 161.64,57.21 161.64,54.8 162.46,53.97 162.46,48.83 162.08,48.45 161,48.45 160.87,48.57 160.87,50.22 160.68,50.41 160.11,50.41 160.11,51.81 160.18,51.87 160.68,51.87 160.94,52.13 160.94,53.44 160.05,54.33 160.05,57.21 160.24,57.4 161.45,57.4
CPU_B+ on BOTTOM (solid shape): 160.82,58.19 160.82,57.45 160.94,57.34 161.5,57.34 161.52,57.31 161.52,54.72 162.72,53.53 163.39,53.53 163.64,53.13 163.9,53.53 167.1,53.53 167.47,53.16 167.47,49.91 167.02,49.46 165.57,49.46 165.57,49.46 165.38,49.46 165.38,49.46 164.37,49.46 164.37,49.46 164.18,49.46 164.18,49.46 163.12,49.46 162.1,48.45 157.48,48.45 157.36,48.57 157.36,49.16 157.33,49.18 156.82,49.18 156.8,49.21 156.8,49.36 156.82,49.39 157.33,49.39 157.36,49.41 157.36,49.9 157.53,50.07 159.77,50.07 160.06,50.36 160.06,53.69 160.07,53.7 160.07,57.29 160.11,57.34 160.43,57.34 160.56,57.46 160.56,58.21 160.63,58.27 160.74,58.27
EC_AGND on TOP (solid shape): 25.93,49.85 26.33,49.85 26.57,49.61 27.21,49.61 27.32,49.5 27.32,48.94 27.24,48.86 26.64,48.86 26.52,48.98 26.52,49.16 26.3,49.38 25.97,49.38 25.75,49.16 25.74,48.94 25.01,48.94 24.78,48.72 24.78,47.75 24.95,47.58 26.31,47.58 26.36,47.63 27.24,47.63 27.29,47.59 27.29,46.99 27.15,46.86 26.54,46.86 26.51,46.88 26.39,46.88 26.39,46.88 26.29,46.9 26.2,46.88 26.19,46.88 26.11,46.88 25.81,46.58 24.17,46.58 24.06,46.68 24.06,47.52 23.8,47.78 23.24,47.78 23.2,47.83 23.2,49.02 23.34,49.16 23.9,49.16 24.34,49.61 25.68,49.61 25.92,49.86
EN_2.5V on BOTTOM (solid shape): 73.04,9.98 73.04,9.81 73.24,9.61 74.67,9.61 74.86,9.42 74.86,9.16 74.64,8.95 73.24,8.95 72.5,8.2 71.88,8.2 71.83,8.25 71.83,8.9 72.48,9.54 72.48,9.96 72.64,10.13 72.89,10.13
GPU_B+ on TOP (solid shape): outline of 213 points within 166.01,77.21 171.61,93.72
GPU_B+ on BOTTOM (solid shape): 166.77,94.51 166.77,93.71 166.82,93.67 167.32,93.67 167.33,93.66 167.48,93.66 167.48,90.49 167.71,90.26 167.71,88.85 167.86,88.7 174.94,88.7 175.09,88.55 175.09,87.9 175.1,87.9 175.1,87.88 175.61,87.88 175.61,87.43 175.1,87.43 175.1,87.4 175.09,87.4 175.09,86.7 175.1,86.7 175.1,86.68 175.61,86.68 175.61,86.23 175.1,86.23 175.1,86.21 175.09,86.21 175.09,81.39 170.84,77.15 166.65,77.15 166.4,77.4 166.4,80.66 166.01,81.04 166.01,84.35 166.04,84.39 166.26,84.39 166.29,84.39 166.29,84.39 166.39,84.39 166.5,84.51 166.5,85.28 166.24,85.54 166.24,85.58 166.78,85.58 166.78,84.46 166.85,84.39 167.47,84.39 167.5,84.36 167.5,81.7 167.73,81.47 167.73,79.75 167.92,79.56 169.5,79.56 171.15,81.21 171.15,81.21 171.31,81.37 171.31,85.38 171.16,85.53 171.16,85.54 170.62,86.09 167.28,86.09 166.78,85.58 166.24,85.58 166.24,90.22 166.01,90.45 166.01,93.62 166.05,93.66 166.45,93.66 166.51,93.71 166.51,94.53 166.57,94.59 166.69,94.59
GT_SNUB2 on TOP (solid shape): 162.75,91.23 162.75,89.33 162.61,89.19 160.99,89.19 160.85,89.33 160.85,89.96 160.47,90.34 159.72,90.34 159.57,90.49 159.57,91.33 159.72,91.47 162.51,91.47
GT_SW1 on TOP (solid shape): 162.72,84.96 162.72,83.81 162.67,83.76 160.99,83.76 160.94,83.81 160.94,85.28 161.09,85.43 162.25,85.43
GT_SW1 on BOTTOM (solid shape): 163.73,83.94 163.73,81.97 162.72,80.96 159.41,80.96 159.29,81.08 159.29,82.54 160.3,82.54 160.3,83.43 159.29,83.43 159.29,85.02 159.7,85.43 162.24,85.43
GT_SW2 on TOP (solid shape): 162.72,93.53 162.72,91.94 162.65,91.88 161,91.88 160.94,91.94 160.94,93.53 161.13,93.72 162.53,93.72
GT_SW2 on BOTTOM (solid shape): 163.72,93.23 163.72,90.86 162.2,89.34 159.41,89.34 159.29,89.47 159.29,90.8 160.3,90.8 160.3,91.69 159.29,91.69 159.29,93.28 159.67,93.66 163.29,93.66
INT-SPK-L+ on TOP (solid shape): 31.49,21.01 31.49,20.18 31.53,20.14 31.53,19.44 31.49,19.35 31.49,19.25 30.72,18.48 30.72,17.61 30.69,17.58 29.94,17.58 29.94,18.28 30.25,18.59 30.25,18.78 30.64,19.17 30.97,19.17 31.28,19.48 31.28,21.01 31.34,21.07 31.43,21.07
INT-SPK-L- on TOP (solid shape): 31.89,21.02 31.89,19.04 31.84,18.99 31.84,18.09 31.08,18.09 31.08,18.6 31.68,19.2 31.68,21.02 31.74,21.07 31.83,21.07
INT-SPK-R+ on TOP (solid shape): 32.7,21.01 32.7,19.72 32.79,19.62 32.92,19.62 33.18,19.36 33.43,19.36 33.56,19.23 33.56,18.72 34.19,18.09 34.19,17.58 33.43,17.58 33.43,18.35 32.48,19.3 32.48,19.43 32.47,19.43 32.47,21.01 32.54,21.07 32.63,21.07
INT-SPK-R- on TOP (solid shape): 32.3,21.01 32.3,19.28 32.99,18.59 32.99,18.09 32.22,18.09 32.22,18.88 32.07,19.03 32.07,21 32.14,21.07 32.23,21.07
LAN_GND on TOP (solid shape): 16.66,82.18 16.66,80.11 16.4,79.85 8.93,79.85 8.63,80.15 8.63,81.18 8.88,81.43 15.35,81.43 15.51,81.59 15.51,82.17 15.56,82.22 16.61,82.22
LAN_GND on TOP (solid shape): 22.65,79.11 22.65,78.84 21.95,78.14 21.95,77.86 21.9,77.8 20.37,77.8 20.16,78.02 19.3,78.02 19.17,78.15 19.17,78.92 19.3,79.04 21.37,79.04 21.9,79.57 22.19,79.57
LAN_GND on TOP (solid shape): 13.07,98.93 13.07,96.13 12.85,95.91 10.73,95.91 10.7,95.91 6.86,95.91 6.86,96.71 6.64,97.24 6.1,97.46 5.3,97.46 4.82,97.29 4.56,96.84 4.55,96.78 4.55,96.71 4.55,95.91 0.5,95.91 0.33,95.99 0.25,96.16 0.25,98.9 0.33,99.07 0.5,99.15 12.85,99.15
LAN_GND on BOTTOM (solid shape): 13.07,98.93 13.07,96.13 12.85,95.91 10.73,95.91 10.7,95.91 6.86,95.91 6.86,96.71 6.64,97.24 6.1,97.46 5.3,97.46 4.82,97.29 4.56,96.84 4.55,96.78 4.55,96.71 4.55,95.91 0.5,95.91 0.33,95.99 0.25,96.16 0.25,98.9 0.33,99.07 0.5,99.15 12.85,99.15
LDO_+1VALW on TOP (solid shape): 153.7,30.92 153.7,30.81 153.7,30.81 153.7,30.59 152.96,29.86 152.54,29.86 152.12,30.28 152.12,30.38 152.67,30.94 153.13,30.94 153.27,31.07 153.55,31.07
LG_1.2V on TOP (solid shape): 69.82,102.36 70.01,102.36 70.2,102.17 70.2,101.34 70.07,101.21 69.88,101.21 69.37,101.72 69.37,102.48 69.43,102.55 69.62,102.55
LG_1.2V on TOP (solid shape): 76.04,102.23 76.04,101.85 75.91,101.72 75.47,101.72 74.83,101.09 74.64,101.09 74.32,101.4 74.32,101.72 74.9,102.29 75.97,102.29
LG_1.2V on BOTTOM (solid shape): 76.04,102.99 76.04,101.98 75.85,101.79 75.09,101.79 74.9,101.98 74.9,102.29 75.28,102.67 75.28,102.93 75.47,103.12 75.91,103.12
LGATE_CHG on TOP (solid shape): 177.57,39.82 177.57,39.06 177.42,38.9 176.46,38.9 176.34,39.02 176.34,39.81 176.48,39.94 177.45,39.94
LGATE_CHG on TOP (solid shape): 171.8,48.45 171.85,48.45 171.92,48.38 172.88,48.38 172.94,48.32 172.94,48.23 172.89,48.17 171.7,48.17 171.57,48.04 170.68,48.04 170.51,48.2 170.51,48.43 170.7,48.62 171.63,48.62
LGATE_CHG on IN3 (solid shape): 177.53,40.76 177.53,39.56 177.41,39.43 176.55,39.43 176.42,39.56 176.42,40.7 176.57,40.84 177.45,40.84
LGATE_CHG on IN3 (solid shape): 172.68,48.16 172.68,47.95 172.35,47.62 172.1,47.62 171.76,47.96 170.77,47.96 170.6,48.13 170.6,48.56 170.77,48.73 172.11,48.73
LX_1.2V on TOP (solid shape): 70.89,102.67 70.89,102.42 71.09,102.23 71.91,102.23 72.1,102.42 72.67,102.42 72.74,102.36 72.74,101.85 72.55,101.66 70.89,101.66 69.75,102.8 69.75,102.86 69.88,102.99 70.58,102.99
LX_1.2V on BOTTOM (solid shape): 81.69,105.85 81.69,98.01 81.5,97.82 80.47,97.82 80.29,98 80.29,101.34 79.21,102.42 79.21,102.93 78.83,103.31 75.51,103.31 75.5,103.32 75.5,104.36 75.52,104.38 78.82,104.38 79.28,104.83 79.28,105.91 81.63,105.91
LX_1.2V on IN3 (solid shape): 71.28,102.04 72.04,102.04 72.23,101.85 72.23,101.4 72.1,101.28 71.09,101.28 70.39,101.98 70.39,102.48 70.51,102.61 70.7,102.61
LX_1.2V on IN3 (solid shape): 80.48,102.42 81.05,102.42 81.18,102.29 81.18,101.85 80.99,101.66 80.04,101.66 79.28,102.42 79.28,102.67 79.59,102.99 79.91,102.99
LX_1.8VALW on TOP (solid shape): 49.94,9.65 49.94,7.58 49.71,7.35 48.72,7.35 48.16,7.91 48.16,9.65 48.29,9.77 49.81,9.77
LX_1.8VALW on BOTTOM (solid shape): 50.16,9.23 50.92,9.23 51,9.16 51,8.51 50.91,8.42 50.47,8.42 50.24,8.2 50.24,7.48 50.06,7.3 46.91,7.3 46.83,7.38 46.83,10.21 46.88,10.26 49.13,10.26
LX_3V on TOP (solid shape): 181.89,78.04 181.89,76.45 181.7,76.26 180.31,76.26 180.11,76.45 180.11,77.97 180.24,78.1 181.83,78.1
LX_3V on BOTTOM (solid shape): 181.45,81.66 181.45,80.68 181.37,80.6 181.24,80.6 181.13,80.7 180.75,80.7 180.56,80.89 180.56,81.72 180.69,81.86 181.25,81.86
LX_3V on BOTTOM (solid shape): 181.89,78.29 181.89,77.02 182.15,76.77 182.97,76.77 183.54,76.19 183.54,73.94 183.26,73.65 177.77,73.65 177.51,73.91 177.51,76.45 180.24,76.45 181.18,77.39 181.18,78.31 181.26,78.39 181.79,78.39
LX_3V on IN3 (solid shape): 181.64,81.66 181.64,77.08 181.96,76.77 181.96,76.45 181.77,76.26 180.88,76.26 180.56,76.58 180.56,81.72 180.69,81.85 181.45,81.85
LX_5V on TOP (solid shape): 193.13,76.7 193.13,75.31 193.07,75.24 191.48,75.24 191.35,75.37 191.35,76.64 191.67,76.96 192.88,76.96
LX_5V on BOTTOM (solid shape): 192.5,81.34 192.5,80.56 192.43,80.5 192.31,80.5 192.18,80.63 191.8,80.63 191.61,80.82 191.61,81.58 191.8,81.77 192.07,81.77
LX_5V on BOTTOM (solid shape): 192.94,78.23 192.94,76.77 193.2,76.51 195.1,76.51 195.48,76.13 195.48,73.78 195.29,73.59 190.78,73.59 189.89,74.48 189.89,76.51 190.02,76.64 190.59,76.64 192.27,78.32 192.86,78.32
LX_5V on IN3 (solid shape): 192.69,81.26 192.69,77.01 192.81,76.89 192.81,76.51 192.62,76.32 191.79,76.32 191.61,76.5 191.61,81.64 191.74,81.77 192.18,81.77
LX_+1VALW on TOP (solid shape): 148,32.13 148,31.89 147.98,31.8 148,31.7 148,31.3 148.71,30.58 148.71,30.39 149.43,29.67 149.61,29.67 149.67,29.62 149.69,29.58 149.69,29.5 149.15,28.96 148.61,28.96 146.19,31.38 146.19,31.69 147.15,32.65 147.48,32.65
LX_+1VALW on BOTTOM (solid shape): 148.51,33.11 148.51,32.19 148.45,32.14 148.2,32.14 148.01,31.95 148.01,31.69 147.64,31.33 147.64,30.46 147.41,30.23 144.22,30.23 144.12,30.34 144.12,32.51 144.16,32.55 147.08,32.55 147.73,33.19 148.42,33.19
LX_+1VALW on IN3 (solid shape): 148.42,32.56 148.42,32.38 147.98,31.94 147.98,31.88 147.82,31.72 147.68,31.72 147.09,32.32 147.09,32.51 147.61,33.03 147.95,33.03
LX_+1VALW on IN3 (solid shape): 153.07,33.57 153.07,33.21 153.05,33.13 153.05,33.04 153.04,32.99 152.99,32.87 152.99,32.75 152.99,32.74 152.99,32.44 152.92,32.37 152.9,32.36 152.71,32.27 152.61,32.08 152.61,32.06 152.55,32.01 152.55,32 152.34,31.78 152.01,31.78 151.88,31.92 151.88,32.25 152.11,32.48 152.11,32.53 152.11,32.56 152.14,32.69 152.11,32.82 152.11,32.83 152.11,33.21 152.1,33.22 152.1,33.67 152.26,33.82 152.82,33.82
LX_+1VALW on TOP: 151.57,30.8 151.66,30.8 152.35,31.48 152.35,31.68 152.51,31.84 152.51,32.06 152.84,32.39 152.84,32.59 152.71,32.71 152.66,32.76 152.41,32.76 151.62,31.96 151.62,31.8 151.15,31.34 151.15,31.21
MCT1 on TOP (solid shape): 21.58,92.35 21.58,92.17 21.45,92.04 20.66,92.04 20.29,92.41 18.63,92.41 18.54,92.5 18.54,93.52 18.59,93.57 20.36,93.57
MCT1 on BOTTOM (solid shape): 21.61,93.78 21.61,92.06 21.51,91.97 20.76,91.97 20.64,92.08 20.64,93.56 20.31,93.89 19.27,93.89 19.1,94.07 19.1,94.36 19.29,94.55 20.85,94.55
MCT2 on TOP (solid shape): 21.34,91.66 21.34,90.83 21.14,90.63 20.97,90.63 20.97,90.64 18.65,90.64 18.56,90.72 18.56,91.7 18.66,91.8 21.2,91.8
MCT2 on BOTTOM (solid shape): 21.35,91.65 21.35,90.85 21.14,90.63 20.69,90.63 20.46,90.86 19.27,90.86 19.08,91.05 19.08,91.35 19.26,91.52 20.33,91.52 20.62,91.81 21.19,91.81
MCT3 on TOP (solid shape): 21.26,88.64 21.26,87.74 21.12,87.6 18.65,87.6 18.57,87.68 18.57,88.69 18.67,88.79 21.11,88.79
MCT3 on BOTTOM (solid shape): 21.27,88.63 21.27,87.74 21.12,87.59 20.62,87.59 20.33,87.88 19.27,87.88 19.08,88.06 19.08,88.34 19.28,88.54 20.33,88.54 20.54,88.76 20.59,88.8 21.11,88.8
MCT4 on TOP (solid shape): 21.31,85.64 21.31,84.88 21.14,84.71 18.68,84.71 18.57,84.82 18.57,85.72 18.7,85.85 21.11,85.85
MCT4 on BOTTOM (solid shape): 21.33,85.63 21.33,84.87 21.13,84.67 20.57,84.67 20.37,84.87 19.25,84.87 19.07,85.05 19.07,85.33 19.28,85.53 20.31,85.53 20.63,85.84 21.12,85.84
MIC_IN_R on TOP (solid shape): 30.39,30.21 30.59,30 30.59,29.9 31.01,29.48 31.01,29.41 30.48,28.88 30.41,28.88 30.06,29.23 29.78,29.23 29.62,29.4 29.62,29.7 30.12,30.21
MIC_IN_R on BOTTOM (solid shape): 24.79,18.83 24.79,18.51 24.7,18.42 24.33,18.42 24.19,18.28 24.19,16.93 24.38,16.73 24.38,15.83 23.98,15.43 23.98,14.67 23.69,14.37 22.61,14.37 22.36,14.63 22.36,15.6 22.52,15.76 23.11,15.76 23.26,15.91 23.7,15.91 23.86,16.07 23.86,16.55 23.66,16.75 23.66,18.86 23.75,18.94 24.68,18.94
MIC_IN_R on IN2 (solid shape): 24.79,19.11 24.79,18.46 24.64,18.31 23.76,18.31 23.61,18.46 23.61,18.71 23.14,19.17 23.14,19.75 23.27,19.88 24.02,19.88
MIC_IN_R on IN2 (solid shape): 30.64,29.94 30.64,29.78 30.04,29.18 28.72,29.18 28.6,29.3 28.6,30.09 28.72,30.21 30.37,30.21
MIC_IN_R on IN3 (solid shape): 23,15.85 23,14.95 22.76,14.71 22.41,14.71 21.17,15.94 21.17,16.92 21.32,17.07 21.78,17.07
PBAT_CHG_SMBCLK on TOP (solid shape): 164.03,26.98 164.03,25.32 163.89,25.19 163.59,25.19 163.45,25.33 163.45,25.71 163.57,25.83 163.57,26.34 163.41,26.51 163.41,26.98 163.48,27.05 163.95,27.05
PBAT_CHG_SMBDAT on TOP (solid shape): 165.2,27 165.2,26.44 165.03,26.26 165.03,25.36 164.88,25.2 164.58,25.2 164.44,25.35 164.44,25.45 164.44,26.29 164.6,26.46 164.6,26.98 164.65,27.04 165.16,27.04
PHASE_CHG on TOP (solid shape): 175.74,40.73 175.74,37 175.65,36.91 173.42,36.91 172.82,37.51 172.77,37.51 172.76,37.52 170.66,37.52 170.48,37.69 170.48,40.76 170.64,40.92 175.56,40.92
PHASE_CHG on TOP (solid shape): 172.95,47.92 172.95,47.83 172.89,47.77 172.01,47.77 171.22,46.98 169.71,46.98 169.65,47.05 169.65,47.71 169.75,47.81 170.4,47.81 170.5,47.91 171.67,47.91 171.74,47.98 172.88,47.98
PHASE_CHG on BOTTOM (solid shape): 176.29,40.91 176.29,37.8 176.01,37.52 170.95,37.52 170.51,37.96 170.51,40.81 170.79,41.09 176.11,41.09
PHASE_CHG on IN3 (solid shape): 171.42,39.79 171.42,39.38 171.63,39.18 171.63,38.92 171.48,38.78 170.66,38.78 170.53,38.91 170.53,39.7 170.74,39.91 171.31,39.91
PHASE_CHG on IN3 (solid shape): 171.51,47.68 171.51,47.46 171.93,47.04 171.93,46.76 171.66,46.49 171.28,46.49 170.78,46.99 170.68,46.99 170.53,47.14 170.53,47.31 171.05,47.83 171.36,47.83
RING2_R on TOP (solid shape): 32.79,30.22 32.79,29.33 32.92,29.2 32.92,28.57 32.28,28.57 32.26,28.59 32.26,29.99 32.16,30.09 32.16,30.22 32.29,30.35 32.67,30.35
RING2_R on BOTTOM (solid shape): 21.57,18.87 21.57,18.54 21.43,18.4 21.43,16.85 21.89,16.38 21.89,15.77 22.06,15.6 22.06,14.67 21.75,14.36 20.65,14.36 20.43,14.59 20.43,15.57 20.56,15.7 21.13,15.7 21.34,15.91 21.34,16.2 20.92,16.62 20.92,16.78 20.92,16.79 20.92,18.31 20.82,18.41 20.57,18.41 20.44,18.54 20.44,18.84 20.6,19 21.44,19
RING2_R on IN1 (solid shape): 21.01,15.56 21.01,14.84 20.76,14.59 19.64,14.59 19.49,14.74 19.49,15.63 19.57,15.72 19.88,15.72 19.88,15.72 20.85,15.72
RING2_R on IN2 (solid shape): 32.77,30.18 32.77,29.37 32.48,29.08 32.22,29.08 31.78,28.63 30.83,28.63 30.83,29.08 32.1,30.35 32.6,30.35
RING2_R on IN2 (solid shape): 21.61,18.85 21.61,18.13 21.88,17.86 21.88,17.7 21.27,17.09 21.1,17.09 20.4,17.79 20.4,18.85 20.53,18.98 21.48,18.98
SA_SNUB on TOP (solid shape): 152.87,48.76 152.87,48.13 152.81,48.06 151.86,48.06 151.6,47.81 151.6,47.18 151.54,47.11 150.52,47.11 150.46,47.18 150.46,48.76 150.52,48.83 152.81,48.83
SA_SW on TOP (solid shape): 149,48.7 149,46.03 148.75,45.78 148.11,45.78 147.86,46.03 147.86,48.76 147.92,48.83 148.87,48.83
SA_SW on BOTTOM (solid shape): 150.97,48.83 153.64,48.83 153.68,48.79 153.68,47.79 153.64,47.75 151.03,47.75 150.43,47.15 150.43,42.85 150.35,42.77 149.51,42.77 149.25,43.02 149.25,44.32 147.67,45.91 147.67,47.49 148.62,47.49 148.62,48.38 147.67,48.38 147.67,49.46 147.79,49.59 150.21,49.59
SNUB_+1VALW on TOP (solid shape): 146.25,29.25 147.62,29.25 147.76,29.12 147.76,28.37 147.61,28.22 145.6,28.22 144.32,29.5 144.32,29.66 145,30.34 145.16,30.34
SPK_L1-_CONN on TOP (solid shape): 32.03,17.71 32.03,16.5 31.46,15.93 31.46,15.89 31.39,15.81 31.39,15.33 31.13,15.08 31.13,13.91 31.43,13.61 31.46,13.61 31.46,12.9 31.09,12.53 31.09,11.27 30.89,11.07 30.27,11.07 29.96,11.37 29.96,12.24 30.06,12.34 30.06,13.01 30.07,13.01 30.07,13.37 30.13,13.53 30.15,13.7 30.15,15.05 30.32,15.21 30.32,16.48 30.48,16.64 30.77,16.64 30.89,16.76 30.89,17.67 31.08,17.86 31.88,17.86
SPK_L1-_CONN on BOTTOM (solid shape): 32.03,17.08 32.03,16.76 31.91,16.63 30.7,16.63 30.38,16.31 30.38,14.85 30.24,14.72 30.24,14.71 30.23,14.71 29.99,14.47 29.64,14.47 29.43,14.68 29.43,15.43 29.44,15.43 29.44,16.19 29.63,16.38 29.71,16.41 29.76,16.44 29.81,16.44 30.01,16.65 30.01,17.1 30.18,17.27 31.84,17.27
SPK_L2+_CONN on TOP (solid shape): 29.87,17.33 30.7,17.33 30.7,16.82 30,16.82 29.62,16.44 29.55,16.44 28.98,15.88 28.98,14.55 28.91,14.39 28.88,14.21 28.88,13.7 28.93,13.47 29.05,13.27 29.05,12.34 29.11,12.28 29.11,12.1 29.18,12.04 29.18,11.5 28.78,11.11 28.21,11.11 27.99,11.32 27.99,12.25 28.1,12.35 28.1,16.31 29.36,17.57 29.63,17.57
SPK_L2+_CONN on BOTTOM (solid shape): 29.75,17.53 29.75,16.63 29.64,16.52 29.59,16.5 29.35,16.5 28.98,16.14 28.98,14.71 28.79,14.51 28.36,14.51 28.16,14.71 28.16,16.58 28.6,17.02 28.6,17.68 28.71,17.78 29.5,17.78
SPK_R1-_CONN on TOP (solid shape): 33.3,17.58 33.3,17.46 33.3,16.82 33.18,16.7 33.18,16.56 33.18,16.26 33.44,15.99 33.44,14.83 33.18,14.56 33.18,13.25 32.87,12.95 32.84,12.95 32.74,12.85 32.26,12.85 32.01,13.1 32.01,13.77 32.15,13.91 32.15,14.66 32.4,14.91 32.4,15.12 32.53,15.25 32.53,15.97 32.22,16.28 32.22,17.84 33.05,17.84
SPK_R1-_CONN on BOTTOM (solid shape): 33.3,16.82 33.05,16.57 33.05,14.85 32.73,14.54 32.73,14.53 32.67,14.53 32.67,14.53 32.08,14.53 31.91,14.7 31.91,16.28 32.16,16.54 32.16,17.08 32.29,17.2 32.3,17.2 32.36,17.27 33.3,17.27
SPK_R2+_CONN on TOP (solid shape): 34.32,17.2 34.32,16.63 34.38,16.57 34.38,16.19 34.64,15.93 34.89,15.93 34.99,15.83 34.99,13.09 34.73,12.82 34.22,12.82 34.22,12.83 33.82,13.23 33.82,14.6 33.83,14.61 33.83,15.79 33.3,16.31 33.3,16.5 33.43,16.63 33.43,17.33 34.19,17.33
SPK_R2+_CONN on BOTTOM (solid shape): 34.38,16.63 34.38,16.25 34.13,16 34.13,12 33.62,11.49 31.97,11.49 30.7,12.76 30.7,14.17 30.66,14.2 30.66,16.27 30.83,16.43 31.23,16.43 31.46,16.2 31.46,14.43 31.28,14.12 31.46,13.81 31.46,13.01 31.84,12.63 32.79,12.63 33.3,13.14 33.3,16.5 33.49,16.7 34.32,16.7
SW_VCCEOPIO on BOTTOM (solid shape): 112.36,110.93 112.36,103.06 111.88,102.57 109.86,102.57 109.69,102.74 109.69,104.64 108.99,105.34 108.99,105.72 108.49,106.23 106.65,106.23 106.57,106.31 106.57,106.45 106.65,106.52 108.33,106.52 108.68,106.87 108.68,107.63 110.77,109.72 110.77,111.12 110.87,111.22 112.07,111.22
UG_1.2V on TOP (solid shape): 71.34,103.18 71.34,102.99 71.66,102.67 71.66,102.48 71.53,102.36 71.34,102.36 71.15,102.55 71.15,102.67 70.64,103.18 69.88,103.18 69.88,103.37 71.15,103.37
UG_1.2V on BOTTOM (solid shape): 76.04,106.99 76.04,105.53 75.91,105.4 75.34,105.4 75.21,105.54 75.21,107.01 75.36,107.16 75.87,107.16
UG_1.2V on IN3 (solid shape): 72.36,103.44 72.36,103.06 71.66,102.36 71.28,102.36 70.83,102.8 70.83,103.25 71.4,103.82 71.97,103.82
UG_1.2V on IN3 (solid shape): 76,106.95 76,106.2 75.84,106.04 75.17,106.04 75.03,105.9 74.88,105.9 74.55,106.23 74.55,106.59 75.13,107.16 75.79,107.16
UGATE_CHG on TOP (solid shape): 170.18,41.51 170.18,40.53 170.07,40.41 169.12,40.41 168.98,40.56 168.98,41.6 169.17,41.79 169.9,41.79
UGATE_CHG on TOP (solid shape): 172.94,47.53 172.94,47.42 172.89,47.37 172.12,47.37 172.06,47.3 172.06,47.3 171.85,47.09 171.85,46.58 171.43,46.17 170.36,46.17 170.36,46.17 169.64,46.17 169.58,46.23 169.58,46.72 169.69,46.82 171.25,46.82 172,47.58 172.89,47.58
UGATE_CHG on IN3 (solid shape): 170.71,42.19 170.71,42.03 169.9,41.22 169.19,41.22 169.01,41.39 169.01,41.62 170.02,42.63 170.27,42.63
UGATE_CHG on IN3 (solid shape): 170.68,46.45 170.68,45.83 170.89,45.63 170.89,45.49 170.56,45.16 170.2,45.16 169.63,45.74 169.63,46.58 169.81,46.76 170.38,46.76
VCIN0_PH on TOP (solid shape): 48.53,33.7 48.53,32.27 48.39,32.14 47.38,32.14 47.29,32.19 47.29,32.29 46.97,32.8 46.65,32.29 46.64,32.19 46.56,32.14 44.62,32.14 44.5,32.26 44.5,32.84 44.34,33 43.84,33 43.68,33.16 43.68,33.61 43.76,33.7 44.46,33.7 44.53,33.77 48.46,33.77
VD_IN1_C on TOP (solid shape): 46.05,34.78 46.27,34.68 46.49,34.78 48.36,34.78 48.47,34.67 48.47,34.02 48.37,33.92 44.68,33.92 44.5,34.09 44.5,34.65 44.63,34.78
VL on BOTTOM (solid shape): 197.07,78.73 197.07,77.85 197.01,77.78 195.8,77.78 195.23,78.35 194.47,78.35 194.36,78.46 194.36,78.57 194.44,78.65 195.51,78.65 195.61,78.54 196.05,78.54 196.31,78.8 197.01,78.8
N17299307 on BOTTOM (solid shape): 153.76,44.32 153.76,42.67 153.36,42.27 151.91,42.27 151.83,42.34 151.83,42.45 151.92,42.54 152.62,42.54 153.19,43.11 153.19,43.68 152.98,43.89 152.76,43.89 152.69,43.96 152.69,44.53 152.73,44.57 153.51,44.57
N17299308 on BOTTOM (solid shape): 151.67,44.64 152.24,44.64 152.31,44.56 152.31,43.95 152.24,43.87 150.74,43.87 150.68,43.93 150.68,44.82 150.75,44.89 151.41,44.89
N17299365 on BOTTOM (solid shape): 150.52,41.36 150.52,40.76 150.4,40.63 149.51,40.63 149.38,40.76 149.38,41.2 149.71,41.53 150.35,41.53
N17299365 on BOTTOM (solid shape): 151.67,47.49 151.67,46.1 151.35,45.78 150.97,45.78 150.92,45.84 150.86,45.88 150.84,45.91 150.84,46.79 151.16,47.11 151.16,47.49 151.28,47.6 151.56,47.6
N17299365 on IN3 (solid shape): 150.52,41.84 150.52,40.83 150.33,40.63 149.51,40.63 149.38,40.76 149.38,41.84 149.63,42.1 150.27,42.1
N17299365 on IN3 (solid shape): 151.35,46.73 151.35,45.4 150.84,44.89 150.46,44.89 150.02,45.33 150.02,45.52 150.71,46.22 150.71,46.79 150.84,46.92 151.16,46.92
N17299369 on BOTTOM (solid shape): 151.64,50.26 151.64,49.94 151.54,49.84 150.02,49.84 149.89,49.97 149.89,50.29 150.02,50.41 151.49,50.41
N17299369 on BOTTOM (solid shape): 153,43.56 153,43.17 152.59,42.77 151.91,42.77 151.83,42.85 151.83,43.53 151.98,43.68 152.87,43.68
N17299369 on IN3 (solid shape): 151.92,49.84 151.92,49.4 151.67,49.14 151.1,49.14 150.52,49.72 150.02,49.72 149.89,49.84 149.89,50.29 149.95,50.35 151.41,50.35
N17299369 on IN3 (solid shape): 153,44.44 153,43.3 152.87,43.17 151.98,43.17 151.86,43.3 151.86,44.06 151.67,44.25 151.67,44.57 151.86,44.76 152.68,44.76
N17415515 on BOTTOM (solid shape): 203.23,94.17 203.23,88.02 203.04,87.83 200.47,87.83 200.24,88.05 200.24,92.5 200.77,92.5 200.77,93.01 200.24,93.01 200.24,93.3 200.77,93.3 200.77,93.81 200.24,93.81 200.24,94.48 200.56,94.8 202.59,94.8
N17481633 on TOP (solid shape): 173.42,36.34 174.1,36.34 174.35,36.09 174.35,29.45 174.27,29.37 172.24,29.37 172.08,29.54 172.08,33.08 171.81,33.35 167.78,33.35 167.49,33.64 167.49,36.89 167.67,37.07 172.69,37.07
N17481633 on BOTTOM (solid shape): 169.93,38.72 169.93,37.78 170.39,37.33 171.91,37.33 172.22,37.02 172.22,33.75 171.92,33.45 166.37,33.45 166.27,33.55 166.27,36.37 166.71,36.37 166.71,37.07 166.27,37.07 166.27,37.3 166.27,37.3 166.27,37.57 166.71,37.57 166.71,38.27 166.27,38.27 166.27,38.85 166.4,38.98 167.18,38.98 167.19,38.98 169.66,38.98
N28714507 on TOP (solid shape): 192.79,94.72 192.79,91.99 192.46,91.66 191.86,91.66 191.01,92.51 188.37,92.51 188.19,92.69 188.19,94.08 189.45,95.33 192.18,95.33
N28714507 on BOTTOM (solid shape): 191.86,97.28 191.86,95.77 192.22,95.41 192.22,93.94 192.37,93.78 193.32,93.78 193.45,93.66 193.45,91.94 192.94,91.43 192.94,90.48 192.88,90.42 192.37,90.42 192.31,90.48 192.31,90.74 191.91,91.13 189.72,91.13 189.47,91.37 189.47,94.29 189.92,94.74 190.45,94.74 191.29,95.58 191.29,97.28 191.35,97.34 191.8,97.34
N28714606 on TOP (solid shape): 170.24,39.68 170.24,38.99 170.24,37.78 170.12,37.66 169.44,37.66 169.34,37.75 169.34,38.53 169.21,38.66 169.21,39.68 169.27,39.74 170.19,39.74
N28714617 on BOTTOM (solid shape): 188.9,94.55 188.9,92.68 188.9,92.67 188.9,90.18 188.5,89.78 184.28,89.78 184.04,90.03 184.04,92.11 183.53,92.62 183.02,92.62 182.85,92.79 182.85,94.32 182.21,94.32 182.21,92.79 181.55,92.79 181.54,92.81 181.54,94.84 181.87,95.17 184.76,95.17 185.09,95.5 187.95,95.5
N28714693 on TOP (solid shape): 169.56,33.1 169.56,29.15 169.29,28.88 166.53,28.88 166.42,28.99 166.42,29.97 167.95,29.97 167.95,30.6 166.42,30.6 166.42,30.81 166.42,30.81 166.42,33.01 166.63,33.22 169.45,33.22
N28714693 on BOTTOM (solid shape): 176.31,34.43 176.31,32 175.06,30.75 166.58,30.75 166.29,31.03 159.25,31.03 158.22,32.07 158.22,33.47 158.42,33.68 165.84,33.68 166.29,33.23 172.23,33.23 172.7,33.7 172.7,34.35 172.85,34.5 176.24,34.5
N28714693 on IN1 (solid shape): 169.67,32.43 169.67,29.2 169.29,28.82 166.59,28.82 166.36,29.05 166.36,30.72 166.09,30.98 160.39,30.98 160.14,31.24 160.14,33.56 160.47,33.89 168.21,33.89
N28714793 on TOP (solid shape): 156.73,33.66 156.73,32.92 156.57,32.76 156.32,32.76 156.07,32.52 156.07,32.06 156.01,32 155.34,32 155.3,32.04 155.3,34.27 155.35,34.32 156.07,34.32
N33124472 on BOTTOM (solid shape): 79.02,99.63 79.02,97.98 78.9,97.85 77.31,97.85 76.99,98.17 76.99,99.37 77.31,99.69 78.96,99.69
N39282118 on TOP (solid shape): 55.02,8.95 55.02,8.63 54.51,8.63 54.51,7.23 55.02,7.23 55.02,6.85 53.37,6.85 53.05,7.17 53.05,7.7 53.18,7.83 53.19,7.83 53.24,7.88 53.24,8.95 53.37,9.08 54.89,9.08
N39282118 on BOTTOM (solid shape): 54.51,9.08 54.51,6.47 54.19,6.15 53.31,6.15 53.11,6.34 53.11,9.14 53.22,9.24 54.35,9.24
